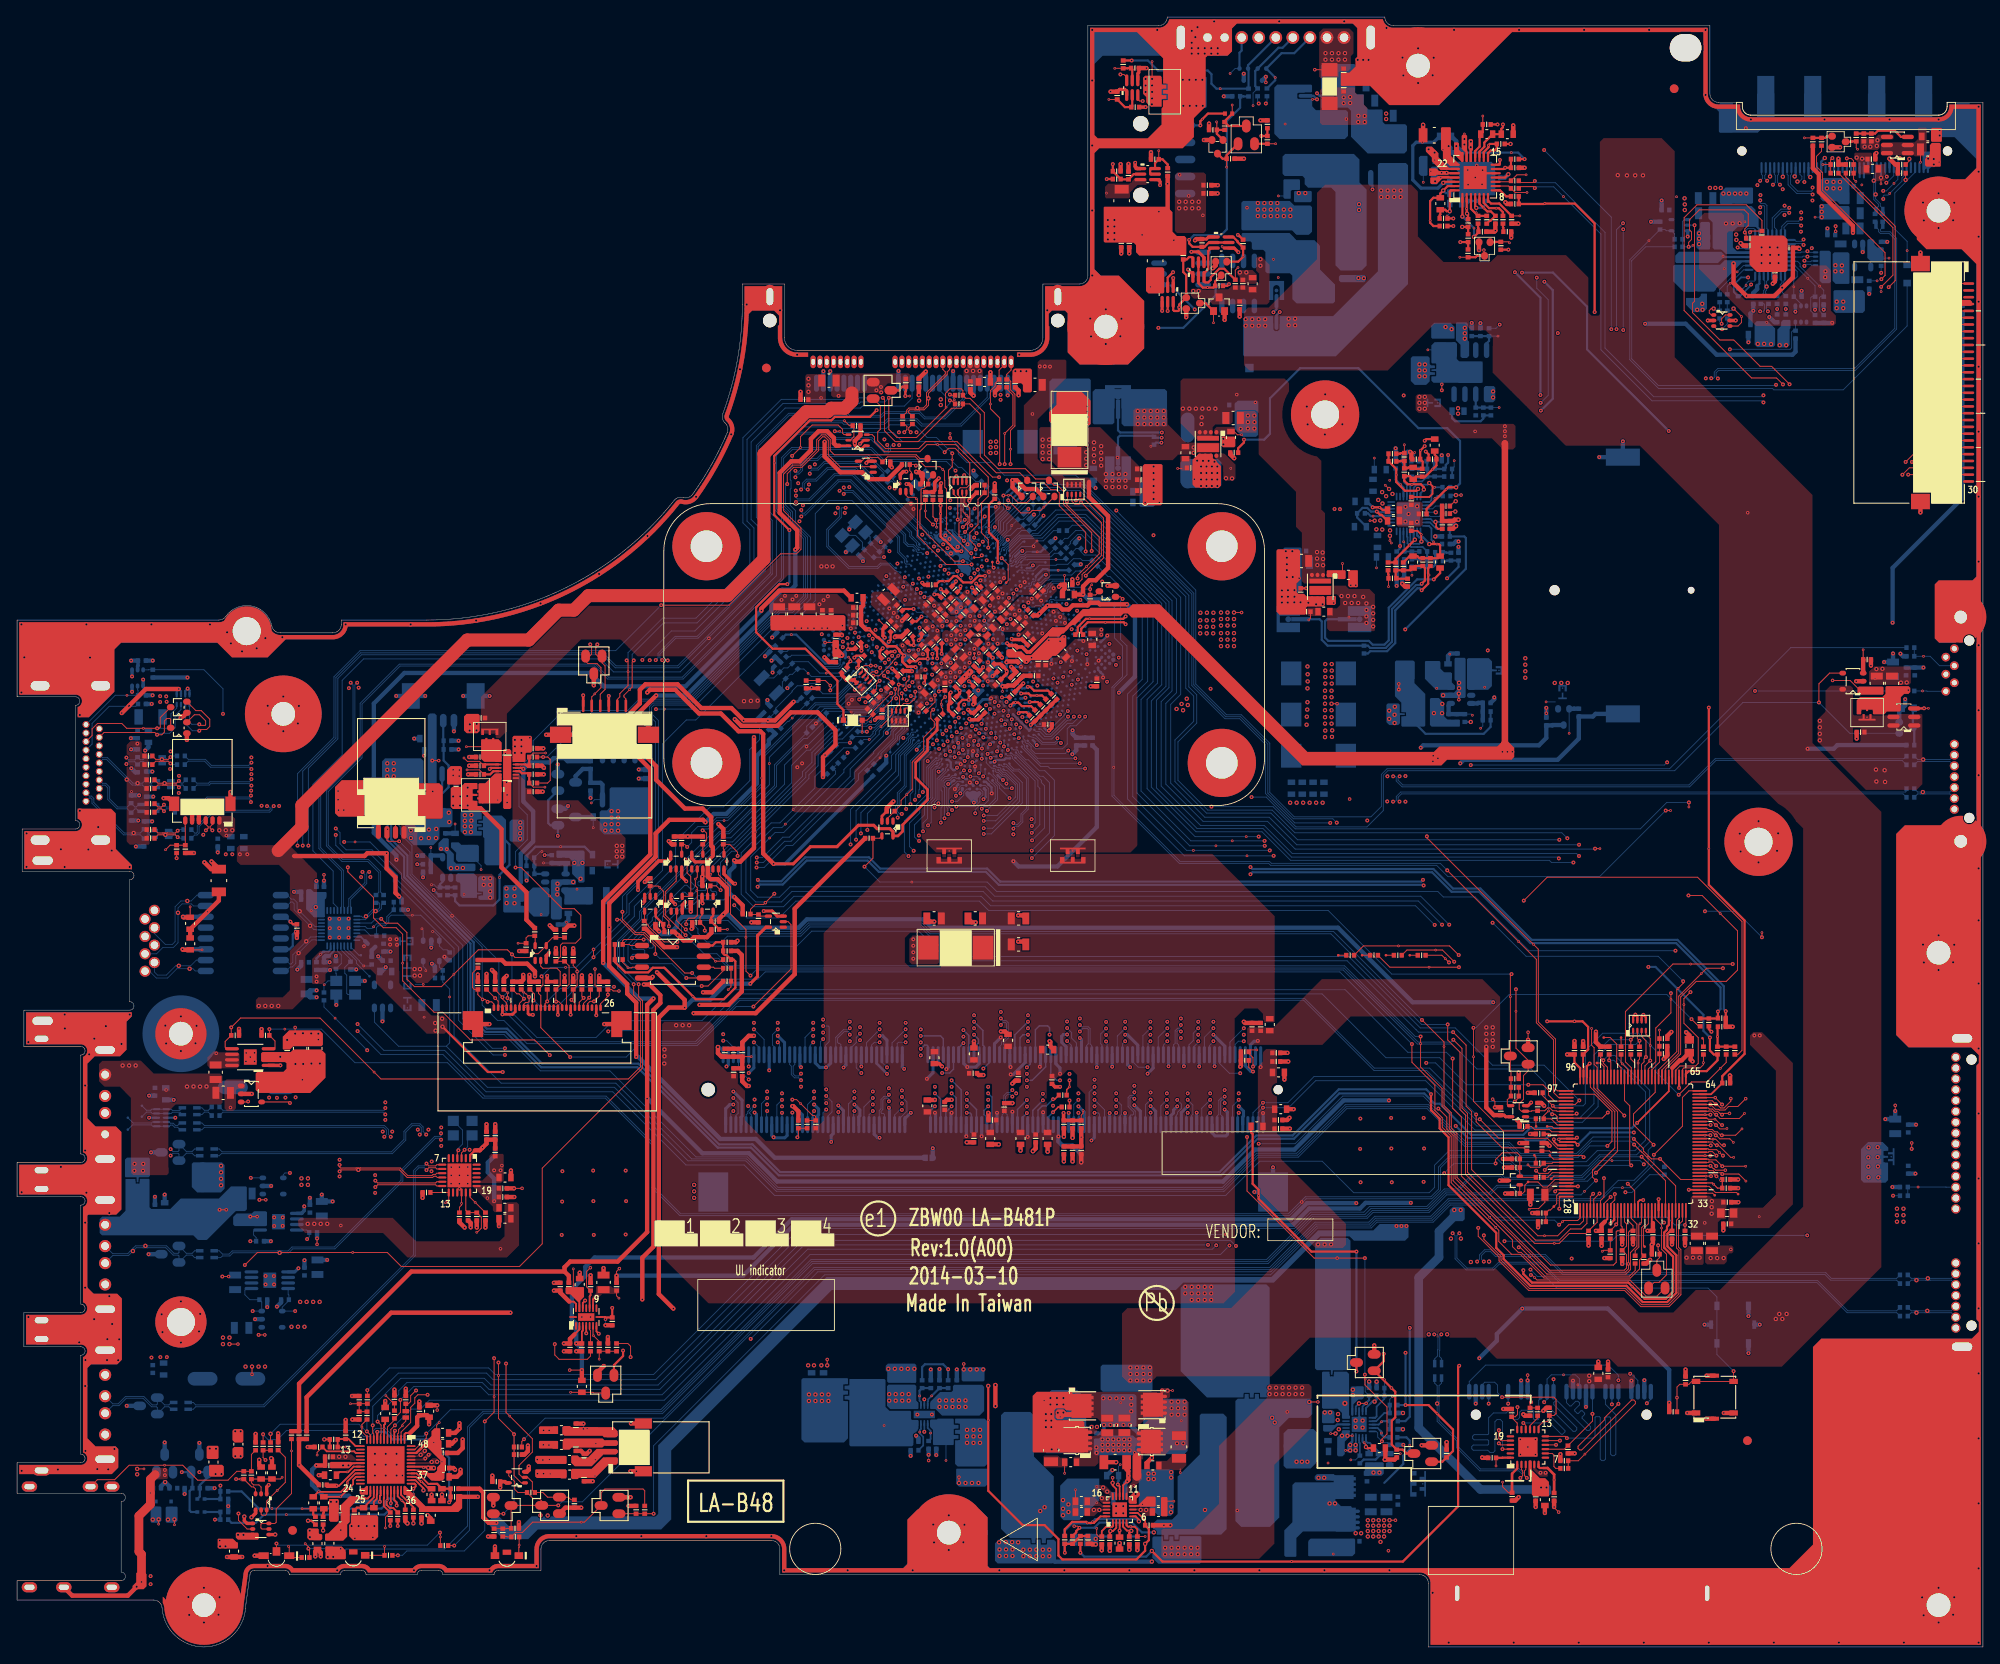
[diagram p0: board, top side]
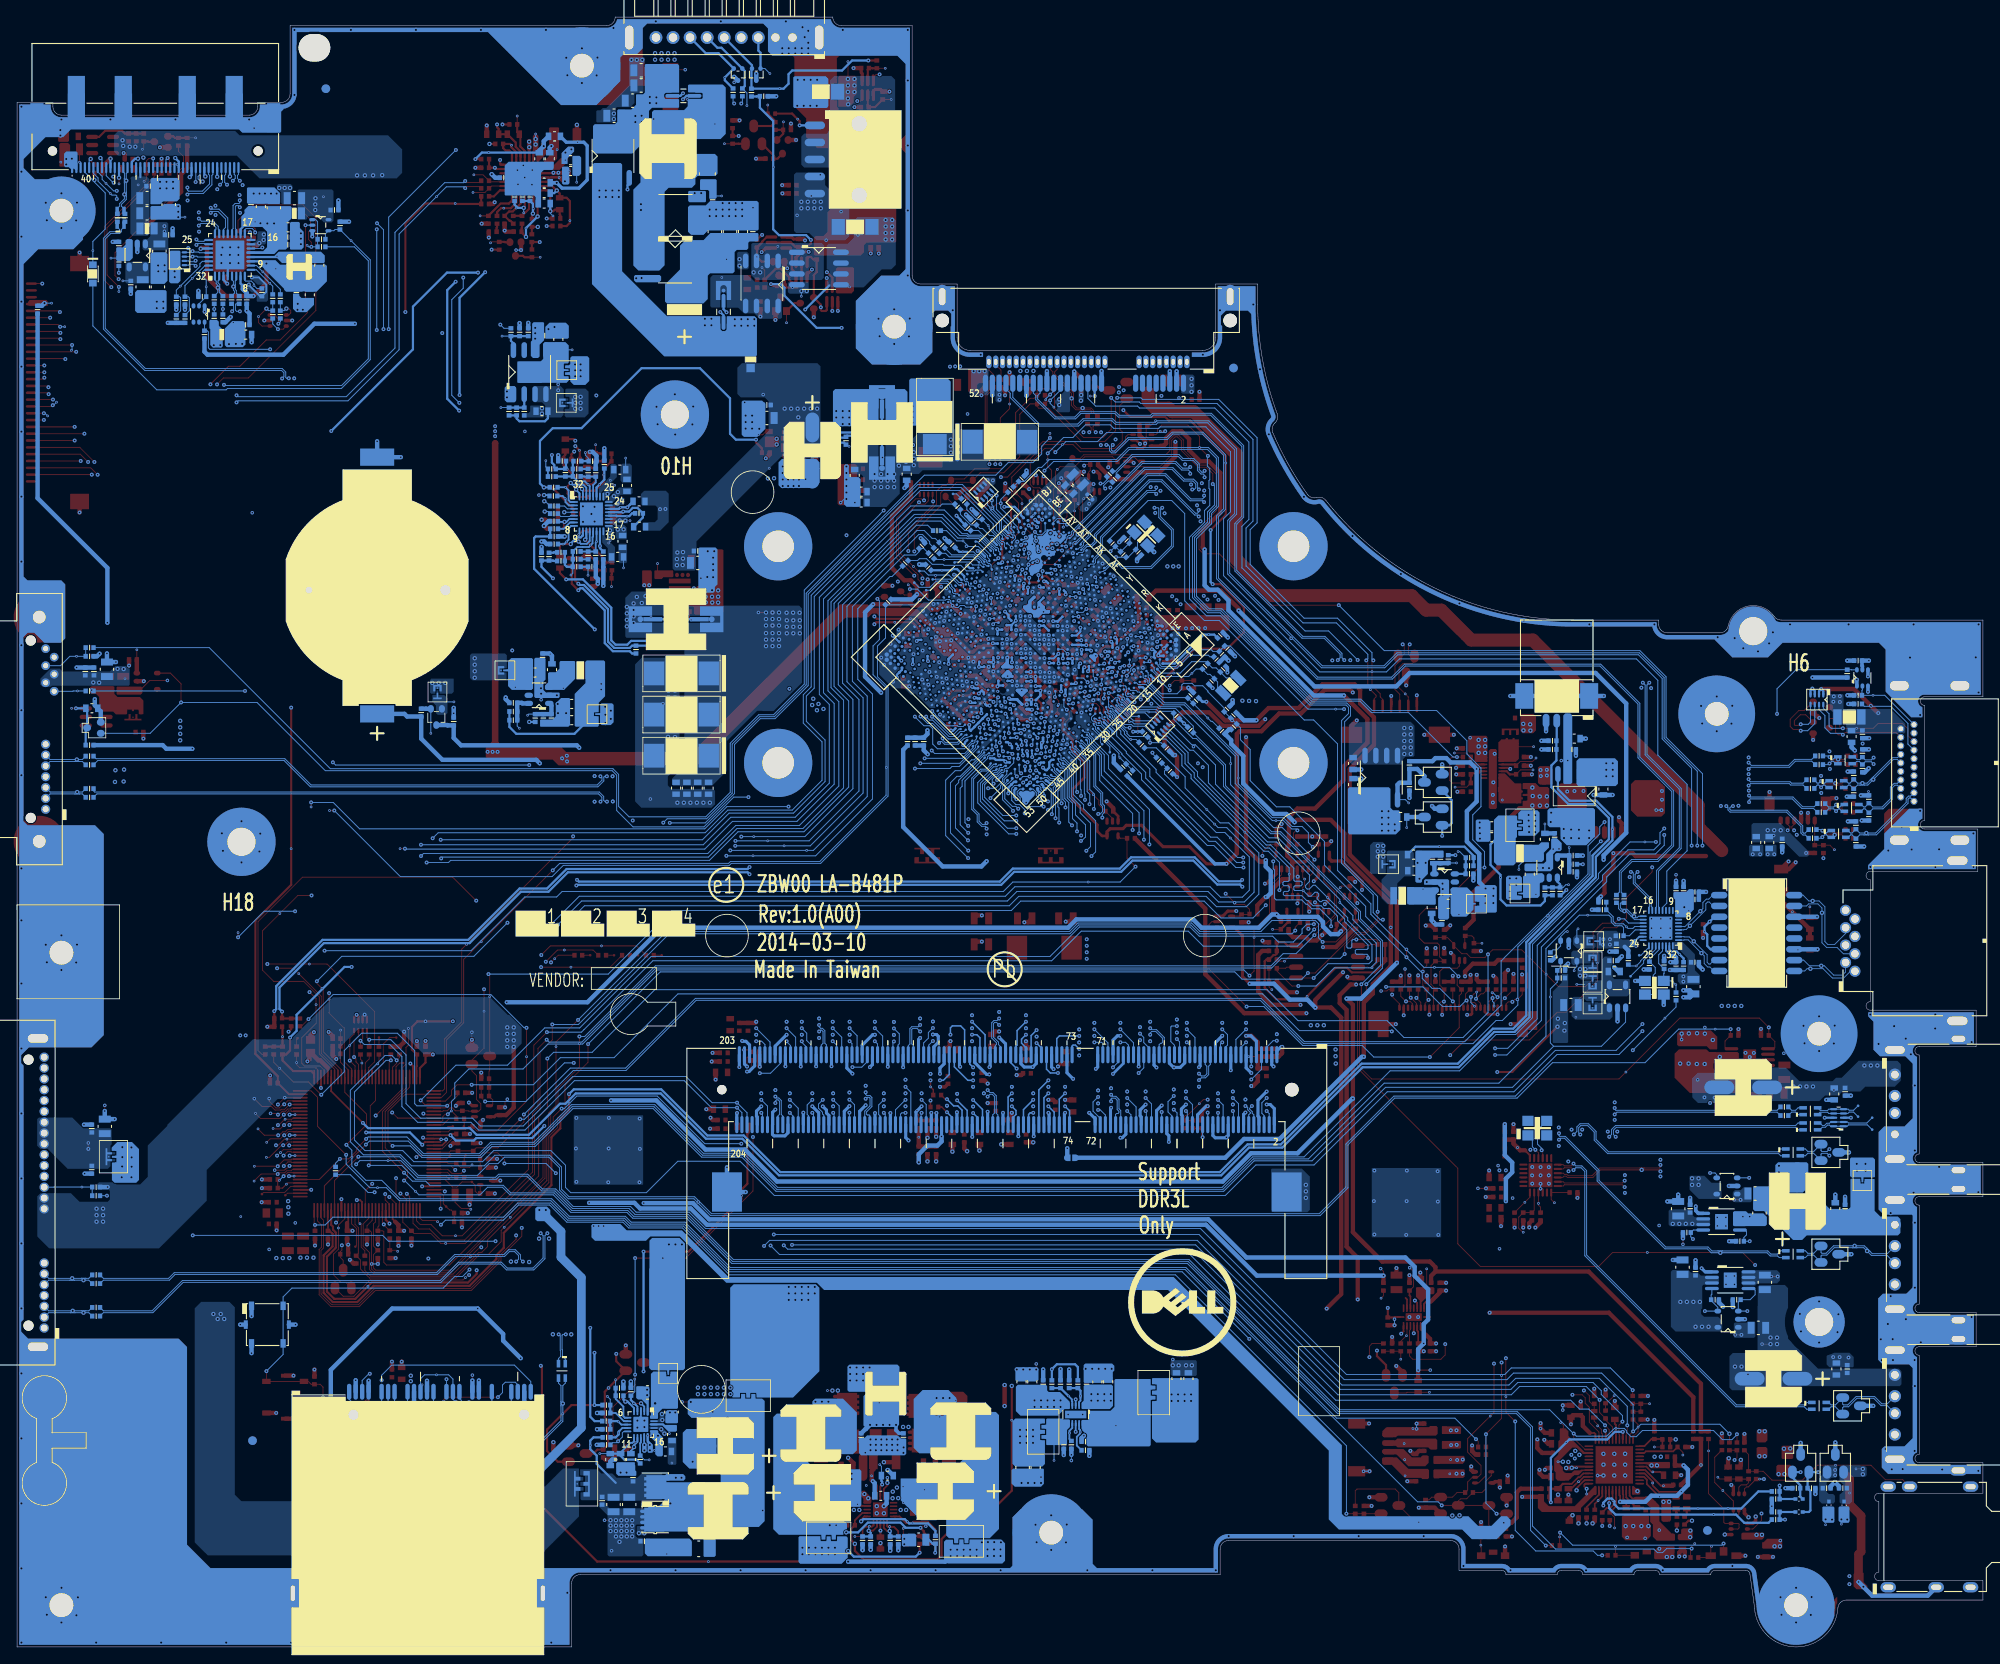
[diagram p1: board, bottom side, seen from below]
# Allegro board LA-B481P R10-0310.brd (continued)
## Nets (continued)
ODD_DA#: RP54.1 RS10.1 USOC1.AY26
ODD_DETECT#: RC68.2 RS09.1 USOC1.AU28
ODD_EN: CS16.1 QS2.3 QS3.1 RS6.1
ODD_EN#: QS3.2 UI7.4 USOC1.BD26
ON/OFFBTN#: CE20.1 JPWR.3 RE49.1 SW1.3 SW1.4 SW2.3 SW2.4 UE1.114
P2: PC700.1 PQ704.1 PQ704.2 PQ704.3 PQ705.1 PQ705.2 PQ705.3 PQ707.3 PR701.1
P3: PC701.2 PQ705.5 PQ705.6 PQ705.7 PQ705.8 PR700.1
PBTN_OUT#: U63.2 UE1.106
PC_BEEP: DA8.1 RA19.1 RA79.2
PCH_HOT#: RE7.1 T207.1(TP-1)
PCH_USB3_RX0_N: LI1.1 USOC1.E3
PCH_USB3_RX0_P: LI1.4 USOC1.D4
PCH_USB3_TX0_N: CI3.2 USOC1.K7
PCH_USB3_TX0_N_C: CI3.1 LI3.1
PCH_USB3_TX0_P: CI4.2 USOC1.K6
PCH_USB3_TX0_P_C: CI4.1 LI3.4
PCH_X1: RG6.2 RG10.1
PCH_X1_R: RG6.1 UG1.5
PCIE_CLKREQ_2#: RP63.3 USOC1.BG5
PCIE_CLKREQ_3#: RP63.4 USOC1.BE3
PCIE_PRX_C_DTX_N0: CL31.2 UL1.18
PCIE_PRX_C_DTX_P0: CL30.2 UL1.17
PCIE_PRX_DTX_N0: CL31.1 USOC1.AT13
PCIE_PRX_DTX_N1: JMINI.23 USOC1.AT9
PCIE_PRX_DTX_P0: CL30.1 USOC1.AT14
PCIE_PRX_DTX_P1: JMINI.25 USOC1.AT10
PCIE_PTX_C_DRX_N0: CC4.2 UL1.14
PCIE_PTX_C_DRX_N1: CC6.2 JMINI.31
PCIE_PTX_C_DRX_P0: CC3.2 UL1.13
PCIE_PTX_C_DRX_P1: CC5.2 JMINI.33
PCIE_PTX_DRX_N0: CC4.1 USOC1.AY6
PCIE_PTX_DRX_N1: CC6.1 USOC1.AV4
PCIE_PTX_DRX_P0: CC3.1 USOC1.AY7
PCIE_PTX_DRX_P1: CC5.1 USOC1.AV6
PCIE_RCOMPN: RC13.2 USOC1.AP13
PCIE_RCOMPP: RC13.1 USOC1.AP14
PCIE_WAKE#: RL34.2 UE1.29 UL1.21
PCU_SMB_ALERT#: RP68.2 USOC1.BG11
PCU_SMB_CLK: QC3.3 RP68.4 USOC1.BH10
PCU_SMB_DATA: QC4.3 RP68.3 USOC1.BG12
PECI_KB9012: RE43.1 UE1.118
PHASE1: PC524.2 PL501.1 PQ503.9 PR532.1 PU500.18
PHASEG: PC515.2 PL500.1 PQ501.9 PR512.1 PU500.24
PLT_RST#: CC11.1 CE36.1 JMINI.22 RC20.2 UC5.4 UE1.13 UL1.19
PMC_ACIN: DC1.2 RC21.2 USOC1.D20
PMC_BATLOW#: RP65.2 USOC1.K26
PMC_CORE_PWROK: CC16.1 CC57.1 CE31.1 JDB1.12 RE18.1 UC7.2 UE1.32 USOC1.B7
PMC_PCIE_WAKE#: RP65.1 USOC1.F26
PMC_PLTRST#: CC13.1 CC51.1 JDB1.17 UC5.2 USOC1.F20
PMC_PWRBTN#: R6.2 U63.4 USOC1.J26
PMC_RSTBTN#: RC24.1 USOC1.BG9
PMC_SLP_S3#: R1024.1 U54.2 USOC1.D22
PMC_SLP_S4#: R1033.1 U57.2 USOC1.F22
PMC_SUSCLK: T103.1(TP-1) USOC1.G24
PS_ID: PR1.2 PR4.1 UE1.16
PSID: PJPDC1.1 PL3.1
PSID-1: PQ2.2 PR2.1 PR5.2
PSID-2: PQ1.2 PQ2.1 PR3.2
PSID-3: PQ1.3 PR1.1
PWR_OTP#: PR114.1 UE1.104
PWR_PWM_LED#: RD14.1 UE1.92
PWR_SRC_ON: CX4.2 QX2.3 RX2.2 RX3.1
RING2: LA10.2 RA1109.1 UA1.17
RING2_R: CA40.1 DA12.2 JHP.6 LA10.1
RREF: RR1.1 UR1.1
RTC_RST#: CC22.1 R1089.2 RC35.2 USOC1.C12
RTC_TEST#: CC20.2 CC64.1 JDB1.13 R1088.2 RC34.2 USOC1.C11
RTC_VOUT: CG6.1 RG2.2 UG1.14
RUNPWROK: T216.1(TP-1) UE1.36
SATA_LED#_SOC: QC2.3 RC18.2 USOC1.AY12
SATA_PRX_DTX_N0: CS109.1 JHDD.5
SATA_PRX_DTX_N0_C: CS109.2 USOC1.AV16
SATA_PRX_DTX_N1: CS14.1 JODD.5
SATA_PRX_DTX_N1_C: CS14.2 USOC1.BA16
SATA_PRX_DTX_P0: CS108.1 JHDD.6
SATA_PRX_DTX_P0_C: CS108.2 USOC1.AU16
SATA_PRX_DTX_P1: CS15.1 JODD.6
SATA_PRX_DTX_P1_C: CS15.2 USOC1.AY16
SATA_PTX_DRX_N0: CS106.1 JHDD.3
SATA_PTX_DRX_N0_C: CS106.2 USOC1.BG7
SATA_PTX_DRX_N1: CS9.1 JODD.3
SATA_PTX_DRX_N1_C: CS9.2 USOC1.BF10
SATA_PTX_DRX_P0: CS105.1 JHDD.2
SATA_PTX_DRX_P0_C: CS105.2 USOC1.BF6
SATA_PTX_DRX_P1: CS8.1 JODD.2
SATA_PTX_DRX_P1_C: CS8.2 USOC1.BD10
SATA_RCOMPN: RC12.1 USOC1.AT18
SATA_RCOMPP: RC12.2 USOC1.AU18
SD3_RCOMP: RC59.1 USOC1.BF26
SD_CD#: CR9.1 JREAD.20 UR1.13
SD_CMD: CR11.1 JREAD.6 UR1.18
SD_D0: JREAD.18 UR1.11
SD_D1: JREAD.19 UR1.10
SD_D2: JREAD.1 UR1.21
SERIRQ: U64.4 UE1.3
SIO_SLP_S0#: T196.1(TP-1) UE1.89
SIO_SLP_S3#: CE27.1 R13.2 U54.4 UE1.6
SIO_SLP_S4#: T194.1(TP-1) UE1.84
SIO_SLP_S5#: CE28.1 R14.2 U57.4 UE1.14
SNB_3V: PC114.1 PR109.2
SNB_5V: PC115.1 PR110.2
SNB_CHG: PC716.1 PR721.2
SOC_I2C0_CLK: T109.1(TP-1) USOC1.BG28
SOC_I2C0_DATA: T108.1(TP-1) USOC1.BH28
SOC_KBRST#: R3.2 U61.4 USOC1.B18
SOC_LID_OUT#: R4.2 U62.4 USOC1.C17
SOC_SATALED#: QC2.1 RD15.1
SOC_SCI#: R8.2 U66.4 USOC1.BA12
SOC_SERIRQ: U64.3 USOC1.BG13
SOC_SMI#: R7.2 U65.4 USOC1.C15
SOC_SPI_CLK: RP67.5 USOC1.C22
SOC_SPI_CS0#: RP67.8 USOC1.C23
SOC_SPI_MISO: RP67.7 USOC1.B22
SOC_SPI_MOSI: RP67.6 USOC1.A21
SOC_SPKR: DA8.3 USOC1.BH12
SPI_CLK: RC39.1 RP67.4 UC8.6
SPI_CS0#: RC36.2 RP67.1 UC8.1
SPI_HOLD#: RC37.2 UC8.7
SPI_MISO: RP67.2 UC8.2
SPI_MOSI: RP67.3 UC8.5
SPI_WP#: RC38.2 UC8.3
SPK_L1-_CONN: CA30.1 JSPK.3 LA5.2
SPK_L2+_CONN: CA29.1 JSPK.4 LA6.2
SPK_R1-_CONN: CA32.1 JSPK.1 LA3.2
SPK_R2+_CONN: CA31.1 JSPK.2 LA4.2
SPOK: PR106.2 PR308.1 PR400.1 PU100.7 UE1.18
SUSP: Q8.1 Q70.2 Q71.2 Q2307.2 Q2308.2 R10.2
SUSP#: PR208.1 PR300.1 PR409.1 Q8.2 R16.1 R926.1 R927.2 R1055.2 R1056.2 UE1.116
SW_1.35VP: PC207.2 PL200.2 PQ201.1 PQ201.2 PQ201.3 PQ203.5 PR202.1 PU200.16
SYSON: CE26.1 PR207.1 UE1.95
TL_BKOFF#: DX1.2 RT15.2 RX33.1 UX2.4
TL_BKOFF#_R: RT14.1 RT15.1 RT19.1 UT2.17 UX2.1
TL_ENVDD: CX20.1 RV300.1 RX6.1 RX7.2 UT2.15
TL_INVT_PWM: JLVDS.36 RX26.1 UT2.14
TMDS_L_TX0N: CX25.1 JHDMI.9 LX3.2
TMDS_L_TX0P: CX26.1 JHDMI.7 LX3.3
TMDS_L_TX1N: CX27.1 JHDMI.6 LX4.2
TMDS_L_TX1P: CX28.1 JHDMI.4 LX4.3
TMDS_L_TX2N: CX29.1 JHDMI.3 LX5.2
TMDS_L_TX2P: CX30.1 JHDMI.1 LX5.3
TMDS_L_TXCN: CX23.1 JHDMI.12 LX2.2
TMDS_L_TXCP: CX24.1 JHDMI.10 LX2.3
TMDS_TX0N: CX14.1 LX3.1 R1073.1
TMDS_TX0P: CX15.1 LX3.4 R1074.1
TMDS_TX1N: CX16.1 LX4.1 R1075.1
TMDS_TX1P: CX17.1 LX4.4 R1076.1
TMDS_TX2N: CX18.1 LX5.1 R1077.1
TMDS_TX2P: CX19.1 LX5.4 R1078.1
TMDS_TXCN: CX12.1 LX2.1 R1071.1
TMDS_TXCP: CX13.1 LX2.4 R1072.1
TON_1.35VP: PR205.2 PU200.9
TOUCH_RST: RX1.1 RX4.2 UE1.38
TOUCH_RST_R: JTOUCH.6 RX1.2 RX24.2
TP2_CORE_VCC_S0IX: T112.1(TP-1) USOC1.AA22
TP_CLK: DE3.3 JTP.2 RE9.2 UE1.87
TP_CORE_V1P05_S4: T195.1(TP-1) USOC1.AF30
TP_DATA: DE3.2 JTP.3 RE10.2 UE1.88
TXE_DBG: QC1.2 UE1.99
UG_3V: PQ101.4 PU100.10
UG_5V: PQ102.4 PU100.16
UGATE1: PR528.1 PU500.17
UGATE1-1: PQ503.1 PR528.2
UGATEG1: PR506.1 PU500.25
UGATEG1-1: PQ501.1 PR506.2
USB3_REXT0: RC40.1 USOC1.M12
USB3RN2_JUSB1_R: DI1.1 DI1.10 LI1.2 T113.1(TP-1)
USB3RP2_JUSB1_R: DI1.2 DI1.9 LI1.3 T114.1(TP-1)
USB3TN2_JUSB1_R: DI1.4 DI1.7 LI3.2 T115.1(TP-1)
USB3TP2_JUSB1_R: DI1.5 DI1.6 LI3.3 T116.1(TP-1)
USB20_CAM_N7_R: JLVDS.28 LX6.2 RX21.2
USB20_CAM_P7_R: JLVDS.27 LX6.3 RX22.2
USB20_CPU_N3: LR2.1 USOC1.H10
USB20_CPU_P3: LR2.4 USOC1.K10
USB20_CR_N3_R: LR2.2 UR1.2
USB20_CR_P3_R: LR2.3 UR1.3
USB20_HUB_N1: JMINI.36 U58.11
USB20_HUB_N2: JTOUCH.2 U58.9
USB20_HUB_N3: LI6.1 U58.7
USB20_HUB_P1: JMINI.38 U58.12
USB20_HUB_P2: JTOUCH.3 U58.10
USB20_HUB_P3: LI6.4 U58.8
USB20_JUSB1_N0_R: DI2.2 JUSB1.2 LI2.2
USB20_JUSB1_P0_R: DI2.3 JUSB1.3 LI2.3
USB20_JUSB2_N1_R: DI9.2 JUSB8.2 LI5.2
USB20_JUSB2_P1_R: DI9.3 JUSB8.3 LI5.3
USB20_JUSB3_N3_R: DI8.2 JUSB7.2 LI6.2
USB20_JUSB3_P3_R: DI8.3 JUSB7.3 LI6.3
USB20_N0: LI2.1 USOC1.K16
USB20_N1: LI5.1 USOC1.G14
USB20_N2: LX6.1 RX21.1 USOC1.J12
USB20_P0: LI2.4 USOC1.M16
USB20_P1: LI5.4 USOC1.J14
USB20_P2: LX6.4 RX22.1 USOC1.K12
USB_EN#: CI13.1 CI26.1 CI29.1 UE1.26 UI1.4 UI2.4 UI3.4 UI4.4 UI5.4 UI6.4
USB_OC0#: CI15.1 CI17.1 RC44.2 UI1.3 UI2.5 UI3.5 UI4.3 USOC1.C20
USB_OC1#: CI28.1 RC46.2 UI5.3 UI6.5 USOC1.B20
USB_PLL_MON: RC47.2 USOC1.M13
USB_RCOMP: RC45.2 USOC1.C7 USOC1.D6
VCIN0_PH: PR13.2 R696.1 UE1.109
VCIN1_PROCHOT: PR15.2 R697.1 UE1.102
VCORE_GSNS: PC503.2 PC535.2 PU500.12 PU500.30 RC58.1 USOC1.N28
VCORE_VSNS: PC527.1 PC533.2 PR542.1 RC56.2 USOC1.P28
VCOUT1_PH: PR17.1 PR18.2 Q50.2 RE47.2 UE1.103 UE2.2
VFB: PR726.1 PU700.15 PU700.16
VGA_V1P35_S3_F1: CC35.1 CC36.1 L1.1 USOC1.BD1
VGATE: PR530.1 PU500.15 UE1.97
VGFX_VSNS: PC502.1 PR501.2 PR504.2 RC55.2 USOC1.BB8
VL: PC117.1 PU100.13
VR_HOT#: PC520.1 PR525.1 PU500.6 RE13.1 RE44.1
VR_ON: CE34.1 DE1.3 PR516.1 RE1.2 RE12.2
VR_ON_EC: RE12.1 UE1.121
VR_ON_R: PR516.2 PU500.2
VR_SVID_ALERT#: PU500.4 RC27.2 RC28.2
VR_SVID_ALERT#_SOC: RC28.1 USOC1.B24
VR_SVID_CLK: PR520.1 PR527.1 USOC1.C25
VR_SVID_CLK_R: PR520.2 PU500.3
VR_SVID_DATA: PR521.1 PR526.1 RC29.2
VR_SVID_DATA_R: PR521.2 PU500.5
VR_SVID_DATA_SOC: RC29.1 USOC1.A25
VSUM+: PC529.1 PC530.1 PR535.1 PR536.2 PR541.1 PU500.10
VSUM-: PC529.2 PC530.2 PC532.2 PC534.1 PH503.2 PL501.3 PR540.2 PR541.2
VSUMG+: PC513.2 PC514.2 PR500.2 PR509.2 PR513.2 PU500.32
VSUMG-: PC512.1 PC513.1 PC514.1 PH500.1 PL500.3 PR502.2 PR507.1 PR509.1
VTTREF_1.35VP: PC212.1 PU200.4
WL_BT_LED: QD20.2 RD50.1 RD53.1 UE1.1
WL_BT_LED#: QD20.1 RD18.1 RD51.2 RD53.2
WL_BT_LED#_EC: QD18.1 QD19.1 RD46.2 RD49.2 RD51.1 RD52.1 UD1.4 UE1.64
WL_BT_LED#_EC2: RD48.2 UE1.74
WL_LED#: JMINI.44 QD18.3 RD45.2 RD48.1 UD1.1
WL_OFF#: QM30.3 RE14.1 RP54.3 USOC1.BA26
WL_OFF#_EC: RE14.2 UE1.19
WLAN_CLKREQ#: JMINI.7 RP63.2 USOC1.BD7
WLAN_RADIO_DIS#_R: JMINI.20 QM30.1 RM110.2
WOL_EN: RL27.2 RL38.1 UE1.98 UL2.3 UL3.4
XDP_H_PRDY#: CC52.1 JDB1.2 RC65.2 USOC1.D18
XDP_H_PREQ_BUF#: CC50.1 JDB1.1 RC25.2 RC61.2 USOC1.F16
XDP_H_TCK: CC65.1 JDB1.26 RP66.7 USOC1.D14
XDP_H_TDI: CC61.1 JDB1.22 RP66.5 USOC1.F12
XDP_H_TDO: CC56.1 JDB1.20 RC63.2 RC64.2 USOC1.G16
XDP_H_TMS: CC63.1 JDB1.23 RP66.6 USOC1.F14
XDP_H_TRST#: CC59.1 JDB1.21 RP66.8 USOC1.G12
XDP_OBSDATA_A0: CC55.1 JDB1.4 USOC1.N24
XDP_OBSDATA_A1: CC58.1 JDB1.5 USOC1.M20
XDP_OBSDATA_A2: CC60.1 JDB1.7 USOC1.J18
XDP_OBSDATA_A3: CC62.1 JDB1.8 USOC1.M18
XDP_RSTBTN#: CC12.1 CC49.1 CC53.1 JDB1.18 RC24.2 RC62.2
XTAL_25M_IN: CC9.1 RC19.1 RG10.2 USOC1.AH12 YC1.1
XTAL_25M_OUT: CC10.1 RC19.2 USOC1.AH10 YC1.3
XTLI: CL36.2 RG11.2 UL1.29 YL2.1
XTLI_L: RG8.2 RG11.1
XTLI_R: CG7.1 RG5.2 RG8.1
XTLO: CL37.2 UL1.28 YL2.3
N17188574: PC400.2 PJP400.2 PU400.4
N17188613: PC405.1 PR401.2
N17227658: PC412.1 PJP404.2 PU402.5 PU402.9
N17227663: PC413.2 PR410.2 PR412.1 PU402.2
N17227696: PC415.1 PR409.2 PR411.1 PU402.8
N17253612: PC116.1 PR111.2 PU100.12
N17256470: PC210.2 PR209.2 PU200.12
N17256593: PC211.1 PR202.2
N17322320: PC7.1 PH1.1 PR10.2 PR13.1
N17322329: PR11.2 PR15.1 PR18.1 PR20.1
N17322935: PQ3.3 PR12.2
N17322941: PQ3.5 PQ3.6 PR14.1 PR19.2
N17330968: RC52.1 T211.1(TP-1)
N17344663: PJP1.1 PJPDC1.2 PJPDC1.3 PL2.1
N17354752: PL501.2 PR536.1
N17354919: PC517.2 PR518.1 PU500.22
N17371703: PR717.2 PU700.10
N17371738: PR719.2 PU700.9
N17407779: CE12.1 R2354.1
N17434553: RE36.1 T218.1(TP-1)
N17434554: RE36.2 UE1.107
N17434556: RE37.1 T212.1(TP-1)
N17434577: RE7.2 UE1.66
N17438484: CA21.1 R2355.2
N17494823: CA1.1 CA2.1 QA5.2 RA3.2
N18943829: PR720.2 PR724.1
N18944147: PC722.2 PC726.1 PR720.3 PU700.17
N18956218: PC722.1 PR724.2 PU700.18
N18967347: PC727.1 PR723.2
N18967375: PC721.1 PU700.4
N18967379: PR723.1 PU700.6
N18967435: PC723.1 PU700.7
N18967441: PR725.1 PR728.2 PU700.5
N18999155: PC706.1 PC709.1 PR704.2 PU700.28
N19000258: PC707.1 PC709.2 PR705.2 PU700.27
N19021042: PC710.1 PR709.2 PU700.26
N19095003: PR722.2 PU700.8
N19142937: PC700.2 PC701.1 PQ704.4 PQ705.4 PQ707.1 PR701.2 PR703.1
N19565438: PQ707.2 PQ708.1
N19565442: PQ709.3 PQ710.3 PR703.2
N19565444: PQ709.2 PQ709.5 PQ712.1 PR712.2
N19565472: PQ711.1 PR708.1
N19636367: QA6.2 RA6.2 RA7.2
N19792312: QA5.5 QA5.6 RA2.2
N19794620: QA6.5 QA6.6 RA5.2
N22321388: RE37.2 UE1.82
N22702729: LED2.1 RD15.2
N22702890: LED1.2 RD14.2
N22702897: LED1.3 RD17.2
N22795339: LED4.1 RD18.2
N23316235: JP3.1 RL28.1 UL2.1
N23954212: R15.2 R17.2 UC5.5
N23955686: T105.1(TP-1) USOC1.C21
N23993932: CC24.2 RC39.2
N24086884: C1123.2 U59.12
N24086900: C1127.2 U59.10
N24234938: CS17.1 JODD.11 RS10.2
N24235708: JODD.8 RS09.2
N24237390: R1048.1 U58.13
N24262528: C976.2 U11.12
N24262552: C967.2 U11.10
N24334655: PC300.2 PJP300.2 PU300.4
N24334673: PC305.1 PR301.2
N24509824: RL40.2 UL3.3
N24530695: RS9.1 UI7.3
N24559749: PC307.2 PJP302.2 PU301.4
N24559796: PC306.1 PR306.2
N24608852: CA62.2 RA154.2 UA1.27
N24608977: RA34.1 RA51.1 RA155.1 UA1.13
N24654163: PC112.2 PR107.1
N24654248: PC113.1 PR108.2
N24947886: RX5.2 UT2.8
N25096547: RE17.2 T199.1(TP-1)
N25096555: RE19.2 T200.1(TP-1)
N25096563: RE20.2 T201.1(TP-1)
N25096571: RE21.2 T202.1(TP-1)
N25415357: R5.1 U64.5
N25420647: R18.2 R19.2 U54.5
N25421095: R20.2 R21.2 U57.5
N29841026: PQ713.3 PR730.2
N39970373: PQ710.6 PQ712.2 PR718.2
N40812716: CR3.2 UR1.6
N47007898: PC11.2 PQ4.5 PR26.1
N47008110: PC9.1 PQ4.2 PR17.2
N47008134: PL3.2 PQ1.1 PR2.2
N48037563: JDIMM1.197 RD6.2
N48037565: JDIMM1.201 RD7.2
N48039107: CD21.1 CD22.1 JDIMM1.126 RD4.1
N52907207: PQ706.4 PR706.1 PR708.2
N52907447: PQ711.2 PR714.1
N55155843: QX1.1 RX3.2
N55201771: JHDMI.13 RX12.2
N56393123: RL31.2 UL1.31
N56393790: T94.1(TP-1) UL1.27
N56393809: T95.1(TP-1) UL1.25
N56394014: CL33.1 RL19.2 RL20.2
N56394031: CL41.2 TL1.3 TL1.6
N59110906: RE43.2 T203.1(TP-1)
N61580896: Q2307.1 R2314.2
N61580898: Q2308.1 R2315.2
N63469417: CA65.2 CA69.1 RA79.1 RA81.2
N63469524: CA68.2 RA82.1
N63469526: CA67.2 RA80.1
N63469613: CA65.1 UA1.12
N63469687: CA23.2 UA1.28
N63469697: RA153.2 UA1.15
N63469703: CA24.1 UA1.37
N63469709: CA24.2 UA1.35
N63469711: CA25.2 UA1.34
N63469723: CA63.2 UA1.39
N63469729: CA64.2 UA1.7
N63469750: RA130.2 UA1.8
N100764683: PC506.1 PR502.1
N100764685: PC506.2 PR507.2 PU500.31
N100764689: PC532.1 PR539.2
N100764691: PR539.1 PR540.1 PU500.11
N100764720: PC518.1 PR519.2 PR522.2 PU500.21
N100764741: PC504.1 PR503.1 PR508.1 PU500.28
N100764791: PC504.2 PC505.1 PC507.2 PR504.1 PR505.1 PU500.29
N100764795: PC528.2 PC531.2 PR534.2 PU500.14
N100764809: PC528.1 PR533.2 PR538.2 PR542.2 PR543.1 PU500.13
N100764813: PC507.1 PR503.2
N100764860: PR510.2 PU500.27
N100764905: PC531.1 PR543.2
N100764954: PC527.2 PR538.1
N100764996: PH500.2 PR500.1
N100765028: PC525.2 PR533.1
N100765040: PC505.2 PR501.1
N100765116: PH503.1 PR535.2
N100765769: PC511.1 PR505.2
N100765781: PR522.1 PU500.20
N100768097: PC526.1 PR532.2
N100768278: PC516.1 PR512.2
N100768460: PC524.1 PR531.2
N100768507: PC515.1 PR511.2
N100768540: PL500.2 PR513.1
N102723193: T102.1(TP-1) USOC1.BG18
N102723222: T101.1(TP-1) USOC1.BH18
N102723231: T100.1(TP-1) USOC1.BG21
N251601461: PR524.2 PU500.8

Pads without a net: FD1 1; FD2 1; FD3 1; FD4 1; FD5 1; FD6 1; FD7 1; FD8 1; JDB1 11 14 15 24; JDIMM1 77 122 125 198; JHDD 18 20 21 22; JHDMI 14; JKB 2 3 30; JLAN 4 5 7 8; JLVDS 13 14 16 17 19 20 22 23 38; JMINI 1 3 5 8 10 12 14 16 17 19 37 42 45 47; LED2 3; LED4 3; PU100 19; PU300 5; PU301 5; PU400 5; PU402 7; PU500 9; Q2309 3 4 5; RP54 4; RP68 1 8; TL1 4 5 12 13; U54 1; U57 1; U58 2 5 6 14 15 21 22 23 24; U61 1; U62 1; U63 1; U65 1; U66 1; UA1 14 16 23 24 48; UC4 1; UC5 1; UC7 1; UC10 1; UE1 85 86 90; UE2 1; UG1 9 12; UL1 3 6 7 9 10 11 22 24; UR1 7 14 17 19 23; USOC1 A13 A17 AB2 AB3 AB7 AB9 AB12 AB13 AB14 AC1 AC3 AD2 AD3 AD4 AD6 AD9 AD10 AD12 AD40 AD41 AF2 AF3 AF13 AF14 AF40 AF41 AF48 AF50 AF51 AF52 AG51 AG53 AH13 AH14 AH40 AH44 AH52 AJ51 AK4 AK6 AK7 AK9 AK40 AK42 AK45 AK47 AK48 AK50 AK51 AK52 AL1 AL3 AL51 AL53 AM4 AM6 AM9 AM10 AM13 AM14 AM41 AM42 AM45 AM47 AM48 AM50 AM52 AP4 AP6 AP7 AP9 AP10 AP12 AP41 AP42 AP44 AP45 AP47 AP48 AP50 AP51 AP52 AR51 AR53 AT6 AT7 AT20 AT22 AT26 AT32 AT34 AT36 AT40 AT41 AT42 AT44 AT45 AT48 AT50 AT51 AU20 AU22 AU26 AU32 AU34 AU36 AU53 AV9 AV10 AV20 AV22 AV26 AV28 AV32 AV34 AV36 AV40 AV44 AV45 AV48 AV50 AV52 AW1 AW41 AW51 AW53 AY2 AY3 AY20 AY24 AY28 AY30 AY34 AY38 AY40 AY42 AY44 AY45 AY47 AY48 AY51 AY52 B4 B5 B12 B14 B16 B26 B28 BA1 BA3 BA18 BA20 BA24 BA28 BA34 BA36 BA38 BA42 BA51 BB3 BB4 BB44 BB47 BB49 BB50 BB51 BC14 BC18 BC24 BC36 BC38 BC40 BC44 BC52 BC53 BD2 BD5 BD12 BD16 BD18 BD20 BD22 BD28 BD32 BD34 BD36 BD38 BD40 BD42 BD44 BD47 BE46 BE51 BE52 BF2 BF14 BF22 BF27 BF28 BF32 BF34 BF40 BF42 BF48 BF50 BF52 BG23 BG24 BG25 BG26 BG27 BG29 BG32 BG33 BG35 BG36 BG37 BG38 BG40 BG41 BG43 BG47 BH4 BH5 BH6 BH7 BH8 BH22 BH24 BH26 BH32 BH34 BH36 BH38 BH40 BH42 BH44 BH46 BH47 BH48 BH49 BH50 BJ9 BJ25 BJ29 BJ33 BJ37 BJ41 BJ45 C13 C16 C18 C19 C27 C30 D2 D26 D28 D32 D34 D48 E2 E46 F1 F18 F28 F32 F34 G2 G18 G30 H3 H4 H5 H7 H8 J3 J28 J30 J34 K2 K3 K18 K20 K24 K28 K34 L1 L3 M2 M3 M4 M6 M7 M9 M10 M22 M24 M32 N3 N30 N32 N34 P2 P3 P6 P7 P10 P12 P14 P34 R1 R3 T2 T3 T4 T6 T7 T9 T10 T12 T13 T14 V2 V3 V4 V6 V9 V10 V13 V14 W1 W3 Y2 Y3 Y4 Y6 Y12 Y13; Y9 2 4

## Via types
v1: diameter 0.305, hole 0.152, TOP to BOTTOM, 462 vias
v2: diameter 0.457, hole 0.203, TOP to BOTTOM, 2160 vias
v3: diameter 0.406, hole 0.203, TOP to BOTTOM, 127 vias
v4: diameter 0.508, hole 0.254, TOP to BOTTOM, 1386 vias
v5: diameter 0.61, hole 0.305, TOP to BOTTOM, 1 via

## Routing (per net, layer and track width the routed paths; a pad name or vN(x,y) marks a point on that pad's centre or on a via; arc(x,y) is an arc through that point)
1.0VS_GATE: length 9.2
  BOTTOM w0.102: v1(67.3,98.96) 67.69,99.35 U60.4
  BOTTOM w0.508: Q70.1 65.46,102.11 66.3,102.94 R1061.1 C1131.1 68.38,101.32 68.61,101.09 U60.4
1.8VS_ON: length 4.8
  TOP w0.102: R1055.1 60.51,100.81 v1(61.87,100.81)
  TOP w0.254: R1055.1 C1125.2 59.9,102.44 59.16,102.44 58.92,102.67 U59.3
1.35VS_ON: length 4.8
  TOP w0.102: v1(61.94,104.81) 60.49,104.81 R1056.1
  TOP w0.254: R1056.1 C1128.2 59.74,103.33 59.59,103.47 U59.5
3VS_ON: length 3.3
  BOTTOM w0.203: 105.77,29.21 105.77,28.88 105.93,28.72 U11.3
  BOTTOM w0.254: 105.77,29.21 v1(105.77,29.44) 105.77,30.05 R927.1 C980.1
5VS_ON: length 3.7
  BOTTOM w0.203: v1(107.19,29.44) 106.79,29.03 106.79,28.83 106.73,28.77 U11.5
  BOTTOM w0.254: R926.2 C979.2 v1(107.19,29.44)
+0.675VS: length 2.8
  BOTTOM w0.356: v2(146.02,62.6) 146.05,62.57 JDIMM1.204 ; v2(145.75,67.99) JDIMM1.203
  vias: v3(150.56,52.17) v4(152.48,47.19) v4(153.24,47.19) v4(154,47.19)
+0.675VSP: length 3.6
  TOP w0.102: v4(157.27,28.56) v3(158.11,28.56)
  IN2 w0.254: v5(155.62,28.56) v4(157.27,28.56)
  BOTTOM w0.203: PU200.2 156.89,28.18 v4(157.27,28.56)
+1.0VALW: length 11
  TOP w0.102: C1034.2 v3(94.7,117.76)
  TOP w0.254: C1039.2 104.97,118.09 105.09,117.98 v2(105.09,117.46) 104.71,117.46 C1074.1 ; C1036.2 106.65,116.66 106.73,116.58 v2(106.73,115.86) 105.68,115.86 105.4,115.57 C1037.2
  BOTTOM w0.254: USOC1.C5 96.64,116.43 v2(96.64,116.26) 96.59,116.21 USOC1.B6 ; USOC1.Y19 105.67,117.5 USOC1.V18 105.63,117.46 v2(105.09,117.46) ; USOC1.V22 106.74,115.87 v2(106.73,115.86) 106.71,115.84 USOC1.U22 ; USOC1.C3 95.84,117.23 95.84,117.2 v2(95.98,117.06)
  vias: v4(52.48,97.52) v4(52.48,96.86) v4(52.48,96.22) v4(52.48,95.54) v4(53.24,97.55) v4(53.24,96.88) v4(53.19,96.2) v4(53.19,95.54) v4(67.06,107.74) v4(67.06,106.98) v4(67.06,106.22) v4(67.06,105.46) v4(67.06,104.7) v4(67.82,107.74) v4(67.82,106.98) v4(67.82,106.22) v4(67.82,105.46) v4(67.82,104.7)
+1.0VALWP: length 15.4
  BOTTOM w0.254: PC308.1 57.71,94.09 57.71,91.69 56.54,90.52 v1(56.54,90.22) 56.54,87.65 55.83,86.94 51.84,86.94 51.34,87.45 PC310.1 PR307.1
+1.0VALWP_ON: length 4.3
  BOTTOM w0.102: v1(48.49,93.72) PC309.1
  BOTTOM w0.508: PR305.1 PR308.2 PC309.1 49.68,92.78 PU301.1
+1.0VS: length 131.6
  TOP w0.254: C1062.2 107.83,116.95 107.83,115.93 107.82,115.91 107.82,115.9 v2(107.83,115.9) ; v2(102.87,116.71) 102.37,116.71 102.26,116.6 C1060.2
  TOP w0.305: v2(105.67,118.03) 106,118.37 C1044.2
  TOP w0.356: C1061.2 114.36,113.83 v2(114.32,113.83)
  TOP w0.508: v2(94.45,101.99) 94.45,104.33 v2(94.69,104.57) 95.91,105.79 95.91,107.49 93.83,109.57 90.68,109.57 89.11,108 84.89,108 v2(84.12,108.77) ; v2(115.97,115.46) 116.06,115.55 117.21,115.55 117.29,115.46 ; PR527.2 PR526.2 167.01,132.03 PR525.2 PC523.1 168.32,132.01 168.47,132.17 v4(168.92,132.17)
  IN1 w0.508: v4(168.92,132.17) 168.37,132.17 167.41,131.21 167.41,129.51 164.04,126.13 162.11,126.13 160.43,124.46 160.43,112.19 159.97,111.73 156.92,111.73 155.96,110.77 155.96,106.58 154.28,104.9 147.32,104.9 v2(139.88,112.34)
  IN2 w0.508: v2(139.88,112.34) 132.64,119.58 132.64,121.61 126.97,127.29 125.34,127.29 124.84,127.79 118.75,127.79 117.3,126.34 117.3,125.45 117.17,125.32
  BOTTOM w0.254: v2(115.97,115.46) 115.97,115.81 115.99,115.83 USOC1.AK35 ; v2(115.97,115.46) 116.26,115.46 116.27,115.48 USOC1.AK36 ; v2(115.97,115.46) 115.97,114.93 USOC1.AJ36 ; v2(114.61,121.39) 114.2,120.98 114.2,120.66 USOC1.AN25 ; 115.49,119.32 v2(115.51,119.34) ; 115.49,119.32 USOC1.AN30 ; 115.49,119.32 115.44,119.27 USOC1.AN29 ; USOC1.G1 96.23,119.74 v2(96.73,119.74) ; v2(104.53,116.81) 104.64,116.92 USOC1.U18 ; USOC1.Y22 107.82,115.9 v2(107.83,115.9) ; v2(108.97,120.28) 108.95,120.25 USOC1.AF18 USOC1.AF16 ; USOC1.Y24 108.35,115.34 v2(108.33,115.32) ; USOC1.M14 102.37,116.71 v2(102.87,116.71) ; USOC1.AF21 USOC1.AG21 v2(110.59,119.73) ; USOC1.U19 v2(105.64,116.91) ; USOC1.BJ6 112.75,132.7 112.75,132.94 113.49,133.67 v2(114.7,133.67) ; v2(105.67,118.03) USOC1.Y18 ; v2(107.27,115.32) 107.28,115.33 USOC1.V24 ; USOC1.AM18 USOC1.AM16 ; USOC1.V32 v2(111.03,112.65)
  BOTTOM w0.305: RC27.1 94.83,102.37 v2(94.45,101.99)
  BOTTOM w0.508: RC15.2 94.87,104.57 v2(94.69,104.57)
  vias: v2(91.16,119.45) v2(91.93,119.45) v2(92.69,119.45) v2(93.4,119.43) v2(94.34,119.45) v2(94.97,119.45) v2(110.1,121.36) v2(110.63,121.9) v2(112.65,112.16) v2(114.02,122.1) v2(115.01,123.04) v2(115.5,123.52) v2(117.61,124.41) v2(118.09,124.85) v3(119.13,129.06) v4(68.94,96.44) v4(68.94,95.73) v4(69.68,97.99) v4(69.68,97.23) v4(69.68,96.47) v4(69.68,95.71) v4(70.44,97.99) v4(70.44,97.23) v4(70.44,96.47) v4(70.44,95.71)
+1.0VS_R: length 3.3
  BOTTOM w0.102: v1(67.53,96.06) R1052.1
  BOTTOM w0.508: R1052.1 Q71.1
+1.05V_PGOOD: length 1.9
  TOP w0.102: T210.1 180.11,55.2 UE1.122
+1.5VS: length 114.4
  TOP w0.406: 121.42,119.35 118.72,116.66 118.37,116.66 117.79,117.24 C1058.1 117.01,117.42 116.29,117.42 v2(116.04,117.68)
  TOP w0.508: v2(56.16,14.55) 55.27,14.55 54.64,15.19 54.64,18.11 54.19,18.55 RA8.1
  TOP w0.762: 174.36,141.12 174.37,141.11 174.37,105.95 174.27,105.85
  IN1 w0.508: v4(108.26,145.62) 107.19,145.62 105.79,144.22 92.64,144.22 90.73,146.13 90.73,148.94 91.24,149.45 93.67,149.45 94.21,148.9 94.82,148.9 95.3,149.38 v2(95.3,149.58)
  IN2 w0.762: 174.63,105.94 174.37,106.2 174.37,141.15
  BOTTOM w0.254: USOC1.AM32 116.01,117.64 v2(116.04,117.68)
  BOTTOM w0.508: JMINI.6 v2(95.3,149.58)
  vias: v2(115.27,146.81) v2(115.27,146.23) v2(161.66,49.35) v2(162.25,49.35) v2(162.83,49.35) v2(165.94,103.83) v2(165.97,104.49) v2(166.53,104.19) v2(174.08,104.95) v2(174.37,143.13) v2(174.37,142.54) v2(174.37,141.96) v2(174.67,104.95) v2(175.25,104.95) v3(170.88,142.52) v4(108.26,146.28) v4(164.35,146.57) v4(164.35,145.87) v4(164.35,145.17) v4(164.99,146.57) v4(164.99,145.87) v4(164.99,145.17)
+1.05VS: length 169
  TOP w0.102: v2(66.2,32.46) v3(64.77,32.46)
  TOP w0.203: UG1.3 66.3,37.09 66.2,36.98 CG2.1
  TOP w0.254: C1040.1 112.06,112.73 v2(111.56,113.22)
  TOP w0.356: RC100.2 110.03,112.56 v2(110.47,112.12) 110.47,111.79 C1038.1
  TOP w0.381: v2(114.35,115.98) 114.29,115.98 C1041.1
  TOP w0.508: R2315.1 v2(66.2,32.46) ; C1042.1 115.01,116.42 v2(115.43,116.01) ; CG2.1 v2(65.54,35.58)
  IN1 w0.406: v2(110.47,112.12) 110.47,112.85 110.82,113.21 111.55,113.21 v2(111.56,113.22)
  IN2 w0.508: v2(156.95,52.04) 155.72,53.27 155.72,70.41 158.25,72.93 v2(158.25,96.9)
  BOTTOM w0.254: USOC1.AA33 111.57,113.23 v2(111.56,113.22) ; USOC1.U35 USOC1.U33 110.46,112.11 v2(110.47,112.12) 110.48,112.12 USOC1.V33
  BOTTOM w0.305: v2(114.35,115.98) 114.34,115.97 114.34,115.44 114.88,114.91 114.86,114.89 USOC1.AF33
  BOTTOM w0.508: v2(156.95,52.04) 151.19,52.04 149.28,50.14 90.8,50.14 86.32,45.66 67.69,45.66 66.6,44.57 66.6,43.51 65.03,41.93 65.03,38.38 65.54,37.87 v2(65.54,35.58) 66.2,34.92 v2(66.2,32.46)
  vias: v4(135.89,109.98) v4(136.48,110.56) v4(136.66,109.83) v4(137.09,111.17) v4(137.21,110.44) v4(160.81,109.78) v4(160.81,108.81) v4(161.45,109.29) v4(161.45,108.33) v4(161.47,110.23)
+1.05VS_SOC: length 1.1
  BOTTOM w0.254: USOC1.Y32 111.04,113.76 v2(111.04,113.76) ; USOC1.AC32 v2(111.62,114.32)
  vias: v1(111.55,113.8)
+1.5VSP: length 6.7
  TOP w0.102: v2(166.98,147.34) v3(166.98,148.04)
  BOTTOM w0.254: PR410.1 PC413.1 171.85,144.03 171.53,143.71 168.53,143.71 168.18,144.06 PC414.1
+1.05VSP: length 11.8
  TOP w0.102: v2(161.94,112.25) v3(161.94,112.91)
  BOTTOM w0.254: 164.11,108.02 165.08,107.06 171.89,107.06 172.7,107.87 PR302.1 PC301.1
+1.05VSP_ON: length 4.2
  BOTTOM w0.102: PR300.2 170.44,109.37 v1(170.56,109.24)
  BOTTOM w0.508: PR300.2 PR303.1 PC304.1 167.77,110.37 PU300.1
+1.8VALW: length 41.8
  TOP w0.305: U64.1 99.34,140.84 99.04,140.54 98.52,140.54 98.19,140.87 v2(98.19,141.11) ; JDB1.16 v2(63.38,74.12)
  TOP w0.457: v2(104.88,114.4) 104.52,114.4 104.48,114.44 C1045.1
  TOP w0.508: v2(98.19,141.11) 98.19,141.41 98.85,142.07 R5.2 ; R6.1 82.77,95.91 v2(82.2,96.48) ; R3.1 v2(78.96,86.22) ; RC99.2 84.46,81.61 84.94,81.13 84.94,76.86 83.37,75.28 v2(79.99,75.28) ; RC61.1 56.82,80.54 57.26,80.11 59.78,80.11 60.7,79.2 v2(60.7,78.64) ; C182.1 R7.1 v2(78.6,95.02) R4.1 ; R17.1 v2(58.84,81.6) ; RC62.1 v2(63.15,81.95) ; RC63.1 v2(65.18,81.91)
  IN2 w0.508: v2(58.84,81.6) 60.85,81.6 61.31,82.05 63.04,82.05 v2(63.15,81.95)
  BOTTOM w0.229: USOC1.AA18 106.22,118.59 105.77,119.03 v2(105.77,119.51)
  BOTTOM w0.254: v2(104.88,114.4) 104.78,114.51 USOC1.N20
  BOTTOM w0.305: RC46.1 v2(93.63,108.28) RC44.1
  vias: v2(91.44,103.15) v2(92,103.6) v2(97.46,110.59) v2(97.84,111.05) v2(107.24,113.99) v3(92.52,105.56) v4(70.29,93.93) v4(70.29,93.29) v4(70.29,92.66) v4(70.92,93.93) v4(70.92,93.29) v4(70.92,92.66) v4(164.35,150.38) v4(164.35,149.68) v4(164.35,148.98) v4(165,150.37) v4(164.99,149.68) v4(164.99,148.98)
+1.8VALWP: length 9.7
  BOTTOM w0.254: PC403.1 66.51,93.83 v1(63.71,93.83) 60.76,93.83 59.69,92.76 PR402.1 59.69,91.6 PC401.1
+1.8VGS: length 5.2
  TOP w0.102: CG1.1 67.19,41.78 66.73,42.24 66.73,44 v3(67.19,44.46)
  TOP w0.203: CG1.1 67.21,41.22 67.1,41.11 UG1.11
+1.8VS: length 305.7
  TOP w0.254: RP63.7 110.27,137.08 v2(110.09,137.26) 109.77,136.94 RP63.8 ; RP63.5 111.27,137.12 v2(111,137.39) 110.77,137.15 RP63.6
  TOP w0.305: RC8.2 107.84,107.5 106.71,106.37 106.71,105.1 105.31,103.71 105.31,101.93 106.71,100.53 106.71,99.31 103.79,96.39 103.79,95.64 103.24,95.09 UC4.5
  TOP w0.356: UC4.5 102.66,95.58 102.3,95.94 100.8,95.94 100.4,96.34 98.61,96.34 96.09,93.83 92.98,93.83 90.97,91.82 v2(88.66,91.82)
  TOP w0.406: C1053.1 C1051.1 116.65,118.11 v2(116.57,118.19) ; UC10.5 103.52,137.47 103.85,137.81 v2(104.23,137.81) ; C1054.1 C1055.1 111.83,109.52 v2(111.46,109.89)
  TOP w0.508: RC43.1 112.25,136.22 v2(111.79,135.76) ; Q57.2 19.51,109.14 19.41,109.14 v2(19.18,108.91) ; v2(130.08,122.25) 126.9,122.25 126.72,122.43 RC17.1 125.45,122.12 123.73,122.12 123.24,121.64 122.52,121.64 122.08,122.08 v3(120.76,122.08) v2(119.82,121.14) 119.62,120.94 RC16.1 ; v4(52.81,98.65) 53.11,98.35 54.31,98.35 56.77,95.88 56.77,91.41 59.7,88.49 59.7,85.26 R15.1 ; v2(88.66,91.82) 87.44,93.04 87.44,107.03 87.11,107.36 84.56,107.36 82.48,109.45 79.93,109.45 77.15,112.23 74.17,112.23 v2(73.85,111.91) ; v2(105.36,137.79) 105.41,137.74 105.74,137.74 QC2.2 106.12,137.36 106.12,136.6 RC18.1 ; R8.1 102.34,138.49 v2(102.52,138.31) ; QC4.2 119.41,135.76 118.19,135.76 117.15,136.8 v2(116.67,136.8) 116.67,135.96 QC3.2 ; Q58.2 v2(19.9,106.35)
  IN1 w0.406: v2(111.46,109.89) 112.23,109.89 113.11,110.77 113.11,110.95 114.18,112.01 116.59,112.01 117,112.42 117.81,112.42 118.34,111.88 v2(129.14,111.88)
  IN1 w0.508: v2(162.51,146.73) 150.4,134.62 137.46,134.62 v2(133.19,130.34) 132.6,130.34 v2(127.17,124.92)
  IN2 w0.508: v2(133.19,130.34) 133.19,130.92 129.25,134.86 125.61,134.86 123.25,137.22 119.98,137.22 117.91,139.29 114.48,139.29 113.92,138.73 113.92,137.13 112.55,135.76 v2(111.79,135.76) ; v2(130.08,122.25) 129.06,122.25 127.17,124.13 v2(127.17,124.92) ; v2(190.81,155.14) 178.67,155.14 175.39,151.86 163.99,151.86 162.51,150.39 v2(162.51,146.73) ; v2(116.57,118.19) 116.57,118.77 117.46,119.66 118.34,119.66 v2(119.82,121.14)
  BOTTOM w0.254: RP15.4 20.21,112.15 v2(19.99,112.37) 19.71,112.08 RP15.3
  BOTTOM w0.33: v2(111.46,109.89) 111.72,109.89 111.79,109.95 USOC1.U38
  BOTTOM w0.406: RC10.1 90.01,91.82 v2(88.66,91.82)
  BOTTOM w0.508: v2(129.14,111.88) 131.02,113.76 131.02,121.31 v2(130.08,122.25) ; v2(190.81,155.14) 195.56,155.14 199.19,151.51 208.08,151.51 208.44,151.86 R377.1 ; R376.1 v2(19.97,113.66)
  vias: v2(116.03,136.78) v4(51.11,99.72) v4(51.11,98.65) v4(51.95,99.72) v4(51.92,98.65) v4(52.81,100.76) v4(52.76,99.77)
+1.8VS_OUT:
  vias: v1(56.33,99.3)
+1.8VSP_ON: length 4.2
  BOTTOM w0.102: PR400.2 v1(61.7,91.92)
  BOTTOM w0.508: PU400.1 64.29,91.67 PC404.1 63.6,91.9 PR403.1 62.69,91.9 PR400.2
+1.35V: length 60.3
  TOP w0.508: R1029.1 v4(124.72,56.83)
  BOTTOM w0.356: JDIMM1.93 112.75,68.38 112.36,67.99 v2(111.36,67.99) 110.95,68.4 JDIMM1.87 ; JDIMM1.117 119.95,68.1 v2(119.87,68.02) ; v2(107.57,62.62) 107.65,62.55 JDIMM1.76 ; v2(116.44,67.99) 116.44,68 116.35,68.08 JDIMM1.105 ; v2(122.05,59.85) JDIMM1.124 ; v2(116.65,62.75) JDIMM1.106 ; JDIMM1.112 v2(118.45,59.8) ; v2(115.29,71.46) 114.55,70.72 JDIMM1.99 ; v2(120.25,62.69) JDIMM1.118 ; v2(108.92,67.75) 109.15,67.98 JDIMM1.81 ; v2(113.05,59.88) JDIMM1.94 ; v2(114.85,62.63) JDIMM1.100 ; JDIMM1.75 107.35,67.32 v2(106.63,66.61) ; JDIMM1.88 v2(111.25,59.88) ; v2(122.24,67.2) 122.24,67.88 121.75,68.36 JDIMM1.123 ; v2(109.53,62.62) 109.45,62.54 JDIMM1.82 ; v2(116.46,67.12) 116.76,67.12 118.16,68.52 118.16,69.43 JDIMM1.111
  BOTTOM w0.508: v2(122.05,59.85) 122.05,59.27 122.53,58.78 123.7,58.78 R1029.1 v4(124.72,56.83) ; v2(116.77,92.12) 117.38,91.51 121.92,91.51 126.55,96.14 126.55,105.19 RC6.1
  vias: v3(60.1,106.6) v4(58.35,106.35) v4(58.35,105.59) v4(58.35,104.82) v4(59.11,106.35) v4(59.11,105.59) v4(59.11,104.82) v4(75.85,68.4) v4(75.87,70.05) v4(75.87,69.26) v4(77.24,72.9) v4(78.01,72.9) v4(78.77,72.9) v4(136.91,42.21) v4(136.91,41.45) v4(137.67,42.21) v4(137.67,41.45) v4(137.67,40.69) v4(138.43,42.21) v4(138.43,41.45) v4(138.43,40.69) v4(139.2,42.21) v4(139.2,41.45) v4(139.2,40.69) v4(139.96,42.21) v4(139.96,41.45) v4(139.96,40.69)
+1.35V_SOC: length 14.1
  BOTTOM w0.254: USOC1.BG51 127.13,116.01 v2(126.76,115.64) ; USOC1.AV41 USOC1.AV42 v2(121.23,115.26) ; v2(111.67,101.35) 111.83,101.19 111.88,101.19 USOC1.C51 ; USOC1.F52 113.54,101.44 USOC1.F53 114.21,100.77 114.21,100.11 v2(114.23,100.08) ; USOC1.D44 110.42,103.69 v2(110.6,103.51) ; v2(112.03,105.04) 112.03,104.76 111.95,104.68 USOC1.H46 ; USOC1.AK38 117.12,114.89 117.64,114.89 v2(117.66,114.92) 117.66,115.46 USOC1.AM38 ; v2(124.96,117.94) 124.83,118.07 USOC1.BF44 ; v2(127.77,118.57) 127.03,117.83 USOC1.BJ48 ; USOC1.BD52 126.69,114.58 127.28,113.99 v2(127.28,113.67) ; v2(123.64,115.59) 123.69,115.65 USOC1.BB46 ; v2(109.91,100.59) 110.14,100.81 110.14,100.97 USOC1.A48 ; USOC1.F49 112.26,103.23 v2(112.27,103.23) ; USOC1.BD49 125.42,115.24 v2(125.43,115.22)
  BOTTOM w0.33: USOC1.V38 112.62,110.51 USOC1.V38 ; USOC1.V38 USOC1.Y38 113.21,111.1 114.02,111.1 v2(114.15,111.22)
  vias: v1(128.53,103.12) v2(111.7,106.77)
+1.35VP: length 26.7
  TOP w0.102: v4(151.44,28.73) v3(152.45,28.73)
  IN2 w0.508: v2(162.46,23.7) 161.19,24.97 161.19,26.67 v4(159.1,28.76) 158.3,29.56 158.3,30.12 156.67,31.75 154.46,31.75 v4(151.44,28.73)
  IN2 w1.016: 153.85,26.57 148.29,26.57
  BOTTOM w0.203: PU200.5 158.09,28.01 158.59,28.51
  BOTTOM w0.254: 158.59,28.51 158.84,28.76 v4(159.1,28.76) 159.33,29 PR204.2
  BOTTOM w0.508: PR210.1 v2(162.46,23.7)
  vias: v4(147.09,26.87) v4(147.4,26.31) v4(154.82,27.3) v4(154.78,26.6)
+1.35VS: length 31
  TOP w0.254: v2(108.36,116.44) 108.36,116.91 108.39,116.94 CC40.1 ; CC41.1 111.54,111.93 v2(111.54,111.04) 110.8,111.04 110.35,110.59 CC39.1
  TOP w0.508: v2(84.05,87.93) 85.04,86.94 RC30.1 ; v2(86.36,106.67) 86.36,93.67 84.76,92.07 84.22,92.07 v2(84.05,92.24)
  BOTTOM w0.203: v2(108.36,116.44) 108.89,115.91 USOC1.AA25
  BOTTOM w0.254: USOC1.AD36 113.8,113.26 113.77,113.23 v2(113.78,113.23) ; v2(113.8,115.44) 113.81,115.46 USOC1.AG32
  BOTTOM w0.33: USOC1.U36 111.53,111.04 v2(111.54,111.04) 112.09,111.04
  BOTTOM w0.508: v2(84.05,92.24) 84.05,91.5 83.47,90.92 83.47,88.39 83.93,87.93 v2(84.05,87.93)
  vias: v2(104.75,134.03) v2(105.06,133.42) v2(108.44,119.71) v3(81.08,118.26) v4(85.2,110.89) v4(86.01,110.92) v4(86.8,110.95) v4(94.26,126.69) v4(94.9,126.69) v4(95.58,126.69)
+1.35VS_OUT: length 2.1
  TOP w0.102: 54.75,105.55 v1(52.66,105.55)
+3V_HUB: length 2.8
  TOP w0.508: R1049.1 v2(54.89,49.17) ; R1050.1 v2(53.88,49.17) ; R1047.1 51.84,49.78 v2(52.45,49.17)
  vias: v2(55.91,55.88) v2(56.67,55.88) v3(56.82,56.44)
+3V_WLAN: length 1
  TOP w0.508: v4(105.69,146.78) 105.69,146.78 CM47.1
  vias: v3(94.22,146.44) v4(92.75,148.68) v4(92.75,147.92) v4(92.75,147.16) v4(105.72,146.12) v4(111.28,149.6) v4(112.04,149.6) v4(112.8,149.6) v4(117,149.58) v4(117.63,149.58) v4(118.29,149.58)
+3VALW: length 411.4
  TOP w0.203: 65.33,36.65 65.9,37.22 UG1.2
  TOP w0.356: UC7.5 87.77,84.39 86.78,83.4 86.78,78.61 v2(85.93,77.76)
  TOP w0.508: R1022.2 96.92,123.85 89.34,123.85 87.23,121.74 v2(87.23,121.5) ; RA10.1 33.94,29.28 43.84,39.19 v2(57.81,39.19) ; v2(75,79.11) 78.25,75.86 v2(78.25,74.96) 76.39,74.96 75.21,73.78 75.21,41.37 v2(76.91,39.67) ; v2(79.06,84.2) 79.12,84.26 R13.1 ; v2(64.09,35.58) CG10.1 64.8,36.12 65.33,36.65 ; v2(77.35,82.05) 75.83,82.05 73.69,84.2 R14.1 ; PR4.2 v2(145.73,178.99)
  IN1 w0.508: v2(141.43,181.81) 144.25,178.99 v2(145.73,178.99) 146.43,178.99 151.41,183.97 160.5,183.97 163.39,181.07 177.55,181.07 180.57,178.05 v2(180.57,154.05) ; 169.19,41.32 169.19,45.03 170.21,46.05 170.21,48.23 170.01,48.44 170.01,84.99 172.37,87.35 v2(172.37,116.84) 167.06,116.84 161.69,122.21 v2(161.69,124.41)
  IN2 w0.508: v2(161.57,140.54) 161.57,139.98 163.3,138.25 171.38,138.25 ; 171.38,138.25 173,139.88 173,144.35 180.57,151.92 v2(180.57,154.05) ; 171.38,138.25 172.37,137.26 v2(172.37,116.84) ; v2(79.06,84.2) 79.06,83.17 77.94,82.05 v2(77.35,82.05) 77.35,81.45 v2(75,79.11)
  BOTTOM w0.508: PR510.1 v2(161.57,140.54) ; v2(50.09,80.92) 50.5,80.52 RL40.1 ; PR530.2 161.69,126.61 161.69,126.6 v2(161.69,124.41) ; PR7.2 v2(141.43,181.81) ; v2(87.23,121.5) 78.34,112.62 68.76,112.62 67.19,114.2 45.39,114.2 41.81,110.61 41.81,95.45 44.45,92.81 v2(44.45,92.3) ; v2(78.25,74.96) 79.18,75.89 81.23,75.89 83.1,77.76 v2(85.93,77.76)
  vias: v3(50.98,85.72) v3(143.01,16) v3(148.86,27.56) v4(46.59,79.47) v4(46.59,78.71) v4(47.22,79.47) v4(47.22,78.71) v4(54.69,90.12) v4(54.69,89.36) v4(55.45,90.12) v4(55.45,89.36) v4(55.45,88.59) v4(55.45,87.86) v4(102.21,29.64) v4(102.21,28.88) v4(102.98,29.64) v4(102.98,28.88) v4(103.74,29.64) v4(103.74,28.88) v4(104.5,29.64) v4(104.5,28.88) v4(134.55,11.63) v4(134.55,10.87) v4(135.31,11.63) v4(135.31,10.87) v4(136.07,11.63) v4(136.07,10.87) v4(136.83,11.63) v4(136.83,10.87) v4(137.6,11.63) v4(137.6,10.87) v4(138.36,11.63) v4(138.36,10.87) v4(146.8,30.4) v4(146.8,29.64) v4(147.56,30.4) v4(147.56,29.64) v4(148.32,30.4) v4(148.32,29.64) v4(149.08,30.4) v4(149.08,29.64) v4(149.84,30.4) v4(149.84,29.64) v4(150.61,30.4) v4(150.61,29.64) v4(195.66,45.64) v4(196.42,45.64) v4(197.18,45.64)
+3VALW_EC: length 234.9
  TOP w0.203: UE1.9 186.39,50.16 186.08,49.86 ; UE1.22 191.59,49.84 191.72,49.71 ; UE1.125 v2(182.93,54)
  TOP w0.254: CE5.2 182.53,68.53 183.19,67.87 UE1.96 ; RP36.6 190.4,73.91 v2(190.61,74.12) 190.9,73.82 RP36.5
  TOP w0.305: U64.6 96.36,140.84
  TOP w0.381: v2(77.13,87.08) 76.66,87.55 U61.5 ; U62.5 79.07,92.46 79.48,92.05 80.86,92.05 81.55,92.73 U63.5
  TOP w0.508: 191.72,49.71 CE2.1 v2(191.09,48.79) ; R696.2 176.1,61.49 v2(175.8,61.8) ; R697.2 v2(177.07,64.97) ; v2(181.66,69.47) CE5.2 ; R489.1 190.96,44.96 v2(191.39,45.39) ; 96.36,140.84 96.01,140.84 95.74,141.11 95.74,141.75 94.94,142.54 93.94,142.54 93.04,141.64 93.04,140.32 91.73,139.01 90.73,139.01 89.39,137.67 89.39,132.97 91.44,130.91 91.44,128.89 v2(91.21,128.66) ; RE3.2 193.4,71.63 v2(193.88,72.11) ; R18.1 82.26,85.09 82.26,85.37 v2(82.77,85.88) 83.19,86.29 83.19,88.95 82.11,90.02 81.27,90.02 80.95,90.33 80.95,91.96 80.86,92.05 ; v2(75.24,83.91) 74.82,84.33 R20.1 ; 186.08,49.86 185.7,49.48 CE6.2 v2(185.04,48.79) ; R488.1 v2(189.39,47.19) ; RE8.2 v2(201.7,54.81) ; RE11.2 v2(178.26,49.2) ; RE71.1 v2(176.08,59.08) ; v2(74.9,111.56) 72.14,108.8 72.14,106.02 74.9,103.26 74.9,101.67 78.27,98.3 80.34,98.3 81.35,97.29 81.35,93.95 81.55,93.75 U63.5
  IN2 w0.508: v2(75.24,83.91) 75.24,84.57 77.13,86.46 v2(77.13,87.08) ; v2(173,75.59) 174.07,74.52 174.07,62.99 175.26,61.8 v2(175.8,61.8) 176.56,62.56 176.56,64.46 v2(177.07,64.97)
  BOTTOM w0.508: v2(74.9,111.56) 78.43,111.56 88.42,121.54 88.42,122.7 89.68,123.96 90.71,123.96 91.21,124.47 v2(91.21,128.66) ; v2(173,75.59) 163.55,75.59 154.82,84.33 107.23,84.33 106.25,85.31 92.56,85.31 91.58,84.33 84.86,84.33 83.32,85.88 v2(82.77,85.88) 82.49,85.6 77.94,85.6 77.35,85 77.35,84.49 76.43,83.58 75.57,83.58 v2(75.24,83.91)
  vias: v3(197.79,49.72) v4(198.63,52.27) v4(198.61,51.56) v4(198.61,50.8)
+3VALW_SOC: length 13.1
  TOP w0.305: v2(105.31,114.87) 105.25,114.93 104.35,114.93 103.76,115.52 103.76,116.01 v2(103.97,116.21) 103.43,116.75 103.43,116.86 102.98,117.32 101.98,117.32 100.92,118.39 100.79,118.39 v1(99.85,119.33)
  TOP w0.508: R1022.1 99.15,122.11 C1065.1 C1067.1 C1063.1 98.91,119.89 99.47,119.33 v1(99.85,119.33)
  BOTTOM w0.254: v2(105.31,114.87) 105.47,114.72 USOC1.N22
+3VALW_UL2: length 0.9
  BOTTOM w0.102: 46.66,77.68 v1(47.6,77.68)
+3VALW_UL3: length 1.3
  BOTTOM w0.102: UL3.5 47.59,79.79 47.91,79.47 v1(47.91,79.28)
+3VALWP: length 14.5
  TOP w0.508: v4(130.36,11.4) PR100.1 ; PR106.1 v3(134.41,14.27) v4(135.16,14.27)
  IN2 w0.254: v4(139.22,16.06) 136.39,13.23 134.39,13.23 134.04,12.88 131.07,12.88 130.36,12.16 v4(130.36,11.4)
  BOTTOM w0.508: PR100.1 v4(130.36,11.4)
+3VLP: length 285.6
  TOP w0.203: v2(182.82,59.71) 182.71,59.6 UE1.111 ; UG1.15 65.5,40.24 65.26,40.49 64.72,40.49 ; PU100.3 129.23,13.65 v2(129.21,13.64)
  TOP w0.254: v2(129.21,13.64) PC105.1
  TOP w0.508: RE49.2 v2(193.63,28.62) ; v2(62.92,41.78) CG4.1 63.66,41.55 64.72,40.49 ; R19.1 81.37,83.74 80.85,83.22 79.35,83.22 78.97,82.84 78.1,82.84 77.47,83.46 v2(77.44,83.46) 77.05,83.84 R21.1 ; v2(73.28,40.75) 73.28,45.64 74.58,46.94 74.58,74.69 75.39,75.5 75.39,76.41 74.13,77.67 v2(73.46,77.67) ; v4(114.66,28.24) v4(114.66,30.71)
  IN1 w0.508: v4(198.49,45.6) 197.68,46.41 195.21,46.41 192.51,43.71 184.03,43.71 v2(182.2,45.54)
  IN2 w0.508: v2(77.44,83.46) 77.21,83.46 76.04,82.29 76.04,81.35 73.46,78.78 v2(73.46,77.67) ; v2(129.21,13.64) 129.21,13.41 128.55,12.75 128.55,11.89 128.91,11.53 128.91,10.81 128.29,10.18 122.46,10.18 121.66,10.98 121.66,12.79 120.25,14.2 117.86,14.2 115.4,16.66 115.4,16.71 114.66,17.45 v4(114.66,28.24) ; v2(62.92,41.78) 72.24,41.78 v2(73.28,40.75) 82.27,31.75 105.72,31.75 106.18,31.29 114.07,31.29 v4(114.66,30.71) 120.42,36.47 159.49,36.47 162.11,33.86 v2(171.38,33.86) ; v2(176.41,39.67) 179.49,42.76 179.49,42.83 v2(182.2,45.54) 182.2,53.41 181.56,54.05 181.56,58.46 v2(182.82,59.71)
  BOTTOM w0.508: v2(171.38,33.86) 173.43,35.91 173.43,36.7 v2(176.41,39.67) 186.44,39.67 193.63,32.48 v2(193.63,28.62)
  vias: v3(200.85,46.61) v4(180.22,113.03) v4(180.98,113.03) v4(181.74,113.03) v4(199.25,45.6) v4(200.01,45.6)
+3VS: length 348
  TOP w0.203: 46.07,25.09 45.56,25.09 45.41,24.94 UA1.1
  TOP w0.254: RP36.7 189.9,73.91 v2(189.67,74.14) 189.4,73.87 RP36.8
  TOP w0.305: JTP.1 v2(66.35,111.58)
  TOP w0.356: UE2.5 174.47,62.16 174.27,62.35 CE15.1
  TOP w0.406: v2(72.77,88.76) 72.77,89.75 75.17,92.15 76.34,92.15 76.59,92.4 U65.5 ; UD1.5 57.32,19.24 57.18,19.38 CD63.1
  TOP w0.508: v2(79.29,74.31) 86.57,74.31 91.14,78.88 91.14,86.56 R378.1 ; RC20.1 64.65,84.58 v2(65.31,84.58) ; v2(44.78,87.98) 44.35,88.42 44.35,90.24 43.31,91.29 v2(43.31,93.06) 41.05,93.06 40.72,92.73 32.46,92.73 ; RE9.1 RE10.1 185.04,70.91 v2(185.04,72.13) ; v4(172.19,70.36) 172.19,63.24 173.08,62.35 CE15.1 ; v2(94.64,141.3) 94.64,139.58 96.5,137.73 U66.5 99.04,137.73 99.85,136.92 102.07,136.92 103.71,138.55 RC53.1 ; v2(59.87,23.62) 59.87,22.96 59.46,22.55 RD45.1 ; RA1.1 v2(27.96,24.98) ; CD63.1 v2(56.62,18.69) ; 125.63,136.6 125.63,134.85 127.87,132.61 127.87,126.52 126.42,125.07 125.66,125.07 124.93,124.34 v2(124.93,123.42) 124.91,123.39 R1023.2 ; v2(48.29,26.11) CA59.1 48.05,27.18 CA60.1 46.89,26.92 46.89,25.92 46.07,25.09 ; QD19.2 64.27,16.33 RD47.1 v2(66.12,16.33) ; RA2.1 v2(30.6,25.04) ; QD18.2 v2(55.82,16.58) ; v2(54,17.6) RA9.1 ; RA155.2 v2(38.51,26.62)
  TOP w1.524: 97.84,147.04 97.84,146.09 96.99,145.24 95.42,145.24 95.01,144.83 92.48,144.83 87.53,139.88 87.53,127.54 83.26,123.26 66.96,123.26 65.26,121.56 63.48,121.56 59.97,118.06 52.76,118.06 33.38,98.68 33.38,96.14 30.61,93.37
  IN1 w0.508: v2(13.36,115.64) 14.13,114.88 14.13,112.22 v2(15.78,110.56) 15.78,109.6 17.1,108.28 17.1,101.22 18.29,100.02 18.29,97.48 23.45,92.33 25.51,92.33 v2(26.11,92.94)
  IN2 w0.508: v2(66.35,111.58) 63.41,108.63 59.11,108.63 55.71,105.23 v2(51.74,105.23) 46.51,105.23 44.96,103.68 44.96,95.91 43.72,94.66 43.72,93.47 v2(43.31,93.06) ; v2(96.28,146.68) 94.64,145.04 v2(94.64,141.3)
  BOTTOM w0.254: JLVDS.26 216.95,174.11 216.56,174.5 v4(216.23,174.5)
  BOTTOM w0.356: JDIMM1.199 144.55,70.58 144.98,71.01 145.37,71.01 v2(145.42,71.06)
  BOTTOM w0.406: Q14.5 14.13,115.01 14.18,115.06 R122.1
  BOTTOM w0.508: v2(13.36,115.64) R122.1 ; RX12.1 v2(15.78,110.56) ; RS7.1 v2(219.79,53.92) ; v2(124.93,123.42) 125.52,122.83 RC68.1 ; v2(44.78,87.98) 45.06,87.7 RL33.1 ; RE50.1 v2(51.74,105.23)
  BOTTOM w1.016: 168.23,50.29 166.65,48.72 166.65,45.69 164.27,43.31 164.27,25.7 171.5,18.46 177.75,18.46
  vias: v2(26.98,92.94) v2(100.71,147.34) v2(101.25,147.72) v2(101.27,147.09) v2(119.87,150.14) v2(120.45,150.14) v2(121.06,150.11) v3(119,144.56) v4(28.32,75.16) v4(29.09,75.16) v4(29.85,75.16) v4(30.61,75.16) v4(92.81,29.6) v4(92.81,28.84) v4(93.57,29.6) v4(93.57,28.84) v4(94.33,29.6) v4(94.33,28.84) v4(95.09,29.6) v4(95.09,28.84) v4(168.43,51.23) v4(169.19,51.23) v4(172.19,72.64) v4(172.19,71.88) v4(172.19,71.12) v4(172.95,72.64) v4(172.95,71.88) v4(172.95,71.12) v4(172.95,70.36) v4(178.62,18.69) v4(179.25,18.69) v4(198.4,171.07) v4(199.04,171.07) v4(199.67,171.07) v4(213.26,157.73) v4(213.26,156.97) v4(214.02,157.73) v4(214.02,156.97) v4(215.6,174.62) v4(220.32,51.38) v4(220.32,50.62) v4(220.32,49.86) v4(221.09,51.38) v4(221.09,50.62) v4(221.09,49.86)
+3VS_CAM: length 1.9
  TOP w0.102: v4(218.45,172.26) v1(218.45,171.54)
  BOTTOM w0.254: JLVDS.29 v4(218.45,172.26)
+3VS_LCDIN: length 0.9
  BOTTOM w0.102: CX9.1 v1(218,160.17)
+3VS_OUT:
  vias: v1(101.62,25.96)
+3VS_RT: length 1.4
  TOP w0.406: QX6.2 v2(198.15,155.52) ; QX6.5 201.4,155.52 201.4,155.53 v2(201.43,155.53)
  vias: v1(194.49,170.03) v4(195.43,169.85) v4(195.46,169.14) v4(195.46,168.48) v4(206.58,152.63) v4(207.34,152.63)
+3VS_SOC: length 16.2
  TOP w0.102: v1(122.76,125.63) C1073.1
  TOP w0.508: v2(122.1,124.31) 122.33,124.53 C1073.1 122.76,124.08 122.52,123.84 R1023.1
  IN2 w0.305: v2(113.35,120.32) 115.22,120.32 119.56,124.66 121.75,124.66 v2(122.1,124.31)
  BOTTOM w0.229: 113.85,119.79 113.85,119.82 v2(113.35,120.32) USOC1.AN24
  BOTTOM w0.254: USOC1.AN27 113.87,119.81 113.85,119.79 113.86,119.78 USOC1.AM27
+5V_HDD: length 0.7
  TOP w0.102: v2(222.05,58.39) v3(222.05,59.09)
+5V_HUB: length 10.6
  TOP w0.508: R1046.1 v2(56.04,61.29)
  BOTTOM w0.508: v2(56.04,61.29) 56.04,57.66 55.17,56.79 55.17,55.65 55.91,54.91 v2(55.91,52.27)
  vias: v3(55.12,52.63)
+5V_PVDD: length 1.3
  TOP w0.102: v1(49.48,26.31) 49.18,26.01 RV54.2
+5V_USB_PWR1:
  vias: v3(17.47,65.3) v4(12.37,68.17) v4(13.14,68.17) v4(13.74,55.83) v4(13.77,56.64) v4(13.9,68.17) v4(14.79,56.64) v4(14.76,55.83) v4(19.92,65.71) v4(20.68,65.71) v4(21.44,65.71) v4(22.2,65.71)
+5V_USB_PWR1_R1:
  vias: v3(23.33,69.61)
+5V_USB_PWR1_R2:
  vias: v3(25.01,63.24)
+5V_USB_PWR2: length 0.8
  TOP w0.102: v2(23.74,51.26) v3(24.51,51.26)
+5V_USB_PWR2_R1: length 0.8
  TOP w0.102: v2(27.33,50.45) v3(28.13,50.45)
+5V_USB_PWR2_R2: length 0.7
  TOP w0.102: v2(28.4,52.42) v3(29.15,52.42)
+5V_USB_PWR3: length 1
  TOP w0.102: v4(24.9,35.51) v3(25.89,35.51)
  vias: v4(24.13,36.27) v4(24.13,35.51) v4(24.9,36.27)
+5V_USB_PWR3_R1: length 0.7
  TOP w0.102: v2(24.06,43.43) v3(24.79,43.43)
+5V_USB_PWR3_R2: length 0.7
  TOP w0.102: v2(28.31,36.59) v3(29.04,36.59)
+5VA: length 2.6
  TOP w0.203: UA1.26 41.41,17.73 41.09,17.41 40.73,17.41
  TOP w0.381: 40.73,17.41 39.56,17.41
  vias: v3(37.94,13.7)
+5VALW: length 152.2
  TOP w0.254: PU700.11 174.39,172.29 v4(174.77,172.67) ; 58.46,103.07 59.21,103.07 v2(59.34,102.94)
  TOP w0.508: LED1.1 v2(27.84,10.7) ; PR209.1 160.37,22.03 v4(160.3,21.97) 161.45,21.97 R10.1 ; LED4.2 v2(56.01,11.78) ; PR3.1 v2(143.79,174.5) ; RD46.1 v2(58.82,14.64)
  IN1 w0.508: v2(143.79,174.5) 145.39,176.1 146.21,176.1 146.84,176.73 146.84,178.2 151.92,183.28 160.28,183.28 163.13,180.44 170.06,180.44 173.76,176.73 173.76,176.1 175.16,174.7 175.16,173.06 v4(174.77,172.67) 174.77,171.21 175.42,170.56 175.42,168.3 174.22,167.1 174.22,165 169.68,160.45 v4(169.68,154.66)
  IN2 w0.508: v4(133,10.01) 160.15,10.01 161.78,11.63 161.78,20.5 v4(160.3,21.97)
  BOTTOM w0.203: U11.4 v2(106.33,29.03)
  BOTTOM w0.508: v4(58.3,88.92) 59.03,89.66 59.03,92.99 60.48,94.44 60.48,97.99 59.34,99.13 v2(59.34,102.94) 60.1,103.71 62.39,103.71 62.9,104.22 64.16,104.22 64.52,103.86 R1061.2 ; PR524.1 168.33,129.31 168.63,129.61 v2(168.94,129.61) ; PR203.1 160.87,21.74 160.65,21.97 v4(160.3,21.97) ; PC715.1 174.36,172.26 v4(174.77,172.67) ; v4(133,10.01) 121.62,10.01 121.44,10.18
  vias: v2(154.41,133.42) v2(155.05,133.4) v3(33.43,66.5) v3(37.95,49.41) v3(56.66,46.68) v4(30.84,69.19) v4(32.16,37.54) v4(32.62,68.35) v4(32.92,37.54) v4(33.18,40.46) v4(33.33,54.94) v4(33.33,54.18) v4(33.53,68.35) v4(33.68,37.54) v4(33.94,40.46) v4(34.09,54.94) v4(34.09,54.18) v4(34.06,49.6) v4(34.5,68.4) v4(34.7,40.46) v4(34.83,49.6) v4(35.49,68.4) v4(35.46,40.46) v4(35.59,49.6) v4(36.35,49.6) v4(57.36,88.92) v4(57.38,88.06) v4(57.38,87.22) v4(58.3,88.03) v4(58.3,87.2) v4(108.11,28.9) v4(108.11,28.14) v4(108.87,28.9) v4(108.87,28.14) v4(109.63,28.9) v4(109.63,28.14) v4(110.39,28.9) v4(110.39,28.14) v4(111.15,28.9) v4(111.15,28.14) v4(115.09,12.27) v4(115.14,11.43) v4(115.14,10.67) v4(115.88,12.29) v4(115.9,11.43) v4(115.9,10.67) v4(116.61,12.29) v4(116.67,11.43) v4(116.67,10.67) v4(117.33,12.27) v4(117.94,11.4) v4(117.94,10.64) v4(118.7,11.4) v4(118.7,10.64) v4(119.46,11.4) v4(119.46,10.64) v4(120.22,11.4) v4(120.22,10.64) v4(120.98,11.4) v4(120.98,10.64) v4(169.68,154.02) v4(169.68,153.39) v4(176.76,115.92) v4(176.76,115.16) v4(176.76,114.4) v4(176.76,113.64)
+5VALWP: length 27.2
  TOP w0.102: v4(128.4,19.24) v3(128.4,19.84)
  TOP w0.203: PU100.14 128.83,18.52 128.4,18.95 v4(128.4,19.24)
  TOP w0.508: PR101.2 v4(128.07,11.29)
  IN2 w0.508: v4(128.07,11.29) 127.54,11.82 127.54,12.88 127.08,13.33 122.28,13.33 119.92,15.7 v4(119.92,15.94) ; v4(128.4,19.24) 128.38,19.21 128.38,18.78 128.49,18.67 128.49,17.09 128.17,16.77 128.17,15.96 126.81,14.6 122.2,14.6 v4(120.42,16.38)
  BOTTOM w0.508: v4(128.07,11.29) PR101.2
+5VS: length 41.7
  TOP w0.508: RV54.1 51.34,25.09 v3(51.84,25.6) v2(51.84,26.24)
  BOTTOM w0.508: v2(219.82,120.09) 219.82,126.52 227.99,134.69 RE60.1
  vias: v2(16.77,111.48) v2(16.77,110.79) v2(17.48,111.45) v2(17.53,110.82) v2(24.46,92.94) v2(25.23,92.94) v2(37.93,11.5) v4(36.41,10.55) v4(37.05,10.55) v4(43.39,103.6) v4(43.39,102.84) v4(43.39,102.08) v4(44.15,103.6) v4(44.15,102.84) v4(44.15,102.08) v4(61.34,15.44) v4(62.19,15.41) v4(111.33,25.45) v4(111.33,24.69) v4(111.33,23.92) v4(112.09,25.45) v4(112.09,24.69) v4(112.09,23.92) v4(112.86,25.45) v4(112.86,24.69) v4(112.86,23.92) v4(211.28,108.58) v4(211.28,107.82) v4(211.28,107.06) v4(211.28,106.3) v4(217,58.57) v4(216.97,57.4) v4(216.97,56.31) v4(217,55.07) v4(217.86,102.87) v4(217.91,101.47) v4(218.06,58.6) v4(218.06,57.43) v4(218.09,56.34) v4(218.14,55.07) v4(218.88,102.79) v4(218.93,101.42)
+5VS_ODD:
  vias: v1(217.76,113.51) v4(217.91,114.65) v4(218.62,114.68) v4(220.78,113.05) v4(221.47,113.08)
+5VS_ODD_R1:
  vias: v3(221.66,112.19)
+5VS_ODD_R2: length 4
  TOP w0.102: v3(212.78,113.32) 214.84,113.32 215.88,112.28 UI7.1
+5VS_OUT: length 2.1
  BOTTOM w0.102: 108.87,23.92 v1(108.87,21.87)
+5VS_TOUCH: length 1
  TOP w0.508: RX24.1 v2(20.73,93.09)
  vias: v3(24.53,95.13) v4(23.7,95.76) v4(24.46,95.76) v4(25.23,95.76)
+AVCC33: length 2
  TOP w0.508: CT2.1 206.02,160.09 v2(205.77,159.84)
  BOTTOM w0.254: UT2.3 206.21,160.28 v2(205.77,159.84)
  vias: v1(205.06,155.29) v4(204.02,152.78) v4(204.75,152.78) v4(205.57,152.75)
+DVCC33: length 3.2
  BOTTOM w0.254: 203.74,166.7 204.21,166.23 UT2.18
  BOTTOM w0.508: RT2.2 RT20.2 v2(212.73,155.24)
  vias: v1(202.51,167.09) v4(200.28,166.9) v4(201.07,166.9) v4(201.88,166.93) v4(211.94,161.29) v4(211.92,160.6)
+V18R: length 3.1
  TOP w0.102: v1(177.22,51.32) 177.3,51.39 178.32,51.39 179.06,52.13 CE16.1
+VCC_3IN1: length 2.6
  BOTTOM w0.508: JREAD.4 v2(189.2,31.21) ; JREAD.11 v2(182.35,31.21)
  vias: v1(182.93,30.73) v2(178.54,20.42) v2(179.15,20.42) v4(184.26,31.8) v4(184.26,31.16)
B+_3/5V: length 11.3
  TOP w0.508: v4(128.81,21.66) PR111.1
  IN2 w0.508: v4(130.43,26.03) 131.32,25.14 131.32,22.53 130.46,21.66 v4(128.81,21.66)
  BOTTOM w0.406: v4(127.38,26.03) 127.38,25.4 127.03,25.04 PC109.1
  BOTTOM w0.508: PC110.1 130.97,25.55 130.92,25.55 v4(130.43,26.03)
  vias: v1(129.35,28.62) v4(127.31,29.16) v4(128.07,29.16) v4(128.15,26.03) v4(128.83,29.16) v4(128.91,26.03) v4(129.59,29.16) v4(129.67,26.03) v4(130.58,29.16) v4(130.58,28.4) v4(130.58,27.63)
GND: length 1764.7
  TOP w0.102: v4(94.95,33.02) v3(94.95,33.7) ; v2(220.12,62.84) v3(220.12,63.5) ; v2(173.21,63.27) 173.21,63.96 v3(172.94,64.22) ; v2(179.23,110.11) v3(179.23,109.47) ; v4(110.39,19.23) v3(110.39,19.91) ; v3(154.7,110.59) v4(154.05,110.59) ; v3(180.67,15.81) 180.14,16.34 v2(180.14,16.41) ; v2(177.04,31.24) v3(177.04,31.87) ; v2(58.25,53.77) v3(59.19,53.77) ; v4(27.54,32.87) v3(27.54,31.96) ; v4(32.59,71.91) v3(32.59,72.63) ; v2(177.09,71.18) v3(177.09,72.07) ; v2(146.36,184.1) v3(146.36,183.44) ; v2(35.97,89.84) v3(35.97,90.54) ; v4(110.95,32.54) v3(110.95,33.18) ; v2(35.16,47.9) v3(35.16,47.2) ; v4(168.98,111.77) v3(168.98,111.06) ; v4(160.85,14.86) v3(161.55,14.86)
  TOP w0.203: UG1.4 v2(66.7,36.78) ; UE1.35 v2(195.93,53.6) ; v2(44.29,25.35) 44.21,25.27 UA1.4 ; UG1.13 66.3,40.34 v2(66.58,40.61) ; v2(68.18,36.73) 67.9,37 UG1.7 ; v2(180.11,59.51) 180.11,59.27 180.58,58.8 UE1.113
  TOP w0.254: PU700.14 173.64,173.79 173.79,173.94 v2(173.79,174.34) ; v2(171.76,173.15) 172.12,172.79 PU700.12 ; v2(186.75,49.64) 187.19,50.07 UE1.11 ; 56.41,103.07 55.53,103.07 v2(55.4,102.94) ; UE1.94 183.99,68.08 v2(184.31,68.4) ; UE1.24 v2(192.39,52.5)
  TOP w0.305: JDB1.25 v2(67.88,74.06) ; U64.2 99.23,141.49 v2(98.8,141.06) ; JTP.4 v2(69.35,111.5) ; RC67.2 101.36,97.42 UC4.3 ; JDB1.9 59.88,74.24 60.01,74.12 v2(60.46,74.12) ; JDB1.3 v2(56.88,74.17) 58.08,74.17 58.38,74.47 JDB1.6 ; C1060.1 101.12,116.14 101.12,116.76 v2(101.45,117.09) ; v2(98.45,114.81) 98.64,114.99 RC42.1 ; JDB1.19 v2(64.88,74.13)
  TOP w0.356: PR26.2 131.47,184.6 131.35,184.48 PQ4.4 ; PQ709.1 137.81,160.92 v2(137.24,161.49) ; UE2.3 177.08,63.46 v2(177.45,63.83) ; CC43.2 115.98,114.12 v2(115.98,114.37) 115.98,114.52 C1061.1 115.25,115.26 CC42.2 ; PC708.2 139.4,165.07 139.64,165.32 PQ710.1 ; PQ3.4 133.73,172.04 133.96,171.8 v2(133.96,171.4) ; v2(137.62,163.57) 138.46,163.57 139.11,162.92 PQ709.4 ; PQ713.1 v2(135.5,160.5) ; PC9.2 129.2,182.62 129.82,182.62 130.05,182.4 PQ4.1 ; v2(113.22,114.89) 113.22,114.89 113.22,114.83 CC44.2 112.44,114.75 112.4,114.75 PC934.1 ; v2(87.51,86.28) 88.5,86.28 89.09,85.69 UC7.3 ; PQ710.4 142.65,164.02 v2(143.13,163.53) ; PQ713.4 v2(134.2,156.65) ; v2(109.43,111.91) 109.3,111.78 109.3,110.88 C1038.2 109.15,110.46 109.15,109.87 CC39.2
  TOP w0.381: U57.3 73.55,87.44 v2(73.32,87.21) ; U61.3 77.96,86.98 v2(78.29,87.31) ; U54.3 80.28,87.25 v2(80.34,87.18) ; v2(80.31,90.31) 80.37,90.37 U62.3 ; v2(99.53,138.82) 99.74,139.03 U66.3 ; v2(84.15,89.49) 83.98,89.49 82.85,90.62 U63.3 ; v2(78.43,89.77) 77.89,90.31 U65.3
  TOP w0.406: UI3.1 v2(30.86,68.19) ; v2(62.36,81.38) 62.02,81.04 UC5.3 ; RC41.1 96.64,113.97 v2(97.21,113.4) 97.21,113.39 RP66.1 RP66.2 ; v2(111.62,108.82) 111.73,108.71 112.61,108.71 C1055.2 113.41,109.51 ; CC1.2 v2(117.94,112.98) ; UC10.3 104.82,136.07 104.54,136.35 v2(104.25,136.35) ; CC29.1 121.26,107.77 v2(120.94,107.45) ; v2(118.8,108.11) 119.26,108.57 RC5.1 RC3.1 RC4.1 RC1.1 RC2.1 ; v2(98.96,116.81) 98.96,117.25 98.9,117.3 RC45.1 ; v2(122.24,65.67) 121.64,65.67 CD10.2 ; v2(62.13,78.69) CC64.2 CC51.2 ; CD17.2 108.07,68.4 v2(108.41,68.06) ; v2(108.03,137.03) 107.55,136.55 107.55,135.61 R380.2 R379.2 ; v2(100.54,108.68) 100.82,108.96 CC13.2 ; RC57.2 106.32,124.53 v2(106.08,124.77) ; CC49.2 v2(64.16,78.74) ; RC48.2 112.42,135.33 111.61,134.52 v2(111.61,134.39) ; v2(131.04,174.01) 131.04,173.58 131.29,173.34 PQ3.1 ; RC26.2 93.04,112.39 v2(93.12,112.47) 93.2,112.39 CC14.2 ; C1045.2 103.21,114.08 v2(102.57,114.71)
  TOP w0.508: CA25.1 45.49,14.74 v4(45.75,14.49) ; v2(86.36,71.65) 85.76,71.65 84.99,70.89 C1076.2 CD1.2 CD2.2 ; CC50.2 v2(54,78.84) ; v2(112.1,146.71) 111.73,147.08 CM48.1 ; C1126.1 v2(52.99,104.34) ; v2(32.79,83.13) CL41.1 ; RD7.1 RD6.1 143.44,68.12 v2(143.35,68.03) ; CE33.2 v2(177.57,50.87) ; SW1.1 v2(195.74,27.43) ; CD8.2 119.38,58.45 v4(119.05,58.12) ; PH501.1 142.19,139.82 v2(142.65,139.37) ; v2(45.56,30.27) CA22.2 ; PC8.2 v2(130.26,173.88) ; C1123.1 v2(52.86,102.31) ; v2(106.5,149.53) 105.69,148.73 CM47.2 ; CE20.2 v2(195.55,32.52) ; v2(68.23,78.71) CC63.2 CC65.2 ; CD31.2 CD30.2 143.92,73.16 v2(143.77,73.31) ; CM46.1 117.38,147.32 v2(117.38,146.76) ; CR5.2 v2(180.88,22.6) ; PR5.1 v2(139.7,178.61) ; CC61.2 v2(67.21,78.74) ; v2(52.23,24.33) 52.23,23.32 51.65,22.74 CA54.2 ; CE11.2 v2(201.7,53.8) ; RD50.2 v2(71.66,16.53) ; UD1.3 59.73,20.54 59.97,20.78 v2(59.97,21.16) ; PR729.1 173.13,165.94 v2(173.26,166.06) PR728.1 ; v2(213.47,174.5) RX20.2 RX23.2 ; v4(126.42,12.04) 126.01,12.04 125.96,12.09 PR116.2 ; CD29.2 v2(149.62,63.05) ; PR21.2 v2(129.34,173.86) ; SW1.6 v2(198.01,31.81) ; DE3.1 v2(67.59,112.75) ; CC52.2 v2(55.02,78.92) ; v2(112.07,110.52) 112.19,110.64 CC41.2 ; CD21.2 v4(122.69,59.83) ; PC904.2 117.87,85.77 v2(117.33,85.77) ; v4(133,22.17) 132.43,21.6 PC114.2 ; CD6.2 108.97,64.15 v2(109.53,64.15) ; JTOUCH.7 v2(25.01,100.24) ; RR1.2 175.59,17.17 v2(175.99,17.56) ; v4(47.4,14.49) CA58.2 ; v2(22.79,92.1) 23.65,91.23 CL33.2 22.75,91.2 v2(21.95,92) ; CD4.2 v4(111.31,59.17) ; v2(55.65,79.37) 56.04,78.99 CC55.2 ; CG6.2 v2(65.94,43.89) ; PQ2.3 v2(139.1,176.69) ; v2(115.3,72.16) 115.8,72.16 CD19.2 ; PR19.1 v2(132.89,175.25) ; v2(35.59,10.62) 35.59,11.06 RA32.2 34.95,11.19 v2(34.95,10.62) ; CA21.2 v2(44.22,30.17) ; CG4.2 v2(62.92,42.7) ; RM11.1 115.09,147.67 114.61,147.19 v2(114.61,146.76) ; CC24.1 81.46,76.76 v2(80.39,76.76) ; PR104.1 v2(131.3,11.35) ; JTOUCH.4 v2(21.31,97.81) ; v2(149.13,62.05) 148.86,61.78 CD27.2 ; PR26.2 v2(132.36,185.11) ; CE6.1 v2(185.7,47.03) ; v2(107.5,85.04) 107,85.04 PC908.2 ; Q2308.3 68.02,32.21 v2(68.76,32.94) ; CE28.2 v2(188.12,44.91) ; JTP.7 74,108.02 v2(73.38,108.63) ; CA69.2 v2(39.26,29.42) ; C1145.1 v2(61.6,100.28) ; v2(59.33,78.8) 59.33,78.24 CC62.2 CC60.2 ; C1119.2 v2(57.88,55.87) ; CE12.2 v2(186.03,45.59) ; v4(168.64,131.44) 168.63,131.44 168.28,131.1 PC523.2 ; v2(140.14,161.64) 140.48,161.98 PQ712.3 ; v2(117.33,82.7) 117.9,82.7 PC902.2 ; CC19.2 v2(86.06,84.96) ; Q8.3 v2(164.62,23.65) ; v2(192.99,68.93) 193.4,69.34 CE8.2 RE5.1 ; CR10.2 v2(182.55,22.69) ; CG2.2 v2(65.54,34.67) ; 116.45,113.67 CC28.2 116.83,114.55 116.83,114.6 v2(116.52,114.92) ; v2(26.38,10.55) RA30.2 v2(24.6,10.55) ; C1118.2 v2(58.25,53.77) ; v2(96.68,118.63) 96.63,118.68 C1034.1 ; CD18.2 v4(117.61,58.2) ; R1030.1 v4(123.7,56.93) ; CE2.2 191.72,47.29 v2(191.6,47.17) RA19.2 ; CR11.2 v2(174.18,27.9) ; CE34.2 v2(174.27,56.21) ; v2(116.65,63.77) 116.65,63.76 CD5.2 ; PC1.2 v2(140.73,171.39) ; v2(61.75,103.07) 61.5,103.33 C1128.1 ; JKB.31 v2(223.07,133.02) ; v2(80.31,90.31) 80.31,89.28 R1024.2 ; QC1.3 v2(127.81,124.42) ; C182.2 76.75,94.1 v2(76.38,94.47) ; v2(103.72,120.31) RC23.1 ; C1120.2 v2(56.48,49.34) ; C1127.1 v2(52.99,103.33) ; v2(171.71,22.22) 171.76,22.17 CR4.1 ; C1122.1 53.17,49.71 v2(53.17,49.2) ; JSPK.6 v2(71.89,20.6) ; CR2.2 v2(179.06,15.71) ; SW1.5 v2(197.96,26.76) ; v4(48.1,15.44) 48.48,15.06 CA57.2 ; CD63.2 v2(55.71,20.09) ; RA81.1 v2(39.3,26.67) ; CE1.2 v2(201.73,52.14) ; RE47.1 178.64,63.78 v2(178.97,63.45) ; CC57.2 CC54.2 60.05,78.05 v2(60.05,78.8) ; RE1.1 v2(174.15,57.22) ; C1121.2 v2(55.02,61.29) ; CE18.1 v2(177.32,60.15) ; CD28.2 v2(148.53,66.52) ; v2(121.01,71.03) 121.1,70.94 121.1,70.42 CD20.2 ; UI7.2 v2(215.55,113.23) ; CE30.2 179.28,59.08 v2(179.61,58.75) ; v4(219.45,174.5) 220.14,173.81 RX26.2 RX9.2 ; CE35.2 v2(174.4,53.16) ; v2(67.11,22.98) 66.75,22.63 CA31.2 66.09,22.98 CA30.2 ; CD9.2 112.7,67.05 v2(113.25,67.05) ; PC906.2 111.9,84.96 v2(112.35,84.96) ; Q2307.3 v2(159.06,35.35) ; CA32.2 v2(67.47,19.43) ; CC56.2 v2(65.18,78.71) ; CI13.2 v2(28.65,72.44) ; v2(162.33,124.66) 162.67,124.33 PC534.2 ; PC727.2 v2(175.11,165.25) ; PC725.1 174.63,169.19 v2(174.43,169.39) ; CD25.2 v2(148.99,68.64) ; Q50.3 v2(177.09,71.18) ; CR1.2 v2(177.98,16.41) ; LE2.1 195.99,71.7 v2(195.61,72.08) ; C1035.1 95.18,115.48 v2(94.62,116.03) ; C1117.2 v2(58.27,52.75) ; RC67.2 101.93,98.36 v2(102.71,99.13) ; QX1.3 v2(213.66,175.83) ; CE27.2 v2(184.18,47.06) ; v2(138.05,164.92) 138.2,165.07 PC708.2 ; CR9.2 179.23,28.04 v2(178.87,27.68) ; UI1.2 v2(27.51,64.84) ; PC726.2 v2(175.35,178.39) ; v2(116.65,66.05) 117,66.4 CD11.2 ; R1033.2 74.01,90.13 v2(73.57,89.7) ; v2(51.97,20.78) 51.97,20.37 51.55,19.95 CA55.2 ; SW1.2 v2(200.03,27.43) ; CE19.2 v2(176,67.33) ; CR3.1 v2(180.14,16.41) ; CE29.2 v2(193.96,47.19) ; CA56.2 51.13,20.98 v2(51.34,20.78) ; JKB.32 v2(223.07,163.49) ; v2(217.91,175.16) 217.78,175.03 CX1.2 ; PC9.2 v2(128.16,182.36) ; v2(57.38,78.69) 57.05,78.36 CC58.2 ; CD13.2 112.14,71.01 v2(112.16,71.02) ; CG5.2 v2(68.74,44.42) ; CD12.2 v4(115.05,58.92) ; v2(102.88,118.4) 102.95,118.47 103.69,118.47 C1039.1 ; v2(107.57,64.15) 107.56,64.13 CD14.2 ; v2(51.41,24.28) 50.96,23.82 CA53.2 ; C1125.1 v2(61.73,102.31) ; PR716.2 v2(176.69,173.43) ; RS9.2 v2(217.28,115.06) ; v2(62.44,84.61) 62.94,84.1 CC11.2 ; C1078.2 v4(122.69,56.93) ; CI15.2 v2(26.01,72.46) ; CC21.2 84.26,82.62 v2(84.43,82.8) ; C1040.2 112.61,113.28 v2(112.14,113.76) ; CA29.2 v2(66.37,26.18) ; CG1.2 v2(67.21,43.58) ; v2(176.53,27.28) 176.7,27.11 CR6.2 ; v2(42.65,97.28) 42.65,96.87 42.35,96.57 JPWR.4 ; CR8.2 v2(185.32,33.45) ; v2(17.17,99.52) 17.74,99.52 JTOUCH.8 ; PC2.2 v2(140.7,170.42) ; PC512.2 163.41,139.38 163.41,139.96 v2(163.26,140.12) ; JDB1.28 v2(68.81,73.03) ; CS13.2 v2(215.6,106.5) ; QD20.3 v2(71.91,17.55) ; CG7.2 v2(69.24,36.35) ; DE1.1 v2(173.76,54.68) ; v2(74.49,78.57) 74.35,78.43 UC8.4 ; RE18.2 v2(195.48,47.06) ; v2(65.48,106.95) JTP.8 v2(62.01,106.95) ; R1048.2 v2(47.53,52.65) ; PC105.2 v4(129.21,12.18) ; PQ711.3 v2(171.34,163.78) ; CR7.2 v2(186.46,33.45) ; PC723.2 v2(175.95,166.88) ; v2(85.75,65.77) 85.54,65.77 84.99,66.32 R1028.1 ; CD26.2 v2(149.18,60.77) ; RC50.1 v2(114.58,136.42) ; R16.2 v4(167.54,24) ; CC31.1 v2(125.84,112.63) ; CM40.2 v2(91.82,147.17) ; CD3.2 91.57,62.8 90.96,63.41 v2(90.86,63.41) ; v2(113.81,62.62) 113.85,62.59 CD7.2 ; CG3.2 v2(68.96,37.72) ; CG10.2 v2(64.09,34.67) ; CE15.2 v2(173.21,63.27) ; CC53.2 v2(64.16,81.95) ; CE26.2 v2(183.54,71.04) ; CD24.2 v2(148.89,69.66) ; CA59.2 v2(49.24,28.33) ; RD52.2 v2(55.2,12.95) ; CE5.1 v2(182.53,71.05) ; JTOUCH.5 v2(20.51,97.79) ; CD16.2 v4(120.78,58.07) ; v2(127.12,11.34) 127.13,11.35 PR105.2 ; PC4.2 v2(129.41,163.38) ; CC59.2 v2(66.2,78.74) ; C1146.1 v2(61.67,105.36) ; CE16.2 v2(177.36,51.85) ; CD22.2 v4(123.7,59.7) ; C1073.2 v2(123.68,125.17) ; CM43.2 v2(114.08,149.45) ; JSPK.5 v2(71.95,26.2) ; PC3.2 v2(130.35,163.39) ; CA60.2 v2(47.15,28.78) ; JDB1.27 v2(55.35,73.03) ; PQ708.3 v2(137.02,155.9) ; v2(43.15,28.84) CA64.1 ; CE36.2 v2(188.12,47.19)
  VCC w0.203: H34.1 143.49,129.05 ; H34.1 142.87,127.38 ; H34.1 139.53,127.38 ; H34.1 141.2,126.76 ; H34.1 141.2,131.34 ; H34.1 142.87,130.72 ; H34.1 138.91,129.05 ; H34.1 139.53,130.72 ; H16.1 21.9,6.73 ; H16.1 20.56,6.24 ; H16.1 23.24,3.56 ; H16.1 20.56,3.56 ; H16.1 23.73,4.9 ; H16.1 20.07,4.9 ; H16.1 23.24,6.24 ; H16.1 21.9,3.07 ; JUSB7.8 2.87,37.03 2.87,37.03 ; JUSB7.8 4.1,36.49 ; JUSB7.8 3.49,36.89 ; JUSB7.8 2.88,36.1 3.79,37.01 ; JUSB7.8 2.24,36.73 2.24,37.03 ; JUSB7.8 4.1,36.89 ; JUSB8.6 11.91,51.52 ; JUSB8.6 11.91,53.28 ; JUSB8.6 10.32,53.28 ; JUSB8.6 10.32,51.52 ; JUSB8.6 11.91,52.4 ; 17.86,73.24 H17.1 ; H17.1 17.37,71.9 ; H17.1 19.2,73.73 ; H17.1 20.54,70.56 ; H17.1 17.86,70.56 ; H17.1 20.54,73.24 ; H17.1 19.2,70.07 ; H17.1 21.03,71.9 ; JUSB8.8 2.87,54.49 ; JUSB8.8 4.1,54.49 ; JUSB8.8 1.64,54.49 ; 87.27,158.32 JMINI.54 ; JMINI.54 87.27,156.76 ; JMINI.54 88.22,156.76 ; 2.87,38.14 2.24,37.51 ; 2.87,38.14 JUSB8.7 ; 2.87,38.14 2.87,37.36 2.85,37.34 ; 104.26,149.76 JMINI.21 ; JMINI.21 104.74,149.76 ; JMINI.21 104.5,149.76 ; JHDMI.23 2.7,113.73 ; JHDMI.23 4.28,113.73 ; JHDMI.23 4.28,112.7 ; PBATT1.10 159.57,186.87 ; PBATT1.10 159.57,188.7 ; PBATT1.10 157.72,186.87 ; PBATT1.10 157.72,188.7 ; PBATT1.10 158.64,186.87 ; JHDD.23 227.95,36.25 ; JHDD.23 227.95,34.14 ; JHDD.23 226.2,34.14 ; JHDD.23 226.2,36.25 ; JHDD.23 226.2,35.2 ; JUSB7.6 11.91,33.92 ; JUSB7.6 11.91,34.8 ; JUSB7.6 11.91,35.68 ; JUSB7.6 10.32,35.68 ; JUSB7.6 10.32,33.92 ; H7.1 19.2,40.18 ; H7.1 21.28,38.1 ; H7.1 20.72,39.62 ; H7.1 17.68,39.62 ; H7.1 19.2,36.02 ; H7.1 20.72,36.58 ; H7.1 17.68,36.58 ; H7.1 17.12,38.1 ; JMINI.29 107.94,149.76 ; JMINI.29 107.46,149.76 ; JMINI.29 107.7,149.76 ; JHDD.7 227.78,45.58 ; JHDD.7 227.94,45.01 ; JHDD.7 226.66,45.58 ; JHDD.7 227.78,44.45 ; JHDD.7 227.22,45.74 ; JHDD.7 226.5,45.01 ; JHDD.7 226.66,44.45 ; 226.66,41.77 JHDD.4 ; JHDD.4 227.78,40.64 ; JHDD.4 226.5,41.2 ; JHDD.4 226.66,40.64 ; JHDD.4 227.94,41.2 ; JHDD.4 227.78,41.77 ; JUSB8.7 2.95,38.3 3.71,37.54 ; JUSB8.7 2.25,37.51 ; JUSB8.7 4.1,37.51 ; JUSB8.7 4.1,37.91 ; JHDMI.21 11.38,94.6 ; JHDMI.21 9.8,95.63 ; JHDMI.21 11.38,95.63 ; JHDMI.21 11.38,93.57 ; JHDMI.21 8.23,94.6 ; JHDMI.21 9.8,93.57 ; JHDMI.21 8.23,93.57 ; 9.8,111.67 JHDMI.22 ; JHDMI.22 8.23,113.73 ; JHDMI.22 8.23,112.7 ; JHDMI.22 11.38,112.7 ; JHDMI.22 11.38,111.67 ; JHDMI.22 11.38,113.73 ; JHDMI.22 9.8,113.73 ; H8.1 166.03,185.4 ; H8.1 162.86,186.74 ; H8.1 165.54,184.06 ; H8.1 165.54,186.74 ; H8.1 162.37,185.4 ; H8.1 164.2,187.23 ; H8.1 164.2,183.57 ; H8.1 162.86,184.06 ; JHDMI.8 10.21,102.65 ; JHDMI.8 9.05,102.65 ; JHDMI.8 9.17,103.11 ; JHDMI.8 10.09,103.11 ; JHDMI.8 9.17,102.19 ; JHDMI.8 10.09,102.19 ; 139.53,101.99 H32.1 ; H32.1 141.2,105.95 ; H32.1 142.87,101.99 ; H32.1 141.2,101.37 ; H32.1 138.91,103.66 ; H32.1 142.87,105.33 ; H32.1 143.49,103.66 ; H32.1 139.53,105.33 ; H9.1 129.43,154.8 ; H9.1 128.94,153.46 ; H9.1 126.26,153.46 ; H9.1 125.77,154.8 ; H9.1 126.26,156.14 ; H9.1 128.94,156.14 ; H9.1 127.6,156.63 ; H9.1 127.6,152.97 ; JUSB1.7 4.1,55.11 ; JUSB1.7 1.64,55.11 ; JUSB1.7 2.87,55.11 ; 109.86,149.76 JMINI.35 ; JMINI.35 110.34,149.76 ; JMINI.35 110.1,149.76 ; JHDMI.11 8.54,104.61 ; JHDMI.11 8.54,103.69 ; JHDMI.11 8.66,104.15 ; 10.32,24.01 JUSB7.4 ; JUSB7.4 9.64,25.58 ; JUSB7.4 9.43,24.9 ; JUSB7.4 11.21,24.9 ; JUSB7.4 10.32,25.79 ; JUSB7.4 11,24.22 ; JUSB7.4 11,25.58 ; JUSB7.4 9.64,24.22 ; JMINI.15 99.38,149.76 ; JMINI.15 99.38,150.67 ; JMINI.15 98.9,149.76 ; JMINI.27 107.14,149.76 ; JMINI.27 106.66,149.76 ; JMINI.27 106.9,149.76 ; 223.86,3.56 H4.1 ; H4.1 223.86,6.24 ; H4.1 225.2,6.73 ; H4.1 223.37,4.9 ; H4.1 227.03,4.9 ; H4.1 225.2,3.07 ; H4.1 226.54,6.24 ; H4.1 226.54,3.56 ; 197.35,7.76 JREAD.23 ; JREAD.23 198.08,7.76 ; JREAD.23 198.08,4.83 ; JREAD.23 197.35,4.83 ; JREAD.23 198.8,6.3 ; JREAD.23 198.8,7.76 ; JREAD.23 198.8,4.83 ; JREAD.23 197.35,6.3 ; 9.64,60.78 JUSB1.4 ; JUSB1.4 11.21,60.1 ; JUSB1.4 11,59.42 ; JUSB1.4 9.64,59.42 ; JUSB1.4 10.32,60.99 ; JUSB1.4 11,60.78 ; JUSB1.4 10.32,59.21 ; JUSB1.4 9.43,60.1 ; 10.32,41.61 JUSB8.4 ; JUSB8.4 9.64,41.82 ; JUSB8.4 9.43,42.5 ; JUSB8.4 11,41.82 ; JUSB8.4 9.64,43.18 ; JUSB8.4 11.21,42.5 ; JUSB8.4 11,43.18 ; JUSB8.4 10.32,43.39 ; JHDMI.20 4.28,93.57 ; JHDMI.20 2.7,93.57 ; JHDMI.20 4.28,94.6 ; JREAD.24 169.5,4.83 ; JREAD.24 169.5,7.76 ; JREAD.24 168.05,6.3 ; JREAD.24 168.05,7.76 ; JREAD.24 168.78,7.76 ; JREAD.24 168.05,4.83 ; JREAD.24 169.5,6.3 ; JREAD.24 168.78,4.83 ; H5.1 226.54,169.74 ; H5.1 226.54,167.06 ; H5.1 223.37,168.4 ; H5.1 223.86,169.74 ; H5.1 227.03,168.4 ; H5.1 225.2,170.23 ; H5.1 223.86,167.06 ; H5.1 225.2,166.57 ; 226.66,37.96 JHDD.1 ; JHDD.1 227.22,36.67 ; JHDD.1 226.66,36.83 ; JHDD.1 226.5,37.39 ; JHDD.1 227.78,36.83 ; JHDD.1 227.94,37.39 ; JHDD.1 227.78,37.96 ; 96.5,149.76 JMINI.9 ; JMINI.9 96.74,149.76 ; JMINI.9 96.26,149.76 ; 136.39,186.87 PBATT1.11 ; PBATT1.11 135.47,186.87 ; PBATT1.11 137.32,188.7 ; PBATT1.11 135.47,188.7 ; PBATT1.11 137.32,186.87 ; JUSB1.6 11.91,70 ; JUSB1.6 11.91,70.88 ; JUSB1.6 11.91,69.12 ; JUSB1.6 10.32,69.12 ; JUSB1.6 10.32,70.88 ; JHDMI.2 10.21,99.65 ; JHDMI.2 10.09,99.19 ; JHDMI.2 9.63,99.07 ; JHDMI.2 10.09,100.11 ; JHDMI.2 9.17,99.19 ; JHDMI.2 9.05,99.65 ; JHDMI.2 9.17,100.11 ; 2.12,72.34 JLAN.9 ; JLAN.9 4.75,72.34 ; JLAN.9 3,72.34 ; JLAN.10 3.88,93.25 ; JLAN.10 3,93.25 ; JLAN.10 4.75,93.25 ; JHDMI.5 8.66,101.15 ; JHDMI.5 8.54,100.69 ; JHDMI.5 8.54,101.61 ; JUSB7.5 11.91,22.88 ; JUSB7.5 11.91,22 ; JUSB7.5 10.32,22.88 ; JUSB7.5 10.32,21.12 ; JUSB7.5 11.91,21.12 ; JMINI.53 122.93,156.76 ; JMINI.53 122.93,158.32 ; JMINI.53 121.97,156.76 ; JUSB8.5 11.91,38.72 ; JUSB8.5 10.32,40.48 ; JUSB8.5 10.32,38.72 ; JUSB8.5 11.91,39.6 ; JUSB8.5 11.91,40.48 ; JUSB1.8 3.49,72.09 ; JUSB1.8 2.87,72.09 ; JUSB1.8 4.1,72.09 ; JUSB1.5 11.91,56.32 ; JUSB1.5 11.91,57.2 ; JUSB1.5 10.32,56.32 ; JUSB1.5 11.91,58.08 ; JUSB1.5 10.32,58.08 ; JHDMI.17 8.66,107.15 ; JHDMI.17 8.54,106.69 ; JHDMI.17 8.54,107.61
  VCC w0.508: 4.58,72.06 3.82,71.3 JUSB1.8 ; JLAN.9 4.78,73.4 5.08,73.1
  GND w0.203: JUSB8.8 4.1,54.49 ; JUSB8.8 4.1,53.7 ; JUSB8.8 1.64,53.7 ; JUSB8.8 1.64,54.49 ; JUSB8.8 2.87,54.49 ; 139.53,105.33 H32.1 ; H32.1 143.49,103.66 ; H32.1 141.2,105.95 ; H32.1 142.87,105.33 ; H32.1 141.2,101.37 ; H32.1 142.87,101.99 ; H32.1 138.91,103.66 ; H32.1 139.53,101.99 ; 1.12,93.57 JHDMI.20 ; JHDMI.20 4.28,93.57 ; JHDMI.20 1.12,94.6 ; JHDMI.20 4.28,94.6 ; JHDMI.20 2.7,93.57 ; 1.25,72.34 JLAN.9 ; JLAN.9 4.75,73.4 ; JLAN.9 3,72.34 ; JLAN.9 4.75,72.34 ; JLAN.9 1.25,73.4 ; 202.58,95.92 H18.1 ; H18.1 205.62,92.88 ; H18.1 204.1,92.32 ; H18.1 205.62,95.92 ; H18.1 202.58,92.88 ; H18.1 204.1,96.48 ; H18.1 206.18,94.4 ; H18.1 202.02,94.4 ; JHDD.17 227.94,62.79 ; JHDD.17 226.66,62.23 ; JHDD.17 227.78,62.23 ; JHDD.17 227.78,63.36 ; JHDD.17 226.66,63.36 ; JHDD.17 226.5,62.79 ; JUSB8.4 10.32,43.39 ; JUSB8.4 10.32,41.61 ; JUSB8.4 9.43,42.5 ; JUSB8.4 11,41.82 ; JUSB8.4 11.21,42.5 ; JUSB8.4 11,43.18 ; JUSB8.4 9.64,43.18 ; JUSB8.4 9.64,41.82 ; H17.1 20.54,70.56 ; H17.1 19.2,73.73 ; H17.1 17.86,70.56 ; H17.1 21.03,71.9 ; H17.1 17.37,71.9 ; H17.1 19.2,70.07 ; H17.1 17.86,73.24 ; H17.1 20.54,73.24 ; 9.17,103.11 JHDMI.8 ; JHDMI.8 9.17,102.19 ; JHDMI.8 9.05,102.65 ; JHDMI.8 10.09,103.11 ; JHDMI.8 10.09,102.19 ; JHDMI.8 10.21,102.65 ; 9.05,99.65 JHDMI.2 ; JHDMI.2 9.63,99.07 ; JHDMI.2 9.17,100.11 ; JHDMI.2 10.09,99.19 ; JHDMI.2 10.21,99.65 ; JHDMI.2 10.09,100.11 ; JHDMI.2 9.17,99.19 ; 151.78,142.98 H10.1 ; H10.1 151.22,144.5 ; H10.1 153.3,146.58 ; H10.1 155.38,144.5 ; H10.1 154.82,142.98 ; H10.1 154.82,146.02 ; H10.1 151.78,146.02 ; H10.1 153.3,142.42 ; 98.9,149.76 JMINI.15 ; JMINI.15 99.38,150.67 ; JMINI.15 98.9,151.59 ; JMINI.15 99.38,151.59 ; JMINI.15 99.38,149.76 ; 26.92,117.02 H6.1 ; H6.1 25.39,117.58 ; H6.1 28.44,117.58 ; H6.1 29,119.1 ; H6.1 25.39,120.63 ; H6.1 24.84,119.1 ; H6.1 28.44,120.63 ; H6.1 26.92,121.19 ; JHDMI.21 11.38,94.6 ; JHDMI.21 9.8,93.57 ; JHDMI.21 8.23,93.57 ; JHDMI.21 11.38,95.63 ; JHDMI.21 8.23,95.63 ; JHDMI.21 9.8,95.63 ; JHDMI.21 8.23,94.6 ; JHDMI.21 11.38,93.57 ; H12.1 31.2,111.23 ; H12.1 32.54,110.74 ; H12.1 33.03,109.4 ; H12.1 31.2,107.57 ; H12.1 29.37,109.4 ; H12.1 29.86,110.74 ; H12.1 32.54,108.06 ; H12.1 29.86,108.06 ; JLAN.10 4.75,92.2 ; JLAN.10 1.25,93.25 ; JLAN.10 4.75,93.25 ; JLAN.10 1.25,92.2 ; JLAN.10 3,93.25 ; 157.72,190.53 PBATT1.10 ; PBATT1.10 157.72,188.7 ; PBATT1.10 158.64,186.87 ; PBATT1.10 159.57,188.7 ; PBATT1.10 159.57,186.87 ; PBATT1.10 158.64,190.53 ; PBATT1.10 157.72,186.87 ; PBATT1.10 159.57,190.53 ; JHDD.12 227.78,55.88 ; JHDD.12 226.66,55.88 ; JHDD.12 227.78,57.01 ; JHDD.12 226.5,56.44 ; JHDD.12 227.94,56.44 ; JHDD.12 226.66,57.01 ; JMINI.54 89.18,158.32 ; JMINI.54 87.27,156.76 ; JMINI.54 88.22,156.76 ; JMINI.54 87.27,158.32 ; JMINI.54 89.18,156.76 ; 164.2,183.57 H8.1 ; H8.1 162.37,185.4 ; H8.1 162.86,184.06 ; H8.1 166.03,185.4 ; H8.1 165.54,186.74 ; H8.1 162.86,186.74 ; H8.1 165.54,184.06 ; H8.1 164.2,187.23 ; JUSB7.6 11.91,35.68 ; JUSB7.6 8.73,33.92 ; JUSB7.6 10.32,35.68 ; JUSB7.6 8.73,35.68 ; JUSB7.6 10.32,33.92 ; JUSB7.6 11.91,34.8 ; JUSB7.6 8.73,34.8 ; JUSB7.6 11.91,33.92 ; H16.1 23.24,3.56 ; H16.1 21.9,3.07 ; H16.1 20.56,6.24 ; H16.1 23.24,6.24 ; H16.1 23.73,4.9 ; H16.1 21.9,6.73 ; H16.1 20.07,4.9 ; H16.1 20.56,3.56 ; JODD.13 227.59,117.59 ; JODD.13 227.05,117.74 ; JODD.13 227.05,116.36 ; JODD.13 226.51,117.59 ; JODD.13 226.36,117.05 ; JODD.13 227.59,116.51 ; JODD.13 227.74,117.05 ; 227.95,34.14 JHDD.23 ; JHDD.23 226.2,34.14 ; JHDD.23 229.7,35.2 ; JHDD.23 227.95,36.25 ; JHDD.23 229.7,34.14 ; JHDD.23 229.7,36.25 ; JHDD.23 226.2,36.25 ; JHDD.23 226.2,35.2 ; JUSB7.5 11.91,22.88 ; JUSB7.5 11.91,21.12 ; JUSB7.5 8.73,22.88 ; JUSB7.5 8.73,21.12 ; JUSB7.5 10.32,21.12 ; JUSB7.5 8.73,22 ; JUSB7.5 10.32,22.88 ; JUSB7.5 11.91,22 ; 226.66,57.15 JHDD.13 ; JHDD.13 227.94,57.71 ; JHDD.13 227.78,58.28 ; JHDD.13 226.5,57.71 ; JHDD.13 226.66,58.28 ; JHDD.13 227.78,57.15 ; 223.86,3.56 H4.1 ; H4.1 227.03,4.9 ; H4.1 223.86,6.24 ; H4.1 223.37,4.9 ; H4.1 226.54,6.24 ; H4.1 225.2,3.07 ; H4.1 226.54,3.56 ; H4.1 225.2,6.73 ; JODD.7 227.6,105.29 ; JODD.7 227.05,106.55 ; JODD.7 226.5,105.29 ; JODD.7 227.76,105.84 ; JODD.7 227.6,106.39 ; JODD.7 226.5,106.39 ; JODD.7 226.34,105.84 ; 226.34,98.22 JODD.1 ; JODD.1 227.6,98.77 ; JODD.1 227.05,97.51 ; JODD.1 226.5,98.77 ; JODD.1 227.6,97.67 ; JODD.1 227.76,98.22 ; JODD.1 226.5,97.67 ; JHDD.24 229.7,71.34 ; JHDD.24 229.7,72.4 ; JHDD.24 226.2,71.34 ; JHDD.24 226.2,70.29 ; JHDD.24 226.2,72.4 ; JHDD.24 227.95,72.4 ; JHDD.24 229.7,70.29 ; JHDD.24 227.95,70.29 ; 226.5,41.2 JHDD.4 ; JHDD.4 227.78,40.64 ; JHDD.4 227.94,41.2 ; JHDD.4 227.78,41.77 ; JHDD.4 226.66,40.64 ; JHDD.4 226.66,41.77 ; JHDMI.23 4.28,112.7 ; JHDMI.23 2.7,113.73 ; JHDMI.23 1.12,113.73 ; JHDMI.23 4.28,113.73 ; JHDMI.23 1.12,112.7 ; JHDMI.22 11.38,111.67 ; JHDMI.22 9.8,111.67 ; JHDMI.22 8.23,113.73 ; JHDMI.22 8.23,112.7 ; JHDMI.22 9.8,113.73 ; JHDMI.22 8.23,111.67 ; JHDMI.22 11.38,113.73 ; JHDMI.22 11.38,112.7 ; PBATT1.11 137.32,188.7 ; PBATT1.11 135.47,186.87 ; PBATT1.11 136.39,186.87 ; PBATT1.11 136.39,190.53 ; PBATT1.11 137.32,186.87 ; PBATT1.11 135.47,188.7 ; PBATT1.11 137.32,190.53 ; PBATT1.11 135.47,190.53 ; JHDD.11 227.78,54.61 ; JHDD.11 226.66,54.61 ; JHDD.11 227.94,55.17 ; JHDD.11 226.5,55.17 ; JHDD.11 227.78,55.74 ; JHDD.11 226.66,55.74 ; 1.64,55.11 JUSB1.7 ; JUSB1.7 1.64,55.9 ; JUSB1.7 4.1,55.9 ; JUSB1.7 2.87,55.11 ; JUSB1.7 4.1,55.11 ; 126.26,153.46 H9.1 ; H9.1 128.94,156.14 ; H9.1 129.43,154.8 ; H9.1 128.94,153.46 ; H9.1 126.26,156.14 ; H9.1 125.77,154.8 ; H9.1 127.6,156.63 ; H9.1 127.6,152.97 ; PBATT1.1 140.23,187.99 ; PBATT1.1 138.81,187.99 ; PBATT1.1 140.45,188.7 ; PBATT1.1 140.23,189.41 ; PBATT1.1 138.59,188.7 ; PBATT1.1 139.52,187.77 ; PBATT1.1 138.81,189.41 ; PBATT1.1 139.52,189.63 ; JHDD.1 227.94,37.39 ; JHDD.1 226.66,36.83 ; JHDD.1 226.5,37.39 ; JHDD.1 226.66,37.96 ; JHDD.1 227.78,36.83 ; JHDD.1 227.22,36.67 ; JHDD.1 227.78,37.96 ; JHDD.19 227.78,65.9 ; JHDD.19 226.66,65.9 ; JHDD.19 226.66,64.77 ; JHDD.19 227.78,64.77 ; JHDD.19 226.5,65.33 ; JHDD.19 227.94,65.33 ; 107.37,13.4 H2.1 ; H2.1 107.86,14.74 ; H2.1 107.86,12.06 ; H2.1 111.03,13.4 ; H2.1 110.54,12.06 ; H2.1 109.2,15.23 ; H2.1 109.2,11.57 ; H2.1 110.54,14.74 ; 8.73,53.28 JUSB8.6 ; JUSB8.6 11.91,53.28 ; JUSB8.6 8.73,51.52 ; JUSB8.6 10.32,51.52 ; JUSB8.6 8.73,52.4 ; JUSB8.6 10.32,53.28 ; JUSB8.6 11.91,52.4 ; JUSB8.6 11.91,51.52 ; 106.66,149.76 JMINI.27 ; JMINI.27 106.9,149.76 ; JMINI.27 106.9,151.59 ; 226.66,45.58 JHDD.7 ; JHDD.7 226.66,44.45 ; JHDD.7 227.22,45.74 ; JHDD.7 227.94,45.01 ; JHDD.7 226.5,45.01 ; JHDD.7 227.78,45.58 ; JHDD.7 227.78,44.45 ; JUSB1.5 10.32,58.08 ; JUSB1.5 8.73,58.08 ; JUSB1.5 10.32,56.32 ; JUSB1.5 11.91,58.08 ; JUSB1.5 11.91,57.2 ; JUSB1.5 8.73,57.2 ; JUSB1.5 11.91,56.32 ; JUSB1.5 8.73,56.32 ; 1.64,20.31 JUSB7.7 ; JUSB7.7 4.1,20.7 ; JUSB7.7 1.64,20.7 ; 168.78,4.83 JREAD.24 ; JREAD.24 168.05,4.83 ; JREAD.24 168.05,7.76 ; JREAD.24 169.5,7.76 ; JREAD.24 168.05,6.3 ; JREAD.24 168.78,7.76 ; JREAD.24 169.5,6.3 ; JREAD.24 169.5,4.83 ; JMINI.43 113.54,151.59 ; JMINI.43 113.3,151.59 ; JMINI.43 113.3,149.76 ; 107.7,149.76 JMINI.29 ; JMINI.29 107.46,149.76 ; JMINI.29 107.7,151.59 ; JHDMI.11 8.54,103.69 ; JHDMI.11 7.5,104.15 ; JHDMI.11 7.62,103.69 ; JHDMI.11 8.66,104.15 ; JHDMI.11 8.54,104.61 ; JHDMI.11 7.62,104.61 ; 80.8,101.37 H33.1 ; H33.1 78.51,103.66 ; H33.1 79.13,101.99 ; H33.1 82.47,105.33 ; H33.1 82.47,101.99 ; H33.1 79.13,105.33 ; H33.1 83.09,103.66 ; H33.1 80.8,105.95 ; 223.86,80.06 H11.1 ; H11.1 223.37,81.4 ; H11.1 227.03,81.4 ; H11.1 226.54,82.74 ; H11.1 226.54,80.06 ; H11.1 225.2,79.57 ; H11.1 223.86,82.74 ; H11.1 225.2,83.23 ; JREAD.23 198.8,4.83 ; JREAD.23 198.08,4.83 ; JREAD.23 197.35,4.83 ; JREAD.23 198.8,6.3 ; JREAD.23 198.08,7.76 ; JREAD.23 197.35,6.3 ; JREAD.23 198.8,7.76 ; JREAD.23 197.35,7.76 ; 121.02,156.76 JMINI.53 ; JMINI.53 122.93,158.32 ; JMINI.53 121.02,158.32 ; JMINI.53 122.93,156.76 ; JMINI.53 121.97,156.76 ; 8.73,38.72 JUSB8.5 ; JUSB8.5 11.91,40.48 ; JUSB8.5 8.73,40.48 ; JUSB8.5 11.91,38.72 ; JUSB8.5 10.32,38.72 ; JUSB8.5 11.91,39.6 ; JUSB8.5 8.73,39.6 ; JUSB8.5 10.32,40.48 ; JUSB7.4 11.21,24.9 ; JUSB7.4 10.32,24.01 ; JUSB7.4 9.64,24.22 ; JUSB7.4 10.32,25.79 ; JUSB7.4 11,24.22 ; JUSB7.4 11,25.58 ; JUSB7.4 9.43,24.9 ; JUSB7.4 9.64,25.58 ; 17.12,38.1 H7.1 ; H7.1 17.68,36.58 ; H7.1 20.72,36.58 ; H7.1 20.72,39.62 ; H7.1 17.68,39.62 ; H7.1 21.28,38.1 ; H7.1 19.2,40.18 ; H7.1 19.2,36.02 ; 226.5,102.58 JODD.4 ; JODD.4 227.6,101.48 ; JODD.4 226.5,101.48 ; JODD.4 226.34,102.03 ; JODD.4 227.6,102.58 ; JODD.4 227.76,102.03 ; JUSB1.4 10.32,60.99 ; JUSB1.4 11,60.78 ; JUSB1.4 11.21,60.1 ; JUSB1.4 10.32,59.21 ; JUSB1.4 9.64,59.42 ; JUSB1.4 9.43,60.1 ; JUSB1.4 9.64,60.78 ; JUSB1.4 11,59.42 ; 1.64,36.89 JUSB7.8 ; JUSB7.8 2.87,36.89 ; JUSB7.8 1.64,36.1 ; JUSB7.8 4.1,36.89 ; JUSB7.8 4.1,36.1 ; 1.64,38.3 JUSB8.7 ; JUSB8.7 2.87,37.51 ; JUSB8.7 1.64,37.51 ; JUSB8.7 4.1,38.3 ; JUSB8.7 4.1,37.51 ; 225.51,116.59 JODD.12 ; JODD.12 226.05,115.36 ; JODD.12 225.36,116.05 ; JODD.12 226.05,116.74 ; JODD.12 226.74,116.05 ; JODD.12 225.51,115.51 ; JUSB1.8 4.1,71.3 ; JUSB1.8 1.64,72.09 ; JUSB1.8 4.1,72.09 ; JUSB1.8 1.64,71.3 ; JUSB1.8 2.87,72.09 ; 140.59,188.7 PBATT1.2 ; PBATT1.2 142.23,187.99 ; PBATT1.2 141.52,189.63 ; PBATT1.2 141.52,187.77 ; PBATT1.2 140.81,189.41 ; PBATT1.2 142.23,189.41 ; PBATT1.2 140.81,187.99 ; H5.1 226.54,167.06 ; H5.1 223.37,168.4 ; H5.1 226.54,169.74 ; H5.1 223.86,169.74 ; H5.1 227.03,168.4 ; H5.1 225.2,170.23 ; H5.1 225.2,166.57 ; H5.1 223.86,167.06 ; 7.62,101.61 JHDMI.5 ; JHDMI.5 7.5,101.15 ; JHDMI.5 7.62,100.69 ; JHDMI.5 8.66,101.15 ; JHDMI.5 8.54,100.69 ; JHDMI.5 8.54,101.61 ; 8.73,70.88 JUSB1.6 ; JUSB1.6 10.32,69.12 ; JUSB1.6 8.73,69.12 ; JUSB1.6 10.32,70.88 ; JUSB1.6 11.91,70.88 ; JUSB1.6 11.91,70 ; JUSB1.6 11.91,69.12 ; JUSB1.6 8.73,70 ; 226.54,119.49 JODD.15 ; JODD.15 226.08,120.75 ; JODD.15 226.54,122.01 ; JODD.15 227.8,119.04 ; JODD.15 227.8,122.47 ; JODD.15 229.06,119.49 ; JODD.15 229.06,122.01 ; JODD.15 229.51,120.75 ; JHDMI.17 8.66,107.15 ; JHDMI.17 7.62,106.69 ; JHDMI.17 8.54,107.61 ; JHDMI.17 8.54,106.69 ; JHDMI.17 7.5,107.15 ; JHDMI.17 7.62,107.61 ; H34.1 142.87,127.38 ; H34.1 139.53,130.72 ; H34.1 143.49,129.05 ; H34.1 141.2,126.76 ; H34.1 139.53,127.38 ; H34.1 142.87,130.72 ; H34.1 138.91,129.05 ; H34.1 141.2,131.34 ; JMINI.21 104.5,151.59 ; JMINI.21 104.26,149.76 ; JMINI.21 104.5,149.76 ; 96.5,149.76 JMINI.9 ; JMINI.9 96.5,151.59 ; JMINI.9 96.26,149.76 ; JODD.14 229.51,94.45 ; JODD.14 226.54,93.19 ; JODD.14 226.54,95.71 ; JODD.14 227.8,96.17 ; JODD.14 229.06,95.71 ; JODD.14 229.06,93.19 ; JODD.14 226.08,94.45 ; JODD.14 227.8,92.73 ; H31.1 82.47,130.72 ; H31.1 82.47,127.38 ; H31.1 83.09,129.05 ; H31.1 79.13,130.72 ; H31.1 78.51,129.05 ; H31.1 80.8,131.34 ; H31.1 79.13,127.38 ; H31.1 80.8,126.76 ; PBATT1.4 146.23,189.41 ; PBATT1.4 145.52,189.63 ; PBATT1.4 145.52,187.77 ; PBATT1.4 144.81,187.99 ; PBATT1.4 146.23,187.99 ; 109.86,149.76 JMINI.35 ; JMINI.35 110.1,149.76 ; JMINI.35 110.1,151.59
  BOTTOM w0.102: v4(35.31,71.91) v3(35.31,71.21) ; v2(37.67,98.12) v3(38.29,98.12) ; v2(71.89,20.6) v3(72.59,20.6) ; v2(51.84,54.3) v3(51.84,53.72) ; v3(133.87,134.17) 133.46,134.59 v4(133.2,134.59) ; v2(180.11,59.51) v3(180.7,59.51) ; v2(49.24,28.33) v3(49.24,27.77) ; 166.27,130.2 v4(166.22,130.2) ; v2(66.37,26.18) v3(66.37,25.56) ; v2(171.34,163.78) v3(171.91,163.78) ; v2(68.96,37.72) v3(68.96,38.43) ; v2(106.84,22.53) v3(106.84,21.85) ; v2(188.12,44.91) v3(188.84,44.91) ; v4(44.48,20.1) v3(45.16,20.1)
  BOTTOM w0.203: USOC1.BJ27 120.33,125.71 v2(120.58,125.71) ; v2(108.01,102.62) 108.23,102.62 USOC1.A43 ; v2(203.23,159.74) 203.23,159.67 201.92,158.37 RX5.1 201.2,158.87 201.2,159.71 202.06,160.58 v2(202.87,160.58) ; U11.11 v2(106.33,25.22)
  BOTTOM w0.229: USOC1.A27 101.99,107.38 101.99,107.22 v2(101.93,107.16) ; USOC1.A23 101.18,109.32 101.17,109.32 100.54,108.69 v2(100.54,108.68)
  BOTTOM w0.254: 115.6,129.23 116,129.63 116,129.71 v2(116.11,129.82) ; PR309.2 49.43,88.14 v2(48.82,88.75) ; USOC1.A35 105.44,105.33 v2(105.44,105.19) ; v2(119.51,105.73) 119.3,105.95 119.3,106.08 USOC1.AA53 ; v2(118.8,108.11) 118.8,107.6 USOC1.AB51 118.22,107.84 USOC1.AB50 USOC1.AB48 USOC1.AB47 116.74,109.34 USOC1.AB45 ; v2(117.82,128.5) 117.62,128.5 USOC1.BJ19 ; USOC1.BJ7 112.92,132.06 v2(113.41,132.55) ; v2(98.18,112.24) 98.47,112.53 USOC1.A15 ; USOC1.A19 99.89,110.78 v2(99.43,110.78) ; RC60.1 119.84,132.1 119.84,132.18 v2(120.3,132.64) ; USOC1.E53 113.52,100.47 113.52,99.65 v2(113.27,99.4) ; USOC1.BJ23 118.74,126.48 v2(119.06,126.8) ; USOC1.P52 115.87,104.19 USOC1.N51 115.68,104 USOC1.M51 114.76,104 v2(114.57,103.8) 114.47,103.71 USOC1.K50 ; DI1.3 v2(15.47,62.05) ; USOC1.M47 113.79,105.59 v2(114.04,105.83) 114.29,106.09 USOC1.P47 ; v4(210.16,172.34) 209.95,172.55 JLVDS.12 ; v2(115.55,101.65) 115.48,101.65 USOC1.J53 ; JLVDS.3 v4(205.45,172.41) ; USOC1.C49 111.14,101.75 v2(110.88,102.01) ; v2(109.13,101.17) 109.29,101.17 109.64,101.52 109.74,101.52 USOC1.A47 ; v2(114.61,131.3) 114.61,131 USOC1.BJ11 ; USOC1.C42 109.14,104.02 109.43,103.73 109.43,103.1 USOC1.C45 109.87,102.81 v2(110.16,103.1) ; v4(205.44,162.25) 205.71,161.99 UT2.4 ; DI1.8 v2(18.55,62.05) ; USOC1.AJ21 v2(110.08,120.29) ; USOC1.Y25 109.39,115.35 v2(109.43,115.39) ; JLVDS.15 211.45,174.16 v4(211.86,174.57) ; v2(110.56,100.07) 110.56,100.22 110.79,100.44 USOC1.A49 ; v4(219.45,174.5) JLVDS.31 ; 120.43,107.7 120.68,107.45 v2(120.94,107.45) ; JLVDS.6 v4(206.95,172.37) ; USOC1.AT12 109.23,125.92 v2(109.17,125.85) ; JLVDS.9 208.45,172.53 v4(208.33,172.41) ; USOC1.BJ5 111.95,133.2 v2(112.22,133.47) ; v2(97.21,113.4) 97.21,113.58 97.52,113.89 USOC1.A11
  BOTTOM w0.305: USOC1.BF4 110.76,131.84 v2(111.08,132.16) ; CC8.1 98.96,107.33 98.98,107.31 v2(99.6,107.31) ; 110.29,106 v2(110.29,106) ; 110.29,106 110.16,106.13 USOC1.J40 ; 110.29,106 110.35,105.94 USOC1.G42 ; JDIMM1.61 100.75,68.4 v2(101.96,67.19) ; v2(102.57,114.71) 102.44,114.84 USOC1.J16
  BOTTOM w0.356: JDIMM1.48 96.85,62.88 v2(96.25,63.48) ; v2(89.15,71.65) 89.95,70.86 JDIMM1.25 ; JDIMM1.19 v2(88.15,67.61) ; JDIMM1.195 v2(143.35,68.03) ; v2(86.36,71.65) 85.78,71.65 85.15,71.02 JDIMM1.9 ; v2(104.75,62.63) 104.73,62.63 104.05,61.94 JDIMM1.72 ; JDIMM1.134 125.05,62.73 v2(124.39,63.39) ; JDIMM1.172 136.45,62.64 v2(137.2,63.39) ; v2(32.97,44.4) 32.55,43.98 UI6.1 ; v2(101.09,71.65) 101.44,71.65 101.95,71.14 JDIMM1.65 ; v2(123.06,71.81) 122.64,71.81 122.43,71.6 122.43,70.89 122.95,70.37 JDIMM1.127 ; JDIMM1.8 84.85,62.11 84.97,62.23 84.97,64.1 v2(83.95,65.12) ; v2(91.88,67.98) 91.75,68.1 JDIMM1.31 ; JDIMM1.128 v2(123.25,62.62) ; v2(125.91,59.38) 126.25,59.72 JDIMM1.138 ; JDIMM1.43 95.35,68.44 94.86,67.95 v2(94.81,67.95) 94.08,67.95 93.55,68.48 JDIMM1.37 ; JDIMM1.26 90.25,59.97 89.98,59.7 88.73,59.7 v2(88.67,59.76) 88.45,59.98 JDIMM1.20 ; JDIMM1.71 103.75,67.99 v2(103.97,67.78) ; JDIMM1.66 102.25,63.15 v2(102.18,63.22) ; JDIMM1.49 97.15,68.23 96.86,67.94 v2(96.86,67.94) ; v2(141.53,63.01) 141.85,62.69 JDIMM1.190 141.87,61.22 141.87,60.1 141.69,59.92 140.41,59.92 140.05,60.28 JDIMM1.184 ; v2(93.41,63.6) 93.94,63.07 93.94,62.4 93.85,62.31 JDIMM1.38 ; v2(132.85,63.41) 133.45,62.81 JDIMM1.162 ; JDIMM1.139 v2(126.55,67.97) ; v2(130.45,67.98) 130.15,68.28 JDIMM1.151 ; JDIMM1.173 v2(136.75,68.08) ; JDIMM1.168 135.25,62.32 135.54,62.6 135.54,62.95 v2(135.97,63.38) ; JDIMM1.54 98.65,62.15 98.78,62.27 98.78,62.96 v2(98.13,63.6) ; v2(129.87,71.78) 130.12,71.78 131.35,70.55 JDIMM1.155 ; v2(140.21,71.78) 141.55,70.44 JDIMM1.189 ; v2(90.86,63.41) 91.03,63.41 92.05,62.38 JDIMM1.32 ; v2(130.94,63.51) 131.65,62.81 JDIMM1.156 ; JDIMM1.167 v2(134.95,68.08) ; JDIMM1.2 83.05,63.12 83.53,63.6 v2(83.95,63.6) ; v2(85.75,67.29) 86.35,67.89 JDIMM1.13 ; v2(124.56,71.4) 124.75,71.21 JDIMM1.133 ; v2(132.49,67.22) 133.15,67.87 JDIMM1.161 ; JDIMM1.145 v2(128.35,68.03) ; JDIMM1.44 95.65,60.19 95.41,59.95 v2(95.41,59.21) ; JDIMM1.196 143.65,62.15 143.74,62.24 143.74,62.82 v2(143.18,63.39) ; JDIMM1.185 v2(140.35,68.08) ; JDIMM1.55 v2(98.95,68.06) ; JDIMM1.144 v2(128.05,62.6) ; v2(83.14,68.06) 83.35,68.27 JDIMM1.3 ; JDIMM1.150 v2(129.85,62.6) ; v2(86.44,62.66) 86.65,62.45 JDIMM1.14 ; JDIMM1.60 100.45,60.12 100.86,59.71 v2(101.09,59.71) ; JDIMM1.179 v2(138.55,68.06) ; v2(138.25,62.64) JDIMM1.178
  BOTTOM w0.406: UX2.3 v2(195.8,165.37) ; v2(88.55,114.25) 88.55,114.77 CC17.2 ; v2(33.66,51.66) 33.66,51.15 33.34,50.83 UI2.1 ; CC18.2 90.73,112.87 v2(90.28,112.42) ; Q14.1 v2(14.78,113.42) ; Q14.4 v2(13.48,113.79) ; Q2309.1 v2(208.42,156.55)
  BOTTOM w0.508: CS10.2 CS11.2 v2(223.42,114.83) ; RT16.2 v2(209.15,159) ; CI17.2 v2(29.75,47.57) ; PR103.2 v2(127.12,11.34) ; R121.2 v2(15.88,111.58) ; v2(32.45,88.53) CL26.2 CL22.2 ; v2(52.28,111.5) JFAN.5 v2(55.38,111.5) ; DI8.1 v2(12.86,28.27) ; RC59.2 124.61,126.89 v2(124.67,126.95) ; PC914.1 126.14,136.14 v2(126.39,135.89) ; PC212.2 v4(158.46,31.11) ; CX26.2 13.86,102.55 v2(13.39,103.02) ; RL27.1 48.97,79.75 v2(48.62,80.11) ; SW2.2 v2(202.92,34.44) ; CI2.2 v2(15.47,64.64) ; CX28.2 v2(14.2,96.9) ; C1129.1 v2(72.86,102.88) ; CI10.2 v2(33.68,45.34) ; CL38.2 42.73,79.2 43.21,79.68 v2(43.21,79.7) ; v2(163.26,140.12) 162.94,140.12 162.49,139.66 PC511.2 162.58,138.94 PR508.2 ; CL36.1 v2(37.37,81.02) ; UI4.2 v2(29.77,54.05) ; v2(188.2,141.36) JBATT1.2 v2(185.43,139.5) ; CI40.2 v2(18.36,64.15) ; v2(97.13,128.37) 97.14,128.37 YC1.2 ; CL39.2 42.83,80.46 v2(42.32,80.97) ; CLRP1.2 v2(107.32,58.47) ; PC502.2 v2(166.98,139.72) ; PR404.2 v2(59.72,89.86) ; v2(43.41,99.9) CE25.2 v2(45.62,99.9) ; CL37.1 v2(39.75,79.44) ; v4(128.38,20.74) 128.35,20.74 PC117.2 ; v2(124.48,129.99) 124.04,129.54 CC7.2 ; CX27.2 v2(14.3,99.85) ; PC533.1 v2(168.94,128.98) ; Q70.3 v2(63.38,103.48) ; YL2.4 v2(37.41,75.28) ; CX6.2 v2(23.52,93.17) ; JREAD.9 v2(183.88,28.14) ; PR102.1 131.31,11.36 v2(131.3,11.35) ; v2(105.36,24.76) 105.64,24.48 C1138.1 ; v2(123.68,104.67) 124.14,105.13 CC2.2 RC7.1 ; PC116.2 128.49,16.83 v4(128.81,16.51) ; v2(87.94,111.02) 87.94,110.64 CC20.1 ; CI7.2 v2(34.32,52.65) ; v2(36.99,52.23) CI6.2 v2(35.72,53.03) ; UL3.2 v2(48.54,81.99) ; JMINI.18 v2(103.3,149.6) ; JMINI.40 v2(112.1,146.71) ; RC11.2 101.86,103.67 v2(101.86,104.5) ; RL31.1 CL20.2 v2(36.68,79.37) ; PR534.1 162.58,126.66 PC525.1 162.57,125.45 162.33,125.22 v2(162.33,124.66) ; PC415.2 v2(171.5,155.22) ; CL15.2 33.29,79.87 v2(32.85,79.42) ; CI29.2 30.94,40.38 v2(30.46,39.9) ; CL35.2 v2(35.08,89.81) ; C967.1 v2(106.84,22.53) ; CE31.2 v2(87.66,116.15) ; R122.2 v2(15.9,115.64) ; CX25.2 v2(13.36,105.24) ; CS6.2 v2(222.56,61.24) ; CX21.2 v2(13.34,106.55) ; v2(220.12,62.84) CS7.2 v2(218.96,61.88) ; UX1.2 v2(216.31,163.55) ; JREAD.2 v2(190.72,31.27) ; C976.1 v2(104.73,22.4) ; CX29.2 v2(15.83,96.8) ; PC309.2 v2(46.89,92.78) ; v2(35.11,76.99) 34.36,76.99 CX51.2 34.33,76.17 v2(35.11,76.17) ; PC214.2 v4(162.42,25.52) ; v2(219.87,116.48) CS12.2 v2(218.81,115.48) ; v2(173.13,111.33) 173.13,111.12 PR304.2 ; Q71.3 64.24,98.27 v2(64.57,98.6) ; CL34.2 v2(35.97,89.84) ; JMINI.26 v2(106.5,149.53) ; CC9.2 100.7,130.06 v2(101.22,129.54) ; v4(168.64,131.44) 168.64,131.46 168.11,131.99 PC520.2 ; v2(220.73,116.46) 221.03,116.15 CS17.2 ; PR305.2 v2(47.58,90.24) ; PD1.1 v2(143.77,184.45) ; CX10.2 v2(192.74,169.59) ; PR206.2 v4(159.34,31.1) ; v2(121.69,130) 121.26,129.56 RC14.2 ; CT12.2 v2(203.48,156.67) 203.15,156.33 CT3.2 ; C980.2 v2(107.09,32.54) ; C1131.2 v2(67.21,99.54) ; CX23.2 v2(15.85,102.64) ; C1130.1 v2(72.86,101.81) ; JREAD.17 v2(176.27,31.24) ; RT3.1 v2(210.72,156.79) ; SW2.1 v2(202.92,38.79) ; QS3.3 220.59,109.7 CS16.2 221.29,110.4 v2(221.29,111.12) ; C979.1 v2(108.11,32.59) ; v2(146.36,184.1) 145.93,183.67 PD2.1 ; CE23.2 v2(47.7,104.49) ; PR529.2 166.27,130.2 ; PR411.2 v2(170.49,155.24) ; v2(88.5,118.36) 89.06,118.92 RC49.1 ; RX33.2 v2(191.49,167.1) ; v2(47.83,111.5) JFAN.4 v2(44.43,111.5) ; CX30.2 v2(13.92,93.85) ; CC15.2 CC16.2 v2(88.42,115.64) ; v2(112.09,137.92) 112.09,137.56 CC12.2 ; CI28.2 v2(29.32,39.85) ; DA12.1 v2(17.3,23.98) ; CX22.2 15.4,105.48 v2(15.01,105.1) ; JMINI.4 v2(94.5,149.57) ; C1139.1 v2(107.72,22.5) ; CC25.2 v2(119.18,132.76) ; CT1.2 v2(202.91,152.97) ; CE24.2 v2(51.74,106.25) ; SW2.5 v2(204.24,37.79) ; DA10.1 v2(21.36,23.92) ; v2(147.2,56.23) JDIMM1.206 v2(145.01,53.34) ; v2(97.54,131.04) 97.54,131.17 YC1.4 ; YL2.2 v2(40.76,78.09) ; CI43.2 v2(17.3,53.03) ; CI9.2 v2(16.16,52.78) ; SW2.6 v2(197.77,37.79) ; DI2.1 v2(15.7,57.99) ; RT18.2 205.97,155.32 v2(205.36,155.93) ; DI9.1 v2(15.42,46.05) ; v2(93.12,112.47) 92.55,111.9 CC22.2 ; JMINI.34 v2(109.7,149.58) ; JREAD.21 v2(170.96,28.53) ; RL35.1 v2(45.83,86.43) ; CX2.2 v2(212.17,166.32) ; UI5.2 v2(27.89,38.43) ; CX24.2 v2(15.95,99.69) ; PC215.2 v4(162.42,27.43) ; v2(99.14,127.3) 99.14,127.52 CC10.2 ; JREAD.16 v2(177.04,31.24) ; CS5.2 v2(222.48,55.5) ; CL19.2 v2(43.77,81.53) ; CE22.2 v2(46.54,106.5) ; CI26.2 v2(35.16,47.9) ; CX9.2 v2(217.07,158.65) ; UL2.2 v2(42.83,73.35) ; RT12.1 v2(211.74,156.79) ; CI11.2 v2(36.34,45.37) ; JFAN.3 v2(51.2,107.36) ; CC23.2 v2(179.23,110.11) ; JMINI.50 v2(116.1,146.75) ; C1144.1 v2(110.14,32.54) ; CC26.2 v2(118.52,133.42)
  vias: v2(15.75,33.93) v2(16.79,33.98) v2(17.55,33.98) v2(17.94,102.94) v2(17.99,105) v2(18.98,102.13) v2(18.95,100.12) v2(21.82,95.22) v2(26.83,68.65) v2(26.85,69.64) v2(27.33,69.16) v2(27.44,100.4) v2(27.46,104.29) v2(27.46,102.33) v2(27.83,69.66) v2(27.84,68.65) v2(28.65,98.63) v2(29.12,43.5) v2(29.12,42.5) v2(29.54,64.41) v2(30.13,50.37) v2(30.13,49.35) v2(30.1,43.48) v2(30.12,42.5) v2(30.46,64.39) v2(30.71,98.6) v2(31.14,50.37) v2(31.13,49.36) v2(31.45,64.41) v2(32.64,64.44) v2(36.64,85.38) v2(36.66,84.27) v2(36.66,83.18) v2(37.62,100.35) v2(37.62,99.34) v2(37.75,85.37) v2(37.75,84.27) v2(37.75,83.18) v2(37.8,57.12) v2(37.8,55.17) v2(38.84,84.27) v2(38.84,83.18) v2(38.89,112.42) v2(38.85,85.38) v2(40.03,112.47) v2(40.31,90.27) v2(41.41,90.27) v2(41.96,55.32) v2(41.96,53.24) v2(42.85,60.42) v2(43.16,63.85) v2(43.16,61.8) v2(43.97,60.42) v2(46.82,100.35) v2(46.97,60.65) v2(47.88,100.35) v2(48.21,60.65) v2(48.59,56.92) v2(48.57,55.78) v2(48.72,100.3) v2(49.69,93.57) v2(49.71,60.91) v2(49.71,58.75) v2(50.37,93.55) v2(50.88,56.26) v2(50.88,55.29) v2(50.87,54.32) v2(51.11,102.84) v2(51.11,102.18) v2(51.84,102.82) v2(51.82,102.11) v2(51.84,56.26) v2(51.84,55.29) v2(52.82,56.27) v2(52.84,55.29) v2(52.82,54.32) v2(53.04,58.29) v2(57.23,104.72) v2(57.38,101.37) v2(57.43,99.9) v2(57.43,99.01) v2(63.83,48.31) v2(63.91,55.78) v2(63.88,52.22) v2(66.2,38.68) v2(67.21,38.68) v2(67.52,55.85) v2(67.54,52.27) v2(67.59,48.31) v2(71.33,55.85) v2(71.33,48.36) v2(71.38,52.27) v2(74.15,115.69) v2(76.25,115.67) v2(82.76,71.84) v2(86.36,73.18) v2(86.44,64.18) v2(87.91,65.12) v2(87.91,63.6) v2(89.15,73.18) v2(89.59,122.76) v2(89.65,64.91) v2(89.65,63.38) v2(90,123.24) v2(90.88,122.81) v2(91.27,135.58) v2(91.32,123.24) v2(91.55,136.45) v2(91.7,131.98) v2(91.88,65.69) v2(92.1,133.86) v2(92.82,136.29) v2(93.31,73.18) v2(93.31,71.65) v2(93.41,65.12) v2(93.5,138.66) v2(94.03,122.25) v2(94.31,118.74) v2(94.52,122.73) v2(94.48,73.56) v2(94.48,72.04) v2(94.83,65.36) v2(94.83,63.76) v2(95.02,123.19) v2(95.91,132.92) v2(96.4,135.56) v2(97.01,132.97) v2(97.32,118.29) v2(97.54,135.99) v2(97.6,73.31) v2(97.6,71.02) v2(97.72,119.42) v2(97.9,117.74) v2(98.13,65.12) v2(98.79,72.67) v2(98.79,71.15) v2(99.57,120.28) v2(99.85,118.61) v2(100.29,65.12) v2(100.29,63.6) v2(100.61,119.25) v2(101.09,73.18) v2(101.26,112.18) v2(101.65,141.58) v2(101.88,125.55) v2(102.23,121.77) v2(102.18,65.5) v2(102.26,135.94) v2(102.75,121.24) v2(103.18,127.02) v2(103.18,120.75) v2(103.36,142.42) v2(103.38,140.92) v2(103.7,65.25) v2(103.7,63.73) v2(103.79,117.42) v2(103.87,106.58) v2(104.07,122.76) v2(104.14,73.18) v2(104.14,71.65) v2(104.27,111) v2(104.56,112.66) v2(105.04,82.97) v2(105.04,82.21) v2(105.04,81.45) v2(105.04,80.69) v2(105.41,142.42) v2(105.52,27.25) v2(105.65,109.56) v2(105.7,125.27) v2(105.69,95.15) v2(105.77,112.5) v2(105.92,72.4) v2(105.92,70.88) v2(105.92,69.36) v2(106.09,130.41) v2(106.18,116.41) v2(106.51,120.29) v2(106.46,114.59) v2(106.66,128.25) v2(106.73,103.87) v2(106.81,125.49) v2(107.12,111.08) v2(107.22,27.25) v2(107.32,119.66) v2(107.34,105.84) v2(107.48,122.08) v2(107.57,65.67) v2(107.86,119.16) v2(108.81,130.32) v2(109.33,133.55) v2(109.29,129.9) v2(109.38,134.44) v2(109.45,128.22) v2(109.53,65.67) v2(110.24,128.98) v2(110.57,117.56) v2(110.91,71.56) v2(111.31,64.91) v2(111.31,63.39) v2(111.41,129.28) v2(111.39,123.7) v2(112.14,99) v2(112.16,74.07) v2(112.16,72.54) v2(112.8,120.87) v2(112.75,118.68) v2(112.91,125.05) v2(113.19,129.59) v2(113.21,112.72) v2(113.64,127.4) v2(113.84,117.62) v2(113.81,65.67) v2(113.81,64.15) v2(113.9,126.04) v2(115.04,110.36) v2(115.22,124.85) v2(115.3,74.45) v2(115.66,125.32) v2(116.77,95.27) v2(116.95,121.03) v2(117.09,64.91) v2(117.38,118.69) v2(117.48,121.52) v2(118.24,120.77) v2(118.31,115.51) v2(118.35,67.2) v2(118.35,65.67) v2(118.35,63.36) v2(118.52,122.45) v2(118.48,74.07) v2(118.48,72.54) v2(118.48,71.02) v2(118.93,122.91) v2(118.91,115.98) v2(118.9,97.05) v2(119.08,113.19) v2(119.58,112.72) v2(120.02,122.68) v2(120.15,118.84) v2(120.22,64.85) v2(120.92,118.03) v2(121.42,63.46) v2(121.49,124.13) v2(121.48,121.37) v2(121.47,113.55) v2(121.75,120.3) v2(121.94,113.06) v2(122.24,117.92) v2(122.23,109.32) v2(122.26,120.77) v2(122.32,115.46) v2(122.61,113.74) v2(122.71,118.41) v2(122.81,120.06) v2(122.99,122.28) v2(123.06,73.33) v2(123.35,67.19) v2(123.47,114.32) v2(123.6,119.33) v2(123.6,112.82) v2(124.23,121.49) v2(124.26,116.82) v2(124.33,113.42) v2(124.39,64.91) v2(124.56,73.69) v2(125.34,116.4) v2(125.38,140.92) v2(126.28,66.51) v2(126.28,64.91) v2(126.28,63.39) v2(127.08,119.28) v2(127.06,118.67) v2(127.63,73.28) v2(127.63,71.76) v2(127.75,113.17) v2(128.03,117.61) v2(128.79,115.14) v2(128.82,64.91) v2(128.82,63.39) v2(129.12,116) v2(129.87,73.31) v2(130.94,65.8) v2(132.82,73.31) v2(132.82,71.78) v2(132.85,65.01) v2(134.81,73.31) v2(134.81,71.78) v2(134.75,64.91) v2(134.75,63.39) v2(136.4,73.69) v2(136.4,71.4) v2(137.2,64.91) v2(138.43,73.31) v2(138.43,71.78) v2(139.83,64.91) v2(139.83,63.39) v2(140.21,73.31) v2(141.53,65.29) v2(143.18,64.91) v2(143.77,71.78) v2(157.43,61.95) v2(157.41,58.39) v2(157.46,54.48) v2(160.61,102.08) v2(160.58,99.13) v2(161.04,62.02) v2(161.06,58.44) v2(161.12,54.48) v2(162.72,102.11) v2(162.72,99.11) v2(164.85,62.02) v2(164.85,54.53) v2(164.9,58.44) v2(170.02,173.16) v2(170.06,171.45) v2(170.89,172.29) v2(171.69,171.49) v2(176.18,24.33) v2(176.19,22.57) v2(177.07,23.44) v2(177.96,24.33) v2(177.96,22.55) v2(197.92,148.74) v2(202.62,178.08) v2(203.97,171.4) v2(204.32,170.23) v2(204.27,168.15) v2(206.94,170.91) v2(207.14,167.89) v2(207.15,168.98) v2(209.1,168.2) v2(209.07,165.94) v2(210.34,164.01) v2(210.42,169.59) v3(130.99,22.77) v3(132.21,134.17) v3(137.98,136.92) v3(144.15,168.74) v3(145.13,145.92) v3(150.26,125.31) v3(156.18,99.41) v3(160.72,11.28) v3(171.07,173.71) v4(0.51,119.89) v4(0.51,111.91) v4(0.54,53.31) v4(0.54,20.65) v4(0.84,116.03) v4(1.11,95.39) v4(1.11,91.46) v4(1.32,70.91) v4(1.32,38.68) v4(4.78,20.8) v4(5.14,93.52) v4(5.13,56.28) v4(5.58,91.45) v4(5.58,74.15) v4(5.6,72.51) v4(7.28,35.71) v4(7.36,109.27) v4(7.36,98.03) v4(7.98,65.83) v4(7.98,58.21) v4(7.98,49.75) v4(7.98,42.13) v4(8.01,33.64) v4(7.98,30.59) v4(8,22.98) v4(8.13,119.89) v4(8.13,53.26) v4(8.35,93.5) v4(8.45,69.48) v4(8.55,116.01) v4(9.05,71.32) v4(9.03,38.43) v4(9.4,20.85) v4(9.51,96.12) v4(10.41,72.79) v4(10.55,33.64) v4(10.58,36.08) v4(10.68,20.82) v4(10.81,50.87) v4(10.81,41.13) v4(11.09,93.37) v4(11.14,37.86) v4(11.41,23.22) v4(11.85,33.62) v4(11.97,36.07) v4(12.24,70.7) v4(13.2,91.45) v4(13.2,74.15) v4(15.75,119.89) v4(16.94,39) v4(17.04,36.91) v4(17.38,72.85) v4(17.47,70.75) v4(19.2,73.93) v4(19.2,69.87) v4(19.2,40.51) v4(19.2,35.69) v4(20.08,5.85) v4(20.17,3.75) v4(20.91,70.77) v4(21.03,72.83) v4(21.33,36.99) v4(21.46,39.05) v4(21.9,6.93) v4(21.9,2.87) v4(22.61,119.89) v4(22.58,23.26) v4(23.32,23.24) v4(23.61,3.77) v4(23.73,5.83) v4(23.9,56.41) v4(23.9,55.65) v4(23.9,54.89) v4(23.9,54.13) v4(24.61,118.97) v4(25.06,117.66) v4(25.57,25.28) v4(26.2,25.28) v4(26.37,116.73) v4(26.78,32.87) v4(28.09,117.09) v4(28.3,32.87) v4(29.1,118.28) v4(29.06,32.87) v4(29.38,110.35) v4(29.36,9.49) v4(29.47,108.25) v4(31.09,118.39) v4(31.2,111.43) v4(31.2,107.37) v4(31.65,71.17) v4(32.91,108.27) v4(33.03,110.33) v4(33.51,71.96) v4(34.47,71.93) v4(37.52,8.99) v4(38.51,119.89) v4(41.94,22.64) v4(41.94,21.37) v4(41.94,20.1) v4(43.21,22.64) v4(43.21,21.37) v4(43.21,20.1) v4(44.48,22.64) v4(44.48,21.37) v4(46.13,119.89) v4(46.16,95.73) v4(46.16,94.84) v4(46.51,8.99) v4(47.35,95.81) v4(47.35,94.82) v4(48.26,95.83) v4(48.26,94.84) v4(49.13,95.91) v4(49.1,94.84) v4(50.6,97.81) v4(50.65,96.72) v4(50.85,91.31) v4(51.57,91.34) v4(52.25,91.34) v4(53.04,107.44) v4(53.06,108.18) v4(53.8,120.34) v4(53.88,108.23) v4(53.85,107.47) v4(55.38,8.99) v4(58.98,96.67) v4(58.98,96.04) v4(58.96,95.4) v4(58.96,94.77) v4(60.88,9.49) v4(61.35,122.35) v4(63.34,89.49) v4(63.31,88.86) v4(63.31,88.22) v4(65.18,89.69) v4(65.31,91.93) v4(65.54,12.99) v4(66.04,90.07) v4(66.26,91.93) v4(68.22,125.81) v4(73.16,12.99) v4(73.89,130.26) v4(79.35,54.18) v4(79.35,53.41) v4(79.35,52.65) v4(79.58,134.85) v4(80.78,12.99) v4(83.7,142.17) v4(84.73,149.8) v4(85.51,157.4) v4(88.4,12.99) v4(89.42,156.72) v4(89.91,8.99) v4(91.43,151.51) v4(92.71,33.02) v4(93.4,33.02) v4(94.26,33.02) v4(97.34,8.99) v4(102.11,32.61) v4(102.87,32.61) v4(103.64,32.61) v4(104.4,32.61) v4(104.96,8.99) v4(105.16,32.61) v4(107.38,14.35) v4(107.47,12.25) v4(109.2,15.43) v4(109.2,11.37) v4(110.91,12.27) v4(111.03,14.33) v4(111.15,19.23) v4(111.71,32.54) v4(111.92,19.23) v4(112.47,32.54) v4(112.68,19.23) v4(113.24,32.54) v4(114.1,141.3) v4(114.1,140.66) v4(114.1,139.98) v4(114.74,141.32) v4(114.74,140.69) v4(114.74,140) v4(115.12,8.99) v4(117.46,151.51) v4(120.74,156.72) v4(122.58,17.22) v4(122.58,16.2) v4(122.58,15.44) v4(122.74,8.99) v4(122.91,143.56) v4(123.22,16.71) v4(123.22,15.82) v4(123.55,143.56) v4(123.8,144.24) v4(124.18,143.56) v4(124.51,144.22) v4(124.82,143.56) v4(125.45,145.46) v4(125.45,144.83) v4(125.45,144.19) v4(125.45,143.56) v4(125.78,155.75) v4(125.87,153.65) v4(126.01,189.59) v4(126.01,183.66) v4(126.01,176.04) v4(126.01,168.42) v4(126.01,160.8) v4(126.42,12.67) v4(126.5,23.39) v4(126.52,22.76) v4(126.56,25.79) v4(127.21,24.33) v4(127.21,23.7) v4(127.21,23.06) v4(127.6,156.83) v4(127.6,152.77) v4(127.84,24.33) v4(127.84,23.7) v4(127.84,23.06) v4(128.48,24.33) v4(128.48,23.7) v4(128.48,23.06) v4(128.81,15.67) v4(129.11,24.33) v4(129.11,23.7) v4(129.11,23.06) v4(129.31,153.67) v4(129.43,155.73) v4(129.64,16.51) v4(129.64,15.67) v4(129.75,24.33) v4(129.75,23.7) v4(129.75,23.06) v4(130.38,24.33) v4(130.38,23.7) v4(130.38,23.06) v4(130.36,8.99) v4(132.59,20.32) v4(132.59,19.68) v4(133.2,138.4) v4(133.2,137.64) v4(133.2,136.88) v4(133.2,136.12) v4(133.2,135.35) v4(133.23,20.32) v4(133.23,19.68) v4(133.63,189.59) v4(135.23,15.8) v4(135.26,20.5) v4(135.26,19.86) v4(135.28,16.46) v4(136.63,183.74) v4(136.68,180.69) v4(137.39,183.74) v4(137.44,180.69) v4(137.68,189.48) v4(137.67,188.08) v4(137.67,187.45) v4(137.67,186.81) v4(137.98,8.99) v4(138.09,188.75) v4(138.15,183.74) v4(138.2,180.69) v4(138.35,189.91) v4(138.31,139.09) v4(138.43,187.45) v4(138.43,186.81) v4(138.76,138.4) v4(138.76,137.64) v4(138.76,136.88) v4(138.76,136.12) v4(138.92,183.74) v4(138.97,180.69) v4(138.99,139.06) v4(139.2,187.45) v4(139.2,186.81) v4(139.4,138.4) v4(139.4,137.64) v4(139.4,136.88) v4(139.4,136.12) v4(139.65,139.06) v4(139.96,187.45) v4(139.96,186.81) v4(140.03,138.4) v4(140.03,137.64) v4(140.03,136.88) v4(140.03,136.12) v4(140.3,190.59) v4(140.34,138.96) v4(140.72,187.45) v4(140.72,186.81) v4(140.67,138.4) v4(140.67,137.64) v4(140.67,136.88) v4(140.67,136.12) v4(143.41,142.82) v4(144.25,144.37) v4(144.25,143.61) v4(144.25,142.85) v4(145.01,144.37) v4(145.01,143.61) v4(145.01,142.85) v4(145.42,169.29) v4(145.42,168.53) v4(145.42,167.76) v4(145.6,8.99) v4(146.18,169.29) v4(146.18,168.53) v4(146.18,167.76) v4(146.94,169.29) v4(146.94,168.53) v4(146.94,167.76) v4(147.7,169.29) v4(147.7,168.53) v4(147.7,167.76) v4(147.92,190.59) v4(148.24,123.87) v4(148.24,123.14) v4(148.24,122.45) v4(148.47,168.53) v4(148.47,167.76) v4(148.7,128.47) v4(148.82,127.71) v4(148.82,126.95) v4(148.82,126.26) v4(148.82,125.42) v4(148.95,123.9) v4(148.95,123.14) v4(148.92,122.45) v4(149.23,168.53) v4(149.23,167.76) v4(149.2,98.98) v4(149.46,128.47) v4(149.51,125.45) v4(149.71,123.9) v4(149.71,123.14) v4(149.69,122.48) v4(149.97,98.98) v4(149.95,21.71) v4(150.42,122.48) v4(150.59,21.71) v4(150.73,98.98) v4(151.16,145.43) v4(151.22,21.71) v4(151.25,143.34) v4(151.34,122.43) v4(151.49,98.98) v4(152.25,122.25) v4(152.25,98.98) v4(153.01,122.25) v4(153.01,98.98) v4(153.22,8.99) v4(153.31,146.86) v4(153.27,142.16) v4(153.32,115.24) v4(153.32,114.48) v4(153.32,113.71) v4(153.32,112.95) v4(153.29,112.11) v4(153.29,111.35) v4(153.29,110.59) v4(153.29,109.83) v4(153.29,109.01) v4(153.29,108.25) v4(153.32,107.44) v4(153.29,106.68) v4(153.25,27.49) v4(153.89,27.49) v4(154.08,115.24) v4(154.08,114.48) v4(154.08,113.71) v4(154.08,112.95) v4(154.05,112.11) v4(154.05,111.35) v4(154.05,109.83) v4(154.05,109.01) v4(154.05,108.25) v4(154.13,107.47) v4(154.11,106.7) v4(155.33,143.36) v4(155.54,190.59) v4(155.45,145.41) v4(156.56,30.16) v4(156.56,29.53) v4(156.87,26.54) v4(156.87,25.78) v4(156.87,23.68) v4(156.87,23.05) v4(157.13,186.08) v4(157.7,26.54) v4(157.7,25.72) v4(157.76,186.08) v4(158.31,14.86) v4(158.31,14.22) v4(158.31,13.59) v4(158.31,12.95) v4(158.4,186.08) v4(158.94,14.86) v4(158.94,14.22) v4(158.94,13.59) v4(158.94,12.95) v4(158.97,20.44) v4(159.58,14.86) v4(159.58,14.22) v4(159.58,13.59) v4(159.58,12.95) v4(159.67,20.44) v4(159.79,12.32) v4(160.21,14.86) v4(160.21,14.22) v4(160.21,13.59) v4(160.21,12.95) v4(160.5,189.82) v4(160.46,179.78) v4(160.46,179.14) v4(160.85,14.22) v4(160.85,13.59) v4(160.84,8.99) v4(162.38,186.35) v4(162.47,184.25) v4(162.72,133.67) v4(162.72,131.95) v4(163.08,132.84) v4(164.09,133.74) v4(164.07,131.91) v4(164.2,187.43) v4(164.2,183.37) v4(165.45,36.65) v4(165.91,184.27) v4(165.91,6.35) v4(166.03,186.33) v4(166.06,109.48) v4(167.03,110.56) v4(167.01,109.48) v4(167.14,111.58) v4(167.41,154.76) v4(167.61,36.66) v4(167.79,0.51) v4(168.13,154.51) v4(168.05,47.88) v4(168.42,189.59) v4(168.88,145.24) v4(168.88,144.6) v4(169,113.04) v4(169,112.41) v4(169.22,47.88) v4(170.39,176.49) v4(170.37,175.84) v4(170.39,45.13) v4(172.52,45.18) v4(172.99,147.2) v4(172.99,146.51) v4(175.41,0.51) v4(176.04,189.59) v4(183.03,0.51) v4(183.66,189.59) v4(190.65,0.51) v4(191.28,189.59) v4(196.9,156.78) v4(197.13,165.74) v4(197.13,165.11) v4(197.13,164.47) v4(197.5,157.48) v4(197.54,156.78) v4(197.89,189.59) v4(197.89,181.97) v4(198.27,0.51) v4(199.98,170.41) v4(200.64,170.41) v4(201.35,170.41) v4(201.9,95.36) v4(201.98,170.41) v4(202,93.26) v4(202.67,170.41) v4(203.2,179.09) v4(204.1,96.81) v4(204.1,91.99) v4(204.45,162.25) v4(204.46,164.09) v4(204.46,163.21) v4(205.43,164.11) v4(205.46,163.21) v4(205.89,0.51) v4(206.33,164.08) v4(206.27,93.34) v4(206.4,95.4) v4(206.47,163.21) v4(206.45,162.25) v4(211.84,179.09) v4(212.12,171.78) v4(212.12,171.02) v4(212.88,171.78) v4(212.88,171.02) v4(213.11,162) v4(213.11,161.29) v4(213.51,0.51) v4(213.64,171.78) v4(213.64,171.02) v4(213.85,161.29) v4(213.87,161.97) v4(219.46,179.09) v4(221.13,0.51) v4(223.27,5.81) v4(223.38,169.35) v4(223.38,82.35) v4(223.45,3.71) v4(223.47,167.25) v4(223.47,80.25) v4(225.2,179.09) v4(225.2,170.43) v4(225.2,166.37) v4(225.2,83.43) v4(225.2,79.37) v4(225.2,6.93) v4(225.2,2.87) v4(225.33,177.85) v4(225.33,177.21) v4(226.91,167.27) v4(226.91,80.27) v4(226.91,3.77) v4(227.03,169.33) v4(227.03,82.33) v4(227.03,5.83) v4(229.89,180.59) v4(229.89,172.97) v4(229.89,165.35) v4(229.89,157.73) v4(229.89,150.11) v4(229.89,142.49) v4(229.89,134.87) v4(229.89,127.25) v4(229.89,117.45) v4(229.89,109.83) v4(229.89,102.21) v4(229.89,91.28) v4(229.89,85.19) v4(229.89,77.79) v4(229.89,70.17) v4(229.89,62.55) v4(229.89,54.93) v4(229.89,47.31) v4(229.89,39.69) v4(229.89,32.07) v4(229.89,24.45) v4(229.89,16.83) v4(229.89,9.21) v4(229.89,0.51)
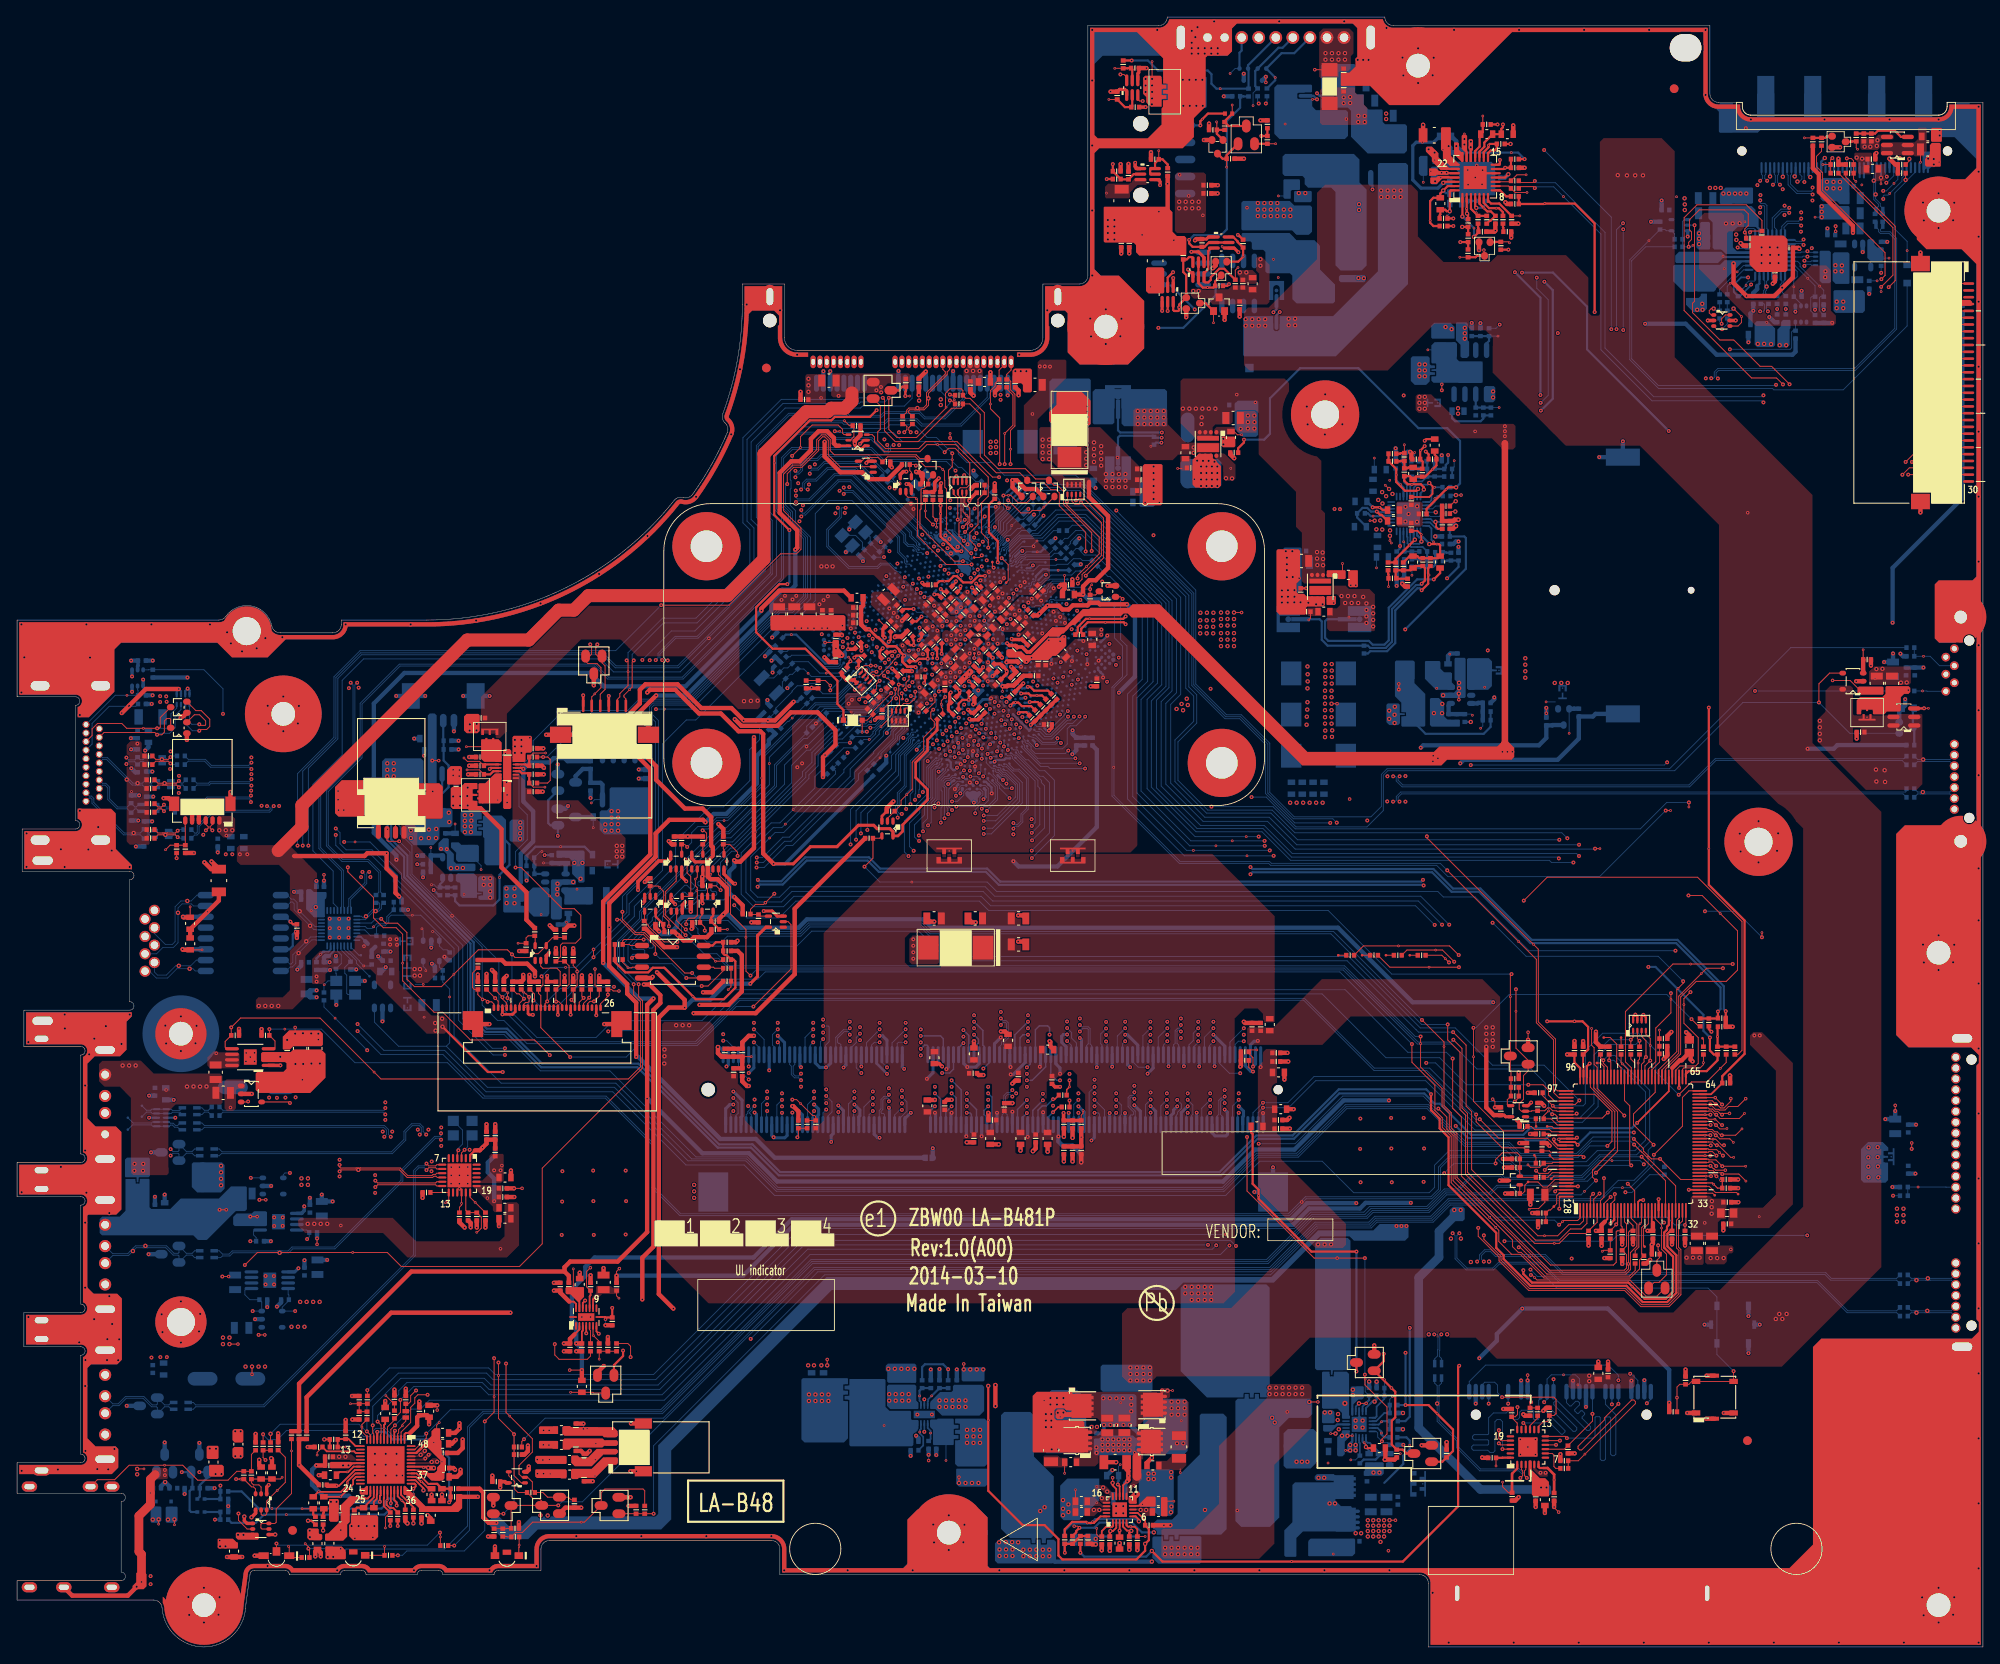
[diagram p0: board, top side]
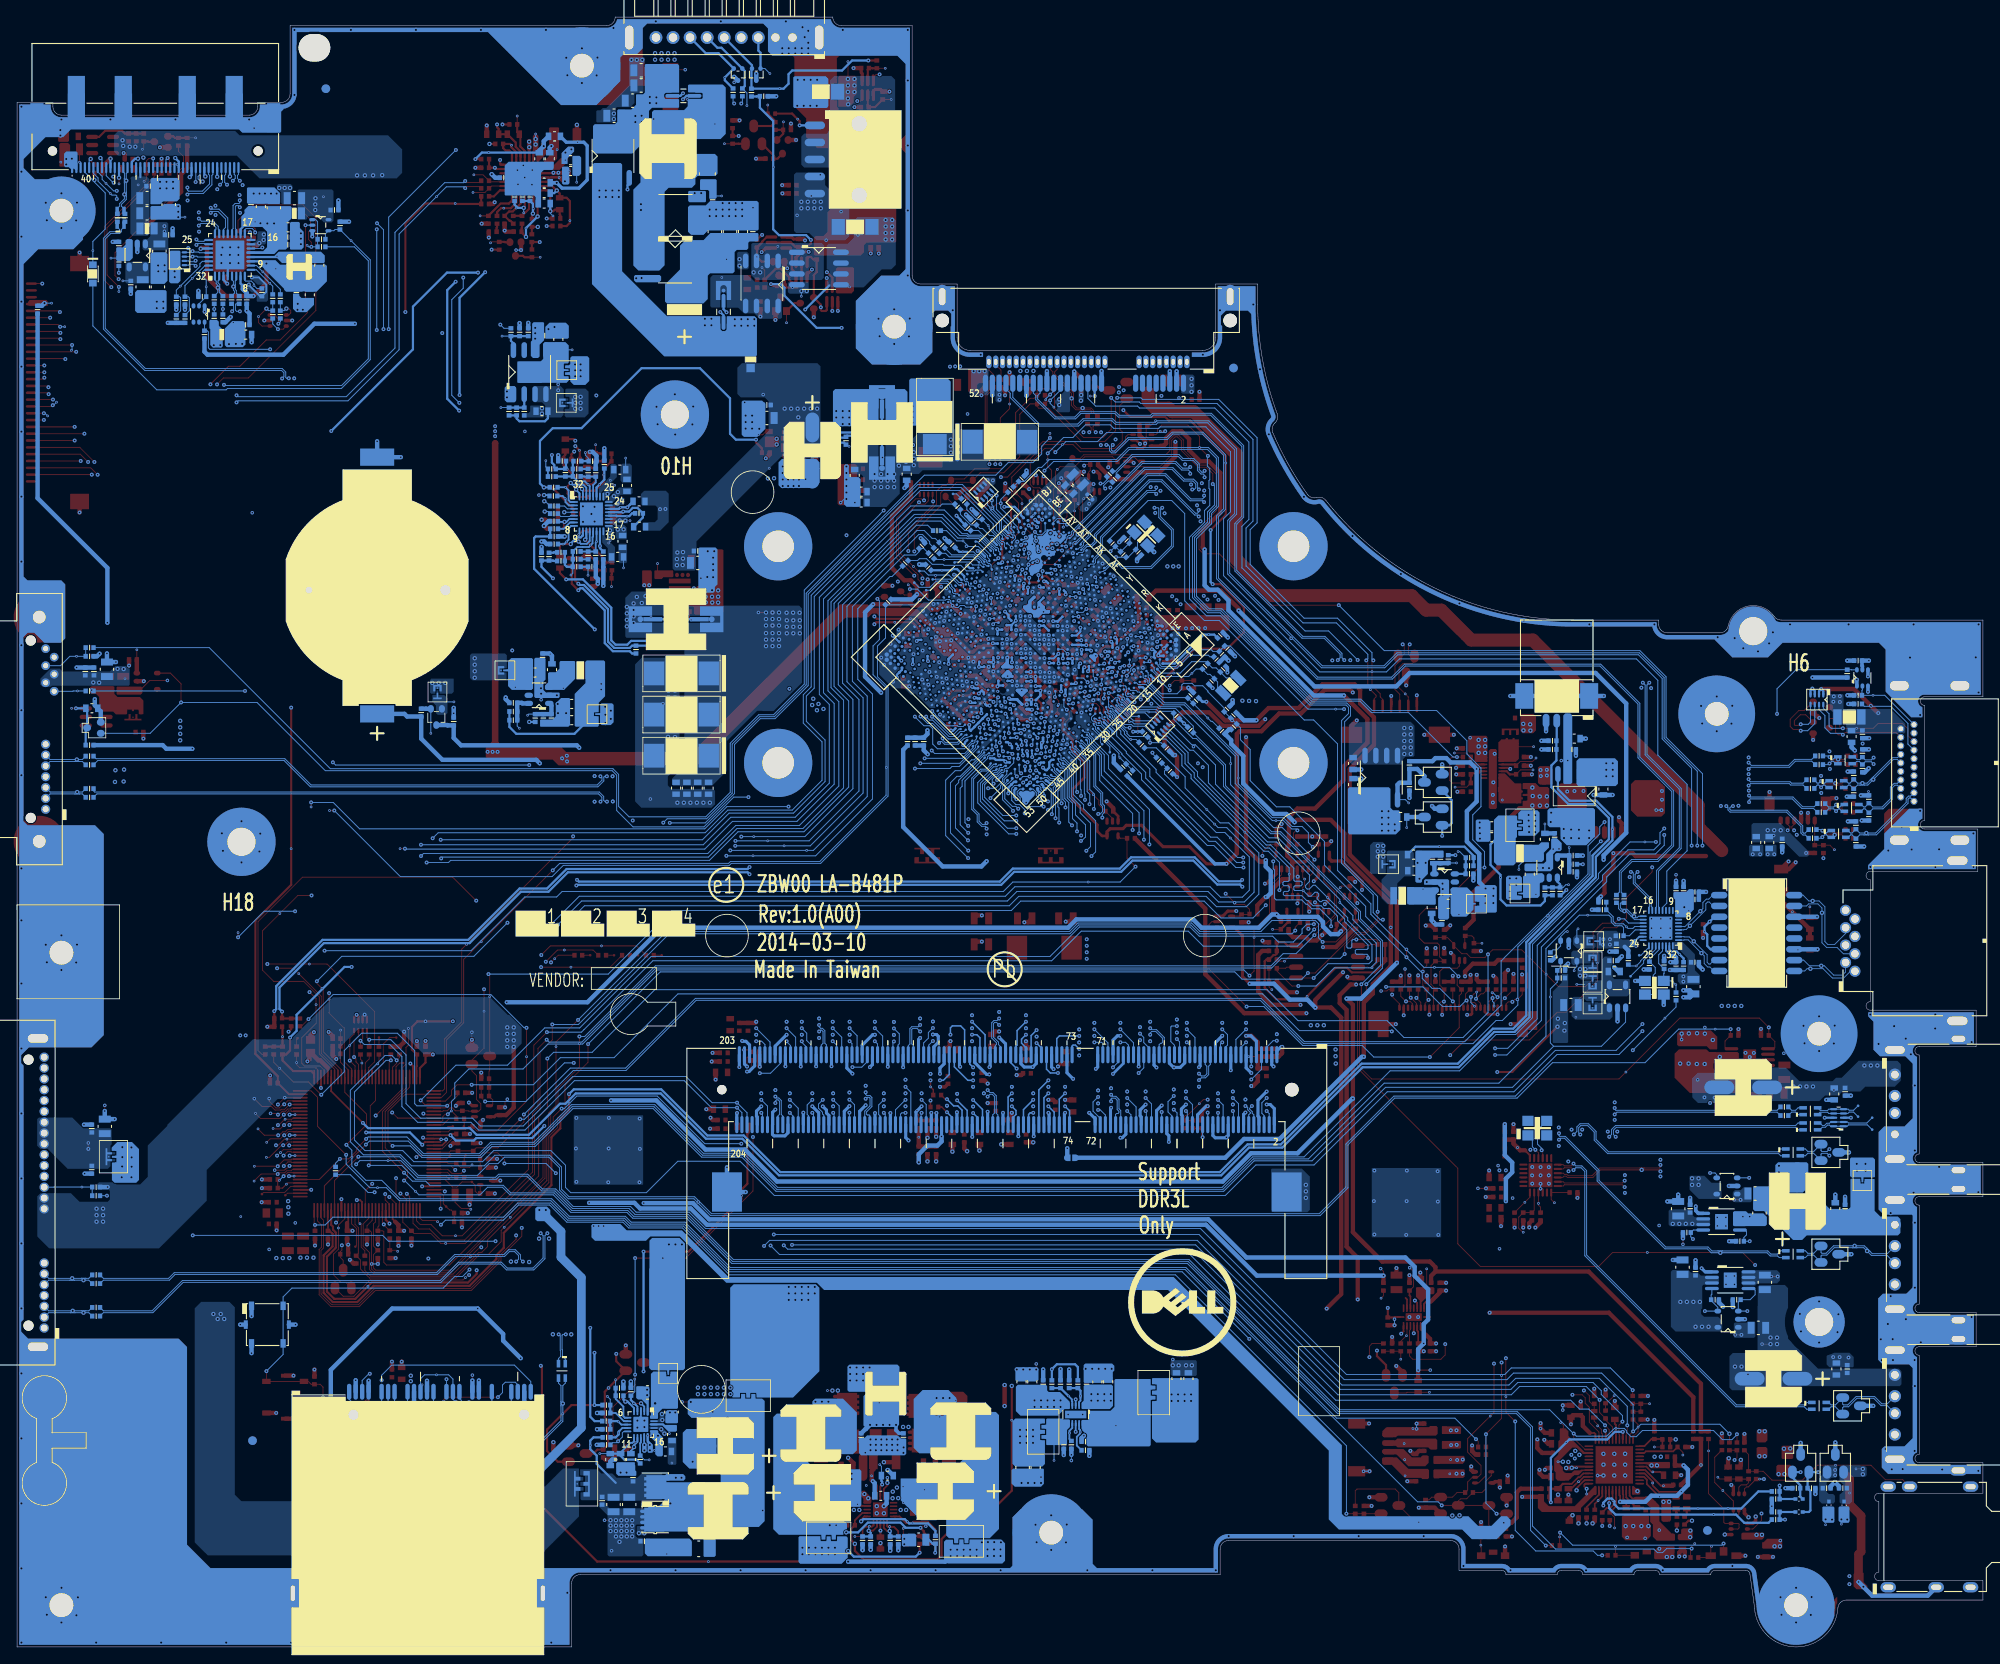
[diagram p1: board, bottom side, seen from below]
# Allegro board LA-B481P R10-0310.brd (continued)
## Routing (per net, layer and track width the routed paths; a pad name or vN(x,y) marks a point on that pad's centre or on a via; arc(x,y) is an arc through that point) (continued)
GNDA: length 21.9
  TOP w0.203: v4(47.63,18.36) 47.63,18.6 46.69,19.55 UA1.38
  TOP w0.381: v2(29.49,19) 29.25,18.76 QA5.1 ; v4(26.63,15.29) 26.63,14.8 26.95,14.48 QA6.1 ; QA6.4 v4(30.25,13.18)
  TOP w0.406: QA5.4 27.95,15.68 v4(27.47,15.2)
  TOP w0.508: v4(29.79,22.12) 29.87,22.03 CA2.2 ; CA74.2 v2(35.36,20.14) ; CA61.2 v4(49.8,17.85) ; v4(28.38,21.93) 28.38,21.32 CA1.2 ; RA153.1 v2(34.06,23.44) ; CA63.1 v2(48.58,17.85)
  GND w0.203: JHP.5 2.53,19.58 ; JHP.5 0.37,19.58 ; JHP.5 2.53,18.8 ; JHP.5 0.37,18.8 ; JHP.5 1.45,19.58
  BOTTOM w0.508: CA38.2 16.87,18.84 v4(17.35,19.33) 17.86,18.82 CA40.2 ; RA84.2 v2(24.74,16.51) RA83.2 ; v2(23.14,18.62) CA33.2 ; CA39.2 v2(19.64,17.93)
  vias: v3(23.75,12.47) v3(39.59,12.74) v3(41.7,12.84) v4(23.27,20.27) v4(23.79,11.8) v4(23.96,20.27) v4(24.43,11.8) v4(25.57,22.36) v4(26.2,22.36) v4(34.29,13.64) v4(34.32,12.88) v4(36.78,17.02) v4(37.44,17.02) v4(39.21,14.17) v4(40.03,14.17) v4(40.49,18.26) v4(40.99,14.17) v4(41.88,14.17)
V1: length 55.7
  TOP w0.254: PR714.2 v2(174.78,163.83) ; PQ709.6 137.81,162.8 137.65,162.96 137.37,162.96 137.09,162.68 PR702.2 136.68,161.2 137.02,160.86 PQ708.2 136.2,157.38 v2(136.2,157.07) 136.2,156.74 136.1,156.64 135.61,156.64 135.5,156.75 PQ713.6
  IN2 w0.254: v2(136.2,157.07) 136.76,157.07 140.96,152.87 155,152.87 165.33,163.19 174.15,163.19 v2(174.78,163.83)
V18: length 2.6
  TOP w0.102: v1(173.33,21.22) CR4.2
  TOP w0.254: CR4.2 174.08,22.17 174.1,22.19 UR1.24
VCCST_PG_EC: length 8
  TOP w0.102: UE1.123 180.23,54.8 179.35,53.92 178.84,53.92 178.25,54.52 T209.1 176.71,54.14 176.71,53.44 176.43,53.16 CE35.1 176.12,53.17 DE1.2
VDD_1.35VP: length 8
  BOTTOM w0.102: v1(162.11,22.67) PR203.2
  BOTTOM w0.203: PC213.1 159.67,22.79 158.52,23.94 158.27,23.94 158.09,24.12 PU200.11
  BOTTOM w0.254: PR201.1 157.82,21.97 159.22,21.97 159.67,22.41 PC213.1 PR203.2
VDDP_LDO: length 10.9
  TOP w0.254: PR710.1 v2(176.69,174.45)
  BOTTOM w0.254: v2(176.69,174.45) 175.92,175.21 v1(175.12,175.21) 169.21,175.21 PC714.1
  BOTTOM w0.508: PR709.1 168.67,176.55 v4(168.67,175.97) 169.19,175.45 PC714.1
VIN: length 88.4
  TOP w0.254: PR706.2 170.07,166.49 PR711.2 v4(169.37,166.49)
  TOP w0.508: PR707.1 v4(164.79,178.46) ; 134.85,167.23 v2(134.85,171.55) PR14.2
  IN1 w0.508: v2(134.85,171.55) 136.15,172.84 145.82,172.84 147.86,174.88 147.86,178 150.5,180.64 153.04,180.64 155.02,182.62 158.78,182.62 162.23,179.17 164.07,179.17 v4(164.79,178.46)
  IN2 w0.254: v4(169.37,166.49) 166.81,163.93 165.51,163.93 154.84,153.26 141.58,153.26 v2(138.03,156.82)
  BOTTOM w0.254: 135.21,159.64 v2(138.03,156.82)
  vias: v3(131.85,165.56) v3(133.82,168.29) v3(135.58,164.93) v4(127.84,167.31) v4(127.84,166.55) v4(127.84,165.78) v4(127.84,165.02) v4(128.6,167.31) v4(128.6,166.55) v4(128.6,165.78) v4(128.6,165.02)
65W/90W#: length 2.1
  TOP w0.102: T220.1 180.06,57.2 UE1.117
+A_VCC: length 7.2
  TOP w0.508: RA10.2 RA12.2 v3(33.05,21.33) RA28.2
+A_VCC_R: length 4.7
  TOP w0.203: UA1.20 39.59,20.75 37.74,18.9 v1(37.44,18.9)
  TOP w0.508: RA28.1 36.4,18.9 v1(37.44,18.9)
+BIOS_SPI: length 27.6
  TOP w0.254: UC8.8 81.51,82.24 81.89,82.62 CC21.1 RC99.1 82.76,81.3 82.93,81.13 83.14,81.13 RC37.1 83.98,80.59 84.18,80.39 84.18,77.29 82.83,75.94 79.54,75.94 v1(79.21,76.28) 75.85,79.63 74.51,79.63 73.97,79.09 71.28,79.09 70.06,80.31 RC38.1 RC36.1
+CHGRTC: length 1.1
  BOTTOM w0.102: 180.28,110.81 v1(179.2,110.81)
+CODEC_AVDD2: length 22.8
  TOP w0.203: 48.4,19.12 48.2,19.12 47.43,19.9 47.27,19.9 46.83,20.35 UA1.40
  TOP w0.254: v2(50.64,16.97) 50.82,17.14 RA9.2 RA8.2 CA61.1 49.23,19.12 48.4,19.12 ; UA1.9 v2(42.21,25.22)
  BOTTOM w0.254: v2(42.21,25.22) 43.15,25.22 44.03,24.33 48.48,24.33 v1(48.84,23.97) 50.64,22.17 v2(50.64,16.97)
+DDR_SOC_VREF: length 11.1
  IN1 w0.254: v2(118.18,111.29) 118.18,110.61 118.73,110.06 120.02,110.06 122.6,107.47 v2(123.71,107.47)
  BOTTOM w0.254: USOC1.AF44 117.86,111.2 117.95,111.29 v2(118.18,111.29)
  BOTTOM w0.508: RC6.2 RC7.2 CC2.1 123.71,107.04 v2(123.71,107.47)
+DIMM1_VREF_CA: length 4.2
  TOP w0.508: RD4.2 v1(124.72,59.76) R1029.2 R1030.2 C1078.1
+DIMM1_VREF_DQ: length 8.4
  TOP w0.102: v1(86.05,69.21) C1076.1
  TOP w0.508: R1027.2 R1028.2 C1076.1 CD1.1 CD2.1 82.55,69.21 82.14,69.63 v4(82.14,70.34)
  BOTTOM w0.356: JDIMM1.1 82.75,69.88 82.29,70.34 v4(82.14,70.34)
+EC_VCCA: length 2
  TOP w0.254: PR10.1 198.28,72.44 v2(198.58,72.13) ; UE1.67 v2(194.79,65.55)
  vias: v1(204.18,50.45) v2(203.61,71.7) v2(204.24,71.7)
+FAN_POWER: length 0.8
  TOP w0.102: v2(48.66,103.92) v3(49.42,103.92)
+INV_PWR_SRC:
  vias: v1(225.26,174.09) v4(223.98,174.5) v4(224.64,174.46) v4(224.64,173.82)
+INV_PWR_SRC_R: length 1.5
  TOP w0.102: RV301.1 v1(223.08,174.08)
+LAN_IO: length 50
  TOP w0.203: UG1.8 68.91,38.68
  TOP w0.254: v4(49.86,72.72) 55.17,67.41 v2(56.92,67.41) ; 68.91,38.68 68.96,38.63 CG3.1 v2(69.75,39.75)
  IN1 w0.254: v2(69.75,39.75) 69.75,44.52 68.07,46.19 64.35,46.19 62.41,48.13 62.41,61.92 v2(56.92,67.41)
  BOTTOM w0.203: UL1.23 40.27,83.27 40.8,82.75
  BOTTOM w0.508: RL36.1 41.56,81.66 41.99,82.09 ; 41.1,82.45 40.8,82.75
  vias: v2(35.11,78.61) v2(35.11,78) v2(43.72,82.98) v2(43.72,82.34) v2(44.48,82.98) v2(44.53,82.32) v3(40.66,82.17) v4(49,73.15) v4(49.05,72.26) v4(49.81,73.66)
+LAN_IO_UL3: length 1.4
  BOTTOM w0.102: v1(47.45,84.2) 47.59,84.06 UL3.1
+LAN_VDD: length 10.4
  IN2 w0.508: v2(36.63,80.29) 35,81.91 v4(35,86.74)
  BOTTOM w0.203: UL1.30 37.15,81.62 36.55,81.02
  BOTTOM w0.508: v2(36.63,80.29) CL20.1 35.97,80.82 36.17,81.02 36.55,81.02
  vias: v1(34.47,86.32)
+LCDVDD: length 0.6
  TOP w0.102: v2(213.13,166.58) v3(213.13,165.97)
+LCDVDD_CONN: length 14.4
  TOP w0.508: RV31.1 210.47,173.38 211.18,172.67 211.18,170.61 215.17,166.62 v2(215.17,165.81)
  BOTTOM w0.254: JLVDS.25 216.45,172.3 ; JLVDS.24 215.95,172.33
  vias: v1(216.21,171.42)
+LCDVDD_CONN_R: length 3.3
  TOP w0.102: v1(209.48,176.93) RV31.2
  TOP w0.254: QX1.2 212.11,177.13 211.92,176.93 RV32.2 RV31.2
+MIC2-VREFO: length 14.7
  TOP w0.203: v2(42.52,17.02) 42.52,17.7 42.6,17.78 42.61,17.78 UA1.29
  TOP w0.508: RA1109.2 RA53.2 v2(35.08,21.28)
  BOTTOM w0.508: v2(42.52,17.02) 39.58,17.02 38.87,17.73 35.84,17.73 v1(35.35,18.22) 34.57,19 34.57,20.78 v2(35.08,21.28)
+RTCBATT: length 179.4
  TOP w0.102: v3(70.59,44.36) 70.26,44.03 v2(70.26,43.53)
  TOP w0.508: RG1.1 v2(70.26,43.53)
  IN2 w0.508: v2(169.14,103.6) 169.14,89.2 162.84,82.9 162.84,65.86 166.63,62.08 166.63,53.74 164.95,52.07 v2(163.35,52.07)
  BOTTOM w0.508: JBATT1.1 185,109.4 184.69,109.09 RC33.2 183.04,106.5 180.55,104.01 169.55,104.01 v2(169.14,103.6) ; v2(70.26,43.53) 85.09,43.53 91.06,49.5 149.54,49.5 151.45,51.41 157.38,51.41 158.04,52.07 v2(163.35,52.07)
+RTCBATT_R: length 4
  BOTTOM w0.102: v1(181.91,107.12) DC3.3
  BOTTOM w0.508: RC33.1 182.48,110.01 182.46,109.99 DC3.3
+RTCVCC: length 326.6
  TOP w0.508: 64.16,44.02 64.16,44.52 64.82,45.18 70.39,45.18 73.84,48.64 v2(73.84,64.29) 73.84,75.28 v2(74.58,76.02) ; 64.16,44.02 46.21,44.02 33.05,30.86 RA12.1 RA5.1 ; 64.16,44.02 64.67,43.51 RG2.1 ; v2(68.69,80.21) 68.69,87.38 74.21,92.91 74.21,102.93 71.38,105.76 71.38,109.01 72.99,110.63 72.99,112.22 73.64,112.86 77.41,112.86 80.19,110.08 83.72,110.08 v2(85.16,108.65) 87.99,108.65 v3(88,108.63) 88.83,108.63 v2(91.01,110.82)
  IN1 w0.356: v2(105.8,115.32) 105.58,115.54 104.25,115.54 101.48,112.77 94.31,112.77 92.36,110.82 v2(91.01,110.82)
  IN2 w0.508: v2(164.52,105.43) 164.52,93.37 160.79,89.63 v2(160.79,64.08)
  BOTTOM w0.254: USOC1.P22 105.97,115.15 v2(105.8,115.32)
  BOTTOM w0.305: RC35.1 91.46,110.82 v2(91.01,110.82)
  BOTTOM w0.508: RC34.1 86.62,108.65 v2(85.16,108.65) ; v2(164.52,105.43) 164.8,105.71 178.36,105.71 179.23,106.58 CC23.1 179.94,108.05 179.98,108.09 DC3.1 ; v2(160.79,64.08) 155.48,64.08 149.71,58.32 145.09,58.32 141.34,54.57 89.09,54.57 85.78,57.88 80.32,57.88 73.92,64.29 v2(73.84,64.29) ; v2(74.58,76.02) 72.88,76.02 v2(68.69,80.21)
+SOC_VCC: length 0.9
  TOP w0.102: v4(142.62,121.28) v3(143.51,121.28)
  vias: v2(107.9,113.36) v2(108.84,113.71) v2(109.4,114.25) v2(109.38,113.18) v2(109.99,115.93) v2(109.96,113.71) v2(110.49,114.31) v2(111.06,114.84) v2(111.64,116.49) v2(111.63,115.41) v2(112.19,117.04) v2(112.73,116.51) v4(138.69,121.26) v4(138.66,120.37) v4(138.66,119.61) v4(138.66,118.84) v4(139.45,121.26) v4(139.42,120.37) v4(139.42,119.61) v4(139.42,118.84) v4(140.21,121.26) v4(140.19,120.37) v4(140.19,119.61) v4(140.19,118.84) v4(141.1,121.28) v4(141.1,120.52) v4(141.1,119.76) v4(141.1,118.87) v4(141.1,118.11) v4(141.1,117.35) v4(141.86,121.28) v4(141.86,120.52) v4(141.86,119.76) v4(141.86,118.87) v4(141.86,118.11) v4(141.86,117.35) v4(142.62,120.52) v4(142.62,119.76) v4(142.62,118.87) v4(142.62,118.11) v4(142.62,117.35) v4(151.13,108.13) v4(151.24,114.96) v4(151.24,112.39) v4(151.24,110.77) v4(151.21,109.9) v4(151.16,109.07) v4(151.26,114.04) v4(151.26,113.21)
+SOC_VNN: length 1.1
  TOP w0.406: RC55.1 108.23,136.38 v2(108.31,136.45)
  vias: v2(108.92,118.07) v2(109.48,118.62) v2(109.48,117.55) v2(110.02,118.12) v2(110.57,118.67) v2(111.13,119.21) v2(111.13,118.13) v2(111.7,120.86) v2(111.69,119.77) v2(112.23,120.31) v2(113.31,119.23) v2(114.38,118.16) v2(114.92,117.63) v3(128.97,139.46) v4(120.2,141.55) v4(120.2,140.79) v4(120.2,140.03) v4(120.2,139.27) v4(120.96,141.55) v4(120.96,140.79) v4(120.96,140.03) v4(120.96,139.27) v4(125.3,140.08) v4(125.3,139.32) v4(125.3,138.55) v4(126.22,141.22) v4(126.22,140.46) v4(126.22,139.7) v4(126.22,138.94) v4(127.05,140.79) v4(127.05,140.03) v4(127.05,139.27) v4(127.05,138.5) v4(127.61,137.51) v4(127.61,136.75) v4(127.61,135.99) v4(128.38,137.51) v4(128.38,136.75) v4(128.38,135.99) v4(129.14,137.51) v4(129.14,136.75) v4(129.14,135.99) v4(129.9,137.51) v4(129.9,136.75) v4(129.9,135.99)
+SW_LX:
  vias: v1(199.94,163.05)
+SWR_V12: length 19.4
  TOP w0.508: v4(208.88,163.94) 208.78,164.03 CT11.1 208.13,160.58 205.95,158.39 v2(202.7,158.39) 201.17,159.92 v4(201.17,162.2)
  BOTTOM w0.254: UT2.27 208.85,163.96 v4(208.88,163.94) ; UT2.7 204.21,159.85 203.94,159.59
  BOTTOM w0.508: v2(202.7,158.39) CT12.1 203.48,158.75 203.94,159.21 203.94,159.59
  vias: v1(200.08,161.59)
+VDISPLAY_VCC: length 9.4
  TOP w0.508: v2(18.95,112.32) 15.09,112.32 v3(13.14,110.37) v2(12.27,109.5)
  BOTTOM w0.254: RP15.2 19.21,112.06 v2(18.95,112.32) 18.71,112.07 RP15.1
ACIN: length 354.6
  TOP w0.203: UE1.110 v2(179.61,60)
  TOP w0.254: DC1.1 96.85,109.86 96.14,110.56 96.14,113.28 92.38,117.04 88.55,117.04 86.62,118.97 86.62,121.89 89.34,124.61 v2(90.28,124.61) ; v2(179.61,60) 179.46,60.15 CE18.2 ; PR712.1 141.84,159.59 v2(142.04,159.79) ; PR710.2 PR716.1 v2(174.4,173.43) 174.26,173.29 PU700.13 ; v2(90.52,130.95) 88.74,132.73 v1(88.74,138.82) 88.74,139.65 92.91,143.81 95.43,143.81 95.84,144.22 99.95,144.22 v2(100.74,145.01) ; PR16.1 v2(127.71,172.11)
  IN2 w0.254: v2(133.76,154.66) 130.86,151.76 123.9,151.76 119.49,147.34 107.78,147.34 106.05,145.62 102.31,145.62 101.7,145.01 v2(100.74,145.01) ; v2(133.76,154.66) 134.34,154.66 137.53,151.47 155.58,151.47 164.18,160.07 v2(179,160.07) ; v2(133.76,154.66) 131.68,156.74 131.68,165.3 127.71,169.26 v2(127.71,172.11) 127.49,172.34 127.49,174.09 128.15,174.75 137.29,174.75 138.64,176.1 146.05,176.1 150.24,180.29 160.68,180.29 161.98,178.99 170.1,178.99 174.4,174.69 v2(174.4,173.43) ; v2(178.59,144.96) 175.64,142.01 175.64,107.53 176.44,106.73 176.44,90.25 173.76,87.57 173.76,84.83 172.55,83.61 169.85,83.61 166.88,80.64 166.88,67.43 168.61,65.71 v2(168.61,61.08)
  BOTTOM w0.254: v2(133.76,154.66) 136.68,154.66 140.47,158.44 140.47,159.36 140.9,159.79 v2(142.04,159.79) ; v2(179,160.07) 179.99,159.08 179.99,146.35 v2(178.59,144.96) ; v2(179.61,60) 178.99,59.38 176.86,59.38 176.58,59.66 170.03,59.66 v2(168.61,61.08) ; v2(90.52,130.95) 90.52,124.85 v2(90.28,124.61)
ACIN_65W: length 2.3
  TOP w0.102: T221.1 179.88,61.03 180.11,60.8 UE1.108
ACOFF: length 220.9
  TOP w0.254: v2(143.08,165.56) 143.23,165.4 143.28,165.4 PR718.1 ; UE1.27 193.59,49.49 193.37,49.27 193.37,48.92 193.04,48.59 193.04,46.8 194.08,45.76 194.08,41.67 193.23,40.82 190.75,40.82 v1(189.28,42.28) 188.84,42.72 177.55,42.72 176.53,43.74 v2(176.53,44.17) ; PQ713.5 v2(134.85,156.64)
  IN2 w0.254: v2(178.54,146.78) 175.01,143.25 175.01,107.26 175.81,106.46 175.81,90.87 166.45,81.51 166.45,67.33 168.08,65.7 168.08,56.89 175.01,49.96 175.01,45.69 v2(176.53,44.17) ; v2(143.08,165.56) 142.65,165.12 142.65,159.56 141.08,157.99 136.2,157.99 v2(134.85,156.64) 139.01,152.49 155.16,152.49 163.76,161.08 175.44,161.08 v2(175.54,161.19)
  BOTTOM w0.254: v2(175.54,161.19) 178.54,158.19 v2(178.54,146.78)
ACSETIN: length 5.1
  TOP w0.254: PU700.2 v1(169.89,168.64) 169.89,168.1 v4(169.94,168.06) 170.06,167.94 PR711.1
  BOTTOM w0.254: PR715.2 PC712.2 169.94,169.2 v4(169.94,168.06)
AD_BID0: length 5.9
  TOP w0.102: v1(192.48,72.32) RE3.1 RE5.2 CE8.1 192.48,68.55 191.59,67.65 UE1.75
ADP_I: length 132.7
  TOP w0.254: v2(198.4,71.45) 198.4,69.92 198.86,69.47 PR11.1 199.29,68.78 198.02,67.51 195.91,67.51 195.59,67.18 UE1.65 ; v2(184.89,156.51) 184.89,166.9 182.55,169.24 v1(179.05,169.24) 179,169.19 PC725.2 PR722.1
  IN2 w0.254: v2(191.19,79.73) 191.19,98.32 201.96,109.09 201.96,143.16 191.93,153.19 191.93,155.34 190.75,156.51 v2(184.89,156.51)
  BOTTOM w0.254: v2(191.19,79.73) 192.03,79.73 197.64,74.12 197.64,72.24 198.4,71.47 v2(198.4,71.45)
ADPIN:
  vias: v3(136.26,172.6) v3(137.32,170.13) v3(138.98,167.85) v4(136.2,169.44) v4(136.2,168.68) v4(136.96,169.44) v4(136.96,168.68) v4(137.72,169.44) v4(137.72,168.68) v4(138.48,169.44) v4(138.48,168.68)
AUD_HP_OUT_L_CN: length 24.9
  IN1 w0.254: v2(19.31,20.5) 18.62,19.81 18.62,18.87 14.38,14.63 14.38,8.15 13.23,7 JHP.1
  BOTTOM w0.254: LA8.1 20.4,15.82 20.22,16 20.22,18.29 CA39.1 20.55,20.34 DA10.3 v2(19.31,20.5)
AUD_HP_OUT_R_CN: length 16.2
  IN1 w0.254: JHP.2 13.98,18.8 16.41,21.23 20.02,21.23 20.76,20.5 v2(21.36,20.5)
  BOTTOM w0.254: v2(21.36,20.5) DA10.2 22.33,19.89 21.42,18.97 CA33.1 21.42,17.64 LA9.1
B+: length 11.8
  BOTTOM w0.508: v2(209.86,105.31) 212.91,105.31 213.34,105.74 RS6.2
  vias: v3(202.84,132.98) v4(130.48,32.76) v4(130.48,32) v4(130.48,31.24) v4(131.25,32.76) v4(131.25,32) v4(131.25,31.24) v4(132.01,32.76) v4(132.01,32) v4(132.01,31.24) v4(132.77,32.76) v4(132.77,32) v4(132.77,31.24) v4(144,155.67) v4(144,154.91) v4(144.76,155.67) v4(144.76,154.91) v4(145.52,155.67) v4(145.52,154.91) v4(146.28,155.67) v4(146.28,154.91) v4(149.03,155.73) v4(149.03,154.96) v4(149.79,155.73) v4(149.79,154.96) v4(159.87,170.76) v4(159.87,170) v4(160.63,170.76) v4(160.63,170) v4(161.4,170.76) v4(161.4,170) v4(162.16,170.76) v4(162.16,170) v4(187.61,172.57) v4(188.67,172.54) v4(189.64,172.54) v4(190.55,172.54) v4(206.12,38.45) v4(206.53,39.04) v4(206.89,38.45) v4(207.39,39.04) v4(216.54,175.89) v4(217.2,175.89) v4(218.04,176.65) v4(217.96,175.99)
B+_1.35VP: length 7.8
  BOTTOM w0.254: PR205.1 162.84,24.57 163.22,24.19 v1(163.22,23.65) 163.22,23.19 162.46,22.43 162.46,21.46 160.24,19.24
BAT_ALERT: length 5.1
  BOTTOM w0.102: PD1.2 142.75,185.07 v1(142.17,184.48)
  BOTTOM w0.254: PBATT1.3 143.52,187.17 143.27,186.92 PD1.2
BATT+: length 21.5
  TOP w0.254: PR726.2 v4(175.03,176.22)
  IN2 w0.254: v4(156.24,181.02) 160.49,181.02 162.14,179.37 170.26,179.37 173.41,176.22 v4(175.03,176.22)
  vias: v3(155.79,179.14) v4(155.48,181.68) v4(155.48,181) v4(156.24,181.73) v4(157.2,179.53) v4(157.18,178.79) v4(157.94,179.5) v4(157.94,178.79)
BATT++: length 1.7
  TOP w0.102: PL4.2 v3(152.09,184.93)
  vias: v4(153.34,186.87) v4(153.34,186.1) v4(154.11,186.87) v4(154.11,186.1) v4(154.87,186.87) v4(154.87,186.1) v4(155.63,186.87) v4(155.63,186.1)
BATT_LOW_LED#: length 174.6
  TOP w0.102: UE1.93 184.39,65.64 187.25,62.77 187.25,58.52 184.64,55.91 184.64,55.09 v2(185.05,54.68) ; RD17.1 v2(51.24,11.89)
  BOTTOM w0.102: v2(51.24,11.89) 53.01,13.66 53.01,25.7 54.67,27.35 75.63,27.35 93.22,44.95 146.62,44.95 151.93,50.26 158.24,50.26 158.92,50.95 165.49,50.95 167.55,53.01 172.63,53.01 173.52,53.9 175.26,53.9 176.15,53.01 183.3,53.01 v1(183.71,53.42) 184.97,54.68 v2(185.05,54.68)
BATT_PRS: length 24.1
  TOP w0.254: PC11.1 v2(130.63,186.01)
  BOTTOM w0.254: PBATT1.5 144.27,185.45 PD1.3 144.33,185.01 PR6.1 v1(141.01,182.7) 140.56,182.7 139.98,183.28 139.98,184.4 139.55,184.83 133.71,184.83 132.54,186.01 v2(130.63,186.01)
BATT_TEMP: length 202.6
  TOP w0.203: UE1.63 198.54,64.8 CE9.2
  TOP w0.254: v2(137.37,164.97) 137.37,164.56 137.77,164.16 PC708.1 139.17,164.16 139.68,164.67 PQ710.2 PQ710.5 ; v2(198.28,110.13) v1(198.28,93.6) 198.28,89.36 202.47,85.16 202.47,69.54 199.85,66.93 CE9.2 ; v2(135.49,161.19) 134.85,160.55 PQ713.2
  IN2 w0.254: v2(176.38,161.14) 175.95,160.7 163.92,160.7 155.32,152.11 137.98,152.11 133.71,156.38 133.71,159.41 v2(135.49,161.19) 135.49,163.09 v2(137.37,164.97) ; v2(198.28,110.13) 201.32,113.18 201.32,134.82 v2(193.58,142.57)
  BOTTOM w0.254: v2(193.58,142.57) 184,152.14 184,157.15 180.01,161.14 v2(176.38,161.14) ; PR6.2 143.74,181.79 143.72,181.81 PR7.1 143.34,180.47 141.79,178.92 141.79,166.22 141.1,165.53 137.93,165.53 v2(137.37,164.97)
BEEP#: length 10.8
  TOP w0.102: DA8.2 191.88,42.75 192.43,42.75 193.32,43.64 193.32,46.05 192.74,46.63 v1(192.74,49.12) 192.74,49.45 191.99,50.2 UE1.23
BKOFF#: length 126.9
  TOP w0.102: UE1.105 182.96,62 182.97,62 183.3,62 183.31,62 185.78,62 186.44,62.66 v2(186.44,62.66) ; v2(207.74,148.04) 205.63,150.15 204.28,150.15 201.2,153.24 199.57,153.24 196.37,156.44 196.37,157.55 196.6,157.78 v2(196.6,166.7)
  IN2 w0.127: v2(186.44,62.66) 186.44,62.66 188.12,64.34 189.13,64.34 192.23,67.44 192.23,72.15 194.08,74.01 194.08,76.02 194.59,76.53 194.59,78.43 195.46,79.3 195.46,93.42 208.87,106.83 208.87,146.91 v2(207.74,148.04)
  BOTTOM w0.102: UX2.2 v2(196.6,166.7)
BOOT1:
  vias: v1(161.06,129.44)
BOOTG:
  vias: v1(160.87,136.79)
BST:
  vias: v1(166.87,172.27) v4(166.2,171.84)
BST_1.35VP:
  vias: v1(153.65,21.56)
BST_3V:
  vias: v1(131.89,16.72)
BST_5V:
  vias: v1(126.52,16.9)
BST_CHGA: length 1.3
  BOTTOM w0.102: PR713.1 v1(164.81,171.73)
BT_LED#: length 221.2
  TOP w0.102: RD47.2 64.93,17.24 64.61,17.56 QD19.3 62.17,17.56 61.62,18.11 RD49.1 60.39,18.4 60.39,19.34 59.85,19.89 UD1.2 59.21,19.89 58.83,20.27 58.83,21.28 60.39,22.85 60.39,24.42 v1(57.74,27.07) 57.31,27.51 v2(57.31,33.22)
  IN2 w0.127: v2(57.31,33.22) 57.31,33.48 39.36,51.42 39.36,57.27 38.33,58.3 38.33,72.29 42.09,76.05 42.09,78.36 40.72,79.73 40.72,87.37 v2(34.14,93.95)
  BOTTOM w0.102: v2(34.14,93.95) 34.14,103.02 37.6,106.47 37.6,113.56 40.36,116.33 68.58,116.33 70.11,114.81 77.52,114.81 88.51,125.8 88.51,132.08 87.7,132.9 87.7,140.37 90.86,143.53 96.7,143.53 96.88,143.36 101.67,143.36 102.09,143.77 105.37,143.77 105.99,143.15 110.66,143.15 114,146.49 114,146.99 114.5,147.49 JMINI.46
BT_ON#: length 45.9
  TOP w0.102: v2(124.32,124.69) 124.82,125.19 124.82,125.74 125.06,125.98 125.11,125.98 127.08,127.95 127.08,131.82 v2(124.69,134.21) 124.46,133.98 123.98,133.98 123.6,134.36 RP54.2 ; RM13.2 115.98,147.53 116.72,146.79 116.72,143.25 v1(115.75,142.28) v2(115.75,138.68)
  IN2 w0.102: v2(116.01,119.91) 116.01,120.65 118.85,123.49 122.61,123.49
  IN2 w0.127: 122.61,123.49 122.81,123.49 123.46,124.14 123.77,124.14 v2(124.32,124.69) ; v2(124.69,134.21) 124.69,134.52 123.35,135.86 119.98,135.86 117.66,138.17 116.26,138.17 v2(115.75,138.68)
  BOTTOM w0.102: USOC1.AT28 115.8,120.09 115.98,119.91 v2(116.01,119.91)
CAPS_LED: length 127.6
  TOP w0.102: JKB.1 v2(227.45,159.85) ; v2(188.37,62.3) 185.19,65.49 UE1.91 185.19,67.97 184.83,68.33 184.83,70.27 184.53,70.56 v1(184.53,72.51)
  IN2 w0.127: v2(188.37,62.3) 188.65,62.58 189.98,62.58 195.61,68.21 195.61,69.8 196.75,70.94 196.75,75.09 200.56,78.9 200.56,81.1 211.99,92.53 211.99,144.4 v2(227.45,159.85)
CE_EN: length 140.1
  TOP w0.102: v2(218.47,159.46) 219.85,160.84 219.85,166.41 RX18.1 ; UE1.17 189.59,53.49 v2(188.78,54.3)
  IN2 w0.127: v2(218.47,159.46) 218.47,153.75 209.38,144.66 209.38,106.55 196.93,94.1 196.93,80.41 194.85,78.33 194.85,76.42 194.34,75.91 194.34,69.16 189.26,64.09 188.31,64.09 186.97,62.75 186.97,61.84 187.91,60.9 187.91,57.94 188.4,57.45 188.4,56.08 188.75,55.72 188.75,54.33 v2(188.78,54.3)
  BOTTOM w0.102: v2(218.47,159.46) v1(218.47,158.91)
CE_EN_R: length 4
  TOP w0.102: RX20.1 v1(211.64,173.81) ; RX20.1 212.55,174.37 v2(212.75,174.57) ; RX20.1 RX18.2
  BOTTOM w0.102: JLVDS.18 212.95,174.38 v2(212.75,174.57)
CHG:
  vias: v1(148.62,178.56)
CHG_B+:
  vias: v1(147.25,162.7)
CIICSCL: length 4.3
  BOTTOM w0.102: RT9.2 200.44,159.55 v1(200.78,159.89) 202.35,161.46 UT2.9
CIICSDA: length 5.2
  BOTTOM w0.102: RT11.2 199.55,159.18 v1(201.59,161.22) 202.33,161.96 UT2.10
CLK_PCIE_LAN: length 106.9
  IN2 w0.102: 102.52,124.75 102.53,124.76 102.55,124.76 102.88,125.09 103.65,125.09 103.65,125.09 103.71,125.09 v2(104.04,125.42)
  IN2 w0.127: v2(40.48,90.87) 40.66,91.05 40.66,91.94 40.51,92.09 40.51,105.34 48.23,113.05 62.84,113.05 65.21,115.42 69.22,115.42 72.09,118.29 83.37,118.29 83.62,118.54 83.62,119.07 83.37,119.33 78.41,119.33 78,119.73 78,120.32 78.41,120.73 84.48,120.73 89.28,125.53 90.75,125.53 92.31,123.97 95.6,123.97 96.98,122.59 100.36,122.59 102.52,124.75
  BOTTOM w0.102: v2(40.48,90.87) 40.76,90.59 40.76,89.6 38.88,87.72 38.88,86.84 38.75,86.71 UL1.15 ; v2(104.04,125.42) 103.92,125.3 USOC1.AF4
CLK_PCIE_LAN#: length 106.9
  IN2 w0.102: v2(103.86,124.31) 103.86,124.7 103.7,124.86 102.97,124.86 102.76,124.65 102.71,124.6 102.71,124.58 102.7,124.57
  IN2 w0.127: 102.7,124.57 100.47,122.33 96.87,122.33 95.5,123.71 92.2,123.71 90.64,125.27 89.39,125.27 84.59,120.47 78.51,120.47 78.26,120.22 78.26,119.84 78.51,119.58 83.47,119.58 83.88,119.18 83.88,118.44 83.47,118.03 72.2,118.03 69.33,115.16 65.31,115.16 62.95,112.8 48.34,112.8 40.77,105.23 40.77,92.19 40.92,92.04 40.92,90.95 41,90.87 v2(41.26,90.87)
  BOTTOM w0.102: v2(41.26,90.87) 41.1,90.87 40.98,90.74 40.98,89.51 39.09,87.63 39.09,86.79 39.15,86.74 UL1.16 ; USOC1.AF6 104.04,124.48 v2(103.86,124.31)
CLK_PCIE_WLAN: length 104.2
  IN2 w0.102: v2(104.98,124.66) 105.21,124.43 105.21,124.33 105,124.12 104.76,124.12 104.5,124.37 104.5,124.79 104.73,125.02 104.73,125.61 104.12,126.23 101.81,126.23 101.8,126.24 101.78,126.24
  IN2 w0.127: 101.78,126.24 101.21,126.24 100.98,126.46 100.98,127.44 100.61,127.82 100.08,127.82 99.71,127.44 99.71,126.46 99.49,126.24 98.23,126.24 97.86,125.86 97.86,125.34 98.23,124.96 100.7,124.96 100.93,124.74 100.93,124.42 100.7,124.2 97.45,124.2 97.08,124.56 97.08,126.72 94.99,128.82 94.46,128.82 93.42,127.78 92.87,127.22 92.87,126.27 93.47,125.66 95.66,125.66 95.89,125.44 95.89,125.12 95.66,124.89 93.05,124.89 91.6,126.34 91.6,127.04 92.32,127.76 92.32,128.29 92.05,128.56 92.05,128.88 92.28,129.1 92.59,129.1 92.86,128.83 93.66,128.83 94.11,129.28 94.11,130.96 94.54,131.39 94.54,136.96 95.01,137.43 95.92,137.43 96.29,137.8 96.29,138.33 95.92,138.71 94.47,138.71 93.43,139.75 92.16,139.75 90.5,141.41 90.5,146.13 90.72,146.35 91.04,146.35 91.26,146.13 91.26,141.87 91.64,141.5 92.16,141.5 92.54,141.87 92.54,145.69 92.79,145.95 93.15,145.95 93.4,145.69 93.4,140.96 94.72,139.64 96.34,139.64 96.72,140.02 96.72,140.55 96.51,140.76 96.51,141.08 97.01,141.58 97.43,141.58 97.8,141.96 97.8,142.49 97.43,142.86 97.01,142.86 96.79,143.08 96.79,144.04 97.11,144.36 98.68,144.36 99.06,144.73 99.06,145.26 98.68,145.63 97.9,145.63 97.68,145.85 97.68,146.17 97.9,146.39 98.68,146.39 99.06,146.77 99.06,147.3 98.68,147.67 98.04,147.67 97.82,147.89 97.82,149.5 98.1,149.78 JMINI.13
  BOTTOM w0.102: v2(104.98,124.66) 104.7,124.38 104.7,124.09 USOC1.AF7
CLK_PCIE_WLAN#: length 104.2
  IN2 w0.102: v2(105.46,124.04) 105.25,124.04 105.09,123.89 104.66,123.89 104.27,124.28 104.27,124.89 104.5,125.12 104.5,125.52 104.02,125.99 101.81,125.99 101.8,125.98 101.78,125.98
  IN2 w0.127: 101.78,125.98 101.1,125.98 100.73,126.36 100.73,127.34 100.5,127.56 100.19,127.56 99.97,127.34 99.97,126.36 99.59,125.98 98.34,125.98 98.11,125.76 98.11,125.44 98.34,125.22 100.81,125.22 101.18,124.85 101.18,124.32 100.81,123.94 97.34,123.94 96.83,124.46 96.83,126.61 94.88,128.56 94.56,128.56 93.6,127.6 93.12,127.12 93.12,126.37 93.58,125.92 95.77,125.92 96.15,125.54 96.15,125.01 95.77,124.64 92.94,124.64 91.34,126.23 91.34,127.14 92.07,127.87 92.07,128.18 91.8,128.46 91.8,128.98 92.17,129.36 92.7,129.36 92.97,129.09 93.56,129.09 93.85,129.38 93.85,131.07 94.29,131.5 94.29,137.07 94.91,137.69 95.81,137.69 96.04,137.91 96.04,138.23 95.81,138.45 94.37,138.45 93.32,139.49 92.05,139.49 90.24,141.3 90.24,146.24 90.62,146.61 91.15,146.61 91.52,146.24 91.52,141.98 91.74,141.76 92.06,141.76 92.28,141.98 92.28,145.8 92.68,146.2 93.25,146.2 93.65,145.8 93.65,141.07 94.82,139.9 96.24,139.9 96.46,140.13 96.46,140.44 96.25,140.65 96.25,141.18 96.91,141.84 97.32,141.84 97.54,142.06 97.54,142.38 97.32,142.6 96.91,142.6 96.53,142.98 96.53,144.14 97,144.61 98.58,144.61 98.8,144.84 98.8,145.15 98.58,145.37 97.8,145.37 97.43,145.75 97.43,146.28 97.8,146.65 98.58,146.65 98.8,146.87 98.8,147.19 98.58,147.41 97.94,147.41 97.56,147.79 97.56,149.52 97.3,149.78 JMINI.11
  BOTTOM w0.102: v2(105.46,124.04) 105.31,123.89 105.31,123.48
CLK_SMB: length 9.8
  BOTTOM w0.254: PR8.1 146.49,182.73 147.45,183.69 v1(147.45,184.02) PD2.3 148.2,186.87 149.69,186.87 PBATT1.7
CLR_CMOS: length 90.6
  TOP w0.508: v2(80.67,96.7) 80.39,96.98 76.44,96.98 74.84,95.37 74.84,92.65 69.4,87.2 v3(69.4,84.36) 69.4,79.83 71.5,77.72 71.5,76.6 72.56,75.55 v2(72.56,69.19)
  BOTTOM w0.508: v2(72.56,69.19) 72.79,69.19 82.41,59.56 86.59,59.56 88.8,57.35 CLRP1.1 ; R1088.1 88.35,107.57 R1089.1 88.11,106.32 88.11,105.89 86.69,104.47 86.69,101.24 83.12,97.66 81.64,97.66 v2(80.67,96.7)
CPU_B+:
  vias: v3(142.95,146.84) v4(136.63,145.18) v4(137.39,145.18) v4(138.15,145.18) v4(138.84,144.17) v4(138.81,143.38) v4(138.92,145.18) v4(139.68,145.18) v4(140.44,145.18) v4(152.35,128.37) v4(152.36,127.61) v4(152.39,126.85) v4(153.01,128.32) v4(153.06,127.56) v4(153.06,126.83)
CPU_DETECT#: length 4.9
  TOP w0.102: UE1.127 180.72,53.2 180.45,52.93 180.45,51.97 T215.1 179.71,51.23 179.53,51.23 CE33.1 RE11.1
CPU_DPB_CTRLCLK_R: length 17.7
  TOP w0.102: Q57.1 16.78,108.96 16.78,107.85 16.64,107.71 v2(16.41,107.71) 16.41,107.71 v1(14.8,107.71) 12.84,107.71 12.27,108.28 9.43,108.28 8.79,107.64 8.79,106.86 JHDMI.15
  BOTTOM w0.102: RP15.8 18.71,110.08 18.04,109.41 18.04,107.97 17.78,107.71 v2(16.41,107.71)
CPU_DPB_CTRLDAT_R: length 16.8
  TOP w0.102: Q58.1 18,108.77 17.9,108.87 17.56,108.87 17.26,108.57 17.26,107.25 16.97,106.95 v2(16.41,106.95) 16.14,107.22 10.2,107.22 JHDMI.16
  BOTTOM w0.102: RP15.7 19.21,109.9 18.52,109.21 18.52,107.77 17.87,107.12 16.58,107.12 v2(16.41,106.95)
CPU_EDP_AUX#_C: length 2.7
  BOTTOM w0.102: UT2.1 207.21,160.29 207.06,160.14 207.06,159.85 206.87,159.66 v4(206.87,159.37) 206.87,158.81 CX44.2
CPU_EDP_AUX_C: length 2.7
  BOTTOM w0.102: UT2.2 206.71,160.3 206.85,160.16 206.85,159.94 206.65,159.74 206.65,159.1 206.66,159.09 206.66,158.77 CX43.2
CPU_EDP_N0_C: length 2.6
  BOTTOM w0.102: CX46.2 204.7,158.72 204.7,159.04 204.82,159.15 204.82,159.76 204.83,159.78 204.83,160.17 204.71,160.29 UT2.6
CPU_EDP_P0_C: length 2.6
  BOTTOM w0.102: UT2.5 205.21,160.28 205.05,160.12 v4(205.05,159.5) 205.05,159.08 204.92,158.95 204.92,158.74 CX42.2
CRT_DDC_CLK: length 4.5
  TOP w0.102: R379.1 v1(106.45,133.2) 106.45,132.48 v2(107.34,131.6)
  BOTTOM w0.102: USOC1.BC1 108.21,131.72 107.47,131.72 v2(107.34,131.6)
CRT_DDC_DATA: length 5
  TOP w0.102: v1(107.76,131.29) 107.76,132.09 v2(107.72,132.13) 107.34,132.51 R380.1
  BOTTOM w0.102: USOC1.BC2 108.97,131.83 108.5,132.29 107.89,132.29 v2(107.72,132.13)
CS1: length 4
  TOP w0.102: v1(126.53,13.9) 126.53,13.19 126.77,12.95 PR105.1
  TOP w0.203: PU100.1 128.43,14.17 128.32,14.07 127.61,14.07 127.13,13.59 PR105.1
CS2: length 3.5
  TOP w0.102: PR104.2 v1(132.21,12.95)
  TOP w0.203: PU100.5 130.03,14.3 130.23,14.09 130.99,14.09 131.3,13.79 PR104.2
CS_1.35VP: length 3.4
  BOTTOM w0.102: v1(156.32,21.93) 156.87,21.93 PR201.2
  BOTTOM w0.203: PR201.2 157.37,23.89 157.29,23.97 PU200.13
CSCL: length 26
  TOP w0.102: QX6.4 201.69,154.87 202.11,155.29 v1(202.11,155.98) v4(201.17,156.92)
  IN2 w0.127: v2(209.48,162.53) 209.1,162.53 208.96,162.39 208.56,162.39 208.05,161.89 208.05,158.2 208.89,157.37 208.89,155.99 207.99,155.09 200.95,155.09 200.21,155.84 200.21,156.72 200.41,156.92 v4(201.17,156.92)
  BOTTOM w0.102: v2(209.48,162.53) 209.6,162.41 210.2,162.41 210.3,162.51 RP56.2 ; v4(201.17,156.92) 200.93,156.68 RT21.1 RT9.1
CSDA: length 24.6
  TOP w0.102: v4(198.83,156.92) 198.55,156.92 198.33,156.7 198.33,156.4 198.56,156.17 QX6.1
  IN2 w0.127: v2(209.48,161.92) 209.1,161.92 208.96,162.06 208.7,162.06 208.39,161.75 208.39,158.34 209.22,157.5 209.22,155.85 208.13,154.76 200.82,154.76 199.88,155.7 199.88,156.72 199.67,156.92 v4(198.83,156.92)
  BOTTOM w0.102: v4(198.83,156.92) 199.08,156.68 RT22.1 RT11.1 ; v2(209.48,161.92) 209.66,162.11 210.2,162.11 210.3,162.01 RP56.1
CSIN: length 27.9
  TOP w0.254: v2(168.33,166.6) PR705.1
  IN2 w0.254: v2(147.98,156.51) 147.83,156.67 147.83,157.98 148.29,158.44 158.76,158.44 167.17,166.85 168.08,166.85 v2(168.33,166.6)
  BOTTOM w0.254: PR700.3 147.6,156.13 v2(147.98,156.51)
CSIP: length 28.7
  TOP w0.254: v2(168.33,167.49) PR704.1
  IN2 w0.254: v2(147.25,156.49) 147.45,156.69 147.45,158.14 148.14,158.82 158.6,158.82 167.01,167.23 168.08,167.23 v2(168.33,167.49)
  BOTTOM w0.254: PR700.2 147.6,156.84 v2(147.25,156.49)
DAT_SMB: length 10.4
  BOTTOM w0.102: PR9.1 144.86,182.2 v1(144.86,180.72)
  BOTTOM w0.254: PBATT1.6 148.32,187.5 147.84,187.5 PD2.2 145.11,184.78 145.11,183.01 PR9.1
DBC_EN: length 146.4
  TOP w0.102: v2(193.02,49.76) 192.79,49.99 UE1.25 ; v2(219.36,159.43) 220.12,160.2 220.12,166.57 214.33,172.36 RX19.1 ; v2(204.5,83.21) v1(204.5,83.75)
  IN2 w0.127: v2(197.82,86.26) 197.82,94.25 209.91,106.34 209.91,144.47 219.36,153.92 v2(219.36,159.43) ; v2(193.02,49.76) 193.02,65.26 195.86,68.11 195.86,69.69 197.01,70.83 197.01,74.99 204.5,82.48 v2(204.5,83.21)
  BOTTOM w0.102: v2(204.5,83.21) 201.45,86.26 v2(197.82,86.26)
DBC_EN_R: length 4.5
  TOP w0.102: v1(215.51,171.83) 215.24,172.1 RX19.2 RX23.1 215.24,174.24 214.96,174.53 v2(214.45,174.53)
  BOTTOM w0.102: JLVDS.21 v2(214.45,174.53)
DBG_UART_RXD: length 1.5
  TOP w0.102: v2(114.46,126.54) 114.3,126.69 T107.1
  BOTTOM w0.102: v2(114.46,126.54) 114.28,126.72 USOC1.BC16
DBG_UART_TXD: length 1.5
  TOP w0.102: T106.1 112.8,127.73 v2(113.06,127.99)
  BOTTOM w0.102: USOC1.BD14 113.13,127.92 v2(113.06,127.99)
DCIN: length 0.9
  BOTTOM w0.508: PC711.1 167.97,175.78 v4(167.78,175.97)
  vias: v1(167.11,175.55)
DDI0_RCOMPN: length 1.5
  TOP w0.254: v2(108.26,124.03) 108.58,123.71 RC9.1
  BOTTOM w0.254: v2(108.26,124.03) 108.26,124.03 108.26,123.42 USOC1.AK13
DDI0_RCOMPP: length 1.5
  TOP w0.254: v2(107.5,123.4) 107.96,123.4 RC9.2
  BOTTOM w0.254: v2(107.5,123.4) 107.5,123.66 USOC1.AK12
DDI1_ENABLE: length 2.9
  TOP w0.102: v2(108.77,111.39) 108.32,110.94 v1(108.32,110.53) 108.32,110.16 108.48,110 RC8.1
  BOTTOM w0.102: v2(108.77,111.39) 108.72,111.44 USOC1.P30
DDI1_PWM: length 16.9
  TOP w0.102: UC4.2 102.01,97.15 RC67.1 103.61,98.75 103.61,99.26 v1(104.27,99.92) 104.91,100.56 104.91,103.74 106.26,105.09 106.26,106.64 107.5,107.88 107.5,108.46 107.09,108.87 107.09,109.6 v2(107.37,109.89)
  BOTTOM w0.102: USOC1.M30 107.71,110.22 v2(107.37,109.89)
DDR_A_BS0: length 58.8
  IN2 w0.102: 118.73,100.05 118.55,100.23 116.48,100.23 116.21,100.49 116.21,100.86 116.34,100.99 116.34,101.69 116.09,101.93 116.09,104.31 115,105.41 114.51,105.41 114.2,105.09 113.59,105.09 113.06,104.57 v2(113.06,104.15)
  IN2 w0.216: 118.73,100.05 124.08,94.7 124.08,79.87 123.87,79.65 123.57,79.65 123.36,79.87 123.36,84.98 123.15,85.19 122.85,85.19 122.63,84.98 122.63,78.33 119.6,75.3 119.6,73.36 119.05,72.81 119.05,72.36 v2(118.48,71.78)
  BOTTOM w0.165: v2(118.48,71.78) 117.91,71.78 117.55,71.42 JDIMM1.109 ; v2(113.06,104.15) 113.09,104.17 USOC1.K47
DDR_A_BS1: length 59.3
  IN2 w0.102: v2(112.17,106.24) 113.05,106.24 113.07,106.22 113.36,106.22 113.88,106.74 114.29,106.74 114.64,107.08 115.12,107.08 118.59,103.62 118.68,103.62 119,103.3
  IN2 w0.216: 119,103.3 126.75,95.55 126.75,76.45 125.88,75.59 125.54,75.59 123.55,73.6 123.55,70.72 121.41,68.58 121.41,66.31 120.7,65.6 119.84,65.6 118.36,64.12 v2(118.35,64.12)
  BOTTOM w0.165: USOC1.K44 112.08,106.15 v2(112.17,106.24) ; v2(118.35,64.12) 117.25,63.02 JDIMM1.108
DDR_A_BS2: length 54.5
  IN2 w0.102: 107.86,96.34 107.86,97.02 109.37,98.52 v2(110.09,98.52)
  IN2 w0.216: v2(105.92,71.64) 105.43,71.16 105.43,70.7 105.21,70.48 104.84,70.48 104.63,70.7 104.63,71.83 105.39,72.59 105.39,73.14 98.68,79.85 98.68,87.46 102.84,91.63 103.15,91.63 103.37,91.41 103.37,91.1 101.92,89.65 101.92,89.35 102.13,89.13 102.43,89.13 104.7,91.4 107.86,94.57 107.86,96.34
  BOTTOM w0.102: USOC1.D52 112.87,100.59 113.19,100.26 113.19,99.9 112.83,99.55 112.83,99.09 112.27,98.52 v2(110.09,98.52)
  BOTTOM w0.165: JDIMM1.79 108.55,71.32 108.23,71.64 v2(105.92,71.64)
DDR_A_CAS#: length 54.5
  IN2 w0.102: v2(112.66,105.75) 113.17,105.75 113.7,106.27 114.15,106.27 114.35,106.07 114.71,106.07 115.06,106.42 115.5,106.42 117.17,104.74 117.17,104.24 118.49,102.93
  IN2 w0.216: 118.49,102.93 126.13,95.29 126.13,76.8 125.82,76.5 125.52,76.5 125.31,76.71 125.31,77.51 125.1,77.72 124.8,77.72 124.59,77.51 124.59,75.51 121.92,72.85 121.92,71.65 121.67,71.4 121.4,71.4 v2(121.01,71.79)
  BOTTOM w0.165: v2(121.01,71.79) 121.01,72.59 120.78,72.82 119.82,72.82 119.35,72.35 JDIMM1.115 ; USOC1.M44 112.66,106.27 v2(112.66,105.75)
DDR_A_CKE0: length 57
  IN2 w0.102: 107.24,96.44 107.24,96.78 109.22,98.75 109.76,98.75 109.96,98.96 109.96,99.31 109.53,99.74 109.53,100.79 110.34,101.6 110.34,102.14 v2(110.97,102.77)
  IN2 w0.216: 107.24,96.44 107.24,94.83 104.68,92.27 102.56,92.27 98.05,87.76 98.05,79.58 103.41,74.22 103.41,70.63 104.51,69.54 104.51,66.86 106.22,65.15 106.53,65.15 106.75,65.37 106.75,65.67 105.43,66.99 105.43,69.63 v2(105.92,70.12)
  BOTTOM w0.165: v2(110.97,102.77) 110.89,102.77 USOC1.C47 ; JDIMM1.73 106.75,70.45 106.63,70.56 106.36,70.56 v2(105.92,70.12)
DDR_A_CKE2: length 57.5
  IN2 w0.102: 106.26,97.42 106.87,98.02 107.7,98.02 108.57,98.89 108.57,101.23 109.36,102.01 109.64,102.01 111.06,103.43 v2(111.06,103.88)
  IN2 w0.216: v2(107.57,63.39) 105.46,63.39 104.28,64.57 104.28,65.33 103.05,66.56 101.92,66.56 101.49,66.99 101.49,68.79 101.9,69.2 101.9,73.95 96.81,79.05 96.81,88.28 102.42,93.89 103.72,93.89 104.54,94.71 104.54,95.69 106.26,97.42
  BOTTOM w0.165: 110.56,104.19 110.63,104.19 110.95,103.88 v2(111.06,103.88) ; JDIMM1.74 107.05,62.86 v2(107.57,63.39)
DDR_A_CLK0: length 58.8
  IN2 w0.102: v2(114.1,104.25) 113.93,104.25 113.77,104.09 113.77,103.68 114.71,102.74 114.71,101.05 115.12,100.64 115.12,99.36 117.43,97.05 117.43,96.27 117.45,96.25 117.45,96.23
  IN2 w0.127: v2(115.3,72.92) 115.6,73.22 115.76,73.22 116.02,73.49 116.02,77.84 116.2,78.02 117.13,78.02 117.51,78.39 117.51,78.92 117.13,79.3 116.41,79.3 116.18,79.52 116.18,79.83 116.41,80.06 117.13,80.06 117.51,80.43 117.51,80.96 117.13,81.33 116.94,81.33 116.87,81.4 116.87,89.48 117.13,89.74 117.51,89.74 117.76,89.48 117.76,82.99 118.13,82.62 118.66,82.62 119.04,82.99 119.04,90.11 117.45,91.7 117.45,96.23
  BOTTOM w0.102: JDIMM1.101 115.15,70.4 115.39,70.63 115.39,70.92 115.95,71.49 115.95,73.1 115.82,73.23 115.61,73.23 v2(115.3,72.92) ; v2(114.1,104.25) 114.27,104.41 USOC1.M50
DDR_A_CLK0#: length 58.9
  IN2 w0.102: 117.19,96.23 117.19,96.25 117.2,96.27 117.2,96.95 114.89,99.26 114.89,100.54 114.48,100.95 114.48,102.64 113.54,103.58 113.54,104.18 113.75,104.39 v2(113.75,104.71)
  IN2 w0.127: v2(115.3,73.69) 115.51,73.48 115.65,73.48 115.77,73.6 115.77,77.95 116.1,78.28 117.03,78.28 117.25,78.5 117.25,78.82 117.03,79.04 116.3,79.04 115.93,79.41 115.93,79.94 116.3,80.31 117.03,80.31 117.25,80.54 117.25,80.85 117.03,81.08 116.84,81.08 116.61,81.3 116.61,89.59 117.02,89.99 117.61,89.99 118.02,89.59 118.02,83.1 118.24,82.88 118.56,82.88 118.78,83.1 118.78,90 117.19,91.59 117.19,96.23
  BOTTOM w0.102: JDIMM1.103 115.75,70.5 115.6,70.65 115.6,70.83 116.17,71.4 116.17,73.19 115.91,73.45 115.54,73.45 v2(115.3,73.69) ; USOC1.M48 113.92,104.88 v2(113.75,104.71)
DDR_A_CLK2: length 58.1
  IN2 w0.102: v2(115.3,104.52) 115.2,104.62 115.01,104.62 114.9,104.52 114.9,104.34 115.37,103.87 115.37,102.56 115.17,102.36 115.17,101.26 115.58,100.85 115.58,99.69 116.13,99.13 116.81,99.13 116.99,98.96 117.05,98.9 117.06,98.9 117.07,98.89
  IN2 w0.127: 117.07,98.89 118.47,97.5 118.47,92.19 120.57,90.08 120.57,79.24 120.2,78.86 119.58,78.86 119.3,79.15 119.3,81.44 119.15,81.58 118.67,81.58 118.54,81.45 118.54,78.6 118.9,78.23 118.9,77.52 118.29,76.91 117.22,76.91 117.04,76.72 117.04,72.56 116.01,71.52 116.01,64.98 116.07,64.91 116.27,64.91 v2(116.65,65.29)
  BOTTOM w0.102: JDIMM1.102 115.45,62.38 115.64,62.57 115.64,64.63 116.02,65.02 116.37,65.02 v2(116.65,65.29) ; v2(115.3,104.52) 115.31,104.52 115.47,104.68 USOC1.P50
DDR_A_CLK2#: length 58.1
  IN2 w0.102: v2(114.85,105.01) 114.85,104.8 114.67,104.61 114.67,104.24 115.14,103.77 115.14,102.66 114.94,102.46 114.94,101.17 115.35,100.76 115.35,99.59 116.04,98.9 116.72,98.9 116.88,98.74 116.88,98.72 116.89,98.71
  IN2 w0.127: 116.89,98.71 116.89,98.71 118.21,97.39 118.21,92.08 120.32,89.97 120.32,79.34 120.09,79.12 119.69,79.12 119.55,79.25 119.55,81.55 119.26,81.84 118.57,81.84 118.28,81.55 118.28,78.49 118.64,78.12 118.64,77.63 118.18,77.16 117.12,77.16 116.78,76.83 116.78,72.67 115.75,71.63 115.75,64.87 115.97,64.66 116.52,64.66 v2(116.65,64.53)
  BOTTOM w0.102: USOC1.P48 114.99,105.15 v2(114.85,105.01) ; v2(116.65,64.53) 116.38,64.8 116.11,64.8 115.86,64.54 115.86,62.58 116.05,62.39 JDIMM1.104
DDR_A_CS0#: length 63.3
  IN2 w0.102: v2(112.75,107.14) 112.75,107.94 112.63,108.06 112.63,108.41 112.86,108.64 114.42,108.64 118.02,105.04 119.9,105.04 120.32,104.62
  IN2 w0.216: v2(120.22,64.09) 121.12,64.98 122.81,64.98 128.62,70.79 128.62,96.32 120.32,104.62
  BOTTOM w0.165: JDIMM1.114 119.05,62.91 v2(120.22,64.09) ; USOC1.P44 113.44,107.14 v2(112.75,107.14)
DDR_A_CS2#: length 61.3
  IN2 w0.102: 119.44,103.74 119.14,104.04 118.45,104.04 114.46,108.03 113.38,108.03 113.16,107.82 113.16,107.27 113.25,107.19 v2(113.25,106.65)
  IN2 w0.216: v2(122.24,66.43) 122.8,66.99 122.8,69.09 123.84,70.13 124.36,70.13 124.97,69.53 125.27,69.53 125.48,69.74 125.48,70.04 125,70.52 125,70.82 125.21,71.04 125.51,71.04 125.92,70.63 126.22,70.63 126.43,70.84 126.43,71.14 125.71,71.86 125.71,72.5 125.92,72.71 126.2,72.71 126.41,72.93 126.41,73.23 126.2,73.44 125.92,73.44 125.71,73.65 125.71,74.32 127.37,75.99 127.37,95.81 119.44,103.74
  BOTTOM w0.165: USOC1.P45 113.3,106.59 v2(113.25,106.65) ; v2(122.24,66.43) 121.84,66.43 121.15,67.12 JDIMM1.121
DDR_A_D0: length 67
  IN1 w0.102: 104.93,106.71 106.26,106.71 108.51,108.96 v2(110.36,108.96)
  IN1 w0.127: 104.93,106.71 104.61,106.71 102.97,105.07 100.08,105.07 88.04,93.03 88.04,87.73 88.39,87.38 88.39,87.11 88.2,86.93 87.94,86.93 87.63,87.24 87.37,87.24 86.64,86.51 86.64,86.24 87.06,85.82 87.06,85.56 86.88,85.37 86.61,85.37 86.19,85.79 85.93,85.79 85.09,84.95 85.09,84.66 85.4,84.35 85.4,83.92 84.97,83.49 84.71,83.49 84.33,83.87 83.96,83.87 83.15,83.05 83.15,82.87 83.63,82.39 83.63,82.21 83.36,81.94 83.18,81.94 82.7,82.42 82.52,82.42 82.3,82.2 82.3,80.85 82.43,80.72 82.66,80.72 82.78,80.59 82.78,80.21 82.66,80.08 82.43,80.08 82.3,79.96 82.3,79.58 82.43,79.45 82.66,79.45 82.78,79.32 82.78,78.94 82.66,78.81 82.43,78.81 82.3,78.69 82.3,78.31 82.43,78.18 82.66,78.18 82.78,78.05 82.78,77.67 82.66,77.54 82.43,77.54 82.3,77.42 82.3,77.04 82.43,76.91 82.66,76.91 82.78,76.78 82.78,76.4 82.66,76.27 82.43,76.27 82.3,76.15 82.3,75.77 82.43,75.64 82.66,75.64 82.78,75.51 82.78,75.13 82.66,75 82.43,75 82.3,74.88 82.3,74.5 82.43,74.37 82.66,74.37 82.78,74.24 82.78,73.86 82.66,73.73 82.43,73.73 82.3,73.61 82.3,73.23 82.43,73.1 82.66,73.1 82.78,72.97 82.78,72.59 82.66,72.46 82.43,72.46 82.3,72.34 82.3,71.22 82.44,71.08 v2(82.76,71.08)
  BOTTOM w0.102: JDIMM1.5 83.95,70.32 83.19,71.08 v2(82.76,71.08) ; USOC1.M36 110.33,108.99 v2(110.36,108.96)
DDR_A_D1: length 67.1
  IN1 w0.102: v2(108.9,107.45) 108.26,107.45 106.91,106.11 106.91,105.66 106.71,105.46
  IN1 w0.127: v2(85.75,66.53) 85.43,66.22 84.92,66.22 84.59,66.55 84.59,67.23 84.59,77.93 84.77,78.11 85.25,78.11 85.44,78.3 85.44,78.56 85.25,78.75 84.77,78.75 84.59,78.93 84.59,80.55 91.23,87.2 91.23,87.44 91.1,87.57 90.38,87.57 90.25,87.7 90.25,88.08 90.38,88.2 91.1,88.2 91.23,88.33 91.23,92.41 91.1,92.54 90.81,92.54 90.68,92.66 90.68,93.05 90.81,93.17 91.1,93.17 91.82,93.88 92,93.88 92.36,93.52 92.54,93.52 92.81,93.79 92.81,93.97 92.45,94.33 92.45,94.51 97.78,99.85 98.56,99.85 98.77,100.06 98.77,100.24 98.5,100.52 98.5,100.7 98.77,100.97 98.95,100.97 99.22,100.69 99.4,100.69 99.7,100.99 99.7,101.2 99.35,101.55 99.35,101.73 99.61,102 99.79,102 100.11,101.68 100.39,101.68 100.62,101.91 100.62,102.17 100.31,102.48 100.31,102.66 100.56,102.92 100.76,102.92 101.14,102.54 101.5,102.54 101.98,103.02 103.58,103.02 104.82,104.26 105.52,104.26 106.71,105.46
  BOTTOM w0.102: v2(108.9,107.45) 108.77,107.59 USOC1.J36 ; v2(85.75,66.53) 84.55,67.73 JDIMM1.7
DDR_A_D2: length 67.3
  IN1 w0.127: v2(111.23,108.29) 111.23,106.31 108.96,104.03 108.96,102.57 107.76,101.38 105.6,101.38 104.42,100.2 102.3,100.2 99.2,97.1 98.5,97.1 96.49,95.09 96.49,88.76 90.99,83.27 90.99,83 91.17,82.82 91.44,82.82 96.02,87.4 96.29,87.4 96.47,87.22 96.47,86.95 88.69,79.17 88.69,76.59 87.36,75.26 87.36,71.9 v2(86.36,70.89)
  BOTTOM w0.102: v2(86.36,70.89) 86.95,70.3 JDIMM1.15 ; v2(111.23,108.29) 111.3,108.35 111.74,108.35 111.91,108.53 USOC1.P40
DDR_A_D3: length 66.9
  IN1 w0.102: 108.34,103.83 108.34,104.64 110.37,106.67 110.37,106.82 110.63,107.08 v2(110.63,107.72)
  IN1 w0.127: 108.34,103.83 108.34,103.68 106.65,101.99 105.36,101.99 104.15,100.79 102.05,100.79 99.23,97.97 98.38,97.97 95.9,95.49 95.9,89.04 95.71,88.85 95.45,88.85 95.27,89.04 95.27,92.7 95.08,92.88 94.82,92.88 94.63,92.7 94.63,87.76 87.92,81.05 87.92,80.78 88.1,80.6 88.37,80.6 90.33,82.56 90.59,82.56 90.78,82.37 90.78,82.11 88.1,79.43 88.1,76.9 86.78,75.58 86.78,72.84 v2(86.36,72.42)
  BOTTOM w0.102: v2(110.63,107.72) 110.63,107.73 USOC1.M40 ; v2(86.36,72.42) 87.55,71.23 JDIMM1.17
DDR_A_D4: length 67.7
  IN1 w0.102: v2(111,110.49) 110.39,109.87 108.49,109.87 106.45,107.83 105.47,107.83
  IN1 w0.127: v2(83.95,62.84) 82.12,64.66 82.12,66.23 81.06,67.29 81.06,82.61 85.83,87.39 85.83,92.48 101.18,107.83 105.47,107.83
  BOTTOM w0.102: v2(111,110.49) 110.78,110.26 USOC1.P36 ; v2(83.95,62.84) 83.65,62.54 JDIMM1.4
DDR_A_D5: length 67.3
  IN1 w0.102: 105.66,107.27 106.39,107.27 108.62,109.5 v2(110.95,109.5)
  IN1 w0.127: 105.66,107.27 104.22,107.27 104,107.04 102.73,107.04 101.49,105.8 99.98,105.8 87.43,93.25 87.43,88.16 81.64,82.37 81.64,69.56 81.83,69.37 82,69.37 82.18,69.19 82.18,68.92 82,68.74 81.83,68.74 81.64,68.55 81.64,67.54 82.73,66.44 82.73,65.58 v2(83.95,64.36)
  BOTTOM w0.102: USOC1.N36 110.95,109.49 v2(110.95,109.5) ; v2(83.95,64.36) 84.51,63.8 84.51,62.57 84.25,62.31 JDIMM1.6
DDR_A_D6: length 67.1
  IN1 w0.102: 107.76,103.95 108.09,104.29 108.09,104.68 110.13,106.72 v2(110.13,107.26)
  IN1 w0.127: 107.76,103.95 106.56,102.76 105.16,102.76 103.77,101.37 101.79,101.37 99.02,98.6 98.19,98.6 95.31,95.72 95.31,93.73 95.12,93.54 94.86,93.54 94.67,93.73 94.67,94.38 94.49,94.57 94.22,94.57 94.04,94.38 94.04,88.13 87.29,81.38 87.29,77 85.78,75.48 85.78,68.9 85.96,68.71 86.22,68.71 86.41,68.9 86.41,70.08 86.6,70.27 86.86,70.27 87.05,70.08 87.05,67.9 86.86,67.72 86.5,67.72 86.31,67.53 86.31,67.27 86.5,67.08 86.86,67.08 87.05,66.9 87.05,65.23 v2(87.91,64.36)
  BOTTOM w0.102: USOC1.K40 110.28,107.1 v2(110.13,107.26) ; v2(87.91,64.36) 87.25,63.7 JDIMM1.16
DDR_A_D7: length 67.2
  IN1 w0.127: v2(111.5,105.73) 111.5,105.17 109.53,103.19 109.53,102.54 108.44,101.45 108.44,101.27 109.62,100.09 109.62,99.91 109.35,99.64 109.17,99.64 108.85,99.96 108.67,99.96 108.33,99.62 108.15,99.62 107.88,99.89 107.88,100.07 108.22,100.41 108.22,100.59 107.99,100.82 105.89,100.82 104.69,99.62 102.55,99.62 99.31,96.38 98.62,96.38 97.08,94.84 97.08,86.68 89.28,78.88 89.28,76.31 87.95,74.98 87.95,68.42 87.69,68.16 87.69,66.08 88.52,65.25 88.52,63.96 88.77,63.71 88.77,62.07 88.65,61.95 87.18,61.95 87.02,62.1 87.02,62.66 87.2,62.84 v2(87.91,62.84)
  BOTTOM w0.102: v2(87.91,62.84) 87.85,62.78 JDIMM1.18 ; USOC1.K42 111.35,105.89 v2(111.5,105.73)
DDR_A_D8: length 52.5
  IN1 w0.127: v2(98.33,94.65) 98.33,94.39 98.28,94.33 98.28,86.09 96.24,84.05 96.24,82.9 96.15,82.81 95.97,82.81 95.54,83.24 95.36,83.24 95.09,82.97 95.09,82.79 95.52,82.36 95.52,82.18 95.25,81.91 95.07,81.91 94.64,82.34 94.46,82.34 94.19,82.07 94.19,81.89 94.62,81.46 94.62,81.28 94.07,80.73 93.89,80.73 93.46,81.16 93.28,81.16 93.01,80.89 93.01,80.71 93.44,80.28 93.44,80.1 93.17,79.83 92.99,79.83 92.56,80.26 92.38,80.26 92.11,79.99 92.11,79.81 92.54,79.38 92.54,79.2 92.27,78.93 92.09,78.93 91.66,79.36 91.48,79.36 91.21,79.09 91.21,78.91 91.64,78.48 91.64,78.3 91.26,77.92 91.08,77.92 90.94,78.06 90.76,78.06 90.49,77.79 90.49,77.61 91.09,77.01 91.09,76.39 89.57,74.88 89.57,72.84 v2(89.15,72.42)
  BOTTOM w0.102: v2(89.15,72.42) 88.53,71.79 88.53,70.57 88.75,70.35 JDIMM1.21 ; USOC1.B32 104.48,106.43 104.48,106.13 102.98,104.63 102.98,102.69 98.33,98.05 v2(98.33,94.65)
DDR_A_D9: length 52.4
  IN1 w0.127: v2(89.15,70.89) 89.18,70.86 89.18,67.77 89.01,67.59 88.75,67.59 88.53,67.81 88.53,74.72 89.86,76.05 89.86,78.59 97.69,86.42 v2(97.69,94.09)
  BOTTOM w0.102: USOC1.C32 105.3,107.25 104.87,107.25 104.7,107.08 104.7,106.94 104.28,106.52 104.28,106.31 102.47,104.5 102.47,102.98 97.69,98.2 v2(97.69,94.09) ; JDIMM1.23 89.35,70.7 v2(89.15,70.89)
DDR_A_D10: length 52.7
  IN1 w0.127: v2(104.71,98.81) 104.93,98.59 104.93,97.83 103.06,95.96 103.06,95.79 102.14,94.87 102.14,84.93 99.8,82.59 99.8,81.44 94.9,76.54 94.9,76.28 95.08,76.09 95.34,76.09 96.66,77.41 96.93,77.41 97.11,77.22 97.11,76.96 95.55,75.4 95.55,72.3 95.36,72.11 95.09,72.11 94.9,72.3 94.9,74.15 94.66,74.39 94.16,74.39 93.86,74.09 93.86,72.97 v2(93.31,72.42)
  BOTTOM w0.102: v2(104.71,98.81) 104.68,98.84 104.68,99.98 104.99,100.28 104.99,103.9 106.36,105.28 106.5,105.28 106.68,105.46 106.68,105.88 USOC1.C36 ; JDIMM1.33 92.35,71.46 v2(93.31,72.42)
DDR_A_D11: length 52.6
  IN1 w0.127: v2(93.31,70.89) 93.61,70.58 94.75,70.58 96.24,72.08 96.24,75.26 100.75,79.77 100.75,80.04 100.57,80.22 100.3,80.22 97.78,77.7 97.52,77.7 97.33,77.88 97.33,78.15 100.44,81.26 100.44,82.4 100.69,82.65 100.94,82.65 101.43,82.16 101.69,82.16 101.88,82.34 101.88,82.6 101.34,83.15 101.34,83.3 102.73,84.69 102.73,94.09 103.65,95.01 103.65,95.72 105.54,97.61 105.54,99.02 v2(105.24,99.32)
  BOTTOM w0.102: v2(105.24,99.32) 105.24,100 105.32,100.07 105.32,103.83 USOC1.A37 ; v2(93.31,70.89) 92.95,70.53 JDIMM1.35
DDR_A_D12: length 53.2
  IN1 w0.127: v2(89.65,64.14) 89.18,64.61 89.18,66.88 89.77,67.46 89.77,69.44 90.16,69.84 90.16,74.64 91.75,76.23 91.75,77.58 96.82,82.65 96.82,83.81 98.86,85.84 98.86,91.92 99.05,92.11 99.05,95.24 v2(98.9,95.39)
  BOTTOM w0.102: USOC1.C33 105.39,106.65 104.99,106.65 104.71,106.37 104.71,106 103.31,104.6 103.31,102.21 98.9,97.8 v2(98.9,95.39) ; v2(89.65,64.14) 89.05,63.54 JDIMM1.22
DDR_A_D13: length 52.6
  IN1 w0.127: v2(89.65,62.62) 90.3,63.27 90.3,64.41 90.61,64.72 90.61,64.97 90.25,65.33 90.02,65.33 89.77,65.58 89.77,66.57 89.97,66.77 90.25,66.77 90.37,66.9 90.37,69.22 90.74,69.59 90.74,74.37 92.41,76.04 92.41,77.41 97.41,82.41 97.41,83.56 99.77,85.93 99.77,95.67 v2(99.65,95.79)
  BOTTOM w0.102: USOC1.A33 104.93,106.2 104.93,105.89 103.51,104.48 103.51,101.58 99.65,97.72 v2(99.65,95.79) ; v2(89.65,62.62) JDIMM1.24
DDR_A_D14: length 52.8
  IN1 w0.127: v2(105.7,99.78) 106.15,99.32 106.15,97.39 104.23,95.48 104.23,94.74 103.31,93.82 103.31,84.45 102.58,83.71 102.58,80.77 102.33,80.53 102.07,80.53 101.52,81.08 101.26,81.08 101.07,80.89 101.07,80.63 101.62,80.08 101.62,79.82 96.84,75.03 96.84,70.79 94.28,68.23 94.28,66.92 92.89,65.53 92.89,64.88 v2(93.41,64.36)
  BOTTOM w0.102: v2(93.41,64.36) 92.65,63.6 JDIMM1.34 ; v2(105.7,99.78) 105.7,100.49 105.78,100.57 105.78,103.9 106.76,104.88 106.76,105.04 106.98,105.25 USOC1.C37
DDR_A_D15: length 51.7
  IN1 w0.127: v2(106.15,100.23) 106.76,99.63 106.76,97.18 104.82,95.24 104.82,94.31 103.89,93.38 103.89,84.2 103.2,83.51 103.2,80.57 98.2,75.57 98.2,74.88 98.4,74.68 98.63,74.68 98.76,74.55 98.76,74.17 98.63,74.04 98.33,74.04 98.2,73.92 98.2,70.01 95.57,67.39 95.57,67.21 95.85,66.93 95.85,66.66 95.67,66.48 95.4,66.48 95.13,66.76 94.95,66.76 94.19,66 94.19,63.61 v2(93.41,62.84)
  BOTTOM w0.102: v2(106.15,100.23) 106.27,100.35 106.27,104 107.07,104.8 USOC1.B38 ; JDIMM1.36 93.25,62.68 v2(93.41,62.84)
DDR_A_D16: length 57.9
  IN2 w0.102: v2(107.8,106.3) 107.78,106.27 105.97,106.27 105.06,105.36 105.06,104.8 104.96,104.7
  IN2 w0.127: 104.96,104.7 103.97,103.71 102.63,103.71 99.06,100.13 98.55,100.13 91.35,92.94 91.35,70.75 93.55,68.55 93.55,67.36 94.28,66.63 94.63,66.63 94.87,66.87 94.87,67.22 94.24,67.85 94.24,68.29 94.48,68.53 v2(94.48,71.27)
  BOTTOM w0.102: v2(107.8,106.3) 107.8,106.94 USOC1.F36 ; JDIMM1.39 94.15,70.95 v2(94.48,71.27)
DDR_A_D17: length 59.5
  IN2 w0.102: v2(109.05,106.2) 109.05,105.67 108.21,104.83 107.91,104.83 107.6,105.14 106.22,105.14 104.14,103.05
  IN2 w0.127: v2(94.48,72.8) 93.99,72.8 93.88,72.69 93.88,69.49 93.75,69.37 93.57,69.37 91.94,70.99 91.94,73.45 92.17,73.68 93.42,73.68 93.6,73.87 93.6,74.13 93.42,74.32 92.08,74.32 91.94,74.46 91.94,74.79 92.28,75.13 92.28,75.5 91.94,75.84 91.94,92.69 98.79,99.55 99.3,99.55 102.8,103.05 104.14,103.05
  BOTTOM w0.102: v2(94.48,72.8) 95.07,72.8 95.18,72.69 95.18,70.98 94.75,70.55 JDIMM1.41 ; USOC1.G38 108.95,106.58 109.05,106.48 v2(109.05,106.2)
DDR_A_D18: length 59.9
  IN2 w0.102: v2(109.82,105.51) 109.82,104.89 109.43,104.5 109.43,104.3 109,103.87 107.4,103.87 107.21,103.68
  IN2 w0.127: v2(98.79,71.91) 98.37,72.33 98.37,74.08 98,74.46 97.82,74.46 97.34,73.98 97.16,73.98 96.89,74.25 96.89,74.43 97.37,74.91 97.37,75.09 97.1,75.36 96.92,75.36 96.44,74.88 96.26,74.88 95.99,75.15 95.99,75.33 96.47,75.81 96.47,75.99 96.2,76.26 96.02,76.26 95.55,75.78 95.37,75.78 95.1,76.05 95.1,76.23 95.57,76.71 95.57,76.89 95.15,77.31 94.97,77.31 94.77,77.11 94.59,77.11 94.32,77.38 94.32,77.56 94.52,77.76 94.52,77.94 94.43,78.03 94.43,91.76 96.19,93.52 96.45,93.52 96.64,93.33 96.64,93.07 95.07,91.51 95.07,91.33 95.34,91.06 95.52,91.06 100.39,95.92 100.39,96.1 99.86,96.63 99.86,96.81 100.13,97.08 100.31,97.08 100.83,96.55 101.01,96.55 106.08,101.62 106.08,102.55 107.21,103.68
  BOTTOM w0.102: v2(109.82,105.51) 109.85,105.49 USOC1.F42 ; JDIMM1.51 97.75,70.26 98.35,70.86 98.35,71.47 v2(98.79,71.91)
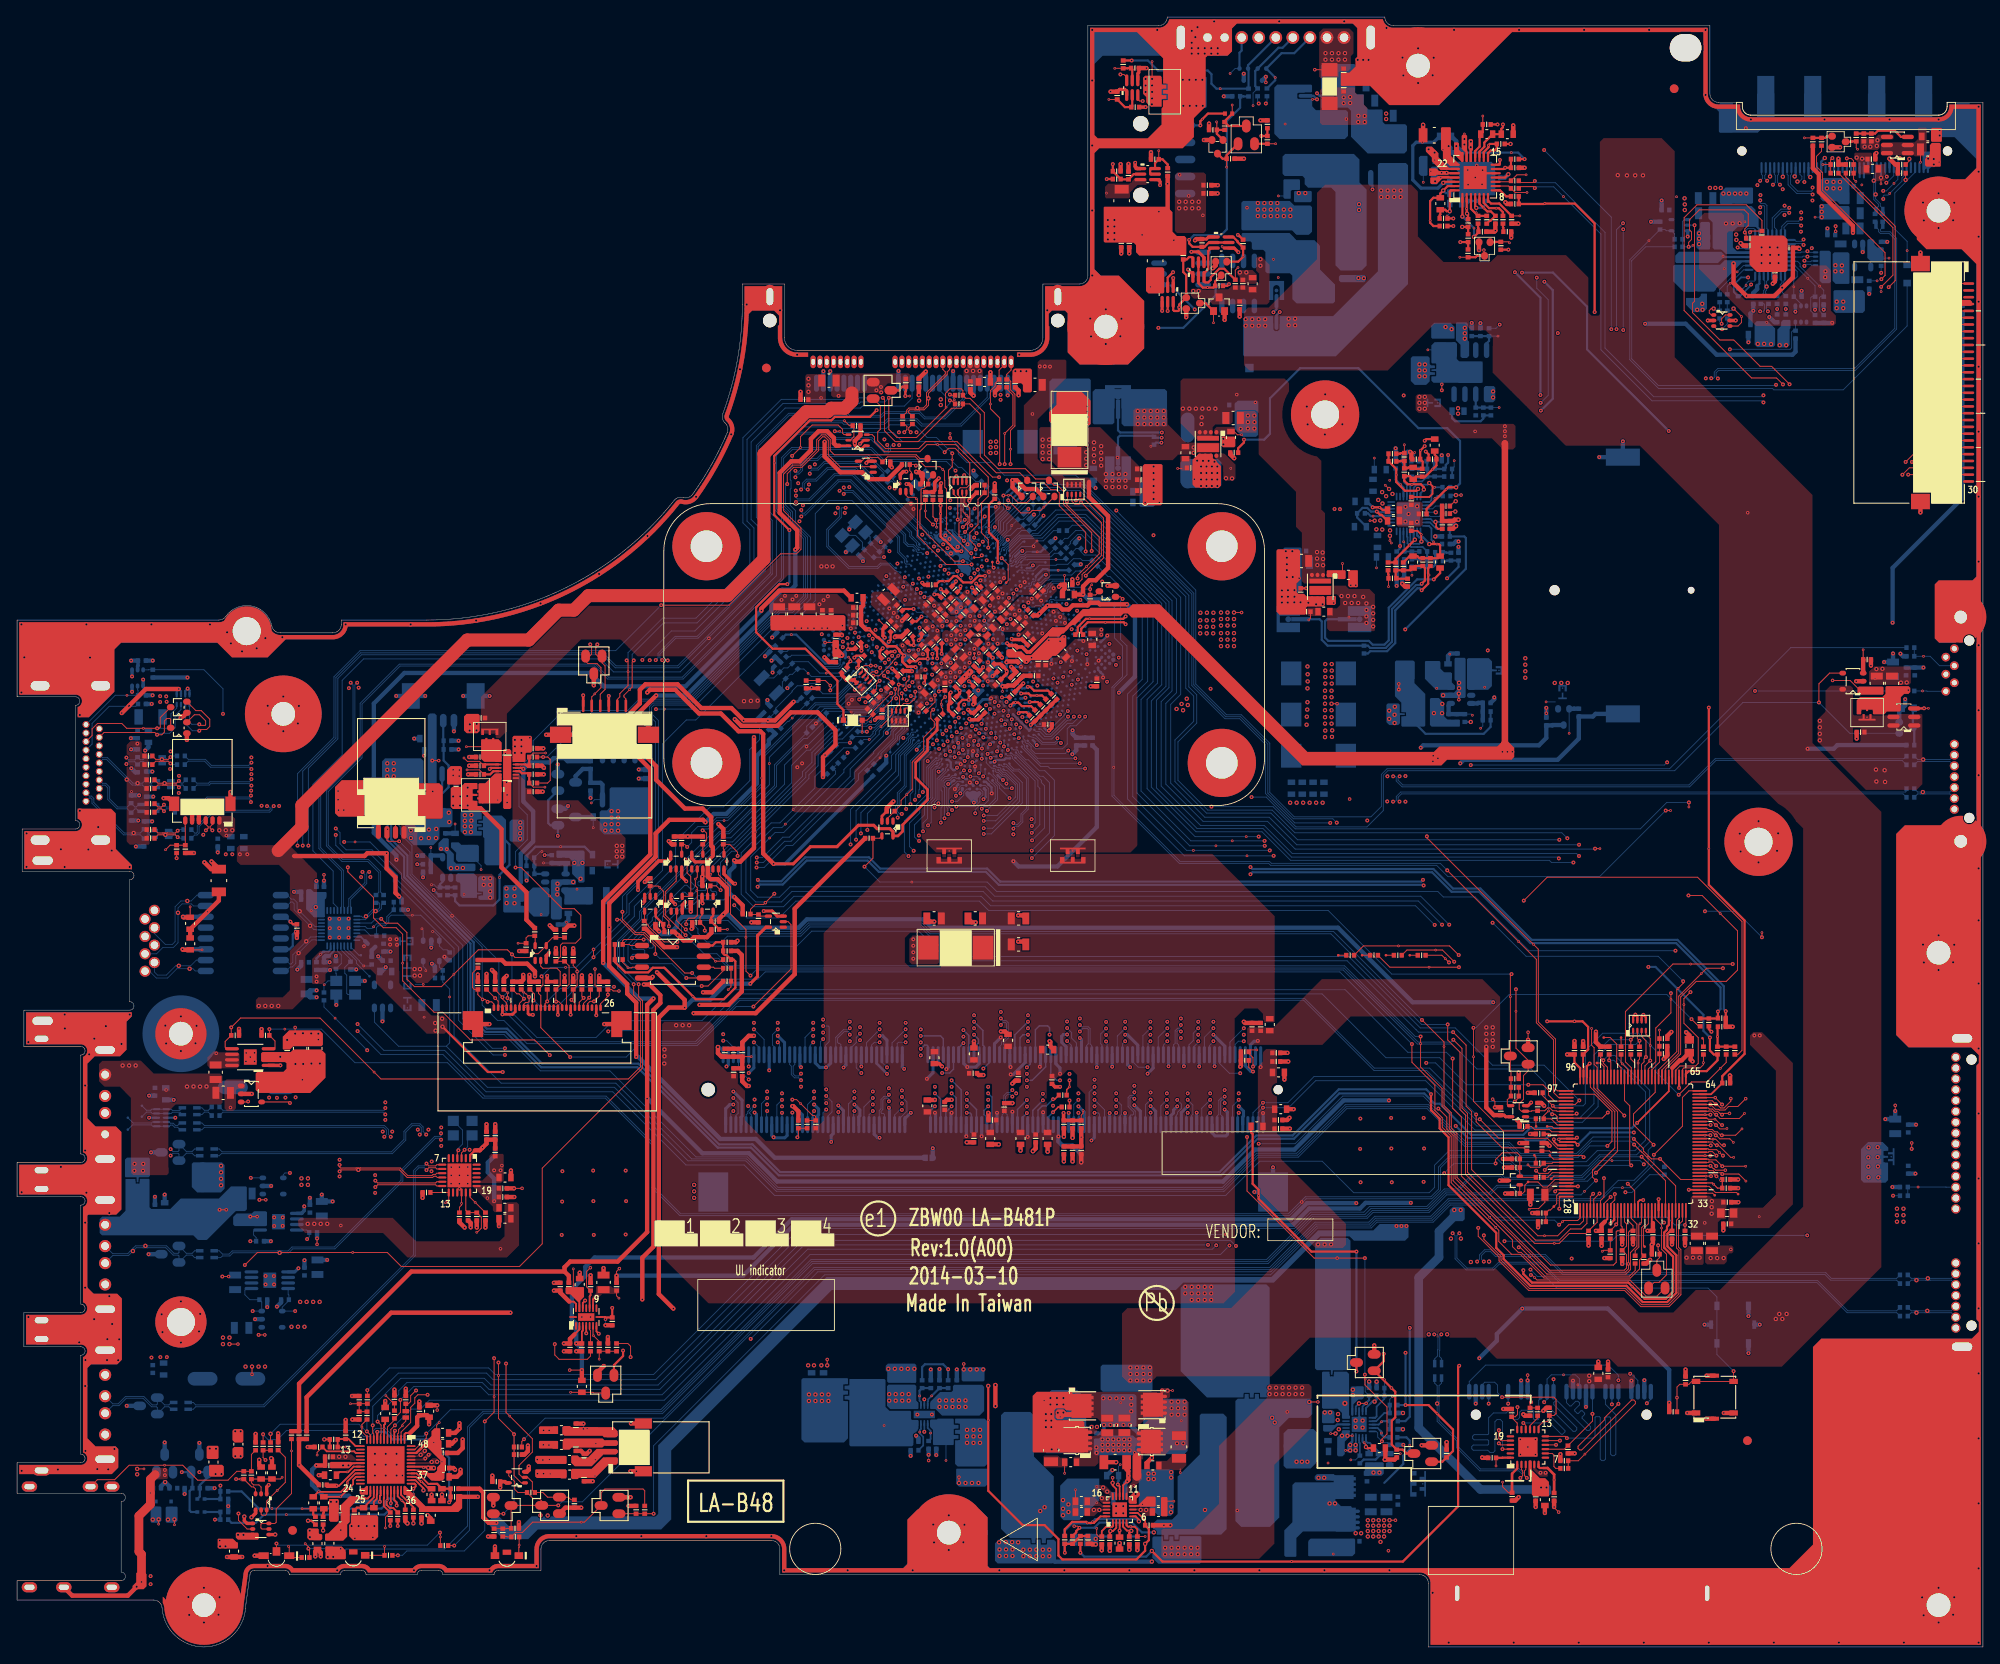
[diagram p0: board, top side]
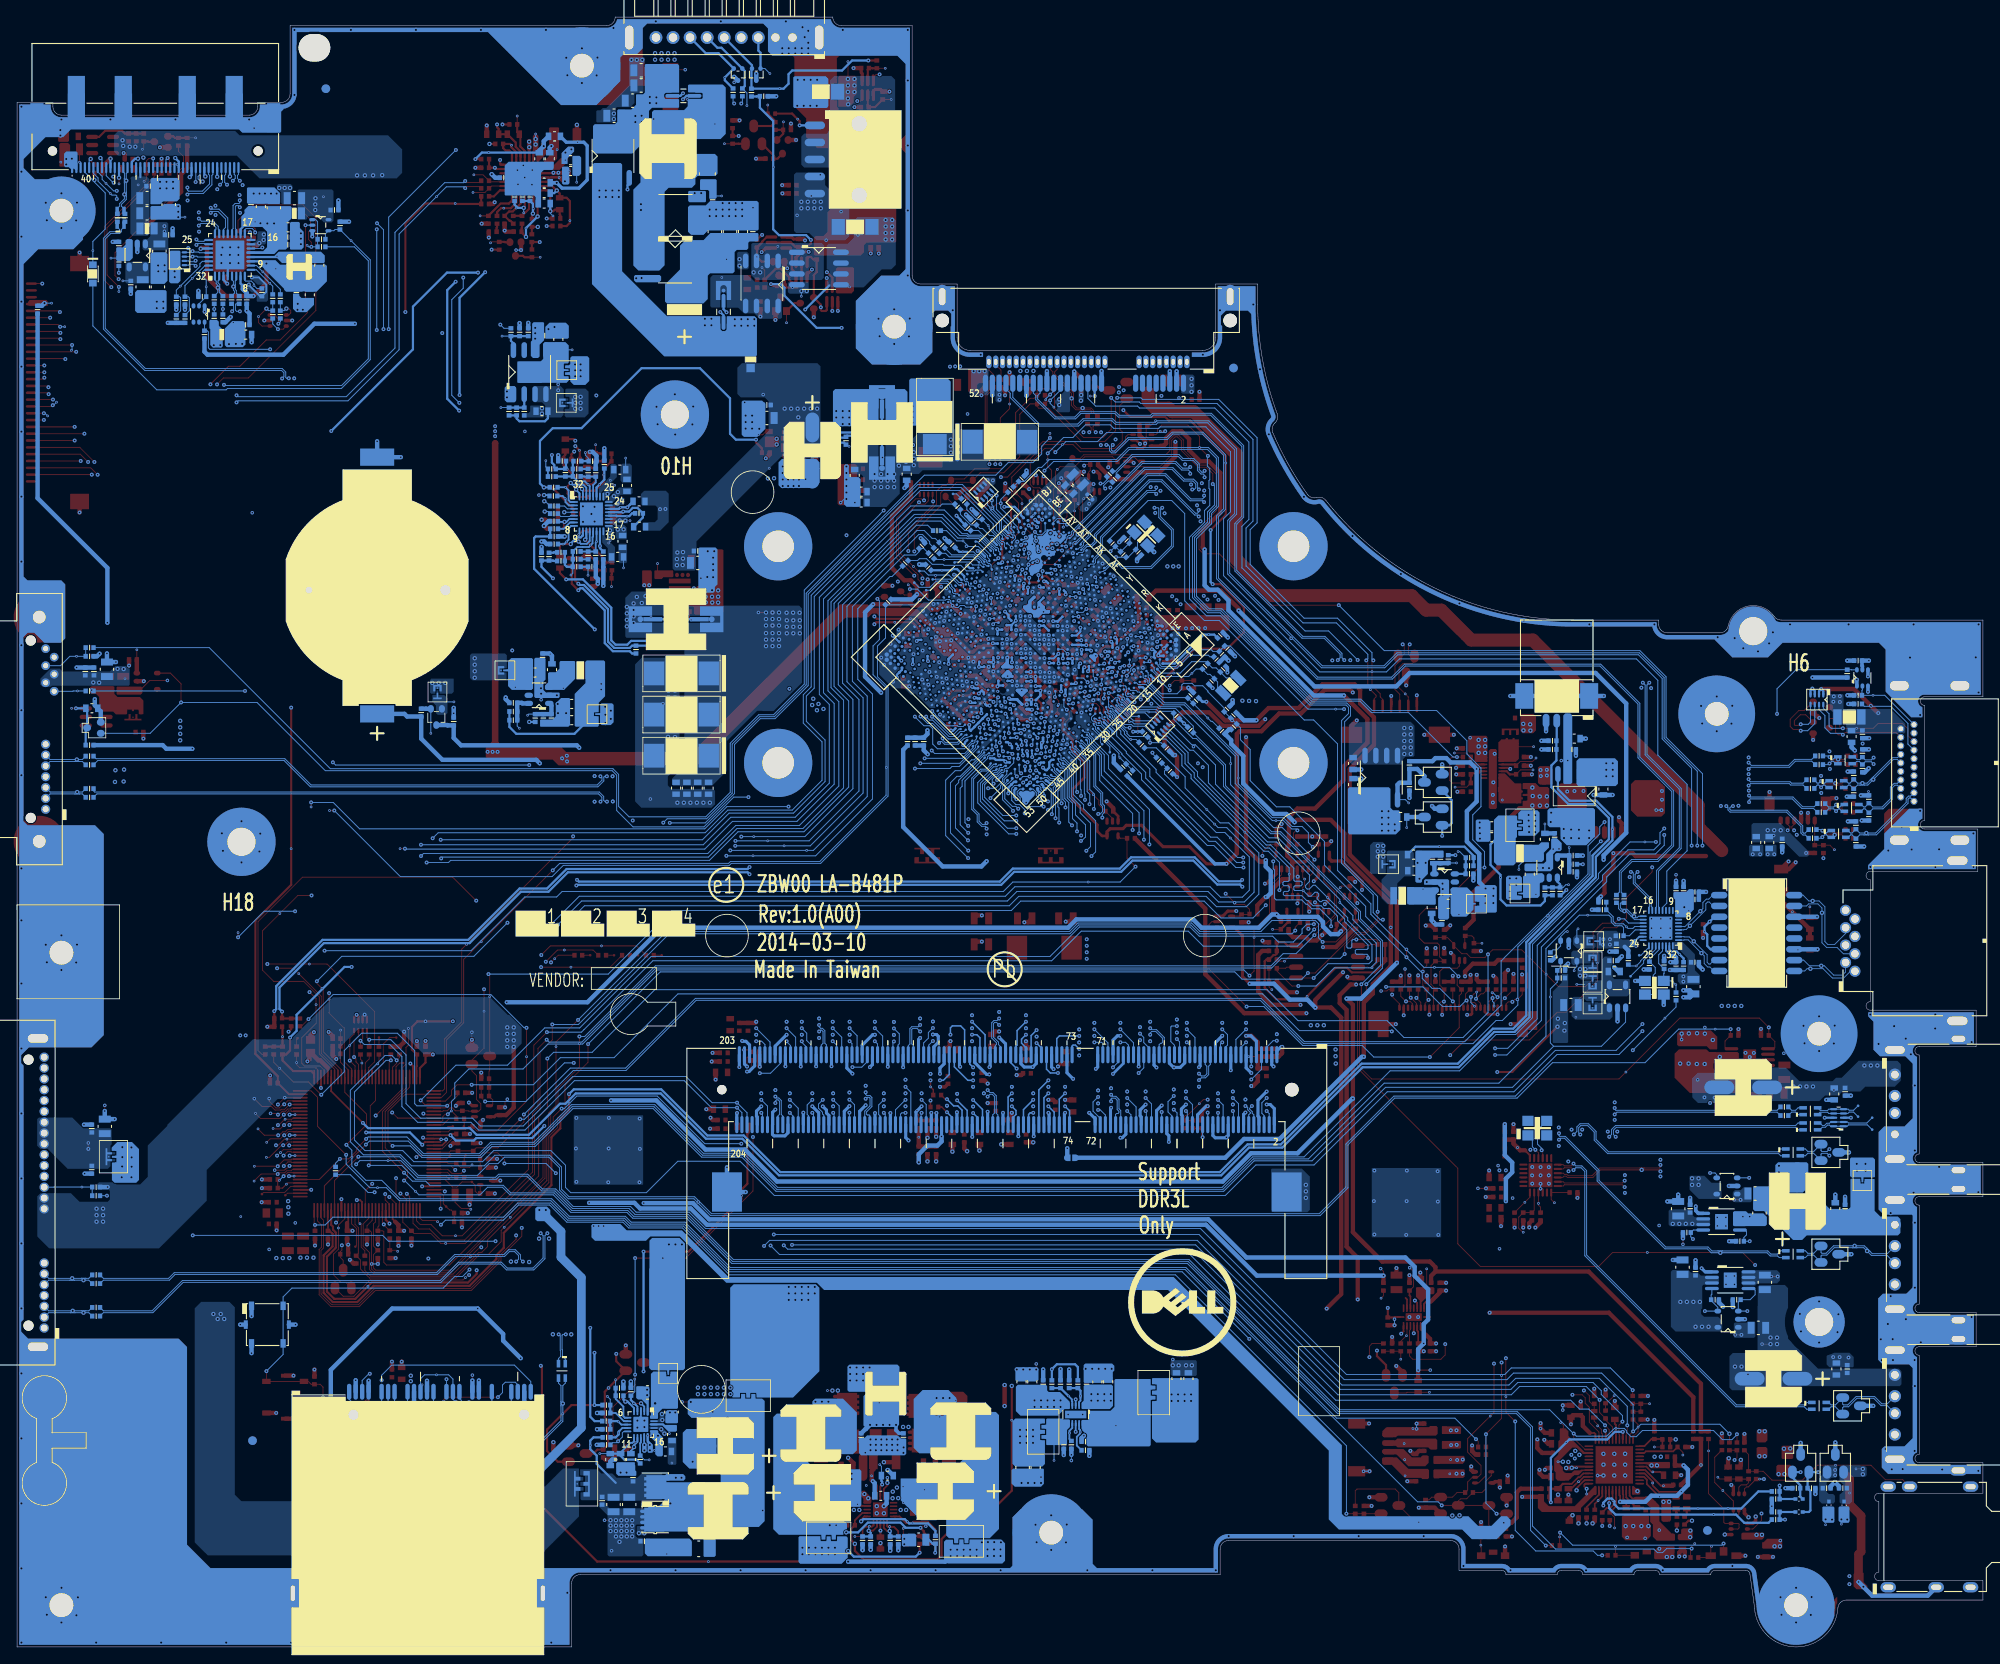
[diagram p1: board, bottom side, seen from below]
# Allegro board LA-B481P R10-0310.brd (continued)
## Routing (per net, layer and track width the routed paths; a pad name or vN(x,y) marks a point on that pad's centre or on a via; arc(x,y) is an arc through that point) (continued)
DDR_A_D19: length 59.4
  IN2 w0.102: 108.66,102.64 108.75,102.73 109.23,102.73 110.85,104.34 v2(110.85,105.18)
  IN2 w0.127: 108.66,102.64 107.78,101.76 107.78,99.82 103.91,95.95 103.91,95.57 103.09,94.76 101.99,94.76 96.18,88.95 96.18,78.79 100.61,74.35 100.61,70.18 100.86,69.93 100.86,67.11 99.69,65.94 99.69,63.25 99.49,63.05 99.19,63.05 98.95,63.3 v2(98.95,67.29)
  BOTTOM w0.102: v2(98.95,67.29) 98.35,67.89 JDIMM1.53 ; USOC1.J42 110.86,105.19 v2(110.85,105.18)
DDR_A_D20: length 60.1
  IN2 w0.102: 104.93,106.4 105.36,106.83 107.47,106.83 107.52,106.88 108.09,106.88 108.33,106.65 108.65,106.65 108.78,106.78 v2(109.55,106.78)
  IN2 w0.127: v2(94.83,63) 93.83,64 93.83,65.36 92.38,66.81 92.38,68.07 90.19,70.27 90.19,93.42 101.72,104.96 103.49,104.96 104.93,106.4
  BOTTOM w0.102: v2(109.55,106.78) 109.65,106.68 USOC1.G40 ; JDIMM1.40 94.45,62.62 v2(94.83,63)
DDR_A_D21: length 59
  IN2 w0.102: v2(108.06,105.29) 108.06,105.77 108.21,105.92 108.21,106.48 108.01,106.68 107.61,106.68 107.56,106.63 106,106.63 104.37,105
  IN2 w0.127: 104.37,105 103.69,104.32 102.42,104.32 99.6,101.5 99.09,101.5 90.77,93.18 90.77,70.51 92.97,68.31 92.97,67.05 94.42,65.6 94.42,65.02 v2(94.83,64.6)
  BOTTOM w0.102: v2(94.83,64.6) 95.51,63.93 95.51,62.72 95.05,62.26 JDIMM1.42 ; USOC1.C38 107.66,105.29 v2(108.06,105.29)
DDR_A_D22: length 59.5
  IN2 w0.102: 107.25,102.26 107.25,102.4 108.05,103.21 109.36,103.21 110.37,104.22 v2(110.37,104.78)
  IN2 w0.127: v2(98.13,64.36) 97.64,64.85 97.64,65.25 98.32,65.93 98.32,69.11 98.64,69.43 99.2,69.43 99.61,69.01 99.61,67.77 99.81,67.57 100.08,67.57 100.27,67.77 100.27,69.67 99.98,69.96 99.98,74.16 95.6,78.54 95.6,89.19 101.85,95.45 102.94,95.45 103.32,95.83 103.32,96.19 107.25,100.12 107.25,102.26
  BOTTOM w0.102: JDIMM1.50 97.45,63.68 v2(98.13,64.36) ; v2(110.37,104.78) 110.47,104.69 USOC1.G44
DDR_A_D23: length 60.1
  IN2 w0.102: 106.61,102.08 106.61,102.25 107.92,103.56 109.25,103.56 109.89,104.2 v2(109.89,104.32)
  IN2 w0.127: v2(98.13,62.84) 98.13,60.33 97.82,60.02 97.37,60.02 97.05,60.33 97.05,65.68 97.73,66.36 97.73,69.48 98.38,70.13 98.91,70.13 99.39,70.61 99.39,73.89 95.01,78.27 95.01,89.72 106.61,101.32 106.61,102.08
  BOTTOM w0.102: USOC1.D42 109.8,104.41 v2(109.89,104.32) ; JDIMM1.52 98.05,62.75 v2(98.13,62.84)
DDR_A_D24: length 49.3
  IN1 w0.127: v2(105.72,94.5) 105.72,94.1 106.1,93.72 106.1,93.45 105.72,93.07 105.72,88.08 105.9,87.89 106.31,87.89 106.5,87.71 106.5,87.44 106.31,87.26 105.9,87.26 105.72,87.07 105.72,84.42 105.98,84.16 105.98,83.7 105.72,83.44 105.72,81.03 105.9,80.84 106.43,80.84 106.62,80.65 106.62,80.39 106.43,80.21 105.9,80.21 105.72,80.02 105.72,79.21 105.62,79.11 105.35,79.11 104.93,79.53 104.66,79.53 104.48,79.35 104.48,79.08 104.9,78.66 104.9,78.39 104.72,78.21 104.45,78.21 104.03,78.64 103.76,78.64 103.58,78.45 103.58,78.19 104.01,77.76 104.01,77.49 103.82,77.31 103.56,77.31 103.13,77.74 102.86,77.74 102.68,77.55 102.68,77.29 103.11,76.86 103.11,76.6 102.92,76.41 102.66,76.41 102.23,76.84 101.96,76.84 101.78,76.66 101.78,76.39 102.21,75.96 102.21,75.7 102.02,75.51 101.76,75.51 101.33,75.95 101.06,75.95 100.88,75.76 100.88,75.5 101.31,75.06 101.31,74.8 100.66,74.15 100.66,72.61 100.86,72.42 v2(101.09,72.42)
  BOTTOM w0.102: USOC1.A41 107.71,103.48 107.54,103.48 107.09,103.03 107.09,99.65 106.35,98.91 106.35,97.56 105.19,96.4 105.19,94.96 105.64,94.5 v2(105.72,94.5) ; JDIMM1.57 99.55,70.84 v2(101.09,72.42)
DDR_A_D25: length 48.7
  IN1 w0.127: v2(106.18,95.63) 106.18,95.12 106.3,94.99 106.3,94.35 107.21,93.44 107.21,93.22 107.03,93.04 106.52,93.04 106.34,92.85 106.34,92.59 106.52,92.4 107.03,92.4 107.21,92.22 107.21,91.95 107.03,91.77 106.52,91.77 106.34,91.58 106.34,91.32 106.52,91.13 107.03,91.13 107.21,90.95 107.21,90.68 107.03,90.5 106.52,90.5 106.34,90.31 106.34,90.05 106.52,89.86 107.03,89.86 107.21,89.68 107.21,89.41 107.03,89.23 106.52,89.23 106.34,89.04 106.34,88.78 106.52,88.59 107.03,88.59 107.21,88.41 107.21,87.32 106.34,86.44 106.34,84.7 107.21,83.83 107.21,83.47 107.02,83.29 106.5,83.29 106.31,83.1 106.31,82.84 106.5,82.65 107.02,82.65 107.21,82.47 107.21,82.2 107.02,82.02 106.67,82.02 106.48,81.83 106.48,81.57 106.67,81.38 107.02,81.38 107.21,81.2 107.21,79.87 101.68,74.34 101.68,70.66 101.51,70.5 101.25,70.5 101.09,70.66 v2(101.09,70.89)
  BOTTOM w0.102: v2(101.09,70.89) 100.48,70.89 100.15,70.56 JDIMM1.59 ; v2(106.18,95.63) 106.18,96.59 106.71,97.13 106.71,98.93 107.32,99.55 107.32,102.88 107.7,103.26 107.91,103.26 108.14,103.49 108.14,103.69 108.35,103.9 USOC1.C41
DDR_A_D26: length 48.7
  IN1 w0.127: v2(104.14,72.42) 104.75,73.02 106.43,73.02 108.43,75.02 108.69,75.02 108.88,74.84 108.88,74.58 106.34,72.03 106.34,71.77 106.52,71.58 106.79,71.58 109.58,74.38 109.58,75.78 109.45,75.9 108.79,75.9 108.66,76.03 108.66,76.41 108.79,76.54 109.45,76.54 109.58,76.67 109.58,95.34 v2(108.26,96.65)
  BOTTOM w0.102: v2(108.26,96.65) 108.29,96.68 108.29,98.38 108.42,98.51 108.42,100.33 108.29,100.45 108.29,101.63 108.71,102.06 109.04,102.06 USOC1.A45 ; JDIMM1.67 102.55,70.83 v2(104.14,72.42)
DDR_A_D27: length 48.7
  IN1 w0.127: v2(104.14,70.89) 104.14,70.13 105.46,68.81 106.25,68.81 106.79,69.34 106.79,70.76 107.01,70.99 107.19,70.99 108.03,70.15 108.21,70.15 108.48,70.42 108.48,70.6 107.64,71.43 107.64,71.61 107.91,71.88 108.09,71.88 108.93,71.05 109.1,71.05 109.37,71.32 109.37,71.5 108.54,72.33 108.54,72.51 109.14,73.11 109.32,73.11 109.58,72.85 109.76,72.85 110.03,73.12 110.03,73.3 109.77,73.56 109.77,73.74 110.16,74.13 110.16,95.69 v2(108.69,97.16)
  BOTTOM w0.102: v2(104.14,70.89) 103.29,70.89 103.15,70.75 JDIMM1.69 ; USOC1.B46 109.86,102.16 109.59,102.16 109.26,101.83 108.81,101.83 108.52,101.53 108.52,100.89 108.69,100.72 v2(108.69,97.16)
DDR_A_D28: length 49.3
  IN1 w0.127: v2(105.08,93.35) 105.08,83.74 104.52,83.18 104.52,80.24 100.06,75.78 100.06,68.06 100.25,67.87 100.52,67.87 100.71,67.68 100.71,67.42 100.53,67.24 100.25,67.24 100.06,67.05 100.06,66.53 100.88,65.71 100.88,64.95 v2(100.29,64.36)
  BOTTOM w0.102: USOC1.C40 108.05,104.51 108.05,104.03 107.93,103.9 107.66,103.9 106.84,103.08 106.84,99.73 105.81,98.69 105.81,97.8 104.59,96.59 104.59,93.84 v2(105.08,93.35) ; v2(100.29,64.36) 99.25,63.32 JDIMM1.56
DDR_A_D29: length 48.9
  IN1 w0.127: v2(104.48,92.73) 104.48,83.96 103.79,83.27 103.79,80.33 99.39,75.94 99.39,62.43 99.55,62.27 100.13,62.27 100.29,62.44 v2(100.29,62.84)
  BOTTOM w0.102: v2(100.29,62.84) 99.85,62.39 JDIMM1.58 ; v2(104.48,92.73) 103.99,93.22 103.99,96.86 105.4,98.27 105.4,98.74 106.61,99.96 106.61,103.16 107.66,104.21 USOC1.B40
DDR_A_D30: length 48.2
  IN1 w0.102: 111.33,95.12 111.33,96.38 111.23,96.48
  IN1 w0.127: 111.33,95.12 111.33,72.63 111.59,72.37 111.59,69.6 110.32,68.33 110.32,68.07 110.69,67.69 110.69,67.43 110.51,67.24 110.24,67.24 109.87,67.62 109.61,67.62 108.4,66.41 107.15,66.41 v2(103.7,62.96) ; 111.23,96.48 v2(109.58,98.13)
  BOTTOM w0.102: v2(103.7,62.96) 103.45,62.96 102.85,62.37 JDIMM1.68 ; v2(109.58,98.13) 109.2,98.51 109.2,100.59 109.74,101.12 109.82,101.12 110.19,101.5 110.47,101.5 110.53,101.44 USOC1.B48
DDR_A_D31: length 48.6
  IN1 w0.127: v2(103.7,64.49) 109.28,70.06 109.54,70.06 110.2,69.4 110.46,69.4 110.64,69.59 110.64,69.85 109.99,70.51 109.99,72.23 110.75,72.99 110.75,96.02 v2(109.13,97.64)
  BOTTOM w0.102: v2(109.13,97.64) 109.07,97.7 109.07,98.32 108.96,98.43 108.96,100.75 108.72,101 108.72,101.35 108.97,101.61 109.33,101.61 109.66,101.94 109.97,101.94 110.06,101.85 USOC1.B47 ; v2(103.7,64.49) 104.3,63.9 104.3,62.82 103.45,61.98 JDIMM1.70
DDR_A_D32: length 51.4
  IN1 w0.102: 113.68,96.2 113.46,96.43 113.15,96.43 112.86,96.72 112.86,97.13 113.22,97.49 v2(113.29,97.49)
  IN1 w0.127: 113.68,96.2 113.92,95.97 113.92,95.11 113.35,94.55 113.35,79.84 117.76,75.44 119.1,75.44 120.09,74.45 120.09,74.18 118.9,72.99 118.9,72.67 119.03,72.54 119.35,72.54 120.54,73.73 120.8,73.73 120.99,73.55 120.99,73.29 119.49,71.78 119.49,71.52 119.67,71.33 119.94,71.33 121.52,72.92 121.88,72.92 122.43,72.37 122.43,71.68 v2(123.06,71.04)
  BOTTOM w0.102: JDIMM1.129 123.55,70.56 v2(123.06,71.04) ; USOC1.K52 115.5,102.32 115.79,102.32 117,101.11 117,99.62 114.87,97.49 v2(113.29,97.49)
DDR_A_D33: length 52
  IN1 w0.102: 114.14,96.86 v2(113.29,96.86)
  IN1 w0.127: v2(123.06,72.57) 122.43,73.2 119.11,76.57 118.93,76.57 118.4,76.04 118.22,76.04 117.95,76.31 117.95,76.49 118.48,77.02 118.48,77.2 118.21,77.46 118.03,77.46 117.5,76.94 117.32,76.94 117.05,77.21 117.05,77.39 117.58,77.91 117.58,78.09 117.31,78.36 117.13,78.36 116.6,77.84 116.42,77.84 116.15,78.11 116.15,78.29 116.68,78.81 116.68,78.99 116.41,79.26 116.23,79.26 115.71,78.74 115.53,78.74 115.26,79 115.26,79.18 115.78,79.71 115.78,79.89 115.51,80.16 115.33,80.16 114.81,79.63 114.63,79.63 114.36,79.9 114.36,80.08 114.88,80.61 114.88,80.79 113.98,81.69 113.98,94.35 114.6,94.97 114.6,96.54 114.28,96.86 114.14,96.86
  BOTTOM w0.102: USOC1.K51 114.68,103.31 114.87,103.11 115.18,103.11 115.3,102.99 115.3,102.81 115.56,102.55 115.85,102.55 117.25,101.14 117.25,99.41 114.69,96.86 v2(113.29,96.86) ; v2(123.06,72.57) 123.6,72.03 123.6,71.37 124.15,70.82 JDIMM1.131
DDR_A_D34: length 52.4
  IN1 w0.127: v2(127.63,72.52) 127.21,72.94 127.21,75.54 119.68,83.07 119.68,83.86 119.86,84.05 120.42,84.05 120.6,84.23 120.6,84.5 120.42,84.68 119.61,84.68 119.42,84.87 119.42,85.13 119.61,85.32 120.42,85.32 120.6,85.5 120.6,85.77 120.42,85.95 119.86,85.95 119.68,86.14 119.68,86.4 119.86,86.59 120.42,86.59 120.6,86.77 120.6,87.04 120.42,87.22 119.86,87.22 119.68,87.41 119.68,87.67 119.86,87.86 120.42,87.86 120.6,88.04 120.6,88.31 120.42,88.49 119.86,88.49 119.68,88.68 119.68,88.94 119.86,89.13 120.42,89.13 120.6,89.31 120.6,89.58 120.42,89.76 119.86,89.76 119.68,89.95 119.68,90.21 119.86,90.4 120.42,90.4 120.6,90.58 120.6,90.85 120.42,91.03 119.86,91.03 119.68,91.22 119.68,91.48 119.86,91.67 120.42,91.67 120.6,91.85 120.6,92.12 120.42,92.3 119.99,92.3 v2(118.92,93.37)
  BOTTOM w0.102: USOC1.T52 119.86,102.08 120.25,102.08 121.01,101.32 121.01,95.45 v2(118.92,93.37) ; v2(127.63,72.52) 127,71.89 127,70.72 127.15,70.57 JDIMM1.141
DDR_A_D35: length 52
  IN1 w0.127: v2(118.94,92.49) 118.51,92.07 118.51,83.41 119.11,82.81 119.11,82.63 118.52,82.04 118.52,81.86 118.79,81.59 118.97,81.59 119.56,82.18 119.74,82.18 120.01,81.91 120.01,81.73 119.42,81.14 119.42,80.96 119.69,80.69 119.87,80.69 120.46,81.28 120.64,81.28 126.62,75.29 126.62,69.24 126.88,68.98 127.38,68.98 127.61,69.21 127.61,70.97 v2(127.63,70.99)
  BOTTOM w0.102: v2(127.63,70.99) 127.75,70.88 JDIMM1.143 ; USOC1.T51 116.76,105.18 117.21,105.18 117.37,105.02 117.37,104.86 118.22,104.01 118.53,104.01 119.8,102.74 120.45,102.74 121.57,101.62 121.57,95.12 v2(118.94,92.49)
DDR_A_D36: length 52.2
  IN1 w0.127: v2(113.29,95.32) 112.77,94.8 112.77,79.51 116.88,75.4 116.88,71.73 120.59,68.01 122.07,68.01 122.91,67.18 122.91,65.63 v2(124.39,64.15)
  BOTTOM w0.102: v2(113.29,95.32) 114.17,95.32 117.81,98.96 117.81,101.35 115.96,103.2 115.56,103.2 115.35,103.41 USOC1.L51 ; v2(124.39,64.15) 123.85,63.61 JDIMM1.130
DDR_A_D37: length 51
  IN1 w0.127: v2(124.39,62.62) 124.05,62.62 119.15,67.52 119.15,68.63 116.3,71.48 116.3,74.94 111.92,79.32 111.92,94.84 113.07,95.99 v2(113.29,95.99)
  BOTTOM w0.102: v2(124.39,62.62) 124.45,62.56 JDIMM1.132 ; USOC1.L53 115.74,102.77 116,102.77 117.5,101.26 117.5,99.16 114.34,95.99 v2(113.29,95.99)
DDR_A_D38: length 52.5
  IN1 w0.127: v2(126.28,62.62) 125.08,63.82 125.08,67.2 125.45,67.57 125.45,73.94 121.81,77.59 121.13,77.59 116.9,81.82 116.9,91.4 117.31,91.82 117.31,93.86 118.02,94.57 v2(118.96,94.57)
  BOTTOM w0.102: JDIMM1.140 126.85,62.47 126.7,62.62 v2(126.28,62.62) ; USOC1.R51 116.58,104.79 116.79,104.57 117.08,104.57 120.04,101.61 120.04,101.34 120.42,100.96 120.42,96.04 v2(118.96,94.57)
DDR_A_D39: length 51.8
  IN1 w0.127: v2(126.28,64.15) 125.69,64.74 125.69,66.98 126.04,67.33 126.04,74.33 122.13,78.24 121.3,78.24 120.85,78.68 120.85,78.95 121.15,79.25 121.15,79.51 120.97,79.7 120.7,79.7 120.4,79.4 120.14,79.4 117.92,81.62 117.92,93.34 118.56,93.98 119.23,93.98 119.56,94.31 119.56,94.82 v2(118.93,95.45)
  BOTTOM w0.102: v2(118.93,95.45) 119.87,96.39 119.87,100.68 119.64,100.91 119.64,101.62 USOC1.R53 ; v2(126.28,64.15) 127.45,62.98 JDIMM1.142
DDR_A_D40: length 62.2
  IN1 w0.102: v2(115.23,106.04) 115.23,105.13 115.83,104.53 115.83,103.37
  IN1 w0.127: 115.83,103.37 115.83,102.85 123.68,95.01 123.68,83.81 123.49,83.62 123.23,83.62 123.04,83.81 123.04,87.03 122.86,87.21 122.59,87.21 122.41,87.03 122.41,82.82 128.31,76.91 128.49,76.91 128.76,77.18 128.76,77.36 126.07,80.05 126.07,80.32 126.25,80.5 126.52,80.5 129.65,77.37 129.65,73.73 129.45,73.53 129.45,72.96 v2(129.87,72.54)
  BOTTOM w0.102: v2(129.87,72.54) 128.95,71.62 JDIMM1.147 ; v2(115.23,106.04) 115.18,106.08 USOC1.T47
DDR_A_D41: length 61
  IN1 w0.127: v2(129.87,71.02) 129.87,70.62 129.72,70.47 129.11,70.47 128.87,70.72 128.87,75.53 121.8,82.59 121.8,94.48 121.97,94.64 122.23,94.64 122.44,94.43 122.44,88 122.63,87.81 122.89,87.81 123.07,88 123.07,94.78 114.98,102.88 114.98,104.13 114.39,104.72 114.39,105.27 114.61,105.49 114.61,106.51 v2(114.69,106.59)
  BOTTOM w0.102: v2(114.69,106.59) 114.68,106.6 114.68,107.28 ; JDIMM1.149 129.55,70.7 v2(129.87,71.02)
DDR_A_D42: length 61
  IN1 w0.102: 117.96,105.15 117.46,105.64 116.98,105.64 113.52,109.11 113.52,110.37 113.57,110.41 v2(113.57,110.41)
  IN1 w0.127: 117.96,105.15 118.69,104.41 118.69,104.26 127.82,95.13 127.82,90.75 127.69,90.63 127.11,90.63 126.98,90.5 126.98,90.12 127.11,89.99 127.69,89.99 127.82,89.86 127.82,89.48 127.69,89.36 127.11,89.36 126.98,89.23 126.98,88.85 127.11,88.72 127.69,88.72 127.82,88.59 127.82,88.21 127.69,88.09 127.11,88.09 126.98,87.96 126.98,87.58 127.11,87.45 127.99,87.45 128.17,87.26 128.17,87 127.99,86.82 127.11,86.82 126.98,86.69 126.98,86.31 127.11,86.18 128.82,86.18 129.01,85.99 129.01,85.73 128.82,85.55 127.11,85.55 126.98,85.42 126.98,85.04 127.11,84.91 128.65,84.91 128.91,84.66 128.91,82.29 133.25,77.94 133.25,72.97 v2(132.82,72.54)
  BOTTOM w0.102: JDIMM1.157 131.95,71.67 v2(132.82,72.54) ; v2(113.57,110.41) 113.8,110.65 USOC1.Y40
DDR_A_D43: length 61.8
  IN1 w0.102: 118.47,105.44 117.79,106.13 116.79,106.13 114.02,108.89 v2(114.02,109.98)
  IN1 w0.127: 118.47,105.44 119.27,104.64 119.27,104.5 128.5,95.27 128.5,88.35 128.69,88.16 128.95,88.16 129.14,88.35 129.14,93.33 129.32,93.52 129.59,93.52 129.77,93.33 129.77,82.81 134.17,78.41 134.17,72.36 v2(132.82,71.02)
  BOTTOM w0.102: USOC1.V41 113.84,109.79 v2(114.02,109.98) ; v2(132.82,71.02) 132.55,70.74 JDIMM1.159
DDR_A_D44: length 62
  IN1 w0.102: v2(115.66,105.58) 115.66,105.06 116.25,104.46 116.25,103.26 119.61,99.9
  IN1 w0.127: 119.61,99.9 124.31,95.2 124.31,83.62 123.63,82.93 123.63,82.42 125.37,80.68 125.55,80.68 125.81,80.95 125.81,81.13 124.5,82.45 124.5,82.71 124.69,82.9 124.95,82.9 130.46,77.39 130.46,69.98 128.89,68.42 128.89,67.16 128.71,66.97 128.42,66.97 128.17,66.72 128.17,66.5 128.33,66.34 128.83,66.34 128.98,66.18 128.98,65.82 128.04,64.88 127.14,64.88 126.95,64.69 126.95,64.43 127.14,64.24 128.04,64.24 128.23,64.06 128.23,63.21 v2(128.82,62.62)
  BOTTOM w0.102: v2(115.66,105.58) 115.68,105.6 USOC1.T48 ; JDIMM1.146 128.65,62.46 v2(128.82,62.62)
DDR_A_D45: length 62
  IN1 w0.102: 120.03,100.31 116.58,103.75 116.58,104.7 v2(116.12,105.17)
  IN1 w0.127: 120.03,100.31 124.9,95.44 124.9,83.78 131.04,77.63 131.04,69.74 129.63,68.33 129.63,65.32 130.16,64.79 130.16,63.33 130.55,62.94 131.28,62.94 131.5,63.15 131.5,63.52 131.71,63.73 132.01,63.73 132.23,63.52 132.23,62.39 131.94,62.1 129.68,62.1 129.42,62.37 129.42,63.97 129.25,64.15 v2(128.82,64.15)
  BOTTOM w0.102: v2(128.82,64.15) 129.42,63.55 129.42,62.42 129.25,62.25 JDIMM1.148 ; USOC1.T50 116.14,105.19 v2(116.12,105.17)
DDR_A_D46: length 62.1
  IN1 w0.102: 116.55,109.5 116.41,109.64 115.75,109.64 v2(115.62,109.77)
  IN1 w0.127: 116.55,109.5 119.16,106.89 119.87,106.89 120.61,106.15 120.61,104.97 131.28,94.3 131.28,86.41 131.46,86.22 131.72,86.22 131.91,86.41 131.91,86.96 132.1,87.15 132.36,87.15 132.55,86.96 132.55,81.71 135.94,78.31 135.94,70.41 133.4,67.87 133.4,64.72 v2(132.85,64.17)
  BOTTOM w0.102: USOC1.Y42 115.5,109.64 v2(115.62,109.77) ; JDIMM1.158 132.25,63.57 v2(132.85,64.17)
DDR_A_D47: length 62.3
  IN1 w0.102: v2(114.58,110.79) 115.23,110.79 116.04,109.98 116.9,109.98
  IN1 w0.127: 116.9,109.98 117.49,109.98 121.22,106.25 121.22,105.18 131.89,94.52 131.89,88.47 133.13,87.23 133.13,81.95 136.56,78.52 136.56,74.7 136.84,74.41 136.84,69.39 135.85,68.4 135.85,66.79 134.22,65.16 134.22,64.01 v2(132.85,62.65)
  BOTTOM w0.102: USOC1.AB40 114.73,110.93 v2(114.58,110.79) ; JDIMM1.160 v2(132.85,62.65)
DDR_A_D48: length 68.8
  IN2 w0.102: v2(115.81,108.18) 116.55,108.18 117.37,107.36 117.72,107.36 118.2,106.88 121.01,106.88 121.55,107.42 122.05,107.42
  IN2 w0.127: 122.05,107.42 122.51,107.42 132.23,97.7 132.23,96.13 132.41,95.94 133.9,95.94 134.08,95.76 134.08,95.49 133.9,95.31 132.41,95.31 132.23,95.12 132.23,94.86 132.41,94.67 133.9,94.67 134.08,94.49 134.08,94.22 133.9,94.04 132.41,94.04 132.23,93.85 132.23,93.59 132.41,93.4 133.9,93.4 134.08,93.22 134.08,92.95 133.9,92.77 132.41,92.77 132.23,92.58 132.23,92.32 132.41,92.13 133.9,92.13 134.08,91.95 134.08,91.68 133.9,91.5 132.41,91.5 132.23,91.31 132.23,91.05 132.41,90.86 133.9,90.86 134.08,90.68 134.08,90.41 133.9,90.23 132.41,90.23 132.23,90.04 132.23,89.72 132.54,89.4 134.01,89.4 134.37,89.05 134.37,72.98 v2(134.81,72.54)
  BOTTOM w0.102: v2(115.81,108.18) 115.57,107.95 USOC1.V45 ; v2(134.81,72.54) 133.75,71.49 JDIMM1.163
DDR_A_D49: length 70.7
  IN2 w0.102: v2(116.34,107.65) 116.79,107.65 117.28,107.16 117.64,107.16 118.15,106.65 121.24,106.65 121.53,106.94 121.95,106.94
  IN2 w0.127: 121.95,106.94 122.12,106.94 131.63,97.42 131.63,88.95 131.82,88.76 133.33,88.76 133.52,88.58 133.52,88.32 133.33,88.13 131.82,88.13 131.63,87.94 131.63,87.68 131.82,87.49 133.33,87.49 133.52,87.31 133.52,87.05 133.33,86.86 131.82,86.86 131.63,86.67 131.63,86.41 131.82,86.22 133.33,86.22 133.52,86.04 133.52,85.78 133.33,85.59 131.82,85.59 131.63,85.4 131.63,85.14 131.82,84.95 133.33,84.95 133.52,84.77 133.52,84.51 133.33,84.32 131.82,84.32 131.63,84.13 131.63,83.87 131.82,83.68 133.33,83.68 133.52,83.5 133.52,83.24 133.33,83.05 131.82,83.05 131.63,82.86 131.63,82.6 131.82,82.41 133.33,82.41 133.52,82.23 133.52,81.97 133.33,81.78 131.82,81.78 131.63,81.59 131.63,81.29 131.9,81.02 133.48,81.02 133.78,80.72 133.78,72.04 v2(134.81,71.02)
  BOTTOM w0.102: 115.85,107.45 116.14,107.45 v2(116.34,107.65) ; JDIMM1.165 134.35,70.56 v2(134.81,71.02)
DDR_A_D50: length 70.8
  IN2 w0.102: v2(117.82,109.03) 118.12,109.33 119.69,109.33 120,109.63
  IN2 w0.127: 120,109.63 121.09,110.72 125.41,110.72 128.14,107.99 128.14,105.98 128.39,105.73 128.66,105.73 129.38,106.45 129.64,106.45 129.83,106.26 129.83,106 129.1,105.28 129.1,105.01 129.29,104.83 129.55,104.83 130.28,105.55 130.54,105.55 130.73,105.37 130.73,105.1 130,104.38 130,104.12 130.19,103.93 130.45,103.93 131.17,104.65 131.44,104.65 131.62,104.47 131.62,104.2 130.9,103.48 130.9,103.22 139.53,94.59 139.53,79.3 139.34,79.11 138.63,79.11 138.45,78.93 138.45,78.66 138.63,78.48 139.34,78.48 139.53,78.29 139.53,78.03 139.34,77.84 138.63,77.84 138.45,77.66 138.45,77.39 138.63,77.21 139.34,77.21 139.53,77.02 139.53,76.76 139.34,76.57 138.63,76.57 138.45,76.39 138.45,76.12 138.63,75.94 139.34,75.94 139.53,75.75 139.53,75.49 139.34,75.3 138.63,75.3 138.45,75.12 138.45,74.85 138.63,74.67 139.34,74.67 139.53,74.48 139.53,74.05 138.95,73.47 138.95,73.06 v2(138.43,72.54)
  BOTTOM w0.102: v2(117.82,109.03) USOC1.AD48 ; v2(138.43,72.54) 137.85,71.96 137.85,71.1 137.35,70.6 JDIMM1.175
DDR_A_D51: length 71.1
  IN2 w0.102: 120.74,109.45 120.24,108.94 119.46,108.94 119.02,108.51 v2(118.33,108.51)
  IN2 w0.127: v2(138.43,71.02) 137.85,71.6 137.85,80.51 138.43,81.1 138.81,81.1 138.94,81.23 138.94,81.61 138.81,81.73 137.97,81.73 137.85,81.86 137.85,82.24 137.97,82.37 138.81,82.37 138.94,82.5 138.94,82.88 138.81,83 137.97,83 137.85,83.13 137.85,83.51 137.97,83.64 138.81,83.64 138.94,83.77 138.94,84.15 138.81,84.27 137.97,84.27 137.85,84.4 137.85,84.78 137.97,84.91 138.81,84.91 138.94,85.04 138.94,85.42 138.81,85.54 137.97,85.54 137.85,85.67 137.85,86.05 137.97,86.18 138.81,86.18 138.94,86.31 138.94,86.69 138.81,86.81 137.97,86.81 137.85,86.94 137.85,87.32 137.97,87.45 138.81,87.45 138.94,87.58 138.94,87.96 138.81,88.08 137.97,88.08 137.85,88.21 137.85,88.59 137.97,88.72 138.81,88.72 138.94,88.85 138.94,89.23 138.81,89.35 137.97,89.35 137.85,89.48 137.85,89.86 137.97,89.99 138.81,89.99 138.94,90.12 138.94,90.5 138.81,90.62 137.97,90.62 137.85,90.75 137.85,91.13 137.97,91.26 138.81,91.26 138.94,91.39 138.94,91.77 138.81,91.89 137.97,91.89 137.85,92.02 137.85,95.45 127.41,105.88 127.41,107.57 124.78,110.19 121.49,110.19 120.74,109.45
  BOTTOM w0.102: USOC1.AD50 118.67,108.51 v2(118.33,108.51) ; JDIMM1.177 137.95,70.41 138.43,70.9 v2(138.43,71.02)
DDR_A_D52: length 69.2
  IN2 w0.102: v2(116.87,107.02) 117.14,107.02 117.2,106.96 117.55,106.96 118.12,106.39 121.15,106.39 121.59,105.95
  IN2 w0.127: v2(134.75,64.15) 133.93,64.97 133.93,67.53 132.39,69.07 132.39,69.72 132.52,69.85 133.07,69.85 133.2,69.97 133.2,70.35 133.07,70.48 132.52,70.48 132.39,70.61 132.39,75.25 130.98,76.66 130.98,77.05 131.17,77.23 132.97,77.23 133.16,77.42 133.16,77.68 132.97,77.87 131.17,77.87 130.98,78.05 130.98,78.32 131.17,78.5 132.97,78.5 133.16,78.69 133.16,78.95 132.97,79.14 131.17,79.14 130.98,79.32 130.98,79.59 131.17,79.77 132.97,79.77 133.16,79.96 133.16,80.22 132.97,80.41 131.17,80.41 130.98,80.59 130.98,96.55 121.59,105.95
  BOTTOM w0.102: JDIMM1.164 134.05,63.44 v2(134.75,64.15) ; v2(116.87,107.02) 116.65,107.02 116.58,106.94 USOC1.V48
DDR_A_D53: length 70.5
  IN2 w0.102: 120.85,105.86 120.58,106.13 117.84,106.13 v2(117.41,106.56)
  IN2 w0.127: v2(134.75,62.62) 133.34,64.03 133.34,66.07 133.18,66.24 132.94,66.24 132.05,65.34 131.87,65.34 131.6,65.61 131.6,65.79 132.34,66.54 132.34,66.72 132.07,66.99 131.89,66.99 131.15,66.24 130.97,66.24 130.7,66.51 130.7,66.69 131.45,67.44 131.45,67.62 130.4,68.66 130.4,69.16 130.53,69.29 131.47,69.29 131.65,69.47 131.65,69.74 131.47,69.92 130.53,69.92 130.4,70.05 130.4,70.43 130.53,70.56 131.47,70.56 131.65,70.74 131.65,71.01 131.47,71.19 130.53,71.19 130.4,71.32 130.4,71.7 130.53,71.83 131.47,71.83 131.65,72.01 131.65,72.28 131.47,72.46 130.53,72.46 130.4,72.59 130.4,72.97 130.53,73.1 131.49,73.1 131.68,73.28 131.68,73.55 131.49,73.73 130.53,73.73 130.4,73.86 130.4,74.24 130.53,74.37 131.49,74.37 131.68,74.55 131.68,74.82 131.49,75 130.53,75 130.4,75.13 130.4,96.31 120.85,105.86
  BOTTOM w0.102: v2(134.75,62.62) 134.65,62.52 JDIMM1.166 ; USOC1.V50 117.34,106.49 v2(117.41,106.56)
DDR_A_D54: length 70.8
  IN2 w0.102: 119.56,110.11 119.38,109.93 117.18,109.93 116.44,109.19 v2(116.16,109.19)
  IN2 w0.127: 119.56,110.11 120.78,111.33 125.64,111.33 132.48,104.49 132.48,104.23 131.92,103.67 131.92,103.41 132.11,103.22 132.37,103.22 132.93,103.78 133.19,103.78 133.38,103.6 133.38,101.57 140.11,94.83 140.11,73.81 139.7,73.4 139.7,69.39 139.12,68.81 139.12,67.64 136.58,65.1 136.58,63.24 v2(137.2,62.62)
  BOTTOM w0.102: USOC1.AB44 116.23,109.27 v2(116.16,109.19) ; v2(137.2,62.62) 137.05,62.48 JDIMM1.174
DDR_A_D55: length 71.4
  IN2 w0.102: v2(115.35,108.67) 115.75,109.07 115.75,109.36 115.99,109.6 116.23,109.6 116.96,110.33 118.83,110.33 119.47,110.97
  IN2 w0.127: v2(137.2,64.15) 139.88,66.83 139.88,68.36 140.69,69.17 140.69,95.13 134,101.82 134,103.8 125.86,111.95 120.45,111.95 119.47,110.97
  BOTTOM w0.102: v2(115.35,108.67) 115.69,108.67 115.72,108.64 USOC1.Y45 ; JDIMM1.176 137.65,62.29 137.8,62.44 137.8,63.55 v2(137.2,64.15)
DDR_A_D56: length 66.3
  IN1 w0.127: v2(140.21,72.54) 138.89,73.86 138.89,77.86 134.76,81.99 134.76,82.49 134.94,82.68 135.74,82.68 135.93,82.87 135.93,83.13 135.74,83.32 134.73,83.32 134.55,83.5 134.55,83.76 134.73,83.95 135.74,83.95 135.93,84.14 135.93,84.4 135.74,84.59 134.7,84.59 134.52,84.77 134.52,85.03 134.7,85.22 135.74,85.22 135.93,85.41 135.93,85.67 135.74,85.86 134.71,85.86 134.53,86.04 134.53,86.3 134.71,86.49 135.74,86.49 135.93,86.68 135.93,86.94 135.74,87.13 134.71,87.13 134.53,87.31 134.53,87.57 134.71,87.76 135.74,87.76 135.93,87.95 135.93,88.21 135.74,88.4 134.71,88.4 134.53,88.58 134.53,88.84 134.71,89.03 135.74,89.03 135.93,89.22 135.93,89.48 135.74,89.67 134.94,89.67 134.76,89.85 134.76,90.11 134.94,90.3 135.74,90.3 135.93,90.49 135.93,90.75 135.74,90.94 134.94,90.94 134.76,91.12 134.76,91.38 134.94,91.57 135.74,91.57 135.93,91.76 135.93,92.02 135.74,92.21 134.94,92.21 134.76,92.39 134.76,93.4 v2(125.17,102.99)
  BOTTOM w0.102: JDIMM1.181 139.15,71.48 v2(140.21,72.54) ; USOC1.V52 117.75,105.45 119.98,103.22 120.83,103.22 121.07,102.99 v2(125.17,102.99)
DDR_A_D57: length 66.1
  IN1 w0.127: v2(140.21,71.02) 138.84,69.64 138.26,69.64 137.85,70.05 137.85,74.19 138.31,74.64 138.31,74.91 138.12,75.09 137.51,75.09 137.33,75.28 137.33,75.54 137.51,75.73 138.12,75.73 138.31,75.91 138.31,76.18 138.12,76.36 137.51,76.36 137.33,76.55 137.33,76.81 137.51,77 138.12,77 138.31,77.18 138.31,77.45 138.12,77.63 137.51,77.63 137.33,77.82 137.33,78.58 133.71,82.19 133.71,87.99 133.35,88.36 132.86,88.36 132.56,88.65 132.56,89.07 132.86,89.36 133.97,89.36 134.15,89.55 134.15,89.81 133.97,90 132.73,90 132.55,90.18 132.55,90.44 132.73,90.63 133.96,90.63 134.15,90.82 134.15,91.08 133.96,91.27 132.73,91.27 132.55,91.45 132.55,91.71 132.73,91.9 133.95,91.9 134.13,92.09 134.13,92.35 133.95,92.54 132.73,92.54 132.55,92.72 132.55,92.98 132.73,93.17 133.47,93.17 133.66,93.36 133.66,93.62 133.47,93.81 132.73,93.81 132.55,93.99 132.55,94.68 124.54,102.69 v2(124.54,103.6)
  BOTTOM w0.102: v2(140.21,71.02) 140.26,71.02 139.75,70.51 JDIMM1.183 ; USOC1.W51 117.84,105.93 118.06,105.72 118.06,105.45 119.9,103.6 v2(124.54,103.6)
DDR_A_D58: length 67.1
  IN1 w0.102: 125.22,109.47 124.89,109.47 v2(124.52,109.1)
  IN1 w0.127: 125.22,109.47 125.46,109.47 125.98,108.95 125.98,107.65 141.51,92.12 141.51,89.35 141.69,89.17 142.76,89.17 142.95,88.98 142.95,88.72 142.76,88.53 141.69,88.53 141.51,88.34 141.51,88.08 141.69,87.9 142.93,87.9 143.11,87.71 143.11,87.45 142.93,87.26 141.69,87.26 141.51,87.07 141.51,86.81 141.69,86.63 142.93,86.63 143.11,86.44 143.11,86.18 142.93,85.99 141.69,85.99 141.51,85.8 141.51,85.54 141.69,85.36 142.93,85.36 143.11,85.17 143.11,84.91 142.93,84.72 141.69,84.72 141.51,84.53 141.51,84.18 141.7,83.98 142.52,83.98 142.9,83.61 142.9,82.79 144.19,81.49 144.19,72.96 v2(143.77,72.54)
  BOTTOM w0.102: JDIMM1.191 142.15,70.92 v2(143.77,72.54) ; USOC1.AC53 120.29,106.46 121.27,106.46 123.1,108.29 123.71,108.29 v2(124.52,109.1)
DDR_A_D59: length 67.3
  IN1 w0.102: v2(123.86,109.07) 124.76,109.98 125.84,109.98 126.2,109.61
  IN1 w0.127: v2(143.77,71.02) 143.77,69.71 143.91,69.58 144.13,69.58 144.32,69.78 144.32,71.57 144.78,72.03 144.78,82.53 144.46,82.85 143.71,82.85 143.49,83.06 143.49,83.36 143.71,83.58 144.46,83.58 144.64,83.76 144.64,84.03 144.46,84.21 143.9,84.21 143.72,84.4 143.72,84.66 143.9,84.85 144.46,84.85 144.64,85.03 144.64,85.3 144.46,85.48 143.9,85.48 143.72,85.67 143.72,85.93 143.9,86.12 144.46,86.12 144.64,86.3 144.64,86.57 144.46,86.75 143.9,86.75 143.72,86.94 143.72,87.2 143.9,87.39 144.46,87.39 144.64,87.57 144.64,87.84 144.46,88.02 143.9,88.02 143.72,88.21 143.72,89.08 142.31,90.48 142.31,92.19 126.65,107.84 126.65,109.16 126.2,109.61
  BOTTOM w0.102: USOC1.AC51 119.42,107.33 119.88,107.33 120.46,106.75 121.18,106.75 123.1,108.67 123.45,108.67 v2(123.86,109.07) ; JDIMM1.193 142.75,70.64 143.13,71.02 v2(143.77,71.02)
DDR_A_D60: length 66.4
  IN1 w0.127: v2(124.03,104.19) 125.07,104.19 136.52,92.74 136.52,91.77 136.71,91.58 137.07,91.58 137.26,91.39 137.26,91.13 137.07,90.95 136.71,90.95 136.52,90.76 136.52,90.5 136.71,90.31 137.07,90.31 137.26,90.12 137.26,89.86 137.07,89.68 136.71,89.68 136.52,89.49 136.52,89.23 136.71,89.04 137.07,89.04 137.26,88.85 137.26,88.59 137.07,88.41 136.71,88.41 136.52,88.22 136.52,87.96 136.71,87.77 137.07,87.77 137.26,87.58 137.26,87.32 137.07,87.14 136.71,87.14 136.52,86.95 136.52,86.69 136.71,86.5 137.07,86.5 137.26,86.31 137.26,86.05 137.07,85.87 136.71,85.87 136.52,85.68 136.52,85.42 136.71,85.23 137.07,85.23 137.26,85.04 137.26,84.78 137.07,84.6 136.71,84.6 136.52,84.41 136.52,84.15 136.71,83.96 137.07,83.96 137.26,83.77 137.26,83.51 137.07,83.33 136.71,83.33 136.52,83.14 136.52,82.88 136.71,82.69 137.07,82.69 137.26,82.5 137.26,82.24 137.07,82.06 136.71,82.06 136.52,81.87 136.52,81.05 140.8,76.78 140.8,66.7 139.33,65.23 139.33,64.65 v2(139.83,64.15)
  BOTTOM w0.102: v2(124.03,104.19) 119.61,104.19 118.37,105.43 USOC1.W53 ; v2(139.83,64.15) 138.85,63.16 JDIMM1.180
DDR_A_D61: length 66.7
  IN1 w0.127: v2(139.83,62.62) 140.44,63.23 140.44,65.52 141.38,66.46 141.38,77.02 138.14,80.27 138.14,81.22 138.32,81.4 138.64,81.4 138.83,81.59 138.83,81.85 138.64,82.04 138.32,82.04 138.14,82.22 138.14,82.49 138.32,82.67 138.64,82.67 138.83,82.86 138.83,83.12 138.64,83.31 138.32,83.31 138.14,83.49 138.14,83.76 138.32,83.94 138.64,83.94 138.83,84.13 138.83,84.39 138.64,84.58 138.32,84.58 138.14,84.76 138.14,85.03 138.32,85.21 138.64,85.21 138.83,85.4 138.83,85.66 138.64,85.85 138.32,85.85 138.14,86.03 138.14,86.3 138.32,86.48 138.64,86.48 138.83,86.67 138.83,86.93 138.64,87.12 138.32,87.12 138.14,87.3 138.14,87.57 138.32,87.75 138.64,87.75 138.83,87.94 138.83,88.2 138.64,88.39 138.32,88.39 138.14,88.57 138.14,88.84 138.32,89.02 138.64,89.02 138.83,89.21 138.83,89.47 138.64,89.66 138.32,89.66 138.14,89.84 138.14,91.95 124.81,105.28 123.38,105.28 v2(123.2,105.1)
  BOTTOM w0.102: USOC1.Y51 117.94,106.49 118.14,106.3 118.14,106.09 118.29,105.94 118.46,105.94 118.84,105.56 118.84,105.24 119.34,104.75 122.85,104.75 v2(123.2,105.1) ; JDIMM1.182 139.45,62.24 v2(139.83,62.62)
DDR_A_D62: length 66.4
  IN1 w0.102: v2(123.17,109.07) 124.43,110.34 126.4,110.34 126.66,110.07
  IN1 w0.127: v2(143.18,64.15) 144.4,65.37 144.4,68.5 144.91,69.01 144.91,71.33 145.36,71.78 145.36,88.26 142.93,90.69 142.93,92.41 127.35,107.99 127.35,109.39 126.66,110.07
  BOTTOM w0.102: v2(123.17,109.07) 123.15,109.07 121.09,107.02 120.61,107.02 120,107.62 USOC1.AD52 ; v2(143.18,64.15) 142.45,63.42 JDIMM1.192
DDR_A_D63: length 67.6
  IN1 w0.102: v2(123.15,109.73) 124.33,110.92 124.48,110.92
  IN1 w0.127: v2(143.18,62.62) 145.32,64.76 145.32,68.35 145.95,68.98 145.95,88.49 143.51,90.93 143.51,92.71 127.99,108.23 127.99,109.6 126.67,110.92 124.48,110.92
  BOTTOM w0.102: v2(123.15,109.73) 122.76,109.35 122.76,109.27 121.49,108 120.7,108 120.69,108.01 120.17,108.01 120.08,107.92 119.52,107.92 USOC1.AD51 ; JDIMM1.194 143.05,62.49 v2(143.18,62.62)
DDR_A_DM0: length 67.1
  IN1 w0.102: v2(108.49,107.03) 108.49,106.39 108.21,106.12
  IN1 w0.127: v2(85.75,68.06) 85.19,68.61 85.19,75.73 85.54,76.08 85.54,76.34 85.19,76.7 85.19,76.96 85.37,77.15 85.63,77.15 85.99,76.79 86.25,76.79 86.71,77.24 86.71,79.24 86.52,79.43 85.41,79.43 85.23,79.61 85.23,79.88 85.41,80.06 86.52,80.06 86.71,80.25 86.71,80.57 86.31,80.97 86.31,81.46 91.82,86.96 91.82,92.66 92,92.85 92.26,92.85 92.45,92.66 92.45,88.08 92.64,87.89 92.9,87.89 93.45,88.45 93.45,94.7 97.99,99.24 98.8,99.24 101.51,101.95 103.43,101.95 105.11,103.64 105.73,103.64 108.21,106.12
  BOTTOM w0.102: JDIMM1.11 v2(85.75,68.06) ; 108.26,107.48 108.26,107.25 v2(108.49,107.03)
DDR_A_DM1: length 52.6
  IN1 w0.127: v2(104.2,98.25) 103.8,98.65 102.43,98.65 100.36,96.58 100.36,85.69 97.99,83.32 97.99,82.17 92.99,77.17 92.99,75.79 91.33,74.13 91.33,69.35 91.11,69.14 91.11,65.4 91.28,65.24 91.28,63.06 v2(90.86,62.65)
  BOTTOM w0.102: v2(104.2,98.25) 104.12,98.33 104.12,99.99 104.68,100.54 104.68,103.89 USOC1.B36 ; v2(90.86,62.65) 90.85,62.64 JDIMM1.28
DDR_A_DM2: length 58.5
  IN2 w0.102: v2(108.58,105.75) 108.58,106.3 108.86,106.58 109.21,106.58 109.44,106.35 109.44,105.77 108.3,104.63 107.73,104.63 107.45,104.91 106.38,104.91 104.77,103.29 104.77,102.85 104.31,102.39
  IN2 w0.127: 104.31,102.39 102.97,102.39 99.48,98.9 98.97,98.9 92.52,92.45 92.52,76.1 95.06,73.57 95.06,68.8 95.7,68.16 95.7,63.27 v2(96.25,62.72)
  BOTTOM w0.102: JDIMM1.46 v2(96.25,62.72) ; v2(108.58,105.75) 108.58,106.16 USOC1.F38
DDR_A_DM3: length 48
  IN1 w0.127: v2(101.96,67.95) 102.26,68.25 102.26,68.97 102.07,69.15 101.6,69.15 101.42,69.34 101.42,69.6 101.6,69.79 102.07,69.79 102.26,69.97 102.26,74.08 104.25,76.08 104.56,76.08 105.57,75.07 105.83,75.07 106.02,75.25 106.02,75.52 105.01,76.52 105.01,76.79 105.19,76.97 105.46,76.97 106.03,76.4 106.3,76.4 106.48,76.58 106.48,76.85 105.9,77.42 105.9,77.69 107.79,79.57 107.79,84.07 107.05,84.81 107.05,86.33 107.8,87.08 107.8,93.68 107.02,94.46 107.02,95.5 106.76,95.76 v2(106.76,96.33)
  BOTTOM w0.102: USOC1.B42 108.44,103.41 108.09,103.05 107.81,103.05 107.6,102.85 107.6,99.47 107.14,99.01 107.14,96.71 v2(106.76,96.33) ; v2(101.96,67.95) 101.35,68.56 JDIMM1.63
DDR_A_DM4: length 51.1
  IN1 w0.127: v2(118.93,96.26) 119.13,96.26 120.32,95.08 120.32,94.81 120.16,94.66 120.16,94.4 120.35,94.21 120.61,94.21 120.76,94.37 121.03,94.37 121.19,94.2 121.19,82.38 128.28,75.29 128.28,69.04 127.74,68.5 127.74,67.13 v2(126.28,65.67)
  BOTTOM w0.102: v2(118.93,96.26) 119.31,96.64 119.31,101.53 116.67,104.17 116.67,104.36 116.55,104.49 116.08,104.49 USOC1.P51 ; JDIMM1.136 125.65,65.04 v2(126.28,65.67)
DDR_A_DM5: length 62.1
  IN1 w0.127: v2(132.49,67.98) 135.31,70.79 135.31,78.11 131.96,81.46 131.96,85.41 131.78,85.6 131.51,85.6 131.33,85.41 131.33,82.74 131.14,82.56 130.88,82.56 130.69,82.74 130.69,94.06 120.01,104.74 120.01,105.82 119.61,106.22 118.82,106.22 117.95,107.09 117.54,107.09 115.21,109.42 v2(114.56,109.42)
  BOTTOM w0.102: JDIMM1.153 130.75,68.63 131.4,67.98 v2(132.49,67.98) ; v2(114.56,109.42) 114.34,109.21 USOC1.V42
DDR_A_DM6: length 71.1
  IN2 w0.102: 124.32,107.48 123.8,108 120.12,108 119.26,107.14 118.23,107.14 v2(117.58,107.8)
  IN2 w0.127: v2(135.97,64.14) 135.56,64.55 135.56,66.81 135.69,66.94 136.3,66.94 136.43,67.07 136.43,67.45 136.3,67.58 135.69,67.58 135.56,67.7 135.56,68.76 135.69,68.89 137.32,68.89 137.44,69.02 137.44,69.4 137.32,69.53 135.69,69.53 135.56,69.65 135.56,70.03 135.69,70.16 137.32,70.16 137.44,70.29 137.44,70.67 137.32,70.8 135.69,70.8 135.56,70.92 135.56,73.56 134.95,74.17 134.95,74.36 135.08,74.49 135.83,74.49 136.02,74.68 136.02,74.94 135.83,75.13 135.08,75.13 134.95,75.25 134.95,75.63 135.08,75.76 135.56,75.76 135.69,75.89 135.69,76.27 135.56,76.4 135.08,76.4 134.95,76.52 134.95,95.8 125,105.76 125,106.8 124.32,107.48
  BOTTOM w0.102: v2(135.97,64.14) 136.47,63.64 136.47,63.16 136,62.69 136,62.49 135.85,62.35 JDIMM1.170 ; v2(117.58,107.8) 117.52,107.73 USOC1.Y50
DDR_A_DM7: length 66
  IN1 w0.102: 125.18,108.59 v2(125.18,109.07)
  IN1 w0.127: v2(143.35,67.27) 143.82,67.74 143.82,68.49 143.16,69.15 143.16,73.67 143.61,74.12 143.61,78.31 143.42,78.49 142.93,78.49 142.74,78.68 142.74,78.94 142.93,79.13 143.42,79.13 143.61,79.32 143.61,79.58 143.42,79.76 143.12,79.76 142.93,79.95 142.93,80.21 143.12,80.4 143.42,80.4 143.61,80.59 143.61,80.97 140.9,83.67 140.9,91.74 125.18,107.47 125.18,108.59
  BOTTOM w0.102: JDIMM1.187 140.95,68.41 142.09,67.27 v2(143.35,67.27) ; v2(125.18,109.07) 124.11,108.01 123.43,108.01 123.09,107.67 123.09,105.86 122.53,105.31 119.38,105.31 USOC1.Y52
DDR_A_DQS0: length 66.4
  IN1 w0.102: v2(109.34,107.87) 109.63,108.16 109.63,108.24 109.5,108.38 108.7,108.38 106.06,105.74 105.62,105.74 105.61,105.72 105.6,105.72
  IN1 w0.127: 105.6,105.72 104.9,105.72 102.95,103.78 100.31,103.78 89.48,92.96 89.48,92.43 89.71,92.21 89.96,92.21 90.33,91.84 90.33,91.31 89.96,90.94 89.36,90.94 89.13,90.71 89.13,90.4 89.36,90.17 89.96,90.17 90.33,89.8 90.33,89.27 89.96,88.9 89.71,88.9 89.48,88.68 89.48,86.53 83.82,80.87 83.82,66.22 84.62,65.42 85.23,65.42 86.01,64.64 86.01,63.68 86.27,63.42 v2(86.44,63.42)
  BOTTOM w0.102: JDIMM1.12 86.05,62.39 85.86,62.58 85.86,62.67 86.17,62.98 86.17,63.25 86.34,63.42 v2(86.44,63.42) ; v2(109.34,107.87) 109.45,107.75 109.45,107.3
DDR_A_DQS1: length 51.8
  IN1 w0.127: v2(103.69,97.67) 103.49,97.67 103.27,97.89 102.74,97.89 101.12,96.27 101.12,85.37 98.75,83.01 98.75,81.84 93.83,76.92 93.83,75.52 92.25,73.94 92.25,69.94 93.12,69.07 93.12,67.22 92.82,66.92 92.06,66.92 91.88,67.11 v2(91.88,67.21)
  BOTTOM w0.102: v2(91.88,67.21) 91.61,66.94 91.21,66.94 90.96,67.2 90.96,68.1 91.15,68.29 JDIMM1.29 ; v2(103.69,97.67) 103.45,97.67 103.18,97.94 103.18,98.55 103.38,98.75 103.38,100.05 104.2,100.87 104.2,104.55 105.61,105.97 105.85,105.97 106.06,106.18 USOC1.C35
DDR_A_DQS2: length 58.9
  IN2 w0.102: v2(108.82,104.58) 108.65,104.41 107.63,104.41 107.43,104.61 106.48,104.61 105.13,103.26 105.13,102.36 105.11,102.35 105.11,102.32
  IN2 w0.127: v2(97.6,71.78) 97.6,72 97.46,72.14 97.27,72.14 97.13,72.01 97.13,69.97 96.76,69.59 96.23,69.59 95.85,69.97 95.85,73.85 93.29,76.41 93.29,92.07 96.06,94.84 96.51,94.84 96.8,94.55 97.11,94.55 97.34,94.78 97.34,95.09 97.08,95.35 97.08,95.88 97.45,96.26 97.98,96.26 98.24,96 98.55,96 98.78,96.22 98.78,96.53 98.45,96.86 98.45,97.29 99.26,98.1 101.07,98.1 101.7,98.73 101.7,99.02 101.48,99.25 101.48,99.78 101.85,100.15 102.38,100.15 102.66,99.87 102.89,99.87 103.24,100.22 103.24,100.37 102.97,100.64 102.97,101.17 103.34,101.54 103.87,101.54 104.14,101.27 104.46,101.27 105.11,101.93 105.11,102.32
  BOTTOM w0.102: v2(97.6,71.78) 97.6,71.98 97.42,72.16 96.94,72.16 96.17,71.38 96.17,70.88 96.27,70.78 96.38,70.78 96.55,70.61 JDIMM1.47 ; USOC1.D40 108.67,104.73 v2(108.82,104.58)
DDR_A_DQS3: length 48.5
  IN1 w0.127: v2(102.18,63.98) 102.18,64.24 102.27,64.33 102.65,64.33 102.76,64.44 102.9,64.58 102.9,65.75 103.36,66.21 103.36,73 104.14,73.78 106.03,73.78 106.94,74.7 107.65,75.41 107.65,77.72 108.82,78.89 108.82,94.54 108.31,95.05 108.31,95.92 107.72,96.5 107.72,97.19 108.14,97.6 108.14,98.32 107.91,98.55 107.91,98.84 v2(107.98,98.91)
  BOTTOM w0.102: v2(102.18,63.98) 102.18,64.26 102.1,64.34 101.7,64.34 101.47,64.11 101.47,63.01 101.27,62.8 101.27,62.64 101.37,62.54 101.55,62.54 101.65,62.44 JDIMM1.64 ; USOC1.B44 109.13,102.8 108.05,101.72 108.05,98.98 v2(107.98,98.91)
DDR_A_DQS4: length 51.4
  IN1 w0.127: v2(116.77,95.94) 116.77,96.07 116.64,96.2 116.31,96.2 115.93,95.83 115.93,93.92 115.65,93.65 115.14,93.65 115.02,93.52 115.02,93.01 115.14,92.88 115.65,92.88 115.93,92.61 115.93,91.89 115.65,91.61 115.14,91.61 115.02,91.48 115.02,90.97 115.14,90.85 115.65,90.85 115.93,90.57 115.93,89.85 115.65,89.57 115.14,89.57 115.02,89.44 115.02,88.94 115.14,88.81 115.65,88.81 115.93,88.53 115.93,87.81 115.65,87.53 115.14,87.53 115.02,87.41 115.02,86.9 115.14,86.77 115.65,86.77 115.93,86.49 115.93,85.77 115.65,85.5 115.14,85.5 115.02,85.37 115.02,84.86 115.14,84.73 115.65,84.73 115.93,84.46 115.93,83.74 115.65,83.46 115.14,83.46 115.02,83.33 115.02,82.82 115.14,82.7 115.65,82.7 115.93,82.42 115.93,81.18 120.36,76.76 121.19,76.76 124.08,73.86 124.08,72.78 124.23,72.63 124.44,72.63 124.56,72.75 v2(124.56,72.92)
  BOTTOM w0.102: USOC1.N53 116.31,103.44 116.83,102.92 117.45,102.92 118.51,101.86 118.51,98.21 117.87,97.57 117.87,96.73 117.36,96.22 116.91,96.22 116.77,96.08 v2(116.77,95.94) ; JDIMM1.137 125.95,70.51 125.76,70.7 125.76,72.5 125.54,72.72 124.77,72.72 v2(124.56,72.92)
DDR_A_DQS5: length 61.3
  IN1 w0.102: v2(113.54,107.65) 113.86,107.65 114.03,107.83 114.5,107.83 117.29,105.04 117.29,104.61 117.6,104.31 117.61,104.31 117.62,104.3
  IN1 w0.127: 117.62,104.3 117.86,104.06 117.86,103.93 125.94,95.85 125.94,94.97 126.07,94.85 126.75,94.85 127.03,94.57 127.03,93.85 126.75,93.57 126.07,93.57 125.94,93.44 125.94,92.94 126.07,92.81 126.75,92.81 127.03,92.53 127.03,91.81 126.75,91.53 126.07,91.53 125.94,91.41 125.94,84.18 132.06,78.06 132.06,68.92 131.19,68.06 131.19,66.76 132.04,65.92 132.04,64.98 131.53,64.47 131.14,64.47 v2(130.94,64.27)
  BOTTOM w0.102: v2(113.54,107.65) 113.67,107.78 USOC1.T42 ; v2(130.94,64.27) 130.77,64.44 130.54,64.44 130.43,64.34 130.43,63.44 131.05,62.82 JDIMM1.154
DDR_A_DQS6: length 70
  IN2 w0.102: v2(116.58,108.76) 116.83,108.76 116.97,108.89 117.4,108.89 118.57,107.72 119.08,107.72 119.33,107.97 119.89,108.53 120.83,108.53 120.96,108.66 124.57,108.66 124.73,108.5 124.73,108.5 124.91,108.33 124.92,108.33
  IN2 w0.127: v2(136.4,72.16) 136.55,72.31 136.81,72.31 137.09,72.59 137.09,76.81 136.81,77.09 136.35,77.09 136.12,77.31 136.12,77.63 136.35,77.85 136.81,77.85 137.09,78.13 137.09,78.85 136.81,79.13 136.12,79.13 136,79.25 136,79.76 136.12,79.89 136.81,79.89 137.09,80.17 137.09,80.89 136.81,81.17 136.12,81.17 136,81.29 136,81.8 136.12,81.93 136.81,81.93 137.09,82.2 137.09,82.92 136.81,83.2 136.12,83.2 136,83.33 136,83.84 136.12,83.96 136.81,83.96 137.09,84.24 137.09,84.96 136.81,85.24 136.12,85.24 136,85.37 136,85.87 136.12,86 136.81,86 137.09,86.28 137.09,87 136.81,87.28 136.12,87.28 136,87.4 136,87.91 136.12,88.04 136.81,88.04 137.09,88.32 137.09,89.04 136.81,89.31 136.12,89.31 136,89.44 136,89.95 136.12,90.08 136.81,90.08 137.09,90.35 137.09,91.07 136.81,91.35 136.12,91.35 136,91.48 136,91.99 136.12,92.11 136.81,92.11 137.09,92.39 137.09,93.11 136.81,93.39 136.12,93.39 136,93.51 136,94.02 136.12,94.15 136.81,94.15 137.09,94.43 137.09,95.12 126.5,105.71 126.5,106.74 124.92,108.33
  BOTTOM w0.102: USOC1.Y47 116.54,108.71 v2(116.58,108.76) ; JDIMM1.171 136.15,70.57 135.94,70.77 135.94,72.16 136.1,72.32 136.24,72.32 v2(136.4,72.16)
DDR_A_DQS7: length 66.2
  IN1 w0.127: v2(141.53,63.77) 141.53,63.89 141.7,64.07 142.09,64.07 142.4,64.37 142.4,77.49 141.98,77.91 141.98,81.52 141.61,81.89 141.08,81.89 140.71,81.52 140.71,79.93 140.48,79.7 140.17,79.7 139.94,79.93 139.94,91.59 124.64,106.89 124,106.89 123.69,106.58 123.34,106.58 123.03,106.89 122.43,106.89 122.08,106.54 v2(121.93,106.54)
  BOTTOM w0.102: USOC1.AB52 119.3,106.94 120.18,106.06 121.63,106.06 121.93,106.36 v2(121.93,106.54) ; JDIMM1.188 141.25,62.23 141.05,62.43 141.05,63.98 141.22,64.15 141.39,64.15 141.53,64 v2(141.53,63.77)
DDR_A_DQS#0: length 66.4
  IN1 w0.102: 105.6,105.98 105.61,105.98 105.62,105.97 105.96,105.97 108.6,108.61 109.59,108.61 109.73,108.47 v2(109.95,108.47)
  IN1 w0.127: 105.6,105.98 104.79,105.98 102.85,104.04 100.2,104.04 89.23,93.06 89.23,92.33 89.6,91.95 89.85,91.95 90.07,91.73 90.07,91.42 89.85,91.19 89.25,91.19 88.88,90.82 88.88,90.29 89.25,89.92 89.85,89.92 90.07,89.69 90.07,89.38 89.85,89.16 89.6,89.16 89.23,88.78 89.23,86.64 83.57,80.98 83.57,66.11 84.51,65.17 85.12,65.17 85.76,64.53 85.76,63.5 v2(85.68,63.42)
  BOTTOM w0.102: USOC1.K38 109.96,108.46 v2(109.95,108.47) ; JDIMM1.10 85.45,62.39 85.64,62.58 85.64,62.76 85.95,63.07 85.95,63.15 v2(85.68,63.42)
DDR_A_DQS#1: length 51.9
  IN1 w0.127: v2(103.21,97.24) 103.3,97.33 103.3,97.5 103.16,97.64 102.85,97.64 101.37,96.16 101.37,85.27 99.01,82.9 99.01,81.73 94.09,76.81 94.09,75.41 92.51,73.84 92.51,70.04 93.37,69.18 93.37,67.11 92.92,66.66 92.09,66.66 v2(91.88,66.45)
  BOTTOM w0.102: USOC1.B34 105.61,106.27 103.98,104.64 103.98,100.96 103.17,100.14 103.17,98.84 102.97,98.64 102.97,97.85 103.21,97.61 v2(103.21,97.24) ; v2(91.88,66.45) 91.6,66.73 91.12,66.73 90.74,67.11 90.74,68.1 90.55,68.29 JDIMM1.27
DDR_A_DQS#2: length 59
  IN2 w0.102: 105.37,102.32 105.37,102.35 105.36,102.36 105.36,103.16 106.58,104.38 107.33,104.38 107.53,104.18 108.97,104.18 109.23,104.44 109.23,104.88 v2(109.36,105.01)
  IN2 w0.127: v2(97.6,72.54) 97.46,72.4 97.16,72.4 96.88,72.11 96.88,70.07 96.65,69.85 96.33,69.85 96.11,70.07 96.11,73.96 93.55,76.52 93.55,91.97 96.17,94.59 96.4,94.59 96.69,94.3 97.22,94.3 97.59,94.67 97.59,95.2 97.33,95.46 97.33,95.78 97.56,96 97.87,96 98.13,95.74 98.66,95.74 99.03,96.11 99.03,96.64 98.71,96.96 98.71,97.18 99.37,97.84 101.17,97.84 101.96,98.63 101.96,99.13 101.73,99.36 101.73,99.67 101.96,99.89 102.27,99.89 102.55,99.62 103,99.62 103.5,100.11 103.5,100.48 103.23,100.75 103.23,101.06 103.45,101.29 103.77,101.29 104.04,101.01 104.56,101.01 105.37,101.82 105.37,102.32
  BOTTOM w0.102: v2(97.6,72.54) 97.43,72.37 96.85,72.37 95.95,71.47 JDIMM1.45 ; USOC1.F40 109.15,105.22 v2(109.36,105.01)
DDR_A_DQS#3: length 48.5
  IN1 w0.127: v2(102.18,64.74) 102.33,64.59 102.55,64.59 102.58,64.62 102.64,64.69 102.64,65.86 103.1,66.31 103.1,73.1 104.04,74.04 105.92,74.04 107.39,75.51 107.39,77.83 108.56,79 108.56,94.43 108.05,94.94 108.05,95.81 107.47,96.39 107.47,97.29 107.88,97.71 107.88,98.21 107.66,98.43 v2(107.53,98.43)
  BOTTOM w0.102: USOC1.C43 109.04,103.25 108.82,103.03 108.82,102.8 107.83,101.81 107.83,99.35 107.53,99.04 v2(107.53,98.43) ; v2(102.18,64.74) 102,64.56 101.61,64.56 101.25,64.2 101.25,63.1 101.05,62.89 JDIMM1.62
DDR_A_DQS#4: length 51.4
  IN1 w0.127: v2(124.56,72.16) 124.35,72.37 124.12,72.37 123.83,72.67 123.83,73.76 121.08,76.5 120.25,76.5 115.68,81.07 115.68,82.31 115.55,82.44 115.04,82.44 114.76,82.72 114.76,83.44 115.04,83.72 115.55,83.72 115.68,83.84 115.68,84.35 115.55,84.48 115.04,84.48 114.76,84.76 114.76,85.48 115.04,85.75 115.55,85.75 115.68,85.88 115.68,86.39 115.55,86.52 115.04,86.52 114.76,86.79 114.76,87.51 115.04,87.79 115.55,87.79 115.68,87.92 115.68,88.43 115.55,88.55 115.04,88.55 114.76,88.83 114.76,89.55 115.04,89.83 115.55,89.83 115.68,89.95 115.68,90.46 115.55,90.59 115.04,90.59 114.76,90.87 114.76,91.59 115.04,91.86 115.55,91.86 115.68,91.99 115.68,92.5 115.55,92.63 115.04,92.63 114.76,92.9 114.76,93.62 115.04,93.9 115.55,93.9 115.68,94.03 115.68,95.93 116.2,96.46 116.63,96.46 v2(116.77,96.6)
  BOTTOM w0.102: v2(116.77,96.6) 116.94,96.43 117.27,96.43 117.66,96.82 117.66,97.66 118.29,98.3 118.29,101.77 117.36,102.7 116.74,102.7 115.94,103.5 USOC1.M52 ; JDIMM1.135 125.35,70.52 125.54,70.71 125.54,72.41 125.45,72.5 124.9,72.5 v2(124.56,72.16)
DDR_A_DQS#5: length 61.3
  IN1 w0.102: 117.44,104.12 117.43,104.13 117.43,104.14 117.38,104.2 117.06,104.52 117.06,104.94 114.4,107.6 114.13,107.6 113.98,107.45 113.98,107.34 v2(114.17,107.15)
  IN1 w0.127: v2(130.94,65.04) 131.25,64.73 131.42,64.73 131.78,65.09 131.78,65.81 130.94,66.65 130.94,68.16 131.8,69.03 131.8,77.95 125.68,84.07 125.68,91.51 125.96,91.79 126.65,91.79 126.77,91.92 126.77,92.43 126.65,92.55 125.96,92.55 125.68,92.83 125.68,93.55 125.96,93.83 126.65,93.83 126.77,93.95 126.77,94.46 126.65,94.59 125.96,94.59 125.68,94.87 125.68,95.75 117.61,103.83 117.61,103.95 117.44,104.12
  BOTTOM w0.102: JDIMM1.152 130.45,62.28 130.54,62.37 130.75,62.37 130.83,62.46 130.83,62.74 130.22,63.35 130.22,64.43 130.45,64.66 130.81,64.66 130.94,64.79 v2(130.94,65.04) ; USOC1.T44 114.17,107.15 v2(114.17,107.15)
DDR_A_DQS#6: length 70
  IN2 w0.102: 124.74,108.15 124.72,108.16 124.72,108.18 124.47,108.43 121.05,108.43 120.93,108.3 119.99,108.3 119.49,107.81 119.18,107.49 118.47,107.49 117.3,108.66 117.06,108.66 116.92,108.51 116.92,108.36 v2(117.1,108.17)
  IN2 w0.127: 124.74,108.15 126.24,106.64 126.24,105.6 136.83,95.02 136.83,94.53 136.7,94.41 136.02,94.41 135.74,94.13 135.74,93.41 136.02,93.13 136.7,93.13 136.83,93 136.83,92.5 136.7,92.37 136.02,92.37 135.74,92.09 135.74,91.37 136.02,91.09 136.7,91.09 136.83,90.97 136.83,90.46 136.7,90.33 136.02,90.33 135.74,90.05 135.74,89.33 136.02,89.06 136.7,89.06 136.83,88.93 136.83,88.42 136.7,88.29 136.02,88.29 135.74,88.02 135.74,87.3 136.02,87.02 136.7,87.02 136.83,86.89 136.83,86.38 136.7,86.26 136.02,86.26 135.74,85.98 135.74,85.26 136.02,84.98 136.7,84.98 136.83,84.86 136.83,84.35 136.7,84.22 136.02,84.22 135.74,83.94 135.74,83.22 136.02,82.95 136.7,82.95 136.83,82.82 136.83,82.31 136.7,82.18 136.02,82.18 135.74,81.91 135.74,81.19 136.02,80.91 136.7,80.91 136.83,80.78 136.83,80.27 136.7,80.15 136.02,80.15 135.74,79.87 135.74,79.15 136.02,78.87 136.7,78.87 136.83,78.74 136.83,78.24 136.7,78.11 136.24,78.11 135.87,77.74 135.87,77.21 136.24,76.83 136.7,76.83 136.83,76.71 136.83,72.7 136.7,72.57 136.52,72.57 136.4,72.69 v2(136.4,72.92)
  BOTTOM w0.102: v2(136.4,72.92) 136.4,72.71 136.23,72.54 136.01,72.54 135.73,72.25 135.73,70.78 135.55,70.61 JDIMM1.169 ; v2(117.1,108.17) 117.04,108.11 USOC1.Y48
DDR_A_DQS#7: length 66.2
  IN1 w0.127: v2(141.53,64.53) 141.73,64.32 141.98,64.32 142.14,64.48 142.14,77.38 141.72,77.8 141.72,81.41 141.5,81.63 141.19,81.63 140.96,81.41 140.96,79.82 140.59,79.45 140.06,79.45 139.69,79.82 139.69,91.48 124.53,106.64 124.11,106.64 123.8,106.33 123.24,106.33 122.93,106.64 122.53,106.64 122.34,106.45 v2(122.34,105.99)
  BOTTOM w0.102: JDIMM1.186 140.65,62.24 140.84,62.43 140.84,64.07 141.13,64.36 141.36,64.36 v2(141.53,64.53) ; v2(122.34,105.99) 122.16,106.17 122.04,106.17 121.72,105.85 120.09,105.85 119.41,106.53 118.63,106.78 USOC1.AA51
DDR_A_MA0: length 53.5
  IN2 w0.102: 116.29,96.68 116.29,97.39 114.69,98.99 114.69,100.46 114.25,100.89 114.25,102.51 113.34,103.43 113.23,103.43 112.5,104.15 v2(112.5,104.53)
  IN2 w0.216: v2(113.81,64.91) 114.28,64.44 114.28,63.98 115.09,63.17 115.52,63.17 115.68,63.32 115.68,63.75 114.89,64.54 114.89,70.46 114.49,70.85 114.49,75.04 114.22,75.31 114.22,75.89 114.44,76.1 114.7,76.1 114.91,76.32 114.91,76.75 114.7,76.97 114.44,76.97 114.22,77.18 114.22,77.62 114.44,77.83 114.7,77.83 114.91,78.05 114.91,78.48 114.7,78.69 114.44,78.69 114.22,78.91 114.22,79.4 115.78,80.96 115.78,90.28 116.28,90.78 116.28,96.67 116.29,96.68
  BOTTOM w0.165: v2(113.81,64.91) 114.25,64.47 JDIMM1.98 ; USOC1.K45 112.59,104.85 112.5,104.77 v2(112.5,104.53)
DDR_A_MA1: length 55.8
  IN2 w0.102: 115.04,97.05 115.04,98.05 114.07,99.02 114.07,99.38 113.62,99.84 113.62,100.32 113.85,100.54 113.85,102.34 113.17,103.02 113.06,103.02 112.34,103.74 v2(111.97,103.74)
  IN2 w0.216: v2(113.25,67.81) 113.25,67.73 112.51,66.99 112.51,65.31 112.27,65.07 111.94,65.07 111.59,65.43 111.59,67.22 112.58,68.21 112.58,68.51 111.22,69.88 111.22,70.18 111.43,70.39 111.73,70.39 113.09,69.03 113.39,69.03 113.64,69.28 113.64,69.94 112.83,70.75 112.83,73.1 113.25,73.52 113.25,74.52 112.98,74.8 112.98,82.28 113.19,82.5 113.49,82.5 113.7,82.28 113.7,81.5 113.91,81.28 114.21,81.28 114.42,81.5 114.42,90.73 115.04,91.34 115.04,97.05
  BOTTOM w0.102: 111.97,103.74 v2(111.97,103.74)
  BOTTOM w0.165: JDIMM1.97 113.95,68.51 v2(113.25,67.81) ; USOC1.H47 112.26,103.74 111.97,103.74
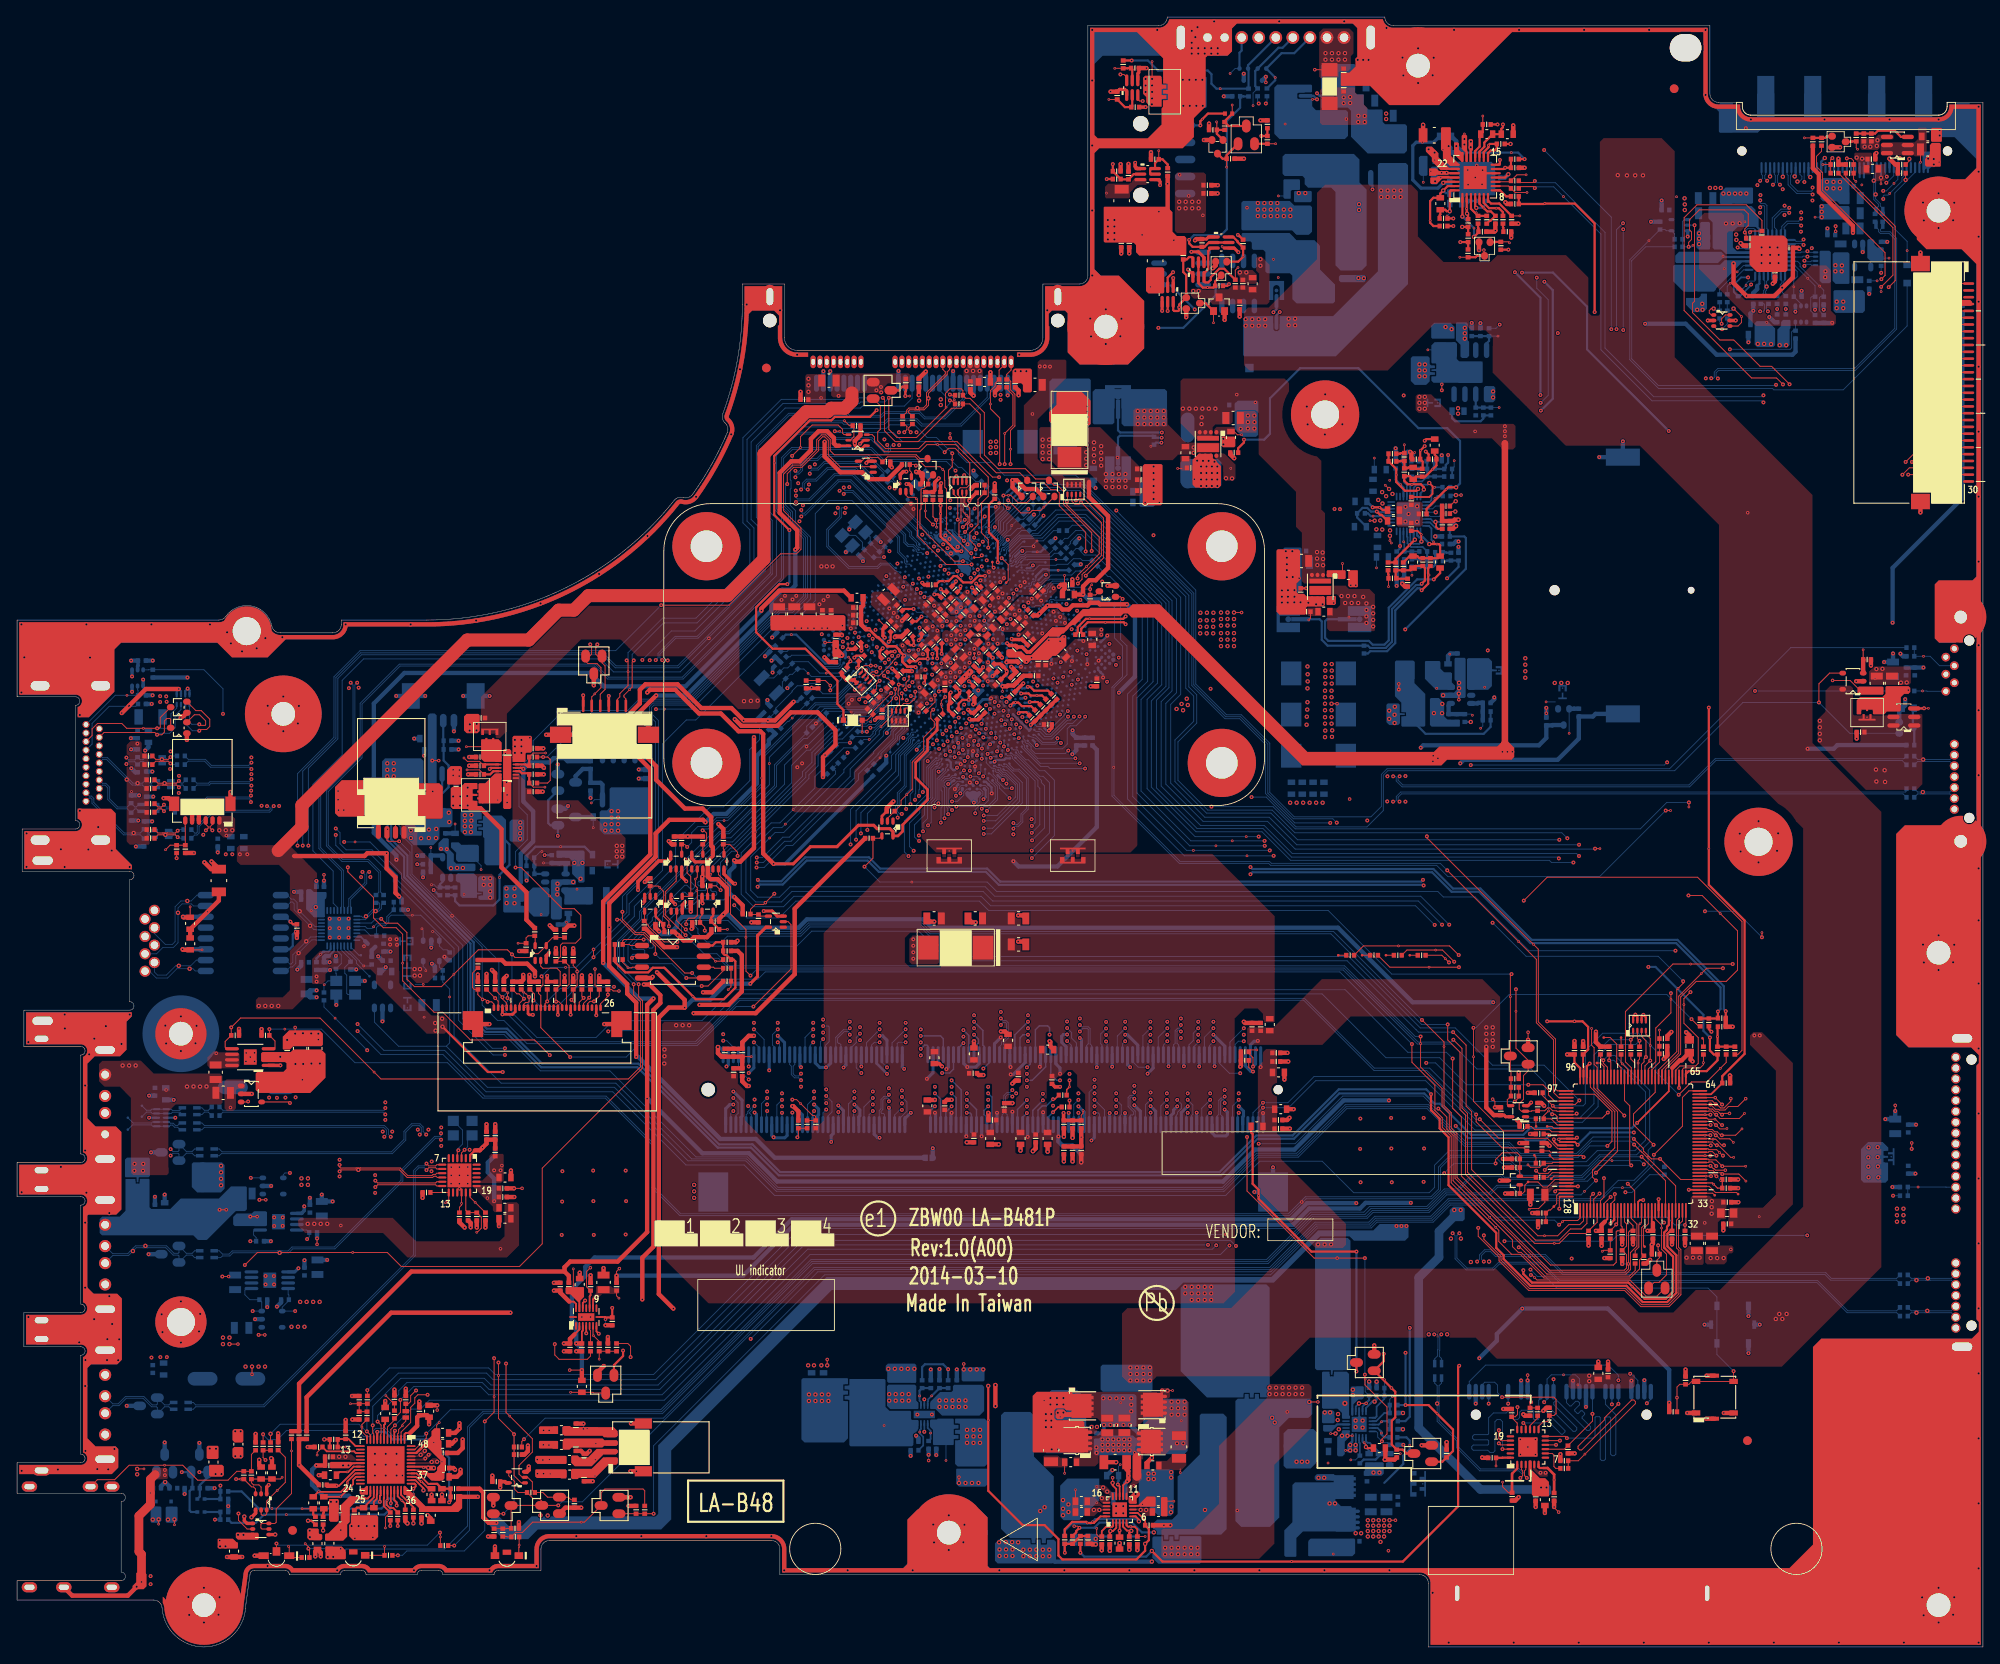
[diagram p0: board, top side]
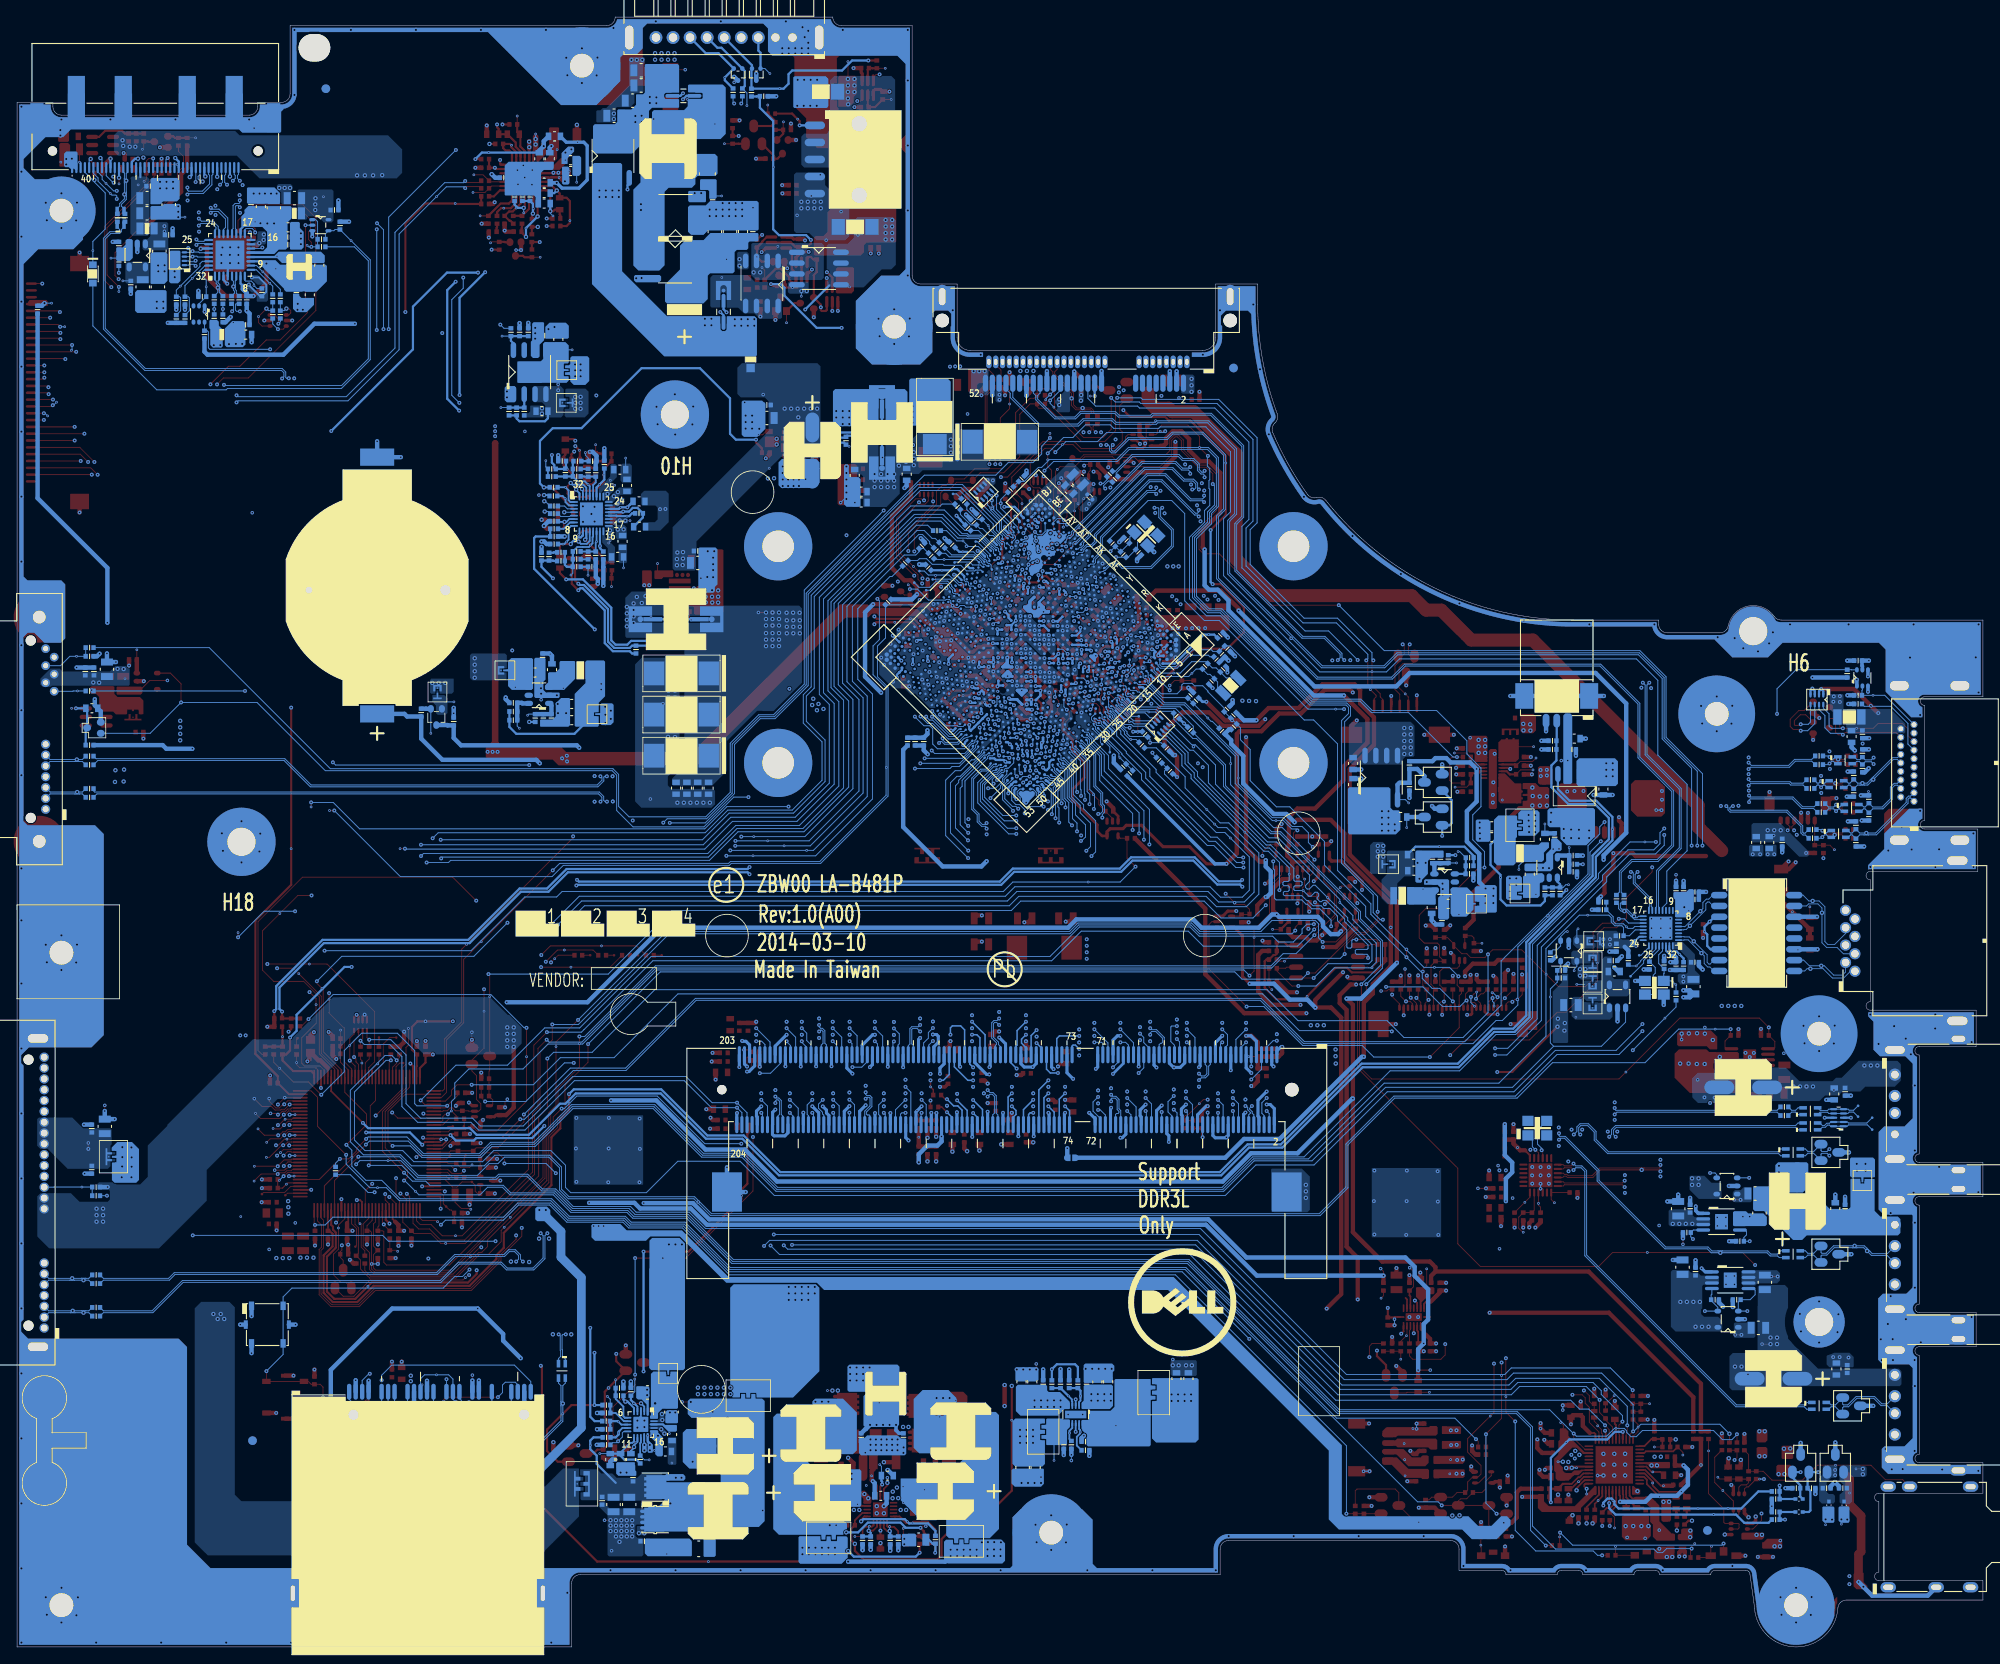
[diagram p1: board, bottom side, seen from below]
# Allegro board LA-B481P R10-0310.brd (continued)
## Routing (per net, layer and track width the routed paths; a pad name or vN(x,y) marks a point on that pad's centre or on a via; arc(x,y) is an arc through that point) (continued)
DDR_A_MA2: length 53.8
  IN2 w0.102: 115.66,97.05 115.66,97.72 114.27,99.1 114.27,99.47 113.82,99.92 113.82,100.23 114.05,100.46 114.05,102.43 113.25,103.22 113.14,103.22 111.62,104.75 111.62,105.01 110.8,105.82 v2(110.8,106.59)
  IN2 w0.216: 115.66,97.05 115.66,91.09 115.05,90.47 115.05,81.1 113.6,79.66 113.6,75.06 113.87,74.78 113.87,70.59 114.27,70.2 114.27,67 113.13,65.87 113.13,62.63 113.71,62.05 114.01,62.05 114.34,62.37 114.34,62.86 v2(113.81,63.39)
  BOTTOM w0.165: v2(110.8,106.59) 110.8,106.64 USOC1.L41 ; v2(113.81,63.39) 113.33,62.9 113.33,62.44 113.65,62.11 JDIMM1.96
DDR_A_MA3: length 55.3
  IN2 w0.102: v2(111.43,104.34) 111.51,104.25 111.51,103.45 112.17,102.79 112.42,102.79 112.45,102.82 113.08,102.82 113.64,102.26 113.64,100.94 112.88,100.18 112.88,99.18 113.39,98.68 113.92,98.68 114.42,98.18 114.42,97.05
  IN2 w0.216: v2(112.16,73.31) 112.63,73.77 112.63,74.27 112.35,74.54 112.35,84.01 111.81,84.56 111.81,86.07 112.35,86.61 112.35,90.25 112.57,90.46 112.87,90.46 113.08,90.25 113.08,83.49 113.29,83.28 113.59,83.28 113.8,83.49 113.8,90.99 114.42,91.6 114.42,97.05
  BOTTOM w0.165: v2(112.16,73.31) 113.2,72.27 113.2,70.56 113.35,70.41 JDIMM1.95 ; v2(111.43,104.34) 111.43,104.74 111.46,104.78 USOC1.H44
DDR_A_MA4: length 54.6
  IN2 w0.102: v2(113.22,102.07) 113.22,102.06 113.22,100.92 112.56,100.25 112.56,98.58 111.6,97.63 111.6,96.34
  IN2 w0.216: 111.6,96.34 111.6,93.02 104.06,85.48 104.06,83.45 104.27,83.24 104.57,83.24 104.78,83.45 104.78,85.07 105,85.28 105.3,85.28 105.51,85.07 105.51,80.21 105.3,80 104.9,80 104.69,79.79 104.69,79.49 104.9,79.27 105.3,79.27 105.51,79.06 105.51,78.38 109.65,74.23 109.65,70.57 110.81,69.4 110.81,64.64 v2(111.31,64.15)
  BOTTOM w0.102: USOC1.H50 113.45,102.3 v2(113.22,102.07)
  BOTTOM w0.165: JDIMM1.92 112.45,63 v2(111.31,64.15)
DDR_A_MA5: length 56.1
  IN2 w0.102: 113.8,95.3 113.8,97.9 v2(113.67,98.02)
  IN2 w0.216: 113.8,95.3 113.8,92.58 111.73,90.51 111.73,89.84 111.52,89.62 110.86,89.62 110.65,89.41 110.65,89.11 110.86,88.9 111.52,88.9 111.73,88.69 111.73,88.39 111.52,88.18 110.5,88.18 110.29,87.96 110.29,87.66 110.5,87.45 111.52,87.45 111.73,87.24 111.73,86.87 110.98,86.11 110.5,86.11 110.29,85.9 110.29,85.6 110.5,85.39 110.98,85.39 111.19,85.18 111.19,84.3 111.73,83.76 111.73,76.67 111.52,76.46 111.22,76.46 111.01,76.67 111.01,83.4 110.8,83.62 110.5,83.62 110.28,83.4 110.28,76.26 111.54,75.01 111.54,72.4 v2(112.16,71.78)
  BOTTOM w0.102: USOC1.G53 114.33,101.48 114.89,100.92 114.89,99.32 113.67,98.1 v2(113.67,98.02)
  BOTTOM w0.165: JDIMM1.91 112.15,70.27 112.68,70.8 112.68,71.26 v2(112.16,71.78)
DDR_A_MA6: length 56.3
  IN2 w0.102: v2(112.73,102.44) 112.73,101.8 112.91,101.62 112.91,101.05 111.69,99.84 111.69,98.05 110.98,97.33 110.98,96.34
  IN2 w0.216: v2(111.31,62.62) 112.05,62.62 112.48,62.19 112.48,61.01 112.02,60.55 110.68,60.55 110.19,61.04 110.19,69.15 109.03,70.31 109.03,73.98 104.02,78.98 104.02,82.52 103.44,83.11 103.44,85.74 110.98,93.28 110.98,96.34
  BOTTOM w0.102: USOC1.H49 112.95,102.66 v2(112.73,102.44)
  BOTTOM w0.165: JDIMM1.90 111.85,62.44 111.66,62.62 v2(111.31,62.62)
DDR_A_MA7: length 54.1
  IN2 w0.102: 110.35,96.34 110.35,96.68 110.75,97.08 110.75,97.44 111.46,98.14 111.46,100.02 112.48,101.05 v2(112.48,101.35)
  IN2 w0.216: v2(109.53,66.43) 109.53,68.93 108.41,70.05 108.41,73.72 101.3,80.82 101.3,82.24 101.52,82.45 101.82,82.45 102.03,82.24 102.03,81.15 102.74,80.44 103.16,80.44 103.4,80.68 103.4,82.26 102.82,82.85 102.82,86 110.35,93.54 110.35,96.34
  BOTTOM w0.102: v2(112.48,101.35) 112.15,101.68 USOC1.D50
  BOTTOM w0.165: v2(109.53,66.43) 110.65,65.31 JDIMM1.86
DDR_A_MA8: length 56.9
  IN2 w0.102: 112.84,95.31 112.84,97.6 113.06,97.82 v2(113.06,98.28)
  IN2 w0.216: v2(110.91,72.32) 110.91,74.73 108.2,77.44 108.2,87 108.41,87.22 108.71,87.22 108.92,87 108.92,77.81 109.14,77.6 109.44,77.6 109.65,77.81 109.65,89.31 113.17,92.83 113.17,94.6 112.84,94.93 112.84,95.31
  BOTTOM w0.102: USOC1.G52 113.77,101.69 114.21,101.25 114.26,101.25 114.64,100.87 114.64,99.45 113.75,98.56 113.34,98.56 v2(113.06,98.28)
  BOTTOM w0.165: v2(110.91,72.32) 111.55,71.69 JDIMM1.89
DDR_A_MA9: length 55.2
  IN2 w0.102: 112.22,95.98 112.22,96.52 112.3,96.6 v2(112.3,97.75)
  IN2 w0.216: v2(110.91,70.8) 110.44,70.8 110.27,70.97 110.27,74.49 107.58,77.19 107.58,84.36 107.37,84.57 107.07,84.57 106.85,84.36 106.85,78.67 106.64,78.46 106.34,78.46 106.13,78.67 106.13,85.05 106.34,85.26 106.82,85.26 107.03,85.47 107.03,85.77 106.82,85.98 106.22,85.98 106,86.19 106,86.55 106.48,87.02 106.78,87.02 107.06,86.74 107.36,86.74 107.57,86.95 107.57,87.25 107.29,87.53 107.29,87.83 107.8,88.34 108.1,88.34 108.5,87.95 108.8,87.95 109.01,88.16 109.01,88.46 108.61,88.85 108.61,89.15 112.55,93.09 112.55,94.32 112.22,94.65 112.22,95.98
  BOTTOM w0.102: v2(112.3,97.75) 112.3,98.18 112.89,98.76 113.34,98.76 113.83,99.24 113.83,100.68 113.49,101.02 USOC1.E52
  BOTTOM w0.165: v2(110.91,70.8) 110.35,70.24 JDIMM1.85
DDR_A_MA10: length 58.7
  IN2 w0.102: 118.29,99.61 117.88,100.02 116.39,100.02 115.95,100.46 v2(115.95,101.22)
  IN2 w0.216: v2(118.48,73.31) 118.98,73.8 118.98,75.55 122.01,78.59 122.01,93.25 122.22,93.47 122.52,93.47 122.74,93.25 122.74,86.02 122.95,85.81 123.25,85.81 123.46,86.02 123.46,94.44 118.29,99.61
  BOTTOM w0.102: 113.59,104.18 113.59,103.65 114.2,103.05 114.36,103.05 114.39,103.02 114.56,103.02 114.7,102.87 114.7,102.62 114.81,102.51 115.02,102.51 115.44,102.09 115.73,102.09 116.11,101.71 116.11,101.37 v2(115.95,101.22)
  BOTTOM w0.165: v2(118.48,73.31) 116.95,71.78 JDIMM1.107
DDR_A_MA11: length 56.1
  IN2 w0.102: 109.11,96.05 109.11,96.41 111.03,98.33 111.03,101.35 v2(111.74,102.06)
  IN2 w0.216: 109.11,96.05 109.11,94.05 101.31,86.25 101.01,86.25 100.8,86.46 100.8,86.76 101.61,87.58 101.61,87.88 101.4,88.09 101.1,88.09 99.92,86.91 99.92,80.44 107.16,73.2 107.16,67.65 108.85,65.96 108.85,65.18 109.13,64.91 v2(109.53,64.91)
  BOTTOM w0.102: USOC1.E51 112.52,102.06 v2(111.74,102.06)
  BOTTOM w0.165: v2(109.53,64.91) 110.05,64.39 JDIMM1.84
DDR_A_MA12: length 53.2
  IN2 w0.102: v2(111.66,102.74) 112.2,102.21 112.2,101.7 112.07,101.58 112.07,101.16 111.23,100.32 111.23,98.23 110.49,97.48 110.49,97.2 109.73,96.44 109.73,96.09
  IN2 w0.216: 109.73,96.09 109.73,93.79 102.11,86.17 102.11,83.3 101.9,83.09 101.6,83.09 101.38,83.3 101.38,85.4 101.17,85.61 100.87,85.61 100.66,85.4 100.66,80.58 107.78,73.46 107.78,69.79 108.24,69.34 108.24,68.78 107.78,68.32 107.78,67.92 v2(108.41,67.29)
  BOTTOM w0.165: USOC1.F47 111.66,103.31 v2(111.66,102.74) ; v2(108.41,67.29) 109.3,67.29 109.75,67.74 JDIMM1.83
DDR_A_MA13: length 57.3
  IN2 w0.102: 119.17,100.49 118.97,100.68 v2(116.59,100.68)
  IN2 w0.216: 119.17,100.49 124.7,94.95 124.7,79.52 122.11,76.93 122.11,76.63 122.83,75.91 122.83,75.61 122.62,75.4 122.32,75.4 121.6,76.12 121.3,76.12 121.09,75.9 121.09,75.6 121.81,74.88 121.81,74.58 121.59,74.37 121.29,74.37 120.64,75.03 120.4,75.03 120.22,74.85 120.22,73.1 119.73,72.6 119.73,70.85 119.31,70.44 117.84,70.44 117.61,70.2 117.61,69.9 117.79,69.72 119.07,69.72 119.3,69.49 119.3,66.84 118.89,66.43 v2(118.35,66.43)
  BOTTOM w0.102: v2(116.59,100.68) 115.72,100.68 114.92,101.49 114.92,101.81 114.41,102.32 USOC1.J51
  BOTTOM w0.165: JDIMM1.119 120.55,68.02 118.97,66.43 v2(118.35,66.43)
DDR_A_MA14: length 55.2
  IN2 w0.102: 108.49,96.05 108.49,96.21 110.47,98.19 110.47,99.36 v2(110.04,99.79)
  IN2 w0.216: v2(109.53,63.39) 109.05,62.91 109.05,61.89 108.8,61.64 108.45,61.64 108.21,61.89 108.21,65.72 106.54,67.39 106.54,72.9 99.3,80.14 99.3,87.18 100.86,88.75 101.62,88.75 102.11,88.26 102.44,88.26 108.49,94.31 108.49,96.05
  BOTTOM w0.102: USOC1.B49 110.66,101.02 110.42,100.77 110.42,100.51 110.04,100.13 v2(110.04,99.79)
  BOTTOM w0.165: JDIMM1.80 108.85,62.71 v2(109.53,63.39)
DDR_A_MA15: length 55.1
  IN2 w0.102: 106.7,96.98 107.29,97.56 107.65,97.56 109.22,99.13 v2(109.58,99.13)
  IN2 w0.216: 106.7,96.98 105.16,95.43 105.16,94.2 104.2,93.24 102.65,93.24 97.43,88.02 97.43,79.3 102.61,74.13 102.61,69.77 102.82,69.56 103.24,69.56 103.46,69.35 103.46,69.05 103.24,68.84 102.82,68.84 102.61,68.63 102.61,67.88 105.01,65.48 105.01,64.72 105.7,64.03 106.69,64.03 v2(107.57,64.91)
  BOTTOM w0.102: USOC1.B50 111.33,100.59 110.95,100.2 110.95,99.87 110.21,99.13 v2(109.58,99.13)
  BOTTOM w0.165: JDIMM1.78 108.25,64.23 v2(107.57,64.91)
DDR_A_ODT0: length 56.8
  TOP w0.165: RD8.2 123.02,65.34 v1(123.35,65.67) v2(123.35,66.43)
  IN2 w0.102: 119.88,104.18 119.57,104.49 118.29,104.49 114.49,108.29 113.09,108.29 v2(113.04,108.24)
  IN2 w0.216: v2(123.35,66.43) 124.36,67.44 124.36,67.74 123.53,68.57 123.53,68.87 123.74,69.08 124.04,69.08 124.87,68.25 125.17,68.25 127.05,70.14 127.05,74.7 127.99,75.64 127.99,96.06 119.88,104.18
  BOTTOM w0.165: v2(113.04,108.24) 113.17,108.37 USOC1.T41
DDR_A_ODT2: length 59.8
  TOP w0.165: RD9.2 v2(123.35,64.07)
  IN2 w0.102: 120.84,104.98 120.5,105.32 118.03,105.32 114.51,108.85 112.78,108.85 112.35,108.42 v2(112.35,107.57)
  IN2 w0.216: v2(123.35,64.07) 123.35,64.6 125.87,67.13 126.48,67.13 129.32,69.98 129.32,96.49 120.84,104.98
  BOTTOM w0.165: USOC1.P42 112.38,107.6 v2(112.35,107.57)
DDR_A_RAS#: length 55
  IN2 w0.102: v2(113.08,105.34) 114.15,105.34 114.43,105.61 115.08,105.61 116.68,104.01 116.68,103.86 116.89,103.65
  IN2 w0.216: v2(118.35,62.6) 117.68,63.26 117.68,64.34 120.35,67 120.35,72.18 123.89,75.72 123.89,77.75 125.33,79.19 125.33,95.21 116.89,103.65
  BOTTOM w0.165: JDIMM1.110 117.85,62.1 v2(118.35,62.6) ; v2(113.08,105.34) 113.08,105.69 USOC1.M45
DDR_A_RST#: length 3.6
  TOP w0.102: v2(91.45,59.76) 91.57,59.88 CD3.1 RD5.1
  BOTTOM w0.102: JDIMM1.30 v2(91.45,59.76)
DDR_A_RST#_CPU: length 65.6
  TOP w0.102: v2(90.86,64.17) 91.37,64.17 v1(91.84,63.69) 93.22,62.32 93.48,62.32 93.6,62.19 RD3.2 RD5.2
  IN2 w0.102: v2(111.92,107.98) 111.82,107.88 111.06,107.88 110.81,108.13 110.34,108.13 110.24,108.02 109.76,108.02 109.43,108.35 108.54,108.35 107.29,107.11 104.98,107.11 103.97,106.09 101.51,106.09 100.82,105.4
  IN2 w0.127: 100.82,105.4 89.42,94.01 89.42,74.88 88.5,73.95 88.5,70.18 88.83,69.85 88.83,66.62 90.86,64.59 v2(90.86,64.17)
  BOTTOM w0.102: v2(111.92,107.98) 112.04,108.1 USOC1.P41
DDR_A_WE#: length 55.7
  IN2 w0.102: 119.53,97.41 117.42,99.52 v2(116.31,99.52)
  IN2 w0.216: v2(118.35,67.96) 118.06,67.96 117.81,67.7 117.81,66.77 117.6,66.56 117.22,66.56 116.99,66.78 116.99,67.99 117.35,68.34 117.35,69.13 116.87,69.61 116.87,71.25 117.85,72.23 117.85,75.3 121.39,78.85 121.39,93.88 121.6,94.09 122.11,94.09 122.32,94.3 122.32,94.6 122.11,94.81 121.6,94.81 121.39,95.02 121.39,95.58 121.18,95.79 120.88,95.79 120.67,95.58 120.67,91.95 120.45,91.74 120.15,91.74 119.94,91.95 119.94,97 119.53,97.41
  BOTTOM w0.102: USOC1.H51 114.01,102.42 114.71,101.71 114.71,101.4 115.15,100.97 115.15,100.69 v2(116.31,99.52)
  BOTTOM w0.165: v2(118.35,67.96) 118.75,68.36 JDIMM1.113
DDR_CORE_PWROK: length 48.8
  TOP w0.102: v2(88.75,88.31) v3(87.7,87.27) 87.51,87.07 86.54,87.07 85.96,86.48 RC30.2 86.01,85.88 CC19.1 87.09,85.69 UC7.4 ; v2(115.43,111.33) 115.43,111.33 CC1.1
  IN2 w0.102: v2(115.43,111.33) 115.5,111.26 115.5,110.18 115.46,110.15 115.46,110.15 115.14,109.83 114.42,109.83 113.89,109.29 111.53,109.29 111.2,108.96 110.9,108.96 110.49,109.37 109.07,109.37 107.09,107.39 104.04,107.39 103.13,106.47 101.53,106.47 100.64,105.58
  IN2 w0.127: v2(88.75,88.31) 89.17,88.73 89.17,94.11 100.64,105.58
  BOTTOM w0.102: v2(115.43,111.33) 115.55,111.21 115.55,110.52 USOC1.AB42
DDR_PWROK: length 125.3
  TOP w0.102: v2(157.97,31.93) 157.97,30.73 160.56,28.14 160.56,24.97 159.96,24.37 v2(159.96,24.12) ; v2(144.15,59.79) 144.15,53.46 152.02,45.59 v3(154.71,45.59) v2(157.97,45.59)
  IN2 w0.127: v2(115.96,110.8) 117.37,112.22 118.01,112.22 118.49,111.73 119.28,111.73 120.4,112.85 120.4,113.18 121.98,114.76 124.34,114.76 124.7,114.41 127.68,114.41 135.03,107.06 135.03,101.87 141.85,95.05 141.85,86.52 142.78,85.59 142.78,70 144.15,68.62 v2(144.15,59.79)
  BOTTOM w0.102: PU200.10 159.29,25.27 159.46,25.09 159.46,24.61 v2(159.96,24.12) 160.13,23.95 160.61,23.95 PR210.2 ; v2(157.97,31.93) v2(157.97,45.59) ; USOC1.AD42 116.19,111.03 v2(115.96,110.8)
DDR_RCOMP0: length 4
  TOP w0.254: RC3.2 118.84,110.31 117.76,110.31 117.34,110.72 v1(117.01,110.72) 116.77,110.72 v2(116.42,110.37)
  BOTTOM w0.254: v2(116.42,110.37) 116.76,110.37 USOC1.AD44
DDR_RCOMP1: length 2
  TOP w0.254: v2(118.69,110.79) 119.63,110.79 RC4.2
  BOTTOM w0.254: v2(118.69,110.79) 118.6,110.7 USOC1.AF45
DDR_RCOMP2: length 2.1
  TOP w0.254: v2(117.38,109.48) 117.5,109.6 118.28,109.6 RC5.2
  BOTTOM w0.254: USOC1.AD45 117.38,109.98 v2(117.38,109.48)
DDR_TERMN0: length 4.2
  TOP w0.254: v2(117.68,111.79) 118.55,111.79 118.79,111.55 v1(119.52,111.55) 120.14,111.55 RC1.2
  BOTTOM w0.254: v2(117.68,111.79) 117.33,112.14 117.32,112.14 117.09,111.91 117.09,111.7
DDR_TERMN1: length 3.8
  TOP w0.254: RC2.2 120.84,112.12 119.18,112.12 118.74,112.57 v2(118.47,112.57)
  BOTTOM w0.254: v2(118.47,112.57) 118.36,112.46 118.18,112.46 118.11,112.39 USOC1.AH42
DEVSLP0: length 199
  TOP w0.102: v2(105.34,138.5) 105.21,138.63 RC53.2 104.63,137.92 104.82,137.73 UC10.4 ; v2(109.35,141.76) v1(109.35,142.29)
  IN2 w0.127: v2(219.87,52.91) 215.22,48.26 v2(209.81,48.26) ; v2(105.34,138.5) 105.87,138.5 105.95,138.58 106.18,138.58 v2(109.35,141.76) ; v2(174.32,47.57) 171.5,47.57 170.46,48.61 170.46,49.2 169.98,49.68 167.18,49.68 165.79,48.28 159.9,48.28 155.27,52.91 155.27,71.02 156.87,72.62 156.87,94.44 v2(154.66,96.64)
  BOTTOM w0.102: v2(109.35,141.76) 110.32,140.79 110.32,139.88 111.33,138.86 114.23,138.86 115.7,137.39 124.07,137.39 137.91,123.54 137.91,112.81 141.65,109.07 143.39,109.07 146.59,105.87 146.59,100.1 149.59,97.1 154.21,97.1 v2(154.66,96.64) ; v2(174.32,47.57) 186.87,47.57 187.56,48.26 v2(209.81,48.26) ; RS8.1 v2(219.87,52.91)
DEVSLP_SOC: length 14.5
  TOP w0.102: v2(111.87,126.92) 108.89,126.92 105.52,130.3 105.52,134.5 v1(105.39,134.62) 105.22,134.8 104.42,134.8 104.17,135.05 UC10.2
  BOTTOM w0.102: v2(111.87,126.92) 111.87,126.77 112.08,126.56 USOC1.AY14
DH_1.35VP: length 4.5
  TOP w0.102: v4(154.52,25.02) v1(153.95,25.02)
  IN2 w1.016: 152.81,21.02 152.81,23.87 153.57,24.64
  vias: v4(152.53,19.84) v4(153.19,19.84) v4(154.91,25.52)
DH_CHG: length 15.2
  IN2 w1.016: 166.04,172.92 165.66,172.92 165,172.26 165,168.65 157.74,161.39
  vias: v1(165.69,173.02) v2(166.96,172.84) v2(167.54,172.84) v4(157.2,160.5) v4(157.84,160.48)
DISPOFF#: length 13.9
  TOP w0.102: RX9.1 v4(221.34,172.01)
  BOTTOM w0.102: DX1.1 v1(221.52,163.71) 221.52,164.79 220.07,166.24 220.07,170.48 221.34,171.75 v4(221.34,172.01) 221.56,172.01 222.45,172.9 JLVDS.37
DL_1.35VP: length 8.2
  TOP w0.102: v4(156.24,23.05) v1(155.71,23.05)
  IN2 w1.016: 157,14.35 157,21.99
  vias: v4(156.24,23.68) v4(156.89,13.33) v4(157.52,13.33)
DL_CHG: length 20.2
  IN2 w1.016: 168.58,177.39 162.89,177.39 155.81,170.3 151.9,170.3
  BOTTOM w0.102: v4(169.62,176.79) v1(169.62,177.39)
  vias: v4(150.22,170.46) v4(150.98,170.46) v4(169.62,176.16)
DRAM_VDD_S4_CLK: length 5.6
  TOP w0.102: v2(115.5,112.63) v1(115.5,112.04)
  TOP w0.508: v2(115.5,112.63) 116.01,112.63 116.11,112.72 116.8,112.72 CC27.1 CC28.1 117.94,113.87 RC54.1
  BOTTOM w0.254: USOC1.AD38 115.41,112.73 ; 115.41,112.73 v2(115.5,112.63) ; 115.41,112.73 115.4,112.73 USOC1.AF38
EC_ENVDD: length 113.3
  TOP w0.102: v2(195.89,88.11) 197.49,88.11 v1(199.6,86) 201.63,83.97 201.63,79.35 200.32,78.04 196.81,78.04 194.97,76.2 194.97,69.52 193.19,67.73 UE1.71
  IN2 w0.127: v2(218.47,161.11) 217.83,160.48 217.83,153.47 209.12,144.76 209.12,106.66 195.89,93.42 v2(195.89,88.11)
  BOTTOM w0.102: RX8.2 v2(218.47,161.11)
EC_LID_OUT#: length 124.3
  TOP w0.102: v2(183.1,64.08) 182.62,63.6 UE1.101 ; v2(78.41,84.74) 78.41,85.13 78.73,85.44 79.39,85.44 79.72,85.77 79.72,89.02 79.49,89.25 v1(79.49,90.03) 79.72,90.26 U62.2
  BOTTOM w0.102: v2(78.41,84.74) 79.23,84.74 79.8,84.17 79.8,83.68 80.83,82.65 82.57,82.65 83.25,83.34 91.85,83.34 92.93,84.42 105.88,84.42 109.35,80.95 156.09,80.95 164.46,72.58 168.56,72.58 172.93,68.21 178.97,68.21 v2(183.1,64.08)
EC_MUTE#: length 190.2
  TOP w0.102: RA7.1 v2(28.83,24.94) ; v2(47.96,25.02) 47.96,24.48 46.62,23.15 UA1.47 ; v2(189.18,56.46) 189,56.64 189,63.45 188.39,64.07 UE1.83
  BOTTOM w0.102: v2(189.18,56.46) 185.32,56.46 183.7,54.84 174.22,54.84 173.87,55.19 170.64,55.19 168.91,53.46 167.36,53.46 165.3,51.41 158.68,51.41 157.99,50.72 151.74,50.72 146.43,45.41 93.03,45.41 75.44,27.81 50.78,27.81 47.98,25.02 v2(47.96,25.02) 47.65,24.71 44.1,24.71 43.18,25.63 42.04,25.63 41.75,25.33 41.75,25.16 41.24,24.65 40.63,24.65 39.91,25.37 31.58,25.37 30.51,24.31 29.42,24.31 28.83,24.89 v2(28.83,24.94)
EC_ON: length 114.8
  TOP w0.102: v3(123.89,14.16) 124.32,14.16 v2(124.51,13.97)
  TOP w0.203: UE1.112 182.58,59.2 v2(182.91,58.88)
  TOP w0.254: v2(124.51,13.97) 124.13,13.59 124.13,13.43 PR115.1
  IN2 w0.254: v4(133.23,13.43) 133.81,13.43 134.12,13.74 135.97,13.74 139.04,16.81 139.04,31.27 141.63,33.86 158.3,33.86 160.71,31.44 173.4,31.44 188.65,46.69 188.65,48.36 189.89,49.6 189.89,52.45 190.38,52.93 190.38,56.13 190.17,56.34 190.17,56.89 189.89,57.17 189.89,58.11 190.25,58.47 190.25,59.56 v2(189.49,60.32)
  BOTTOM w0.254: v2(124.51,13.97) 126.24,13.97 126.85,14.58 130.69,14.58 131.83,13.43 v4(133.23,13.43) ; v2(182.91,58.88) 184.36,60.32 v2(189.49,60.32)
EC_RSMRST#: length 195.8
  TOP w0.102: CC54.1 60.63,76.55 60.63,75.91 v2(60.52,75.79) 60.38,75.65 JDB1.10 ; RC26.1 CC14.1 94.73,113.31 v3(95.31,112.73) v2(95.31,112.16) ; UE1.100 180.2,64 179.48,64.72 179.48,65.28 178.84,65.91 v2(177.12,65.91)
  IN2 w0.102: v2(95.31,112.16) 93.51,110.37
  IN2 w0.127: v2(69.28,72.17) 69.12,72.34 64.14,72.34 60.76,75.72 60.6,75.72 v2(60.52,75.79) ; v2(69.96,77.39) 70.15,77.39 77.18,84.43 77.18,85.52 77.85,86.19 77.85,87.91 78.41,88.47 78.41,88.99 78.85,89.42 78.85,93.32 79.02,93.5 79.02,96.78 92.58,110.34 93.48,110.34 93.51,110.37
  BOTTOM w0.102: v2(177.12,65.91) 169.9,65.91 166.73,69.09 160.43,69.09 152.95,76.57 84.42,76.57 80.11,72.26 69.37,72.26 v2(69.28,72.17) ; v2(69.96,77.39) 65.64,77.39 63.33,75.08 61.31,75.08 60.6,75.79 v2(60.52,75.79) ; v2(95.31,112.16) 96.63,113.48 96.63,113.7 USOC1.B10
EC_RST#: length 3.9
  TOP w0.127: UE1.37 198.69,54.4 v1(198.83,54.26) 199.29,53.8 CE11.1 RE8.1
EC_RX: length 191.3
  TOP w0.102: JMINI.51 116.5,149.72 115.98,149.2 RM13.1 116.23,148.61 116.46,148.38 116.46,147.37 116.95,146.89 116.95,143.15 116.44,142.64 v1(116.44,140.43) v2(116.44,138.68) ; UE1.31 195.19,49.94 194.72,49.48 194.72,46.87 195,46.59 195,41.29 193.61,39.9 190.31,39.9 188.4,41.81 177.15,41.81 173.69,45.27 173.69,45.71 171.25,48.15 v2(171.25,49.13)
  IN2 w0.127: v2(116.44,138.68) 116.49,138.63 117.58,138.63 120.09,136.12 123.73,136.12 125.43,134.42 129.07,134.42 132.68,130.8 132.68,130.21 137.52,125.37 143.21,125.37 145.95,122.63 145.95,113.73 149.89,109.8 149.89,107.9 151.92,105.87 161.42,105.87 164.07,103.21 164.07,93.55 159.67,89.15 159.67,73.37 156.8,70.5 156.8,53.54 161.55,48.79 165.57,48.79 166.97,50.19 170.19,50.19 v2(171.25,49.13)
EC_SCI#: length 234
  TOP w0.102: U66.2 96.46,138.38 95.08,139.76 95.08,141.48 94.67,141.88 94.4,141.88 93.95,141.43 93.95,140.28 91.98,138.31 91.02,138.31 90.26,137.55 v2(90.26,136.35) ; v2(79.11,79.02) 78.26,79.02 73.53,83.74 72.53,83.74 70.94,85.33 v2(70.94,86.19) ; UE1.20 190.79,49.54 190.4,49.16 190.4,46.12 R489.2 190.15,45.36 190.15,44.32 189.08,43.25 178.96,43.25 176.18,46.04 175.16,46.04 173.66,47.53 173.66,48.84 v1(173.31,49.2) 168.08,54.43 168.08,59.89 167.03,60.93 167.03,62.05 166.17,62.91 166.17,65.86 163.48,68.55 v2(163.48,70.69)
  BOTTOM w0.102: v2(163.48,70.69) 155.02,79.15 87.69,79.15 86.83,78.29 79.84,78.29 v2(79.11,79.02) ; v2(70.94,86.19) 70.94,87.99 74.81,91.86 74.81,108.48 74.12,109.17 74.12,110.24 74.55,110.67 78.8,110.67 89.39,121.26 90.86,121.26 92.64,123.03 92.64,130.14 90.88,131.89 90.88,133.07 90.07,133.89 90.07,136.15 v2(90.26,136.35)
EC_SMB_CK1: length 184.8
  TOP w0.102: PR717.1 176.2,171.7 177.71,171.7 v2(177.88,171.88) ; RP36.4 190.9,71.87 191.41,71.36 v1(191.41,70.53) v2(191.41,68.74) 190.79,68.12 UE1.77
  IN2 w0.127: v2(146.35,180.96) 148.12,180.96 151.1,183.94 159.81,183.94 162.57,181.19 174.64,181.19 180.14,175.69 180.14,172.7 179.14,171.7 178.05,171.7 v2(177.88,171.88) ; v2(204.68,146.75) 204.85,146.58 206.18,146.58 207.29,145.46 207.29,107.41 193.32,93.44 193.32,73.97 191.54,72.19 191.54,68.88 v2(191.41,68.74)
  BOTTOM w0.102: v2(146.35,180.96) 146.49,181.1 PR8.2 ; v2(177.88,171.88) 178.08,171.68 180.29,171.68 186.11,165.86 186.11,152.29 191.81,146.59 204.52,146.59 v2(204.68,146.75)
EC_SMB_CK2: length 335.5
  TOP w0.102: v2(101.47,146.45) 101.65,146.27 101.65,142.6 102.93,141.32 105.61,141.32 109.53,145.24 110.65,145.24 110.85,145.44 R432.2 111.66,145.74 112.88,144.52 112.88,139.55 114.76,137.67 117.51,137.67 QC3.1 118.63,136.55 120.3,136.55 121.16,135.68 121.77,135.68 122.15,135.31 122.15,133.78 125.24,130.69 v2(125.24,128.45) ; QX6.3 199.22,154.51 v2(199.83,154.51) ; RE15.1 v2(190.15,71.07) 189.9,71.32 RP36.2 ; v2(71.45,115.67) 71.61,115.51 v1(71.61,114.35) 71.61,112.74 70.64,111.78 70.64,111.39 70.35,111.1 JTP.5
  IN2 w0.127: v2(199.83,154.51) 199.7,154.63 199.17,154.63 198.94,154.39 198.94,153.86 199.4,153.39 201.07,153.39 203.51,150.95 203.51,145.74 205.62,143.63 205.62,107.17 192.26,93.81 192.26,74.34 190.15,72.23 v2(190.15,71.07) ; v2(125.24,128.45) 125.7,127.99 127.26,127.99 133.51,121.74 133.51,119.78 145.22,108.07 145.22,99.26 144.58,98.63 144.58,93.22 147.2,90.61 147.2,67.85 145.16,65.82 145.16,63.68 145.61,63.23 v2(146.02,63.23)
  BOTTOM w0.102: v2(190.15,71.07) 189.71,70.64 186.72,70.64 185.3,69.22 185.3,63.36 183.46,61.52 177.22,61.52 176.3,60.6 170.87,60.6 165.08,66.39 152.2,66.39 149.03,63.23 v2(146.02,63.23) 145.45,62.65 JDIMM1.202 ; v2(101.47,146.45) 98.68,146.45 98.5,146.28 89.57,146.28 85.07,141.78 85.07,131.8 85.88,130.99 85.88,126.94 79.56,120.62 75.65,120.62 71.61,116.58 71.61,115.83 v2(71.45,115.67) ; RT21.2 200.44,155.12 v2(199.83,154.51)
EC_SMB_CK2_EC: length 2.7
  TOP w0.102: RE15.2 190.15,68.91 189.99,68.75 v1(189.99,68.46) UE1.79
EC_SMB_CK2_R: length 4.3
  TOP w0.102: R432.1 109.53,146.15 v2(109.33,146.15)
  BOTTOM w0.102: JMINI.30 108.1,147.37 v2(109.33,146.15) 109.33,145.81 v1(108.88,145.36)
EC_SMB_DA1: length 186.2
  TOP w0.102: PR719.1 176.2,171.22 177.71,171.22 v2(177.88,171.05) ; RP36.3 190.4,71.58 190.91,71.07 v2(190.91,69.16) 190.68,68.94 190.68,68.6 190.39,68.31 UE1.78
  IN2 w0.127: v2(190.91,69.16) 190.91,72.27 192.79,74.15 192.79,93.62 206.78,107.62 206.78,145.25 205.96,146.07 204.83,146.07 v2(204.68,145.92) ; v2(177.88,171.05) 178.03,171.19 179.35,171.19 180.65,172.49 180.65,175.9 174.85,181.7 162.78,181.7 159.97,184.5 150.94,184.5 148.03,181.59 146.15,181.59 v2(145.52,180.96)
  BOTTOM w0.102: v2(145.52,180.96) 145.39,181.1 PR9.2 ; v2(204.68,145.92) 204.49,146.11 191.61,146.11 185.63,152.09 185.63,165.66 v1(181.24,170.04) 180.09,171.19 178.03,171.19 v2(177.88,171.05)
EC_SMB_DA2: length 336.9
  TOP w0.102: JTP.6 71.35,111.17 71.12,111.39 71.12,111.58 v1(71.8,112.25) 72.09,112.54 72.09,115.48 v2(72.27,115.67) ; RP36.1 189.4,71.46 v2(189.13,71.19) RE16.1 ; v2(125.95,128.5) 125.95,130.67 122.63,133.98 122.63,135.51 121.95,136.19 121.53,136.19 QC4.1 120.78,136.94 119.37,136.94 118.16,138.15 114.96,138.15 113.36,139.75 113.36,144.72 111.68,146.4 111.2,146.4 R434.2 110.85,147.32 110.65,147.52 109.35,147.52 108.82,146.99 108.82,145.21 105.41,141.81 103.13,141.81 102.17,142.76 v2(102.17,146.45) ; QX6.6 200.22,156.17 199.77,155.73 v2(199.77,155.14)
  IN2 w0.127: v2(199.77,155.14) 198.96,155.14 198.43,154.61 198.43,153.64 199.19,152.88 200.86,152.88 203,150.74 203,145.53 205.08,143.45 205.08,107.55 191.75,94.22 191.75,74.55 189.13,71.93 v2(189.13,71.19) ; v2(146.02,63.81) 145.67,64.16 145.67,65.61 147.7,67.64 147.7,90.82 145.09,93.43 145.09,98.42 145.72,99.05 145.72,108.29 134.01,119.99 134.01,121.95 127.47,128.5 v2(125.95,128.5)
  BOTTOM w0.102: JDIMM1.200 144.85,62.64 v2(146.02,63.81) 148.93,63.81 152,66.88 165.28,66.88 171.07,61.08 176.1,61.08 177.02,62 183.11,62 184.81,63.7 184.81,69.42 186.59,71.19 v2(189.13,71.19) ; v2(199.77,155.14) 199.55,155.37 RT22.2 ; v2(72.27,115.67) 72.09,115.86 72.09,116.38 75.77,120.06 79.68,120.06 86.36,126.74 86.36,131.19 85.55,132 85.55,141.58 89.77,145.79 98.7,145.79 98.88,145.97 101.69,145.97 v2(102.17,146.45)
EC_SMB_DA2_EC: length 2.8
  TOP w0.102: RE16.2 189.13,68.93 189.59,68.48 189.59,68.47 UE1.80
EC_SMB_DA2_R: length 3
  TOP w0.102: R434.1 109.4,146.76 v2(109.33,146.84)
  BOTTOM w0.102: JMINI.32 108.9,147.26 v2(109.33,146.84) 109.85,146.31 v1(109.85,146.23)
EC_SMI#: length 151.2
  TOP w0.102: UE1.15 188.79,50 189.39,49.4 R488.2 189.03,48.79 188.85,48.61 188.85,44.33 188.47,43.94 179.54,43.94 168.53,54.95 168.53,60.08 167.86,60.75 167.86,62.54 167.01,63.39 167.01,65.48 164.49,67.99 v1(164.49,70.74) v2(164.49,71.58) ; v2(78.35,83.45) 78.34,83.45 76.01,85.77 76.01,88.57 77.24,89.8 77.24,91.22
  BOTTOM w0.102: v2(164.49,71.58) 163.87,71.58 155.59,79.86 83.44,79.86 82.01,81.28 80.52,81.28 v2(78.35,83.45)
EC_SPI_CLK_R: length 41.4
  TOP w0.102: v2(168.43,80.34) 167.06,81.71 v1(166.26,81.71) 162.89,81.71 RE20.1 ; v2(180.27,53.41) 180.46,53.6 UE1.126
  IN2 w0.127: v2(180.27,53.41) 178.12,53.41 174.68,56.85 174.68,60 171.94,62.74 171.94,65.36 169.47,67.82 169.47,73.39 168.43,74.43 v2(168.43,80.34)
EC_SPI_CS0#: length 41.2
  TOP w0.102: v2(167.82,80.26) v1(167.39,80.69) 166.98,81.1 RE21.1 ; UE1.128 180.9,52.8 180.75,52.65 v2(180.75,51.38)
  IN2 w0.127: v2(167.82,80.26) 167.82,74.32 168.96,73.18 168.96,67.61 171.43,65.15 171.43,62.53 172.85,61.11 172.85,56.31 175.42,53.74 177.07,53.74 179.43,51.38 v2(180.75,51.38)
EC_SPI_MISO_1: length 41.5
  TOP w0.102: v2(168.99,79.7) v1(165.48,79.7) 160.89,79.7 RE19.1 ; UE1.120 179.91,56 179.43,55.52 178.35,55.52 v2(178.03,55.84)
  IN2 w0.127: v2(178.03,55.84) 175.19,58.68 175.19,60.21 172.44,62.95 172.44,65.57 169.98,68.03 169.98,73.6 168.99,74.59 v2(168.99,79.7)
EC_SPI_MOSI_1: length 45.6
  TOP w0.102: v2(168.96,81.13) 167.9,82.19 v1(161.9,82.19) 157.79,82.19 RE17.1 ; UE1.119 179.52,56.4 v2(179.05,55.93)
  IN2 w0.127: v2(179.05,55.93) 178.24,56.74 177.55,56.74 175.44,58.85 175.44,60.32 172.7,63.06 172.7,65.68 170.23,68.14 170.23,79.86 v2(168.96,81.13)
EC_TX: length 194.9
  TOP w0.102: v2(171.91,48.26) 171.91,47.81 173.92,45.8 173.92,45.36 177.25,42.03 188.5,42.03 190.4,40.13 193.51,40.13 194.77,41.39 194.77,46.49 194.49,46.77 194.49,50.04 194.79,50.33 UE1.30 ; v2(115.17,138.68) 115.17,144.09 114.07,145.18 v1(114.07,145.73) 114.07,147.29 114.63,147.85 114.63,148.16 RM11.2 115.09,149.71 115.7,150.31 JMINI.49
  IN2 w0.127: v2(115.17,138.68) 114.43,137.95 114.43,137.17 114.95,136.65 115.18,136.65 115.79,137.26 117.86,137.26 119.76,135.35 122.71,135.35 123.47,134.59 123.47,134.14 123.83,133.78 129.34,133.78 132.43,130.7 132.43,130.11 137.42,125.12 143.11,125.12 145.7,122.52 145.7,113.62 149.63,109.69 149.63,107.8 151.82,105.61 161.32,105.61 163.82,103.11 163.82,93.66 159.31,89.15 159.31,73.37 156.54,70.6 156.54,53.44 161.45,48.54 165.68,48.54 167.08,49.93 170.09,49.93 170.72,49.31 170.72,48.71 171.17,48.26 v2(171.91,48.26)
ECAGND: length 140.2
  TOP w0.203: 193.99,67.9 UE1.69
  TOP w0.254: PC7.2 v2(200.26,74.55) ; PH1.2 124.31,118.97 124.31,119.58 125.28,120.55 v1(125.71,120.55) 129.65,120.55 v2(129.92,120.83)
  TOP w0.508: v2(196.37,68.65) 196.14,68.88 196.14,69.53 LE2.2 195.09,68.78 194.87,68.78 193.99,67.9 ; CE7.2 v2(199.98,48.84) ; PC7.2 PR20.2 v2(201.07,72.72) ; v2(200.74,67) 200.77,66.98 CE9.1
  IN2 w0.254: v2(144.55,91.44) 144.35,91.23 143.44,91.23 142.98,91.69 142.98,97.13 136.43,103.68 136.43,106.98 138.49,109.04 138.49,111.6 131.02,119.08 131.02,119.99 130.48,120.52 130.23,120.52 v2(129.92,120.83)
  IN2 w0.508: v2(199.98,48.84) 199.22,49.6 198.15,49.6 197.39,50.37 197.39,63.65 v2(200.74,67)
  BOTTOM w0.254: v2(144.55,91.44) 144.78,91.21 166,91.21 168.28,88.92 171.5,88.92 177.52,82.9 194.6,82.9 200.03,77.47 200.03,74.78 v2(200.26,74.55)
EDID_CLK: length 22.1
  IN2 w0.127: v2(209.83,163.01) 214.33,163.01 219.84,168.52 219.84,170.13 219.25,170.72 v2(218.71,170.72)
  BOTTOM w0.102: RP56.3 v2(209.83,163.01) 209.78,163.07 209.32,163.07 209.22,162.96 UT2.29 ; v2(218.71,170.72) 219.09,170.72 v1(219.98,171.61) 220.42,172.05 220.42,172.44 220.95,172.96 JLVDS.34
EDID_DATA: length 22.1
  IN2 w0.127: v2(209.83,163.65) 209.93,163.55 214.15,163.55 219.33,168.73 219.33,169.92 219.04,170.21 218.82,170.21 218.71,170.1 v2(218.71,169.77)
  BOTTOM w0.102: RP56.4 209.97,163.51 v2(209.83,163.65) 209.73,163.55 209.11,163.55 209.02,163.46 UT2.28 ; v2(218.71,169.77) 218.71,170.12 218.82,170.23 219.28,170.23 v1(219.48,170.43) 220.91,171.85 220.91,172.24 221.45,172.78 JLVDS.35
EDP_BIA_PWM: length 217
  TOP w0.102: v2(203.1,165.87) 203.24,166.01 RX36.1 204.5,167.26 202.67,169.09 196.89,169.09 195.38,167.58 195.38,156.69 203.29,148.78 206.21,148.78 v2(206.96,148.03) ; UC4.4 101.09,94.82 R378.2 100.31,92.48 v2(99.32,91.49)
  IN2 w0.127: v2(206.96,148.03) 208.36,146.63 208.36,107.04 194.95,93.63 194.95,82.22 v2(194.36,81.63)
  BOTTOM w0.102: UT2.16 202.98,165.75 v2(203.1,165.87) ; v2(194.36,81.63) 177.19,81.63 170.89,87.93 167.16,87.93 166.52,88.58 114.8,88.58 113.69,89.69 v1(104.87,89.69) 101.12,89.69 v2(99.32,91.49)
EDP_CPU_AUX: length 138.3
  IN2 w0.127: v2(96.89,135.19) 97.01,135.31 98.05,135.31 98.58,135.84 98.58,138.46 100.42,140.3 100.42,142.55 102.16,144.3 109.91,144.3 110.65,145.03 118.4,145.03 124.01,150.64 156.14,150.64 164.57,159.08 202.98,159.08 203.86,158.19 206.12,158.19 206.68,157.63 206.68,156.98 206.57,156.87 v2(206.28,156.87)
  BOTTOM w0.102: USOC1.AK3 104.6,126.96 104.18,126.96 104,127.14 104,127.53 103.22,128.31 103.22,130.03 97.89,135.36 97.06,135.36 v2(96.89,135.19) ; CX43.1 v2(206.28,156.87) RT18.1
EDP_CPU_AUX#: length 138.2
  IN2 w0.127: v2(207.29,156.87) 206.94,157.22 206.94,157.74 206.23,158.45 203.97,158.45 203.08,159.33 164.47,159.33 156.04,150.9 123.9,150.9 118.29,145.29 110.54,145.29 109.8,144.55 102.06,144.55 100.16,142.66 100.16,140.41 98.32,138.57 98.32,135.94 97.95,135.57 97.07,135.57 96.89,135.75 v2(96.89,135.94)
  BOTTOM w0.102: CX44.1 v2(207.29,156.87) RT17.2 ; v2(96.89,135.94) 96.89,135.72 97.03,135.57 97.98,135.57 103.43,130.12 103.43,128.4 104.21,127.62 104.21,127.35 USOC1.AK2
EDP_CPU_HPD: length 174.9
  TOP w0.102: v2(195.94,99.02) v1(195.94,98.49)
  IN2 w0.102: 115.65,111.76 114.1,111.76 112.48,110.14 111.89,110.14 111.16,110.87 110.84,110.87 110.6,110.62 v2(106.64,110.62)
  IN2 w0.127: v2(139.98,98.52) 139.98,98.7 135.28,103.4 135.28,107.16 127.54,114.91 126.75,114.91 125.89,115.77 125.05,115.77 124.75,116.07 120.87,116.07 118.43,113.63 117.52,113.63 115.65,111.76 ; v2(195.94,99.02) 204.8,107.88 204.8,141.73 200.1,146.43 200.1,151.51 v2(200.74,152.14)
  BOTTOM w0.102: v2(139.98,98.52) 147.2,98.52 149.8,95.92 190.25,95.92 193.35,99.02 v2(195.94,99.02) ; Q2309.6 208.44,155.32 R377.2 208.13,154.33 207.98,154.18 207.98,152.32 207.8,152.14 v2(200.74,152.14) ; USOC1.K30 106.71,110.55 v2(106.64,110.62)
EDP_CPU_LANE_N0: length 139.8
  IN2 w0.127: v2(97.1,133.56) 96.7,133.56 96.6,133.67 96.6,133.93 96.9,134.24 98.56,134.24 99.6,135.27 99.6,137.68 101.18,139.27 101.18,142.17 102.5,143.48 110.2,143.48 110.93,144.22 118.72,144.22 124.36,149.86 156.44,149.86 164.52,157.94 201.35,157.94 201.96,157.33 204.45,157.33 204.78,157 204.78,156.69 204.69,156.6 v2(204.29,156.6)
  BOTTOM w0.102: v2(204.29,156.6) 204.68,156.6 204.8,156.73 204.8,157.4 204.73,157.48 CX46.1 ; v2(97.1,133.56) 96.67,133.56 96.59,133.48 96.59,132.42 95.11,130.95 95.11,129.09 97.53,126.68 100.8,126.68 101.06,126.95 101.07,126.95 101.2,127.07 102.32,127.07 102.88,126.51 102.99,126.51 USOC1.AG1
EDP_CPU_LANE_P0: length 139.8
  IN2 w0.127: v2(205.19,156.6) 205.03,156.76 205.03,157.1 204.55,157.58 202.07,157.58 201.46,158.19 164.41,158.19 156.33,150.11 124.25,150.11 118.62,144.48 110.83,144.48 110.09,143.74 102.39,143.74 100.93,142.27 100.93,139.37 99.34,137.78 99.34,135.38 98.45,134.49 96.8,134.49 96.34,134.03 96.34,133.71 v2(96.19,133.56)
  BOTTOM w0.102: v2(96.19,133.56) 96.37,133.38 96.37,132.51 94.9,131.04 94.9,129 97.44,126.46 100.89,126.46 101.22,126.79 101.22,126.8 101.28,126.87 102.23,126.87 102.86,126.24 103.06,126.15 103.14,126.11 USOC1.AG3 ; CX42.1 205.02,157.24 205.02,156.77 v2(205.19,156.6)
EDP_HPD: length 5.3
  BOTTOM w0.102: UT2.32 208.44,161.46 208.63,161.27 208.63,160.66 208.23,160.27 v1(208.23,159.47) RT16.1 209.07,157.48 Q2309.2
EN_0.675VSP: length 4.5
  BOTTOM w0.102: PR208.2 160.88,29.03 v1(161.22,29.37)
  BOTTOM w0.203: PC215.1 160.24,27.43 159.28,26.47 PU200.7
  BOTTOM w0.254: PC215.1 160.88,27.43 PR208.2
EN_1.35VP: length 3.2
  BOTTOM w0.203: 160.05,26.48 159.99,26.48 v1(159.9,26.39) 159.58,26.07 PU200.8
  BOTTOM w0.254: PC214.1 160.87,25.98 160.9,26.01 PR207.2 160.9,26.48 160.05,26.48
EN_3V: length 11
  TOP w0.203: PU100.6 131.11,15.3 131.47,14.93 v4(131.47,14.73)
  BOTTOM w0.254: PR113.1 122.76,13.6 123.64,14.48 125.85,14.48 v1(126.05,14.68) 126.36,14.98 131.22,14.98 v4(131.47,14.73)
EN_5V: length 6.4
  TOP w0.203: 126.72,15.06 126.97,15.3 PU100.20
  TOP w0.254: PR112.1 122.79,13.79 123.66,14.67 125.3,14.67 v1(125.43,14.54) 126.2,14.54 126.72,15.06
EN_5V3V: length 6.5
  TOP w0.254: v2(122.8,11.05) 122.79,11.06 PR112.2 PR115.2 PR114.2 PR116.1
  BOTTOM w0.254: v2(122.8,11.05) 122.76,11.08 PR113.2 123.09,12.11 123.55,12.57 PC118.1
EN_DFAN1: length 194.9
  TOP w0.203: UE1.70 193.59,65.16 v2(189.87,61.44)
  BOTTOM w0.254: v2(189.87,61.44) 189.26,60.83 177.32,60.83 176.53,60.04 170.41,60.04 166.77,63.69 166.13,63.69 164.93,64.89 154.96,64.89 149.65,59.59 145.39,59.59 141.1,55.29 89.28,55.29 86.03,58.54 82.12,58.54 72.7,67.97 61.42,67.97 57.28,72.11 54.89,72.11 53.14,73.86 53.14,82.47 45.37,90.24 45.37,92.63 43.42,94.57 v1(43.42,95.87) 43.42,97.32 45.32,99.21 48.44,99.21 49.81,100.58 UE3.4
EN_INVPWR: length 125.8
  TOP w0.102: v2(218.49,160.37) 218.93,160.81 218.93,163.47 211.61,170.79 211.61,172.85 210.9,173.56 210.9,174.78 211.48,175.36 RV32.1 ; v2(196.12,76.78) 196.12,76.78 196.12,76.78 195.35,76.02 v1(195.35,75.31) 195.35,73.12 197.03,71.45 197.03,68.43 196.73,68.12 194.9,68.12 194.39,67.61 UE1.68
  IN2 w0.127: v2(196.12,76.78) 196.12,76.78 196.12,76.78 197.31,77.98 197.31,94.1 209.66,106.44 209.66,144.58 218.93,153.85 218.93,159.94 v2(218.49,160.37)
ENBAKL: length 124.2
  TOP w0.102: v2(193.83,76.66) v1(193.83,75.94) 193.83,74.34 192.05,72.57 192.05,68.63 191.19,67.76 UE1.76
  IN2 w0.127: v2(193.83,76.66) 193.83,93.23 207.8,107.2 207.8,146.33 v2(206.15,147.98)
  BOTTOM w0.102: v2(206.15,147.98) 206.07,147.9 192.36,147.9 189.23,151.03 189.23,162.53 190.86,164.16 RT14.2
ENVDD_R: length 0.9
  BOTTOM w0.102: RX8.1 v1(219.4,162.84)
ERP_LOT6: length 191.7
  TOP w0.102: v2(195.27,78.05) 195.27,77.81 v1(194.66,77.21) 194.52,77.06 194.52,69.8 192.39,67.67 UE1.73
  TOP w0.254: PQ3.2 130.88,172.69 PC8.1 129.37,172.07 PR16.2 PR21.1 v2(128.42,173.86)
  IN2 w0.127: v2(172.93,84.91) 172.93,87.18 176.13,90.38 176.13,106.59 175.33,107.39 175.33,142.63 v2(178.57,145.87) ; v2(178.11,160.55) 177.94,160.39 164.05,160.39 155.45,151.79 137.85,151.79 132.57,157.07 132.57,165.3 128.42,169.44 v2(128.42,173.86)
  BOTTOM w0.102: v2(178.11,160.55) 178.11,159.31 179.45,157.96 179.45,146.76 v2(178.57,145.87) ; v2(195.27,78.05) 192.35,80.97 176.86,80.97 v2(172.93,84.91)
FAN_SPEED1: length 223.6
  TOP w0.203: CE29.1 193.96,49.75 193.99,49.78 UE1.28
  TOP w0.254: CE29.1 193.78,48.79 193.42,48.44 193.42,46.96 194.47,45.92 194.47,41.51 193.39,40.43 190.53,40.43 188.62,42.34 177.37,42.34 174.22,45.49 174.22,45.93 173.36,46.79 173.36,48.55 167.77,54.14 167.77,59.76 166.73,60.8 166.73,61.92 165.71,62.94 v1(165.71,63.76) v2(165.71,64.82)
  BOTTOM w0.254: v2(165.71,64.82) 165.15,65.38 154.91,65.38 149.5,59.97 145.24,59.97 140.94,55.67 89.44,55.67 86.19,58.93 82.28,58.93 72.82,68.39 61.54,68.39 57.44,72.49 55.05,72.49 53.52,74.02 53.52,82.63 45.75,90.4 45.75,92.79 43.84,94.69 43.84,97.2 45.48,98.83 48.6,98.83 50.57,100.8 50.57,103.35 49.99,103.93 RE50.2 CE24.1 49.95,106.29 JFAN.2
FB_1.0VALWP: length 4.2
  BOTTOM w0.102: PR309.1 49.2,89.05 48.89,89.37 v1(48.57,89.37)
  BOTTOM w0.254: PC310.2 PR307.2 PR309.1 49.56,89.42 49.88,89.74 PU301.6
FB_1.05VSP: length 4.5
  BOTTOM w0.102: v1(171.53,107.72) 171.78,107.97 PR302.2
  BOTTOM w0.508: PU300.6 171.17,110.63 171.24,110.69 PR304.1 PC301.2 PR302.2
FB_1.35VP: length 5.2
  BOTTOM w0.102: PR206.1 v1(160.25,31.33)
  BOTTOM w0.203: PU200.6 159.17,26.87 159.34,27.03 159.34,28.18 160.24,29.09 PR204.1 ; 160.25,29.46 160.25,29.46
  BOTTOM w0.254: PR204.1 160.25,29.46 ; 160.25,29.46 PR206.1
FB_3V: length 4.7
  TOP w0.203: PU100.4 129.63,14.09 130.08,13.64 130.56,13.64 v4(130.58,13.61)
  TOP w0.254: PR100.2 130.36,13.38 v4(130.58,13.61)
  BOTTOM w0.102: v1(130.51,14.16) 130.58,14.08 v4(130.58,13.61)
  BOTTOM w0.254: v4(130.58,13.61) 130.36,13.38 PR100.2 PR102.2
FB_5V: length 4.2
  TOP w0.203: PU100.2 128.83,13.97 128.44,13.59 v4(128.13,13.59)
  TOP w0.254: PR101.1 128.07,13.51 128.13,13.57 v4(128.13,13.59)
  BOTTOM w0.102: v4(128.13,13.59) v1(128.13,14.12)
  BOTTOM w0.254: PR103.1 PR101.1 128.07,13.51 128.13,13.57 v4(128.13,13.59)
FB_+1.8VSP: length 4.7
  BOTTOM w0.102: PR402.2 61.32,93.25 v1(61.51,93.25)
  BOTTOM w0.254: 60.62,91.29 60.62,90.66 PR404.1 60.64,90.64 PU400.6 ; 60.62,91.29 PC401.2 ; 60.62,91.29 60.61,91.3 PR402.2
GCLK_VRTC: length 2.3
  TOP w0.102: RG1.2 70.26,41.17 v1(70.54,40.89)
  TOP w0.203: 67.67,40.92 67.5,40.75 UG1.10
GPIO_NC12: length 2.3
  BOTTOM w0.102: USOC1.B30 104.32,107.61 103.44,106.73 103.44,106.05 T98.1
GPIO_NC13: length 6.6
  BOTTOM w0.102: RC10.2 RC11.1 v1(101.14,104.25) 101.26,104.37 101.26,104.76 102.98,106.48 102.98,106.99 USOC1.A29
GPIO_NC14: length 4.1
  BOTTOM w0.102: T97.1 102.33,105.53 103.18,106.38 103.18,106.79 104.02,107.62 104.02,107.88 104.23,108.09 104.23,108.24
GPIO_RCOMP: length 1.4
  TOP w0.254: v2(106.31,113.01) 106.4,113.11 RC32.2
  BOTTOM w0.254: USOC1.N26 106.4,112.92 v2(106.31,113.01)
GPIO_S0_SC_56: length 9.1
  TOP w0.102: RC43.2 RC48.1 112.62,134.56 v1(112.62,134.05) 112.62,131.59 111.66,130.63 111.66,129.77 112.35,129.08 v2(112.35,128.69)
  BOTTOM w0.102: v2(112.35,128.69) 112.38,128.66 USOC1.BC12
GPIO_S0_SC_63: length 1.3
  TOP w0.102: RC16.2 118.03,122.01 v2(117.99,122.01)
  BOTTOM w0.102: v2(117.99,122.01) 118.08,121.93 USOC1.BA30
GPIO_S0_SC_65: length 11
  TOP w0.102: v1(125.95,124.53) 125.76,124.34 v2(125.76,124.03) RC17.2 126.41,123.34 QC1.1
  BOTTOM w0.102: USOC1.BC30 119.2,121.92 119.38,122.1 119.87,122.1 120.11,121.87 120.45,121.87 120.97,122.38 120.97,122.4 120.97,122.64 121.15,122.83 121.48,122.83 121.58,122.74 123.58,122.74 124.87,124.03 v2(125.76,124.03)
GPIO_S0_SC_92: length 6
  BOTTOM w0.102: T110.1 124.7,124.24 123.4,124.24 122.68,124.97 121.34,124.97 120.86,124.49 120.86,124.36 120.54,124.04 120.54,124.02 120.48,123.96 USOC1.BH30
GPIO_S0_SC_93: length 5
  BOTTOM w0.102: USOC1.BG30 120.14,123.47 120.41,123.47 120.45,123.5 120.62,123.5 120.77,123.65 120.77,123.95 121.12,124.29 121.12,124.39 121.44,124.71 122.61,124.71 123.42,123.9 T111.1
GPIO_S5_14: length 4.6
  TOP w0.102: RP65.3 103.03,110.14 103.43,110.54 103.43,111.45 103.25,111.63 103.25,112.09 103.34,112.17 v2(103.34,112.84) 103.67,112.84 v1(103.83,112.68)
  BOTTOM w0.102: USOC1.J20 103.27,112.91 v2(103.34,112.84)
GPIO_S5_17: length 2.3
  TOP w0.102: T104.1 104.54,113.43 104.18,113.08 104.18,112.32 v2(104.12,112.26)
  BOTTOM w0.102: v2(104.12,112.26) 104.28,112.26 104.44,112.09 USOC1.J24
GPO: length 4.1
  BOTTOM w0.102: RL36.2 41.39,79.84 v1(40.63,79.84) 40.11,80.36 40.11,80.46 38.75,81.82 UL1.26
H_PROCHOT#: length 315.6
  TOP w0.102: UE2.4 174.77,63.46 174.65,63.57 174.65,64.16 RE13.2 RE44.2 CE19.1 175.09,67.51 175.01,67.59 Q50.1 v1(175.01,76.25) 175.01,78.75 v2(175.15,78.89) ; PQ4.3 131.35,181.48 131.58,181.25 v2(131.93,181.25) ; PQ4.6 130.05,184.05 129.72,184.38 v2(129.31,184.38)
  IN2 w0.127: v2(131.93,181.25) 131.93,181.76 v2(129.31,184.38) 132.75,184.38 133.31,184.94 141.41,184.94 141.76,185.29 160.05,185.29 163.05,182.29 175.26,182.29 187.68,169.87 187.68,166.77 v2(188.24,166.22) ; v2(84.05,86.97) 84.57,87.49 84.57,91.57 86.29,93.28 86.29,94.46 92.04,100.22 92.04,102.2 93.55,103.71 95.3,103.71 v2(97.62,106.02) ; v2(188.24,154.4) 188.24,152.78 177.27,141.81 177.27,87.36 175.15,85.24 v2(175.15,78.89)
  BOTTOM w0.102: v2(175.15,78.89) 161.12,78.89 153.66,86.34 113.88,86.34 112.77,87.45 91.27,87.45 89.29,85.47 85.55,85.47 v2(84.05,86.97) ; RC15.1 96.32,106.02 v2(97.62,106.02) 97.62,106.42 CC8.2 97.95,106.75 99.98,106.75 100.31,107.09 100.31,107.31 102,109 102,109.16 102.01,109.17 102.01,109.17 102.24,109.4 102.36,109.4 102.42,109.4 102.56,109.53 102.56,109.76 102.75,109.96 USOC1.C24 ; v2(188.24,154.4) v2(188.24,166.22)
HDA_BIT_CLK: length 5.5
  BOTTOM w0.102: RC66.2 122.84,127.51 v1(121.76,127.51) 118.49,127.51 118.45,127.46 117.95,127.46 USOC1.BJ21
HDA_BITCLK_AUDIO: length 216.1
  TOP w0.102: UA1.6 43.41,25.79 44.22,26.6 R2355.1 44.92,27.49 v2(44.92,28.97)
  IN2 w0.127: v2(146.82,93.39) 147.55,93.39 150.73,90.22 150.73,64.85 147.55,61.68 147.55,57.74 142.68,52.86 142.68,48.38 141.38,47.09 v2(140.54,47.09)
  BOTTOM w0.102: v2(44.92,28.97) 46.49,30.53 54.31,30.53 55.28,29.56 75.59,29.56 92.67,46.64 140.09,46.64 v2(140.54,47.09) ; v2(146.82,93.39) v1(137.86,93.39) 137.07,93.39 130.76,99.7 130.76,111.48 132.5,113.22 132.5,121.95 126.43,128.03 125.07,128.03 124.69,128.41 CC7.1 124.11,128.78 RC66.1
HDA_RCOMP: length 5.8
  BOTTOM w0.102: 119.03,128.4 118.29,128.4 117.97,128.07 117.58,128.07 117.04,127.54 116.92,127.54 116.75,127.36 116.75,127.21 116.58,127.04 116.43,127.04 116.24,126.85 116.24,126.42 USOC1.BF20
  BOTTOM w0.254: RC14.1 119.97,128.4 v1(119.56,128.4) 119.03,128.4
HDA_RST#: length 9.5
  BOTTOM w0.102: RC71.2 124.85,127.38 124.64,127.59 123.8,127.59 123.14,126.93 121.87,126.93 121.76,126.82 119.79,126.82 119.13,126.16 118.16,126.16 118.06,126.26 117.44,126.26 USOC1.BG22
HDA_RST_AUDIO#: length 226.3
  TOP w0.102: v2(41,25.27) 41.41,24.86 UA1.11 ; RA6.1 v4(29.71,24.99)
  IN2 w0.127: v2(147.27,92.76) 150.09,89.94 150.09,65.11 146.92,61.94 146.92,58 141.71,52.8 v2(141.71,48.36)
  BOTTOM w0.102: v2(141.71,48.36) 91.87,48.36 74.85,31.34 55.78,31.34 55.02,32.1 44.68,32.1 41,28.42 v2(41,25.27) 40.92,25.27 40.08,26.11 30.83,26.11 v4(29.71,24.99) ; RC71.1 127.85,125.5 128.1,125.5 131.87,121.73 131.87,113.45 130.15,111.73 130.15,99.42 136.81,92.76 v1(144.15,92.76) v2(147.27,92.76)
HDA_SDIN0: length 7.4
  BOTTOM w0.102: RA130.1 121.47,130.88 120.26,129.68 v1(119.54,129.68) 118.89,129.03 117.74,129.03 116.66,127.95 116.66,127.74 116.45,127.53 USOC1.BG19
HDA_SDOUT: length 6.4
  BOTTOM w0.102: USOC1.BG20 116.77,126.75 116.97,126.95 117.17,126.95 117.35,127.13 117.35,127.26 117.76,127.67 118.13,127.67 118.19,127.72 118.28,127.81 121.16,127.81 121.57,128.22 RC70.2
HDA_SDOUT_AUDIO: length 216.8
  TOP w0.102: UA1.5 43.81,25.5 v2(44.29,25.98)
  IN2 w0.127: v2(142.09,47.06) 151.36,56.34 151.36,90.3 147.74,93.93 v2(146.23,93.93)
  BOTTOM w0.102: v2(146.23,93.93) v1(140.5,93.93) 137.44,93.93 131.25,100.12 131.25,111.28 133.14,113.17 133.14,122.01 124.72,130.43 124.29,130.43 123.44,129.58 123.44,129.35 RC70.1 ; v2(44.29,25.98) 46.19,27.89 47.27,27.89 48.31,28.93 75.85,28.93 92.93,46 141.03,46 v2(142.09,47.06)
HDA_SYNC: length 5.3
  BOTTOM w0.102: RC69.2 120.86,128.04 118.22,128.04 118.05,127.87 117.67,127.87 117.05,127.24 USOC1.BH20
HDA_SYNC_AUDIO: length 223.7
  TOP w0.102: v2(41.68,25.98) 41.68,25.09 41.81,24.97 UA1.10
  IN2 w0.127: v2(142.85,47.01) 151.88,56.04 151.88,90.5 147.87,94.51 v2(146.21,94.51)
  BOTTOM w0.102: v2(41.68,25.98) 41.68,28.22 44.96,31.49 54.77,31.49 55.56,30.71 75.12,30.71 92.09,47.67 142.19,47.67 v2(142.85,47.01) ; RC69.1 122.8,129.98 123.16,129.98 124.09,130.91 124.92,130.91 133.65,122.18 133.65,113 131.73,111.08 131.73,100.36 137.57,94.51 v1(142.42,94.51) v2(146.21,94.51)
HDMI_CLK+: length 105.7
  IN2 w0.127: v2(91.91,132.54) 91.77,132.69 91.16,132.69 87.91,129.44 87.91,127.86 83.06,123.01 73.74,123.01 71.32,120.59 65.31,120.59 61.4,116.68 46.58,116.68 31.07,101.16 27.63,101.16 v2(27.46,100.99)
  BOTTOM w0.102: v2(27.46,100.99) 27.23,101.22 22.69,101.22 22.53,101.06 21.08,101.06 CX13.2 ; v2(91.91,132.54) 92.08,132.71 92.38,132.71 93.95,134.28 96.29,136.62 97.64,136.62 103.93,130.34 103.93,129.5 104.1,129.33 104.17,129.26 104.18,129.26 104.25,129.19 104.33,129.11 104.41,129.03 104.99,129.03 105.38,128.64 105.38,128.48 105.53,128.33 105.98,128.33 USOC1.AP3
HDMI_CLK-: length 105.7
  IN2 w0.127: v2(91.91,133.3) 91.91,133.09 91.77,132.94 91.06,132.94 87.66,129.54 87.66,127.97 82.95,123.26 73.63,123.26 71.22,120.85 65.21,120.85 61.29,116.94 46.48,116.94 30.96,101.42 27.6,101.42 27.46,101.55 v2(27.46,101.75)
  BOTTOM w0.102: v2(27.46,101.75) 27.46,101.63 27.27,101.44 22.6,101.44 22.44,101.27 21.08,101.27 CX12.2 ; USOC1.AP2 105.08,129.23 104.5,129.23 104.39,129.33 104.33,129.4 104.33,129.41 104.25,129.48 104.14,129.59 104.14,130.43 97.73,136.84 96.21,136.84 93.79,134.43 92.29,132.93 92.06,132.93 91.91,133.08 v2(91.91,133.3)
HDMI_DDCCLK: length 142.8
  TOP w0.102: v2(21.36,107.42) 21.5,107.57 22.22,107.57 22.58,107.93 22.58,108.78 21.59,109.78 20.96,109.78 Q57.3
  IN2 w0.127: v2(86.69,91.97) 86.45,91.97 85.59,91.11 85.59,81.5 83.93,79.84 83.93,76.46 78.71,71.24 75.48,71.24 74.46,70.22 62.35,70.22 61.54,69.41 v2(57.18,69.41) ; v2(21.36,107.42) 22.47,107.42 25.43,104.46 25.43,98.62 28.42,95.63 36.93,95.63 v2(37.35,95.21)
  BOTTOM w0.102: v2(37.35,95.21) 37.35,94 38.37,92.97 41.4,92.97 44.1,90.28 44.1,89.71 51.76,82.06 51.76,73.45 55.8,69.41 v2(57.18,69.41) ; USOC1.C28 103.94,108.84 103.73,108.63 103.48,108.63 103.33,108.48 103.33,108.25 102.4,107.32 102.4,106.99 100.4,104.99 100.4,104.81 98.12,102.53 98.12,101.87 90.71,94.46 89.95,94.46 87.46,91.97 v2(86.69,91.97) ; v2(21.36,107.42) 20.54,107.42 19.71,108.26 RP15.6
HDMI_DDCDATA: length 139.8
  TOP w0.102: Q58.3 20.78,109.29 21.39,109.29 22.1,108.58 22.1,108.13 22.02,108.05 21.49,108.05 v2(21.36,108.18)
  IN2 w0.127: v2(37.35,95.96) 37.05,96.26 28.5,96.26 25.94,98.83 25.94,104.67 22.43,108.18 v2(21.36,108.18) ; v2(57.18,70.19) 61.6,70.19 62.15,70.74 74.14,70.74 75.21,71.8 78.55,71.8 83.42,76.67 83.42,80.05 85.08,81.71 85.08,91.32 86.32,92.56 v2(86.69,92.56)
  BOTTOM w0.102: v2(37.35,95.96) 37.85,95.47 37.85,94.18 38.57,93.46 41.6,93.46 44.58,90.48 44.58,89.91 52.24,82.26 52.24,73.65 55.69,70.19 v2(57.18,70.19) ; v2(86.69,92.56) 87.36,92.56 89.75,94.94 90.51,94.94 97.64,102.07 97.64,102.94 101.53,106.82 101.53,107.34 102.9,108.71 103.11,108.71 103.24,108.85 103.24,109.31 USOC1.C26 ; v2(21.36,108.18) 20.47,108.18 20.21,108.44 RP15.5
HDMI_GND: length 7
  IN1 w0.508: v2(13.48,111.99) 13.48,110.76 14.1,110.14 v2(14.1,105.92)
  BOTTOM w0.406: Q14.3 v2(13.48,111.99)
  vias: v1(13.41,100.29)
HDMI_HPD#: length 149.1
  TOP w0.102: v2(62.44,69.39) 60.66,71.17 53.14,71.17 49.89,74.42 48.87,74.42 45.19,78.1 v1(45.19,80.17) 45.19,83.56 44.43,84.33 42.93,84.33 41.79,85.47 41.79,87.86 38.76,90.88 v2(38.76,91.41)
  IN2 w0.127: v2(38.76,91.41) 38.76,95.6 37.14,97.23 32.67,97.23 32.29,96.85 28.66,96.85 26.44,99.07 26.44,104.88 24.13,107.19 v2(24.13,109.4) ; v2(86.67,91.39) 86.59,91.39 86.1,90.89 86.1,87.54 86.92,86.71 86.92,82.12 84.43,79.63 84.43,76.25 78.92,70.74 75.7,70.74 74.57,69.61 62.65,69.61 v2(62.44,69.39)
  BOTTOM w0.102: v2(86.67,91.39) 87.56,91.39 90.15,93.98 90.91,93.98 98.61,101.67 98.61,102.33 100.92,104.65 100.92,104.75 102.67,106.51 102.67,107.29 103.41,108.03 103.82,108.03 103.93,108.14 103.93,108.38 104.08,108.54 104.3,108.54 104.48,108.72 104.48,109 104.26,109.22 104.25,109.22 USOC1.D27 ; v2(24.13,109.4) 24.13,112.34 21.9,114.58 R376.2 15.4,114.58 15.38,114.56 Q14.6
HDMI_HPLUG: length 8.6
  BOTTOM w0.102: Q14.2 14.13,112.22 14.18,112.16 R121.1 v1(12.88,111.58) 11.51,111.58 JHDMI.19
HDMI_TX0+: length 107.1
  IN2 w0.127: v2(91.28,134.23) 91.14,134.38 90.57,134.38 87.1,130.91 87.1,128.13 82.79,123.82 73.31,123.82 70.87,121.38 64.96,121.38 61.04,117.47 46.25,117.47 31.84,103.06 27.59,103.06 v2(27.46,102.93)
  BOTTOM w0.102: USOC1.AR3 106.05,128.73 105.84,128.94 105.66,128.94 105.42,129.18 105.42,129.42 104.91,129.93 104.9,129.93 104.63,130.21 104.63,130.63 97.92,137.34 95.86,137.34 94.34,135.82 92.91,134.38 91.43,134.38 v2(91.28,134.23) ; CX15.2 20.06,103.85 21.97,103.85 22.68,103.15 27.24,103.15 v2(27.46,102.93)
HDMI_TX0-: length 107.1
  IN2 w0.127: v2(91.28,134.99) 91.28,134.76 91.16,134.63 90.46,134.63 86.84,131.02 86.84,128.24 82.68,124.08 73.2,124.08 70.76,121.64 64.85,121.64 60.94,117.73 46.15,117.73 31.73,103.31 27.64,103.31 27.46,103.49 v2(27.46,103.68)
  BOTTOM w0.102: USOC1.AR1 105.74,129.39 105.05,130.08 105.05,130.09 104.84,130.3 104.84,130.72 98.01,137.55 95.77,137.55 94.19,135.97 92.82,134.6 91.46,134.6 91.28,134.78 v2(91.28,134.99) ; v2(27.46,103.68) 27.14,103.36 22.77,103.36 22.06,104.07 20.06,104.07 CX14.2
HDMI_TX1+: length 112.7
  IN2 w0.127: v2(27.41,99.06) 27.41,99.29 27.53,99.41 30.48,99.41 46.94,115.87 61.78,115.87 65.72,119.81 75.34,119.81 77.76,122.22 83.9,122.22 86.02,124.34 89.25,127.57 89.25,128.48 92.84,132.08 92.84,134.79 92.29,135.34 92.29,135.59 92.41,135.71 v2(92.67,135.71)
  BOTTOM w0.102: CX17.2 19.84,98.3 21.21,98.3 22.35,99.43 27.27,99.43 27.41,99.29 v2(27.41,99.06) ; USOC1.AT2 106.36,129.33 106.26,129.42 106.17,129.42 105.45,130.14 105.45,130.83 105.33,130.95 105.26,131.02 105.25,131.02 98.23,138.05 95.02,138.05 93.68,136.7 92.6,136.7 92.25,136.36 92.25,135.9 92.44,135.71 v2(92.67,135.71)
HDMI_TX1-: length 112.7
  IN2 w0.127: v2(27.41,99.82) 27.56,99.67 30.38,99.67 46.83,116.13 61.67,116.13 65.61,120.06 75.24,120.06 77.65,122.48 83.79,122.48 85.84,124.52 88.99,127.67 88.99,128.59 92.59,132.19 92.59,134.69 92.04,135.24 92.04,135.56 v2(91.89,135.71)
  BOTTOM w0.102: v2(27.41,99.82) 27.24,99.65 22.26,99.65 21.12,98.51 19.78,98.51 CX16.2 ; USOC1.AT3 106.66,129.02 106.66,129.44 106.48,129.63 106.26,129.63 105.66,130.23 105.66,130.91 105.4,131.16 105.4,131.17 98.32,138.26 94.94,138.26 93.59,136.92 92.51,136.92 92.04,136.44 92.04,135.86 v2(91.89,135.71)
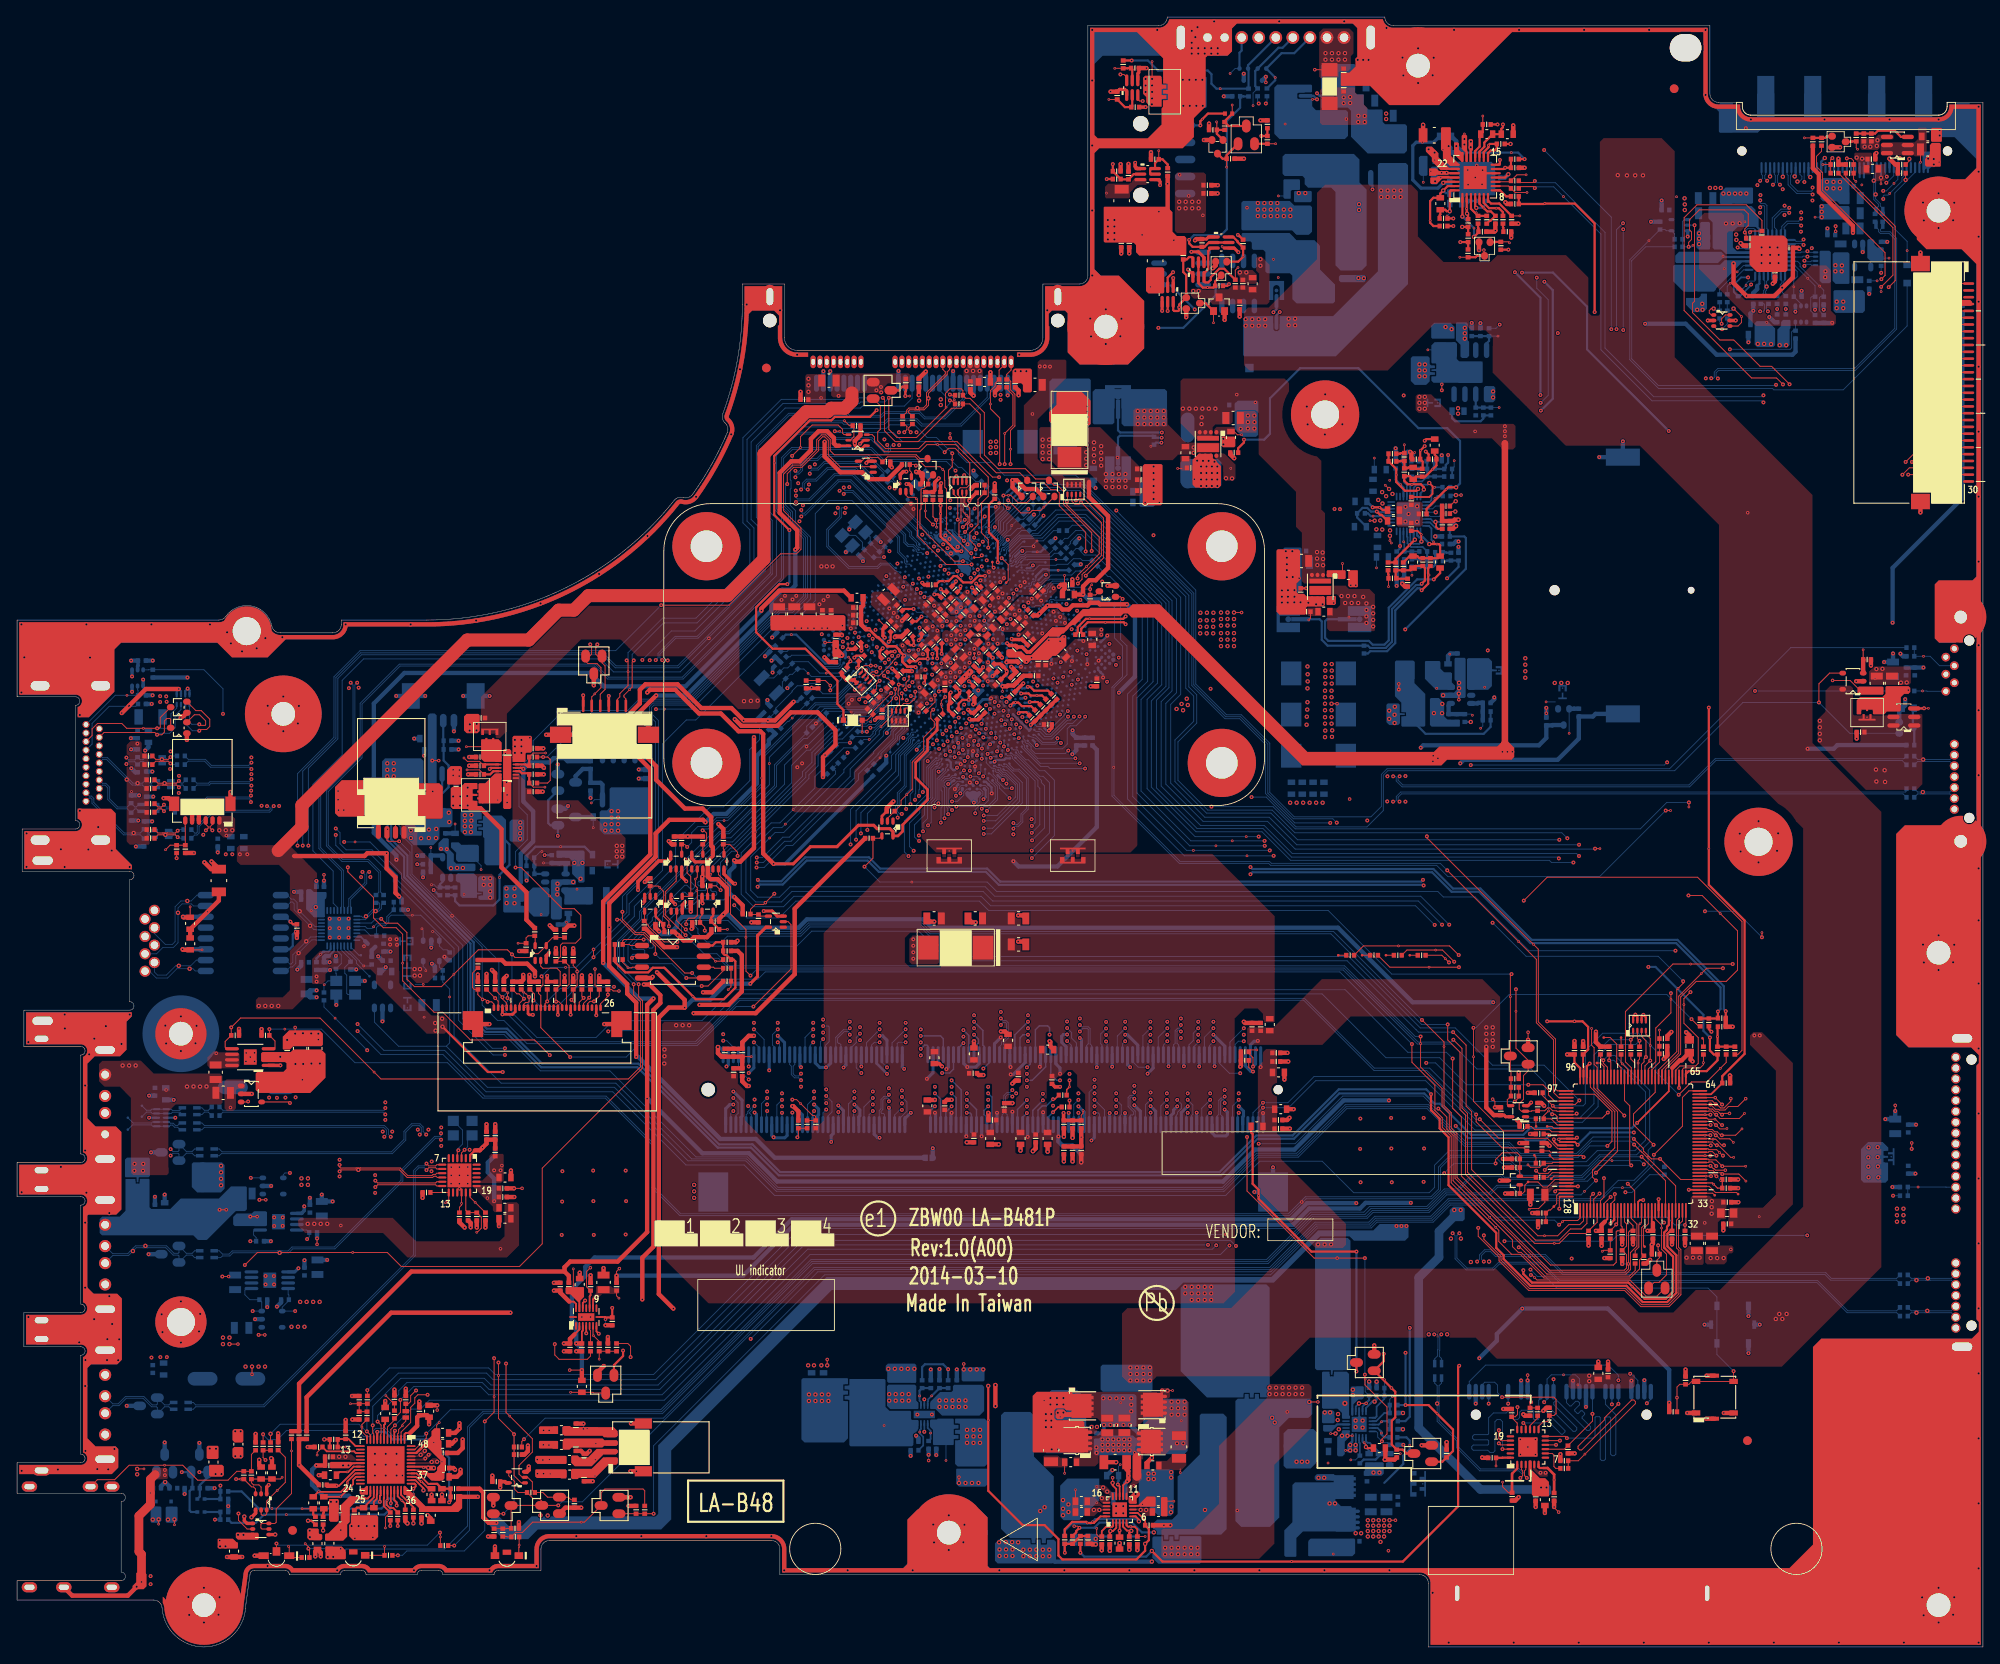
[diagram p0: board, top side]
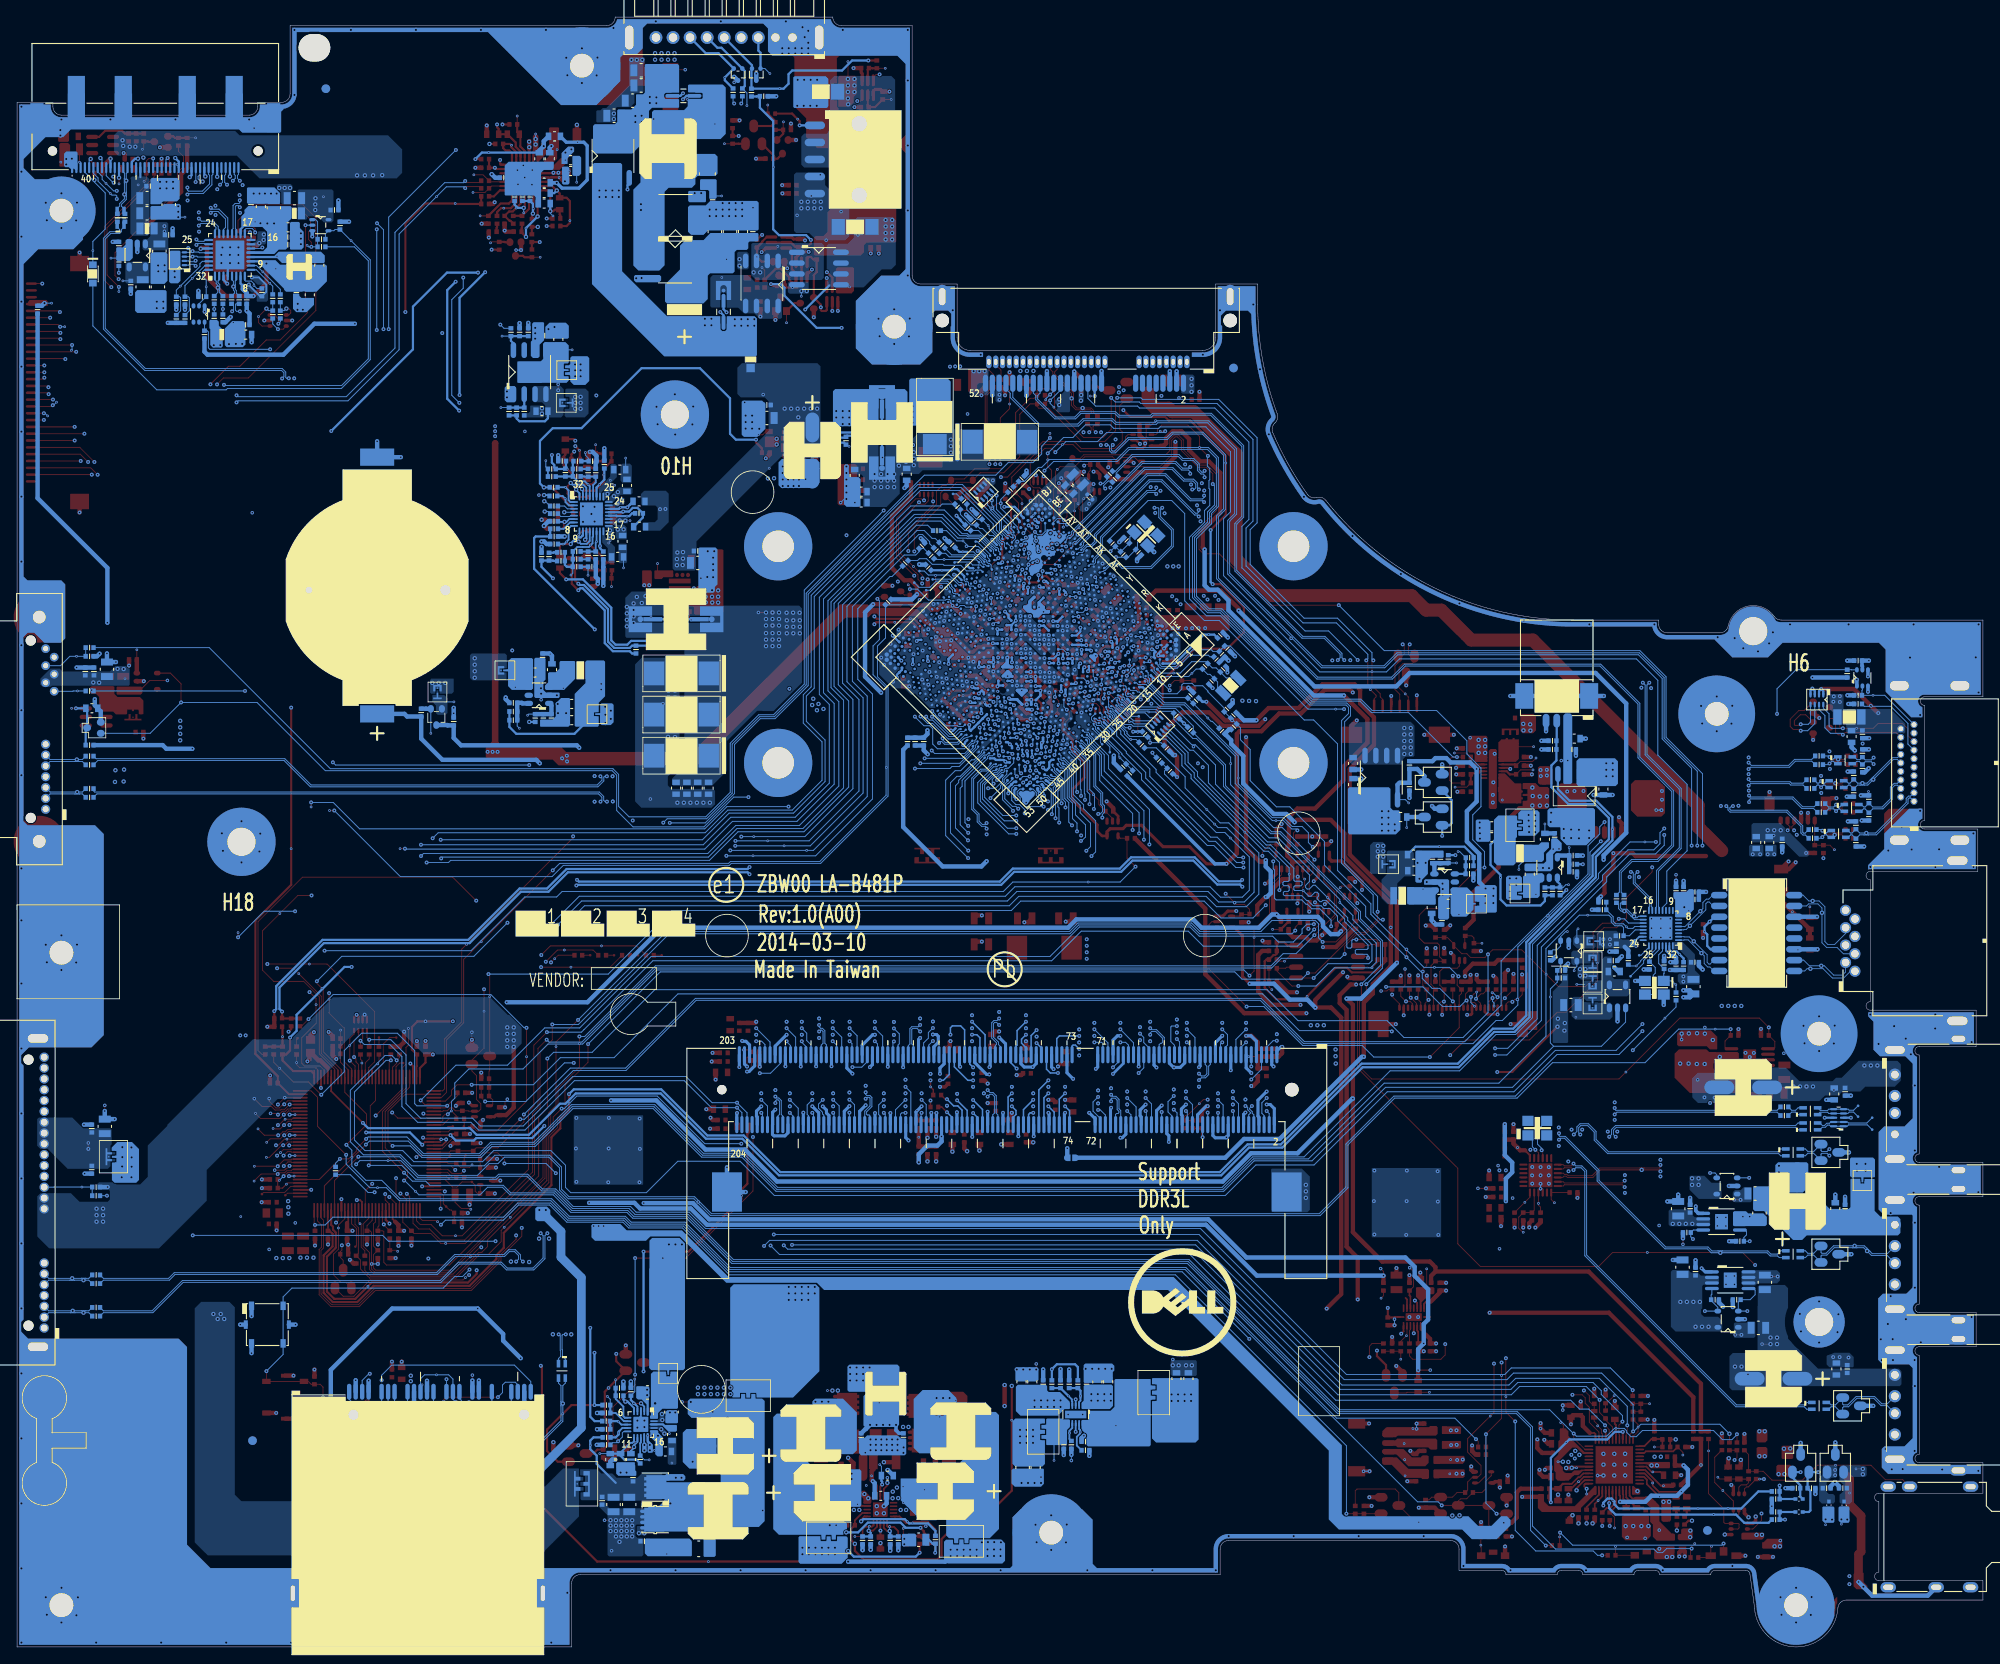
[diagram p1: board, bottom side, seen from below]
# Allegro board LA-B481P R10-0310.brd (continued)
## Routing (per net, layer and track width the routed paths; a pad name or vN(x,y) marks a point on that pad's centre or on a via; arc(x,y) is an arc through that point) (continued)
HDMI_TX2+: length 118.5
  IN2 w0.127: v2(92.91,138.34) 92.76,138.19 92.44,138.19 92.06,137.81 92.06,137.23 92.55,136.73 93.01,136.73 93.37,136.36 93.37,131.86 90.1,128.58 90.1,127.66 84.13,121.69 78.03,121.69 75.57,119.23 65.86,119.23 61.97,115.34 47.16,115.34 31.61,99.79 31.61,98.41 31.07,97.88 30.08,97.88 29.94,98.02 29.94,98.45 v2(30.08,98.59)
  BOTTOM w0.102: v2(92.91,138.34) 93.04,138.21 93.81,138.21 94.58,138.97 98.59,138.97 106.8,130.77 106.8,130.49 106.97,130.32 107.15,130.32 107.34,130.13 107.34,129.96 107.47,129.65 USOC1.AV3 ; v2(30.08,98.59) 29.88,98.39 29.88,98.14 29.63,97.88 23.04,97.88 21.34,96.18 21.34,95.44 21.09,95.2 20.81,95.2 CX19.2
HDMI_TX2-: length 118.5
  IN2 w0.127: v2(92.91,137.55) 92.91,137.81 92.78,137.94 92.55,137.94 92.31,137.7 92.31,137.33 92.66,136.99 93.11,136.99 93.63,136.47 93.63,131.75 90.35,128.47 90.35,127.55 84.23,121.43 78.14,121.43 75.68,118.97 65.97,118.97 62.08,115.08 47.27,115.08 31.87,99.68 31.87,98.31 31.18,97.62 29.98,97.62 29.68,97.92 29.68,98.43 29.53,98.59 v2(29.29,98.59)
  BOTTOM w0.102: v2(92.91,137.55) 92.91,137.78 93.12,137.99 93.9,137.99 94.67,138.76 98.5,138.76 106.58,130.68 106.58,130.4 106.88,130.1 106.96,130.1 USOC1.AV2 ; CX18.2 20.85,95.41 21,95.41 21.12,95.53 21.12,96.27 22.95,98.1 29.54,98.1 29.67,98.23 29.67,98.38 29.45,98.59 v2(29.29,98.59)
HPOUT-L: length 22
  TOP w0.203: v2(43.81,16.86) 43.81,16.87 UA1.32
  BOTTOM w0.254: RA55.1 25.12,14.55 27.97,14.55 28.93,15.52 v1(31.56,15.52) 43.06,15.52 43.81,16.27 v2(43.81,16.86)
HPOUT-R: length 23.7
  TOP w0.203: UA1.33 44.21,17.24 44.49,16.95 v2(44.49,16.58)
  BOTTOM w0.254: RA56.1 26.32,18.24 28.32,16.23 v1(29.87,16.23) 42.7,16.23 43.18,16.71 43.18,17.07 43.51,17.4 44,17.4 44.49,16.9 v2(44.49,16.58)
HSIC_RCOMP: length 8
  BOTTOM w0.254: RC49.2 90.1,118.69 v1(90.75,118.69) 91.32,118.69 94.71,115.3 USOC1.A7
HUB_BUSJ: length 3.1
  TOP w0.102: U58.18 53.09,52.72 v1(53.69,52.13) R1049.2
HUB_OVCJ: length 5.4
  TOP w0.254: U58.1 53.09,57.66 53.66,58.23
  TOP w0.508: R1051.2 R1046.2 C1121.1 55.02,59.01 v1(54.55,58.54) 54.23,58.23 53.66,58.23
HUB_VBUSM: length 6.3
  TOP w0.102: U58.17 52.59,51.19 C1122.2 R1050.2 54.41,50.39 54.41,49.09 53.94,48.63 v1(53.88,48.63)
HUB_XIN: length 5.1
  TOP w0.102: v2(51.72,58.24) 51.59,58.12 U58.4
  BOTTOM w0.102: v2(51.72,58.24) 51.72,58.47 52.2,58.95 52.2,60.61 Y9.3
HUB_XOUT: length 3.2
  TOP w0.102: v2(52.45,58.29) 52.09,57.93 U58.3
  BOTTOM w0.102: v2(52.45,58.29) 52.81,58.65 52.81,59.46 Y9.1
HUB_XRSTJ: length 2.5
  TOP w0.102: U58.16 v1(52.09,52) 52.09,51.81 51.84,51.56 R1047.2
ICLK_ICOMP: length 2
  TOP w0.254: RC23.2 105.43,120.24 v2(106,120.81)
  BOTTOM w0.102: v2(106,120.81) 106.01,120.8 USOC1.AD14
ICLK_RCOMP: length 2.7
  TOP w0.254: RC22.2 103.94,121.7 v2(105.07,121.7)
  BOTTOM w0.102: v2(105.07,121.7) 105.47,121.3 USOC1.AD13
ICLK_USB_TERMN: length 2
  TOP w0.254: RC42.2 98.35,116.22 v2(98.12,116)
  BOTTOM w0.102: v2(98.12,116) 98.18,115.94 USOC1.F10
ICLK_USB_TERMP: length 2.1
  TOP w0.102: v2(97.67,115.58) 97.67,115.83 v1(97.45,116.05)
  TOP w0.254: v2(97.67,115.58) 97.28,115.19 RC41.2
  BOTTOM w0.102: v2(97.67,115.58) 97.81,115.44 USOC1.D10
ILB_RTC_EXTPAD: length 7.8
  BOTTOM w0.102: CC15.1 90.6,116.09 90.78,116.28 92.92,116.28 94.44,114.76 96.4,114.76 96.68,115.03 96.68,115.16 USOC1.B8
ILB_RTC_X1: length 11
  BOTTOM w0.102: YC2.2 89.69,112.49 89.69,113.14 CC18.1 90.59,114.04 90.86,114.04 RC31.2 92.21,114.66 v1(92.71,114.16) 93.08,113.79 96.43,113.79 97.13,114.49 97.13,114.82 USOC1.C9
ILB_RTC_X2: length 11
  BOTTOM w0.102: YC2.1 88.69,113.61 CC17.1 89.87,114.79 90.33,114.79 RC31.1 91.05,115.52 92.74,115.52 94.07,114.18 v1(94.83,114.18) 96.3,114.18 USOC1.A9
INT-SPK-L+: length 24.2
  IN2 w1.016: 64.06,25.27 64.57,24.76 64.57,19.28 62.13,16.84 57.03,16.84 54.66,19.2 51.67,19.2 50.57,20.29 49.56,20.29
  BOTTOM w0.102: v4(48.19,21) v1(47.64,21)
  vias: v2(61.7,25.4) v2(62.36,25.4) v4(48.85,20.98)
INT-SPK-L-: length 18
  IN2 w1.016: 50.4,21.64 55.76,21.64 58.83,18.57 61.7,18.57 62.87,19.73 62.87,22.93
  BOTTOM w0.102: v4(49.23,21.71) v1(49.8,21.71)
  vias: v2(61.67,23.7) v2(62.34,23.67) v4(48.59,21.69)
INT-SPK-R+: length 13.9
  IN2 w1.016: 48.11,23.92 49.46,25.27 56.59,25.27 59.8,22.07 60.1,22.07
  vias: v1(62.39,21.97) v2(60.96,21.97) v2(61.62,21.92) v4(47.3,22.52) v4(47.78,22.98)
INT-SPK-R-: length 12.4
  IN2 w1.016: 59.95,20.24 59.31,20.24 56.14,23.42 49.3,23.42 48.97,23.09
  vias: v1(62.49,20.29) v2(47.83,22.1) v2(48.24,22.53) v2(60.99,20.32) v2(61.7,20.32)
ISL88731_ICREF: length 6.9
  TOP w0.254: PR727.1 171.22,166.39 171.28,166.34 PR729.2 171.28,165.85 v4(170.76,165.33) ; v4(169.39,167.71) PU700.1
  BOTTOM w0.254: v4(169.39,167.71) v1(170.76,166.35) v4(170.76,165.33)
ISL88731_VREF: length 3.5
  TOP w0.254: PU700.3 170.39,168.62 PR727.2 PR725.2
ISOLATEB: length 6.5
  BOTTOM w0.102: RL33.2 RL35.2 43.34,85.62 43.34,85.09 43.03,84.78 42.13,84.78 v1(41.78,84.43) 41.6,84.25 41.02,84.25 40.8,84.47 UL1.20
JACK_PLUG#: length 23.7
  TOP w0.102: JHP.4 9.41,19.61 11.43,19.61 13.14,21.31 v1(17.29,21.31) 19.41,21.31 21.16,19.56 24.72,19.56 25.76,20.6 RA4.1 RA3.1 27.46,22.57 RA1.2
JACK_SENSE#: length 17.7
  TOP w0.102: v2(25.67,19.68) RA4.2 27.49,18.77 27.71,18.77 27.95,18.53 QA5.3
  TOP w0.203: RA51.2 RA34.2 v4(36.01,24.33)
  IN1 w0.127: v2(25.67,19.68) 27.71,21.73 27.71,21.9 28.84,23.02 31.16,23.02 32.46,24.33 v4(36.01,24.33)
  BOTTOM w0.102: v2(25.67,19.68) v1(26.18,19.68)
JHDD_P10: length 6.6
  BOTTOM w0.102: RS8.2 RS7.2 v1(222.8,53.92) 226.06,53.92 226.08,53.9 JHDD.10
KB_CAPS_PWR: length 1.8
  BOTTOM w0.102: v4(227.18,157.55) v1(226.36,157.55)
  BOTTOM w0.508: RE60.2 227.49,157.25 v4(227.18,157.55)
KB_LED_PWM: length 4.5
  TOP w0.102: UE1.21 191.19,49.61 190.63,49.06 190.63,47.05 T192.1
KB_RST#: length 134.2
  TOP w0.102: v2(168.3,72.08) 169.83,70.56 169.83,63.41 170.48,62.76 170.48,55.97 178.24,48.21 v1(179.01,48.21) 180.56,48.21 181.87,49.52 183.14,49.52 183.59,49.97 UE1.2 ; U61.2 77.31,85.16 78.35,84.12 v2(78.38,84.12)
  BOTTOM w0.102: v2(78.38,84.12) 80.33,82.17 91.38,82.17 93.14,83.92 105.67,83.92 109.14,80.45 155.88,80.45 163.96,72.37 163.96,72.37 164.25,72.08 v2(168.3,72.08)
KSI0: length 101.5
  TOP w0.102: JKB.22 v2(223.65,143.05) ; UE1.55 198.16,61.6 198.2,61.64 198.62,61.64 199.08,61.19 v2(199.11,61.19) 199.56,60.74 200.35,60.74 v1(200.4,60.79)
  IN2 w0.127: v2(223.65,143.05) 223.22,142.62 223.22,140.36 223.65,139.93 223.65,132.98 214.33,123.66 214.33,90.08 211.13,86.88 211.13,72.37 200.48,61.72 199.65,61.72 v2(199.11,61.19)
KSI1: length 98.6
  TOP w0.102: UE1.56 198.07,62 198.2,61.87 v1(198.99,61.87) 199.04,61.87 199.73,61.19 v2(199.83,61.19) ; JKB.24 v2(223.65,141.45)
  IN2 w0.127: v2(199.83,61.19) 200.31,61.19 211.38,72.26 211.38,86.77 214.58,89.97 214.58,123.55 223.9,132.87 223.9,140.04 223.65,140.29 v2(223.65,141.45)
KSI2: length 95.8
  TOP w0.102: v2(222.08,138.94) 222.99,139.85 JKB.26 ; UE1.57 v2(198.45,62.4)
  IN2 w0.127: v2(198.45,62.4) 199.22,63.17 200.26,63.17 210.11,73.02 210.11,87.3 213.31,90.5 213.31,127.46 222.08,136.22 v2(222.08,138.94)
  BOTTOM w0.102: v2(198.45,62.4) v1(197.82,62.4)
KSI3: length 102
  TOP w0.102: UE1.58 198.19,62.8 198.23,62.84 198.59,62.84 199.02,62.41 v2(199.14,62.41) 199.58,61.96 201.86,61.96 v1(202.45,62.56) ; JKB.23 v2(222.51,142.25)
  IN2 w0.127: v2(199.14,62.41) 199.65,62.91 200.36,62.91 210.37,72.92 210.37,87.2 213.57,90.4 213.57,127.35 222.51,136.29 v2(222.51,142.25)
KSI4: length 96.1
  TOP w0.102: JKB.27 v2(222.94,139.05) ; v3(200.69,62.56) 199.98,62.56 v2(199.83,62.41) 199.66,62.57 199.55,62.57 199.31,62.81 198.94,62.81 198.69,63.07 198.33,63.07 198.19,63.2 UE1.59
  IN2 w0.127: v2(199.83,62.41) 200.08,62.66 200.47,62.66 210.62,72.81 210.62,87.09 213.82,90.29 213.82,127.25 222.94,136.37 v2(222.94,139.05)
KSI5: length 99.1
  TOP w0.102: v2(221.34,138.94) 223.05,140.65 JKB.25 ; UE1.60 v2(198.45,63.6) 198.48,63.6 199.04,63.04 199.4,63.04 199.49,62.95 200.17,62.95 200.59,63.37 201.68,63.37 v3(202.59,64.29)
  IN2 w0.127: v2(198.45,63.6) 209.27,74.42 209.27,87.66 212.53,90.91 212.53,130.12 v2(221.34,138.94)
KSI6: length 95.6
  TOP w0.102: UE1.61 198.09,64 198.12,64.03 198.68,64.03 v2(199.09,63.62) 199.25,63.46 199.39,63.46 199.66,63.19 200.05,63.19 200.85,63.99 v3(200.85,64.3) ; JKB.28 221.77,138.25 v2(220.96,137.44)
  IN2 w0.127: v2(220.96,137.44) 212.78,129.26 212.78,90.81 209.6,87.63 209.6,74.14 v2(199.09,63.62)
KSI7: length 92.9
  TOP w0.102: UE1.62 v3(199.02,64.4) v2(199.83,63.6) ; JKB.29 v2(221.64,137.45)
  IN2 w0.127: v2(199.83,63.6) 209.86,73.63 209.86,87.53 213.03,90.7 213.03,127.63 221.64,136.24 v2(221.64,137.45)
KSO0: length 112.9
  TOP w0.102: UE1.39 v2(198.53,55.2) ; JKB.13 v2(227.21,150.25)
  IN2 w0.127: v2(198.53,55.2) 199.26,55.93 200.94,55.93 214.94,69.93 214.94,85.3 222.48,92.84 222.48,126.42 228.27,132.21 228.27,146.76 226.42,148.61 226.42,149.46 v2(227.21,150.25)
  BOTTOM w0.102: v2(198.53,55.2) v1(197.93,55.2)
KSO1: length 112.2
  TOP w0.102: UE1.40 198.18,55.6 198.18,55.61 198.7,55.61 199.11,55.19 v2(199.16,55.19) ; JKB.15 227.37,148.65 v2(227.21,148.82)
  IN2 w0.127: v2(227.21,148.82) 228.78,147.24 228.78,132 222.99,126.21 222.99,92.63 215.45,85.09 215.45,69.72 201.15,55.42 200.51,55.42 200.05,54.96 199.62,54.96 199.39,55.19 v2(199.16,55.19)
  BOTTOM w0.102: v2(199.16,55.19) 199.18,55.19 v1(199.66,54.71)
KSO2: length 114.8
  TOP w0.102: UE1.41 198.1,56 198.27,55.84 198.79,55.84 199.03,55.6 199.7,55.6 v2(199.85,55.45) 201.79,55.45 v1(202.62,54.62) ; JKB.14 v2(227.21,149.45)
  IN2 w0.127: v2(199.85,55.45) 200.03,55.45 200.26,55.67 201.04,55.67 215.19,69.83 215.19,85.19 222.74,92.74 222.74,126.32 228.53,132.11 228.53,146.89 226.77,148.64 226.77,149.02 v2(227.21,149.45)
KSO3: length 109.5
  TOP w0.102: v2(226.72,147.7) 226.88,147.85 JKB.16 ; v3(200.21,55.9) 199.05,55.9 198.89,56.07 198.81,56.07 v2(198.47,56.4) UE1.42
  IN2 w0.127: v2(198.47,56.4) 199.24,57.17 200.78,57.17 214.05,70.44 214.05,85.67 220.2,91.81 220.2,114.5 221.72,116.02 221.72,126.92 226.55,131.74 226.55,144.83 227.18,145.46 227.18,147.24 v2(226.72,147.7)
KSO4: length 104.8
  TOP w0.102: JKB.20 v2(227.26,144.65) ; UE1.43 198.21,56.8 198.28,56.87 198.65,56.87 v2(199.14,56.39)
  IN2 w0.127: v2(199.14,56.39) 199.67,56.92 200.89,56.92 214.3,70.33 214.3,85.56 221.97,93.23 221.97,126.81 226.83,131.66 226.83,144.22 v2(227.26,144.65)
  BOTTOM w0.102: v1(226.81,144.33) 227.13,144.65 v2(227.26,144.65)
KSO5: length 106.5
  TOP w0.102: JKB.21 227.27,143.85 v2(227.26,143.86) ; UE1.44 198.18,57.2 198.28,57.1 199.11,57.1 v2(199.85,56.36) v1(202.59,56.36)
  IN2 w0.127: v2(199.85,56.36) 200.16,56.67 200.99,56.67 214.56,70.23 214.56,85.46 222.23,93.13 222.23,126.71 227.26,131.74 v2(227.26,143.86)
KSO6: length 105.5
  TOP w0.102: UE1.45 v2(198.45,57.6) ; JKB.18 v2(226.19,146.25)
  IN2 w0.127: v2(226.19,146.25) 225.76,145.82 225.76,132.18 220.3,126.72 220.3,116 219.43,115.14 219.43,92.27 213.19,86.03 213.19,70.72 200.86,58.39 199.24,58.39 v2(198.45,57.6)
  BOTTOM w0.102: v2(198.45,57.6) v1(197.83,57.6)
KSO7: length 105.3
  TOP w0.102: v2(226.22,145.59) 226.36,145.45 JKB.19 ; UE1.46 198.22,58 198.29,58.07 198.7,58.07 v2(199.16,57.61)
  IN2 w0.127: v2(199.16,57.61) 199.7,58.14 200.96,58.14 213.44,70.61 213.44,85.92 219.69,92.17 219.69,114.71 221.21,116.23 221.21,127.27 226.01,132.07 226.01,145.39 v2(226.22,145.59)
  BOTTOM w0.102: v1(225.77,145.95) 226.13,145.59 v2(226.22,145.59)
KSO8: length 106.2
  TOP w0.102: v2(199.93,57.61) 199.89,57.61 v1(199.53,57.96) 199.19,58.3 198.29,58.3 198.19,58.4 UE1.47 ; v2(226.7,146.89) 226.86,147.05 JKB.17
  IN2 w0.127: v2(199.93,57.61) 200.79,57.61 213.69,70.51 213.69,85.81 219.94,92.06 219.94,114.6 221.47,116.13 221.47,127.17 226.29,131.99 226.29,145.03 226.88,145.62 226.88,146.71 v2(226.7,146.89)
KSO9: length 113.7
  TOP w0.102: v2(225.35,154.79) 225.62,155.05 JKB.7 ; UE1.48 v2(198.5,58.8)
  IN2 w0.127: v2(225.35,154.79) 226.01,154.13 226.01,150.69 225,149.68 225,132.49 216.34,123.83 216.34,90.25 212.42,86.34 212.42,71.4 200.58,59.56 199.26,59.56 v2(198.5,58.8)
  BOTTOM w0.102: v2(225.35,154.79) v1(224.82,154.79)
KSO10: length 118
  TOP w0.102: UE1.49 198.22,59.2 198.23,59.21 198.67,59.21 199.05,58.82 v2(199.22,58.82) 199.41,58.82 200.83,57.4 v1(201.18,57.4) ; v2(225.38,156.51) 225.52,156.65 JKB.5
  IN2 w0.127: v2(199.22,58.82) 199.7,59.31 200.69,59.31 212.68,71.3 212.68,86.24 216.59,90.15 216.59,123.73 225.25,132.39 225.25,149.57 226.27,150.59 226.27,154.73 225.38,155.62 v2(225.38,156.51)
KSO11: length 113.7
  TOP w0.102: v2(200.05,58.82) 199.79,58.82 199.08,59.54 v1(198.77,59.54) 198.27,59.54 198.21,59.6 UE1.50 ; v2(226.52,155.85) 226.52,155.85 JKB.6
  IN2 w0.127: v2(200.05,58.82) 200.56,58.82 212.93,71.19 212.93,86.13 216.84,90.04 216.84,123.62 225.5,132.28 225.5,149.47 226.52,150.48 v2(226.52,155.85)
KSO12: length 108.5
  TOP w0.102: JKB.12 224.79,151.05 v2(224.74,151) ; UE1.51 v2(198.45,60)
  IN2 w0.127: v2(224.74,151) 224.18,150.44 224.18,132.76 214.86,123.44 214.86,89.86 211.66,86.66 211.66,71.99 200.4,60.73 199.18,60.73 v2(198.45,60)
  BOTTOM w0.102: v2(198.45,60) v1(197.82,60)
KSO13: length 112.7
  TOP w0.102: UE1.52 198.18,60.4 198.23,60.45 198.58,60.45 199.04,59.99 v2(199.09,59.99) 199.14,59.99 199.56,59.57 200.74,59.57 v1(201.15,59.17) ; JKB.9 225.44,153.45 v2(225.33,153.34)
  IN2 w0.127: v2(199.09,59.99) 199.57,60.48 200.51,60.48 211.92,71.88 211.92,86.55 215.12,89.75 215.12,123.33 224.49,132.7 224.49,150.09 225.33,150.92 v2(225.33,153.34)
KSO14: length 114.4
  TOP w0.102: v1(202.16,60.74) 201.41,59.99 v2(199.8,59.99) 199.66,59.99 199.26,60.4 198.95,60.4 198.68,60.68 198.2,60.68 198.08,60.8 UE1.53 ; v2(225.33,154.07) 225.5,154.25 JKB.8
  IN2 w0.127: v2(199.8,59.99) 200.38,59.99 212.17,71.78 212.17,86.45 216.06,90.33 216.06,123.91 224.74,132.6 224.74,149.78 225.76,150.8 225.76,153.64 v2(225.33,154.07)
KSO15: length 109.7
  TOP w0.102: JKB.10 v2(223.96,152.65) ; UE1.54 v2(198.48,61.2)
  IN2 w0.127: v2(223.96,152.65) 223.96,151.33 222.96,150.34 222.96,140.26 223.37,139.85 223.37,136.44 214.07,127.14 214.07,90.19 210.87,86.98 210.87,72.47 200.38,61.97 199.25,61.97 v2(198.48,61.2)
  BOTTOM w0.102: v2(223.96,152.65) 223.96,152.11 v1(224.03,152.03)
KSO16: length 109.1
  TOP w0.102: JKB.11 v2(223.47,151.85) ; v2(201.07,80.07) v1(196.14,80.07) 194.07,80.07 188.5,74.5 188.5,68.6 189.19,67.91 UE1.81
  IN2 w0.127: v2(223.47,151.85) 212.25,140.62 212.25,91.89 201.07,80.72 v2(201.07,80.07)
LAN_CLKREQ#: length 134.9
  TOP w0.102: v2(109.6,139.95) v1(109.6,139.19) 109.6,138.4 109.17,137.96 109.17,137.03 109.21,136.98 109.21,136.18 109.77,135.62 RP63.1 109.77,135.16 110.25,134.69 v2(110.25,132.17)
  BOTTOM w0.102: v2(109.6,139.95) 107.75,141.81 106.66,141.81 105.17,143.29 102.29,143.29 101.87,142.87 96.6,142.87 96.43,143.05 91.08,143.05 88.18,140.15 88.18,133.1 88.99,132.28 88.99,125.6 77.72,114.32 69.9,114.32 68.38,115.85 40.62,115.85 38.1,113.33 38.1,104.57 34.67,101.14 34.67,93.34 37.05,90.97 37.05,87.21 37.55,86.71 UL1.12 ; v2(110.25,132.17) 110.59,132.52 USOC1.BG3
LAN_X1_R: length 2.4
  TOP w0.102: RG5.1 68.23,35.82 v1(67.57,36.48) 67.5,36.55 UG1.6
LCD_TEST: length 122.7
  TOP w0.102: v2(199.93,79.58) 198.02,79.58 v1(197.38,78.93) 194.75,76.3 194.75,69.61 192.79,67.65 UE1.72
  IN2 w0.127: v4(220.63,174.57) 222.02,173.18 222.02,154.79 211.74,144.5 211.74,92.66 199.93,80.85 v2(199.93,79.58)
  BOTTOM w0.102: JLVDS.33 220.45,174.39 v4(220.63,174.57)
LG_3V: length 2.3
  TOP w1.016: 131.25,19.99 131.25,22.25
  vias: v1(130.88,18.93)
LG_5V: length 6
  IN2 w1.016: 126.93,19.73 125.38,21.28 125.38,24.13 126.06,24.81
  vias: v1(126.56,18.79) v4(125.92,25.79) v4(127.28,18.69) v4(127.77,18.21)
LGATE1: length 11.6
  TOP w0.102: v4(159.11,132.05) v1(158.56,132.05)
  IN2 w1.016: 153.27,124 153.27,125.75 154.68,127.16 154.68,130.01 157.15,132.48 158.09,132.48
  vias: v2(154.31,122.98) v2(154.31,122.4) v4(159.77,132.08)
LGATEG: length 17
  IN2 w1.016: 142.17,136.09 143.77,134.49 158.55,134.49
  vias: v1(142.24,138.19) v4(141.68,137.03) v4(142.4,137.01) v4(159.53,134.48) v4(160.02,134.06)
LID_SW#: length 164.7
  TOP w0.102: JPWR.2 v2(44.35,96.72) ; v2(171,62.42) 171,61.57 174.05,58.52 176.58,58.52 RE71.2 CE30.1 179.57,58.16 179.73,58 UE1.115
  BOTTOM w0.102: v2(44.35,96.72) 44.91,96.16 44.91,95.32 46.28,93.95 46.28,90.62 56.47,80.43 56.47,75.23 60.73,70.97 79.52,70.97 84.6,76.05 150.9,76.05 159.08,67.87 165.56,67.87 v2(171,62.42)
LINE1-L: length 5.6
  TOP w0.203: CA67.1 v1(37.9,17.6) 39.39,19.09 39.39,19.61 39.73,19.95 UA1.22
LINE1-R: length 6.9
  TOP w0.203: CA68.1 35.3,18.18 37.96,18.18 38.71,18.93 v1(38.71,19.23) 38.71,19.4 39.66,20.35 UA1.21
LINE1-VREFO-L: length 3.4
  TOP w0.203: RA165.1 44.1,16.29 43.68,16.29 43.31,16.66 43.31,17.12 v1(43.36,17.17) 43.41,17.22 UA1.31
LINE1-VREFO-R: length 5
  TOP w0.102: v1(43.17,13.96) 43.17,15.2 RA166.1
  TOP w0.203: RA166.1 43.73,15.77 42.98,16.52 42.98,17.47 43.01,17.5 UA1.30
LINE-IN-L: length 28.1
  TOP w0.254: RA80.2 v4(35.87,13.65) ; RA165.2 v2(44.62,14.18)
  IN1 w0.254: v2(44.62,14.18) 44.62,13.84 43.65,12.87 38.35,12.87 37.56,13.65 v4(35.87,13.65) 35.35,14.17 31.91,14.17 31.49,13.75 25.81,13.75 24.63,14.93 v2(23.19,14.93)
  BOTTOM w0.254: LA8.2 RA83.1 RA55.2 v2(23.19,14.93)
LINE-IN-R: length 29.1
  TOP w0.254: RA166.2 v2(43.74,14.18) ; RA82.2 34.52,14.8 v4(34.1,14.8)
  IN1 w0.254: v2(43.74,14.18) 43.74,14.16 43.21,13.63 38.67,13.63 37.5,14.8 v4(34.1,14.8) 34.1,14.79 31.51,14.79 31.02,14.3 26.41,14.3 25.35,15.36 25.35,17.4 v2(23.83,18.92)
  BOTTOM w0.254: LA9.2 RA84.1 RA56.2 v2(23.83,18.92)
LPC_AD0: length 143.7
  TOP w0.102: UE1.10 186.79,51.94 187.25,52.41 v2(187.25,53.1)
  IN2 w0.127: v2(183.06,92.73) 183.06,67.55 184.78,65.83 184.78,61.6 185.95,60.43 185.95,57.44 186.8,56.6 186.8,53.56 v2(187.25,53.1)
  BOTTOM w0.102: USOC1.BH16 116.11,129.06 116.18,129.06 117.47,130.35 118.85,130.35 119.03,130.53 119.64,130.53 121.9,132.79 125.24,132.79 135.36,122.67 135.36,112.1 134.09,110.83 134.09,100.94 138.71,96.31 146.17,96.31 149.45,93.04 182.76,93.04 v2(183.06,92.73)
LPC_AD1: length 142.4
  TOP w0.102: v2(186.77,52.75) 185.99,51.97 UE1.8
  IN2 w0.127: v2(182.4,91.97) 182.4,71.58 182.07,71.24 182.07,70.56 182.61,70.01 182.61,67.46 184.4,65.67 184.4,61.39 185.57,60.22 185.57,57.29 186.41,56.44 186.41,53.11 v2(186.77,52.75)
  BOTTOM w0.102: v2(182.4,91.97) 179.84,91.97 179.58,92.23 149.25,92.23 145.9,95.58 138.18,95.58 132.93,100.82 132.93,110.91 134.65,112.63 134.65,122.36 125.01,132 122.13,132 120.13,130.01 119.1,130.01 119.04,129.94 117.68,129.94 USOC1.BJ17
LPC_AD2: length 147.8
  TOP w0.102: v2(185.98,54.96) 185.98,52.75 185.59,52.36 UE1.7
  IN2 w0.127: v2(185.98,54.96) 185.98,56.34 185.19,57.13 185.19,60.02 184,61.21 184,65.54 182.23,67.3 182.23,69.84 181.69,70.38 v2(181.69,94.82)
  BOTTOM w0.102: USOC1.BJ13 114.91,130.25 115.62,130.96 115.62,131.8 119.76,135.94 124.69,135.94 137.33,123.3 137.33,112.56 138.26,111.64 138.26,108.32 136.06,106.12 136.06,101.61 139.55,98.12 147.1,98.12 149.75,95.46 181.04,95.46 v2(181.69,94.82)
LPC_AD3: length 147.9
  TOP w0.102: v2(185.47,53.16) 185.45,53.16 184.79,52.5 UE1.5
  IN2 w0.127: v2(180.75,94.64) 181.23,94.16 181.23,67.77 183.62,65.38 183.62,61.01 184.81,59.82 184.81,56.97 185.47,56.31 v2(185.47,53.16)
  BOTTOM w0.102: USOC1.BG14 114.68,129.01 114.68,129.46 114.82,129.6 114.99,129.6 115.24,129.85 115.24,130.17 115.99,130.92 115.99,131.67 119.91,135.58 124.54,135.58 136.97,123.15 136.97,112.42 137.9,111.49 137.9,108.53 135.7,106.33 135.7,101.46 139.4,97.76 146.95,97.76 150.08,94.64 v2(180.75,94.64)
LPC_CLK_0: length 7.4
  BOTTOM w0.102: RC51.2 119.85,132.78 118.61,131.55 CC25.1 117.55,131.14 117.25,131.14 116.44,130.33 116.01,130.33 115.65,129.97 115.65,129.68 115.29,129.32 115.29,129.18 115.07,128.96 USOC1.BG15
LPC_CLK_1: length 6.8
  BOTTOM w0.102: 114.98,129.3 115.45,129.77 115.45,130.07 116.48,131.1 116.48,131.38 v1(116.59,131.49) CC26.1 117.94,132.21 118.03,132.3 118.05,132.3 119.09,133.34 RC52.2
LPC_CLK_EC: length 143.5
  TOP w0.102: R2354.2 187.42,49.49 v2(187.42,49.54) 187.59,49.71 UE1.12
  IN2 w0.127: v2(183.06,94.05) 184.33,92.78 184.33,69.82 183.82,69.31 183.82,67.86 185.3,66.39 185.3,61.8 186.88,60.23 186.88,57.24 187.3,56.81 187.3,53.97 187.99,53.29 187.99,50.11 v2(187.42,49.54)
  BOTTOM w0.102: RC51.1 121.98,134 122.2,133.78 125.66,133.78 136.38,123.07 136.38,111.68 135.21,110.51 135.21,101.28 139.2,97.28 146.75,97.28 149.98,94.05 v2(183.06,94.05)
LPC_CLKRUN#: length 151.4
  TOP w0.102: v2(184.94,93.6) v1(185.51,93.6)
  IN2 w0.127: v2(188.5,53.31) 188.5,53.5 187.81,54.18 187.81,57.02 187.38,57.45 187.38,60.44 185.86,61.97 185.86,66.55 184.94,67.46 184.94,70.58 185.55,71.19 185.55,72.85 184.94,73.45 v2(184.94,93.6)
  BOTTOM w0.102: RX4.1 191.34,55.37 189.26,53.29 188.52,53.29 v2(188.5,53.31) ; v2(184.94,93.6) 184.89,93.55 149.8,93.55 146.55,96.8 139,96.8 134.64,101.16 134.64,110.62 135.89,111.88 135.89,122.87 125.46,133.3 121.72,133.3 119.31,130.89 RC60.2 117.72,130.89 116.15,129.31 116.08,129.31 115.67,128.91 115.53,128.91 115.37,128.75 115.37,128.5 115.18,128.3 115.18,128.12
LPC_FRAME#: length 141.5
  TOP w0.102: v2(184.72,53.13) 184.39,52.8 UE1.4
  IN2 w0.127: v2(184.72,53.13) 184.72,53.61 184.41,53.92 184.41,59.68 183.21,60.88 183.21,62.86 180.85,65.22 180.85,92.3 v2(180.7,92.45)
  BOTTOM w0.102: v2(180.7,92.45) 180.55,92.61 149.38,92.61 146.02,95.96 138.3,95.96 133.53,100.73 133.53,111 135,112.48 135,122.52 125.12,132.41 122.03,132.41 119.92,130.3 119.09,130.3 118.93,130.15 117.55,130.15 116.26,128.86 116.2,128.86 115.98,128.63 115.98,128.24 USOC1.BG17
LPC_RCOMP: length 8.7
  TOP w0.254: v2(114.94,127.18) 114.94,129.64 113.9,130.68 v1(113.9,131.24) 113.9,133.94 RC50.2
  BOTTOM w0.254: v2(114.94,127.18) 115.09,127.03 USOC1.BF18
LS_OE: length 2.4
  TOP w0.102: v1(101.25,107.9) 102.14,108.79 102.14,108.91 102.53,109.31 RP65.4
LVDS_A0+: length 13.4
  IN2 w0.127: v2(205.11,171.91) 204.82,171.91 204.7,171.79 204.7,171.02 205.46,170.25 205.46,167.79 208.55,164.7 209.06,164.7 v2(209.38,165.02)
  BOTTOM w0.102: JLVDS.2 204.95,172.65 204.83,172.54 204.83,172.18 v2(205.11,171.91) ; UT2.25 208.34,164.96 208.5,164.81 209.17,164.81 v2(209.38,165.02)
LVDS_A0-: length 13.4
  IN2 w0.127: v2(204.29,171.91) 204.38,171.81 204.38,170.88 205.15,170.12 205.15,167.66 208.42,164.38 v2(209.38,164.38)
  BOTTOM w0.102: v2(209.38,164.38) 209.22,164.54 208.44,164.54 208.36,164.46 UT2.26 ; v2(204.29,171.91) 204.57,172.18 204.57,172.54 204.45,172.65 JLVDS.1
LVDS_A1+: length 12.5
  IN2 w0.127: v2(206.61,171.44) 206.36,171.19 206.36,168.08 207.28,167.16 208.78,167.16 v2(209.1,167.47)
  BOTTOM w0.102: v2(209.1,167.47) 208.8,167.17 207.43,167.17 206.82,166.56 206.82,166.24 206.71,166.12 UT2.23 ; JLVDS.5 206.45,172.65 206.33,172.54 206.33,171.72 v2(206.61,171.44)
LVDS_A1-: length 12.5
  IN2 w0.127: v2(205.79,171.44) 206.04,171.19 206.04,167.94 207.15,166.84 208.91,166.84 v2(209.1,166.65)
  BOTTOM w0.102: JLVDS.4 205.95,172.65 206.07,172.54 206.07,171.72 v2(205.79,171.44) ; UT2.24 207.21,166.12 207.09,166.24 207.09,166.45 207.54,166.9 208.85,166.9 v2(209.1,166.65)
LVDS_A2+: length 13.9
  IN2 w0.127: v2(207.7,168.73) 208.41,168.73 209.27,169.6 209.27,170.48 209.69,170.9 210.23,170.9 v2(210.44,171.11)
  BOTTOM w0.102: v2(210.44,171.11) 210.44,170.81 210.32,170.69 208.69,170.69 207.83,171.54 207.83,172.54 207.95,172.65 JLVDS.8 ; v2(207.7,168.73) 207.54,168.58 206.74,168.58 205.71,167.55 UT2.21
LVDS_A2-: length 13.8
  IN2 w0.127: v2(210.44,170.3) 210.15,170.58 209.82,170.58 209.59,170.35 209.59,169.47 208.54,168.42 207.98,168.42 207.72,168.15 v2(207.7,168.15)
  BOTTOM w0.102: UT2.22 206.21,166.2 205.97,166.43 205.97,167.44 206.85,168.31 207.54,168.31 v2(207.7,168.15) ; JLVDS.7 207.45,172.65 207.57,172.54 207.57,171.43 208.58,170.42 210.32,170.42 v2(210.44,170.3)
LVDS_ACLK+: length 18.6
  IN2 w0.127: v2(209.47,171.76) 209.38,171.86 209.38,173.22 208.57,174.03 204.89,174.03 203.19,172.32 203.19,169.4 203.7,168.9 204.2,168.9 v2(204.3,168.8)
  BOTTOM w0.102: UT2.19 204.71,166.18 204.82,166.29 204.82,168.9 204.73,168.98 204.48,168.98 v2(204.3,168.8) ; JLVDS.11 209.45,171.78 v2(209.47,171.76)
LVDS_ACLK-: length 18.6
  IN2 w0.127: v2(204.3,169.61) 204.3,169.29 204.22,169.21 203.83,169.21 203.51,169.53 203.51,172.19 205.02,173.71 208.44,173.71 209.06,173.09 209.06,171.99 208.88,171.81 v4(208.66,171.81)
  BOTTOM w0.102: JLVDS.10 208.95,172.65 209.18,172.42 209.18,172.12 208.88,171.81 v4(208.66,171.81) ; UT2.20 205.21,166.17 205.08,166.29 205.08,169.01 204.84,169.25 204.38,169.25 204.3,169.34 v2(204.3,169.61)
LX_1.0VALWP: length 1.3
  BOTTOM w0.102: 53.84,92.17 53.84,92.16 54.38,91.62 v1(54.38,91.15)
LX_1.05VSP:
  vias: v1(166.37,112.41)
LX_3V: length 7.1
  IN2 w1.016: 136.15,22.43 136.15,19.25 133.38,16.48
  vias: v1(136.44,26.52) v4(131.69,16.06) v4(132.32,16.06) v4(135.31,28.75) v4(135.31,27.99) v4(135.31,27.23) v4(135.94,23.87) v4(136.07,28.75) v4(136.07,27.99) v4(136.07,27.23) v4(136.68,23.87) v4(136.83,28.75) v4(136.83,27.99) v4(136.83,27.23)
LX_5V: length 7.4
  IN2 w1.016: 125.07,16.36 121.34,20.09 121.34,22.17
  vias: v1(120.37,28.89) v4(120.58,27.3) v4(120.58,26.54) v4(120.58,25.78) v4(121.11,29.18) v4(121.11,28.42) v4(121.21,27.3) v4(121.21,26.54) v4(121.21,25.78) v4(121.26,23.16) v4(121.87,29.18) v4(121.87,28.42) v4(122.03,23.16) v4(122.63,29.18) v4(122.63,28.42) v4(126.2,16.06) v4(126.84,16.06)
LX_+1.8VSP:
  vias: v1(65.62,88.85)
LX_CHG: length 11.6
  IN2 w1.016: 158.19,168.7 162.49,168.7 163.25,169.47 163.25,173.91 164.54,175.21
  vias: v1(166.14,174.33) v4(157.28,169.16) v4(157.28,168.48) v4(165.43,175.59) v4(166.13,175.21)
M_ODT0: length 4.9
  TOP w0.165: v2(121.42,64.22) 121.62,64.22 RD8.1
  BOTTOM w0.165: v2(121.42,64.22) 120.63,63.43 120.15,63.43 119.65,62.94 JDIMM1.116
M_ODT1: length 3
  TOP w0.165: RD9.1 122.03,63.31 v2(121.42,62.7)
  BOTTOM w0.165: v2(121.42,62.7) 120.85,62.13 JDIMM1.120
MCT0: length 4.8
  TOP w0.102: v1(20.29,86.78) RL19.1
  TOP w0.508: RL19.1 19.51,85.54 v2(19.45,85.61)
  BOTTOM w0.508: v2(19.45,85.61) TL1.14
MCT1: length 5
  TOP w0.102: v1(21.68,81.73) RL20.1
  TOP w0.508: v2(19.4,81.8) 19.46,81.73 RL20.1
  BOTTOM w0.508: TL1.11 v2(19.4,81.8)
MDI0+: length 6.8
  BOTTOM w0.089: UL1.1 35.05,82.87 35.02,82.9 34.55,82.9 v4(32.99,81.35) 32.67,81.02 32.67,80.13 32.25,79.72 32,79.72 31.54,79.26 TL1.8
MDI0-: length 6.8
  BOTTOM w0.089: TL1.7 31.51,80.53 31.98,80.06 32.11,80.06 32.33,80.28 32.33,81.17 v4(33.89,82.73) 34.41,83.25 35.02,83.25 35.05,83.27 UL1.2
MDI1+: length 6.7
  BOTTOM w0.089: UL1.4 35.05,84.07 35.02,84.1 34.79,84.1 v4(34.34,84.55) 32.48,86.42 32.48,87.14 32.27,87.34 32.08,87.34 31.61,86.88 TL1.2
MDI1-: length 6.7
  BOTTOM w0.089: TL1.1 31.66,88.15 32.13,87.68 32.42,87.68 32.82,87.28 32.82,86.56 v4(33.12,86.26) 34.94,84.45 35.02,84.45 35.05,84.47 UL1.5
MDO0+: length 8
  BOTTOM w0.089: JLAN.1 15.52,79.23 16.32,78.43 17.64,78.43 18.73,79.52 v4(20.22,79.52) 20.62,79.52 20.88,79.26 TL1.9
MDO0-: length 8
  BOTTOM w0.089: JLAN.2 16.1,79.14 16.46,78.77 17.5,78.77 18.59,79.86 v4(18.95,79.86) 20.35,79.86 21.01,80.53 TL1.10
MDO1+: length 12
  BOTTOM w0.089: JLAN.3 16.35,81.27 17.1,82.02 18.32,82.02 18.86,82.56 v4(18.86,86.08) 18.86,86.64 19.34,87.12 20.43,87.12 20.67,86.88 TL1.15
MDO1-: length 12
  BOTTOM w0.089: JLAN.6 16.1,83.65 17.39,82.36 18.18,82.36 18.52,82.7 18.52,86.79 19.2,87.47 v4(19.96,87.47) 20.4,87.47 21.08,88.15 TL1.16
ME_SUS_PWR_ACK: length 1.8
  TOP w0.102: UE1.34 198.72,53.2 T204.1
MIC1-L: length 3.2
  TOP w0.203: CA74.1 37.81,20.52 v1(38.69,20.52) 38.81,20.52 39.44,21.15 UA1.19
MIC_CLK: length 300.4
  TOP w0.102: LA1.2 CA22.1 45.86,28.51 46.13,28.78 46.13,29.46 46.74,30.07 v2(46.76,30.07)
  IN2 w0.127: v2(46.76,30.07) 47.96,28.88 78.2,28.88 80.97,26.11 111,26.11 113.85,28.95 116.34,28.95 121.88,34.49 158.48,34.49 160.95,32.01 173.17,32.01 187,45.84 187,47.57 189.26,49.83 189.26,52.62 189.81,53.17 189.81,55.79 189.6,56 189.6,56.66 189.32,56.94 189.32,58.05 188.75,58.62 188.75,61.14 187.73,62.15 187.73,62.43 188.4,63.09 189.77,63.09 195.1,68.43 195.1,74.16 199.37,78.43 199.37,81.01 210.75,92.38 210.75,144.23 221.14,154.62 221.14,170.38 v2(219.13,172.39)
  BOTTOM w0.102: v2(219.13,172.39) 218.95,172.57 JLVDS.30
MIC_CLK_C: length 3
  TOP w0.102: UA1.3 44.61,24.97 44.72,25.09 44.72,25.5 v1(45.15,25.92) 45.15,26.07 45.56,26.48 LA1.1
MIC_DATA: length 301.4
  TOP w0.102: UA1.2 45.01,25.19 46.13,26.31 46.13,28.09 46.61,28.58 46.61,29.21 46.97,29.56 48.11,29.56 v2(48.11,29.56)
  IN2 w0.127: v2(48.11,29.56) 78.24,29.56 81.18,26.62 110.72,26.62 113.57,29.46 116.13,29.46 121.71,35.04 158.65,35.04 161.16,32.52 171.95,32.52 186.49,47.06 186.49,47.78 188.75,50.04 188.75,52.83 189.3,53.38 189.3,55.53 188.65,56.18 188.65,58 188.24,58.41 188.24,60.93 187.23,61.94 187.23,62.64 188.42,63.83 189.64,63.83 194.59,68.78 194.59,74.37 198.33,78.1 198.33,94.39 210.19,106.25 210.19,144.39 220.63,154.83 220.63,170.13 v2(219.08,171.68)
  BOTTOM w0.102: JLVDS.32 219.95,172.5 219.1,171.65 v2(219.08,171.68)
MIC_IN: length 24.7
  TOP w0.102: v4(16.59,14.96) v1(16.59,14.4)
  IN2 w1.016: 24.9,12.93 21.42,12.93 20.22,11.73 17.15,11.73 16.28,12.6 16.28,14.02 ; 37.65,20.34 36.35,19.05 33.48,19.05 27.46,13.03
  vias: v4(15.9,14.93) v4(25.9,13.14) v4(26.53,13.14) v4(38.21,21.28) v4(38.84,21.28)
MIC_IN_R: length 42.6
  TOP w0.102: v4(14.08,20.88) v1(14.88,20.88)
  IN1 w0.508: v2(15.65,8.3) v2(15.65,7.36) 14.3,6.02 2.43,6.02 JHP.3
  IN2 w0.508: v2(15.65,7.36) 14.3,6.02 2.43,6.02 JHP.3
  IN2 w1.016: 15.65,9.27 15.65,10.62 14.38,11.89 14.38,15.95 14.56,16.13 14.56,19.17
  vias: v4(14.08,20.24)
MIIC_SCL: length 7.9
  BOTTOM w0.102: RT2.1 210.21,156.67 210.21,158.19 210.34,158.32 RT3.2 210.72,159.61 v1(209.86,160.47) 208.37,161.96 UT2.31
MIIC_SDA: length 9
  BOTTOM w0.102: UT2.30 208.68,162.46 208.97,162.18 208.97,161.85 v1(211.26,159.55) 211.74,159.08 RT12.2 211.36,158.32 211.23,158.19 211.23,156.67 RT20.1
MMC1_RCOMP: length 7.4
  TOP w0.254: v2(113.44,125.58) 112.66,125.58 111.9,124.81 110.87,124.81 110.14,125.55 109.76,125.55 109.17,124.97 v1(108.68,124.97) 108.11,124.97 RC57.1
  BOTTOM w0.254: v2(113.44,125.58) 113.47,125.55 USOC1.AY18
MS_BS: length 32.9
  TOP w0.102: UR1.22 v2(174.09,23.19)
  BOTTOM w0.102: v2(174.09,23.19) 174.09,26.41 173.84,26.67 173.46,26.67 173.21,26.41 173.21,22.98 173.03,22.81 172.62,22.81 172.37,23.06 170.67,23.06 170.49,23.24 170.49,23.49 170.67,23.67 172.37,23.67 172.47,23.77 172.47,24.18 172.37,24.28 170.77,24.28 170.59,24.46 170.59,24.71 170.77,24.89 172.37,24.89 172.47,24.99 172.47,26.87 173.03,27.43 174.52,27.43 174.84,27.76 175.2,27.76 175.3,27.65 175.3,26.77 175.4,26.67 175.87,26.67 176.1,26.9 176.1,27.53 176.33,27.76 177.63,27.76 177.73,27.65 177.73,26.74 177.83,26.64 178.24,26.64 178.34,26.74 178.34,28.93 178.56,29.15 JREAD.15
MS_CLK_SD_WP: length 53
  TOP w0.102: RR3.2 CR5.1 182.97,21.83 v1(183.75,22.61) 189.67,28.52 189.67,28.78 189.49,28.95 189.23,28.95 183.38,23.1 183.13,23.1 182.95,23.28 182.95,23.53 186.03,26.61 186.03,26.85 v2(187.68,28.5)
  IN2 w0.127: v2(187.68,28.5) v2(187.68,31.27)
  BOTTOM w0.102: v2(187.68,31.27) 187.68,31.85 186.48,33.04 172.11,33.04 170.19,31.12 JREAD.22 ; JREAD.5 v2(187.68,28.5)
MS_CLK_SD_WP_R: length 3.3
  TOP w0.102: UR1.8 179.93,22.69 180.11,22.5 180.11,21.16 180.33,20.94 RR3.1
MS_D0: length 33.3
  TOP w0.102: v2(176.53,26.26) 176.82,25.98 UR1.16
  BOTTOM w0.102: JREAD.12 181.6,28.64 181.98,28.25 182.13,28.25 182.68,28.8 182.93,28.8 183.11,28.63 183.11,28.37 182.56,27.82 182.56,27.68 182.84,27.39 182.99,27.39 183.29,27.69 183.43,27.69 183.72,27.4 183.72,27.26 183.42,26.96 183.42,26.81 184.42,25.81 184.42,25.56 184.24,25.38 183.99,25.38 180.53,28.84 180.28,28.84 180.1,28.66 180.1,28.41 182.79,25.71 182.79,25.46 182.62,25.28 182.36,25.28 179.75,27.9 179.49,27.9 179.31,27.72 179.31,27.47 181.42,25.37 181.42,25.22 181.13,24.94 180.98,24.94 179.44,26.48 179.29,26.48 179.07,26.26 v2(176.53,26.26)
MS_D1_SD_D3: length 37.4
  TOP w0.102: UR1.20 173.92,24.19 173.66,24.45 v2(173.66,25.42)
  IN2 w0.127: v2(173.66,25.42) 173.66,28.27 174.93,29.54 174.93,30.66 177.3,33.02 188.52,33.02 189.06,32.48 v2(189.06,32.03) 187.84,32.03 187.58,32.28 181.99,32.28 181.11,31.39 v2(180.08,31.39)
  BOTTOM w0.102: JREAD.3 189.96,31.24 189.17,32.03 v2(189.06,32.03) ; JREAD.13 v2(180.08,31.39)
MS_D2_SD_CLK: length 31.8
  TOP w0.102: v2(177.45,28.7) 177.32,28.57 CR6.1 RR2.2
  IN2 w0.127: v2(178.97,28.7) 178.17,28.7 177.98,28.89 177.98,29.15 178.17,29.33 182.34,29.33 182.53,29.52 182.53,29.78 182.34,29.97 179.59,29.97 179.46,30.1 179.46,31.69 179.27,31.87 179.01,31.87 178.82,31.69 178.82,30.1 178.7,29.97 178.32,29.97 178.19,30.1 178.19,31.79 178,31.98 177.74,31.98 177.55,31.79 177.55,30.1 177.43,29.97 176.58,29.97 176.41,29.79 176.41,28.93 176.64,28.7 v2(177.45,28.7)
  BOTTOM w0.102: v2(178.97,28.7) 179.32,29.04 JREAD.14 179.32,31.41 179.81,31.9 v1(181.25,31.9) 182.65,31.9 183.12,31.44 JREAD.10
MS_D2_SD_CLK_R: length 2
  TOP w0.102: RR2.1 178.21,26.85 177.32,25.95 UR1.15
MS_D3: length 32.9
  TOP w0.102: UR1.12 181.43,24.69 v2(181.64,24.48)
  BOTTOM w0.102: v2(181.64,24.48) 184.71,24.48 184.94,24.71 184.94,26.9 185.04,27 185.44,27 185.55,26.9 185.55,22.02 185.72,21.84 185.98,21.84 186.16,22.02 186.16,26.87 186.26,26.97 186.66,26.97 186.76,26.87 186.76,22.6 186.94,22.43 187.2,22.43 187.37,22.6 187.37,27.23 186.16,28.45 JREAD.7
MS_INS#: length 10.3
  TOP w0.102: v2(184.64,27.33) 184.64,26.48 CR10.1 181.35,23.19 UR1.9
  BOTTOM w0.102: JREAD.8 v2(184.64,27.33)
NTC: length 2.2
  BOTTOM w0.203: PU500.7 165.6,131.84 166.34,131.1 PR523.1
NTC_1: length 46.3
  TOP w0.254: v2(151.08,124.13) PH502.1
  IN2 w0.254: v2(151.08,124.13) 150.52,124.69 147.4,124.69 146.49,123.77 146.49,117.47 147.32,116.63 160.02,116.63 v2(162.69,119.3)
  BOTTOM w0.254: PR523.2 167.92,130.21 PR529.1 169.62,130.2 169.8,130.02 169.8,126.41 v2(162.69,119.3)
NTCG: length 3.3
  BOTTOM w0.203: PU500.1 165.56,134.24 165.76,134.45 165.76,135.61 v1(166.12,135.97) PR515.2
NTCG_1: length 48
  TOP w0.254: PH501.2 143.11,140.54 143.79,141.22 v2(143.79,141.55) ; v4(168.65,135.96) 168.64,135.96 167.72,135.96 v1(167.48,135.73) 165.19,133.44 PR514.2
  BOTTOM w0.203: v4(168.65,135.96) 167.98,135.96 PR515.1
  BOTTOM w0.254: v4(168.65,135.96) 169.12,136.42 169.12,141.4 167.62,142.9 164.24,142.9 157.2,149.93 150.37,149.93 146.84,146.4 146.84,142.24 146.16,141.55 v2(143.79,141.55)
ODD_DA#: length 156.8
  TOP w0.102: RP54.1 123.1,134.38 v2(123.04,134.31) 123.04,133.9 126.83,130.12 126.83,128.17 v1(125.35,126.69) 124.29,125.63 v2(124.29,125.29)
  IN2 w0.102: 122.05,125.07 119.54,125.07 117.47,123 v2(116.26,123)
  IN2 w0.127: v2(128.83,133.25) 128.63,133.25 128.4,133.47 123.4,133.47 123.04,133.83 v2(123.04,134.31) ; 122.05,125.07 122.28,125.07 122.89,125.68 123.78,125.68 124.17,125.29 v2(124.29,125.29)
  BOTTOM w0.102: 116.21,122.27 116.21,122.95 v2(116.26,123) ; v2(128.83,133.25) 129.29,132.79 129.29,132.76 138.14,123.91 138.14,112.9 141.75,109.29 143.48,109.29 146.82,105.96 146.82,100.2 149.68,97.33 158.68,97.33 159.9,98.55 159.9,102.3 160.56,102.97 193.68,102.97 207.88,117.17 RS10.1
ODD_DETECT#: length 145.9
  TOP w0.102: v2(193.22,98.07) v1(193.78,98.07)
  IN2 w0.102: 123.35,122.76 122.48,122.76 121.69,121.97 118.75,121.97 117.3,120.52 v2(116.44,120.52)
  IN2 w0.127: v2(124.62,122.76) 123.35,122.76 ; v2(193.22,98.07) 203.69,108.53 v2(203.69,112.09)
  BOTTOM w0.102: v2(193.22,98.07) 185.47,90.32 167.69,90.32 166.37,91.64 146.92,91.64 146.69,91.87 136.22,91.87 128.32,99.76 128.32,112.52 129.57,113.76 129.57,117.35 128.62,118.29 RC68.2 125.19,122.18 v2(124.62,122.76) ; v2(203.69,112.09) RS09.1 ; v2(116.44,120.52) 116.36,120.6 115.88,120.6 115.88,120.6
ODD_EN: length 7.3
  TOP w0.102: v2(223.5,110.06) v1(224.01,110.06)
  TOP w0.254: QS2.3 223.48,110.04 v2(223.5,110.06)
  BOTTOM w0.254: RS6.1 222.36,107.6 QS3.1 222.19,109.9 CS16.1 v2(223.5,110.06)
ODD_EN#: length 138.6
  TOP w0.102: v2(211.18,110.74) 211.18,112.93 212.43,114.18 UI7.4
  IN2 w0.102: 122.05,126.39 121.31,126.39 121.19,126.52 120.41,126.52 117.87,123.98 v2(117.15,123.98)
  IN2 w0.127: v2(144.68,99.64) 144.68,106.64 131.98,119.34 131.98,121.64 127.91,125.72 125.77,125.72 125.47,126.02 124.23,126.02 123.86,126.39 122.05,126.39
  BOTTOM w0.102: v2(144.68,99.64) 146.4,99.64 149.89,96.15 158.21,96.15 160.13,98.07 160.13,102.21 160.66,102.74 194.27,102.74 202.28,110.74 v2(211.18,110.74) 214.8,107.12 QS3.2 ; USOC1.BD26 117.35,123.78 v2(117.15,123.98)
ON/OFFBTN#: length 227.6
  TOP w0.102: UE1.114 180.59,58.4 179.35,59.64 173.66,59.64 v2(171.43,61.87) ; v2(201.17,32.34) SW1.4 SW1.3 196.28,31.13 195.94,30.8 CE20.1 194.87,30.8 194.54,30.47 v3(194.54,29.23) RE49.1 ; v2(44.78,94.46) 43.51,94.46 43.35,94.62 JPWR.3
  IN2 w0.127: v2(177.37,44.24) 176.61,45.01 176.61,49.68 171.43,54.86 v2(171.43,61.87)
  BOTTOM w0.102: v2(201.17,32.34) 199.22,34.29 SW2.4 SW2.3 199.22,41.04 198.19,42.07 180.46,42.07 179.1,43.43 178.18,43.43 v2(177.37,44.24) ; v2(171.43,61.87) 170.92,61.87 165.21,67.59 159.03,67.59 150.8,75.82 84.69,75.82 79.61,70.74 59.77,70.74 57.05,73.45 56.32,73.45 54.51,75.26 54.51,82.07 46.05,90.52 46.05,93.19 v2(44.78,94.46)
P2: length 7.7
  TOP w0.508: PQ707.3 v2(141.52,155.59)
  IN2 w0.508: v4(144.07,161.16) 144.07,158.14 v2(141.52,155.59)
  vias: v1(141.24,164.21) v4(143.31,161.16)
P3: length 0.9
  TOP w0.508: PC701.2 v2(143.28,155.98)
  vias: v1(147.81,160.56)
PBTN_OUT#: length 119.2
  TOP w0.102: U63.2 82.2,90.55 83.62,89.13 83.62,85.92 85.42,84.12 v1(85.42,83.2) 85.42,79.25 v2(85.96,78.71) ; v2(179.91,62.46) 180.23,62.46 180.5,62.19 180.5,61.75 180.64,61.6 UE1.106
  BOTTOM w0.102: v2(85.96,78.71) 86.62,79.38 155.42,79.38 164.11,70.69 168.18,70.69 171.1,67.77 177.45,67.77 179.1,66.11 179.1,64.34 179.48,63.96 179.48,62.89 v2(179.91,62.46)
PC_BEEP: length 175.9
  TOP w0.102: v2(192.33,47.09) 192.33,46.53 192.51,46.35 RA19.1 192.51,45.67 192.18,45.34 DA8.1 ; RA79.2 v2(41.05,30.11)
  IN2 w0.127: v2(190.66,56.59) 191.8,55.45 191.8,51.79 192.33,51.26 v2(192.33,47.09)
  BOTTOM w0.102: v2(41.05,30.11) 43.65,32.71 55.27,32.71 56.04,31.95 74.6,31.95 91.72,49.07 149.72,49.07 151.63,50.98 157.84,50.98 158.5,51.64 165.21,51.64 167.27,53.69 168.82,53.69 170.55,55.42 173.96,55.42 174.32,55.07 183.47,55.07 185.42,57.02 v1(186.92,57.02) 190.22,57.02 v2(190.66,56.59)
PCH_HOT#: length 1
  TOP w0.102: T207.1 197.64,71.26 RE7.1
PCH_USB3_RX0_N: length 119.1
  IN2 w0.127: v2(96.78,117.87) 96.63,117.72 91.1,117.72 89.39,119.43 87.3,119.43 83.42,115.54 82.27,115.54 73.84,107.12 73.84,95.86 74.12,95.58 74.12,91.36 66.55,83.79 56.22,83.79 50.06,77.64 47.65,75.23 47.65,69.57 44.62,66.54 44.62,62.42 43.29,61.09 43.29,60.06 v2(43.04,59.81)
  BOTTOM w0.102: v2(43.04,59.81) 43.31,60.08 43.31,60.58 42.96,60.93 21.96,60.93 21.66,60.63 LI1.1 ; 96.36,118.21 96.44,118.21 v2(96.78,117.87)
PCH_USB3_RX0_P: length 119.1
  IN2 w0.127: v2(43.8,59.81) 43.55,60.06 43.55,60.98 44.87,62.31 44.87,66.43 47.91,69.47 47.91,75.12 50.24,77.46 56.32,83.54 66.66,83.54 74.38,91.26 74.38,95.68 74.1,95.96 74.1,107.01 82.38,115.29 83.53,115.29 87.41,119.17 89.28,119.17 90.99,117.46 96.55,117.46 v2(96.78,117.23)
  BOTTOM w0.102: v2(96.78,117.23) 96.54,117.46 USOC1.D4 ; v2(43.8,59.81) 43.53,60.08 43.53,60.67 43.05,61.14 21.96,61.14 21.66,61.43 LI1.4
PCH_USB3_TX0_N: length 117.8
  IN2 w0.102: v2(98.64,118.4) 98.53,118.51 98.4,118.51 98.22,118.32 97.83,118.32 97.06,119.1 96.43,119.1 96.01,119.51 96.01,119.96 95.44,120.53 95.24,120.53 95.23,120.52 95.21,120.52
  IN2 w0.127: v2(43.16,62.43) 43.31,62.58 43.72,62.58 44.1,62.96 44.1,66.95 47.12,69.97 47.12,75.56 55.93,84.38 59.86,84.38 60.87,85.39 67.42,85.39 73.56,91.53 73.56,95.33 73.29,95.61 73.29,99.95 71.71,101.53 71.71,105.71 82.18,116.18 83.3,116.18 87.64,120.52 95.21,120.52
  BOTTOM w0.102: v2(43.16,62.43) 42.89,62.7 24.13,62.7 CI3.2 ; USOC1.K7 98.72,118.48 v2(98.64,118.4)
PCH_USB3_TX0_N_C: length 2
  BOTTOM w0.102: CI3.1 22.41,62.71 21.96,62.71 21.66,62.41 LI3.1
PCH_USB3_TX0_P: length 117.8
  IN2 w0.102: v2(98.2,118.93) 98.2,118.64 98.12,118.55 97.93,118.55 97.15,119.33 96.52,119.33 96.24,119.61 96.24,120.06 95.54,120.76 95.24,120.76 95.23,120.78 95.21,120.78
  IN2 w0.127: v2(43.16,63.19) 43.16,62.96 43.28,62.84 43.61,62.84 43.84,63.06 43.84,67.06 46.86,70.08 46.86,75.67 55.83,84.63 59.75,84.63 60.77,85.65 67.32,85.65 73.31,91.64 73.31,95.22 73.03,95.5 73.03,99.85 71.45,101.42 71.45,105.81 82.07,116.43 83.19,116.43 87.53,120.78 95.21,120.78
  BOTTOM w0.102: CI4.2 24.13,62.92 43.03,62.92 43.16,63.05 v2(43.16,63.19) ; USOC1.K6 98.26,118.98 v2(98.2,118.93)
PCH_USB3_TX0_P_C: length 2
  BOTTOM w0.102: CI4.1 22.41,62.92 21.95,62.92 21.66,63.21 LI3.4
PCH_X1: length 160.4
  TOP w0.102: RG6.2 67.21,34.11 66.83,33.73 63.53,33.73 63.02,34.24 v2(63.02,35.51)
  IN2 w0.127: v2(63.02,35.51) 59.22,35.51 44.53,50.2 44.53,56.87 41.84,59.56 41.84,66.7 46.13,70.99 46.13,75.92 55.58,85.38 59.5,85.38 60.54,86.42 67.07,86.42 72.59,91.93 72.59,94.91 72.31,95.19 72.31,99.4 70.55,101.16 70.55,107.94 72.57,109.96 v2(74.88,109.96)
  BOTTOM w0.102: RG10.1 102.33,129.93 97.84,134.41 95.08,134.41 93.55,132.89 93.55,122.65 91.24,120.34 89.48,120.34 79.1,109.96 v1(75.86,109.96) v2(74.88,109.96)
PCH_X1_R: length 2.1
  TOP w0.102: UG1.5 67.1,37.19 67.21,37.08 RG6.1
PCIE_CLKREQ_2#: length 5.5
  TOP w0.102: RP63.3 110.77,134.95 110.87,134.85 110.87,133.09 v1(111.31,132.66) 111.46,132.51 111.46,131.93 111.2,131.68 111.2,131.6 110.91,131.3 v2(110.84,131.3)
  BOTTOM w0.102: v2(110.84,131.3) 110.85,131.31 110.85,131.37 111.03,131.54 111.19,131.54 USOC1.BG5
PCIE_CLKREQ_3#: length 7.7
  TOP w0.102: v2(111.1,130.73) 111.41,131.04 111.41,131.6 111.66,131.85 111.66,133.51 v1(111.21,133.96) 111.08,134.1 111.08,134.85 111.27,135.04 RP63.4
  BOTTOM w0.102: USOC1.BE3 109.91,130.78 110.29,130.4 110.77,130.4 v2(111.1,130.73)
PCIE_PRX_C_DTX_N0: length 4.2
  BOTTOM w0.102: UL1.18 40.82,85.27 41.24,85.69 41.24,85.71 41.8,86.27 v4(42.03,86.27) 42.4,86.27 42.71,86.58 42.71,87 CL31.2
PCIE_PRX_C_DTX_P0: length 4.2
  BOTTOM w0.102: UL1.17 40.36,85.67 40.55,85.49 40.72,85.49 v4(40.89,85.67) 41.72,86.5 42.33,86.5 42.5,86.67 42.5,87.16 42.41,87.25 CL30.2
PCIE_PRX_DTX_N0: length 139.5
  IN2 w0.102: v2(110.21,126.14) 110.32,126.03 110.32,125.79 110.18,125.65 110.04,125.65 109.78,125.9 109.78,126.44 109.53,126.69 109.53,127.4 108.84,128.09 107.77,128.09 106.8,129.06 105.51,129.06 104.52,130.04 104.52,130.06 104.51,130.08
  IN2 w0.127: v2(102.74,140.93) 102.56,140.93 102.39,140.77 102.39,139.33 100.54,137.48 100.54,134.05 104.51,130.08
  BOTTOM w0.102: USOC1.AT13 110.26,126.1 v2(110.21,126.14) ; CL31.1 42.61,88.5 42.61,90.89 41.19,92.31 38.17,92.31 36.47,94.02 36.47,100.29 40.43,104.25 40.43,110.55 44.89,115.01 67.69,115.01 69.22,113.49 78.06,113.49 89.82,125.25 89.82,132.63 89.01,133.44 89.01,139.72 91.49,142.21 94.95,142.21 95.6,141.56 100.1,141.56 101.67,140 102.11,140 102.37,140.26 102.37,140.76 102.53,140.93 v2(102.74,140.93)
PCIE_PRX_DTX_N1: length 43.3
  IN2 w0.102: 103.77,129.34 103.79,129.34 105.86,127.28 108.59,127.28 108.75,127.12 108.75,126.87 108.5,126.63 108.34,126.63 v2(108.22,126.75)
  IN2 w0.127: JMINI.23 105.3,149.81 105.57,149.54 105.57,149.36 105.39,149.17 100.81,149.17 100.07,148.43 99.72,148.08 99.72,144.2 99.24,143.72 99.24,140.73 96.96,138.45 96.96,137.51 95.23,135.78 95.23,132.61 95.6,132.23 97.24,132.23 98.31,133.3 99.82,133.3 103.77,129.34
  BOTTOM w0.102: v2(108.22,126.75) 108.4,126.92 USOC1.AT9
PCIE_PRX_DTX_P0: length 139.5
  IN2 w0.102: 104.32,129.9 104.34,129.88 104.36,129.88 105.41,128.83 106.71,128.83 107.67,127.86 108.74,127.86 109.3,127.31 109.3,126.6 109.55,126.34 109.55,125.81 109.94,125.42 110.28,125.42 110.54,125.68 v2(110.69,125.68)
  IN2 w0.127: v2(101.98,140.93) 102.14,140.78 102.14,139.44 100.28,137.58 100.28,133.94 104.32,129.9
  BOTTOM w0.102: v2(110.69,125.68) 110.68,125.68 USOC1.AT14 ; CL30.1 42.4,88.49 42.4,90.8 41.1,92.1 38.08,92.1 36.25,93.93 36.25,100.38 40.21,104.34 40.21,110.64 44.8,115.22 67.78,115.22 69.31,113.7 77.97,113.7 89.6,125.33 89.6,132.54 88.79,133.35 88.79,139.81 91.4,142.43 95.04,142.43 95.69,141.78 100.19,141.78 101.76,140.22 102.02,140.22 102.15,140.35 102.15,140.76 v2(101.98,140.93)
PCIE_PRX_DTX_P1: length 43.3
  IN2 w0.102: v2(108.72,126.29) 108.72,126.51 108.98,126.78 108.98,127.22 108.69,127.51 105.95,127.51 104,129.46 103.96,129.5 103.96,129.52 103.95,129.53
  IN2 w0.127: 103.95,129.53 99.92,133.55 98.2,133.55 97.13,132.48 95.71,132.48 95.48,132.71 95.48,135.68 97.21,137.41 97.21,138.34 99.5,140.62 99.5,143.61 99.98,144.09 99.98,147.98 100.25,148.25 100.91,148.92 105.49,148.92 105.83,149.25 105.83,149.58 106.1,149.85 JMINI.25
  BOTTOM w0.102: 109.25,126.42 108.85,126.42 v2(108.72,126.29)
PCIE_PTX_C_DRX_N0: length 108.7
  IN2 w0.127: v2(91.22,137.14) 91.22,137.31 91.08,137.45 89.46,137.45 86.32,134.31 86.32,128.44 82.51,124.63 72.87,124.63 70.46,122.22 64.62,122.22 60.71,118.31 44.25,118.31 39.61,113.67 39.61,113.3 v2(39.86,113.05)
  BOTTOM w0.102: v2(91.22,137.14) 91.22,137.37 91.37,137.52 91.63,137.52 92.06,137.95 92.06,138.62 92.57,139.13 93.84,139.13 94.3,139.58 99.64,139.58 101.58,137.64 101.58,137.43 CC4.2 ; v2(39.86,113.05) 39.59,112.78 39.59,104.58 35.59,100.58 35.59,93.7 38.24,91.04 38.24,86.79 38.35,86.69 UL1.14
PCIE_PTX_C_DRX_N1: length 9.6
  TOP w0.102: CC6.2 103.94,144.45 103.95,144.45 104.26,144.76 104.26,145 104.52,145.26 v4(105.52,145.26) 106.2,145.26 106.59,145.65 106.59,146.11 106.58,146.13 106.58,146.66 106.59,146.67 106.59,147.06 108.79,149.26 108.79,149.49 108.5,149.79 JMINI.31
PCIE_PTX_C_DRX_P0: length 108.6
  IN2 w0.127: v2(91.22,137.9) 91.03,137.7 89.35,137.7 86.06,134.41 86.06,128.55 82.4,124.89 72.77,124.89 70.35,122.48 64.51,122.48 60.6,118.57 44.14,118.57 39.35,113.78 39.35,113.3 v2(39.1,113.05)
  BOTTOM w0.102: v2(91.22,137.9) 91.39,137.73 91.54,137.73 91.85,138.04 91.85,138.71 92.48,139.34 93.75,139.34 94.21,139.8 99.73,139.8 101.67,137.86 CC3.2 ; v2(39.1,113.05) 39.37,112.78 39.37,104.67 35.37,100.67 35.37,93.61 38.03,90.96 38.03,86.79 37.95,86.71 UL1.13
PCIE_PTX_C_DRX_P1: length 9.6
  TOP w0.102: JMINI.33 109.3,149.79 109.01,149.49 109.01,149.17 106.81,146.97 v4(106.81,146.39) 106.81,145.56 106.29,145.04 105.79,145.04 105.78,145.03 105.25,145.03 105.24,145.04 104.61,145.04 104.48,144.91 104.48,144.75 CC5.2
PCIE_PTX_DRX_N0: length 12.3
  IN2 w0.102: 105.75,131.32 105.77,131.3 105.78,131.3 106.72,130.37 107.67,130.37 108.54,129.5 v2(108.54,129.28)
  IN2 w0.127: v2(102.86,135.82) 103.05,136.01 103.25,136.01 103.79,135.48 103.79,133.28 105.75,131.32
  BOTTOM w0.102: v2(102.86,135.82) 103.05,136.01 103.05,136.17 102.52,136.7 102.15,136.7 CC4.1 ; v2(108.54,129.28) 108.58,129.33 USOC1.AY6
PCIE_PTX_DRX_N1: length 20.7
  TOP w0.102: v2(103.98,142.43) 104.29,142.73 104.29,143.09 104,143.38 CC6.1
  IN2 w0.102: v2(107.46,129.03) 107.73,129.03 107.88,129.18 107.88,129.39 107.56,129.72 105.66,129.72 104.93,130.45 104.91,130.45 104.89,130.46
  IN2 w0.127: 104.89,130.46 101.5,133.86 101.5,136.6 104.23,139.33 104.23,142.18 v2(103.98,142.43)
  BOTTOM w0.102: v2(107.46,129.03) 107.54,129.1 USOC1.AV4
PCIE_PTX_DRX_P0: length 12.3
  IN2 w0.102: v2(109.04,128.83) 108.88,129.48 107.76,130.6 106.82,130.6 105.99,131.42 105.94,131.48 105.94,131.49 105.93,131.5
  IN2 w0.127: v2(103.42,136.41) 103.42,136.21 104.04,135.58 104.04,133.39 105.93,131.5
  BOTTOM w0.102: v2(103.42,136.41) 103.12,136.41 102.66,136.86 CC3.1 ; USOC1.AY7 v2(109.04,128.83)
PCIE_PTX_DRX_P1: length 20.7
  TOP w0.102: v2(104.74,142.43) 104.51,142.66 104.51,142.96 CC5.1
  IN2 w0.102: v2(107.93,128.56) 107.93,128.9 108.11,129.08 108.11,129.49 107.65,129.95 105.76,129.95 105.09,130.61 105.09,130.63 105.07,130.65
  IN2 w0.127: 105.07,130.65 101.76,133.96 101.76,136.49 104.49,139.22 104.49,142.18 v2(104.74,142.43)
  BOTTOM w0.102: USOC1.AV6 108.01,128.63 v2(107.93,128.56)
PCIE_RCOMPN: length 1.4
  TOP w0.254: RC13.2 110.04,124.83 v2(110.04,124.95)
  BOTTOM w0.254: v2(110.04,124.95) 109.79,124.95 USOC1.AP13
PCIE_RCOMPP: length 1.4
  TOP w0.254: RC13.1 110.57,124.07 v2(110.57,124.36)
  BOTTOM w0.254: v2(110.57,124.36) 110.43,124.22 USOC1.AP14
PCIE_WAKE#: length 188.2
  TOP w0.102: v2(189.51,58.9) 190.37,58.04 190.4,58.04 194.39,54.06 UE1.29
  BOTTOM w0.102: v2(189.51,58.9) 189.11,59.31 184.55,59.31 182.85,57.61 176.14,57.61 174.8,58.94 169.74,58.94 165.34,63.35 155.75,63.35 150.06,57.66 145.36,57.66 141.36,53.65 89.08,53.65 85.51,57.22 79.05,57.22 70.17,66.1 56.73,66.1 51.21,71.63 51.21,81.89 47.3,85.8 v1(46.32,85.8) 43.84,85.8 43.56,85.53 43.56,84.99 43.13,84.55 42.32,84.55 42.12,84.35 RL34.2 41.43,83.39 40.74,84.07 UL1.21
PCU_SMB_ALERT#: length 6.4
  BOTTOM w0.102: USOC1.BG11 113.91,130.08 114.12,130.3 114.31,130.3 114.31,130.3 114.33,130.3 115.01,130.99 115.01,132.02 116.29,133.29 v1(116.29,133.53) 116.67,133.91 116.67,134.65 RP68.2
PCU_SMB_CLK: length 10.1
  TOP w0.102: QC3.3 118.32,134.16 117.33,134.16 116.46,135.03 v1(116.2,135.03) 115.64,135.03 v2(115.6,134.99)
  BOTTOM w0.102: USOC1.BH10 113.61,130.68 113.61,130.82 113.87,131.08 113.87,131.65 115.6,133.37 v2(115.6,134.99) RP68.4
PCU_SMB_DATA: length 14.2
  TOP w0.102: v2(116.16,134.44) 117.63,132.97 118.7,132.97 118.97,133.24 119.94,133.24 v1(120.34,133.64) QC4.3
  BOTTOM w0.102: RP68.3 116.16,134.84 v2(116.16,134.44) 116.16,133.92 115.93,133.69 115.93,133.27 114.18,131.52 114.18,130.95 113.91,130.69 113.91,130.52 113.77,130.38 113.74,130.38 113.74,130.38 113.54,130.38 113.39,130.22 113.39,129.94 113.8,129.53 USOC1.BG12
PECI_KB9012: length 4.8
  TOP w0.102: UE1.118 179.99,56.8 179.9,56.72 RE43.1 178.45,56.25 177.36,56.25 v1(177.08,56.53)
PHASE1: length 7.5
  IN2 w1.016: 155.1,124.28 155.1,124.69 157.23,126.82 157.23,128.75 158.78,130.3
  vias: v1(156.1,120.74) v4(155.22,123.21) v4(155.65,122.4) v4(155.98,123.21) v4(156.42,122.4) v4(156.75,123.21) v4(157.18,122.4) v4(157.76,123.11) v4(158.14,122.35) v4(158.14,121.59) v4(158.14,120.83) v4(158.14,120.06) v4(158.93,121.94) v4(158.93,121.18) v4(158.93,120.42) v4(158.93,119.66) v4(159.31,131.04) v4(160,131.01)
PHASEG: length 21.3
  IN2 w1.016: 158.98,136.09 158.4,136.68 146.03,136.68 144.22,138.48 142.19,138.48 140.26,140.41 139.5,140.41
  vias: v1(132.88,140.76) v4(131.35,144.9) v4(131.35,144.14) v4(131.35,143.38) v4(132.11,144.9) v4(132.11,144.14) v4(132.11,143.38) v4(132.87,144.9) v4(132.87,144.14) v4(132.87,143.38) v4(133.63,144.9) v4(133.63,144.14) v4(133.63,143.38) v4(134.39,144.9) v4(134.39,144.14) v4(134.39,143.38) v4(137.9,140.64) v4(137.9,140) v4(159.98,135.4) v4(160.45,134.92)
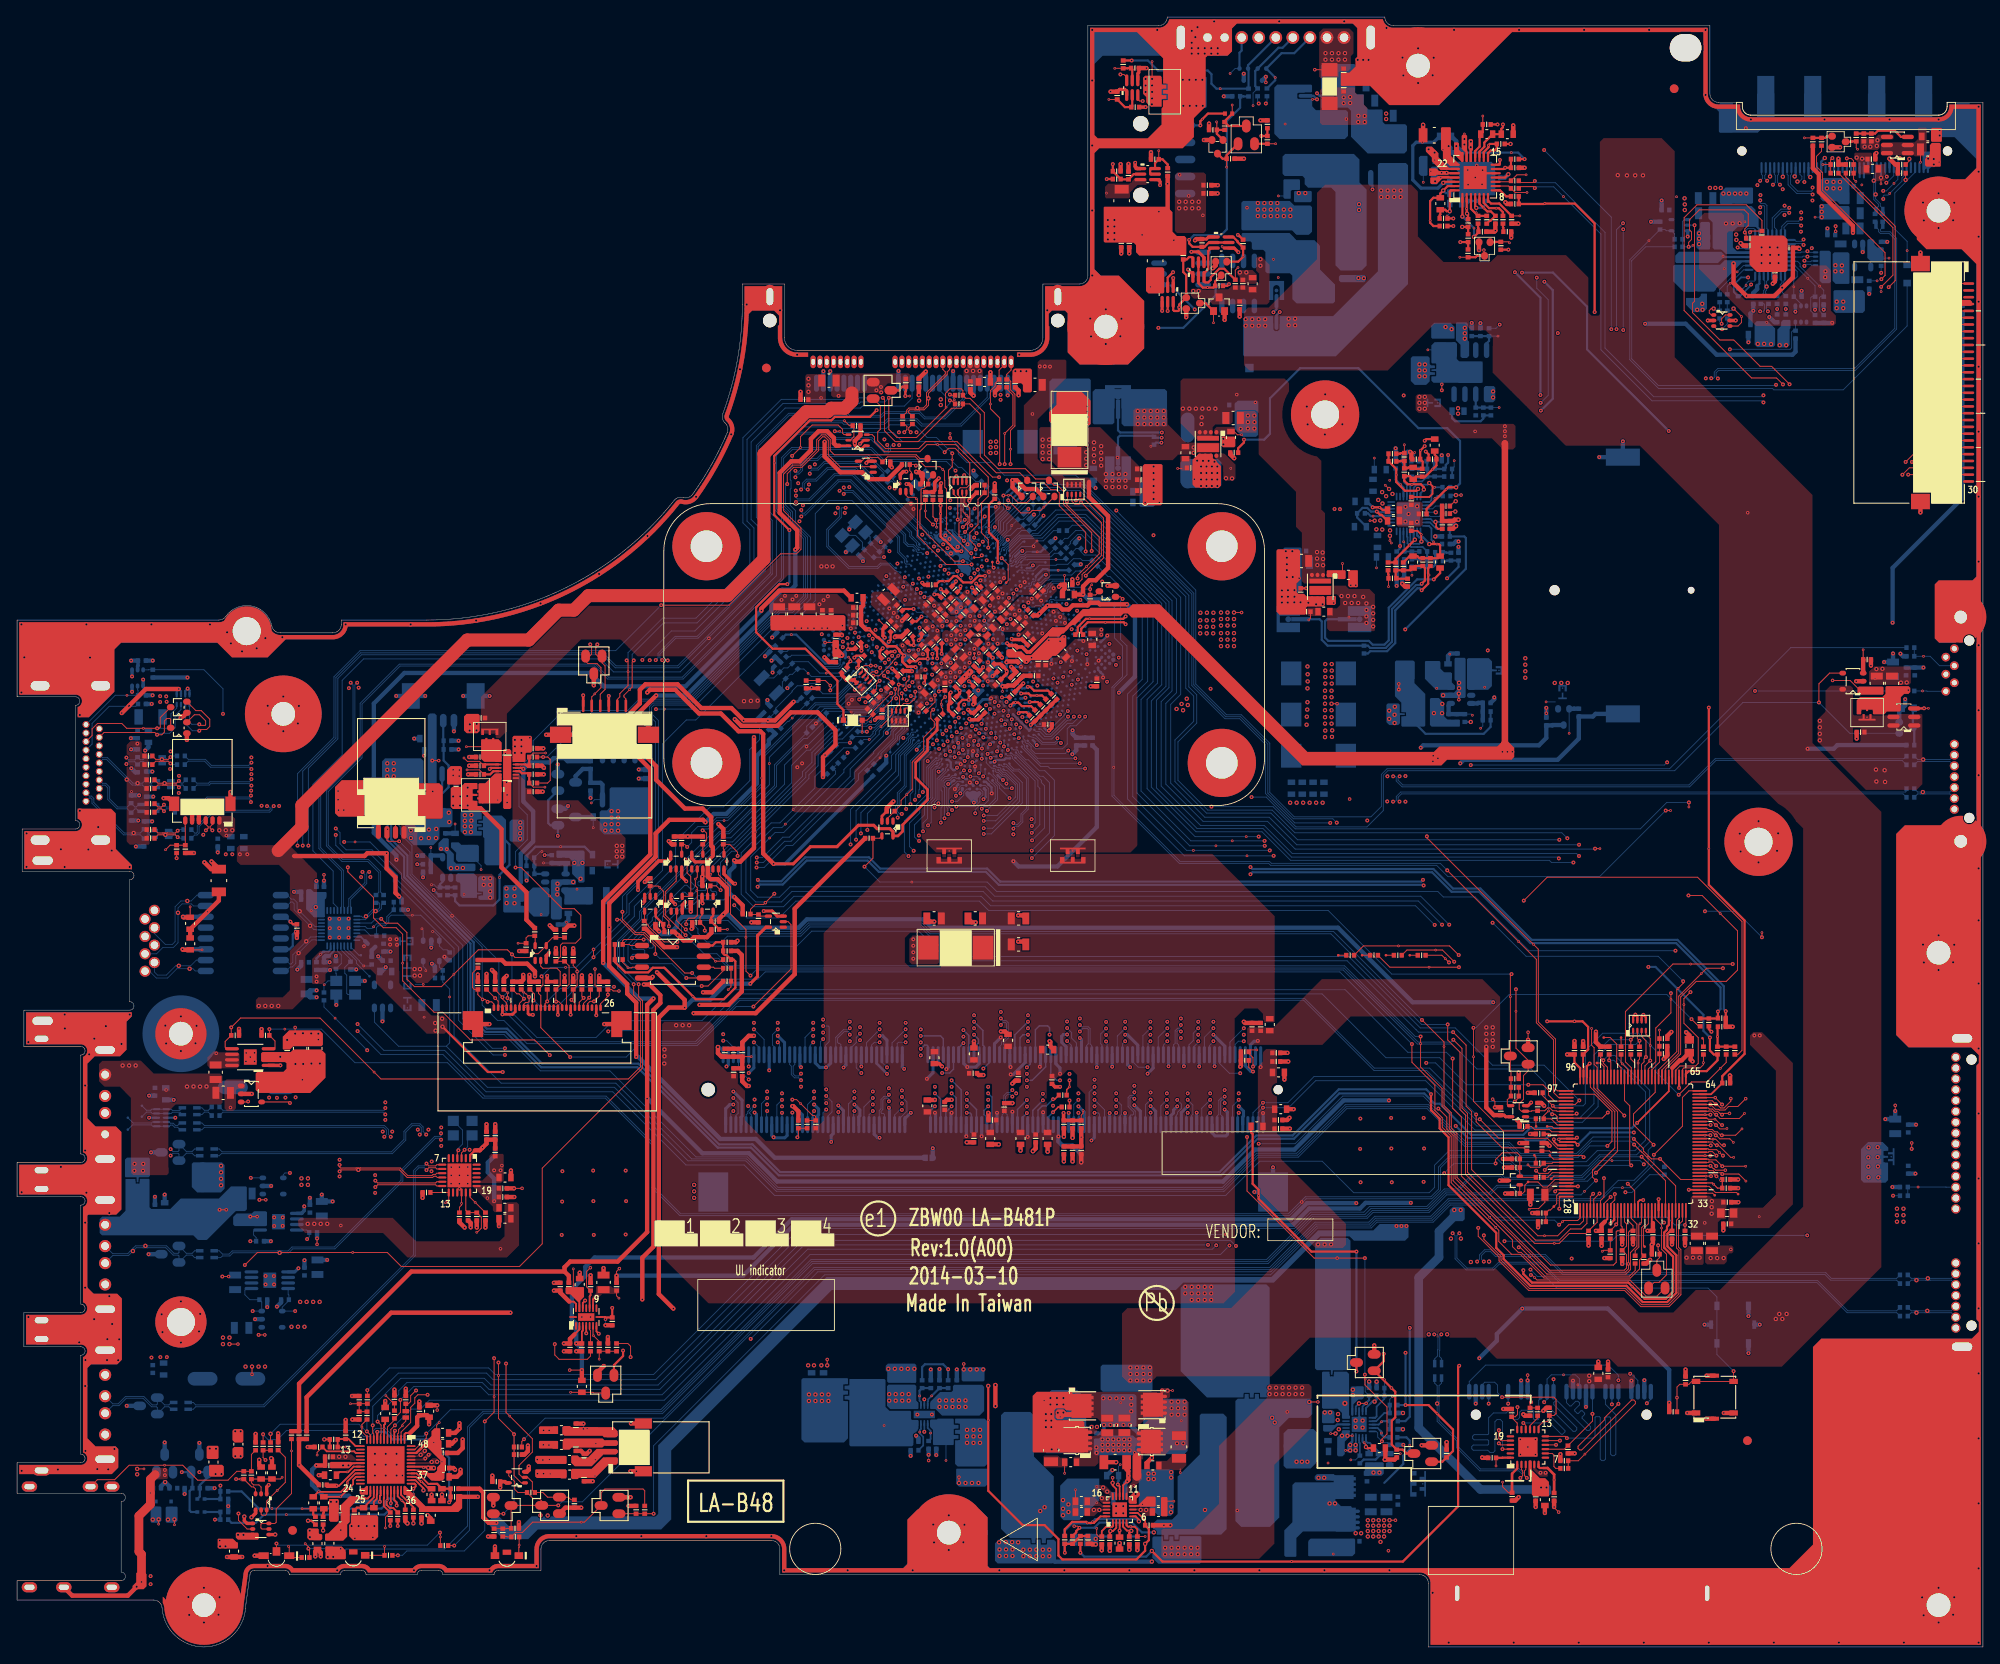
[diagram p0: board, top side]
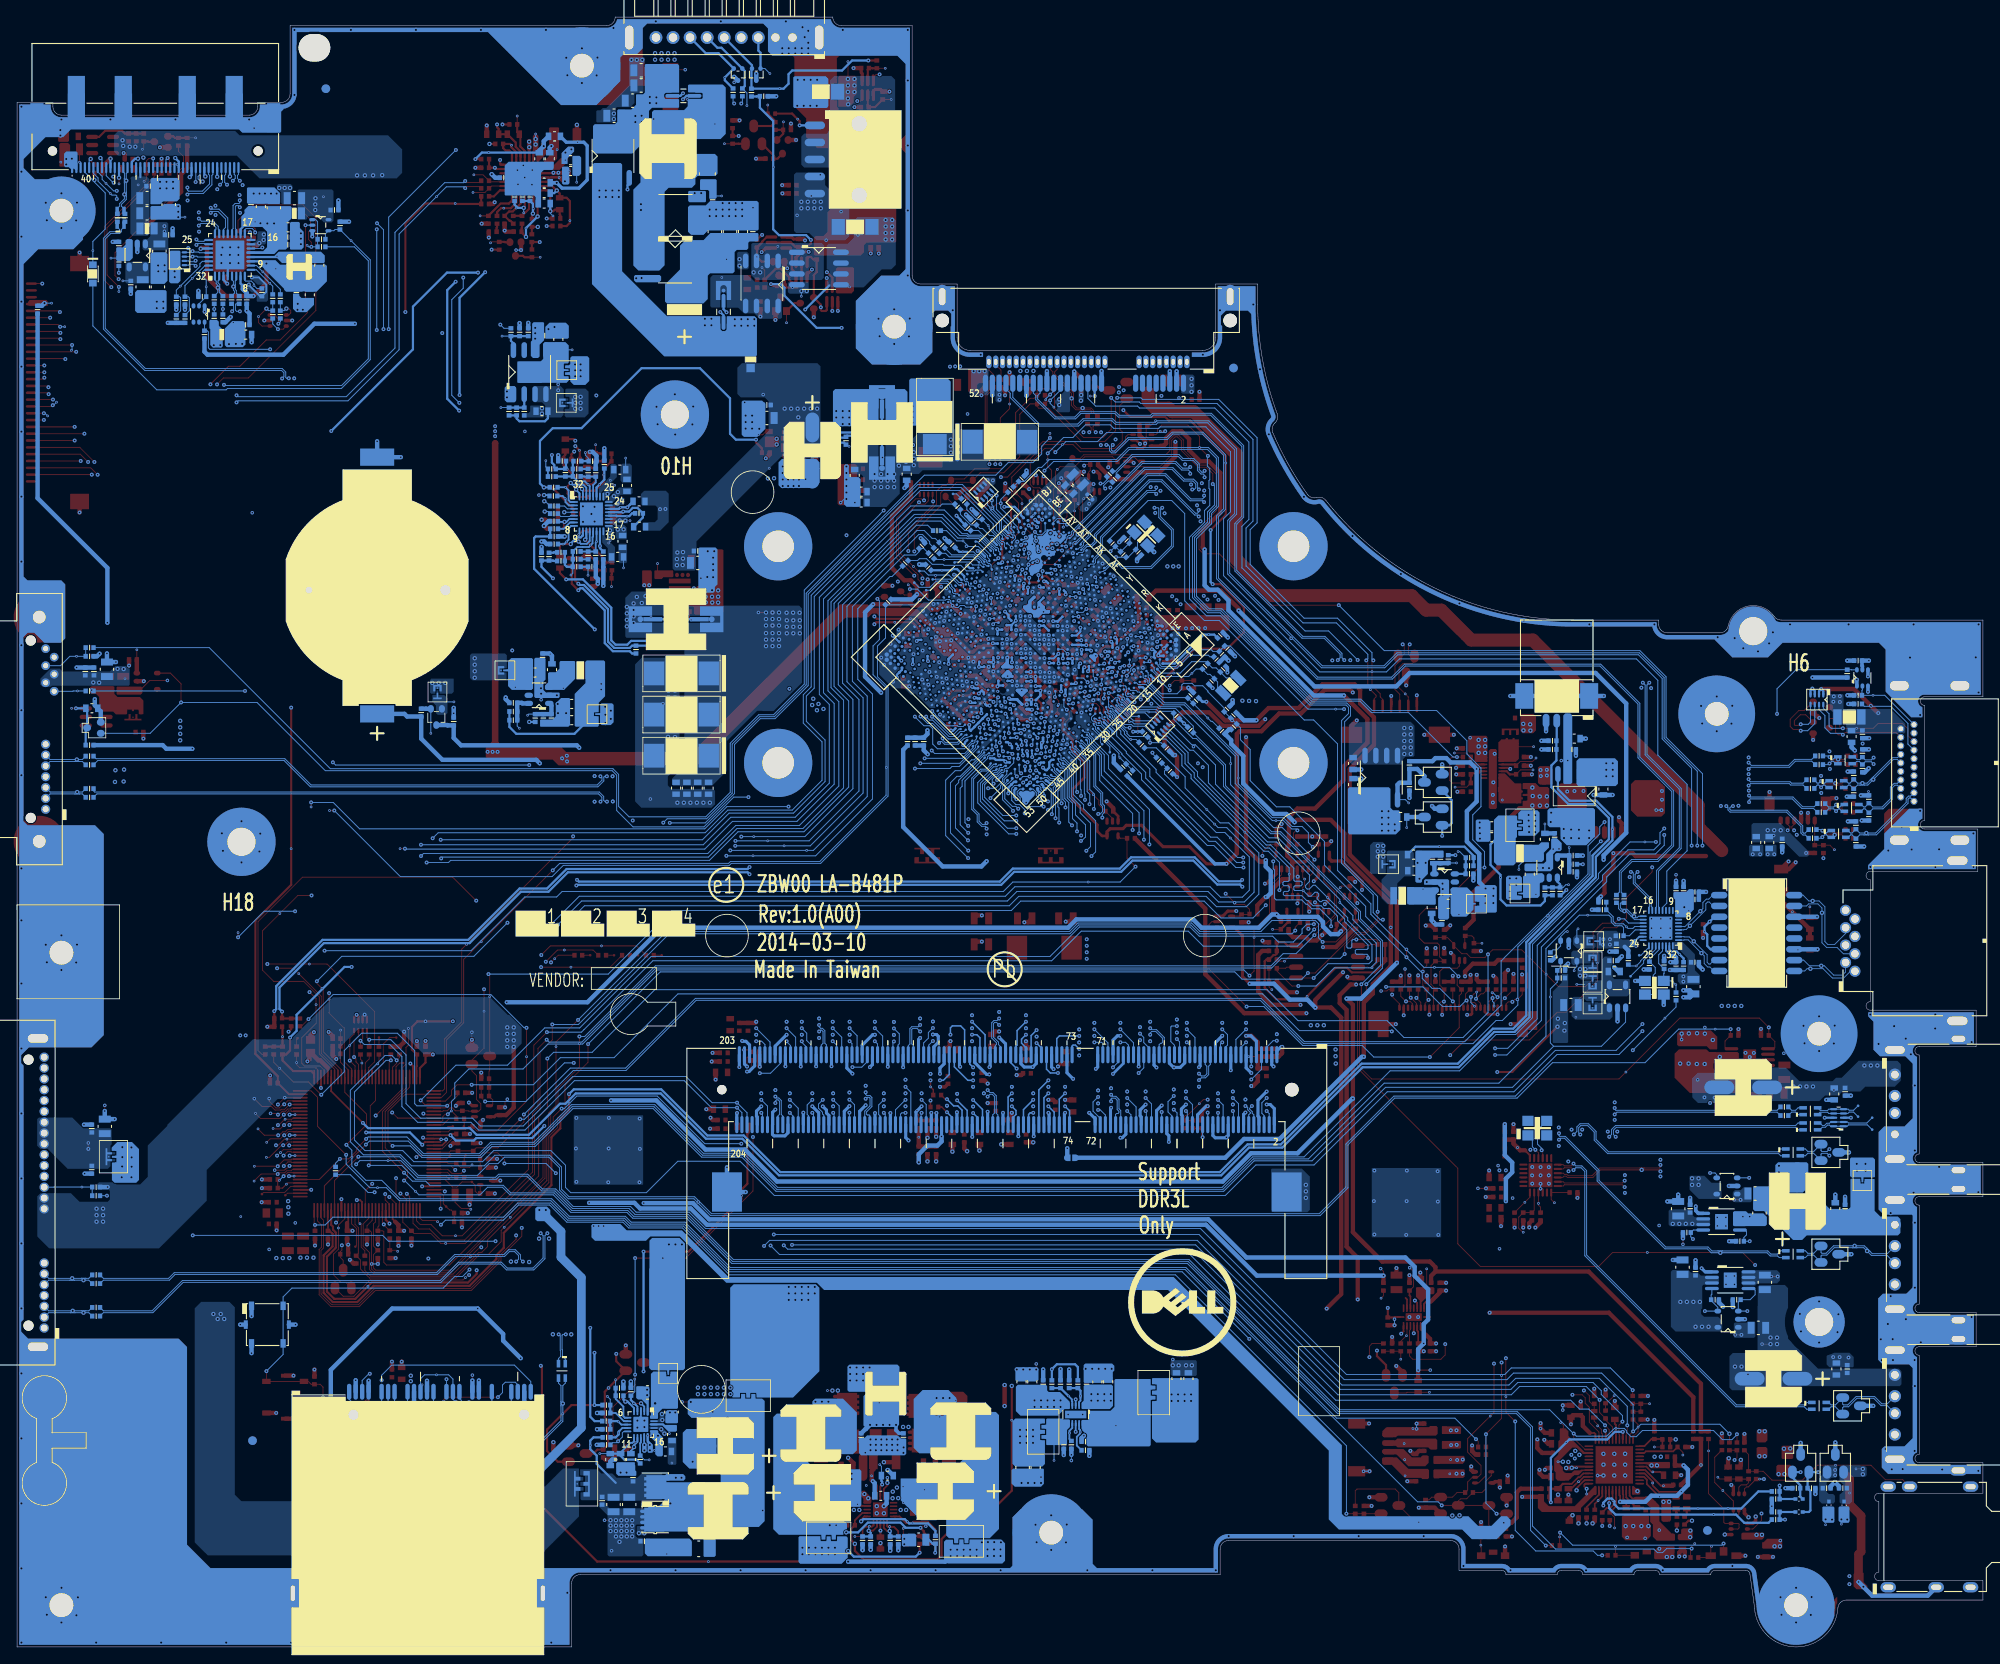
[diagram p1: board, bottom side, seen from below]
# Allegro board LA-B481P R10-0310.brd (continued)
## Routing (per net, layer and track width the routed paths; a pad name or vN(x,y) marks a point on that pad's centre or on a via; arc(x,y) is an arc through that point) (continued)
PLT_RST#: length 313.6
  TOP w0.102: RC20.2 CC11.1 62.77,83.18 62.02,82.44 UC5.4 61.07,81.28 60.48,81.28 60.05,80.85 58.36,80.85 v2(58,81.2) 57.47,81.74 54.05,81.74 v1(51.2,78.88) 49.74,77.42 46.58,77.42 45.69,78.31 45.69,83.77 44.6,84.86 43.18,84.86 v2(42.68,85.37) ; v2(168.25,68.98) 168.25,63.15 169.27,62.14 169.27,55.22 179.71,44.78 187.1,44.78 187.42,45.1 187.42,48.68 187.53,48.79 CE36.1 188.12,49.25 187.99,49.38 UE1.13
  IN2 w0.127: v2(73.28,115.72) 73.28,114.42 72.6,113.74 65.98,113.74 62.5,110.26 48.49,110.26 42.4,104.16 42.4,98.5 43.08,97.81 43.08,95.22 42.32,94.46 42.32,92.71 42.68,92.35 v2(42.68,85.37)
  BOTTOM w0.102: v2(58,81.2) 58,74.38 60.92,71.46 67.86,71.46 69.83,73.43 80.27,73.43 83.9,77.06 155.65,77.06 163,69.72 167.52,69.72 v2(168.25,68.98) ; UL1.19 41.52,84.87 42.02,85.37 v2(42.68,85.37) ; v2(73.28,115.72) 76.69,119.12 79.44,119.12 86.85,126.53 86.85,131.39 86.03,132.2 86.03,141.27 90.02,145.26 98.85,145.26 99.08,145.49 103.99,145.49 104.9,146.4 JMINI.22
PMC_ACIN: length 7
  TOP w0.102: v2(102.45,111.84) 100.3,109.7 RC21.2 99.61,108.66 DC1.2 v1(99.05,107.24)
  BOTTOM w0.102: v2(102.45,111.84) 101.95,111.84 USOC1.D20
PMC_BATLOW#: length 4
  TOP w0.102: RP65.2 103.53,110.23 103.91,110.61 104.61,110.61 v1(105.11,111.11) 105.26,111.27 v2(105.26,112)
  BOTTOM w0.102: USOC1.K26 105.64,111.91 105.56,112 v2(105.26,112)
PMC_CORE_PWROK: length 271.4
  TOP w0.102: RE18.1 v2(195.48,49.48) 195.48,49.63 195.59,49.73 UE1.32 ; UC7.2 90.36,85.04 90.71,84.69 90.71,79.49 v2(86.3,75.08) ; v2(61.47,78.63) 61.62,78.47 61.62,77.59 CC57.1 61.12,76.63 61.38,76.36 JDB1.12 61.38,72.6 v2(64.82,69.16)
  IN2 w0.127: v2(64.82,69.16) 73.04,60.95 73.04,49.06 v2(85.98,36.12)
  BOTTOM w0.102: v2(61.47,78.63) 62.52,79.68 v1(64.29,79.68) 65.51,79.68 71.73,85.9 71.73,87.13 75.64,91.04 75.64,105.89 78.44,108.68 79.54,108.68 88.22,117.36 CE31.1 CC16.1 90.24,116.73 90.43,116.91 92.64,116.91 94.59,114.96 96.27,114.96 96.46,115.15 USOC1.B7 ; v2(195.48,49.48) 194.29,49.48 193.37,50.39 173.37,50.39 171.72,52.04 167.88,52.04 165.87,50.04 159.3,50.04 158.62,49.35 152.31,49.35 146.95,43.99 93.86,43.99 v2(85.98,36.12) ; v2(86.3,75.08) 84.28,75.08 79.71,70.51 72.74,70.51 71.39,69.16 v2(64.82,69.16)
PMC_PCIE_WAKE#: length 1.6
  TOP w0.102: v2(104.6,109.9) 104.42,110.08 104.14,110.08 104.03,109.97 RP65.1
  BOTTOM w0.102: 104.35,110.48 104.35,110.16 v2(104.6,109.9)
PMC_PLTRST#: length 78.6
  TOP w0.102: v2(102.93,112.32) 102.93,111.66 102.59,111.33 102.59,111.1 CC13.1 ; JDB1.17 63.88,75.26 63.48,75.66 v2(63.17,75.66) 63.15,75.69 CC51.1 63.66,77.59 63.66,79.2 63.27,79.58 61.62,79.58 61.37,79.83 UC5.2
  IN2 w0.127: v2(102.93,112.32) 102.32,112.32 101.27,111.28 101.07,111.28 99.37,109.57 99.1,109.57 98.13,108.61 96.69,108.61 93.74,105.66 92.25,105.66 90.08,103.49 90.08,100.7 82.25,92.87 82.25,91.73 82.87,91.1 82.87,86.46 83.19,86.14 83.19,84.17 82.81,83.79 82.81,81.77 74.77,73.73 68.87,73.73 68.24,73.1 65.13,73.1 64.09,74.14 64.09,74.75 v2(63.17,75.66)
  BOTTOM w0.102: USOC1.F20 102.78,112.48 v2(102.93,112.32)
PMC_PWRBTN#: length 34.3
  TOP w0.102: U63.4 82.85,93.51 82.77,93.59 R6.2 83.52,94.1 84.45,93.18 v2(84.45,92.75)
  IN2 w0.127: v2(84.45,92.75) 84.41,92.78 84.41,92.94 91.79,100.32 91.79,102.3 93.52,104.04 95.18,104.04 96.13,104.99 96.13,105.28 97.99,107.14 98.38,107.14 100.89,109.65 103.56,109.65 104.76,110.85 v2(104.76,111.49)
  BOTTOM w0.102: v2(104.76,111.49) 105.05,111.49 105.13,111.41 USOC1.J26
PMC_RSTBTN#: length 7.1
  TOP w0.102: v3(116.11,133.51) 115.54,134.08 v2(115.11,134.08)
  BOTTOM w0.102: RC24.1 115.11,134.54 v2(115.11,134.08) 115.11,133.54 113.67,132.09 113.67,131.82 113.19,131.34 113.19,131.06 113.02,130.89 USOC1.BG9
PMC_SLP_S3#: length 35.9
  TOP w0.102: U54.2 80.93,88.91 R1024.1 81.94,89.24 v2(82.45,88.73)
  BOTTOM w0.102: USOC1.D22 102.48,110.51 102.44,110.47 102.47,110.32 102.45,110.2 102.4,110.12 102.28,110.01 102.06,110.01 101.96,109.9 101.96,109.7 101.6,109.33 101.6,109.16 100.58,108.15 99.8,108.15 99.6,107.95 98.23,107.95 96.73,106.45 95.76,106.45 93.88,104.57 93.88,103.33 92.8,102.25 92.8,101.82 v1(86.51,95.53) 84.27,93.29 83.75,93.29 82.45,92 v2(82.45,88.73)
PMC_SLP_S4#: length 50.6
  TOP w0.102: U57.2 R1033.1 75.14,89.22 v1(75.33,89.02) 75.78,88.57 75.78,85.66 76.39,85.05 v2(76.39,84.5)
  IN2 w0.127: v2(103.03,111.21) 102.39,110.56 101.04,110.56 98.32,107.85 97,107.85 94.06,104.9 92.57,104.9 90.93,103.26 90.93,100.47 83.18,92.72 v2(83.18,92.11)
  BOTTOM w0.102: USOC1.F22 102.95,111.55 103.03,111.48 v2(103.03,111.21) ; v2(76.39,84.5) 76.39,85.22 77.72,86.55 78.65,86.55 79.18,87.08 79.33,87.08 79.84,87.59 82.83,87.59 83.04,87.79 83.04,91.1 83.18,91.24 v2(83.18,92.11)
PMC_SUSCLK: length 1.3
  TOP w0.102: T103.1 103.78,111.72 v2(103.69,111.81)
  BOTTOM w0.102: v2(103.69,111.81) 103.71,111.78 103.96,111.78 USOC1.G24
PS_ID: length 209.2
  TOP w0.102: v2(176,46.86) 176.15,46.86 v1(177.28,45.73) 179.3,43.71 188.56,43.71 189.08,44.23 189.08,46.23 189.84,46.99 189.84,49.59 189.19,50.24 UE1.16
  TOP w0.254: v2(145.82,177.16) PR1.2 PR4.1
  IN2 w0.127: v2(178.97,175.51) 173.8,180.68 162.36,180.68 159.6,183.44 151.31,183.44 145.82,177.95 v2(145.82,177.16) ; v2(176,46.86) 176,49.68 169.32,56.36 169.32,65.56 167.2,67.68 167.2,80.51 169.98,83.3 172.68,83.3 174.25,84.86 174.25,87.61 176.76,90.12 176.76,106.86 175.96,107.66 175.96,141.23 186.85,152.12 v2(186.85,154.51)
  BOTTOM w0.102: v2(186.85,154.51) 186.85,167.64 v2(178.97,175.51)
PSID: length 5.5
  TOP w0.254: v2(138.68,178.4) 138.68,178.9 v1(138.92,179.13) 139.56,179.78 PL3.1
  BOTTOM w0.254: PJPDC1.1 v2(138.68,178.4)
PSID-1: length 3.4
  TOP w0.102: PR5.2 140.61,178.64 140.58,178.67 v1(140.58,178.81)
  TOP w0.254: PQ2.2 140.61,177.41 PR5.2 141.53,177.87 PR2.1
PSID-2: length 4.6
  TOP w0.102: PR3.2 v1(141.76,173.5)
  TOP w0.254: PQ2.1 141.28,174.5 PR3.2 141.76,174.91 PQ1.2
PSID-3: length 2.5
  TOP w0.102: PR1.1 v1(147.5,176.24)
  TOP w0.254: PQ1.3 145.82,176.24 PR1.1
PWR_OTP#: length 105.5
  TOP w0.102: UE1.104 182.65,62.4 v2(182.78,62.53)
  TOP w0.254: PR114.1 v2(124.62,11.05) ; v2(169.02,32.97) 168.89,32.84 168.89,16.48 162.42,10.01 v1(149.38,10.01) 134.24,10.01 v4(133,11.25)
  IN2 w0.127: v2(182.78,62.53) 182.78,60.77 184.03,59.52 184.03,48.66 184.76,47.93 184.76,45.69 172.04,32.97 v2(169.02,32.97)
  BOTTOM w0.254: v2(124.62,11.05) 125.07,10.59 132.34,10.59 v4(133,11.25)
PWR_PWM_LED#: length 191.6
  TOP w0.102: RD14.1 34.27,11.4 v2(34.14,11.53) 34.14,11.75 v1(33.77,12.11) ; v2(185.05,55.6) 187.58,58.13 187.58,62.77 184.79,65.56 UE1.92
  BOTTOM w0.102: v2(185.05,55.6) 184.06,54.61 182.5,54.61 182.02,54.13 173.42,54.13 172.53,53.24 167.46,53.24 165.4,51.18 158.83,51.18 158.14,50.49 151.84,50.49 146.52,45.18 93.13,45.18 75.53,27.58 54.58,27.58 52.78,25.79 52.78,14.17 50.09,11.48 38.56,11.48 38.13,11.05 37.57,11.05 37.09,11.53 v2(34.14,11.53)
PWR_SRC_ON: length 6.5
  TOP w0.254: RX3.1 RX2.2 CX4.2 217.76,177.44 218.09,177.77 220.07,177.77 220.8,177.05 QX2.3
RING2: length 22.9
  TOP w0.102: v4(18.44,14.96) v1(18.44,14.32)
  IN2 w1.016: 18.06,13.79 19.99,13.79 23.75,17.55 29.57,17.55 34.55,22.53 36.71,22.53
  vias: v4(17.68,14.93) v4(37.75,22.3) v4(38.48,22.3)
RING2_R: length 32.1
  TOP w0.508: v4(14.01,7.06) 14.01,7.05 12.98,6.02 6.46,6.02 JHP.6
  TOP w1.016: 16.18,20.22 15.62,19.66 v1(15.62,18.04) 15.62,16.71 14.28,15.36 14.28,11.17 14.58,10.87 14.58,8.56
  BOTTOM w0.508: 14.01,7.05 12.98,6.02 6.46,6.02 JHP.6 ; 14.01,7.05 v2(14.58,7.62) ; 14.01,7.05 v4(14.01,7.06)
  vias: v2(17.33,20.75) v2(17.33,20.14)
RREF: length 5.5
  TOP w0.102: RR1.1 174.81,18.08 174.11,18.78 v1(174.11,19.33)
  TOP w0.254: 175.21,20.32 175.82,20.92 UR1.1
  TOP w0.305: RR1.1 175.21,20.32
RTC_RST#: length 12.3
  BOTTOM w0.102: R1089.2 90.32,108.53 90.46,108.53 v1(90.85,108.91) RC35.2 CC22.1 93.23,111.3 96.14,111.3 97.87,113.03 97.87,113.28 98.12,113.53 98.27,113.53 98.43,113.69 98.43,114.13 98.63,114.32
RTC_TEST#: length 62.9
  TOP w0.102: v2(67.56,80.87) v3(67.56,81.79) ; JDB1.13 61.88,75.44 v2(62.13,75.69) CC64.1
  BOTTOM w0.102: v2(62.13,75.69) 63.66,77.21 64.54,77.21 65.71,78.38 65.71,79.02 v2(67.56,80.87) 72.34,85.65 72.34,86.83 77.16,91.65 77.16,94.43 81.23,98.5 82.81,98.5 85.88,101.57 85.88,105.23 87.02,106.37 87.02,107.78 R1088.2 88.14,108.89 RC34.2 CC20.2 88.92,110.07 90.83,111.99 90.83,112.09 91.44,112.7 92.41,112.7 92.69,112.98 93.7,112.98 93.89,112.79 93.89,112.3 94.44,111.76 96.31,111.76 97.67,113.11 97.67,113.52 97.84,113.69 97.84,114.22 USOC1.C11
RTC_VOUT: length 2.2
  TOP w0.102: 65.19,42.11 v1(65.19,44.33)
RUNPWROK: length 4.9
  TOP w0.102: T216.1 201.51,53.29 199.04,53.29 198.32,54 UE1.36
SATA_LED#_SOC: length 14.2
  TOP w0.102: v2(110.85,127.3) 109.83,127.3 v1(105.93,131.21) 105.82,131.32 105.82,133.3 105.95,133.42 105.95,135.71 106.07,135.84 106.28,135.84 RC18.2 106.79,136.85 QC2.3
  BOTTOM w0.102: v2(110.85,127.3) 111.2,127.3 USOC1.AY12
SATA_PRX_DTX_N0: length 6
  BOTTOM w0.102: CS109.1 221.99,43 v4(222.61,43) 223.66,43 223.68,42.99 224.21,42.99 224.22,43 226.69,43 JHDD.5
SATA_PRX_DTX_N0_C: length 179.7
  IN2 w0.102: v2(112.2,125.88) 112.12,125.8 112.12,125.64 112.26,125.5 112.42,125.5 113.44,126.52 113.44,126.58 116.39,129.53 120.07,129.53 120.08,129.54 120.09,129.54
  IN2 w0.127: 120.09,129.54 127.67,129.54 134.88,122.33 134.88,120.24 146.51,108.61 146.51,99.52 153.4,92.63 153.4,52.04 158.93,46.51 171,46.51 171.69,45.82 171.69,45.4 v2(171.9,45.18)
  BOTTOM w0.102: CS109.2 220.28,43 212.55,43 211.89,43.66 181.16,43.66 179.02,45.79 173.26,45.79 172.7,46.35 172.09,46.35 171.62,45.88 171.62,45.47 v2(171.9,45.18) ; USOC1.AV16 112.28,125.81 v2(112.2,125.88)
SATA_PRX_DTX_N1: length 5.1
  BOTTOM w0.102: JODD.5 226.52,103.83 223.68,103.83 223.66,103.81 223.13,103.81 223.12,103.83 222.76,103.83 CS14.1
SATA_PRX_DTX_N1_C: length 145.9
  IN2 w0.102: v2(113.06,126.69) 112.97,126.6 112.85,126.6 112.58,126.87 112.58,127.17 112.09,127.66 111.76,127.66 111.33,128.09 111.33,128.8 110.59,129.54 110.59,130.79 109.84,131.54 109.84,132.77 110.46,133.4 111.58,133.4 112.12,133.93 112.14,133.93 112.15,133.95
  IN2 w0.127: v2(161.28,102.08) 161.51,102.08 161.63,102.21 161.63,102.43 161.4,102.66 151.43,102.66 148.69,105.4 148.69,109.55 144.83,113.41 144.83,122.2 142.7,124.33 136,124.33 127.66,132.66 121.97,132.66 120.83,133.8 119.51,133.8 117.61,135.71 115.17,135.71 114.31,134.84 113.05,134.84 112.15,133.95
  BOTTOM w0.102: CS14.2 220.94,103.93 199.11,103.93 196.03,100.85 162.32,100.85 161.63,101.54 161.63,101.98 161.54,102.08 v2(161.28,102.08) ; 113.28,126.21 113.13,126.21 113.06,126.29 v2(113.06,126.69)
SATA_PRX_DTX_P0: length 6
  BOTTOM w0.102: JHDD.6 226.69,43.22 v4(223.94,43.22) 222.89,43.22 222.87,43.23 222.34,43.23 222.33,43.22 221.99,43.22 CS108.1
SATA_PRX_DTX_P0_C: length 179.7
  IN2 w0.102: 120.09,129.28 120.08,129.28 120.07,129.3 116.48,129.3 113.67,126.48 113.67,126.42 112.52,125.27 112.16,125.27 112.01,125.42 111.85,125.42 v2(111.77,125.35)
  IN2 w0.127: 120.09,129.28 127.56,129.28 134.62,122.22 134.62,120.13 146.25,108.5 146.25,99.41 153.14,92.52 153.14,51.93 158.82,46.25 170.9,46.25 171.44,45.71 171.44,45.5 v2(171.12,45.18)
  BOTTOM w0.102: USOC1.AU16 v2(111.77,125.35) ; v2(171.12,45.18) 171.4,45.47 171.4,45.97 172,46.57 172.79,46.57 173.35,46.01 179.11,46.01 181.25,43.88 211.98,43.88 212.64,43.22 220.28,43.22 CS108.2
SATA_PRX_DTX_P1: length 5.1
  BOTTOM w0.102: JODD.6 226.52,104.04 v4(223.4,104.04) 222.76,104.04 CS15.1
SATA_PRX_DTX_P1_C: length 145.9
  IN2 w0.102: v2(112.59,126.32) 112.59,126.54 112.35,126.78 112.35,127.08 112,127.43 111.67,127.43 111.1,127.99 111.1,128.7 110.36,129.44 110.36,130.69 109.61,131.45 109.61,132.87 110.37,133.63 111.49,133.63 111.96,134.1 111.96,134.12 111.97,134.13
  IN2 w0.127: 111.97,134.13 112.94,135.1 114.2,135.1 115.07,135.96 117.71,135.96 119.62,134.06 120.93,134.06 122.07,132.92 127.77,132.92 136.1,124.58 142.81,124.58 145.09,122.31 145.09,113.52 148.95,109.66 148.95,105.51 151.54,102.92 161.51,102.92 161.89,102.54 161.89,102.22 v2(162.03,102.08)
  BOTTOM w0.102: v2(112.59,126.32) 112.59,126.32 112.59,126.17 112.78,125.98 USOC1.AY16 ; CS15.2 221.14,104.14 199.02,104.14 195.94,101.06 162.41,101.06 161.85,101.63 161.85,101.9 v2(162.03,102.08)
SATA_PTX_DRX_N0: length 6
  BOTTOM w0.102: JHDD.3 226.69,39.41 v4(223.88,39.41) 222.89,39.41 222.87,39.42 222.34,39.42 222.33,39.41 221.99,39.41 CS106.1
SATA_PTX_DRX_N0_C: length 182.5
  IN2 w0.127: v2(169.03,48.51) 168.77,48.24 168.77,47.45 168.46,47.14 159.28,47.14 153.98,52.44 153.98,92.91 147.02,99.87 147.02,108.88 135.41,120.49 135.41,122.65 127,131.06 115.82,131.06 115.03,131.85 113.36,131.85 112.45,130.94 v2(112.45,130.59)
  BOTTOM w0.102: USOC1.BG7 112.19,130.86 v2(112.45,130.59) ; CS106.2 220.28,39.41 214.57,39.41 211.01,42.96 180.81,42.96 178.67,45.11 173.64,45.11 172.95,44.42 169.93,44.42 168.75,45.6 168.75,48.22 v2(169.03,48.51)
SATA_PTX_DRX_N1: length 5.1
  BOTTOM w0.102: JODD.3 226.52,100.23 v4(223.36,100.23) 222.76,100.23 CS9.1
SATA_PTX_DRX_N1_C: length 138.6
  IN2 w0.102: 112.95,133.15 112.94,133.13 112.92,133.13 111.46,131.67 111.46,131.29 111.74,131.01 111.74,129.85 112,129.58 112.38,129.58 112.46,129.66 112.46,129.78 v2(112.17,130.07)
  IN2 w0.127: 112.95,133.15 113.16,133.35 113.56,133.35 114.28,132.64 117.83,132.64 118.62,131.85 127.31,131.85 135.74,123.41 142.44,123.41 143.94,121.91 143.94,113.08 147.88,109.14 147.88,104.82 152.51,100.2 161.22,100.2 161.63,99.79 161.63,99.27 161.47,99.11 v2(161.27,99.11)
  BOTTOM w0.102: v2(112.17,130.07) 112.42,129.82 USOC1.BF10 ; v2(161.27,99.11) 161.49,99.11 161.65,99.27 161.65,99.72 162.16,100.23 221.3,100.23 221.44,100.37 CS9.2
SATA_PTX_DRX_P0: length 6
  BOTTOM w0.102: JHDD.2 226.69,39.19 224.16,39.19 224.15,39.18 223.61,39.18 223.6,39.19 v4(222.61,39.19) 221.99,39.19 CS105.1
SATA_PTX_DRX_P0_C: length 182.5
  IN2 w0.127: v2(111.84,131.49) 111.84,131.49 112.64,131.49 113.26,132.11 115.14,132.11 115.93,131.32 127.11,131.32 135.67,122.76 135.67,120.59 147.28,108.99 147.28,99.98 154.23,93.02 154.23,52.55 159.39,47.39 168.35,47.39 168.51,47.55 168.51,48.24 v2(168.25,48.51)
  BOTTOM w0.102: v2(111.84,131.49) 111.5,131.15 111.46,131.15 ; CS105.2 220.28,39.19 214.48,39.19 210.93,42.75 180.72,42.75 178.58,44.89 173.73,44.89 173.04,44.21 169.84,44.21 168.53,45.51 168.53,48.22 v2(168.25,48.51)
SATA_PTX_DRX_P1: length 5.1
  BOTTOM w0.102: CS8.1 222.76,100.02 223.08,100.02 223.09,100 223.62,100 223.64,100.02 226.52,100.02 JODD.2
SATA_PTX_DRX_P1_C: length 138.6
  IN2 w0.102: v2(112.73,129.21) 112.59,129.35 111.91,129.35 111.51,129.75 111.51,130.91 111.23,131.19 111.23,131.77 112.75,133.29 112.75,133.31 112.77,133.33
  IN2 w0.127: v2(162.02,99.11) 161.89,99.24 161.89,99.89 161.32,100.46 152.61,100.46 148.14,104.93 148.14,109.25 144.2,113.19 144.2,122.02 142.55,123.67 135.85,123.67 127.41,132.11 118.72,132.11 117.94,132.89 114.38,132.89 113.67,133.61 113.05,133.61 112.77,133.33
  BOTTOM w0.102: v2(112.73,129.21) 112.62,129.32 USOC1.BD10 ; CS8.2 221.04,100.02 162.25,100.02 161.86,99.63 161.86,99.27 v2(162.02,99.11)
SATA_RCOMPN: length 1.4
  TOP w0.254: RC12.1 112.28,123.85 v2(111.92,124.21)
  BOTTOM w0.254: 111.96,123.51 111.92,123.55 v2(111.92,124.21)
SATA_RCOMPP: length 1.4
  TOP w0.254: RC12.2 112.79,124.28 v2(112.4,124.67)
  BOTTOM w0.254: USOC1.AU18 112.46,124.33 112.4,124.39 v2(112.4,124.67)
SD3_RCOMP: length 6.6
  BOTTOM w0.102: USOC1.BF26 118.34,124.38 118.75,124.38 118.9,124.53 118.9,124.81 118.98,124.89 119.23,124.89 119.4,125.06 119.4,125.41
  BOTTOM w0.254: RC59.1 v1(122.01,126.24) 120.89,126.24 120.76,126.37 120.23,126.37 119.4,125.54 119.4,125.41
SD_CD#: length 15.9
  TOP w0.102: UR1.13 178.32,25.86 178.87,26.41 179.38,26.41 179.58,26.62 CR9.1 180.11,27.13 180.37,27.38 180.37,29.03 180.11,29.28 v2(174.04,29.28)
  BOTTOM w0.102: JREAD.20 171.72,30.74 172.01,31.04 173.18,31.04 173.51,30.71 173.51,29.82 v2(174.04,29.28)
SD_CMD: length 25.7
  TOP w0.102: v2(175.85,28.12) 175.85,27.25 175.58,26.99 CR11.1 175.16,26.9 175.82,26.24 UR1.18
  IN2 w0.127: v2(175.85,28.12) 183.19,28.12 183.37,28.29 183.37,30.77 183.55,30.96 183.82,30.96 184,30.77 184,28.68 184.19,28.5 184.45,28.5 184.64,28.68 184.64,30.93 184.82,31.11 185.09,31.11 185.27,30.93 185.27,28.7 185.53,28.45 v2(186.92,28.45)
  BOTTOM w0.102: v2(186.92,28.45) JREAD.6
SD_D0: length 26.1
  TOP w0.102: UR1.11 v2(180.83,24.19)
  IN2 w0.127: v2(174.76,28.52) 174.76,27.96 175.4,27.32 175.86,27.32 176.28,27.73 177.98,27.73 178.49,27.23 184.13,27.23 184.33,27.03 184.33,26.74 184.13,26.54 183.76,26.54 183.63,26.41 183.63,24.77 183.44,24.59 183.18,24.59 183,24.77 183,26.41 182.87,26.54 182.49,26.54 182.36,26.41 182.36,25.25 182.17,25.07 181.91,25.07 181.73,25.25 181.73,26.26 181.47,26.52 181.08,26.52 180.83,26.26 v2(180.83,24.19)
  BOTTOM w0.102: JREAD.18 v2(174.76,28.52)
SD_D1: length 25.6
  TOP w0.102: UR1.10 v2(180.37,23.69)
  IN2 w0.127: v2(172.48,28.52) 171.96,28.01 171.96,23.91 172.15,23.72 172.41,23.72 172.6,23.91 172.6,27.62 172.78,27.81 173.05,27.81 173.23,27.62 173.23,25.13 173.49,24.88 174.01,24.88 175.87,26.74 179.05,26.74 180.37,25.42 v2(180.37,23.69)
  BOTTOM w0.102: JREAD.19 v2(172.48,28.52)
SD_D2: length 26.2
  TOP w0.102: v2(173.66,23.87) 173.85,23.69 UR1.21
  IN2 w0.127: v2(173.66,23.87) 173.66,22.76 175.91,20.51 177.64,20.51 178.21,19.94 182.38,19.94 v2(191.01,28.57)
  BOTTOM w0.102: v2(191.01,28.57) 191.48,29.04 JREAD.1
SERIRQ: length 219.3
  TOP w0.102: UE1.3 183.99,49.67 183.33,49.01 182.06,49.01 180.75,47.7 177.96,47.7 169.98,55.67 169.98,62.56 169.35,63.19 169.35,70.18 v2(168.33,71.19) ; U64.4 96.93,142.14 96.75,142.32 96.75,142.75 96.23,143.27 93.18,143.27 91.82,141.9 v1(91.82,140.63) v2(90.83,139.65) ; v2(70.32,85.27) 70.68,85.27 72.43,83.51 73.44,83.51 74.81,82.14 v2(74.81,81.24)
  BOTTOM w0.102: v2(90.83,139.65) 90.9,139.58 90.9,138.44 90.61,138.16 90.61,136.85 90.71,136.76 90.71,135.84 90.61,135.74 90.61,133.85 91.24,133.22 91.24,131.86 92.99,130.11 92.99,122.89 91.01,120.9 89.36,120.9 78.9,110.44 74.64,110.44 74.35,110.14 74.35,109.44 75.16,108.63 75.16,91.88 71.47,88.19 71.47,86.1 70.63,85.27 v2(70.32,85.27) ; v2(168.33,71.19) 168.05,70.91 164.21,70.91 155.52,79.6 83.37,79.6 82.23,80.74 75.3,80.74 v2(74.81,81.24)
SIO_SLP_S0#: length 2.2
  TOP w0.102: UE1.89 185.99,68.04 185.56,68.46 T196.1
SIO_SLP_S3#: length 134.7
  TOP w0.102: v2(167.67,72.98) 167.67,71.17 169.12,69.72 169.12,62.99 169.75,62.35 169.75,55.42 177.85,47.32 v1(180.17,47.32) 180.75,47.32 181.92,48.49 183.87,48.49 CE27.1 185.19,49.8 UE1.6 ; v2(80.6,84) 80.6,84.39 R13.2 80.04,85.56 80.28,85.8 U54.4
  BOTTOM w0.102: v2(167.67,72.98) 164.61,72.98 153.98,83.61 107,83.61 105.97,84.65 92.84,84.65 91.81,83.61 80.98,83.61 v2(80.6,84)
SIO_SLP_S4#: length 5.9
  TOP w0.102: UE1.84 187.99,67.89 187.48,68.4 187.48,70.69 186.72,71.45 T194.1
SIO_SLP_S5#: length 153
  TOP w0.102: v2(77.38,82.66) 75.83,82.66 74.01,84.49 74.01,84.61 R14.2 73.55,85.16 U57.4 ; UE1.14 188.39,49.84 188.62,49.6 188.62,47.01 CE28.1 188.62,46 188.62,44.42 188.37,44.17 179.64,44.17 168.76,55.05 168.76,60.17 168.09,60.84 168.09,62.64 167.24,63.49 v1(167.24,70.39) 167.24,70.93 v2(164.65,73.51)
  BOTTOM w0.102: v2(77.38,82.66) 77.87,83.14 77.87,84.8 78.24,85.16 83.34,85.16 84.61,83.89 91.76,83.89 92.74,84.88 106.07,84.88 107.05,83.89 154.27,83.89 v2(164.65,73.51)
SNB_3V: length 0.4
  TOP w0.102: 136.33,20.89 v1(136.33,20.44)
SNB_5V: length 1.3
  TOP w0.102: PC115.1 v1(122.77,20.36)
SNB_CHG: length 1.1
  BOTTOM w0.102: PC716.1 v1(147.82,170.13)
SOC_I2C0_CLK: length 6.5
  BOTTOM w0.102: T109.1 124.07,126.15 123.6,125.68 121.19,125.68 120.82,125.31 120.5,125.31 119.99,124.8 119.8,124.8 119.68,124.8 119.5,124.62 119.5,124.21 USOC1.BG28
SOC_I2C0_DATA: length 3.6
  BOTTOM w0.102: T108.1 122.8,125.17 122.77,125.19 121.05,125.19 120.93,125.08 120.59,125.08 120,124.49 USOC1.BH28
SOC_KBRST#: length 37.2
  TOP w0.102: v2(78.34,92.31) 78.53,92.12 78.53,90.75 78.96,90.32 R3.2 78.74,88 U61.4
  BOTTOM w0.102: v2(78.34,92.31) 78.35,92.31 82.1,96.06 83.13,96.06 88.17,101.09 v1(88.17,103.58) 88.17,104.31 94.09,110.23 96.43,110.23 97.68,111.48 99.62,111.48 99.91,111.77 100.19,111.77
SOC_LID_OUT#: length 31.8
  TOP w0.102: U62.4 80.37,94.09 R4.2 80.81,94.56 80.81,95.41 80.48,95.74 v2(80.34,95.74)
  BOTTOM w0.102: v2(80.34,95.74) 80.51,95.91 81,95.91 81.98,96.89 v1(82.86,96.89) 83.28,96.89 87.63,101.24 87.63,104.48 93.62,110.46 96.04,110.46 97.32,111.74 98.63,111.74 98.85,111.96 99.06,111.96 99.26,112.16 99.9,112.16 USOC1.C17
SOC_SATALED#: length 219
  TOP w0.102: QC2.1 105.82,139.33 105.38,139.77 95.78,139.77 95.3,140.25 95.3,141.57 94.77,142.11 94.3,142.11 93.72,141.53 93.72,140.38 91.91,138.57 90.9,138.57 89.82,137.49 89.82,133.23 91.88,131.18 91.88,128.7 91.34,128.17 89.49,128.17 83.47,122.15 v2(75.49,122.15) ; v2(54.82,26.44) 55.91,27.53 v1(55.91,29.35) v2(55.91,33.86) ; RD15.1 v2(44.63,10.74)
  IN2 w0.127: v2(55.91,33.86) 55.91,34.15 38.85,51.21 38.85,57.06 37.82,58.09 37.82,72.5 41.58,76.26 41.58,78.15 40.21,79.52 40.21,86.61 v2(32.87,93.95)
  BOTTOM w0.102: v2(32.87,93.95) 32.87,102.39 37.14,106.66 37.14,113.75 40.2,116.81 70.16,116.81 v2(75.49,122.15) ; v2(44.63,10.74) 45.16,10.74 45.67,11.25 52.4,11.25 54.82,13.66 v2(54.82,26.44)
SOC_SCI#: length 23.1
  TOP w0.102: v2(111.83,128.24) 111.69,128.24 108.94,130.99 108.94,135.76 108.73,135.98 108.73,136.78 108.68,136.83 108.68,137.86 v1(108.48,138.07) 108.17,138.38 106.45,138.38 105.28,139.55 102.02,139.55 R8.2 100.92,139.46 99.41,139.46 98.98,139.03 U66.4
  BOTTOM w0.102: USOC1.BA12 111.88,128.18 v2(111.83,128.24)
SOC_SERIRQ: length 27
  TOP w0.102: v2(113.83,128.89) 113.83,129.84 113.02,130.64 113.02,134.12 113.82,134.92 113.82,137.16 110.02,140.97 v1(107.89,140.97) 106.63,140.97 105.81,140.14 101.64,140.14 100.49,141.3 100.49,141.87 100.22,142.14 U64.3
  BOTTOM w0.102: USOC1.BG13 114.33,129.39 v2(113.83,128.89)
SOC_SMI#: length 33.4
  TOP w0.102: U65.4 77.89,94.09 R7.2 78.24,94.1 v2(78.54,93.8)
  BOTTOM w0.102: USOC1.C15 99.21,113.05 99,112.84 98.81,112.84 98.06,112.84 97.79,112.57 97.62,112.4 97.59,112.4 95.89,110.69 93.52,110.69 87.28,104.45 v1(87.28,101.88) 87.28,101.21 83.3,97.23 81.98,97.23 80.95,96.2 79.8,96.2 79.06,95.46 79.06,94.32 v2(78.54,93.8)
SOC_SPI_CLK: length 7
  BOTTOM w0.102: 102.06,110.89 102.06,110.89 101.67,111.28 101.41,111.28 101.3,111.27 101.2,111.2 101.18,111.02 101.18,110.93 101.03,110.78 100.95,110.78 100.87,110.78 99.82,109.73 97.86,109.73 v1(97.76,109.62) 96.96,109.62 RP67.5
SOC_SPI_CS0#: length 6
  BOTTOM w0.102: RP67.8 97.69,108.23 99.47,108.23 99.72,108.48 v1(100.04,108.48) 100.16,108.6 100.16,108.91 100.89,109.65 101.11,109.65 101.55,110.09 101.76,110.09 101.98,110.3 USOC1.C23
SOC_SPI_MISO: length 5.4
  BOTTOM w0.102: RP67.7 97.33,108.58 99.54,108.58 100.81,109.85 101.03,109.85 USOC1.B22
SOC_SPI_MOSI: length 5.1
  BOTTOM w0.102: USOC1.A21 100.84,110.46 99.9,109.52 98.2,109.52 97.62,108.94 96.98,108.94 RP67.6
SOC_SPKR: length 159.6
  TOP w0.102: v2(177.42,43.61) 177.55,43.61 v1(177.85,43.3) 178.13,43.03 189.02,43.03 190.92,41.12 192.18,41.12 DA8.3
  IN2 w0.127: v2(153.9,96.62) 156.62,93.9 156.62,72.73 155.02,71.13 155.02,52.8 159.79,48.03 165.89,48.03 167.29,49.43 169.88,49.43 170.13,49.17 170.13,48.24 174.76,43.61 v2(177.42,43.61)
  BOTTOM w0.102: USOC1.BH12 114.35,129.99 115.24,130.88 115.24,131.93 119.61,136.29 124.84,136.29 137.68,123.45 137.68,112.71 141.56,108.84 143.29,108.84 146.31,105.82 146.31,100.06 149.75,96.62 v2(153.9,96.62)
SPI_CLK: length 55.2
  TOP w0.102: v2(80.24,77.49) 80.98,77.49 82.76,79.27 RC39.1 81.74,79.58 81.61,79.7 UC8.6
  BOTTOM w0.102: v2(80.24,77.49) 78.16,77.49 76.03,79.63 71.76,79.63 71.1,80.29 71.1,82.52 73.84,85.26 73.84,85.76 v1(75.37,87.29) 75.37,87.65 82.59,94.87 83.65,94.87 89.94,101.16 89.94,103.41 92.32,105.78 92.72,105.78 95.09,108.15 RP67.4
SPI_CS0#: length 46.4
  TOP w0.102: UC8.1 71.89,82.24 71.76,82.37 RC36.2 70.97,82.78 71.14,82.94 v2(73.43,82.94)
  BOTTOM w0.102: RP67.1 96.55,107.08 96.27,106.8 95.61,106.8 93.51,104.71 93.51,103.56 92.44,102.48 92.44,101.96 84.15,93.67 83.63,93.67 81.31,91.36 v1(81.31,90.6) 81.31,89.88 81.44,89.75 81.92,89.75 82.05,89.62 82.05,89.38 81.92,89.25 81.44,89.25 81.31,89.13 81.31,88.72 81.44,88.59 81.87,88.59 81.99,88.47 81.99,88.21 81.87,88.09 79.83,88.09 79.24,87.5 79.1,87.5 78.5,86.9 77.58,86.9 77.26,86.59 76.54,86.59 75.64,85.69 75.64,85.15 74.55,84.06 74.55,82.07 74.43,81.94 74.1,81.94 73.97,82.07 73.97,82.81 73.84,82.94 v2(73.43,82.94)
SPI_HOLD#: length 2.6
  TOP w0.102: RC37.2 82.57,80.4 v1(81.86,80.4) 81.28,80.97 80.49,80.97
SPI_MISO: length 45.4
  TOP w0.102: 73.24,80.97 72.25,80.97 v2(72.06,80.78)
  BOTTOM w0.102: v2(72.06,80.78) 72.06,81.09 72.19,81.21 73.43,81.21 73.56,81.34 73.56,81.66 73.43,81.79 72.19,81.79 72.06,81.91 72.06,82.3 74.81,85.04 74.81,85.36 76.98,87.53 77.37,87.53 77.52,87.38 77.7,87.38 78.02,87.71 78.02,87.88 77.85,88.06 77.85,88.31 78.03,88.49 78.28,88.49 78.75,88.02 79,88.02 v1(79.67,88.68) 80.66,88.68 80.76,88.78 80.76,89.11 80.63,89.24 79.92,89.24 79.8,89.37 79.8,89.65 79.92,89.77 80.63,89.77 80.76,89.9 80.76,91.31 83.48,94.03 84,94.03 92.06,102.08 92.06,102.61 93.16,103.71 93.16,104.86 95.46,107.16 95.91,107.16 RP67.2
SPI_MOSI: length 49.6
  TOP w0.102: UC8.5 v2(78.44,78.43)
  BOTTOM w0.102: v2(78.44,78.43) 76.76,80.11 71.96,80.11 71.61,80.46 71.61,82.34 74.45,85.19 74.45,85.5 v1(76.8,87.85) 78.25,89.3 78.5,89.3 78.95,88.86 79.2,88.86 79.38,89.04 79.38,89.29 78.94,89.74 78.94,90.53 82.79,94.38 83.86,94.38 90.78,101.31 90.78,103.38 92.53,105.14 92.94,105.14 95.32,107.52 95.56,107.52 RP67.3
SPI_WP#: length 2.9
  TOP w0.102: RC38.2 70.97,80.26 v1(71.6,79.63) 71.62,79.61 72.01,79.61 72.1,79.7 UC8.3
SPK_L1-_CONN:
  vias: v1(67.83,23.85)
SPK_L2+_CONN:
  vias: v1(66.81,25.6)
SPK_R1-_CONN:
  vias: v1(67.73,20.05)
SPK_R2+_CONN:
  vias: v1(67.77,21.96)
SPOK: length 276.4
  TOP w0.203: UE1.18 189.99,52.19 190.2,52.4 v2(190.58,52.4) ; PU100.7 131.35,15.7 132.21,14.84 PR106.2
  TOP w0.254: v4(113.82,30.6) v1(113.82,26.58) 113.82,18.31 117.85,14.29 120.41,14.29 122.05,12.65 122.05,10.72 122.51,10.26 131.19,10.26 132.21,11.28 v4(132.21,12.09) 132.64,12.52 132.64,13.84 PR106.2
  IN2 w0.254: v4(113.82,30.6) 105.5,30.6 105.08,31.02 78.87,31.02 74.13,35.76 67.72,35.76 66.07,34.11 59.35,34.11 41.2,52.26 41.2,58.03 40.24,59 40.24,67.54 44.36,71.66 44.36,80.68 46.89,83.21 v2(46.89,91.77) 48.47,91.77 49.99,90.24 54,90.24 56.6,92.84 v2(61.83,92.84) ; v4(132.21,12.09) 133.96,12.09 134.6,12.72 138.05,12.72 139.81,14.48 139.81,31.16 142.12,33.48 158.14,33.48 160.56,31.06 173.56,31.06 188.93,46.43 189.39,46.43 190.58,47.62 v2(190.58,52.4)
  BOTTOM w0.254: PR400.1 v2(61.83,92.84) ; PR308.1 v2(46.89,91.77)
SUSP: length 221.1
  TOP w0.254: v2(160.18,34.36) 160.18,33.5 Q2307.2 v3(161.08,30.36) 161.52,29.92 161.52,26.92 161.12,26.52 161.12,23.72 R10.2 162.39,23.14 162.84,22.68 Q8.1 ; Q2308.2 69.96,33.04 71.02,34.11 v2(71.02,34.75)
  IN2 w0.254: v2(160.18,34.36) 160.18,34.92 159.24,35.86 121.63,35.86 115.69,29.92 105.64,29.92 104.92,30.64 78.71,30.64 74.2,35.15 71.43,35.15 v2(71.02,34.75) 67.24,34.75 66.23,33.73 59.19,33.73 40.82,52.1 40.82,57.88 39.86,58.84 39.86,67.7 43.73,71.57 43.73,80.58 46.38,83.24 46.38,91.95 46.71,92.28 49.08,92.28 50.73,90.63 53.78,90.63 56.57,93.42 60.35,93.42 62.03,95.1 v2(63.38,95.1)
  BOTTOM w0.254: Q70.2 62.26,99.29 62.26,96.59 62.51,96.34 Q71.2 v2(63.38,95.1)
SUSP#: length 440.9
  TOP w0.102: v2(183.59,57.43) 183.42,57.6 UE1.116 ; R1056.2 v2(61.65,104.34) 62.21,104.34 62.49,104.06 62.49,101.6 62.18,101.29 R1055.2
  TOP w0.254: Q8.2 167.03,21.71 R16.1 168.29,22.97 168.29,25.49 v1(166.44,27.34) 165.42,28.36 v2(162.73,28.36)
  IN2 w0.127: v4(170.37,108.46) v2(170.37,103.4) ; v2(183.59,57.43) 183.59,59.6 182.12,61.07 182.12,63.22 180.09,65.25 180.09,94.64 182.38,96.92 186.59,96.92 v2(193.39,103.72) 201.64,111.97 201.64,143.03 191.42,153.25 191.42,155.4 191.11,155.7 178.05,155.7 177.39,155.04 v2(173.76,155.04) 172.65,156.16 165.83,156.16 164.84,155.17 162.57,152.89 158.58,148.91 158.16,148.49 124.88,148.49 119.22,142.82 113.88,142.82 112.12,141.06 112.12,140.05 v2(109.99,137.92)
  IN2 w0.254: v2(109.12,32.56) 113.57,37.01 160.21,37.01 v2(162.73,34.49) 173.03,34.49 183.57,45.03 183.57,56.77 183.59,56.79 v2(183.59,57.43)
  BOTTOM w0.102: v2(109.99,137.92) 108.92,138.99 101.47,138.99 100.05,140.41 90.88,140.41 89.84,139.37 89.84,133.79 90.66,132.98 90.66,131.8 92.41,130.04 92.41,123.13 90.77,121.49 89.3,121.49 78.71,110.9 73,110.9 71.65,109.55 67.31,109.55 62.11,104.34 v2(61.65,104.34) ; v2(173.76,155.04) 173.33,154.61 PR409.1 ; v2(193.39,103.72) 193.07,103.4 v2(170.37,103.4)
  BOTTOM w0.254: v2(162.73,34.49) v2(162.73,28.36) PR208.1 ; R927.2 106.07,32.81 106.4,33.14 108.54,33.14 v2(109.12,32.56) R926.1 ; PR300.1 v4(170.37,108.46)
SW_1.35VP: length 7
  TOP w0.102: v4(155.92,24.76) v1(156.49,24.76)
  IN2 w1.016: 154.78,23.94 154.59,23.75 154.59,18.41 154.02,17.84
  vias: v4(153.83,16.83) v4(154.46,16.83) v4(155.29,24.76)
SYSON: length 74.2
  TOP w0.203: CE26.1 183.54,68.11 183.59,68.07 UE1.95
  TOP w0.254: CE26.1 184.13,70.05 184.13,72.69 183.47,73.35 v3(182.53,73.35) v2(179.33,73.35)
  IN2 w0.254: v2(163.22,37.41) 173.1,37.41 181.64,45.95 181.64,53.26 180.98,53.91 180.98,54.76 178.49,57.25 178.49,72.51 v2(179.33,73.35)
  BOTTOM w0.254: PR207.1 161.82,26.48 162.71,26.48 163.22,26.99 v2(163.22,37.41)
TL_BKOFF#: length 61.4
  BOTTOM w0.102: DX1.2 221.52,154.89 214.02,147.39 205.9,147.39 205.74,147.55 192.39,147.55 189,150.93 189,162.63 v1(191.25,164.88) RX33.1 193.13,166.19 193.27,166.05 UX2.4 194.26,165.68 RT15.2
TL_BKOFF#_R: length 21.1
  TOP w0.102: RT19.1 202.64,165.69 v2(202.49,165.85) 202.49,166.27 202.9,166.67 202.9,168.02 202.42,168.5 197.16,168.5 196.02,167.36 196.02,166.14 196.24,165.91 196.24,165.02 195.91,164.69 v2(195.91,164.16)
  BOTTOM w0.102: UT2.17 203.71,166.16 203.55,166.32 202.85,166.32 202.49,165.96 v2(202.49,165.85) ; UX2.1 195.41,167.35 195.18,167.12 RT15.1 RT14.1 v2(195.91,164.16) 196.23,164.16 v1(196.41,164.34)
TL_ENVDD: length 2.3
  TOP w0.508: RX6.1 202.31,164.29 v4(202.01,164.59)
  BOTTOM w0.102: v4(211.51,167.64) v1(210.72,167.64)
  BOTTOM w0.508: RX7.2 v2(219.18,164.74)
  vias: v4(201.48,165.61) v4(201.5,164.97) v4(211.51,168.91) v4(211.51,168.27)
TL_INVT_PWM: length 40.5
  TOP w0.102: v4(221.77,174.47) 221.77,174.24 RX26.1
  IN2 w0.127: v2(201.65,164.08) 200.56,164.08 197.34,167.31 197.34,171.45 198,172.11 201.3,172.11 204.42,175.23 216.84,175.23 217.76,174.32 218.55,174.32 219.79,175.56 220.68,175.56 v4(221.77,174.47)
  BOTTOM w0.102: v4(221.77,174.47) 221.95,174.29 JLVDS.36 ; v2(201.65,164.08) 201.77,163.96 UT2.14
TMDS_L_TX0N: length 16.4
  IN2 w0.127: JHDMI.9 8.44,102.79 8.74,102.79 8.97,102.56 8.97,99.11 9.38,98.7 10.87,98.7 11.56,99.39 11.56,103.55 12.03,104.02 12.56,104.02 v2(12.81,104.27)
  BOTTOM w0.102: LX3.2 15.08,104.36 14.75,104.02 14.43,104.02 CX25.1 13.8,104 13.08,104 v2(12.81,104.27)
TMDS_L_TX0P: length 16.3
  IN2 w0.127: v2(12.81,103.52) 12.56,103.77 12.13,103.77 11.81,103.45 11.81,99.28 10.98,98.45 9.28,98.45 8.72,99.01 8.72,102.46 8.63,102.54 8.47,102.54 JHDMI.7
  BOTTOM w0.102: v2(12.81,103.52) 13.08,103.79 13.8,103.79 CX26.1 14.47,103.81 14.81,103.81 15.06,103.56 LX3.3
TMDS_L_TX1N: length 7.5
  BOTTOM w0.102: LX4.2 14.25,98.77 13.95,98.48 13.81,98.48 CX27.1 12.91,98.48 11.81,98.48 10.85,99.44 10.85,100.81 10.4,101.26 10.02,101.26 JHDMI.6
TMDS_L_TX1P: length 7.5
  BOTTOM w0.102: LX4.3 14.3,97.97 14.01,98.26 13.81,98.26 CX28.1 12.91,98.26 11.72,98.26 10.63,99.35 10.63,100.72 10.31,101.04 10.02,101.04 JHDMI.4
TMDS_L_TX2N: length 10.7
  BOTTOM w0.102: LX5.2 15.82,95.72 15.53,95.43 15.34,95.43 CX29.1 14.44,95.43 v4(13.67,95.43) 12.57,95.43 9,99.01 9,99.49 8.73,99.76 8.47,99.76 JHDMI.3
TMDS_L_TX2P: length 10.7
  BOTTOM w0.102: LX5.3 15.8,94.92 15.5,95.22 15.34,95.22 CX30.1 14.44,95.22 13.95,95.22 13.93,95.2 13.4,95.2 13.39,95.22 12.48,95.22 8.78,98.92 8.78,99.4 8.64,99.54 8.47,99.54 JHDMI.1
TMDS_L_TXCN: length 8.6
  BOTTOM w0.102: LX2.2 16.07,101.57 15.78,101.27 15.59,101.27 CX23.1 14.69,101.27 v4(14.13,101.27) 13.58,101.27 13.2,101.65 13.2,101.67 12.83,102.05 12.81,102.05 10.6,104.26 10.02,104.26 JHDMI.12
TMDS_L_TXCP: length 8.6
  BOTTOM w0.102: LX2.3 16.05,100.77 15.76,101.06 15.59,101.06 CX24.1 14.69,101.06 14.4,101.06 14.39,101.05 13.86,101.05 13.85,101.06 13.49,101.06 v4(12.85,101.7) 10.51,104.04 10.02,104.04 JHDMI.10
TMDS_TX0N: length 4.4
  TOP w0.102: R1073.1 16.25,104.07 v4(16.97,104.07) 17.71,104.07 v2(17.98,104.34)
  BOTTOM w0.102: LX3.1 17.28,104.36 17.57,104.07 17.71,104.07 v2(17.98,104.34) 18.11,104.47 CX14.1
TMDS_TX0P: length 4.4
  TOP w0.102: v2(17.98,103.58) 17.71,103.85 17.25,103.85 17.24,103.84 16.71,103.84 16.69,103.85 16.25,103.85 R1074.1
  BOTTOM w0.102: LX3.4 17.26,103.56 17.55,103.85 17.71,103.85 v2(17.98,103.58) 18.11,103.45 CX15.1
TMDS_TX1N: length 4.1
  TOP w0.102: v2(17.22,98.75) 16.95,98.48 16.51,98.48 R1075.1
  BOTTOM w0.102: LX4.1 16.49,98.77 16.79,98.48 16.95,98.48 v2(17.22,98.75) 17.49,98.48 18.09,98.48 CX16.1
TMDS_TX1P: length 4.1
  TOP w0.102: R1076.1 16.51,98.26 16.95,98.26 v2(17.22,97.99)
  BOTTOM w0.102: LX4.4 16.52,97.97 16.81,98.26 16.95,98.26 v2(17.22,97.99) 17.49,98.26 18.09,98.26 CX17.1
TMDS_TX2N: length 5
  TOP w0.102: v2(18.82,95.7) 18.55,95.43 17.66,95.43 17.64,95.44 17.11,95.44 17.1,95.43 16.51,95.43 R1077.1
  BOTTOM w0.102: LX5.1 18.04,95.72 18.34,95.43 18.55,95.43 v2(18.82,95.7) 18.95,95.83 CX18.1
TMDS_TX2P: length 5
  TOP w0.102: R1078.1 16.51,95.22 v4(17.38,95.22) 18.55,95.22 v2(18.82,94.95)
  BOTTOM w0.102: LX5.4 18.05,94.92 18.34,95.22 18.55,95.22 v2(18.82,94.95) 18.95,94.82 CX19.1
TMDS_TXCN: length 5.4
  TOP w0.102: v2(18.97,101.54) 18.7,101.27 v4(17.29,101.27) 16.51,101.27 R1071.1
  BOTTOM w0.102: LX2.1 18.25,101.57 18.54,101.27 18.7,101.27 v2(18.97,101.54) 19.23,101.28 19.43,101.28 CX12.1
TMDS_TXCP: length 5.4
  TOP w0.102: v2(18.97,100.79) 18.7,101.06 17.57,101.06 17.55,101.05 17.02,101.05 17.01,101.06 16.51,101.06 R1072.1
  BOTTOM w0.102: CX13.1 19.42,101.06 19.24,101.06 v2(18.97,100.79) 18.7,101.06 18.54,101.06 18.25,100.77 LX2.4
TON_1.35VP: length 2.6
  BOTTOM w0.203: PU200.9 159.46,25.67 159.79,25.33
  BOTTOM w0.254: PR205.2 160.24,24.57 159.9,24.92 v1(159.9,25.08) 159.9,25.23 159.79,25.33
TOUCH_RST: length 215.4
  TOP w0.102: UE1.38 194.98,54.8 v2(192.56,57.22) 191.54,57.22 190.63,58.14 190.63,58.42 v2(189.49,59.56) ; RX1.1 v2(18.7,92.48)
  IN2 w0.127: v2(38.33,94.38) 35.79,94.38 35.28,94.89 28.32,94.89 26.34,96.87 21.97,96.87 20.35,95.25 20.35,94.89 18.7,93.24 v2(18.7,92.48)
  BOTTOM w0.102: v2(192.56,57.22) 193.07,56.72 RX4.2 ; v2(189.49,59.56) 189.26,59.79 184.71,59.79 182.75,57.83 176.23,57.83 174.9,59.17 169.84,59.17 165.43,63.57 155.66,63.57 149.97,57.88 145.27,57.88 141.26,53.88 89.17,53.88 85.6,57.45 79.57,57.45 69.47,67.55 61.33,67.55 57.08,71.8 54.76,71.8 52.78,73.78 52.78,82.39 45.06,90.11 45.06,90.68 41.35,94.38 v1(39.61,94.38) v2(38.33,94.38)
TOUCH_RST_R: length 5.4
  TOP w0.102: v1(17.4,93.47) 17.94,94 RX1.2 RX24.2 19.71,96.21 19.71,96.21 JTOUCH.6
TP2_CORE_VCC_S0IX: length 1.8
  TOP w0.102: T112.1 107.32,116.39 v2(107.28,116.43)
  BOTTOM w0.102: v2(107.28,116.43) 107.82,116.98 USOC1.AA22
TP_CLK: length 260.8
  TOP w0.102: v2(67.18,117.55) 67.34,117.39 67.34,116.41 67.11,116.18 DE3.3 66.63,115.57 66.91,115.29 67.97,115.29 68.43,114.83 68.43,112.47 v1(67.71,111.74) 67.35,111.38 JTP.2 ; UE1.87 186.79,68.59 v2(186.59,68.78) RE9.2
  IN2 w0.127: v2(39.91,73.03) 40.07,72.87 40.94,72.87 42.65,74.58 42.65,78.52 41.25,79.92 41.25,87.58 39.32,89.51 39.32,105.77 47.95,114.4 62.28,114.4 64.47,116.58 66.95,116.58 67.34,116.97 67.34,117.39 v2(67.18,117.55)
  BOTTOM w0.102: v2(39.91,73.03) 42.99,69.95 50.11,69.95 54.97,65.09 69.81,65.09 78.39,56.51 85.21,56.51 88.78,52.94 141.65,52.94 145.66,56.94 152.96,56.94 156.65,53.26 165.51,53.26 166.12,53.88 166.12,56.48 167.83,58.19 174.55,58.19 175.84,56.89 183.9,56.89 185.19,58.19 189.62,58.19 190.86,59.43 190.86,65.07 187.15,68.78 v2(186.59,68.78)
TP_CORE_V1P05_S4: length 1.1
  TOP w0.102: T195.1 112.2,115.97 v2(112.18,115.95)
  BOTTOM w0.254: USOC1.AF30 112.71,115.95 v2(112.18,115.95)
TP_DATA: length 264.1
  TOP w0.102: UE1.88 186.39,67.97 185.91,68.45 v2(185.91,68.78) 185.58,69.11 RE10.2 ; v2(68.01,117.55) 67.82,117.36 67.82,116.41 68.05,116.18 DE3.2 68.56,115.39 68.91,115.03 68.91,112.27 68.35,111.7 JTP.3
  IN2 w0.127: v2(39.91,72.2) 40.07,72.36 41.15,72.36 43.16,74.37 43.16,78.74 41.76,80.13 41.76,87.79 39.83,89.72 39.83,105.56 48.16,113.89 62.49,113.89 64.68,116.08 67.16,116.08 67.85,116.76 67.85,117.39 v2(68.01,117.55)
  BOTTOM w0.102: v2(39.91,72.2) 42.64,69.47 49.91,69.47 54.8,64.58 69.03,64.58 74.65,58.96 74.65,53.92 77.78,50.8 149.01,50.8 150.99,52.78 165.71,52.78 166.6,53.68 166.6,56.28 167.98,57.65 174.4,57.65 175.64,56.41 184.17,56.41 185.46,57.7 189.81,57.7 191.34,59.23 191.34,65.27 187.27,69.34 186.47,69.34 v2(185.91,68.78)
TXE_DBG: length 100.6
  TOP w0.102: QC1.2 129.33,123.12 v2(129.57,122.88) ; v2(167.62,91.06) v1(175.99,82.68) 178.06,80.62 178.06,73.19 180.06,71.19 180.06,65.02 180.68,64.4 UE1.99
  BOTTOM w0.102: v2(129.57,122.88) 129.34,122.65 129.34,118.11 130.08,117.37 130.08,113.98 128.55,112.46 128.55,99.86 136.31,92.1 146.78,92.1 147.01,91.87 166.81,91.87 v2(167.62,91.06)
UG_3V: length 13.1
  TOP w0.102: v4(134.84,30.06) v1(135.42,30.06)
  IN2 w1.016: 134.52,29.21 134.27,28.95 134.27,19.35 133.51,18.59 132.01,18.59
  vias: v4(130.64,17.44) v4(131.09,17.93) v4(134.2,30.06)
UG_5V: length 10.5
  IN2 w1.016: 126.17,17.6 123.27,20.5 123.27,25.88 122.56,26.59
  vias: v1(122.27,26.97) v4(121.97,27.46) v4(122.63,27.48) v4(127.13,17.45) v4(127.79,17.44)
UGATE1: length 6.9
  TOP w0.102: v4(160.9,130.27) v1(160.9,129.72)
  IN2 w1.016: 157.89,124.28 159.54,125.93 159.54,127.94 160.94,129.33
  vias: v2(156.32,124.48) v2(156.9,124.48) v4(160.91,130.92)
UGATE1-1: length 1.3
  TOP w0.102: v1(155.34,127.02) PR528.2
UGATEG1: length 19.5
  TOP w0.102: v4(160.8,135.77) 160.79,135.77 v1(160.35,136.21)
  IN2 w1.016: 160.3,136.9 158.32,138.89 147.43,138.89 145.72,140.59 142.93,140.59
  vias: v4(141.38,141.65) v4(141.38,140.99) v4(161.2,135.19)
UGATEG1-1: length 1.4
  TOP w0.102: v1(143.51,142.12) 143.02,142.12 142.64,142.5 PR506.2
USB3_REXT0: length 3.3
  TOP w0.102: v1(101.01,120.39) RC40.1
  TOP w0.381: RC40.1 101.48,119.36 101.48,118.56 v2(101.7,118.34)
  BOTTOM w0.254: v2(101.7,118.34) 101.51,118.15 USOC1.M12
USB3RN2_JUSB1_R: length 7
  BOTTOM w0.102: LI1.2 19.12,60.63 18.82,60.93 18.47,60.93 18.21,61.19 17.99,61.19 17.85,61.05 DI1.10 DI1.1 15.91,61.05 15.75,61.21 13.54,61.21 T113.1
USB3RP2_JUSB1_R: length 7
  BOTTOM w0.102: T114.1 13.61,61.43 15.75,61.43 15.87,61.55 DI1.2 DI1.9 17.82,61.55 17.97,61.4 18.3,61.4 18.56,61.15 18.82,61.15 19.11,61.43 LI1.3
USB3TN2_JUSB1_R: length 5.2
  BOTTOM w0.102: LI3.2 19.09,62.69 18.2,62.69 18.06,62.55 DI1.7 DI1.4 15.84,62.55 15.68,62.71 15.17,62.71 T115.1
USB3TP2_JUSB1_R: length 5.2
  BOTTOM w0.102: LI3.3 19.07,62.91 18.2,62.91 18.06,63.05 DI1.6 DI1.5 15.8,63.05 15.68,62.93 15.15,62.93 T116.1
USB20_CAM_N7_R: length 5.5
  BOTTOM w0.102: LX6.2 218.67,168.63 218.37,168.93 218.37,169.24 217.82,169.78 v4(217.82,170.3) 217.82,171.64 217.83,171.65 217.83,172.18 217.82,172.2 217.82,172.82 217.95,172.95 JLVDS.28
USB20_CAM_P7_R: length 5.5
  BOTTOM w0.102: LX6.3 217.87,168.62 218.15,168.91 218.15,169.15 217.61,169.69 217.61,170.03 217.59,170.04 217.59,170.57 217.61,170.58 v4(217.61,171.92) 217.61,172.77 217.45,172.92 JLVDS.27
USB20_CPU_N3: length 241.5
  IN2 w0.102: v2(99.55,117.34) 99.9,117.69 99.9,117.88 99.8,117.98 99.29,117.98 98.53,117.22 96.92,115.62 95.92,115.62 94.98,116.56 91.63,116.56 91.62,116.54 91.6,116.54
  IN2 w0.127: v2(166.09,36.65) 166.42,36.65 166.5,36.57 166.5,35.86 166.29,35.65 162.98,35.65 160.73,37.9 92,37.9 89.56,35.46 85.2,35.46 73.34,47.32 52.4,47.32 48.28,51.44 47.32,51.44 45.6,53.17 45.6,61.31 45.89,61.6 45.89,65.64 51.62,71.37 51.62,77.67 56.7,82.75 68.84,82.75 72.32,86.23 72.32,87.07 75.19,89.93 75.19,96.01 74.89,96.32 74.89,106.71 82.63,114.45 83.83,114.45 87.06,117.68 89.53,117.68 90.66,116.54 91.6,116.54
  BOTTOM w0.102: v2(99.55,117.34) 99.88,117.34 99.95,117.26 99.95,117.09 USOC1.H10 ; v2(166.09,36.65) 166.42,36.65 166.53,36.55 166.53,34.87 166.48,34.82 166.48,34.11 166.14,33.78 LR2.1
USB20_CPU_P3: length 241.6
  IN2 w0.102: 91.6,116.8 91.62,116.8 91.63,116.79 95.08,116.79 96.02,115.85 96.83,115.85 98.44,117.46 99.19,118.21 v2(100.28,118.21)
  IN2 w0.127: 91.6,116.8 90.77,116.8 89.64,117.93 86.95,117.93 83.72,114.71 82.52,114.71 74.63,106.81 74.63,96.21 74.93,95.91 74.93,90.04 72.07,87.18 72.07,86.34 68.74,83.01 56.59,83.01 51.36,77.78 51.36,71.48 45.63,65.75 45.63,61.71 45.34,61.42 45.34,53.06 47.21,51.19 48.17,51.19 52.29,47.06 73.23,47.06 85.1,35.2 89.66,35.2 92.1,37.64 160.63,37.64 162.87,35.39 166.4,35.39 166.76,35.75 166.76,36.48 v2(166.92,36.65)
  BOTTOM w0.102: USOC1.K10 100.3,118.18 v2(100.28,118.21) ; v2(166.92,36.65) 166.74,36.47 166.74,34.78 166.69,34.73 166.69,34.07 166.7,34.07 166.7,34.06 166.7,34.05 166.95,33.81 LR2.4
USB20_CR_N3_R: length 20.5
  TOP w0.102: UR1.2 176.32,20.8 176.46,20.66 176.46,20.09 v2(176.19,19.82)
  BOTTOM w0.102: v2(176.19,19.82) 176.46,20.09 176.46,20.19 176,20.65 171.43,20.65 168.72,23.35 168.72,24.17 166.44,26.45 v4(166.44,28.53) 166.44,30.64 166.14,30.93 LR2.2
USB20_CR_P3_R: length 20.5
  TOP w0.102: UR1.3 176.82,20.8 176.68,20.66 176.68,20.09 v2(176.95,19.82)
  BOTTOM w0.102: LR2.3 166.95,30.93 166.65,30.64 166.65,28.81 166.67,28.8 166.67,28.27 166.65,28.26 166.65,26.54 168.94,24.26 168.94,23.44 171.52,20.86 176.09,20.86 176.68,20.28 176.68,20.09 v2(176.95,19.82)
USB20_HUB_N1: length 156.8
  TOP w0.102: v2(41.99,54.67) 42.26,54.4 49.06,54.4 49.2,54.54 U58.11
  IN2 w0.127: v2(41.99,54.67) 41.99,54.42 42.08,54.32 42.6,54.32 42.78,54.5 42.78,57.27 40.82,59.22 40.82,67.32 44.93,71.43 44.93,79.53 50.21,84.81 53.32,84.81 54.84,86.33 59.1,86.33 60.14,87.37 66.68,87.37 71.63,92.33 71.63,94.51 71.35,94.79 71.35,99.01 69.6,100.76 69.6,108.38 72.98,111.76 72.98,112.9 75.19,115.11 75.19,115.57 75.05,115.71 v2(74.85,115.71)
  BOTTOM w0.102: JMINI.36 110.5,147.02 110.79,146.73 110.79,146.32 108.68,144.21 106.43,144.21 105.81,144.83 101.65,144.83 101.24,144.41 97.55,144.41 97.32,144.64 90.43,144.64 86.64,140.85 86.64,132.46 87.46,131.65 87.46,126.24 79.71,118.49 77.12,118.49 75.12,116.5 75.12,115.98 v2(74.85,115.71)
USB20_HUB_N2: length 64.3
  TOP w0.102: JTOUCH.2 22.91,96.46 22.62,96.17 22.62,96.02 v2(22.89,95.75) ; U58.9 49.19,55.54 49.05,55.41 48.76,55.41 48.61,55.26 45.81,55.26 44.91,56.15 40.27,56.15 40.26,56.16 39.73,56.16 39.72,56.15 37.92,56.15 37.8,56.27 v2(37.8,56.52)
  IN2 w0.127: v2(22.89,95.75) 22.64,95.5 22.64,94.97 23.33,94.28 29.27,94.28 34.01,89.54 34.01,74.55 36.6,71.96 36.6,56.73 37.17,56.16 37.65,56.16 37.8,56.31 v2(37.8,56.52)
USB20_HUB_N3: length 47.6
  TOP w0.102: U58.7 49.2,56.54 49.06,56.4 48.25,56.4 v2(47.98,56.67)
  BOTTOM w0.102: v2(47.98,56.67) 47.71,56.4 47.01,56.4 46.45,55.84 46.45,45.96 28.86,28.38 20.94,28.38 20.65,28.67 LI6.1
USB20_HUB_P1: length 156.8
  TOP w0.102: U58.12 49.2,54.04 49.06,54.19 42.26,54.19 v2(41.99,53.92)
  IN2 w0.127: v2(75.61,115.71) 75.45,115.55 75.45,115 73.24,112.79 73.24,111.65 69.86,108.27 69.86,100.87 71.61,99.11 71.61,94.9 71.89,94.62 71.89,92.22 66.78,87.12 60.25,87.12 59.21,86.08 54.95,86.08 53.42,84.55 50.32,84.55 45.19,79.42 45.19,71.32 41.08,67.21 41.08,59.33 43.03,57.37 43.03,54.4 42.71,54.07 42.14,54.07 v2(41.99,53.92)
  BOTTOM w0.102: JMINI.38 111.3,147.02 111,146.72 111,146.23 108.77,143.99 106.34,143.99 105.72,144.61 101.74,144.61 101.32,144.19 97.46,144.19 97.23,144.42 90.52,144.42 86.86,140.76 86.86,132.55 87.67,131.74 87.67,126.15 79.8,118.27 77.21,118.27 75.34,116.41 75.34,115.98 v2(75.61,115.71)
USB20_HUB_P2: length 64.3
  TOP w0.102: v2(22.13,95.75) 22.4,96.02 22.4,96.17 22.11,96.46 JTOUCH.3 ; U58.10 49.25,55.04 49.1,55.19 48.85,55.19 48.7,55.04 45.72,55.04 44.82,55.93 v4(40,55.93) 37.97,55.93 v2(37.8,55.76)
  IN2 w0.127: v2(37.8,55.76) 37.66,55.9 37.07,55.9 36.35,56.62 36.35,71.85 33.76,74.44 33.76,89.43 29.17,94.03 23.22,94.03 22.38,94.87 22.38,95.5 v2(22.13,95.75)
USB20_HUB_P3: length 47.6
  TOP w0.102: v2(47.98,55.92) 48.25,56.19 49.06,56.19 49.2,56.04 U58.8
  BOTTOM w0.102: LI6.4 20.65,27.87 20.94,28.16 28.95,28.16 46.66,45.87 46.66,55.75 47.1,56.19 47.71,56.19 v2(47.98,55.92)
USB20_JUSB1_N0_R: length 15.3
  IN2 w0.127: JUSB1.2 11.18,63.74 11.79,63.74 17.41,58.11 17.75,58.11 v2(18,58.36)
  BOTTOM w0.102: v2(18,58.36) 18.27,58.09 18.88,58.09 18.98,58.2 DI2.2 19.83,58.1 20.53,58.1 20.81,58.39 LI2.2
USB20_JUSB1_P0_R: length 15.3
  IN2 w0.127: v2(18,57.61) 17.75,57.86 17.3,57.86 11.68,63.48 11.2,63.48 JUSB1.3
  BOTTOM w0.102: v2(18,57.61) 18.27,57.88 18.88,57.88 18.98,57.78 DI2.3 19.84,57.89 20.51,57.89 20.81,57.59 LI2.3
USB20_JUSB2_N1_R: length 13.5
  BOTTOM w0.102: JUSB8.2 11.21,46.11 12.97,46.11 13.23,46.37 13.23,46.39 13.6,46.77 13.62,46.77 13.88,47.03 v4(15.04,47.03) 17.52,47.03 18.39,46.16 18.88,46.16 18.98,46.26 DI9.2 19.83,46.16 20.52,46.16 20.81,46.45 LI5.2
USB20_JUSB2_P1_R: length 13.5
  BOTTOM w0.102: LI5.3 20.81,45.65 20.52,45.94 19.83,45.94 DI9.3 18.98,45.84 18.88,45.94 18.3,45.94 17.43,46.81 15.32,46.81 15.31,46.8 14.77,46.8 14.76,46.81 13.97,46.81 v4(13.58,46.42) 13.06,45.89 11.21,45.89 JUSB8.3
USB20_JUSB3_N3_R: length 10.5
  BOTTOM w0.102: LI6.2 18.08,28.67 17.79,28.38 17.29,28.38 DI8.2 16.44,28.48 16.34,28.38 15.85,28.38 14.85,29.37 12.72,29.37 11.85,28.51 11.21,28.51 JUSB7.2
USB20_JUSB3_P3_R: length 10.5
  BOTTOM w0.102: LI6.3 18.08,27.87 17.79,28.16 17.29,28.16 DI8.3 16.44,28.06 16.34,28.16 15.76,28.16 14.76,29.16 12.81,29.16 11.94,28.29 11.21,28.29 JUSB7.3
USB20_N0: length 124.4
  IN2 w0.102: v2(102.16,115.79) 102.16,116.19 102.01,116.34 101.08,116.34 100.64,115.9 98.96,115.9 98,114.94 98,114.76 96.67,113.43 94.13,113.43 93.79,113.09 93.17,113.09 93.16,113.08 93.15,113.08
  IN2 w0.127: v2(47.95,60.08) 47.7,60.33 47.7,64.53 53.47,70.3 53.47,76.17 56.65,79.35 67.07,79.35 68.59,80.87 69.1,80.87 75.28,87.05 75.28,87.94 77.06,89.71 77.06,96.71 76.58,97.18 76.58,106.04 80.78,110.23 83.87,110.23 84.94,109.17 88.37,109.17 92.28,113.08 93.15,113.08
  BOTTOM w0.102: USOC1.K16 102.41,115.53 v2(102.16,115.79) ; LI2.1 23.7,58.39 24.03,58.05 43.89,58.05 45.34,59.51 45.34,60.45 46.23,61.34 47.23,61.34 47.59,60.98 47.59,60.44 v2(47.95,60.08)
USB20_N1: length 129.4
  IN2 w0.102: 93.7,111.47 93.7,111.48 93.7,111.5 93.76,111.55 94.98,112.77 97.51,112.77 99.07,114.33 99.07,114.81 99.7,115.44 101.12,115.44 101.48,115.09 101.48,114.93 101.35,114.8 v2(101.16,114.8)
  IN2 w0.127: v2(49.69,60.22) 49.69,60.02 49.52,59.86 49.21,59.86 49.08,59.99 49.08,64.49 54.33,69.75 54.33,75.87 56.14,77.67 68.15,77.67 71.24,80.76 71.24,81.86 76.33,86.95 76.33,87.73 77.92,89.32 77.92,96.73 78.62,97.42 78.62,98.93 77.5,100.05 77.5,105.78 79.08,107.36 85.33,107.36 86.16,108.2 89.71,108.2 92.41,110.89 93.12,110.89 93.7,111.47
  BOTTOM w0.102: LI5.1 23.7,46.45 24.09,46.06 24.84,46.06 25.21,46.43 30.5,46.43 30.51,46.44 31.04,46.44 31.05,46.43 31.76,46.43 32.22,46.89 37.17,46.89 45,54.72 45,55.92 48.95,59.86 49.58,59.86 49.69,59.96 v2(49.69,60.22) ; v2(101.16,114.8) 100.92,115.04 100.71,115.04
USB20_N2: length 173.4
  IN2 w0.102: v2(100.17,116.63) 100.17,116.85 100.05,116.97 100.05,117.42 100.69,118.06 100.69,118.41 101.59,119.3 103.54,119.3 103.86,119.62 105.71,121.48 108.27,121.48 111.1,124.31 111.1,126.03 109.96,127.17 109.96,128.29 109.55,128.7 109.55,129.5 109.72,129.67 109.72,130.27 108.68,131.32 108.68,132 107.57,133.11 107.55,133.11 107.55,133.12
  IN2 w0.127: v2(199.33,148.72) 199.17,148.89 199.17,150.35 192.11,157.4 165.99,157.4 157.89,149.3 124.62,149.3 119.01,143.69 113.67,143.69 111.35,141.38 111.35,140.65 109.86,139.16 109.06,139.16 107.06,137.17 107.06,133.6 107.55,133.12
  BOTTOM w0.102: v2(100.17,116.63) 100.51,116.29 USOC1.J12 ; LX6.1 218.67,166.48 218.37,166.19 218.37,166.03 218.47,165.94 219.51,165.94 220.29,165.16 220.29,154.52 215.43,149.67 199.41,149.67 199.13,149.39 199.13,148.93 v2(199.33,148.72)
USB20_P0: length 124.4
  IN2 w0.102: v2(102.56,116.21) 102.46,116.21 102.1,116.57 100.98,116.57 100.54,116.13 98.86,116.13 97.77,115.03 97.77,114.85 96.58,113.66 94.04,113.66 93.7,113.32 93.17,113.32 93.16,113.34 93.15,113.34
  IN2 w0.127: v2(47.19,60.08) 47.44,60.33 47.44,64.63 53.21,70.4 53.21,76.28 56.54,79.6 66.96,79.6 68.48,81.13 68.99,81.13 75.02,87.16 75.02,88.04 76.8,89.82 76.8,96.6 76.33,97.07 76.33,106.15 80.67,110.49 83.98,110.49 85.05,109.42 88.26,109.42 89.96,111.12 90.22,111.38 92.18,113.34 93.15,113.34
  BOTTOM w0.102: v2(102.56,116.21) 102.92,115.86 USOC1.M16 ; v2(47.19,60.08) 47.37,60.26 47.37,60.89 47.14,61.12 46.32,61.12 45.56,60.36 45.56,59.42 43.98,57.84 23.95,57.84 23.7,57.59 LI2.4
USB20_P1: length 129.4
  IN2 w0.102: v2(101.72,115.4) 101.49,115.4 101.22,115.67 99.61,115.67 98.83,114.9 98.83,114.42 97.42,113 94.88,113 93.77,111.89 93.55,111.67 93.53,111.67 93.51,111.65
  IN2 w0.127: 93.51,111.65 93.01,111.15 92.3,111.15 89.61,108.46 86.06,108.46 85.22,107.62 78.97,107.62 77.24,105.89 77.24,99.94 78.36,98.82 78.36,97.53 77.66,96.83 77.66,89.42 76.07,87.84 76.07,87.06 70.98,81.97 70.98,80.86 68.05,77.93 56.03,77.93 54.08,75.97 54.08,69.86 48.82,64.6 48.82,59.88 49.1,59.6 49.56,59.6 v2(49.69,59.47)
  BOTTOM w0.102: USOC1.J14 101.58,115.54 v2(101.72,115.4) ; LI5.4 23.87,45.65 24.06,45.84 24.93,45.84 25.3,46.21 v4(30.78,46.21) 31.85,46.21 32.31,46.67 37.26,46.67 45.22,54.63 45.22,55.83 49.04,59.65 49.51,59.65 v2(49.69,59.47)
USB20_P2: length 173.4
  IN2 w0.102: 107.73,133.3 107.75,133.28 107.75,133.26 108.91,132.1 108.91,131.41 109.95,130.37 109.95,129.57 109.79,129.41 109.79,128.8 110.19,128.39 110.19,127.27 111.33,126.13 111.33,124.22 108.36,121.24 105.81,121.24 103.64,119.07 101.68,119.07 100.92,118.32 100.92,117.97 100.29,117.33 100.29,117.06 100.49,116.86 100.64,116.86 100.77,116.99 v2(100.77,117.23)
  IN2 w0.127: v2(198.55,148.75) 198.82,148.75 198.91,148.84 198.91,150.24 192,157.15 166.1,157.15 158,149.04 124.72,149.04 119.12,143.44 113.78,143.44 111.61,141.27 111.61,140.55 109.97,138.91 109.16,138.91 107.32,137.06 107.32,133.71 107.73,133.3
  BOTTOM w0.102: LX6.4 217.87,166.49 218.16,166.2 218.16,165.94 218.38,165.72 219.42,165.72 220.07,165.07 220.07,154.61 215.34,149.88 199.32,149.88 198.91,149.48 198.91,148.84 198.82,148.75 v2(198.55,148.75) ; v2(100.77,117.23) 100.77,116.98 USOC1.K12
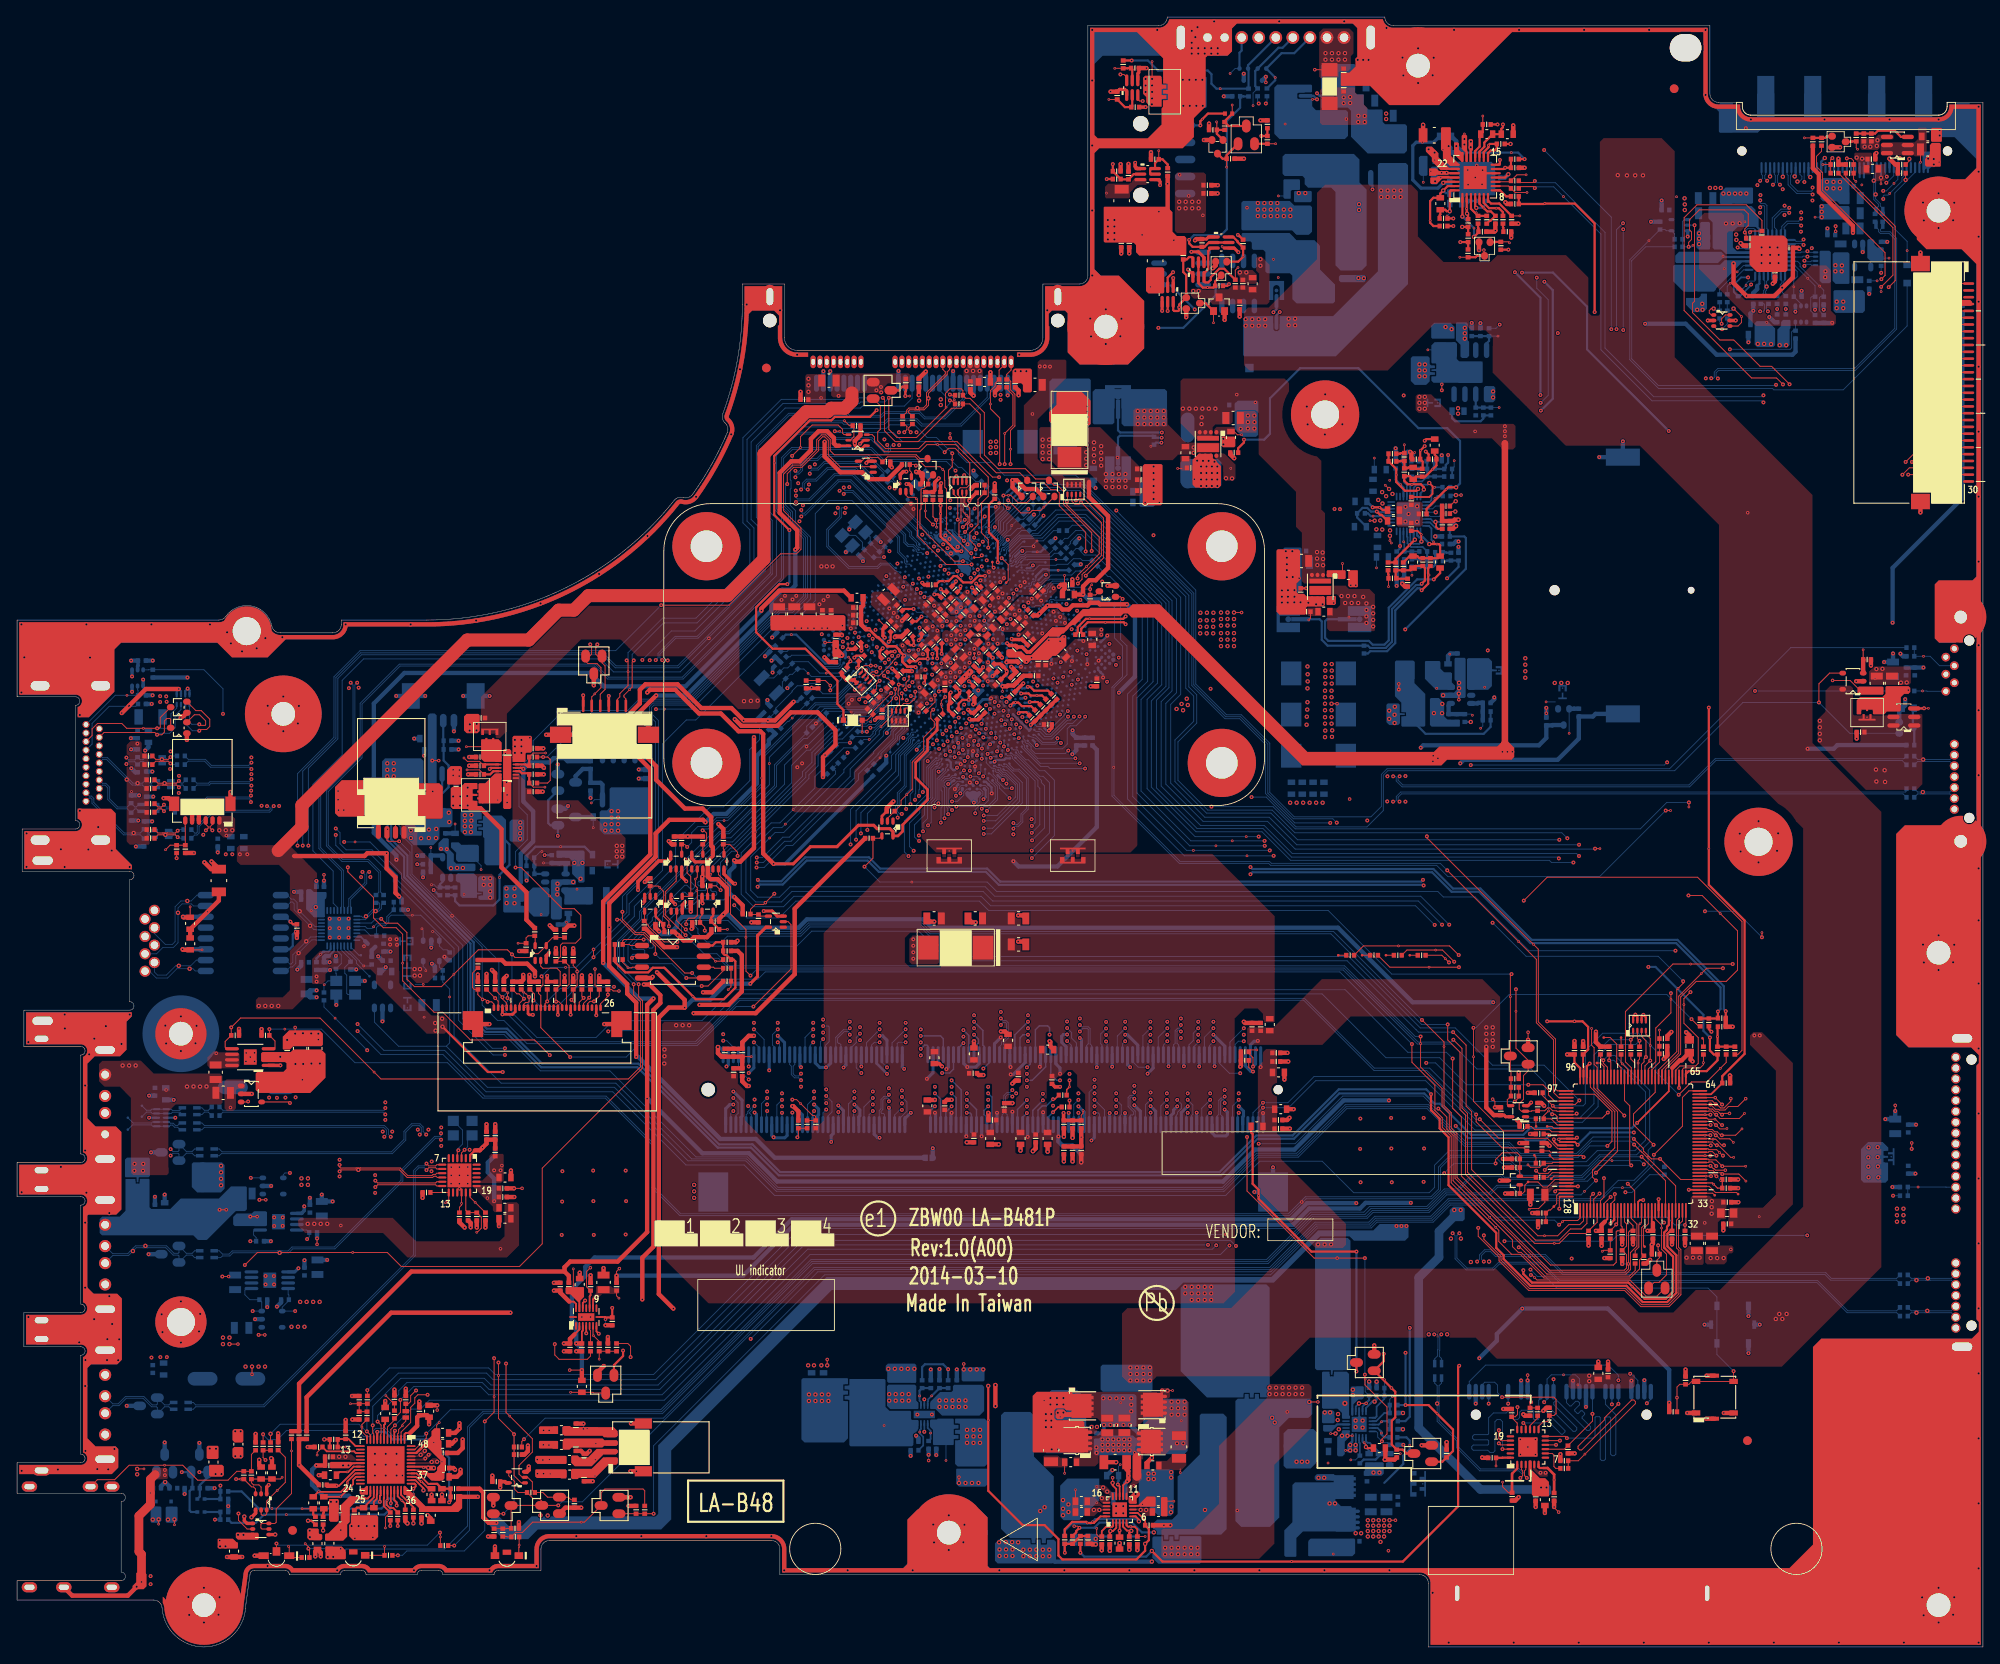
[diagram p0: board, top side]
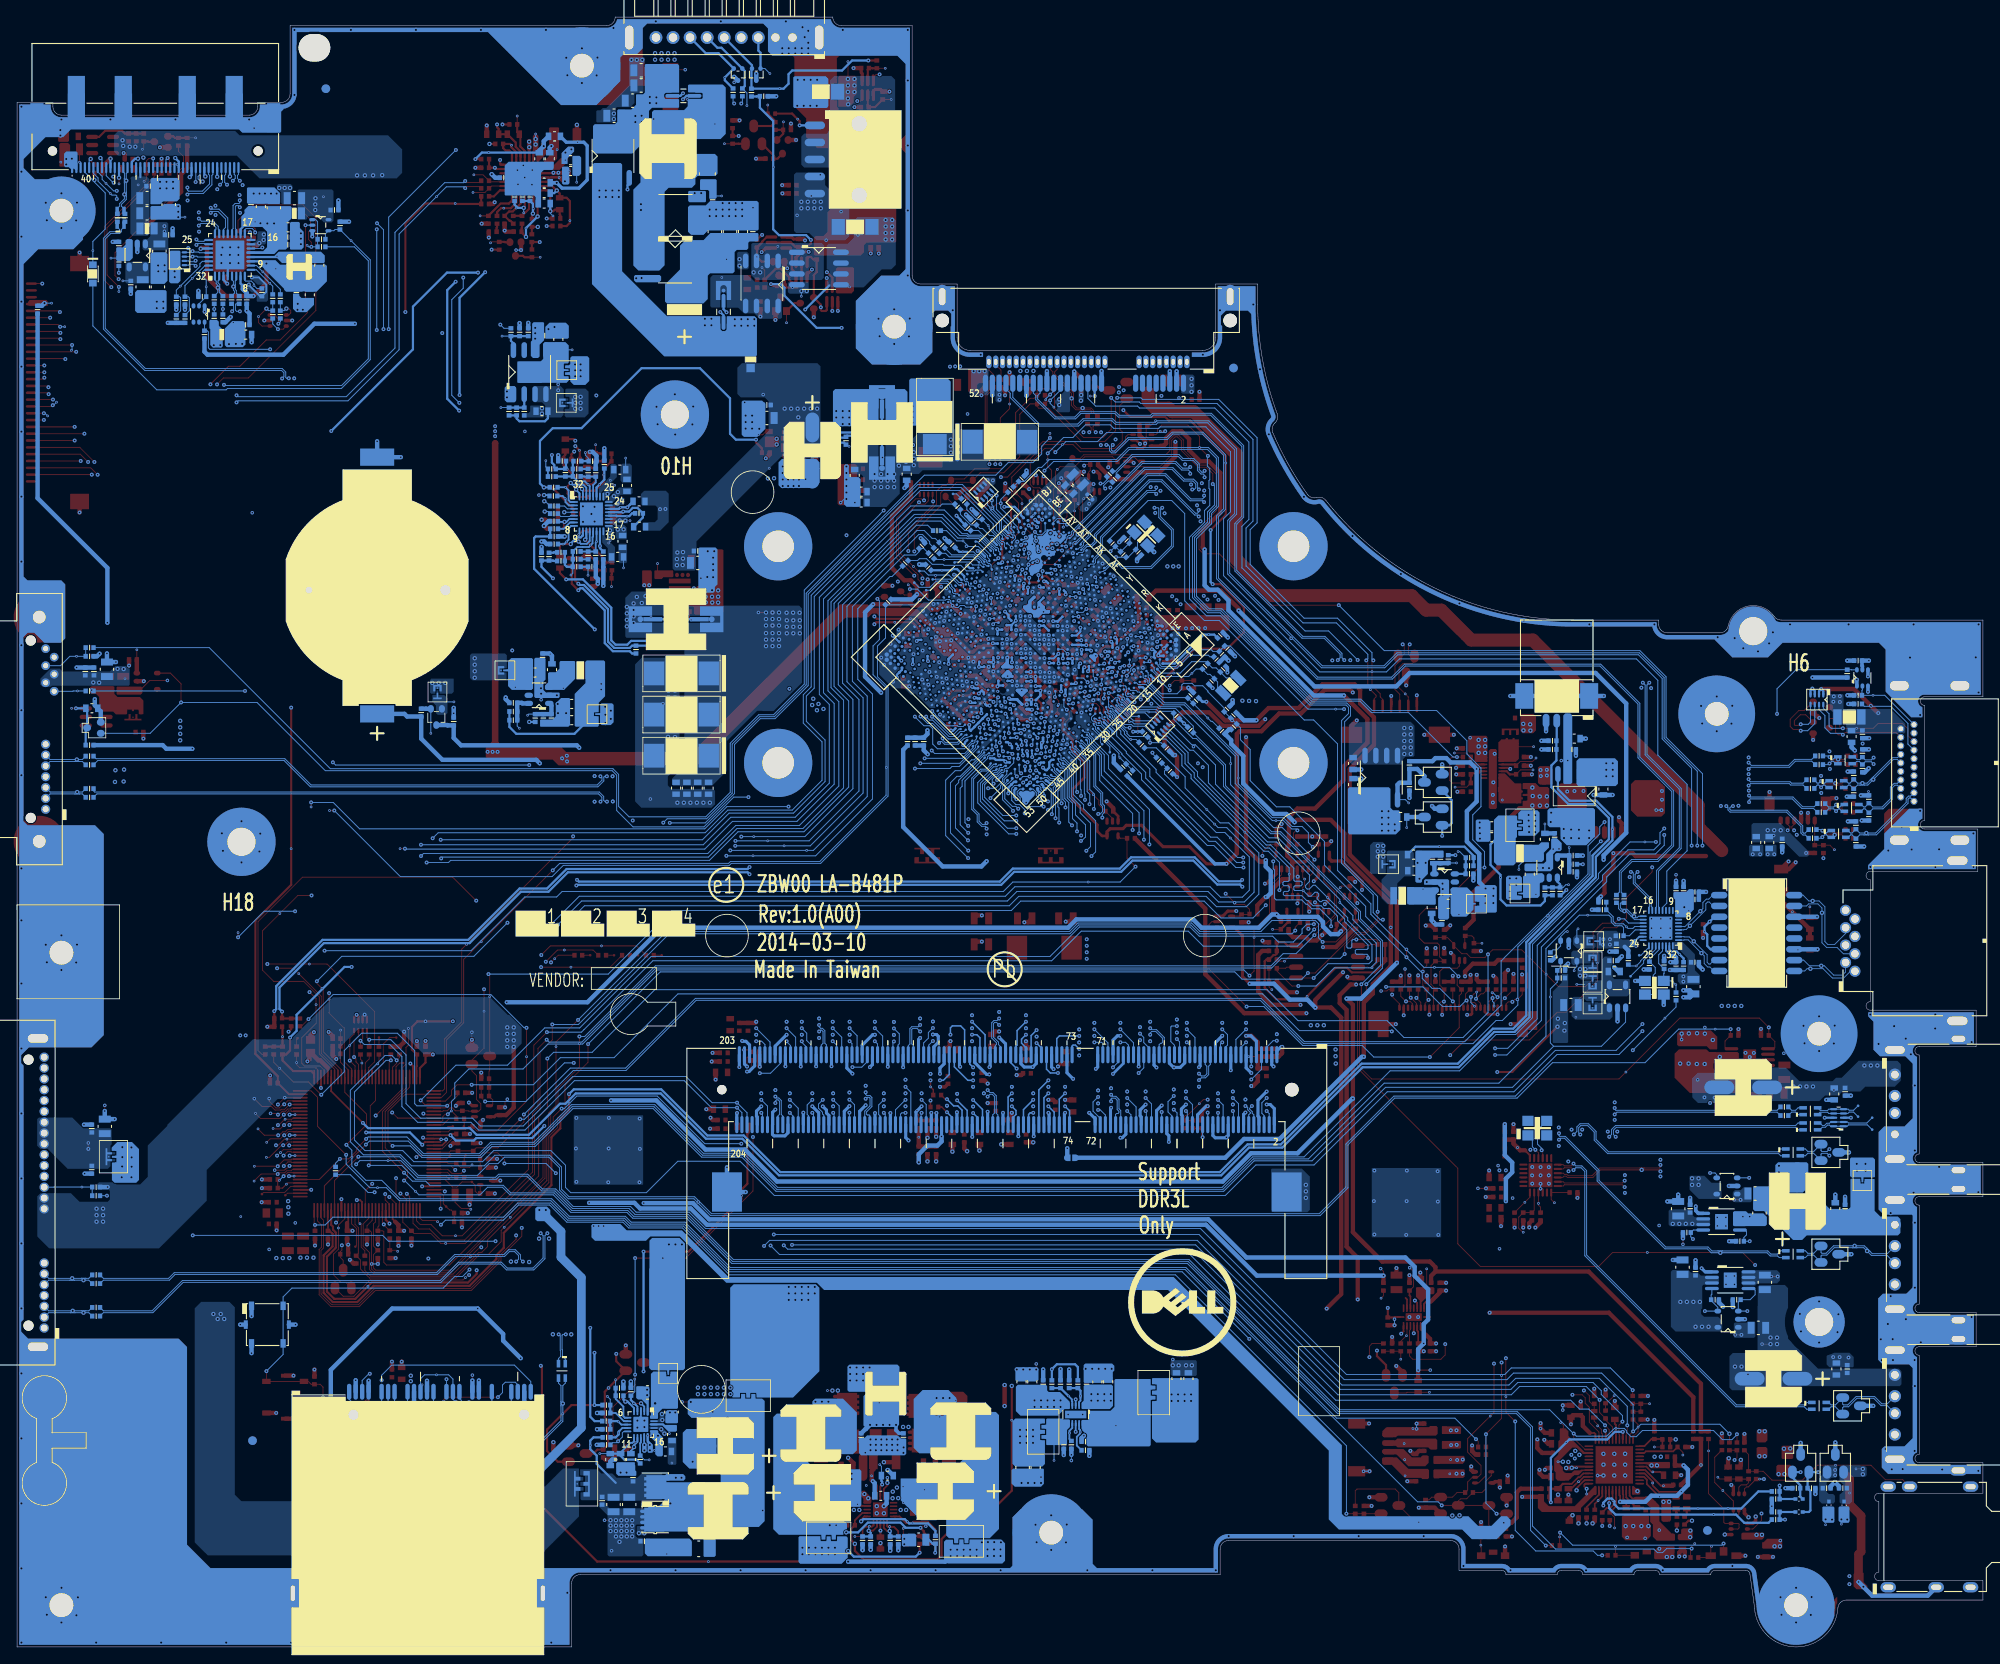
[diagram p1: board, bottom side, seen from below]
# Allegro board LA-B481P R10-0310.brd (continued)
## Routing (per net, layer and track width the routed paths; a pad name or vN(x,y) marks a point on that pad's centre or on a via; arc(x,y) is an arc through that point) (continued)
USB_EN#: length 237.4
  TOP w0.102: UI1.4 31.87,63.89 v2(31.98,63.78) ; v2(190.4,57.47) 193.19,54.68 UE1.26 ; v2(29.57,72.44) CI13.1 30.23,71.04 30.23,70.31 30.06,70.14 UI3.4
  IN2 w0.127: v2(29.57,72.44) 31.98,70.03 v2(31.98,63.78) v2(31.98,55.57) 31.98,48.94 33.1,47.83 v2(33.99,47.83) 33.99,47.67 32.41,46.09 32.41,39.56 v2(32.59,39.38)
  BOTTOM w0.102: UI6.4 31.77,41.35 31.86,41.26 CI29.1 31.86,40.61 31.07,39.83 UI5.4 v2(32.59,39.38) ; v2(31.98,55.57) 31.4,55.57 31.2,55.38 UI4.4 ; UI2.4 33.95,48.88 CI26.1 34.24,48.08 v2(33.99,47.83) ; v2(29.57,72.44) v1(31.39,72.44) 35.67,72.44 39.6,68.5 50.45,68.5 54.6,64.35 68.94,64.35 74.43,58.87 74.43,53.83 77.68,50.57 149.1,50.57 151.08,52.55 165.8,52.55 166.83,53.58 166.83,56.18 168.07,57.42 173.28,57.42 174.04,56.67 175.06,56.67 176.44,55.29 183.37,55.29 185.55,57.47 v2(190.4,57.47)
USB_OC0#: length 148.3
  TOP w0.102: UI3.5 24.58,70.14 24.39,70.33 24.39,70.99 CI15.1 v2(25.1,72.64) 26.19,73.73 35.51,73.73 v1(41.84,67.4) 42.65,66.59 71.64,66.59 73.08,68.03 73.08,75.64 72.27,76.45 v2(72.27,77.7) ; v2(27.08,63.96) 27.02,63.89 UI1.3
  IN2 w0.127: v2(25.1,72.64) 25.1,69.11 27.08,67.13 v2(27.08,63.96) 27.08,55.31 v2(27.39,55) 27.33,54.94 27.33,51.26 26.81,50.73 26.81,50.05 27.33,49.53 v2(27.33,47.57)
  BOTTOM w0.102: USOC1.C20 101.21,111.57 101.02,111.38 100.71,111.38 100.58,111.24 100.58,111.06 99.72,110.21 96.74,110.21 96.56,110.03 94.62,110.03 92.54,107.95 RC44.2 88.78,103.43 88.78,100.99 83.36,95.58 82.3,95.58 72.95,86.23 72.95,85.38 70.39,82.81 70.39,79.58 v2(72.27,77.7) ; UI2.5 27.88,48.88 27.71,48.72 27.71,48.31 28.02,48 CI17.1 v2(27.33,47.57) ; v2(27.39,55) UI4.3
USB_OC1#: length 134.7
  TOP w0.102: v2(72.85,77.7) 72.85,76.22 73.31,75.77 73.31,67.89 61.55,56.13 61.55,47.27 58.88,44.6 45.04,44.6 43.39,46.25 v1(39.34,46.25) 28.17,46.25 v2(26.7,44.78)
  IN2 w0.127: v2(27.61,39.38) 26.7,40.29 v2(26.7,44.78)
  BOTTOM w0.102: v2(27.61,39.38) UI5.3 28.67,40.44 CI28.1 27.28,40.71 26.7,41.3 26.7,41.83 26.89,42.03 UI6.5 ; v2(72.85,77.7) 70.62,79.93 70.62,82.72 73.18,85.29 73.18,86.14 82.39,95.35 83.45,95.35 89.01,100.9 89.01,103.33 92.19,106.52 92.59,106.52 94.84,108.76 RC46.2 95.05,109.7 96.65,109.7 96.88,109.93 99.73,109.93 USOC1.B20
USB_PLL_MON: length 2
  TOP w0.254: v2(102.17,117.86) 102.38,118.08 RC47.2
  BOTTOM w0.254: USOC1.M13 102.01,117.71 v2(102.17,117.86)
USB_RCOMP: length 2.9
  TOP w0.102: v2(97.39,116.97) v1(97.39,117.59)
  TOP w0.406: v2(97.39,116.97) 98.13,116.97 RC45.2
  BOTTOM w0.254: USOC1.C7 97.14,116.04 97.14,116.51 USOC1.D6 97.28,116.97 v2(97.39,116.97)
VCIN0_PH: length 51.1
  TOP w0.102: UE1.109 179.86,60.4 179.61,60.65 177.85,60.65 177.47,61.03 R696.1 176.48,60.5 174.17,60.5 170.69,63.98 v1(170.69,69.2) v2(170.69,72.59) ; v2(196.24,73.61) 197.08,72.77 PR13.2
  BOTTOM w0.102: v2(196.24,73.61) 193.35,76.5 174.88,76.5 171.02,72.64 170.74,72.64 v2(170.69,72.59)
VCIN1_PROCHOT: length 38.1
  TOP w0.102: v2(194.75,64.74) 196.24,66.24 198.02,66.24 v1(199.62,67.84) 200.31,68.53 PR15.2 ; R697.1 178.79,64.64 v2(179.99,63.45) 180.23,63.2 UE1.102
  BOTTOM w0.102: v2(194.75,64.74) 192.05,67.43 192.05,69.92 190.02,71.96 185.83,71.96 183.8,69.92 183.8,63.7 183.54,63.45 v2(179.99,63.45)
VCORE_GSNS: length 186
  TOP w0.102: v2(107.58,111.58) 107.58,110.78 RC58.1
  TOP w0.203: v4(165.51,136.47) 165.89,136.09 165.89,135.2 165.51,134.83 PC503.2 ; v4(164.6,129.61) 164.57,129.63 v1(164.57,130.43) 164.13,130.87 PC535.2
  IN2 w0.254: v4(165.51,136.47) 166.02,135.96 166.02,135.2 165.54,134.72 165.54,130.55 v4(164.6,129.61) 164.6,129 168.18,125.42 168.18,121.82 163.6,117.24 163.6,109.66 168.18,105.08 168.18,93.67 166.65,92.15 166.65,90.35 165.76,89.46 165.03,89.46 v2(164.85,89.28) ; v2(86.8,89.13) 87.06,89.39 87.34,89.39 87.79,89.84 87.79,94.44 93.12,99.77 93.12,101.75 93.88,102.51 96.58,102.51 101.2,107.13 101.2,107.69 101.74,108.23 105.41,108.23 106.18,108.99 106.18,110.86 106.89,111.58 v2(107.58,111.58)
  BOTTOM w0.203: v4(164.6,129.61) 164.33,129.34 163.62,129.34 163.34,129.62 163.28,129.68 PU500.12 ; PU500.30 163.68,135.92 164.04,136.27 165.31,136.27 v4(165.51,136.47)
  BOTTOM w0.254: v2(164.85,89.28) 164.77,89.36 115.06,89.36 113.54,90.88 101,90.88 99.68,92.2 92.54,92.2 89.73,89.39 87.06,89.39 v2(86.8,89.13) ; v2(107.58,111.58) 107.53,111.63 USOC1.N28
VCORE_VSNS: length 163
  TOP w0.102: v2(108.03,112.04) 108.13,112.14 RC56.2
  IN2 w0.254: v2(164.77,89.94) 164.87,89.84 165.61,89.84 166.27,90.5 166.27,92.31 167.8,93.83 167.8,104.93 163.22,109.5 163.22,117.4 167.8,121.97 167.8,125.09 v2(167.59,125.3) ; v2(86.82,89.93) 86.98,89.77 87.18,89.77 87.4,90 87.4,94.59 92.74,99.93 92.74,101.91 93.72,102.89 96.42,102.89 100.82,107.29 100.82,107.85 101.94,108.97 104.81,108.97 105.16,109.32 105.16,110.51 106.79,112.14 107.93,112.14 v2(108.03,112.04)
  BOTTOM w0.254: PR542.1 167.54,127.33 167.59,127.38 PC527.1 PC533.2 168.94,126.64 v2(167.59,125.3) ; v2(86.82,89.93) 86.98,89.77 89.57,89.77 92.38,92.58 99.84,92.58 101.16,91.26 113.7,91.26 115.22,89.74 164.57,89.74 v2(164.77,89.94) ; v2(108.03,112.04) USOC1.P28
VCOUT1_PH: length 239.2
  TOP w0.102: v2(176.58,87.5) 179.33,90.24 196.96,90.24 202.16,85.04 202.16,69.95 201.68,69.47 PR18.2 ; v2(175.67,77.11) v1(175.67,74.53) 175.67,70.2 177.09,68.78 Q50.2 177.09,67.54 176.56,67 176.56,64.21 176.05,63.7 176.05,63.07 176.3,62.81 UE2.2 177.48,62.81 177.53,62.86 RE47.2 179.04,62.86 179.37,63.19 179.65,63.19 179.98,62.86 180.43,62.86 180.5,62.8 UE1.103
  TOP w0.406: PR17.1 v2(132.26,180.54)
  IN2 w0.127: v2(175.67,77.11) 175.67,77.5 174.73,78.44 174.73,85.65 v2(176.58,87.5) 177.02,87.93 177.02,106.96 176.22,107.76 176.22,141.13 187.46,152.37 v2(187.46,154.51) ; v2(188.22,166.93) 188.22,170.2 175.87,182.55 163.15,182.55 160.15,185.54 141.66,185.54 141.3,185.19 133.2,185.19 132.64,184.63 131.65,184.63 131.17,185.11 129.16,185.11 128.63,184.58 128.63,183.44 131.52,180.54 v2(132.26,180.54)
  BOTTOM w0.102: v2(188.22,166.93) 187.46,166.16 v2(187.46,154.51)
VFB: length 4.9
  TOP w0.254: PU700.16 171.9,175.27 172.46,175.83 v1(172.46,176.07) 172.61,176.22 PR726.1 173.43,175.74 173.14,175.45 172.71,175.45 172.4,175.13 PU700.15
VGA_V1P35_S3_F1:
  vias: v1(106.06,134.03)
VGATE: length 77.7
  TOP w0.102: UE1.97 180.52,65.2 180.29,65.42 180.29,71.28 178.29,73.29 178.29,81.81 v1(177.71,82.38) 165.23,94.87 v2(165.23,95.04)
  IN2 w0.127: v2(165.23,95.04) 165.23,105.61 162.44,108.41 162.44,117.73 165.61,120.9 165.61,125.55 v2(162.08,129.08)
  BOTTOM w0.254: PR530.1 162.08,128.83 v2(162.08,129.08) PU500.15
VGFX_VSNS: length 83.8
  TOP w0.254: v2(110.67,128.47) 110.06,128.47 108.74,129.79 108.64,129.79 108.23,130.2 v1(108.23,132.87) v2(108.23,133.81) RC55.2
  IN2 w0.254: v2(108.23,133.81) 108.23,134.31 109.05,135.13 109.76,135.13 111.66,137.03 112.25,137.03 112.86,137.64 112.86,140.81 114.16,142.11 119.5,142.11 125.17,147.79 158.46,147.79 163.99,142.26 166.93,142.26 167.72,141.48 v2(167.72,139.75)
  BOTTOM w0.254: v2(110.67,128.47) 110.79,128.59 USOC1.BB8 ; v2(167.72,139.75) 167.72,138.86 167.44,138.58 167.44,138.29 PR501.2 166.17,138.11 PR504.2 166.06,138.22 PC502.1
VL: length 3.9
  TOP w0.203: v2(129.01,19.05) 129.23,18.83 PU100.13
  BOTTOM w0.102: PC117.1 129.1,21.18 v1(129.29,21.37)
  BOTTOM w0.254: PC117.1 129.1,19.47 129.01,19.38 v2(129.01,19.05)
VR_HOT#: length 85.3
  TOP w0.102: v2(175.54,63.96) 176,64.41 RE13.1 RE44.1
  TOP w0.203: PR525.1 166.55,131.1 166.32,131.33 166.32,131.91 v4(166.24,131.91)
  IN2 w0.127: v4(166.24,131.91) 166.98,131.17 166.98,128.6 169.07,126.52 169.07,114.31 170.84,112.53 170.84,90.27 165.15,84.58 v2(165.15,68.48)
  BOTTOM w0.102: v2(165.15,68.48) 166.25,68.48 170.77,63.96 v2(175.54,63.96)
  BOTTOM w0.203: PU500.6 165.68,132.24 166.01,131.91 v4(166.24,131.91) 166.94,131.91 PC520.1
VR_ON: length 102
  TOP w0.102: v4(168.63,135.05) v3(169.24,135.05) ; RE12.2 176.24,55.07 DE1.3 176.12,56.2 CE34.1 RE1.2 176.13,57.63 175.82,57.94 174.07,57.94 173.28,57.15 v2(173.28,56.69)
  IN2 w0.127: v4(168.63,135.05) 169.49,135.05 171.83,132.71 171.83,115.38 173.64,113.57 173.64,89.71 166.13,82.2 166.13,67.2 167.76,65.57 167.76,56.04 v2(167.26,55.55)
  BOTTOM w0.102: v2(173.28,56.69) 168.41,56.69 v2(167.26,55.55)
  BOTTOM w0.203: v4(168.63,135.05) 168.1,135.05 PR516.1
VR_ON_EC: length 2.9
  TOP w0.102: RE12.1 179.39,55.07 179.93,55.6 UE1.121
VR_ON_R: length 2.6
  BOTTOM w0.203: PU500.2 165.74,133.84 166.12,134.22 166.12,134.61 v1(166.17,134.66) 166.46,134.95 PR516.2
VR_SVID_ALERT#: length 161.2
  IN2 w0.127: v2(167.01,84.68) 172.01,89.69 172.01,113.55 170.67,114.89 170.67,132.13 169.06,133.73 166.96,133.73 v4(166.27,133.04)
  BOTTOM w0.102: RC28.2 RC27.2 95.91,102.7 95.91,102.34 v1(90.05,96.48) 89.63,96.06 88.62,96.06 85.42,92.86 85.42,88.49 86.56,87.35 89.59,87.35 90.81,88.57 113.23,88.57 114.34,87.46 164.23,87.46 v2(167.01,84.68) ; v4(166.27,133.04) PU500.4
VR_SVID_ALERT#_SOC: length 8.3
  IN2 w0.102: 98.89,107.33 99.34,107.77 v2(100,107.77)
  IN2 w0.127: v2(97.34,104.85) 98.63,106.14 98.63,107.07 98.89,107.33
  BOTTOM w0.102: v2(97.34,104.85) 97.34,104.75 RC28.1 ; USOC1.B24 101.8,109.25 101.8,109.08 100.49,107.77 v2(100,107.77)
VR_SVID_CLK: length 168.5
  TOP w0.102: v4(168.61,134.33) 168.5,134.33 PR527.1
  IN2 w0.127: v2(167.85,84.68) 172.6,89.43 172.6,113.79 171.25,115.14 171.25,132.38 169.3,134.33 v4(168.61,134.33)
  BOTTOM w0.102: USOC1.C25 102.85,109.43 102.64,109.22 102.64,108.98 101.04,107.38 101.04,107.02 96.9,102.88 96.9,102.54 89.86,95.5 88.85,95.5 v1(88.2,94.85) 85.98,92.63 85.98,88.72 86.8,87.91 89.36,87.91 90.58,89.13 113.46,89.13 114.57,88.02 164.51,88.02 v2(167.85,84.68) ; v4(168.61,134.33) 168.5,134.33 PR527.1
VR_SVID_CLK_R: length 2
  BOTTOM w0.102: PU500.3 165.91,133.44 166.23,133.77 PR520.2
VR_SVID_DATA: length 161.3
  TOP w0.102: v4(168.56,133.13) 168.18,133.13 PR526.1
  IN2 w0.127: v2(166.14,84.66) 171.43,89.94 171.43,113.3 170.08,114.65 170.08,131.82 168.78,133.13 v4(168.56,133.13)
  BOTTOM w0.102: PR526.1 168.18,133.13 v4(168.56,133.13) ; RC29.2 96.89,105.41 93.5,102.03 93.5,100.72 v1(90.96,98.17) 89.4,96.62 88.39,96.62 84.86,93.09 84.86,88.26 86.33,86.79 89.82,86.79 91.04,88.01 113,88.01 114.11,86.9 163.9,86.9 v2(166.14,84.66)
VR_SVID_DATA_R: length 2.1
  BOTTOM w0.102: PU500.5 165.53,132.64 165.64,132.54 166.67,132.54 PR521.2
VR_SVID_DATA_SOC: length 4.9
  BOTTOM w0.102: 102.33,109.09 102.33,109.03 100.62,107.33 100.62,107.05 99.97,106.4 v1(99.88,106.4) 99.24,106.4 RC29.1
VSUM+: length 9.8
  TOP w0.254: PC529.1 163.21,127.9 PC530.1 164.11,127.9 164.35,127.66 PR541.1 PR535.1 166.54,127.66 PR536.2 166.78,129.16 166.63,129.31 v1(166.41,129.31) v4(165.51,129.31)
  BOTTOM w0.254: v4(165.51,129.31) 165.51,129.38 164.8,130.09 164.34,130.09 164.15,130.27 164.08,130.34 PU500.10
VSUM-: length 30.3
  TOP w0.254: v2(164.62,124.66) 165,125.04 165,126.49 PR541.2 163.85,126.74 PC530.2 163.34,126.24 PC529.2 PR540.2 161.57,125.37 PC532.2 161.7,125.25 PC534.1
  BOTTOM w0.254: v2(164.62,124.66) 164.47,124.51 163.96,124.51 161.14,121.69 161.14,117.86 160.41,117.13 158.59,117.13 158.32,117.4 PH503.2 153.6,117.4 152.91,118.08 152.91,120.24 152.66,120.5 PL501.3
VSUMG+: length 10.8
  TOP w0.254: v4(164.87,135.71) 164.87,135.96 164.52,136.32 163,136.32 162.58,136.74 162.58,137.27 PC514.2 163.24,137.29 PC513.2 163.95,137.22 PR509.2 165.03,137.22 v1(165.91,138.09) 166.35,138.53 PR500.2 166.35,139.57 166.14,139.77 PR513.2
  BOTTOM w0.203: PU500.32 164.48,135.27 164.87,135.66 v4(164.87,135.71)
VSUMG-: length 52.8
  TOP w0.254: v2(164.98,140.79) v1(164.49,140.31) 164.44,140.26 PC512.1 164.74,138.97 164.74,138.18 PR509.1 163.79,138.13 PC513.1 163.07,138.3 162.97,138.2 PC514.1 PR502.2 162.13,139.06 162.08,139.01 PR507.1
  IN2 w0.254: v2(164.98,140.79) 164.57,140.79 164.32,141.04 163.41,141.04 162.09,142.36 159.59,142.36 158.19,140.97 151.09,140.97 145.42,146.63 136.27,146.63 135.56,145.92 135.56,142.62 134.73,141.78 v2(134.15,141.78)
  BOTTOM w0.254: PL500.3 129.03,141.8 129.24,142.01 133.12,142.01 PH500.1 133.35,141.78 v2(134.15,141.78)
VTTREF_1.35VP: length 4.3
  BOTTOM w0.102: v1(158,31.4) 158,29.92 PC212.1
  BOTTOM w0.203: 157.89,28.38 157.69,28.19 PU200.4
  BOTTOM w0.254: PC212.1 158.46,28.95 157.89,28.38
WL_BT_LED: length 134.5
  TOP w0.102: v2(74.6,15.62) RD53.1 RD50.1 QD20.2 ; UE1.1 183.19,50.29 182.91,50.01 181.27,50.01 v1(181.12,49.86) 180.76,49.5 v2(180.72,49.5)
  BOTTOM w0.102: v2(180.72,49.5) 180.19,50.04 173.4,50.04 171.63,51.81 167.97,51.81 165.97,49.81 159.4,49.81 158.71,49.12 152.41,49.12 146.91,43.63 94.64,43.63 74.6,23.59 v2(74.6,15.62)
WL_BT_LED#: length 21.7
  TOP w0.102: RD53.2 73.56,18.31 73.36,18.51 68.89,18.51 68.46,18.08 QD20.1 66.5,14.63 v1(66.12,14.63) 60.43,14.63 59.21,13.41 58.44,13.41 RD18.1 57.43,12.9 57.38,12.95 RD51.2
WL_BT_LED#_EC: length 173.3
  TOP w0.102: RD52.1 RD51.1 57.39,13.87 57.43,13.9 RD46.2 57.9,16.58 QD18.1 57.92,16.6 QD19.1 ; UE1.64 195.94,65.2 195.18,64.44 195.18,61.04 v2(191.83,57.7) ; v2(63.43,16.6) QD19.1 ; QD19.1 61.48,17.1 61.22,17.37 60.51,17.37 RD49.2 58.7,18.11 58.32,18.49 58.32,19.38 57.63,20.07 UD1.4
  BOTTOM w0.102: v2(63.43,16.6) 63.85,17.02 66.26,17.02 93.51,44.26 146.9,44.26 152.22,49.58 158.52,49.58 159.21,50.26 165.78,50.26 167.84,52.32 185.59,52.32 187.12,53.85 v1(188.15,53.85) 189.06,53.85 191.83,56.62 v2(191.83,57.7)
WL_BT_LED#_EC2: length 158.8
  TOP w0.102: v2(59.41,24.36) 59.16,24.1 RD48.2 ; v2(191.8,58.88) 189.45,61.22 189.45,62.49 191.99,65.03 UE1.74
  BOTTOM w0.102: v2(191.8,58.88) 191.16,58.24 v1(191.16,57.4) 191.16,56.36 189.51,54.71 187.66,54.71 185.5,52.55 167.74,52.55 165.68,50.49 159.11,50.49 158.43,49.81 152.12,49.81 146.81,44.49 93.41,44.49 75.74,26.82 61.88,26.82 v2(59.41,24.36)
WL_LED#: length 224.4
  TOP w0.102: QD18.3 v2(57,15.62) ; v2(56.42,33.35) v1(56.42,31.82) 56.42,26.79 58.25,24.97 v2(58.25,24.94) RD48.1 RD45.2 58.25,20.09 59.1,19.24 UD1.1
  IN2 w0.127: v2(33.48,93.95) 40.47,86.97 40.47,79.62 41.84,78.25 41.84,76.15 38.08,72.39 38.08,58.19 39.11,57.17 39.11,51.31 56.42,34 v2(56.42,33.35)
  BOTTOM w0.102: v2(57,15.62) 58.25,16.86 v2(58.25,24.94) ; JMINI.44 113.7,146.51 110.57,143.38 106.09,143.38 105.46,144 102,144 101.58,143.58 96.97,143.58 96.8,143.76 90.73,143.76 87.47,140.5 87.47,132.8 88.28,131.99 88.28,125.89 77.42,115.03 70.2,115.03 68.68,116.56 40.27,116.56 37.37,113.66 37.37,106.57 33.48,102.68 v2(33.48,93.95)
WL_OFF#: length 195
  TOP w0.102: v2(115.09,137.16) 114.33,137.16 110.16,141.32 106.49,141.32 105.66,140.5 101.79,140.5 100.87,141.42 100.87,142.47 101.17,142.77 101.17,145.53 QM30.3 ; RP54.3 v2(124.1,134.44) 124.26,134.44 124.44,134.62 125.07,134.62 127.33,132.36 127.33,127.68 v2(125.25,125.6) ; RE14.1 189.64,44.14 188.99,43.48 179.06,43.48 176.27,46.26 175.94,46.26 175.28,46.92 175.28,47.7 v1(172.6,50.38) 168.3,54.67 168.3,59.98 167.57,60.72 167.57,62.13 v2(166.58,63.12)
  IN2 w0.102: 122.05,126.1 120.95,126.1 120.81,126.24 120.42,126.24 117.69,123.51 v2(116.77,123.51)
  IN2 w0.127: v2(145.52,59) 145.52,62.28 144.53,63.27 144.53,66.11 146.43,68.02 146.43,90.65 143.87,93.22 143.87,99.97 144.43,100.53 144.43,106.54 131.73,119.24 131.73,121.54 127.83,125.44 125.42,125.44 v2(125.25,125.6) 125.14,125.72 124.17,125.72 123.79,126.1 122.05,126.1 ; v2(124.1,134.44) 122.94,135.61 119.87,135.61 117.74,137.74 115.68,137.74 v2(115.09,137.16)
  BOTTOM w0.102: v2(145.52,59) 149.79,59 155.38,64.59 164.8,64.59 166.27,63.12 v2(166.58,63.12) ; USOC1.BA26 116.72,123.46 v2(116.77,123.51)
WL_OFF#_EC: length 5.6
  TOP w0.102: RE14.2 189.64,46.46 190.07,46.89 190.07,49.48 v1(190.21,49.62) 190.39,49.8 UE1.19
WLAN_CLKREQ#: length 38.5
  TOP w0.102: v2(95.84,142.54) v1(96.42,142.54) ; v2(110.98,129.69) 110.39,130.27 110.39,131.77 110.63,132.01 110.63,134.71 110.27,135.07 RP63.2 110.27,135.64 110.54,135.91 111.28,135.91 111.66,136.29 111.66,138.82 109.94,140.54 109.17,140.54 v2(108.72,140.08)
  IN2 w0.127: v2(95.84,142.54) 95.84,145.54 96.8,146.51 96.8,147.72 95.84,148.69 95.84,149.76 95.7,149.89 JMINI.7
  BOTTOM w0.102: v2(108.72,140.08) 107.47,141.32 103.76,141.32 102.7,142.39 95.99,142.39 v2(95.84,142.54) ; v2(110.98,129.69) 110.98,129.82 111.08,129.92 USOC1.BD7
WLAN_RADIO_DIS#_R: length 5.1
  TOP w0.102: v2(104.1,146.66) v1(104.62,146.66)
  TOP w0.254: QM30.1 103.32,147.33 103.75,147.76 RM110.2 104.17,147.24 104.1,147.17 v2(104.1,146.66)
  BOTTOM w0.254: JMINI.20 v2(104.1,146.66)
WOL_EN: length 182.4
  TOP w0.102: v2(186.39,58.75) 186.92,59.28 186.92,62.78 184.9,64.8 UE1.98
  BOTTOM w0.102: 50.31,70.43 50.7,70.82 v1(50.7,76.21) 50.7,77.14 49.89,77.95 RL38.1 RL27.2 49.49,79.72 UL3.4 ; 50.31,70.43 55.13,65.61 70.01,65.61 78.63,57 85.41,57 88.98,53.42 141.45,53.42 145.46,57.43 150.16,57.43 155.85,63.12 165.24,63.12 169.69,58.67 174.75,58.67 176.04,57.38 182.94,57.38 184.31,58.75 v2(186.39,58.75) ; 50.31,70.43 44.71,70.43 41.88,73.26 UL2.3
XDP_H_PRDY#: length 75.3
  TOP w0.102: v2(98.69,111.1) 98.97,111.37 RC65.2 ; CC52.1 v2(56.04,76.07) 56.38,75.72 JDB1.2
  IN2 w0.102: 96.06,109.78 97.38,109.78 v2(98.69,111.1)
  IN2 w0.127: v2(56.04,76.07) 56.87,76.91 64.57,76.91 66.48,75 74.24,75 75.06,75.82 75.06,76.74 81.54,83.22 81.54,86.4 81.27,86.66 81.27,90.78 80.9,91.15 80.9,93.32 88.81,101.23 88.81,104.02 91.73,106.93 93.21,106.93 96.06,109.78
  BOTTOM w0.102: v2(98.69,111.1) 98.86,111.26 99.7,111.26 99.91,111.46 100.34,111.46 100.49,111.61 100.49,111.94 100.39,112.05 100.39,112.27 100.42,112.58 100.54,112.69 USOC1.D18
XDP_H_PREQ_BUF#: length 80.6
  TOP w0.102: v2(101.1,113.28) 100.72,112.91 100.72,112.35 RC25.2 ; JDB1.1 55.88,75.39 55.63,75.64 v2(55.15,75.64) 54.87,75.92 v3(54.56,75.92) 54,76.48 CC50.1 53.6,77.09 53.37,77.32 53.37,78.99 RC61.2
  IN2 w0.102: 96.83,111.12 97.13,111.43 98.5,111.43 98.61,111.53 98.99,111.53 100.74,113.28 v2(101.1,113.28)
  IN2 w0.127: v2(55.15,75.64) 55.15,75.94 56.37,77.16 64.68,77.16 66.58,75.26 73.22,75.26 81.28,83.33 81.28,86.29 81.02,86.56 81.02,90.68 80.65,91.05 80.65,93.43 84.51,97.29 84.51,97.81 88.56,101.86 88.56,104.12 93.15,108.71 94.42,108.71 96.83,111.12
  BOTTOM w0.102: v2(101.1,113.28) 100.9,113.47 USOC1.F16
XDP_H_TCK: length 59.4
  TOP w0.102: JDB1.26 68.38,75.41 69.24,76.27 v2(69.24,76.48) CC65.1 69.69,77.09 69.86,76.91 v3(70.54,76.91) ; v2(99.5,114.53) 99.5,114.12 RP66.7
  IN2 w0.102: v2(99.5,114.53) 99.5,114.4 97.34,112.24 96.45,112.24 95.63,111.43
  IN2 w0.127: v2(69.24,76.48) 73,76.48 79.53,83.01 79.53,85.77 79.38,85.93 79.38,93.13 79.53,93.28 79.53,96.57 92.74,109.78 93.98,109.78 95.63,111.43
  BOTTOM w0.102: v2(99.5,114.53) 99.5,114.29 USOC1.D14
XDP_H_TDI: length 66.3
  TOP w0.102: RP66.5 100.33,113.54 v2(100.33,113.87) 101.04,113.87 102.62,115.44 102.62,115.56 v3(103.27,116.2) ; CC61.1 67.21,76.27 v2(67.06,76.12) 66.38,75.44 JDB1.22
  IN2 w0.102: v2(100.33,113.87) 98.78,112.32 98.78,112.28 98.34,111.83 96.78,111.83 94.16,109.22 93.68,109.22
  IN2 w0.127: 93.68,109.22 92.93,109.22 88.05,104.33 88.05,102.07 83.99,98.01 83.99,97.49 80.09,93.59 80.09,92.85 79.89,92.64 79.89,86.14 80.09,85.93 80.09,82.85 73.03,75.79 68.33,75.79 68,76.12 v2(67.06,76.12)
  BOTTOM w0.102: USOC1.F12 99.5,115.08 99.88,114.7 99.88,114.42 100.33,113.97 v2(100.33,113.87)
XDP_H_TDO: length 70.9
  TOP w0.102: JDB1.20 65.38,75.46 v2(64.98,75.87) 65.18,76.07 CC56.1 65.64,77.54 v3(65.64,79.2) 65.64,79.42 65.18,79.88 RC63.2 ; RC64.2 102.1,113.54 101.94,113.54 v2(101.61,113.87)
  IN2 w0.102: 96.11,109.47 97.82,109.47 98.85,110.51 98.85,110.71 99.08,110.94 99.08,111.11 100.05,112.09 100.1,112.09 100.92,112.9 101.46,112.9 101.61,113.05 v2(101.61,113.87)
  IN2 w0.127: v2(64.98,75.87) 66.09,74.75 74.35,74.75 75.31,75.72 75.31,76.64 81.79,83.11 81.79,86.53 81.52,86.79 81.52,90.89 81.16,91.26 81.16,93.22 89.07,101.13 89.07,103.91 91.83,106.68 93.32,106.68 96.11,109.47
  BOTTOM w0.102: v2(101.61,113.87) 101.41,114.07 USOC1.G16
XDP_H_TMS: length 65.8
  TOP w0.102: v2(100.72,114.33) 100.21,114.33 99.72,113.84 99.72,113.64 RP66.6 ; JDB1.23 66.88,75.44 67.14,75.69 v2(67.62,75.69) 68.23,76.3 CC63.1 67.73,77.58 v3(67.73,79.49)
  IN2 w0.102: v2(100.72,114.33) 100.72,113.69 98.79,111.76 98.55,111.76 98.42,111.63 97.01,111.63 96.78,111.4
  IN2 w0.127: 96.78,111.4 94.35,108.96 93.04,108.96 88.3,104.23 88.3,101.96 84.25,97.9 84.25,97.38 80.39,93.53 80.39,90.94 80.76,90.57 80.76,86.45 81.03,86.19 81.03,83.43 73.14,75.54 67.77,75.54 v2(67.62,75.69)
  BOTTOM w0.102: v2(100.72,114.33) 100.51,114.54 USOC1.F14
XDP_H_TRST#: length 64.2
  TOP w0.102: JDB1.21 65.88,75.58 v2(66.4,76.1) 66.2,76.3 CC59.1 ; RP66.8 99.06,114.4 99.06,114.83 99.29,115.06 v2(100.07,115.06) 100.09,115.03 v3(100.63,115.03)
  IN2 w0.102: v2(100.07,115.06) 100.07,114.49 98.73,113.15 98.56,113.15 97.44,112.04 96.6,112.04 95.81,111.25
  IN2 w0.127: 95.81,111.25 94.09,109.52 92.84,109.52 79.84,96.51 79.84,93.23 79.63,93.03 79.63,86.03 79.78,85.88 79.78,82.9 72.93,76.05 68.43,76.05 67.83,76.66 66.96,76.66 v2(66.4,76.1)
  BOTTOM w0.102: v2(100.07,115.06) 100.01,115.12 USOC1.G12
XDP_OBSDATA_A0: length 81.6
  TOP w0.102: CC55.1 56.04,77.04 v2(56.89,76.19) 56.89,75.98 57.38,75.49 JDB1.4
  IN2 w0.102: v2(104.94,113.11) 104.96,113.09 104.96,112.44 102.75,110.23 101.07,110.23 98.45,107.62 97.74,107.62
  IN2 w0.127: 97.74,107.62 97.13,107.62 94.16,104.65 93.77,104.65 91.53,102.41 91.53,100.43 83.63,92.53 83.63,86.78 83.95,86.46 83.95,83.72 83.57,83.34 83.57,81.46 73.51,71.4 60,71.4 57.51,73.89 57.51,74.88 56.89,75.5 v2(56.89,76.19)
  BOTTOM w0.102: v1(57.52,76.71) 57.41,76.71 v2(56.89,76.19) ; USOC1.N24 105.43,113.6 v2(104.94,113.11)
XDP_OBSDATA_A1: length 81
  TOP w0.102: JDB1.5 57.88,75.67 v2(57.47,76.08) 57.47,76.67 CC58.1
  IN2 w0.102: v2(103.97,113.49) 103.97,112.8 102.09,110.92 101.02,110.92 98.2,108.1 97.21,108.1
  IN2 w0.127: 97.21,108.1 96.9,108.1 93.95,105.15 92.46,105.15 90.66,103.35 90.66,100.56 82.76,92.66 82.76,91.94 83.38,91.31 83.38,86.67 83.7,86.35 83.7,83.82 83.32,83.44 83.32,81.56 73.41,71.65 60.1,71.65 57.88,73.87 57.88,75.67 v2(57.47,76.08)
  BOTTOM w0.102: v2(57.47,76.08) 57.47,75.69 57.29,75.51 v1(57.29,75.13) ; USOC1.M20 104.28,113.8 v2(103.97,113.49)
XDP_OBSDATA_A2: length 75.3
  TOP w0.102: CC60.1 58.58,76.58 58.83,76.58 v2(59.41,75.99) 58.88,75.46 JDB1.7
  IN2 w0.102: 96.24,109.24 98,109.24 98.99,110.23 99.43,110.23 100.49,111.28 100.49,112.09 100.99,112.6 101.76,112.6 102.06,112.9 v2(102.06,114.32)
  IN2 w0.127: 96.24,109.24 93.42,106.42 91.94,106.42 89.32,103.81 89.32,101.02 81.41,93.11 81.41,91.36 81.78,90.99 81.78,86.9 82.05,86.63 82.05,83.01 75.57,76.53 75.57,75.61 74.45,74.5 65.69,74.5 63.53,76.66 59.69,76.66 59.41,76.38 v2(59.41,75.99)
  BOTTOM w0.102: USOC1.J18 102.22,114.16 v2(102.06,114.32) ; v2(59.41,75.99) 59.34,76.07 v1(59.34,76.78)
XDP_OBSDATA_A3: length 76.5
  TOP w0.102: JDB1.8 59.38,75.35 59.59,75.56 59.87,75.56 60.01,75.7 v2(60.01,76.21) 59.64,76.59 59.59,76.59 CC62.1
  IN2 w0.102: v2(102.99,115.3) 102.99,113.29 101.18,111.49 100.98,111.49 99.44,109.95 99.14,109.95 98.17,108.99 96.35,108.99
  IN2 w0.127: v2(60.01,76.21) 60.2,76.4 63.43,76.4 66.22,73.61 68.02,73.61 68.66,74.24 74.56,74.24 75.82,75.51 75.82,76.43 82.3,82.9 82.3,86.74 82.03,87.01 82.03,91.22 81.74,91.52 81.74,93.08 89.57,100.92 89.57,103.7 92.04,106.17 93.53,106.17 96.35,108.99
  BOTTOM w0.102: v1(59.59,75.12) 60.01,75.55 v2(60.01,76.21) ; USOC1.M18 103.12,115.16 v2(102.99,115.3)
XDP_RSTBTN#: length 123.4
  TOP w0.102: v2(58.42,91.39) 59.08,91.39 v1(62.42,88.05) 63.91,86.56 65.31,86.56 66.07,85.8 66.07,83.13 65.46,82.52 63.94,82.52 63.68,82.27 63.68,80.92 RC62.2 CC53.1 64.7,79.86 64.7,77.7 64.16,77.16 CC49.1 64.38,76.87 JDB1.18
  BOTTOM w0.102: v2(58.42,91.39) 58.42,93.27 59.8,94.64 59.8,97.56 58.83,98.52 58.83,103.05 60.48,104.7 60.48,106.25 64.04,109.8 71.58,109.8 72.9,111.13 78.61,111.13 89.2,121.71 90.67,121.71 92.18,123.22 92.18,129.92 90.43,131.67 90.43,132.88 89.61,133.7 89.61,139.46 90.79,140.64 100.14,140.64 101.56,139.22 109.4,139.22 110.32,138.3 110.7,138.3 112.34,136.66 CC12.1 RC24.2
XTAL_25M_IN: length 13.8
  IN2 w0.127: v2(106.33,123.09) 107.04,123.8 107.04,124.46 106.2,125.3 106.2,125.91 103.64,128.47 v2(102.24,128.47)
  BOTTOM w0.102: v2(106.33,123.09) 106.41,123.17 USOC1.AH12 ; v2(102.24,128.47) 101.69,129.02 RG10.2 RC19.1 101.04,128.41 CC9.1 99.98,129.48 99.98,130.15 YC1.1
XTAL_25M_OUT: length 14.2
  IN2 w0.127: v2(101.6,127.79) 101.96,127.43 103.76,127.43 105.29,125.91 105.29,124.92 106.05,124.15 106.05,123.73 v2(105.9,123.58)
  BOTTOM w0.102: v2(105.9,123.58) 105.99,123.67 USOC1.AH10 ; YC1.3 98.27,130.33 99.09,129.51 99.09,128.86 CC10.1 100.19,127.77 RC19.2 101.59,127.77 v2(101.6,127.79)
XTLI: length 7.1
  BOTTOM w0.102: UL1.29 37.55,81.6 38,81.15 38,80.13 CL36.2 37.37,78.97 37.41,78.92 YL2.1 36.44,78.09 v1(36,77.65) 35.97,77.62 RG11.2
XTLI_L: length 71.7
  TOP w0.102: v2(71.91,33.98) 71.91,35.26 71.58,35.58 RG8.2
  IN2 w0.127: v2(41.03,69.96) 39.07,68 39.07,58.55 40.06,57.56 40.06,51.79 60.3,31.54 69.47,31.54 v2(71.91,33.98)
  BOTTOM w0.102: v2(41.03,69.96) v1(37.27,73.73) 35.97,75.03 RG11.1
XTLI_R: length 3
  TOP w0.102: v1(68.23,33.74) RG5.2 CG7.1 RG8.1
XTLO: length 7.4
  BOTTOM w0.102: YL2.3 38.78,76.49 38.64,76.63 38.64,78.76 38.41,78.99 38.41,79.68 CL37.2 39.08,80.63 37.95,81.76 UL1.28
N17188574:
  vias: v1(61.42,85.88)
N17188613: length 2.2
  BOTTOM w0.508: PC405.1 64.13,84.71 v1(64.39,84.97) 64.61,85.19 PR401.2
N17227658: length 0.6
  BOTTOM w0.102: 165.99,152.08 v1(165.34,152.08)
N17227663: length 4.3
  BOTTOM w0.102: v1(173.7,145.31) PR410.2
  BOTTOM w0.254: PU402.2 PR412.1 PC413.2 PR410.2
N17227696: length 4.8
  BOTTOM w0.102: v1(173.56,153.69) PR409.2
  BOTTOM w0.254: PU402.8 172.23,152.84 172.52,153.13 PR409.2 PC415.1 PR411.1
N17253612: length 6.1
  TOP w0.203: PU100.12 129.63,18.95 v2(130.1,19.43)
  TOP w0.508: PR111.2 130.04,20.83 130.24,20.62 v1(130.24,20.06) 130.24,19.57 v2(130.1,19.43)
  BOTTOM w0.508: v2(130.1,19.43) 129.89,19.21 PC116.1
N17256470: length 3.7
  TOP w0.102: v4(158.09,23.44) 158.09,23.73 v1(157.88,23.95)
  TOP w0.254: PR209.2 158.22,23.32 v4(158.09,23.44)
  BOTTOM w0.203: PC210.2 158.46,22.98 158.09,23.35 v4(158.09,23.44) 158.09,23.65 157.69,24.05 PU200.12
N17256593:
  vias: v1(154.26,10.89)
N17322320: length 111.2
  TOP w0.254: PR13.1 PR10.2 199.29,73.68 PC7.1 v2(199.34,74.5) ; v2(129.92,119.91) 129.7,120.14 v1(127.54,120.14) 125.48,120.14 124.72,119.38 124.72,118.92 PH1.1
  IN2 w0.254: v2(144.55,90.6) 144.3,90.85 143.28,90.85 142.6,91.53 142.6,96.97 136.05,103.52 136.05,107.14 138.11,109.2 138.11,111.44 130.64,118.92 130.64,119.83 130.33,120.14 130.15,120.14 v2(129.92,119.91)
  BOTTOM w0.254: v2(199.34,74.5) 199.65,74.8 199.65,77.32 194.44,82.52 177.37,82.52 171.35,88.54 168.13,88.54 165.84,90.83 144.78,90.83 v2(144.55,90.6)
N17322329: length 4.4
  TOP w0.254: PR20.1 199.29,72.67 v1(199.29,71.55) PR11.2 PR15.1 PR18.1
N17322935:
  vias: v1(127.68,170.46)
N17322941: length 5.6
  TOP w0.102: v1(133.81,175.43) PR19.2
  TOP w0.254: PQ3.5 132.95,172.69 132.79,172.84 132.79,173.15 132.98,173.34 PQ3.6 133.37,173.98 PR19.2 134.24,174.42 134.85,173.81 PR14.1
N17330968: length 1.2
  BOTTOM w0.102: T211.1 120.29,135.19 RC52.1
N17344663: length 2
  TOP w0.102: v4(133.02,183.84) v1(133.02,185.88)
  vias: v4(132.26,183.84) v4(132.26,183.08) v4(132.26,182.32) v4(133.02,183.08) v4(133.02,182.32) v4(133.02,181.56) v4(133,180.87)
N17354752: length 24.8
  TOP w0.254: PR536.1 166.78,125.91 v2(166.04,125.17)
  BOTTOM w0.254: v2(166.04,125.17) 164.08,125.17 160.76,121.85 160.76,118.02 160.25,117.51 158.88,117.51 158.44,117.96 153.67,117.96 153.29,118.34 153.29,120.26 153.53,120.5 PL501.2
N17354919: length 5.1
  TOP w0.254: PC517.2 160.05,133.3 159.73,133.62 v2(158.88,133.62)
  BOTTOM w0.254: PR518.1 158.58,133.94 158.58,133.91 v2(158.88,133.62) v1(159.67,133.62) 159.85,133.44 PU500.22
N17371703: length 3.9
  TOP w0.102: v1(176.86,172.6) 175.78,172.6 PR717.2 174.97,171.79 PU700.10
N17371738: length 4
  TOP w0.102: v1(176.97,170.53) 175.57,170.53 PR719.2 174.82,171.29 PU700.9
N17407779: length 2.3
  TOP w0.102: v1(185.79,46.39) 185.91,46.51 CE12.1 R2354.1
N17434553: length 0.9
  TOP w0.102: RE36.1 178.01,61.06 T218.1
N17434554: length 4.1
  TOP w0.102: UE1.107 180.51,61.2 179.78,61.92 RE36.2 178.92,62.28 v1(179.49,62.85)
N17434556: length 1.1
  TOP w0.102: RE37.1 T212.1
N17434577: length 4.8
  TOP w0.102: UE1.66 195.19,67.72 195.35,67.89 197.26,67.89 197.64,68.27 v1(197.64,68.51) RE7.2
N17438484: length 2.2
  TOP w0.102: R2355.2 CA21.1 44.11,28.57 v1(43.22,29.46)
N17494823: length 6.3
  TOP w0.102: v1(31.07,19.9) 30.86,19.7 CA2.1 CA1.1 28.59,19.68 RA3.2 27.46,19.25 27.71,19 28.35,19 28.6,18.74 QA5.2
N18943829: length 26.6
  TOP w0.102: v2(152.35,181.46) v1(151.83,181.46)
  TOP w0.254: PR724.1 v2(173.51,178.51)
  IN2 w0.254: v2(152.35,181.46) 152.48,181.58 154.16,181.58 155.05,182.47 159.58,182.47 162.14,179.91 172.9,179.91 173.61,179.19 173.61,178.61 v2(173.51,178.51)
  BOTTOM w0.254: v2(152.35,181.46) 151.95,181.86 PR720.2
N18944147: length 31.4
  TOP w0.254: PU700.17 171.39,175.33 171.96,175.89 171.96,176.39 PC722.2 PC726.1 173.96,177.99 174.15,178.18 v2(174.15,178.51)
  IN2 w0.254: v2(174.15,178.51) 173.99,178.66 173.99,179.35 172.98,180.36 162.22,180.36 159.66,182.93 154.86,182.93 153.97,182.04 152.48,182.04 v2(152.35,182.17)
  BOTTOM w0.254: v2(152.35,182.17) 152.66,181.86 PR720.3
N18956218: length 5.2
  TOP w0.102: v1(171.78,179.5) PR724.2
  TOP w0.254: PU700.18 170.89,175.4 171.42,175.92 171.42,177.24 PC722.1 171.78,177.61 PR724.2
N18967347: length 1
  TOP w0.254: PC727.1 174.2,166.39 174.15,166.44 PR723.2
N18967375: length 3.5
  TOP w0.254: PU700.4 170.89,168.86 v4(171.02,168.73)
  BOTTOM w0.102: v4(171.02,168.73) v1(171.02,168.15)
  BOTTOM w0.254: v4(171.02,168.73) 171.72,168.73 172.09,169.1 PC721.1
N18967379: length 3.7
  TOP w0.254: PU700.6 171.9,169.32 172.52,168.69 v1(173.36,168.69) 173.68,168.69 174.15,168.22 PR723.1
N18967435: length 4.8
  TOP w0.102: PC723.1 v1(176.13,167.79)
  TOP w0.254: PC723.1 173.71,169.24 172.75,169.24 172.4,169.59 PU700.7
N18967441: length 4.5
  TOP w0.254: PR725.1 172.57,167.21 172.67,167.21 PR728.2 172.74,168.31 172.3,168.31 v1(171.91,168.7) 171.39,169.22 PU700.5
N18999155: length 6.8
  TOP w0.254: PR704.2 166.73,167.87 166.81,167.94 PC709.1 167.38,168.51 167.55,168.34 v4(167.91,168.34) 167.91,170.64 168.06,170.79 PU700.28
  BOTTOM w0.102: v1(167.59,167.78) 167.91,168.1 v4(167.91,168.34)
  BOTTOM w0.254: PC706.1 v4(167.91,168.34)
N19000258: length 8.6
  TOP w0.254: PR705.2 165.99,166.6 165.61,166.98 v1(165.61,167.23) 165.61,169.53 165.99,169.91 PC709.2 166.81,170.42 v4(167.15,170.76) 167.67,171.29 PU700.27
  BOTTOM w0.254: v4(167.15,170.76) 167.45,170.46 PC707.1
N19021042: length 14
  TOP w0.254: PU700.26 167.28,171.79 v4(167.15,171.66)
  BOTTOM w0.381: PC710.1 167.52,171.68 167.5,171.66 v4(167.15,171.66) 166.53,171.04 164.54,171.04 163.58,172.01 163.58,176.02 163.99,176.43 v1(164.71,176.43) 166.03,176.43 PR709.2
N19095003: length 2.1
  TOP w0.254: PR722.2 174.51,170.08 173.8,170.79 PU700.8
N19142937: length 0.6
  BOTTOM w0.102: v4(138.48,158.98) v1(138.48,158.37)
  vias: v4(137.85,158.98) v4(145.72,162.71) v4(145.72,161.95)
N19565438: length 3.4
  TOP w0.102: v1(140.22,155.26) PQ707.2
  TOP w0.254: PQ708.1 139.29,157.55 PQ707.2
N19565442: length 11.2
  TOP w0.102: v1(143.09,161.73) 142.78,161.41 PR703.2
  TOP w0.254: PR703.2 141.48,161.59 140.9,161.59 139.91,160.6 139.91,160.29 139.61,159.99 139.25,159.99 139.11,160.13 PQ709.3 139.11,161.05 139.6,161.54 139.6,163.65 139.97,164.02 PQ710.3
N19565444: length 6.2
  TOP w0.254: PQ712.1 140.41,160.11 PR712.2 140.21,159.38 v1(139.53,159.38) 138.97,159.38 138.46,159.89 PQ709.2 PQ709.5
N19565472: length 3
  TOP w0.102: PR708.1 v1(169.09,162.94)
  TOP w0.254: PR708.1 170.93,162.94 171.1,163.1 PQ711.1
N19636367: length 12.6
  TOP w0.102: v2(29.11,21.92) 28.83,22.2 RA7.2 RA6.2 ; v2(25.95,15.64) 25.95,14.84 26.97,13.83 QA6.2
  IN1 w0.127: v2(29.11,21.92) 29.11,21.16 25.95,17.99 v2(25.95,15.64)
N19792312: length 10
  TOP w0.102: QA5.5 28.6,15.57 28.73,15.44 29.11,15.44 29.25,15.58 QA5.6 29.25,17.11 v1(30.48,18.34) 31.44,19.29 31.44,22.24 RA2.2
N19794620: length 13.8
  TOP w0.102: RA5.2 v1(32.16,22.98) 32.16,17.98 30.37,16.19 30.37,14.63 30.22,14.48 QA6.6 28.66,14.48 28.58,14.4 28.58,13.96 28.71,13.83 QA6.5
N22321388: length 3
  TOP w0.102: UE1.82 188.79,67.71 v1(188.14,68.36) 187.99,68.51 RE37.2
N22702729: length 3.3
  TOP w0.102: v1(43.07,11.78) RD15.2 LED2.1
N22702890: length 2.7
  TOP w0.102: v1(31.81,11.8) 31.9,11.7 LED1.2 32.11,10.49 RD14.2
N22702897: length 22.3
  TOP w0.102: RD17.2 v1(49.61,12.9) 49.61,13.36 v2(49.56,13.41) ; LED1.3 v2(30.4,12.12)
  BOTTOM w0.102: v2(49.56,13.41) 48.09,11.94 30.59,11.94 v2(30.4,12.12)
N22795339: length 2.2
  TOP w0.102: RD18.2 v1(58.84,11.94) 58.84,11.68 58.81,11.65 LED4.1
N23316235:
  vias: v1(47.7,73.84)
N23954212: length 3.8
  TOP w0.102: v1(58.72,82.51) R17.2 59.66,83.13 59.9,83.37 R15.2 60.72,83.32 UC5.5
N23955686: length 3.6
  BOTTOM w0.102: USOC1.C21 101.48,110.75 101.27,110.54 101.27,110.38 100.97,110.08 100.75,110.08 99.78,109.12 T105.1
N23993932: length 2.7
  TOP w0.102: v1(83.34,77.06) 83.67,77.39 CC24.2 RC39.2
N24086884: length 4
  TOP w0.102: v1(52.73,102.83) 54.19,102.83 C1123.2
  TOP w0.254: C1123.2 55.45,102.31 55.81,102.67 U59.12
N24086900: length 4.5
  TOP w0.102: v1(52.38,104.23) 52.77,103.83 54.21,103.83 C1127.2
  TOP w0.254: C1127.2 54.86,103.47 U59.10
N24234938: length 6.2
  BOTTOM w0.102: JODD.11 225.31,115.05 224.21,116.15 v1(223.43,116.15) CS17.1 RS10.2
N24235708: length 3.7
  BOTTOM w0.102: RS09.2 v1(223.32,112.09) 223.82,112.09 223.86,112.05 JODD.8
N24237390: length 3.5
  TOP w0.102: R1048.1 49.68,53.29 49.69,53.28 U58.13 50.59,52.46 v1(50.22,52.08)
N24262528: length 3.6
  BOTTOM w0.203: U11.12 105.93,25.56 105.79,25.42 v1(105.79,25.19) 105.79,25.04 106.2,24.64 106.2,23.62 C976.2
N24262552: length 2.3
  BOTTOM w0.203: U11.10 106.73,25.67 107.06,25.33 v1(107.06,25.08) 107.06,24.38 C967.2
N24334655:
  vias: v1(172,112.52)
N24334673: length 2.2
  BOTTOM w0.508: PC305.1 167.99,116.48 v1(167.91,116.41) 167.71,116.2 PR301.2
N24509824: length 3.7
  BOTTOM w0.102: RL40.2 50.4,81.74 49.94,81.74 49.49,82.18 UL3.3 49.49,83.28 48.89,83.88 v1(48.71,83.88)
N24530695: length 2.7
  TOP w0.102: RS9.1 v1(216.36,116.91)
  TOP w0.508: UI7.3 216.37,115.76 RS9.1
N24559749:
  vias: v1(52.39,88.24)
N24559796: length 2.3
  BOTTOM w0.102: PR306.2 v1(51.34,96.49)
  BOTTOM w0.508: PR306.2 50.21,95.39 PC306.1
N24608852: length 3.7
  TOP w0.203: CA62.2 41.81,17.53 UA1.27
  TOP w0.254: CA62.2 39.83,16.33 RA154.2
N24608977: length 4.9
  TOP w0.102: v1(38.51,23.44) RA51.1
  TOP w0.203: RA51.1 RA34.1 37.62,24.38 RA155.1 38.84,24.38 39.68,23.55 UA1.13
N24654163: length 1.1
  TOP w0.102: PR107.1 v1(135.58,17.09)
N24654248: length 1.3
  TOP w0.102: PR108.2 v1(124.04,18.43)
N24947886: length 3
  BOTTOM w0.102: UT2.8 203.71,160.23 203.62,160.14 202.95,160.14 202.64,159.83 v1(202.64,159.63) 202.29,159.28 RX5.2
N25096547: length 0.9
  TOP w0.102: RE17.2 T199.1
N25096555: length 0.9
  TOP w0.102: RE19.2 T200.1
N25096563: length 0.9
  TOP w0.102: RE20.2 T201.1
N25096571: length 0.9
  TOP w0.102: RE21.2 T202.1
N25415357: length 3.4
  TOP w0.102: U64.5 97.65,141.49 98.07,141.91 98.07,143.05 R5.1 97.55,143.19 v1(96.97,143.77)
N25420647: length 3.6
  TOP w0.102: R19.2 v1(83.25,84.14)
  TOP w0.254: R19.2 81.36,85.06 R18.2 81.36,85.52 81.58,85.74 U54.5
N25421095: length 2.8
  TOP w0.254: R21.2 75.87,84.19 75.73,84.33 R20.2 74.85,85.62 U57.5
N29841026:
  vias: v1(132.83,159.46)
N39970373: length 5.5
  TOP w0.254: PQ710.6 142.53,165.32 143.06,164.79 143.06,164.72 PR718.2 v1(143.69,162.99) 143.12,162.42 PQ712.2
N40812716: length 4.6
  TOP w0.254: UR1.6 178.32,21.12 178.46,20.98 178.87,20.98
  TOP w0.305: CR3.2 v1(180.14,19.58) 180.14,20.22 179.38,20.98 178.87,20.98
N47007898: length 3.4
  TOP w0.102: PC11.2 v1(128.65,185.09)
  TOP w0.254: PQ4.5 130.7,184.97 PR26.1 130.15,185.11 130.13,185.09 PC11.2
N47008110: length 4.5
  TOP w0.102: PC9.1 v1(127.96,181.44)
  TOP w0.254: PC9.1 129.84,180.54 PR17.2 130.7,180.65 PQ4.2
N47008134: length 5.1
  TOP w0.102: v1(142.42,180.79) PL3.2
  TOP w0.254: PL3.2 141.53,178.9 PR2.2 141.99,178.33 PQ1.1
N48037563: length 4
  TOP w0.102: RD6.2 144.35,67.96 v2(144.85,67.46)
  BOTTOM w0.356: JDIMM1.197 143.95,68.13 144.62,67.46 v2(144.85,67.46)
N48037565: length 4.5
  TOP w0.102: v1(145.3,70) 144.57,70 RD7.2 144.35,69.59 144.85,69.1 v2(144.85,68.05)
  BOTTOM w0.356: JDIMM1.201 145.15,68.34 v2(144.85,68.05)
N48039107: length 5.5
  TOP w0.102: v1(124.93,62.89) 124.93,62.57 124.72,62.36 RD4.1
  TOP w0.406: v2(122.65,62.61) 122.65,61.77 CD21.1 CD22.1 RD4.1
  BOTTOM w0.356: v2(122.65,62.61) JDIMM1.126
N52907207: length 17.7
  TOP w0.254: PR708.2 170.07,163.87 PR706.1 v2(169.14,164.72)
  IN1 w0.254: v2(158.86,170.89) 158.86,168.15 162.28,164.72 v2(169.14,164.72)
  BOTTOM w0.254: v2(158.86,170.89) 158.86,171.4 158.65,171.6 PQ706.4
N52907447: length 2.3
  TOP w0.102: v1(174.91,164.63) 174.79,164.74 PR714.1
  TOP w0.254: PR714.1 173.26,164.74 173.22,164.7 PQ711.2
N55155843: length 2.2
  TOP w0.102: RX3.2 215.55,175.77 v1(215.71,175.6)
  TOP w0.254: QX1.1 215.01,176.48 215.07,176.53 RX3.2
N55201771: length 9.8
  BOTTOM w0.102: JHDMI.13 8.79,105.86 8.79,108.28 10.8,110.28 v1(13.08,110.28) 13.9,110.28 RX12.2
N56393123: length 3
  BOTTOM w0.203: 36.02,81.53 36.5,81.53 36.75,81.78 UL1.31
  BOTTOM w0.254: RL31.2 35.08,80.73 v1(35.56,81.21) 35.89,81.53 36.02,81.53
N56393790: length 4.8
  BOTTOM w0.102: T94.1 39.77,80.17 39.77,80.48 39.01,81.24 38.9,81.24 38.35,81.79 UL1.27
N56393809: length 1.7
  BOTTOM w0.102: UL1.25 39.15,82.02 40.07,81.1 T95.1
N56394014: length 6.8
  TOP w0.508: RL20.2 RL19.2 v1(22.33,86.19) 23.65,87.51 CL33.1
N56394031: length 7
  TOP w0.254: CL41.2 32.34,84.73 v2(32.03,85.04)
  BOTTOM w0.254: TL1.3 31.46,85.61 v2(32.03,85.04) 32.63,84.44 v1(32.63,83.86) 32.31,83.54 32.31,82.19 31.92,81.8 TL1.6
N59110906: length 1
  TOP w0.102: T203.1 178.01,57.43 RE43.2
N61580896: length 38
  TOP w0.254: Q2307.1 v2(156.98,32.31) ; R2314.2 144.62,60.34 144.81,60.15 144.81,54.3 145.51,53.6 v1(145.51,52.91) 145.51,52.54 151.69,46.35 v2(156.98,46.35)
  BOTTOM w0.254: v2(156.98,32.31) v2(156.98,46.35)
N61580898: length 4.2
  TOP w0.102: Q2308.1 67.59,29.77 67.5,29.86 R2315.2 v1(64.88,29.86)
N63469417: length 3.8
  TOP w0.102: CA69.1 RA81.2 CA65.2 ; CA69.1 v1(39.07,28.51) ; CA69.1 40.11,28.52 RA79.1
N63469524: length 2.4
  TOP w0.102: 34.71,16.2 v1(33.4,16.2)
  TOP w0.254: 34.71,16.2 34.71,15.52 RA82.1
N63469526: length 1
  TOP w0.254: RA80.1 35.87,15.67 35.96,15.76 35.96,16.2
N63469613: length 2.8
  TOP w0.102: UA1.12 41.01,24.65 40.41,25.25 v1(40.41,25.78) 40.41,26.07 CA65.1
N63469687: length 2.2
  TOP w0.203: CA23.2 41.81,17.02 42.15,17.36 42.15,17.85 42.21,17.9 UA1.28
N63469697: length 5.9
  TOP w0.102: v1(35.17,22.5) 35.17,22.82 RA153.2
  TOP w0.203: RA153.2 36.3,22.93 39.5,22.93 39.69,22.75 UA1.15
N63469703: length 6.5
  TOP w0.203: UA1.37 46.57,19.15 46.71,19.01 46.71,18.82 v2(46.45,18.55)
  TOP w0.254: v4(46.45,14.49) CA24.1
  IN1 w0.254: v4(46.45,14.49) v2(46.45,18.55)
  BOTTOM w0.102: v2(46.45,18.55) v1(46.45,17.93)
N63469709: length 2.9
  TOP w0.203: UA1.35 45.01,17.83 46.45,16.39 CA24.2
N63469711: length 2.7
  TOP w0.203: CA25.2 45.49,16.77 v1(45.1,17.17) 44.61,17.66 UA1.34
N63469723: length 3
  TOP w0.203: UA1.39 46.76,19.95 47.33,19.37 v1(47.4,19.37) 47.43,19.37 48.25,18.55 CA63.2
N63469729: length 2.4
  TOP w0.203: UA1.7 v1(43.01,25.64) 43.01,26.02 43.15,26.16 CA64.2
N63469750: length 216.1
  TOP w0.102: UA1.8 42.61,24.91 42.66,24.96 42.66,26.01 v2(42.25,26.42)
  IN2 w0.127: v2(145.52,95.01) 145.52,93.6 149.41,89.71 149.41,65.33 146.28,62.2 146.28,58.27 139.58,51.56 v2(139.58,47.14)
  BOTTOM w0.102: RA130.2 123.68,131.52 124.99,131.52 134.15,122.36 134.15,112.81 132.44,111.1 132.44,100.63 138.06,95.01 v1(144.06,95.01) v2(145.52,95.01) ; v2(139.58,47.14) 92.27,47.14 75.33,30.2 55.32,30.2 54.51,31.01 45.7,31.01 44.73,30.05 44.73,29.61 42.25,27.13 v2(42.25,26.42)
N100764683: length 1.9
  TOP w0.102: v1(162.59,140.96) PR502.1
  TOP w0.254: PC506.1 162.08,139.9 162.16,139.98 PR502.1
N100764685: length 7.7
  TOP w0.254: v4(164.19,135.77) 163.98,135.56 162.67,135.56 161.64,136.59 v1(161.64,137.42) 161.64,138.11 PR507.2 PC506.2
  BOTTOM w0.203: v4(164.19,135.77) 164.08,135.66 PU500.31
N100764689: length 1.9
  TOP w0.102: PC532.1 v1(160.73,124.32)
  TOP w0.254: PC532.1 160.73,125.75 160.68,125.8 PR539.2
N100764691: length 5.5
  TOP w0.254: PR539.1 PR540.1 161.57,127.57 v1(163.2,129.2) v4(163.82,129.82)
  BOTTOM w0.254: v4(163.82,129.82) 163.68,129.96 PU500.11
N100764720: length 8.2
  TOP w0.254: v2(159.36,133.12) 159.74,132.74 159.91,132.74 PC518.1
  BOTTOM w0.254: PU500.21 161.05,133.04 159.44,133.04 v2(159.36,133.12) 158.68,133.12 158.25,133.55 157.69,133.55 PR522.2 157.05,132.43 PR519.2
N100764741: length 4.2
  BOTTOM w0.203: PU500.28 162.88,136.23 162.58,136.53 PR508.1 PR503.1 163.93,137.21 163.96,137.24 PC504.1
N100764791: length 7.5
  BOTTOM w0.203: PC504.2 164.67,136.65 163.84,136.65 v1(163.48,136.29) 163.28,136.1 PU500.29
  BOTTOM w0.254: PR505.1 165.26,138.95 PC507.2 PC504.2 166.13,137.24 PR504.1 167.26,137.23 PC505.1
N100764795: length 4.2
  BOTTOM w0.203: PC528.2 164.34,128.44 PC531.2 PR534.2 162.58,129.5 v1(162.51,129.58) 162.48,129.6 PU500.14
N100764809: length 9.5
  BOTTOM w0.102: v1(165.48,125.68) 165.26,125.9 PR533.2
  BOTTOM w0.203: PU500.13 162.88,130.2 162.96,130.12 162.96,129.4 163.38,128.97 164.1,128.97 164.74,128.97 PC528.1
  BOTTOM w0.254: PR538.2 PR542.2 166.2,126.87 165.97,126.65 PR533.2 PR543.1 PC528.1
N100764813: length 0.9
  BOTTOM w0.203: PR503.2 163.48,138.11 163.87,138.11 PC507.1
N100764860: length 3.7
  BOTTOM w0.254: PU500.27 162.48,135.94 v1(162.16,136.27) 161.57,136.85 PR510.2
N100764905: length 0.9
  BOTTOM w0.203: PR543.2 164.34,127.52 PC531.1
N100764954: length 1
  BOTTOM w0.254: PR538.1 167.49,128.34 167.54,128.29 PC527.2
N100764996: length 40.7
  TOP w0.254: v2(165.1,140.16) 165.43,139.82 PR500.1
  IN2 w0.254: v2(134.12,141.2) 134.68,141.2 135.94,142.46 135.94,145.76 136.43,146.25 145.27,146.25 150.93,140.59 158.35,140.59 159.74,141.98 161.93,141.98 163.25,140.66 164.14,140.66 164.65,140.16 v2(165.1,140.16)
  BOTTOM w0.254: PH500.2 133.48,141.2 v2(134.12,141.2)
N100765028: length 1.9
  BOTTOM w0.102: v1(163.48,125.65) PC525.2
  BOTTOM w0.203: PC525.2 PR533.1
N100765040: length 2
  BOTTOM w0.102: PR501.1 168.43,138.36 v1(168.43,139.09)
  BOTTOM w0.203: PR501.1 PC505.2
N100765116: length 15.5
  TOP w0.254: PR535.2 165.38,126.49 165.38,124.66 v2(164.62,123.9)
  BOTTOM w0.254: PH503.1 158.32,116.48 158.59,116.75 160.57,116.75 161.52,117.7 161.52,121.53 164.12,124.13 164.39,124.13 v2(164.62,123.9)
N100765769: length 2
  BOTTOM w0.102: v1(163.8,140.04) 163.8,139.74 163.41,139.35 PC511.1
  BOTTOM w0.254: PC511.1 PR505.2
N100765781: length 3.2
  BOTTOM w0.254: PR522.1 158.32,132.92 158.65,132.59 v1(158.92,132.59) 160.1,132.59 160.16,132.64 PU500.20
N100768097: length 1
  TOP w0.102: PC526.1 151.59,120.62 v1(151.39,120.42)
N100768278: length 0.5
  TOP w0.102: 136.54,138.17 v1(136.02,138.17)
N100768460: length 1.3
  BOTTOM w0.102: PR531.2 v1(159.32,126.52)
N100768507: length 1.4
  BOTTOM w0.102: PR511.2 v1(159.07,139.39)
N100768540: length 47.1
  TOP w0.254: v2(164.98,141.43) 165.17,141.62 PR513.1
  IN2 w0.254: v2(134.17,142.39) 134.75,142.39 135.18,142.82 135.18,146.14 136.07,147.03 145.59,147.03 151.25,141.36 158.03,141.36 159.42,142.76 162.25,142.76 163.58,141.43 v2(164.98,141.43)
  BOTTOM w0.254: v2(134.17,142.39) 129.29,142.39 129.03,142.65 PL500.2
N102723193: length 3.8
  TOP w0.102: v2(115.4,127.66) 116.16,126.9 116.16,125.02 T102.1
  BOTTOM w0.102: v2(115.4,127.66) 115.62,127.44 USOC1.BG18
N102723222: length 2.5
  BOTTOM w0.102: T101.1 117.87,129.6 116.36,128.09 USOC1.BH18
N102723231: length 3.6
  BOTTOM w0.102: T100.1 120.48,127.2 118.75,127.2 118.41,126.86 117.74,126.86 117.69,126.86 117.49,126.86 117.28,126.65 USOC1.BG21
N251601461: length 3.5
  BOTTOM w0.203: PR524.2 166.27,129.31 v1(166.02,129.56) 165.76,129.82 165.76,131.14 165.46,131.44 PU500.8

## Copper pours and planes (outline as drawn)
+0.675VS on BOTTOM (solid shape): 156.28,47.64 156.28,44.38 156.32,44.35 156.32,32.71 156.06,32.46 155.45,32.46 155.43,32.43 154.21,32.43 154.18,32.41 154.18,31.95 154.13,31.9 154,31.9 153.98,31.93 153.98,32.43 153.95,32.46 152.33,32.46 152.12,32.66 152.12,47.32 152.76,47.95 155.96,47.95
+0.675VS on TOP: 147.68,60.2 147.68,62.06 147.67,62.07 147.67,69.95 147.5,70.11 146.41,70.11 146.03,69.73 146.03,68.67 145.42,68.06 145.42,53.54 152.17,46.78 155.4,46.78 155.73,47.11 155.73,49.6 148.11,57.22 148.11,59.76
+0.675VSP on BOTTOM (solid shape): 153.83,32.26 153.83,31.75 153.85,31.72 154.31,31.72 154.33,31.75 154.33,32.26 154.36,32.28 155.83,32.28 156.11,32 156.11,27.18 156.21,27.07 156.21,26.82 156.16,26.77 155.35,26.77 155.27,26.85 155.27,27.43 154.77,27.94 153.06,27.94 152.94,28.06 152.94,32.18 153.04,32.28 153.8,32.28
+1.0VALW on TOP (solid shape): 96.32,117.96 96.32,117.07 96.97,116.43 96.97,116.15 96.78,115.96 95.79,115.96 95.56,116.19 95.56,117.94 95.69,118.07 96.22,118.07
+1.0VALW on BOTTOM (solid shape): 54.46,97.76 54.46,97.05 54.44,97.03 53.93,97.03 53.9,97 53.9,96.49 53.93,96.47 54.44,96.47 54.46,96.44 54.46,96.24 54.44,96.21 53.93,96.21 53.9,96.19 53.9,95.68 53.93,95.65 54.44,95.65 54.46,95.63 54.46,95.19 54.38,95.11 52.49,95.11 51.97,95.63 51.97,97.84 52.23,98.09 54.13,98.09
+1.0VALW on BOTTOM: 72.42,108.48 72.47,108.43 73.97,108.43 74.32,108.07 74.32,104.87 74.31,104.86 74.31,103.82 73.94,103.45 68.1,103.45 67.97,103.58 67.97,104.09 67.68,104.38 66.74,104.38 66.63,104.49 66.63,108.02 67.08,108.48
+1.0VALW on IN1: 107.61,115.91 107.22,115.52 106.71,115.52 106.45,115.77 105.24,115.77 105.21,115.75 99.19,115.75 98.33,114.88 87.28,114.88 83.87,111.48 79.94,111.48 74.81,106.35 74.81,105 74.12,104.32 66.7,104.32 66.45,104.57 66.45,111.91 73.43,118.9 83.57,118.9 90.1,125.42 98.68,125.42 107.61,116.49
+1.0VALW on IN2: 52,95.22 61.09,95.22 61.73,95.86 64.6,95.86 68.23,99.49 68.23,108.06 67.9,108.39 64.33,108.39 57.81,101.88 52.12,101.88 51.64,101.39 51.64,95.58
+1.0VALWP on BOTTOM (solid shape): 57.31,96.98 57.31,92.02 56.92,91.64 55.02,91.64 54.77,91.9 54.77,94.82 54.61,94.97 54.61,95.81 54.05,95.81 54.05,96.06 54.08,96.09 54.59,96.09 54.61,96.11 54.61,96.59 54.59,96.62 54.05,96.62 54.05,96.85 54.08,96.87 54.59,96.87 54.59,97.38 54.69,97.48 56.8,97.48
+1.0VS on TOP (solid shape): 97.08,120.8 97.08,119.25 97.01,119.17 88.47,119.17 88.29,119.35 88.29,120.8 88.47,120.98 96.9,120.98
+1.0VS on BOTTOM (solid shape): 113.36,112.24 113.36,112.09 112.7,111.43 112.58,111.43 111.94,112.06 111.94,112.22 112.09,112.37 113.24,112.37
+1.0VS on BOTTOM (solid shape): 74.43,100.61 74.43,96.52 74.4,96.49 74.4,95.45 74.22,95.27 68.81,95.27 68.28,95.81 68.28,97.89 68.48,98.09 69.14,98.09 69.45,98.4 69.45,100.61 69.62,100.79 74.25,100.79
+1.0VS on BOTTOM (solid shape): 114.98,113.94 114.99,113.92 114.99,113.72 114.9,113.66 114.79,113.67 114.76,113.68 114.68,113.68 114.57,113.57 114.07,113.57 114.02,113.62 113.69,113.62 113.67,113.65 113.64,113.69 113.61,113.83 113.69,113.94 113.77,113.99 113.77,114.15 114.16,114.53 114.38,114.53
+1.0VS on BOTTOM (solid shape): 111.89,122.67 111.89,122.38 111.94,122.32 111.95,122.32 112.02,122.22 112.11,122.16 112.14,122.13 112.23,122.12 112.28,122.12 112.41,122.12 112.5,122.03 112.5,121.77 112,121.27 111.71,121.27 111.7,121.28 111.6,121.28 111.6,121.28 111.52,121.21 111.51,121.21 111.33,121.03 111.33,120.88 111.15,120.69 110.67,120.69 110.22,121.15 109.46,121.15 109.34,121.27 109.34,121.52 109.39,121.57 109.76,121.57 109.94,121.75 109.94,121.98 110.52,122.56 110.68,122.56 110.82,122.42 110.82,121.76 111.01,121.57 111.27,121.57 111.49,121.79 111.49,122.52 111.01,123.01 111.01,123.19 111.1,123.28 111.28,123.28
+1.0VS on TOP: 116.23,120.39 116.95,120.39 117.88,119.45 117.88,119.35 117.53,119 115.55,119 115.29,119.25 115.29,119.45
+1.0VS on TOP: 117.42,123.34 115.22,121.14 114.65,121.14 113.74,122.04 113.74,122.15 114.1,122.5 114.1,122.71 113.9,122.91 113.9,123.24 115.01,124.36 115.37,124.36 116.24,125.23 116.24,129.43 114.61,131.06 114.61,132.86 114.42,133.04 114.42,133.8 114.55,133.93 115.29,133.93 121.06,128.17 121.06,125.4 119,123.34 ; 1 cut-out
+1.0VS on TOP: 109.98,122.71 110.19,122.71 110.39,122.5 110.98,122.5 111.36,122.88 111.48,122.88 111.85,122.51 111.85,122.41 111.46,122.02 111.12,122.02 110.17,121.07 110.16,121.07 110.07,120.98 109.48,120.98 109.07,121.38 109.07,121.79
+1.0VS on VCC: 67.82,94.06 64.52,97.36 63.19,97.36 62.89,97.65 62.89,106.27 66.05,109.42 72.52,109.42 92.72,129.61 107.81,129.61 108.11,129.32 108.11,117.82 108.87,117.06 108.87,115.24 108.14,114.52 107.81,114.52 107.2,115.14 94.54,115.14 74.73,95.32 69.39,95.32 68.13,94.06
+1.0VS on IN2: 116.42,120.9 116.39,120.89 116.18,120.57 116.39,120.24 116.42,120.23 116.42,119.79 111.56,114.93 111.56,114.48 111.03,113.94 111.03,113.1 111.43,112.7 112.83,112.7 115.9,115.77 116.75,115.77 117.08,115.44 117.08,113.57 115.42,111.91 113.97,111.91 112.75,110.69 111.59,110.69 111.23,111.05 109.58,111.05 108.11,112.52 107.55,112.52 107.06,113 107.06,113.31 107.67,113.92 107.67,114.26 106.93,115 106.93,115.56 107.07,115.74 107.08,115.96 107.1,116.06 107.2,116.09 107.53,116.69 106.94,116.33 106.91,116.24 106.82,116.21 106.72,116.22 106.63,116.2 106.53,116.22 106.5,116.32 106.21,116.77 105.8,116.43 105.8,116.41 105.75,116.35 104.47,116.35 104.24,116.58 104.24,116.96 104.5,117.22 104.78,117.22 104.82,117.19 105.36,117.19 105.36,117.73 105.32,117.77 105.32,118.04 105.81,118.54 105.81,119.12 105.86,119.17 105.87,119.17 106.03,119.26 106.12,119.41 106.12,119.43 107.14,120.45 108.19,120.45 109.91,122.18 109.93,122.18 114.4,126.64 116.87,126.64 118.35,125.16 118.35,124.58 118.41,124.52 118.41,123.45 116.42,121.46
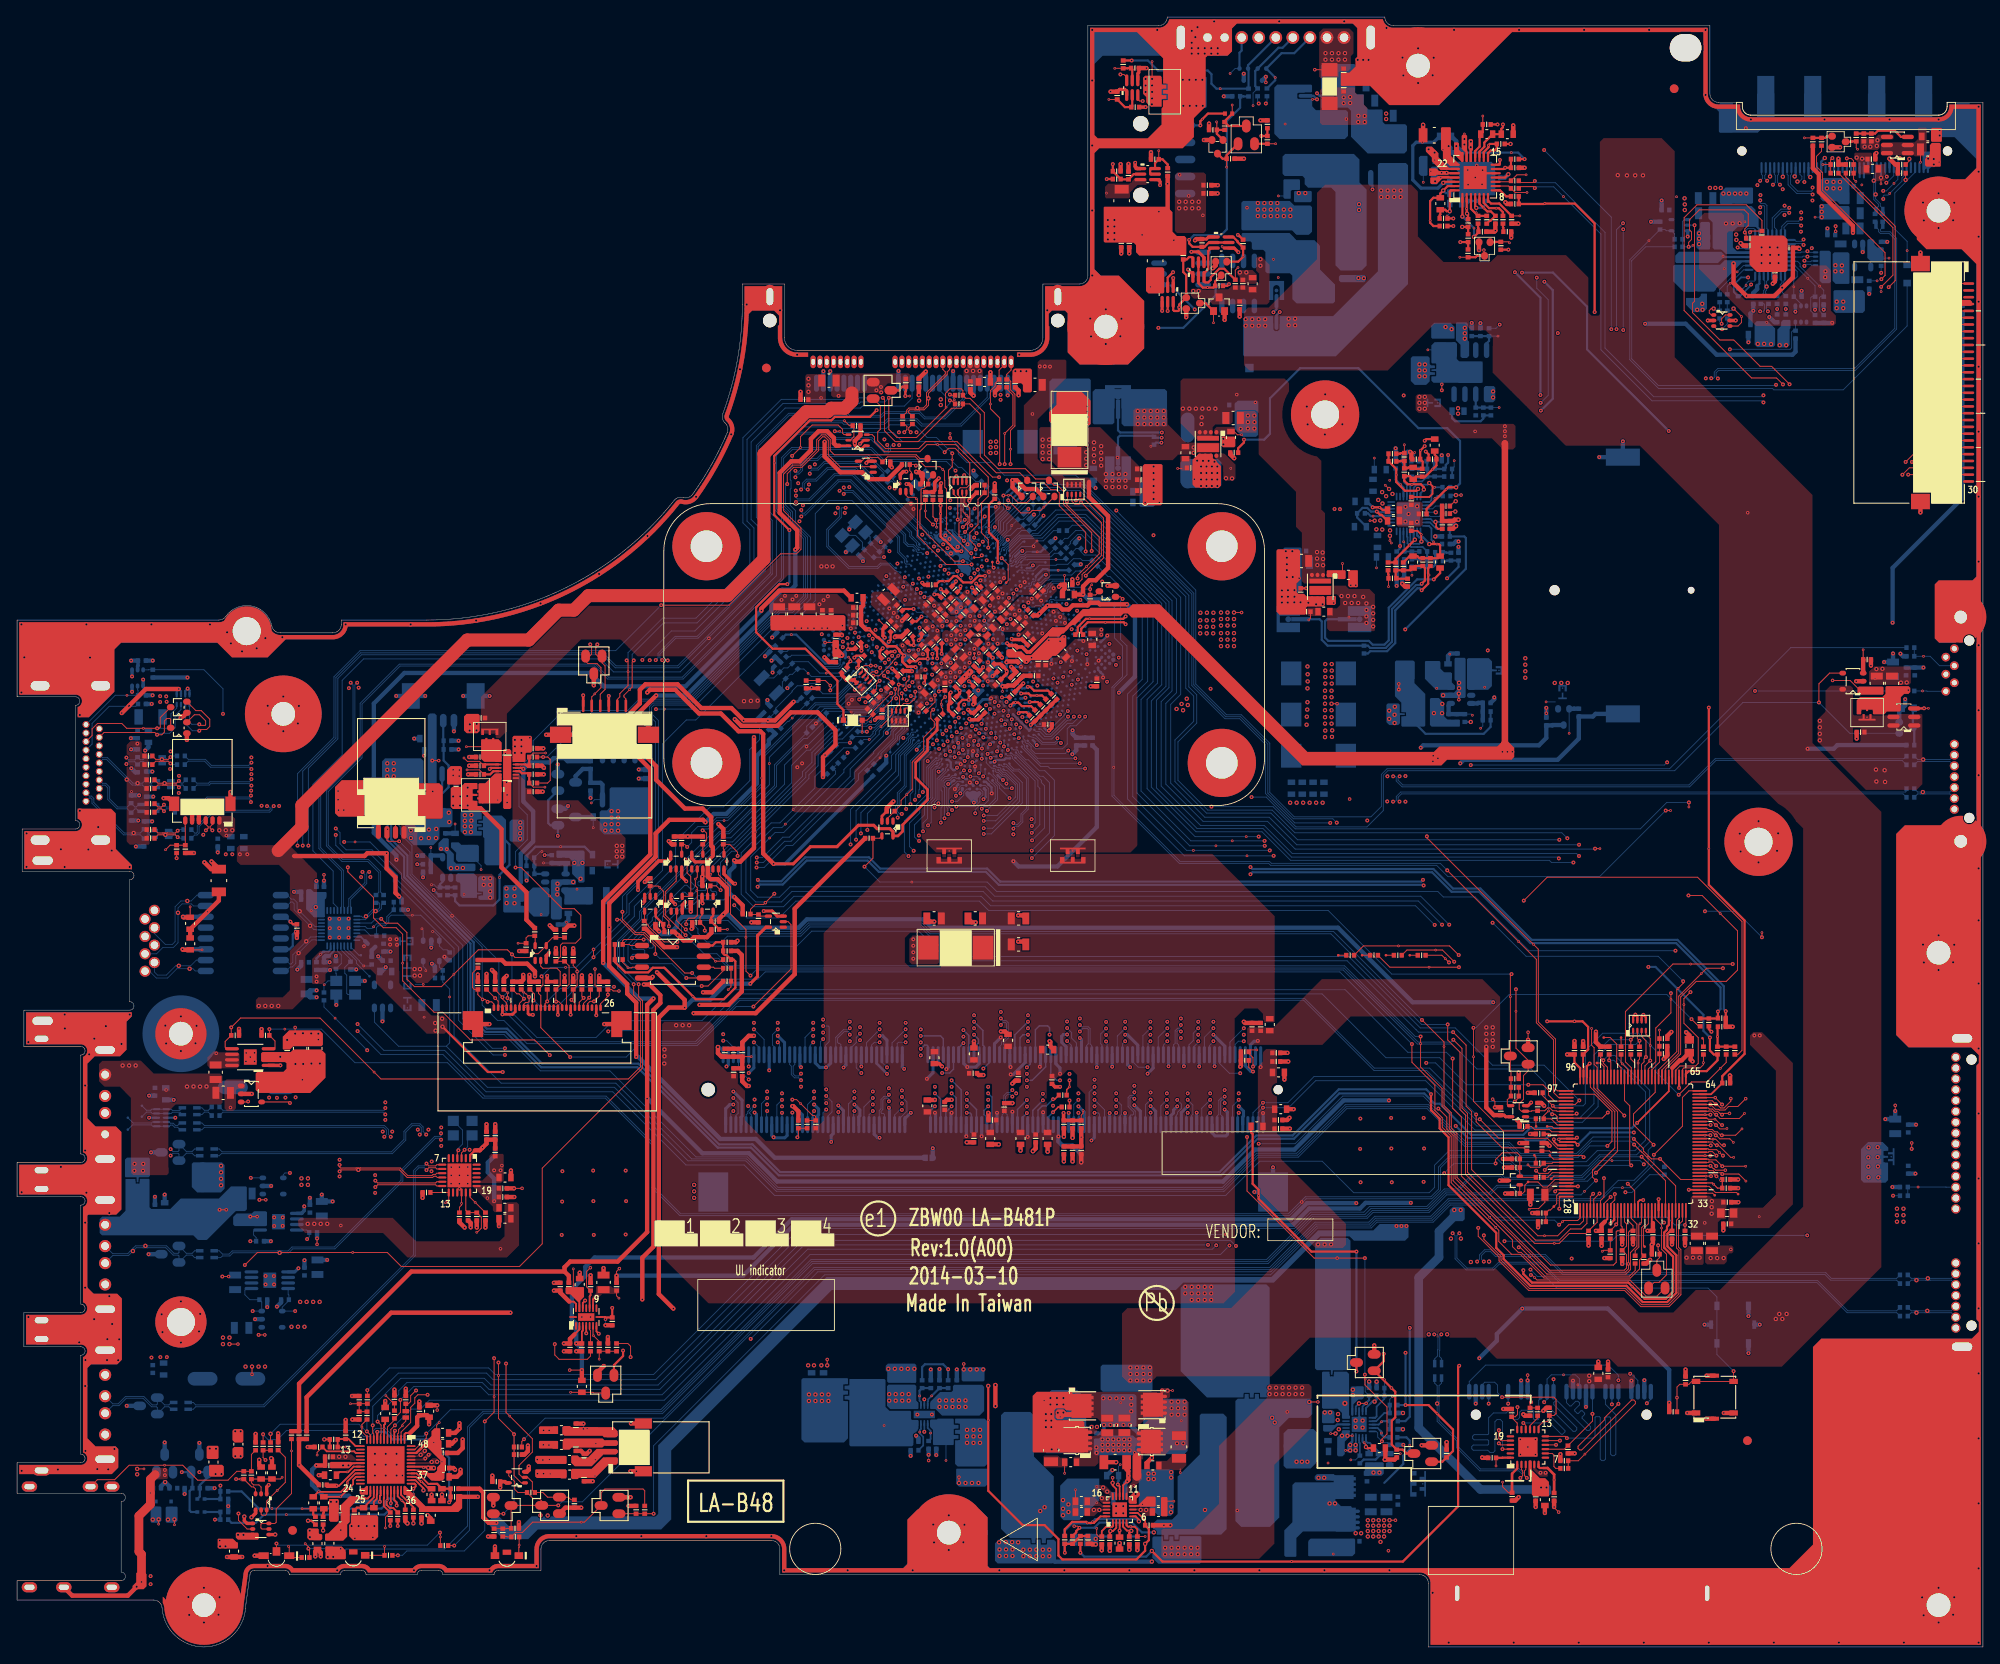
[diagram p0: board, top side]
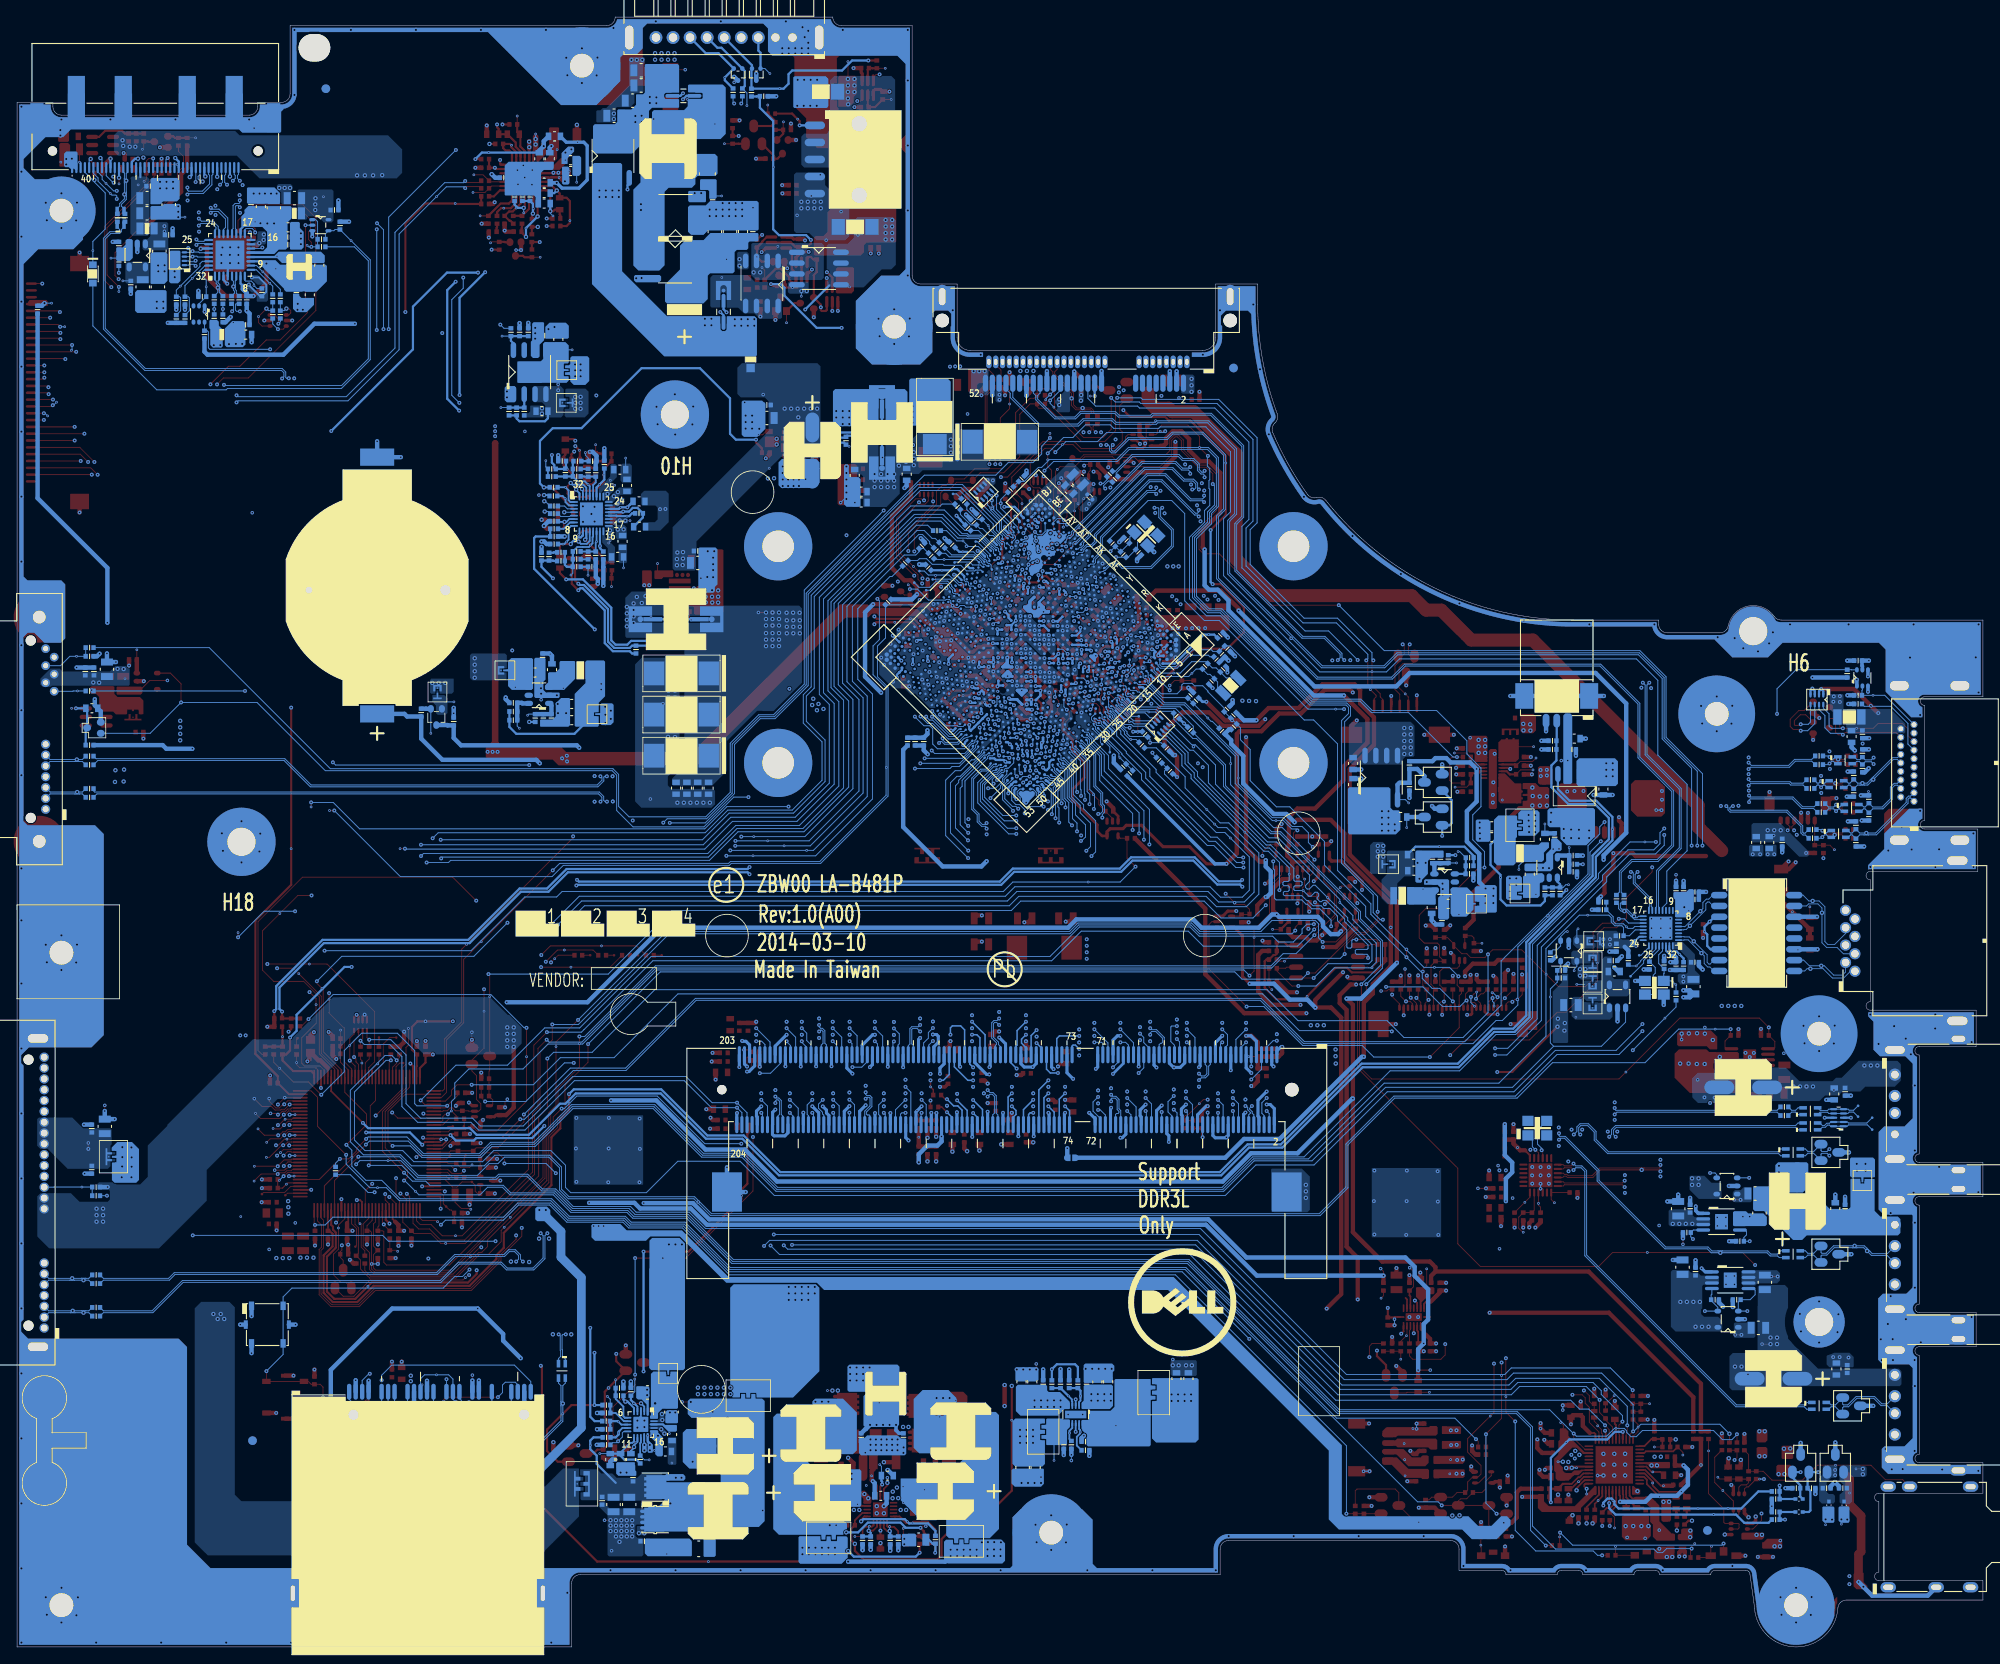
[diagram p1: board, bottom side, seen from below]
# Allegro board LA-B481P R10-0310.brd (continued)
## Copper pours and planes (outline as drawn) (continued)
+1.5VS on TOP (solid shape): 151.23,104.94 166.06,104.94 166.68,105.56 173.46,105.56 174.19,106.29 174.6,106.29 175.46,105.43 175.46,104.35 175.14,104.02 167.6,104.02 166.94,103.36 150.61,103.36 133.28,120.69 130.96,120.69 130.65,120.69 130.18,121.16 129.67,121.16 129.36,120.85 125.02,120.85 123.99,119.81 123.64,119.81 123.49,119.67 123.48,119.66 123.35,119.58 123.26,119.44 123.26,119.43 122.64,118.81 122.48,118.81 122.13,118.46 120.96,118.46 120.81,118.61 120.81,119.03 121.34,119.55 122.77,119.55 122.95,119.73 122.95,119.74 123.06,119.81 123.14,119.92 123.14,119.93 124.37,121.16 124.38,121.16 124.49,121.23 124.56,121.34 124.57,121.35 124.9,121.69 125.66,121.69 125.81,121.84 130.32,121.84 130.74,122.25 133.91,122.25
+1.05VS on BOTTOM (solid shape): 162.06,110.48 162.06,109.5 162.08,109.47 162.61,109.47 162.64,109.45 162.64,109.29 162.61,109.27 162.11,109.27 162.08,109.24 162.08,108.3 161.87,108.09 160.82,108.09 160.49,108.42 160.49,110.46 160.66,110.63 161.9,110.63
+1.05VS on BOTTOM (solid shape): 114.56,116.11 114.56,115.44 114.94,115.06 114.96,115.05 114.99,115.03 115.02,115 115.02,114.84 114.92,114.74 113.72,114.74 113.65,114.81 113.65,114.97 113.66,115 113.66,115.05 113.7,115.1 113.73,115.09 113.8,115.09 113.87,115.09 113.98,115.09 114.16,115.27 114.16,115.8 114.1,115.86 114.1,116.16 114.14,116.16 114.18,116.19 114.21,116.22 114.25,116.24 114.44,116.24
+1.5VS on BOTTOM (solid shape): 163.08,49.45 163.08,48.04 162.67,47.63 156.69,47.63 156.18,48.13 152.71,48.13 147.28,42.7 136.66,42.7 135.81,41.85 95.49,41.85 76.66,23.02 76.66,14.95 75.49,13.77 61.03,13.77 59.9,12.64 56.98,12.64 55.37,14.25 55.37,14.9 55.78,15.31 56.48,15.31 57.6,14.2 59.18,14.2 60.3,15.32 60.98,15.32 60.99,15.29 61.34,15.06 61.69,15.29 61.71,15.32 61.82,15.32 61.83,15.28 62.19,15.03 62.55,15.28 62.56,15.32 74.42,15.32 74.6,15.26 74.79,15.32 74.86,15.32 75.14,15.6 75.14,23.66 94.86,43.38 147.01,43.38 152.47,48.84 158.95,48.84 159.7,49.59 162.94,49.59
+1.5VS on IN2 (solid shape): 174.75,143.15 174.75,140.9 174.65,140.8 174.09,140.8 174,140.89 174,143.28 174.1,143.38 174.52,143.38
+1.5VS on IN2 (solid shape): 167.13,104.26 167.13,94.25 165.49,92.61 165.49,91.96 162.43,88.9 162.43,65.73 162.46,65.7 166.24,61.92 166.24,53.9 164.92,52.58 163.24,52.58 162.96,52.3 162.96,51.57 163.05,51.49 163.05,49.22 162.91,49.09 161.6,49.09 161.41,49.28 161.41,52.95 162.45,53.99 165.13,53.99 165.34,54.2 165.34,62.15 164.96,62.53 163.3,62.53 161.17,64.66 161.17,89.42 164.95,93.2 164.95,94.1 165.7,94.85 165.7,104.56 165.9,104.77 166.62,104.77
+1.5VS on TOP: 164.11,146.86 165.74,146.86 169.19,143.41 175.37,143.41 175.62,143.15 175.62,140.71 175.31,140.4 174.13,140.4 172.83,141.7 168.28,141.7 165.28,144.7 164.24,144.7 163.91,145.03 163.91,146.66
+1.5VS on BOTTOM: 115.22,149.17 115.6,149.17 115.73,149.05 115.73,146.1 115.55,145.92 115.17,145.92 114.96,146.12 114.96,148.92
+1.5VS on BOTTOM: 107.17,149.2 107.52,149.2 107.65,149.07 107.65,147.32 108.77,146.2 108.77,145.01 108.41,144.65 107.22,144.65 106.99,144.88 106.99,149.02
+1.5VS on BOTTOM: 166.15,147.42 166.04,147.53 164.39,147.53 164.39,147.53 163.77,147.53 163.42,147.17 163.42,144.61 163.86,144.16 166.04,144.16 166.23,144.35 166.23,145.11 166.17,145.18 165.72,145.18 165.66,145.24 165.66,145.69 165.72,145.75 166.17,145.75 166.23,145.81 166.23,145.94 166.17,146 165.72,146 165.66,146.07 165.66,146.51 165.72,146.57 166.07,146.57 166.15,146.65
+1.5VS on VCC: 150.12,140.92 149.36,141.68 137.04,141.68 135.92,142.8 135.92,145.59 135.14,146.38 130.73,146.38 129.82,145.47 129.82,142.86 129.53,142.57 108.15,142.57 107.85,142.86 107.85,146.4 108.72,147.27 118.24,147.27 119.28,148.3 119.28,150.65 119.48,150.86 120.69,151.56 121.39,152.77 121.74,153.11 124,153.11 125.53,151.59 129.42,151.59 130.94,153.11 162.67,153.11 162.97,152.81 162.97,148.18 163.88,147.27 165.79,147.27 166.4,146.65 166.4,141.15 166.17,140.92
+1.05VS on IN1: 135.08,111.5 135.44,111.86 139.5,111.86 141.05,110.31 142.07,110.31 148.09,104.29 154.41,104.29 156.52,106.4 156.52,110.36 157.15,111 162.18,111 162.4,110.78 162.4,103.4 161.84,102.84 160.58,102.84 160.19,102.45 160.19,97.04 159.03,95.88 142.73,95.88 135.08,103.53
+1.05VS on IN2: 111.56,112.82 112.75,112.82 115.83,115.9 120.02,115.9 120.68,116.56 127.36,116.56 134.59,109.33 137.34,109.33 137.72,109.71 137.72,111.33 128.8,120.24 119.59,120.24 117.17,117.83 115.09,117.83 111.26,113.99 111.26,113.13
+1.5VS on IN2: 173.99,104.54 175.26,104.54 175.44,104.72 175.44,106.07 175.34,106.17 174.15,106.17 173.92,105.94 173.92,104.62
+1.05VS_SOC on TOP (solid shape): 112.07,114.46 112.07,114.2 110.68,112.81 110.63,112.81 110.22,113.21 110.22,113.34 111.59,114.71 111.82,114.71
+1.05VSP on BOTTOM (solid shape): 163.78,115.51 163.78,113 165.04,111.74 165.04,108.01 164.92,107.9 162.33,107.9 162.23,108 162.23,109.09 162.26,109.12 162.79,109.12 162.79,109.6 162.26,109.6 162.23,109.62 162.23,110.72 161.49,111.46 161.49,115.51 161.63,115.65 163.63,115.65
+1.5VSP on BOTTOM: 170.01,146.12 170.01,147.65 169.82,147.84 166.7,147.84 166.32,147.46 166.32,146.44 166.26,146.38 165.81,146.38 165.75,146.31 165.75,146.19 165.81,146.12 166.26,146.12 166.32,146.06 166.32,145.68 166.26,145.62 165.81,145.62 165.75,145.55 165.75,145.43 165.81,145.36 166.26,145.36 166.32,145.3 166.32,144.47 166.64,144.16 168.42,144.16 168.51,144.24 168.51,145.57 168.88,145.93 169.82,145.93
+1.8VALW on BOTTOM (solid shape): 165.56,151.14 165.56,150.42 165.71,150.26 166.12,150.26 166.17,150.21 166.17,149.93 165.61,149.93 165.61,149.48 165.64,149.45 166.14,149.45 166.17,149.43 166.17,149.17 166.14,149.15 165.66,149.15 165.57,149.05 165.57,148.99 165.56,148.98 165.56,148.38 165.14,147.97 163.81,147.97 163.35,148.43 163.35,151.12 163.56,151.33 165.37,151.33
+1.8VALW on TOP: 58.19,102.41 58.7,102.41 59.44,101.67 59.46,101.67 59.52,101.62 59.52,100.81 59.62,100.71 59.74,100.71 59.77,100.73 60.25,100.73 60.38,100.61 60.38,99.9 61.01,99.26 65.76,99.26 69.27,95.76 70.41,95.76 71.3,94.87 71.3,92.5 70.31,91.51 60.86,91.51 58.07,94.31 58.07,102.28
+1.8VALW on TOP: 101.13,111.84 101.56,111.98 101.51,112.43 101.49,112.47 101.51,112.5 101.8,112.8 102.01,112.8 102.34,112.47 102.34,112.18 102.14,112.03 102.09,111.78 100.1,109.78 100.08,109.78 99.46,109.17 98.02,109.17 97.06,110.13 97.06,111.58 97.31,111.83 98.33,111.83 98.58,112.09 98.58,112.34 98.45,112.47 98.45,112.57 98.89,113 99.17,113 99.55,112.62 99.55,112.29 98.71,111.45 98.45,111.45 98.33,111.33 98.33,110.95 98.83,110.44 99.72,110.44
+1.8VALW on TOP: 102.39,108.94 102.65,109.2 104.2,109.2 104.53,108.87 104.53,107.44 99.22,102.13 99.22,100.45 96.63,97.86 91.11,97.86 90.83,98.14 90.83,108.02 91.62,108.81 93.83,108.81 94.57,108.07 94.57,105.36 93.63,104.42 93.63,100.91 93.83,100.71 97.59,100.71 98.15,101.27 98.15,102.82 102.39,107.06
+1.8VALW on BOTTOM: 70.15,90.64 71.66,90.64 71.83,90.81 71.83,94.01 71.45,94.38 70.34,94.38 70.05,94.1 70.05,92.99 70.01,92.95 70.01,91.92 69.98,91.9 69.47,91.9 69.45,91.87 69.45,91.69 69.47,91.67 69.93,91.67 69.98,91.62 69.98,90.8
+1.8VALW on BOTTOM: 108.52,114.69 107.5,113.67 107.36,113.67 107.09,113.67 106.92,113.84 106.92,113.97 106.93,113.98 106.93,114.75 107.15,114.97 107.27,114.96 107.31,114.97 108.39,114.97 108.52,114.84
+1.8VALW on VCC: 72.4,89.48 68.49,93.39 68.49,93.7 69.6,94.82 74.94,94.82 94.75,114.63 106.98,114.63 107.46,114.16 107.46,113.83 107.22,113.59 107.22,112.87 108.74,111.35 108.74,111.05 106.98,109.29 105.54,109.29 105.31,109.53 105.31,110.16 104.78,110.69 102.79,110.69 84.99,92.89 84.99,90.35 84.12,89.48
+1.8VALW on IN1: 63.1,73.81 59.77,77.14 59.77,80.54 61.85,82.62 65.81,82.62 66.45,83.26 66.45,96.42 60.63,102.23 60.63,115.97 69.04,124.38 82.05,124.38 88.45,130.78 88.45,138.81 92.63,143 107.25,143 108.58,144.33 116.48,144.33 121.06,148.92 130.71,148.92 134.27,152.47 165.38,152.47 165.76,152.09 165.76,148.18 165.23,147.65 140.24,147.65 134.9,142.31 119.03,142.31 117.88,141.17 117.88,141.04 115.62,138.78 109.62,138.78 107.34,136.5 95.95,136.5 93.4,133.95 93.4,129.79 83.4,119.8 73.35,119.8 65.99,112.44 65.99,110.34 66.02,110.31 66.02,104.34 66.86,103.5 73.03,103.5 78.68,97.85 81.65,97.85 82.64,96.86 82.64,93.41 80.19,90.96 80.19,74.37 79.63,73.81
+1.8VALW on IN2: 104.98,120.22 105.72,120.22 106.12,119.81 106.12,119.56 104.07,117.5 104.07,116.56 104.47,116.15 104.96,116.15 104.98,116.18 105.54,116.18 107.55,114.17 107.55,113.97 106.99,113.41 104.78,113.41 102.59,115.59 102.59,117.83
+1.8VALWP on BOTTOM: 66.7,93.11 66.96,93.37 69.73,93.37 69.88,93.22 69.88,92.05 69.85,92.02 69.32,92.02 69.29,92 69.29,91.54 69.32,91.51 69.83,91.51 69.85,91.49 69.85,90.6 70.49,89.96 70.49,87.78 69.8,87.09 68.71,87.09 68.63,87.17 68.63,89.53 67.82,90.35 66.98,90.35 66.7,90.63
+1.8VS on TOP (solid shape): 53.95,101.22 53.95,100.61 53.93,100.58 53.42,100.58 53.39,100.56 53.39,100.02 53.95,100.02 53.95,99.77 53.39,99.77 53.39,99.24 53.42,99.21 53.93,99.21 53.95,99.18 53.95,98.32 53.88,98.25 51.08,98.25 50.83,98.5 50.83,100.66 51.01,100.84 52,100.84 52.45,101.29 53.88,101.29
+1.8VS on BOTTOM: 115.82,118.45 115.88,118.5 116.59,118.5 116.75,118.34 116.75,118.12 116.57,117.94 115.73,117.94 115.71,117.96 115.26,117.96 115.21,118.02 115.14,118.02 115.11,118.05 114.99,118.05 114.94,118.04 114.88,118.05 114.85,118.05 114.8,118.11 114.8,118.25 114.91,118.36 115.09,118.36 115.18,118.45
+1.8VS on BOTTOM: 118.04,135.96 118.04,135.81 117.63,135.41 117.02,135.41 116.28,136.14 116.03,136.14 115.73,136.45 115.73,137.01 115.83,137.11 116.89,137.11
+1.8VS on VCC: 24.9,97.36 21.24,101.02 21.24,104.19 18.7,106.73 18.7,118.84 18.99,119.13 23.91,119.13 23.93,119.15 24.81,119.45 25.5,120.1 27.27,120.8 28.61,119.45 29.3,118.23 30.56,117.65 30.58,117.63 37.26,117.63 37.28,117.65 38.42,118.13 39.14,119.13 48.26,119.13 64.7,122.97 77.89,133.5 79.18,133.61 80.2,134.41 82.35,137.75 84.14,141.29 84.29,141.29 84.79,140.79 105.8,140.79 107.07,142.06 117.78,142.06 118.01,141.83 118.01,136.83 111.3,130.12 92.51,130.12 72.31,109.93 65.84,109.93 62.39,106.48 62.39,97.65 62.09,97.36
+1.8VS_OUT on TOP (solid shape): 56.8,102.36 56.8,99.18 56.52,98.91 54.13,98.91 54.08,98.96 54.08,101.17 54.18,101.27 54.87,101.27 56.01,102.41 56.75,102.41
+1.35V on TOP (solid shape): 60.33,106.68 60.33,104.98 60.2,104.85 59.69,104.85 59.59,104.75 59.59,103.88 59.46,103.76 58.14,103.76 58.07,103.83 58.07,106.68 58.22,106.83 60.18,106.83
+1.35V on BOTTOM (solid shape): 146.82,42.11 146.82,30.81 146.8,30.77 146.77,30.76 146.45,30.49 146.6,30.11 146.64,30.02 146.6,29.94 146.44,29.66 146.57,29.37 146.61,29.33 146.54,29.26 145.7,29.26 145.67,29.28 145.67,29.69 145.67,29.77 145.65,29.79 145.04,29.79 144.96,29.79 144.94,29.77 144.94,29.26 144.91,29.23 144.5,29.23 144.48,29.26 144.48,29.69 144.48,29.77 144.45,29.79 143.84,29.79 143.75,29.79 143.73,29.78 143.73,29.27 143.71,29.25 139.45,29.25 136.38,32.33 136.38,42.11 136.78,42.52 146.41,42.52
+1.35V on TOP: 75.59,45.74 75.59,73.02 75.87,73.3 81.21,73.3 81.69,72.82 81.69,68.93 83.19,67.43 84.28,67.43 84.48,67.23 84.48,66.04 85.32,65.2 85.32,61.72 87.71,59.33 92.84,59.33 93.12,59.61 93.12,61.01 93.35,61.24 94.06,61.24 94.54,61.72 94.54,83.72 99.94,89.11 99.94,89.14 103.79,92.99 108.23,92.99 108.28,92.94 108.28,92.48 108.33,92.43 109.02,92.43 109.02,92.96 109.05,92.99 109.45,92.99 109.48,92.96 109.48,92.43 110.21,92.43 110.21,92.96 110.24,92.99 122.76,92.99 122.76,92.43 123.5,92.43 123.5,92.99 123.96,92.99 123.96,92.43 124.72,92.43 124.72,92.96 124.74,92.99 140.08,92.99 147.4,85.67 147.4,73.33 147.3,73.23 146.21,73.23 146.03,73.4 146.03,74.24 145.42,74.85 143.87,74.85 142.7,73.68 142.7,54.15 142.73,54.13 142.73,41.63 141.38,40.28 81.05,40.28 ; 17 cut-outs
+1.35V on IN1: 59.39,106.93 59.95,106.37 59.95,102.23 65.64,96.54 65.64,83.44 65.26,83.06 61.73,83.06 59.34,80.67 59.34,77.09 63.11,73.31 79.07,73.31 79.36,73.03 79.36,68.55 78.88,68.07 54.82,68.07 52.89,70 52.89,83.49 56.62,87.22 56.62,92.68 50.6,98.7 50.6,106.12 51.41,106.93
+1.35V_SOC on TOP: outline of 186 points within 105.98,92.58 131.29,118.88 ; 6 cut-outs
+1.35V_SOC on BOTTOM: 111.9,107.58 112.16,107.31 112.16,107.3 112.25,107.16 112.4,107.07 112.41,107.06 112.45,107.02 112.45,106.76 112.27,106.58 112.25,106.59 112.08,106.59 111.94,106.51 111.62,106.51 111.44,106.69 111.44,106.92 111.51,107.08 111.45,107.25 111.44,107.27 111.44,107.32 111.69,107.58
+1.35VP on BOTTOM (solid shape): 144.35,29.64 144.35,29.13 144.38,29.11 145.04,29.11 145.06,29.13 145.06,29.64 145.09,29.67 145.52,29.67 145.55,29.64 145.55,29.13 145.57,29.11 151.51,29.11 151.79,28.83 151.79,27.3 151.35,26.86 149.06,26.86 147.93,25.73 147.93,15.18 146.82,14.07 143.47,14.07 142.79,14.75 142.79,28.84 142.97,29.02 142.98,29.02 143.07,29.11 143.84,29.11 143.87,29.13 143.87,29.64 143.89,29.67 144.33,29.67
+1.35VP on BOTTOM: 154.66,26.34 156.14,26.34 156.21,26.41 156.21,26.54 156.14,26.62 155.3,26.62 155.1,26.82 155.1,27.43 154.92,27.61 154.61,27.61 154.54,27.53 154.54,26.46
+1.35VP on IN2: 146.99,27.13 148.31,27.13 148.47,26.97 148.47,26.11 148.34,25.98 147.02,25.98 146.82,26.19 146.82,26.95
+1.35VP on IN2: 153.72,27.51 154.99,27.51 155.1,27.4 155.1,26.41 154.77,26.08 153.7,26.08 153.55,26.24 153.55,27.33
+1.35VS on TOP: 113.57,115.72 113.87,115.72 114.05,115.54 114.05,115.06 114.28,114.83 114.28,114.45 113.97,114.15 113.97,113.59 114.1,113.46 114.58,113.46 115.08,112.96 115.08,112.63 114.81,112.37 114.28,112.37 113.01,113.64 113.01,113.92 113.49,114.4 113.49,114.68 113.57,114.76 113.57,115.06 113.47,115.16 113.47,115.62
+1.35VS on TOP: 56.04,107.06 54.36,107.06 54.33,107.08 54.33,109.4 54.36,109.42 54.36,111.38 65.05,122.07 80.88,122.07 80.89,122.06 81.56,122.73 83.59,122.73 88.8,127.94 98.48,127.94 101.86,131.32 101.86,131.75 104.5,134.39 104.88,134.39 105.29,133.98 105.29,132.59 101.68,128.98 101.68,127.53 108.66,120.55 108.72,120.55 108.72,119.56 108.54,119.38 108.13,119.38 105.49,122.02 104.07,122.02 100.41,125.68 90.35,125.68 84.69,120.01 84.66,120.01 84.66,113.64 87.1,111.2 87.1,110.23 86.82,109.95 84.51,109.95 78.31,116.15 72.7,116.15 70.73,118.12 66.11,118.12 57.41,109.42 57.41,107.39 56.57,106.55 56.21,106.55 56.09,106.68 56.09,107.01
+1.35VS on BOTTOM: 104.02,134.97 104.55,134.97 105.82,133.7 105.82,133.3 105.62,133.09 105.01,133.09 103.81,134.29 103.81,134.77
+1.35VS on BOTTOM: 108.92,121 110.16,121 110.24,120.93 110.24,120.72 110.14,120.62 109.91,120.62 109.81,120.52 109.81,119.94 109.33,119.45 108.33,119.45 108.21,119.58 108.21,119.84 108.33,119.96 109.12,119.96 109.27,120.11 109.27,120.47 109.12,120.62 108.89,120.62 108.79,120.72 108.79,120.88
+1.35VS on IN1: 100.77,128.5 101.55,127.71 101.55,124.89 109.16,117.28 109.16,115.4 107.14,113.38 107.14,112.52 107.88,111.78 111.15,111.78 113.02,113.65 113.71,113.65 114.41,112.95 114.41,112.62 112.45,110.67 111.13,110.67 110.99,110.81 110.75,110.81 110.48,110.54 108.11,110.54 107.19,109.62 101.86,109.62 97.53,105.29 86.5,105.29 84.51,107.29 84.51,110.72 85.06,111.26 86.91,111.26 88.14,110.03 95.13,110.03 97.41,112.32 102.44,112.32 104.88,114.76 105.54,114.76 106.09,115.3 107.36,115.3 107.92,115.86 107.92,116.56 98.49,125.98 94.34,125.98 94.06,126.26 94.06,128.09 94.47,128.5
+1.35VS_OUT on TOP (solid shape): 56.8,106.04 56.8,103.83 56.75,103.78 54.74,103.78 54.38,104.14 54.38,106.37 54.44,106.42 56.42,106.42
+3V_HUB on TOP: 53.45,54.68 54.51,54.68 55.35,55.52 55.35,57.58 55.58,57.81 56.92,57.81 57.03,57.71 57.03,54.71 56.7,54.38 53.42,54.38 53.37,54.43 53.37,54.61
+3V_HUB on IN2: 55.45,56.23 57,56.23 57.18,56.06 57.18,49.35 56.65,48.82 51.74,48.82 51.26,49.3 51.26,50.72 51.67,51.13 54.18,51.13 55.12,52.07 55.12,55.9
+3V_WLAN on TOP (solid shape): 118.94,149.73 118.94,147.23 118.8,147.09 118.06,147.09 117.88,147.27 117.88,147.98 117.69,148.17 117.31,148.17 117.3,148.18 116.74,148.18 116.67,148.26 116.67,149.63 116.92,149.88 118.79,149.88
+3V_WLAN on TOP: 111.41,150.75 112.8,150.75 112.91,150.65 112.91,150.01 113.19,149.73 113.19,148.03 113.01,147.85 112.3,147.85 112.14,148 111.26,148 110.93,148.33 110.93,149.71 111.33,150.11 111.33,150.67
+3V_WLAN on TOP: 92.56,149.22 94.72,149.22 94.8,149.15 94.8,145.87 94.72,145.79 92.48,145.79 92.38,145.9 92.38,149.05
+3V_WLAN on BOTTOM: 105.59,149.17 105.9,149.17 106,149.07 106,145.97 105.87,145.84 105.59,145.84 105.39,146.05 105.39,148.97
+3V_WLAN on BOTTOM: 92.59,149.17 93.83,149.17 93.98,149.02 93.98,147.11 93.81,146.94 92.61,146.94 92.41,147.14 92.41,148.99
+3V_WLAN on BOTTOM: 116.64,146.76 118.34,146.76 118.57,146.99 118.57,149.71 118.42,149.86 116.72,149.86 116.54,149.68 116.54,146.86
+3V_WLAN on IN1: 92.33,145.74 105.79,145.74 107.06,147.01 117.45,147.01 118.52,148.08 118.52,149.68 118.37,149.83 113.24,149.83 112.91,150.16 112.91,150.7 112.86,150.75 111.36,150.75 111.31,150.7 111.31,150.06 110.42,149.17 92.75,149.17 92.03,148.45 92.03,146.05
+3VALW on BOTTOM (solid shape): 105.39,30.58 105.39,28.88 105.62,28.65 105.62,27.96 105.54,27.89 102.34,27.89 101.96,28.27 101.96,30.58 102.14,30.76 105.21,30.76
+3VALW on BOTTOM (solid shape): 55.9,90.21 55.9,87.77 55.73,87.6 54.18,87.6 54.05,87.73 54.05,88.03 54.11,88.08 54.59,88.08 54.61,88.1 54.61,88.54 54.56,88.59 54.05,88.59 54.03,88.61 54.03,90.19 54.26,90.42 55.68,90.42
+3VALW on BOTTOM (solid shape): 138.81,12.86 138.81,9.95 138.62,9.76 133.75,9.76 133.34,10.17 133.34,10.18 133.27,10.28 133.17,10.35 133.16,10.35 133.05,10.46 133.05,10.9 133.09,10.91 133.35,11.25 133.09,11.59 133.05,11.6 133.05,12.81 133.2,12.96 134.27,12.96 134.3,12.94 134.3,12.43 134.32,12.4 135.01,12.4 135.03,12.43 135.03,12.5 135.04,12.55 135.05,12.56 135.05,12.96 135.06,12.96 135.49,12.96 135.52,12.94 135.52,12.43 135.54,12.4 136.2,12.4 136.25,12.45 136.25,12.96 136.28,12.99 138.68,12.99
+3VALW on TOP: 48.06,77.8 46.84,77.8 46.1,78.53 46.1,85.19 45.01,86.28 45.01,90.42 43.59,91.84 43.59,93.01 45.01,94.44 45.01,96.29 45.32,96.59 46.36,96.59 46.92,96.04 46.92,93.85 50.12,90.65 55.6,90.65 56.16,90.09 56.16,85.9
+3VALW on TOP: 195.86,46.99 197.49,46.99 197.67,46.81 197.67,44.96 197.51,44.8 195.58,44.8 195.38,45.01 195.38,46.51
+3VALW on TOP: 147.35,12.11 147.35,21.36 151.7,25.71 151.7,30.54 151.4,30.84 146.79,30.84 146.5,30.55 146.5,29.2 140.86,23.56 140.86,16.77 137.92,13.83 134.77,13.83 134.77,13.82 134.28,13.82 134.12,13.66 134.12,10.67 134.45,10.34 145.58,10.34
+3VALW on BOTTOM: 45.11,79.98 45.65,79.98 45.65,80.57 45.83,80.57 45.85,80.54 45.85,80.01 45.88,79.98 46.36,79.98 46.37,79.97 47.12,79.97 47.12,79.96 47.53,79.55 47.53,78.66 47.12,78.26 45.9,78.26 45.85,78.2 45.85,77.72 45.65,77.72 45.65,78.26 45.62,78.28 45.14,78.28 45.09,78.33 45.09,79.96
+3VALW on IN1: 54.6,50.65 66.2,39.05 74.07,39.05 77.24,42.22 191.78,42.22 195.49,45.94 197.39,45.94 197.65,45.67 197.65,35.71 197.17,35.23 179.86,35.23 172.29,27.66 101.02,27.66 96.31,32.36 58.42,32.36 41.53,49.25 41.53,90.14 44.01,92.62 55.64,92.62 55.97,92.29 55.97,87.25 52.48,83.76 52.48,69.24 48.62,65.38 48.62,51.53 49.51,50.65
+3VALW_EC on TOP: 196.37,52.91 198.38,52.91 198.73,52.55 200.26,52.55 200.33,52.47 200.33,50.44 200.32,50.43 200.32,50.28 200.18,50.14 199.67,50.14 199.34,49.81 199.34,47.78 199.24,47.67 196.27,47.67 196.14,47.8 196.14,52.68
+3VALW_EC on IN1: 194.39,68.1 193.45,67.16 193.45,64.44 202.06,55.83 202.06,48.41 201.53,47.88 195.64,47.88 192.79,45.03 183.67,45.03 182.35,46.34 174.6,46.34 172.8,48.15 172.8,73.73 173.84,74.78 193.91,74.78 194.39,74.29
+3VALW_SOC on BOTTOM (solid shape): 104.35,116.36 104.63,116.36 104.76,116.24 104.76,116.11 104.17,115.53 104,115.53 103.94,115.58 103.94,115.91 103.74,116.11 103.74,116.34 103.94,116.54 104.17,116.54
+3VALW_UL2 on BOTTOM: 41.46,78.31 43.21,78.31 43.44,78.53 43.44,80.85 43.54,80.95 44.33,80.95 44.63,80.64 44.63,78.23 44.71,78.15 45.49,78.15 45.55,78.1 45.55,77.62 45.6,77.57 45.95,77.57 46,77.62 46,77.75 45.98,77.77 45.98,78.1 46.03,78.15 46.61,78.15 46.74,78.03 46.74,76.02 46.43,75.72 45.88,75.72 45.85,75.69 45.85,75.21 45.83,75.18 45.65,75.18 45.65,75.66 45.6,75.72 44.56,75.72 44,76.27 41.68,76.27 41.38,76.58 41.38,78.23
+3VALW_UL3 on BOTTOM: 45.27,81.63 48.03,81.63 48.24,81.43 48.24,80.16 48.01,79.93 47.45,79.93 47.25,80.13 46,80.13 46,80.69 45.98,80.72 45.55,80.72 45.49,80.67 45.49,80.16 45.47,80.13 45.06,80.13 44.91,80.29 44.91,81.28
+3VALWP on BOTTOM (solid shape): 141.77,26.95 141.77,13.81 141.11,13.16 136.15,13.16 136.12,13.12 136.12,12.62 136.09,12.59 135.69,12.59 135.66,12.62 135.66,13.12 135.64,13.15 134.95,13.15 134.92,13.12 134.92,12.62 134.9,12.59 134.47,12.59 134.44,12.62 134.44,13.12 134.42,13.15 133.65,13.15 133.56,13.2 133.55,13.29 133.53,13.63 133.23,13.79 133.16,13.82 133.13,13.89 133.13,14.45 133.62,14.93 135.36,14.93 136.01,15.57 136.01,19.98 138.61,22.57 138.61,27.16 138.79,27.35 141.37,27.35
+3VLP on TOP: 198.05,47.06 200.97,47.06 201.15,46.89 201.15,46.31 200.97,46.14 200.64,46.14 200.38,45.88 200.38,45.18 200.05,44.85 198.07,44.85 197.84,45.08 197.84,46.86
+3VLP on BOTTOM: 181.84,113.54 181.99,113.38 181.99,111.88 181.87,111.76 181.41,111.76 181.38,111.78 181.38,112.32 180.9,112.32 180.88,112.29 180.88,111.81 180.83,111.76 179.45,111.76 179.23,111.99 179.23,113.49 179.28,113.54
+3VLP on IN1: 198.44,46.02 201.27,46.02 206.07,50.82 206.07,75.36 177.85,103.58 177.85,113.56 178.39,114.09 182.22,114.09 182.71,113.61 182.71,104.93 209.63,78 209.63,49.15 203.69,43.2 198.34,43.2 198.14,43.4 198.14,45.73
+3VS on TOP (solid shape): 177.52,21.79 177.52,20.72 178.46,19.78 179.1,19.78 179.53,19.35 179.53,17.73 179.48,17.68 177.71,17.68 177.54,17.85 177.54,19.24 177.55,19.25 177.55,19.73 177.14,20.14 177.14,21.79 177.22,21.87 177.45,21.87
+3VS on TOP (solid shape): 47.86,16.5 50.88,16.5 51.45,17.07 51.45,17.86 51.52,17.93 52.08,17.93 52.16,17.85 52.16,16.28 51.71,15.82 47.13,15.82 47.11,15.84 47.11,16.31 45.59,17.82 45.4,17.82 45.3,17.92 45.3,18.81 45.37,18.87 45.49,18.87
+3VS on BOTTOM (solid shape): 169.66,51.39 169.66,50.15 169.43,49.92 168.22,49.92 167.91,50.23 167.91,51.23 168.3,51.62 169.43,51.62
+3VS on BOTTOM (solid shape): 179.78,18.82 179.78,17.96 179.58,17.75 177.73,17.75 177.47,18.01 177.47,18.9 177.65,19.07 179.53,19.07
+3VS on BOTTOM (solid shape): 216.56,158.82 216.56,156.67 216.31,156.41 213.13,156.41 212.88,156.67 212.88,158.95 213.01,159.08 216.31,159.08
+3VS on BOTTOM (solid shape): 97.39,31.44 97.39,30.83 97.36,30.81 96.85,30.81 96.83,30.78 96.83,30.05 97.36,30.05 97.39,30.02 97.39,29.59 96.85,29.59 96.83,29.56 96.83,28.88 96.88,28.83 97.34,28.83 97.39,28.78 97.39,24.46 96.91,23.97 92.29,23.97 91.93,24.34 91.93,31.34 92.1,31.52 97.31,31.52
+3VS on TOP: 119.62,150.66 119.89,150.92 122.84,150.92 122.96,150.8 122.96,148.77 121.52,147.32 121.52,145.84 119.61,143.94 119.61,139.29 120.15,138.76 121.19,138.76 122.84,137.11 125.58,137.11 125.86,136.83 125.86,135.94 125.76,135.84 122.74,135.84 121.11,137.46 119.26,137.46 117.99,138.73 117.99,145.57 119.62,147.2
+3VS on TOP: 144.3,70.58 144.17,70.71 144.17,72.54 144.28,72.64 147.27,72.64 152.92,78.29 171.75,78.29 173.82,76.22 173.82,69.92 173.59,69.7 171.07,69.7 170.84,69.92 170.84,72.74 169.66,73.92 156.3,73.92 152.96,70.58
+3VS on TOP: 217.28,175.21 217.38,175.11 217.38,172.79 217.25,172.67 215.93,172.67 215.78,172.82 215.78,174.02 215.77,174.07 215.32,174.52 215.32,175.09 215.44,175.21
+3VS on TOP: 102.06,148.16 104.5,148.16 104.68,148.33 104.68,149.12 104.47,149.32 95.61,149.32 95.41,149.12 95.41,146.76 95.66,146.51 98,146.51 98.5,147.01 100.94,147.01 101.07,146.89 101.4,146.89 101.58,147.06 101.58,147.67
+3VS on TOP: 26.06,94 31.91,94 33.79,92.12 33.79,92.1 35.16,90.73 35.16,82.4 33.79,81.02 33.79,76.27 32.26,74.75 28.1,74.75 27.99,74.85 27.99,75.87 28.3,76.17 31.14,76.17 31.97,77 31.97,81.61 33.35,82.99 33.35,85.08 31.97,86.46 31.97,90.41 30.69,91.69 26.19,91.69 25.76,92.12 25.76,93.7
+3VS on BOTTOM: 25.84,94.05 27.26,94.05 27.41,93.9 27.41,92.81 27.28,92.68 25.91,92.68 25.73,92.86 25.73,93.95
+3VS on BOTTOM: 198.29,71.24 202.76,71.24 212.79,61.21 212.79,61.08 215.08,58.8 215.08,55.12 215.97,54.23 218.76,54.23 219.02,54.48 220.79,54.48 221.05,54.23 221.05,53.72 220.92,53.59 219.65,53.59 219.52,53.46 219.52,52.45 219.78,52.19 223.08,52.19 224.1,53.21 227.65,53.21 228.03,52.83 228.03,48.13 226.64,46.73 213.76,46.73 208.17,52.32 208.17,55.93 199.85,64.25 197.18,64.25 192.48,68.95 192.48,70.39 190.4,72.46 185.7,72.46 182.71,69.47 172.53,69.47 171.26,70.74 171.26,72.77 172.6,74.1 172.89,74.1 174.98,76.2 192.6,76.2 192.62,76.17 193.36,76.17
+3VS on BOTTOM: 198.38,169.14 199.29,169.14 199.44,169.29 199.44,170.48 199.95,170.99 199.95,171.35 199.77,171.52 198.33,171.52 198.12,171.32 198.12,170.89 198.28,170.74 198.28,169.24
+3VS on VCC: 85.22,28.52 83.72,30.02 83.72,46.03 81.54,48.21 61.28,48.21 60.99,48.5 60.99,87.81 58.81,89.99 47.55,89.99 43.97,86.41 43.97,71.93 42.72,70.69 25.03,70.69 24.67,71.05 24.67,74.45 24.9,74.69 25.49,74.69 25.7,74.68 25.7,74.69 26.72,74.69 28.22,76.19 28.22,89.69 26.97,90.94 26.47,90.94 26.46,90.94 26.23,90.94 25.94,91.24 25.94,96.55 26.23,96.85 64.31,96.85 67.44,93.72 67.44,93.7 67.59,93.55 67.61,93.55 67.98,93.18 67.98,93.16 68.13,93.01 68.15,93.01 72.19,88.97 79.24,88.97 79.53,88.68 79.53,87.96 79.66,62.45 83.74,58.37 164.09,58.37 169.83,64.1 169.83,135.82 166.91,138.74 166.91,146.86 166,147.78 164.09,147.78 163.48,148.39 163.48,160.12 171.33,167.97 185.47,167.97 195.38,158.06 228.97,158.06 229.13,157.9 229.13,48.21 205.68,48.21 205.39,48.5 205.39,127.81 176.66,156.54 169.47,156.54 168.81,155.88 168.81,152.75 175.8,145.76 175.8,82.26 182.65,75.41 182.65,57.08 173.66,48.08 100.63,48.08 98.96,46.41 98.96,29.52 97.97,28.52
+3VS on IN1: 198,170.23 216.51,170.23 220.48,166.27 220.48,161.77 217.88,159.18 213.08,159.18 212.55,158.65 212.55,156.61 213.08,156.08 220.42,156.08 222.51,158.16 222.51,169.77 217.33,174.95 198.5,174.95 197.59,174.04 197.59,170.64
+3VS on IN1: 40.67,27.25 48.16,27.25 50.19,25.22 60.61,25.22 66.45,19.38 66.45,16.33 66.2,16.08 54.77,16.08 52.99,17.85 52.99,18.74 47.02,24.71 40.92,24.71 40.41,25.22 40.41,27
+3VS on IN2: 106.99,149.58 116.51,149.58 117.4,150.47 121.19,150.47 121.36,150.29 121.36,149.55 119.47,147.66 107.81,147.66 106.76,146.61 105.06,146.61 105.05,146.62 100.91,146.62 100.46,147.06 100.46,147.47 101.08,148.09 105.5,148.09
+3VS on IN2: 46.63,24.08 41.18,24.08 40.03,25.22 31.52,25.22 30.89,24.59 27.84,24.59 27.59,24.84 27.59,25.86 27.99,26.26 27.99,67.08 25.68,69.39 25.68,73.56 28.27,76.15 30.74,76.15 31.09,75.79 31.09,74.01 29.49,72.41 29.49,70.84 31.52,68.81 31.52,39.95 34.57,36.9 38.19,36.9 48.54,26.56 48.54,25.98
+3VS_CAM on TOP: 217.76,173.86 218.9,173.86 218.98,173.78 218.98,171.93 218.9,171.85 217.83,171.85 217.71,171.98 217.71,173.81
+3VS_LCDIN on BOTTOM: 215.12,162.41 217.53,162.41 217.71,162.23 217.71,160.02 217.55,159.87 214.99,159.87 214.86,159.99 214.86,162.15
+3VS_OUT on BOTTOM (solid shape): 101.78,31.29 101.78,28.14 102.24,27.68 104.68,27.68 104.78,27.58 104.78,26.72 104.88,26.62 105.54,26.62 105.64,26.52 105.64,25.59 105.57,25.52 105.57,25.4 105.31,25.14 105.29,25.14 105.01,24.9 105.06,24.53 105.06,23.92 105.05,23.91 105.05,23.68 104.88,23.52 97.69,23.52 97.54,23.67 97.54,28.98 97.51,29 97.01,29 96.98,29.03 96.98,29.41 97.01,29.44 97.54,29.44 97.54,30.2 97.01,30.2 96.98,30.22 96.98,30.6 97.01,30.63 97.51,30.63 97.54,30.66 97.54,31.37 97.59,31.42 101.65,31.42
+3VS_RT on BOTTOM (solid shape): 207.85,155.5 207.85,154.61 207.75,154.51 207.75,152.65 207.46,152.36 206.44,152.36 206.3,152.5 206.3,154.46 206.76,154.91 206.76,155.37 206.99,155.6 207.75,155.6
+3VS_RT on BOTTOM: 193.53,167.03 194.44,167.03 195.15,167.74 196.27,167.74 196.4,167.61 196.4,167.46 196.52,167.33 197.51,167.33 197.51,170.76 197.39,170.89 193.5,170.89 193.32,170.71 193.32,167.23
+3VS_RT on IN1: 194.52,170.66 196.62,170.66 198.05,169.24 198.05,158.04 199.93,156.16 201.83,156.16 202.92,155.06 202.92,152.4 203.38,151.94 206.12,151.94 206.3,152.12 206.3,152.86 206.45,153.01 207.85,153.01 208.11,152.75 208.11,150.62 207.7,150.21 199.8,150.21 194.26,155.75 194.26,170.41
+5V_HDD on BOTTOM: 219.76,56.06 224.46,56.06 226.8,58.39 227.66,58.39 228.04,58.77 228.04,61.87 227.84,62.08 223.93,62.08 222.66,60.81 219.48,60.81 219.31,60.63 219.31,58.93 219.46,58.77 219.46,58.04 219.43,58.01 218.93,58.01 218.9,57.99 218.9,57.78 218.93,57.76 219.43,57.76 219.46,57.73 219.46,57.22 219.43,57.2 218.93,57.2 218.9,57.17 218.9,57 218.95,56.94 219.43,56.94 219.46,56.92 219.46,56.36
+5V_HUB on TOP: 53.47,54.18 56.75,54.18 56.85,54.07 56.85,51.08 56.75,50.98 55.99,50.98 55.76,51.2 55.76,51.64 53.39,54 53.39,54.1
+5V_PVDD on TOP (solid shape): 49.6,25.55 49.6,24.29 49.75,24.14 49.75,22.59 50.26,22.08 50.26,20.65 50.08,20.48 50.08,19.74 49.85,19.51 48.54,19.51 47.9,20.15 47.39,20.15 46.89,20.65 45.75,20.65 45.69,20.71 45.69,20.78 45.75,20.84 46,20.84 46.02,20.83 46.1,20.8 46.18,20.79 47.13,20.79 47.21,20.72 47.91,20.72 48.23,20.39 48.86,20.39 48.89,20.43 48.98,20.43 49.23,20.67 49.23,21.06 49.61,21.44 49.61,21.88 48.13,23.37 47.64,23.37 47.15,22.88 47.14,22.87 47.03,22.79 46.95,22.68 46.95,22.67 46.89,22.62 45.75,22.62 45.69,22.68 45.69,22.81 45.75,22.87 46.7,22.87 48.57,24.74 48.57,25.28 48.92,25.64 49.51,25.64
+5V_USB_PWR1 on BOTTOM (solid shape): 15.57,57.25 15.57,55.22 15.42,55.07 14.28,55.07 14.23,55.01 14.23,54.51 14.2,54.48 14.05,54.48 14.02,54.51 14.02,55.04 14,55.07 12.73,55.07 12.65,55.14 12.65,57.15 12.88,57.38 15.45,57.38
+5V_USB_PWR1 on TOP: 13.62,55.32 13.34,55.6 13.34,64.39 12.04,65.68 10.27,65.68 9.6,66.34 9.6,68.32 10,68.72 12.16,68.72 12.2,68.76 14.48,68.76 16.01,67.23 23.78,67.23 24.08,66.93 24.08,63.83 23.85,63.6 18.57,63.6 17.73,62.76 17.73,58.6 17.64,58.36 17.73,58.12 17.73,56.21 17.76,56.18 17.76,55.52 17.55,55.32
+5V_USB_PWR1 on BOTTOM: 16.46,65.12 16.93,64.65 18.51,64.65 19.16,64.01 26.67,64.01 27.16,64.49 27.16,67.26 26.47,67.94 23.12,67.94 21.52,66.34 17.61,66.34 17.21,66.74 16.55,66.74 14.56,68.73 12.25,68.73 12.23,68.72 10.02,68.72 9.63,68.32 9.63,66.39 10.34,65.68 13.8,65.68 14.35,65.12
+5V_USB_PWR1_R1 on TOP: 23.64,69.72 25.86,69.72 26.06,69.52 26.06,68.1 25.81,67.84 22.63,67.84 22.3,68.17 22.3,69.11 23.03,69.84 23.52,69.84
+5V_USB_PWR1_R2 on TOP: 24.54,66.55 26.62,66.55 26.75,66.42 26.75,65.58 26.57,65.4 25.76,65.4 25.66,65.3 25.66,63.15 25.37,62.86 24.6,62.86 24.31,63.15 24.31,66.32
+5V_USB_PWR2 on BOTTOM (solid shape): 15.52,54.81 15.52,51.56 15.73,51.36 17.96,51.36 19.18,52.58 23.65,52.58 25.07,54 26.83,54 26.93,53.9 26.93,51.31 26.72,51.1 25.63,51.1 22.25,47.72 21.19,47.72 20.65,48.26 9.96,48.26 9.68,48.54 9.68,50.17 9.97,50.46 12.03,50.46 12.7,51.13 12.7,54.81 12.75,54.86 13.85,54.86 13.87,54.84 13.87,54.35 13.9,54.33 14.35,54.33 14.38,54.35 14.38,54.86 14.41,54.89 15.45,54.89
+5V_USB_PWR2_R1 on BOTTOM (solid shape): 29.29,50.95 29.29,49.5 29.14,49.35 25.51,49.35 25.33,49.53 25.33,50.42 25.73,50.82 27.51,50.82 27.77,51.08 29.16,51.08
+5V_USB_PWR2_R2 on BOTTOM: 27.18,53.92 28.02,53.92 28.38,53.57 29.06,53.57 29.32,53.31 29.32,52.37 29.09,52.14 27.23,52.14 27.08,52.3 27.08,53.82
+5V_USB_PWR3 on BOTTOM: 9.76,30.58 24.46,30.58 24.77,30.88 24.77,32.08 26.42,33.73 26.42,39.93 26.39,39.95 26.39,42.24 26.19,42.44 23.22,42.44 22.84,42.06 22.84,36.14 19.33,32.64 9.86,32.64 9.55,32.33 9.55,30.78
+5V_USB_PWR3 on IN1: 9.81,32.59 18.06,32.59 23.52,38.05 26.32,38.05 26.95,37.41 26.95,35.13 26.32,34.49 23.52,34.49 19.46,30.43 9.93,30.43 9.55,30.81 9.55,32.33
+5V_USB_PWR3_R1 on BOTTOM: 28.16,44.18 28.29,44.05 28.29,42.56 28.11,42.38 26.69,42.38 26.43,42.63 24.12,42.63 23.79,42.96 23.79,43.83 24.15,44.18
+5V_USB_PWR3_R2 on BOTTOM: 26.75,38.15 27.59,38.15 27.71,38.02 29.09,38.02 29.19,37.92 29.19,36.35 29.09,36.24 26.83,36.24 26.67,36.4 26.67,38.07
+5VA on TOP (solid shape): 39.68,17.55 39.68,17.02 38.99,16.33 38.99,14.65 38.69,14.35 38.69,12.93 38.23,12.47 36.17,12.47 36.1,12.55 36.1,13.18 36.22,13.31 36.48,13.31 37.93,14.76 37.93,16.61 38.99,17.68 39.55,17.68
+5VALW on TOP (solid shape): 36.15,69.54 36.15,66.75 34.34,64.95 31.35,64.95 31.33,64.96 28.31,64.96 27.97,65.3 27.97,67.23 28.17,67.43 31.22,67.43 31.58,67.79 31.58,68.43 31.42,68.58 28.73,68.58 28.6,68.7 28.6,69.59 28.76,69.75 32.08,69.75 32.39,70.05 35.64,70.05
+5VALW on BOTTOM (solid shape): 170.03,155.14 170.03,153.19 170.18,153.03 170.18,151.38 169.93,151.13 169.35,151.13 169.17,151.31 169.17,152.68 168.63,153.21 168.63,155.22 168.74,155.32 169.85,155.32
+5VALW on BOTTOM (solid shape): 113.34,30.5 113.34,27.66 112.8,27.13 108.41,27.13 107.65,27.89 107.12,27.89 107.04,27.96 107.04,28.75 108.18,29.89 109.5,29.89 109.68,30.07 109.68,30.58 109.83,30.73 113.11,30.73
+5VALW on BOTTOM (solid shape): 58.93,89.18 59.39,89.18 59.57,89 59.57,87.42 59.54,87.4 59.05,87.4 59.02,87.37 59.02,86.89 59.54,86.89 59.57,86.87 59.57,86.18 59.49,86.1 57.1,86.1 56.98,86.23 56.98,89.13 57.18,89.33 58.78,89.33
+5VALW on BOTTOM (solid shape): 119.97,12.57 119.97,12.14 119.97,12.04 120.01,12 120.64,12 120.7,12.06 120.7,12.55 120.73,12.57 121.52,12.57 121.76,12.33 121.76,10.21 121.34,9.79 114.93,9.79 114.61,10.11 114.61,12.14 115.07,12.6 118.72,12.6 118.77,12.55 118.77,12.14 118.77,12.06 118.78,12.06 118.8,12.04 118.87,12.04 119.39,12.04 119.47,12.04 119.49,12.05 119.49,12.57 119.52,12.6 119.94,12.6
+5VALW on TOP: 33.23,50.32 44.02,50.32 46.79,47.55 56.52,47.55 57.13,48.16 57.13,51.81 57.43,52.12 58.58,52.12 58.83,51.86 58.83,47.09 57.41,45.67 45.75,45.67 42.88,48.54 33.76,48.54 32.95,49.35 32.95,50.04
+5VALW on BOTTOM: 34.17,51.31 36.66,51.31 36.83,51.13 36.83,49.5 36.66,49.32 32.11,49.32 31.98,49.45 31.98,50.29 32.08,50.39 33.79,50.39 34.04,50.65 34.04,51.18
+5VALW on BOTTOM: 32.64,55.24 34.29,55.24 34.4,55.14 34.4,54 34.38,53.99 34.38,53.6 33.3,52.53 30.76,52.53 30.64,52.65 30.64,54.3 30.76,54.43 31.83,54.43
+5VALW on BOTTOM: 173,114.76 173.56,114.76 173.59,114.73 173.59,114.25 173.05,114.25 173.03,114.22 173.03,113.46 173.16,113.33 177.04,113.33 177.32,113.61 177.32,116.28 177.12,116.48 173.21,116.48 173,116.28
+5VALW on BOTTOM: 36.58,43.99 36.58,37.54 36.02,36.98 30.76,36.98 30.56,37.18 30.56,38.25 31.02,38.71 32.69,38.71 33.02,39.04 33.02,39.57 32.9,39.7 32.9,42.31 32.74,42.47 31.09,42.47 30.94,42.62 30.94,43.46 31.02,43.53 33.05,43.53 33.4,43.89 34.22,43.89 34.52,44.19 36.38,44.19
+5VALW on BOTTOM: 155.02,130.88 156.98,130.88 157.08,130.99 157.08,131.77 156.98,131.87 155.65,131.87 155.32,132.2 155.32,133.58 155.58,133.83 157.13,133.83 157.28,133.98 157.28,135.18 156.9,135.56 154.36,135.56 154.03,135.23 154.03,131.87
+5VALW on VCC: outline of 98 points within 25.81,9.75 204.88,156.03 ; 1 cut-out
+5VALW on IN1: 177.13,129.87 177.13,151.27 172.09,156.31 169.9,156.31 169.27,155.67 169.27,143.99 168.61,143.33 162.16,143.33 153.95,135.13 153.95,133.45 154.31,133.09 155.25,133.09 160.56,138.4 170.03,138.4 170.26,138.17 170.26,131.57 168.68,130 168.68,129.23 168.81,129.11 176.37,129.11
+5VALWP on BOTTOM (solid shape): 119.18,27.13 119.18,22.32 121.5,20 121.5,13.08 121.19,12.76 120.67,12.76 120.61,12.7 120.58,12.7 120.58,12.21 120.53,12.16 120.12,12.16 120.09,12.19 120.09,12.69 120.07,12.7 120.02,12.76 119.4,12.76 119.36,12.72 119.36,12.19 119.33,12.16 118.93,12.16 118.9,12.19 118.9,12.74 118.88,12.76 116.39,12.76 115.32,13.83 115.32,27.18 115.7,27.56 118.75,27.56
+5VS on TOP (solid shape): 38.51,11.31 38.51,10.38 38.42,10.28 36.29,10.28 36.14,10.42 36.14,11.71 36.2,11.76 38.06,11.76
+5VS on BOTTOM (solid shape): 47.63,103.88 47.63,101.17 47.4,100.94 43.06,100.94 42.78,101.22 42.78,103.83 43.13,104.19 47.32,104.19
+5VS on BOTTOM (solid shape): 113.74,26.44 113.74,21.49 113.41,21.16 110.24,21.16 109.93,21.46 109.93,24.2 109.96,24.23 110.47,24.23 110.49,24.25 110.49,24.97 110.47,24.99 109.96,24.99 109.93,25.02 109.93,25.42 109.96,25.45 110.49,25.45 110.49,26.19 110.47,26.21 109.93,26.21 109.93,26.72 109.99,26.77 113.41,26.77
+5VS on BOTTOM (solid shape): 219.31,58.54 219.31,58.19 219.28,58.16 218.77,58.16 218.75,58.14 218.75,57.61 218.77,57.58 219.26,57.58 219.28,57.55 219.28,57.35 218.77,57.35 218.75,57.33 218.75,56.82 218.77,56.79 219.23,56.79 219.28,56.74 219.28,54.73 218.98,54.43 216.44,54.43 216.11,54.76 216.11,58.37 216.94,59.21 218.65,59.21
+5VS on TOP: 211.03,106.14 211.03,108.74 211.94,109.65 211.94,112.11 212.53,112.7 214.89,112.7 215.17,112.42 215.17,109.37 215.32,109.22 219.15,109.22 219.33,109.4 223.19,109.4 223.29,109.29 223.29,101.17 222.62,100.49 216.68,100.49 ; 1 cut-out
+5VS on BOTTOM: 16.44,108.1 17.55,108.1 17.96,108.51 17.96,111.02 17.99,111.05 17.99,111.55 17.81,111.73 16.46,111.73 16.34,111.61 16.34,108.2
+5VS on BOTTOM: 24.29,94.05 25.45,94.05 25.53,93.98 25.53,92.76 25.45,92.68 24.29,92.68 24.18,92.78 24.18,93.95
+5VS on IN1: 220.35,120.01 220.35,117.6 219.29,116.55 219.29,21.48 207.69,9.87 114.72,9.87 114.2,10.39 114.2,15.34 112.93,16.61 92.32,16.61 89.63,13.92 58.7,13.92 55.15,10.36 36.22,10.36 36.1,10.49 36.1,11.63 36.22,11.76 44.4,11.76 44.83,12.2 53.55,12.2 57.31,15.95 66.45,15.95 66.96,16.46 66.96,19.25 60.61,25.6 50.32,25.6 25.68,50.24 25.68,67.64 33.05,75 33.05,91.64 32.16,92.53 23.65,92.53 18.57,97.61 18.57,107.92 16.39,110.11 16.39,111.76 16.69,112.06 23.93,112.06 32.06,103.93 44.3,103.93 44.56,103.68 44.56,93.62 40.67,89.74 40.67,48.89 57.59,31.98 95.81,31.98 101.37,26.41 110.57,26.41 110.61,26.37 114.4,26.37 122.16,18.62 203.09,18.62 210.47,25.99 210.47,118.54 212.35,120.42 219.94,120.42
+5VS on IN2: 36.3,10.3 57.47,10.3 62.42,15.25 62.42,15.79 62.27,15.94 58.84,15.94 55.16,12.26 44.95,12.26 44.51,11.82 36.28,11.82 36.08,11.63 36.08,10.52
+5VS_ODD on TOP: 217.66,114.96 221.85,114.96 221.95,114.86 221.95,113.03 221.72,112.8 217.25,112.8 217.05,113 217.05,114.35
+5VS_ODD on BOTTOM: 219.51,114.37 225.07,114.37 225.4,114.7 226.5,114.7 227.66,113.54 227.66,112.82 227.41,112.57 226.47,112.57 226.34,112.7 217.33,112.7 217.2,112.82 217.2,114.86 217.35,115.01 218.88,115.01
+5VS_ODD_R1 on TOP (solid shape): 221.89,112.46 221.89,111.96 221.67,111.75 221.16,111.75 220.78,111.36 220.78,109.83 220.63,109.68 219.13,109.68 219.08,109.62 219.08,109.6 218.82,109.34 217.58,109.34 217.5,109.42 217.5,109.88 217.48,109.9 216.16,109.9 216.13,109.88 216.13,109.4 216.08,109.34 215.65,109.34 215.6,109.4 215.6,110.97 216.01,111.38 218.62,111.38 218.98,111.73 218.98,112.55 219.08,112.65 221.69,112.65
+5VS_ODD_R2 on TOP (solid shape): 218.75,112.49 218.75,111.76 218.65,111.66 215.9,111.66 215.7,111.86 215.7,112.44 215.85,112.6 218.65,112.6
+5VS_OUT on BOTTOM (solid shape): 109.78,26.69 109.78,26.08 109.83,26.03 110.32,26.03 110.34,26.01 110.34,25.63 110.32,25.6 109.81,25.6 109.78,25.58 109.78,24.84 110.32,24.84 110.34,24.81 110.34,24.43 110.32,24.41 109.81,24.41 109.78,24.38 109.78,23.75 109.71,23.67 107.42,23.67 107.34,23.75 107.34,25.45 107.01,25.78 107.01,26.59 107.09,26.67 107.8,26.67 107.9,26.77 109.71,26.77
+5VS_TOUCH on TOP: 23.63,97.43 25.23,97.43 25.56,97.1 25.56,95.6 24.86,94.9 24.17,94.9 23.45,95.63 23.45,97.25
+5VS_TOUCH on BOTTOM: 20.58,92.66 21.54,92.66 23.22,94.33 27.03,94.33 27.13,94.44 27.13,96.39 26.93,96.59 23.75,96.59 20.35,93.19 20.35,92.89
+AVCC33 on BOTTOM (solid shape): 206.05,154.58 206.05,152.63 205.82,152.4 203.94,152.4 203.64,152.7 203.64,155.19 203.89,155.45 205.18,155.45
+AVCC33 on IN1: 204.32,160.42 205.97,160.42 206.1,160.3 206.1,152.42 205.85,152.17 203.64,152.17 203.33,152.47 203.33,159.43
+DVCC33 on BOTTOM (solid shape): 212.58,163.52 212.58,160.07 212.4,159.89 211.53,159.89 211.26,160.17 211.26,163.6 211.36,163.7 212.4,163.7
+DVCC33 on BOTTOM (solid shape): 203.75,168.49 203.75,168.34 203.74,168.32 203.74,168.1 204.12,167.71 204.12,166.57 204.04,166.49 201.65,166.49 201.1,165.94 201.1,164.11 201.55,163.65 203.44,163.65 203.53,163.56 203.53,163.41 203.45,163.32 200.25,163.32 199.74,163.84 198.92,163.84 198.71,164.05 198.71,167.02 198.23,167.51 198.23,168.81 198.35,168.93 203.31,168.93
+DVCC33 on TOP: 197.74,168.15 202.14,168.15 202.39,167.89 202.39,166.37 201.98,165.96 200.61,165.96 200.38,165.73 200.38,160.04 202.52,157.91 206.23,157.91 210.29,161.97 212.02,161.97 212.58,161.41 212.58,156.69 213.16,156.11 213.16,155.19 212.86,154.89 203.81,154.89 197.13,161.57 197.13,167.54
+V18R on TOP: 180.17,54.53 182.38,54.53 182.43,54.48 182.43,54.35 182.38,54.3 180.6,54.3 179.53,53.24 179.53,52.3 179.48,52.25 178.67,52.25 178.59,52.32 178.59,53.67 178.64,53.72 179.35,53.72
+VCC_3IN1 on TOP: 189.41,32.05 189.61,31.85 189.61,30.58 189.34,30.3 182.05,30.3 181.84,30.5 181.84,31.6 182.3,32.05
+VCC_3IN1 on TOP: 177.75,21.87 177.88,21.87 177.96,21.79 177.96,21 178.29,20.67 179.25,20.67 179.38,20.55 179.38,20.01 179.33,19.96 178.51,19.96 177.68,20.8 177.68,21.79
+VCC_3IN1 on IN1: 188.19,23.82 188.19,28.83 186.29,30.73 184.13,30.73 183.87,30.99 183.87,31.9 184.05,32.08 186.72,32.08 189.51,29.28 189.51,22.81 185.96,19.25 178.41,19.25 178.06,19.61 178.06,20.5 178.26,20.7 185.07,20.7
B+_3/5V on BOTTOM (solid shape): 131.19,29.41 131.19,25.96 131.03,25.79 127.3,25.79 127.03,26.06 127.03,29.51 127.16,29.64 130.97,29.64
B+_3/5V on TOP: 133.86,29.58 133.86,27 133.76,26.9 132.39,26.9 131.3,25.8 127.28,25.8 127.05,26.03 127.05,26.36 126.57,26.85 124.06,26.85 123.98,26.92 123.98,29.64 123.98,29.64 123.98,29.88 124.02,29.92 124.26,29.92 124.26,29.92 133.53,29.92
GND on TOP (solid shape): 23.61,23.48 23.61,22.16 23.48,22.03 22.35,22.03 22.22,22.16 22.22,23.44 22.36,23.58 23.5,23.58
GND on TOP (solid shape): 41.25,101.17 41.25,98.09 40.52,97.36 37.67,97.36 37.27,97.76 37.27,100.84 38.05,101.62 40.8,101.62
GND on TOP (solid shape): 49.89,100.86 49.89,97.28 49.71,97.1 46.84,97.1 46.43,97.51 46.43,100.61 47.1,101.27 49.48,101.27
GND on TOP (solid shape): 52.15,103.1 52.15,101.32 51.95,101.12 50.52,101.12 50.4,101.24 50.4,102.84 50.83,103.27 51.97,103.27
GND on TOP (solid shape): 54.21,109.24 54.21,107.39 53.95,107.14 52.71,107.14 52.38,107.47 52.38,109.09 52.68,109.4 54.05,109.4
GND on TOP (solid shape): 57.92,105.08 57.92,98.4 57.76,98.25 57.1,98.25 56.98,98.37 56.98,105.15 57.1,105.28 57.71,105.28
GND on TOP (solid shape): 134.24,138.55 134.24,134.06 134.04,133.86 132.08,133.86 131.93,134.01 131.93,138.48 132.13,138.68 134.12,138.68
GND on TOP (solid shape): 26.52,25.35 26.52,24.13 26.37,23.98 25.51,23.98 25.25,24.24 25.25,25.35 25.44,25.54 26.33,25.54
GND on TOP (solid shape): 35.84,71.91 35.84,70.61 35.67,70.43 32.36,70.43 31.98,70.05 31.22,70.05 31.14,70.13 31.14,71.55 31.88,72.29 35.46,72.29
GND on TOP (solid shape): 207.5,165.03 207.5,161.41 207.29,161.21 203.91,161.21 203.05,162.08 203.05,165.22 203.31,165.48 207.05,165.48
GND on TOP (solid shape): 125.81,146.12 125.81,143.38 125.66,143.23 121.47,143.23 120.96,143.74 120.96,144.78 121.82,145.64 121.82,147.04 121.95,147.17 124.77,147.17
GND on TOP (solid shape): 140.14,139.77 140.14,139.39 141.1,138.43 141.1,136.17 140.87,135.94 138.1,135.94 137.77,136.27 137.77,139.19 138.48,139.9 140.01,139.9
GND on TOP (solid shape): 225.58,178.04 225.58,176.55 225.5,176.48 224.41,176.48 224.31,176.58 224.31,177.98 224.44,178.1 225.52,178.1
GND on TOP (solid shape): 170.63,176.67 170.63,175.51 170.51,175.4 170.51,174.18 170.44,174.1 170.27,174.1 170.21,174.17 170.21,175.52 170.12,175.61 170.12,176.7 170.2,176.78 170.52,176.78
GND on TOP (solid shape): 122.96,118.46 122.96,117.4 121.77,116.2 121.36,116.2 120.86,115.69 118.82,115.69 118.39,115.26 118.09,115.26 117.35,116 116.21,116 115.93,116.28 115.93,116.81 116.11,116.99 116.79,116.99 117.07,116.71 117.71,116.71 118.14,116.28 118.85,116.28 120.91,118.34 122.23,118.34 122.53,118.64 122.79,118.64
GND on TOP (solid shape): 150.37,128.5 150.37,125.12 149.94,124.69 149.94,123.7 150.17,123.47 150.83,123.47 151.11,123.19 153.14,123.19 153.29,123.04 153.29,122.25 153.04,121.99 151.21,121.99 151.06,121.84 151.06,121.13 150.96,121.03 147.96,121.03 147.6,121.38 147.6,128.55 147.76,128.7 150.17,128.7
GND on TOP (solid shape): 7.61,98.28 11.02,98.28 11.57,97.73 11.57,93.56 13.45,91.68 13.45,91.15 13.33,91.18 13.2,91.19 0.85,91.19 0.85,95.65 6.85,95.65 7.59,96.27 7.1,97.11 7.1,98.3 7.61,98.3
GND on TOP (solid shape): 13.43,73.92 12.83,73.31 12.83,70.02 12.06,69.26 9.1,69.26 8.23,68.39 8.23,61.98 9.19,61.02 11.58,61.02 12.23,60.37 12.23,51.3 11.62,50.69 8.34,50.69 8.23,50.58 8.23,42.15 8.97,41.41 11.73,41.41 12.28,40.86 12.28,33.67 11.74,33.13 8.66,33.13 8.23,32.7 8.23,24.47 9.19,23.52 11.55,23.52 11.86,23.21 11.86,21.03 11.09,20.26 0.25,20.26 0.25,21.35 7.47,21.35 8.21,21.97 7.72,22.81 7.72,33.99 8.21,34.83 7.47,35.45 1.05,35.45 1.05,38.95 7.47,38.95 8.21,39.57 7.72,40.41 7.72,51.59 8.21,52.43 7.47,53.05 0.25,53.05 0.25,56.55 7.47,56.55 8.21,57.17 7.72,58.01 7.72,69.19 8.21,70.03 7.47,70.65 1.05,70.65 1.05,74.41 13.2,74.41 13.32,74.42 13.43,74.44
GND on TOP (solid shape): 89.67,153.52 90.19,152.28 91.43,151.77 92.71,151.77 92.71,151.26 91.43,151.26 89.83,151.92 89.17,153.52 89.17,154.87 89.31,155.01 89.31,156.1 88.73,156.68 86.15,156.68 85.75,156.28 85.07,150.21 83.43,144.33 83.42,144.19 83.49,144.07 84.03,143.14 83.93,142.07 82.06,138.28 79.79,134.7 78.93,134.06 77.86,134.04 77.72,134.03 77.6,133.96 64.44,123.41 48,119.64 38.74,119.64 38.15,118.56 37,118.14 31.48,118.14 29.36,116.02 25.19,116.02 23.46,117.75 12.2,117.75 11.4,116.95 11.4,112 8.4,109 7.1,109 7.1,110.19 7.59,111.03 6.85,111.65 0.25,111.65 0.25,120.15 23.65,120.15 24.22,120.29 24.67,120.68 27.48,121.79 29.61,119.65 30.05,118.93 30.84,118.65 37,118.65 37.89,119.01 38.25,119.9 38.25,120.15 48.51,120.15 48.51,120.15 64.45,123.97 77.2,134.27 77.56,134.52 78,134.52 78.76,134.54 79.38,135 81.62,138.52 83.46,142.27 83.53,143.03 83.15,143.69 82.93,144.07 82.95,144.51 84.67,150.85 85.25,157.4 85.25,159.55 89.67,159.55
GND on TOP (solid shape): outline of 887 points within 17.08,0.25 230.15,190.85
GND on BOTTOM (solid shape): 24.32,56.5 24.32,53.73 23.88,53.29 21.11,53.29 20.48,53.92 20.48,56.64 20.65,56.82 24.01,56.82
GND on BOTTOM (solid shape): 59.44,96.87 59.44,94.61 59.24,94.41 57.89,94.41 57.71,94.59 57.71,96.75 57.97,97 59.31,97
GND on BOTTOM (solid shape): 113.39,32.66 113.39,31.27 113.26,31.14 110.85,31.14 110.7,31.29 110.7,32.59 110.9,32.79 113.26,32.79
GND on BOTTOM (solid shape): 113.85,20.72 113.85,19.17 113.47,18.79 110.39,18.79 110.06,19.12 110.06,20.83 110.14,20.9 113.67,20.9
GND on BOTTOM (solid shape): 126.7,13.16 126.7,11.94 126.56,11.8 125.09,11.8 125.02,11.86 125.02,13.13 125.15,13.26 126.6,13.26
GND on BOTTOM (solid shape): 141.15,138.89 141.15,136.22 140.82,135.89 136.96,135.89 136.35,136.5 136.35,138.89 136.76,139.29 140.74,139.29
GND on BOTTOM (solid shape): 152.38,25.12 152.38,21.69 151.61,20.92 148.75,20.92 148.43,21.24 148.43,25.05 148.94,25.56 151.94,25.56
GND on BOTTOM (solid shape): 154.4,27.56 154.4,26.35 154.27,26.22 153.06,26.22 152.94,26.35 152.94,27.56 153.13,27.75 154.21,27.75
GND on BOTTOM (solid shape): 173.24,147.65 173.24,146.19 172.99,145.93 172.1,145.93 171.91,146.12 171.91,147.65 172.1,147.84 173.05,147.84
GND on BOTTOM (solid shape): 203.46,171.02 203.46,169.34 203.33,169.21 199.72,169.21 199.57,169.37 199.57,170.46 200.23,171.12 203.36,171.12
GND on BOTTOM (solid shape): 214.76,163.35 214.76,159.89 214.68,159.81 213.13,159.81 212.78,160.17 212.78,163.32 212.98,163.52 214.58,163.52
GND on BOTTOM (solid shape): 145.47,146 145.47,142.14 145.22,141.88 143.64,141.88 142.7,142.82 142.7,145.74 143.08,146.12 145.34,146.12
GND on BOTTOM (solid shape): 125.84,148.54 125.84,143.41 125.63,143.2 121.49,143.2 120.98,143.71 120.98,148.36 121.34,148.71 125.66,148.71
GND on BOTTOM (solid shape): 135.56,20.65 135.56,15.72 135.21,15.36 133.77,15.36 132.7,16.44 131.62,16.44 131.45,16.6 131.45,20.63 131.65,20.83 135.39,20.83
GND on BOTTOM (solid shape): 139.42,184.02 139.42,180.57 139.3,180.44 135.51,180.44 135.33,180.62 135.33,183.87 135.61,184.15 139.3,184.15
GND on BOTTOM (solid shape): 168.48,154.77 168.48,153.44 168.43,153.39 165.87,153.39 165.74,153.52 165.74,154.91 166.09,155.26 167.99,155.26
GND on BOTTOM (solid shape): 198.41,166.95 198.41,163.92 198.33,163.84 197.07,163.84 196.82,164.09 196.82,165.92 197.26,166.37 197.26,166.95 197.39,167.08 198.29,167.08
GND on BOTTOM (solid shape): 214.76,172.08 214.76,169.21 214.71,169.16 213.62,169.16 213.29,169.49 211.66,169.49 211.36,169.8 211.36,171.96 211.64,172.24 214.61,172.24
GND on BOTTOM (solid shape): 105.39,33.04 105.39,31.06 105.29,30.96 102.14,30.96 101.97,31.13 101.97,31.63 101.98,31.65 101.98,32.23 101.81,32.41 101.81,32.97 102.06,33.22 105.21,33.22
GND on BOTTOM (solid shape): 133.48,138.45 133.48,133.98 133.18,133.68 131.68,133.68 131.55,133.81 131.55,136.93 131.78,137.16 132.59,137.16 132.92,137.49 132.92,138.5 133.05,138.63 133.3,138.63
GND on BOTTOM (solid shape): 150.55,128.78 150.55,123.77 150.4,123.62 148.8,123.62 148.62,123.8 148.62,124.28 148.31,124.58 148.31,128.67 148.54,128.9 150.42,128.9
GND on BOTTOM (solid shape): 157,25.02 157,23.94 157.13,23.81 157.13,22.92 157,22.79 156.75,22.79 156.62,22.92 156.62,23.81 156.81,24 156.81,25.02 156.87,25.08 156.94,25.08
GND on BOTTOM (solid shape): 149.69,169.01 151.57,169.01 151.77,168.81 151.77,165.94 151.41,165.58 149.94,165.58 149.43,166.09 143.62,166.09 143.49,166.22 143.49,169.34 143.69,169.54 149.15,169.54
GND on BOTTOM (solid shape): 173.24,173.68 173.24,170.25 173.18,170.19 169.82,170.19 169.62,170 169.62,168.79 168.99,168.79 168.99,172.86 168.67,173.18 167.66,173.18 167.53,173.3 167.53,174.13 172.8,174.13
GND on BOTTOM (solid shape): 131.05,24.52 131.64,24.52 131.73,24.43 131.73,22.73 131.47,22.48 126.37,22.48 126.19,22.65 126.19,24.33 126.29,24.43 126.81,24.43 127.09,24.71 127.17,24.71 127.25,24.79 130.78,24.79
GND on BOTTOM (solid shape): 157.83,30.48 157.83,29.21 157.64,29.02 157.19,29.02 156.62,28.45 156.62,27.18 156.56,27.11 156.43,27.11 156.37,27.18 156.37,29.27 156.3,29.33 156.3,30.41 156.43,30.54 157.76,30.54
GND on BOTTOM (solid shape): 160.18,21.52 160.18,20.32 159.92,20.06 157.89,20.06 157.83,20.13 157.83,20.57 157.95,20.7 157.95,21.27 158.02,21.33 158.02,21.65 160.05,21.65
GND on BOTTOM (solid shape): 198.06,158.64 198.06,156.91 197.65,156.5 196.46,156.5 195.6,157.36 195.6,158.13 195.64,158.17 197.07,158.17 197.33,158.42 197.33,158.59 197.41,158.68 198.02,158.68
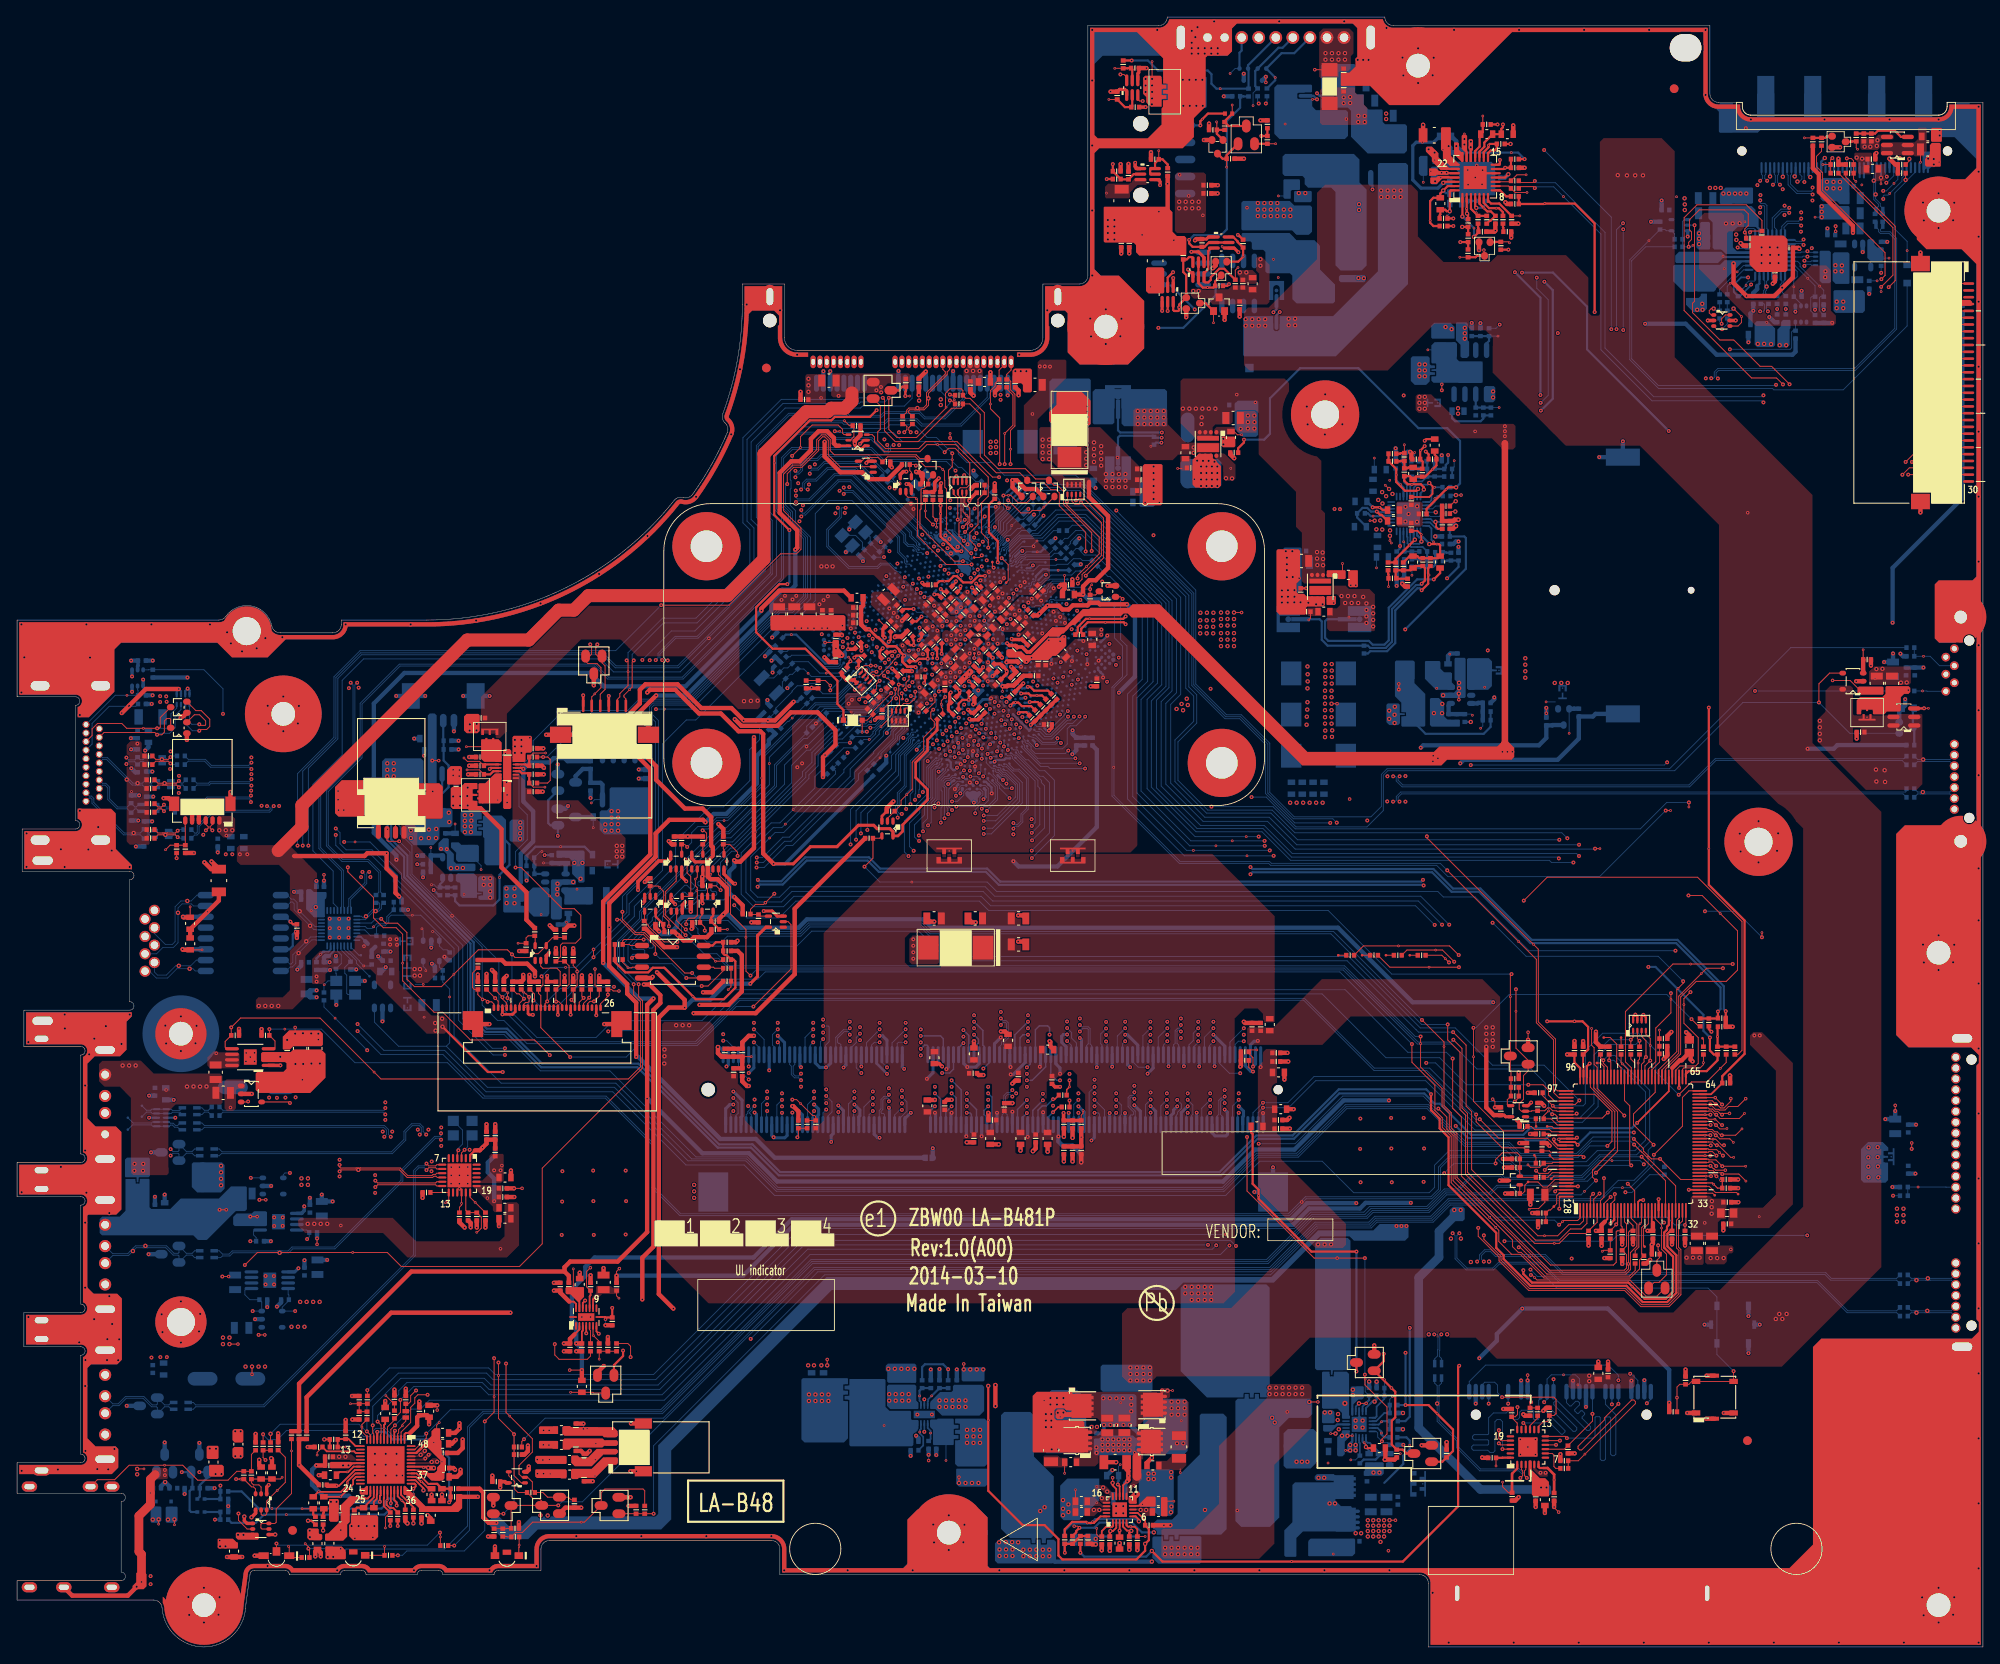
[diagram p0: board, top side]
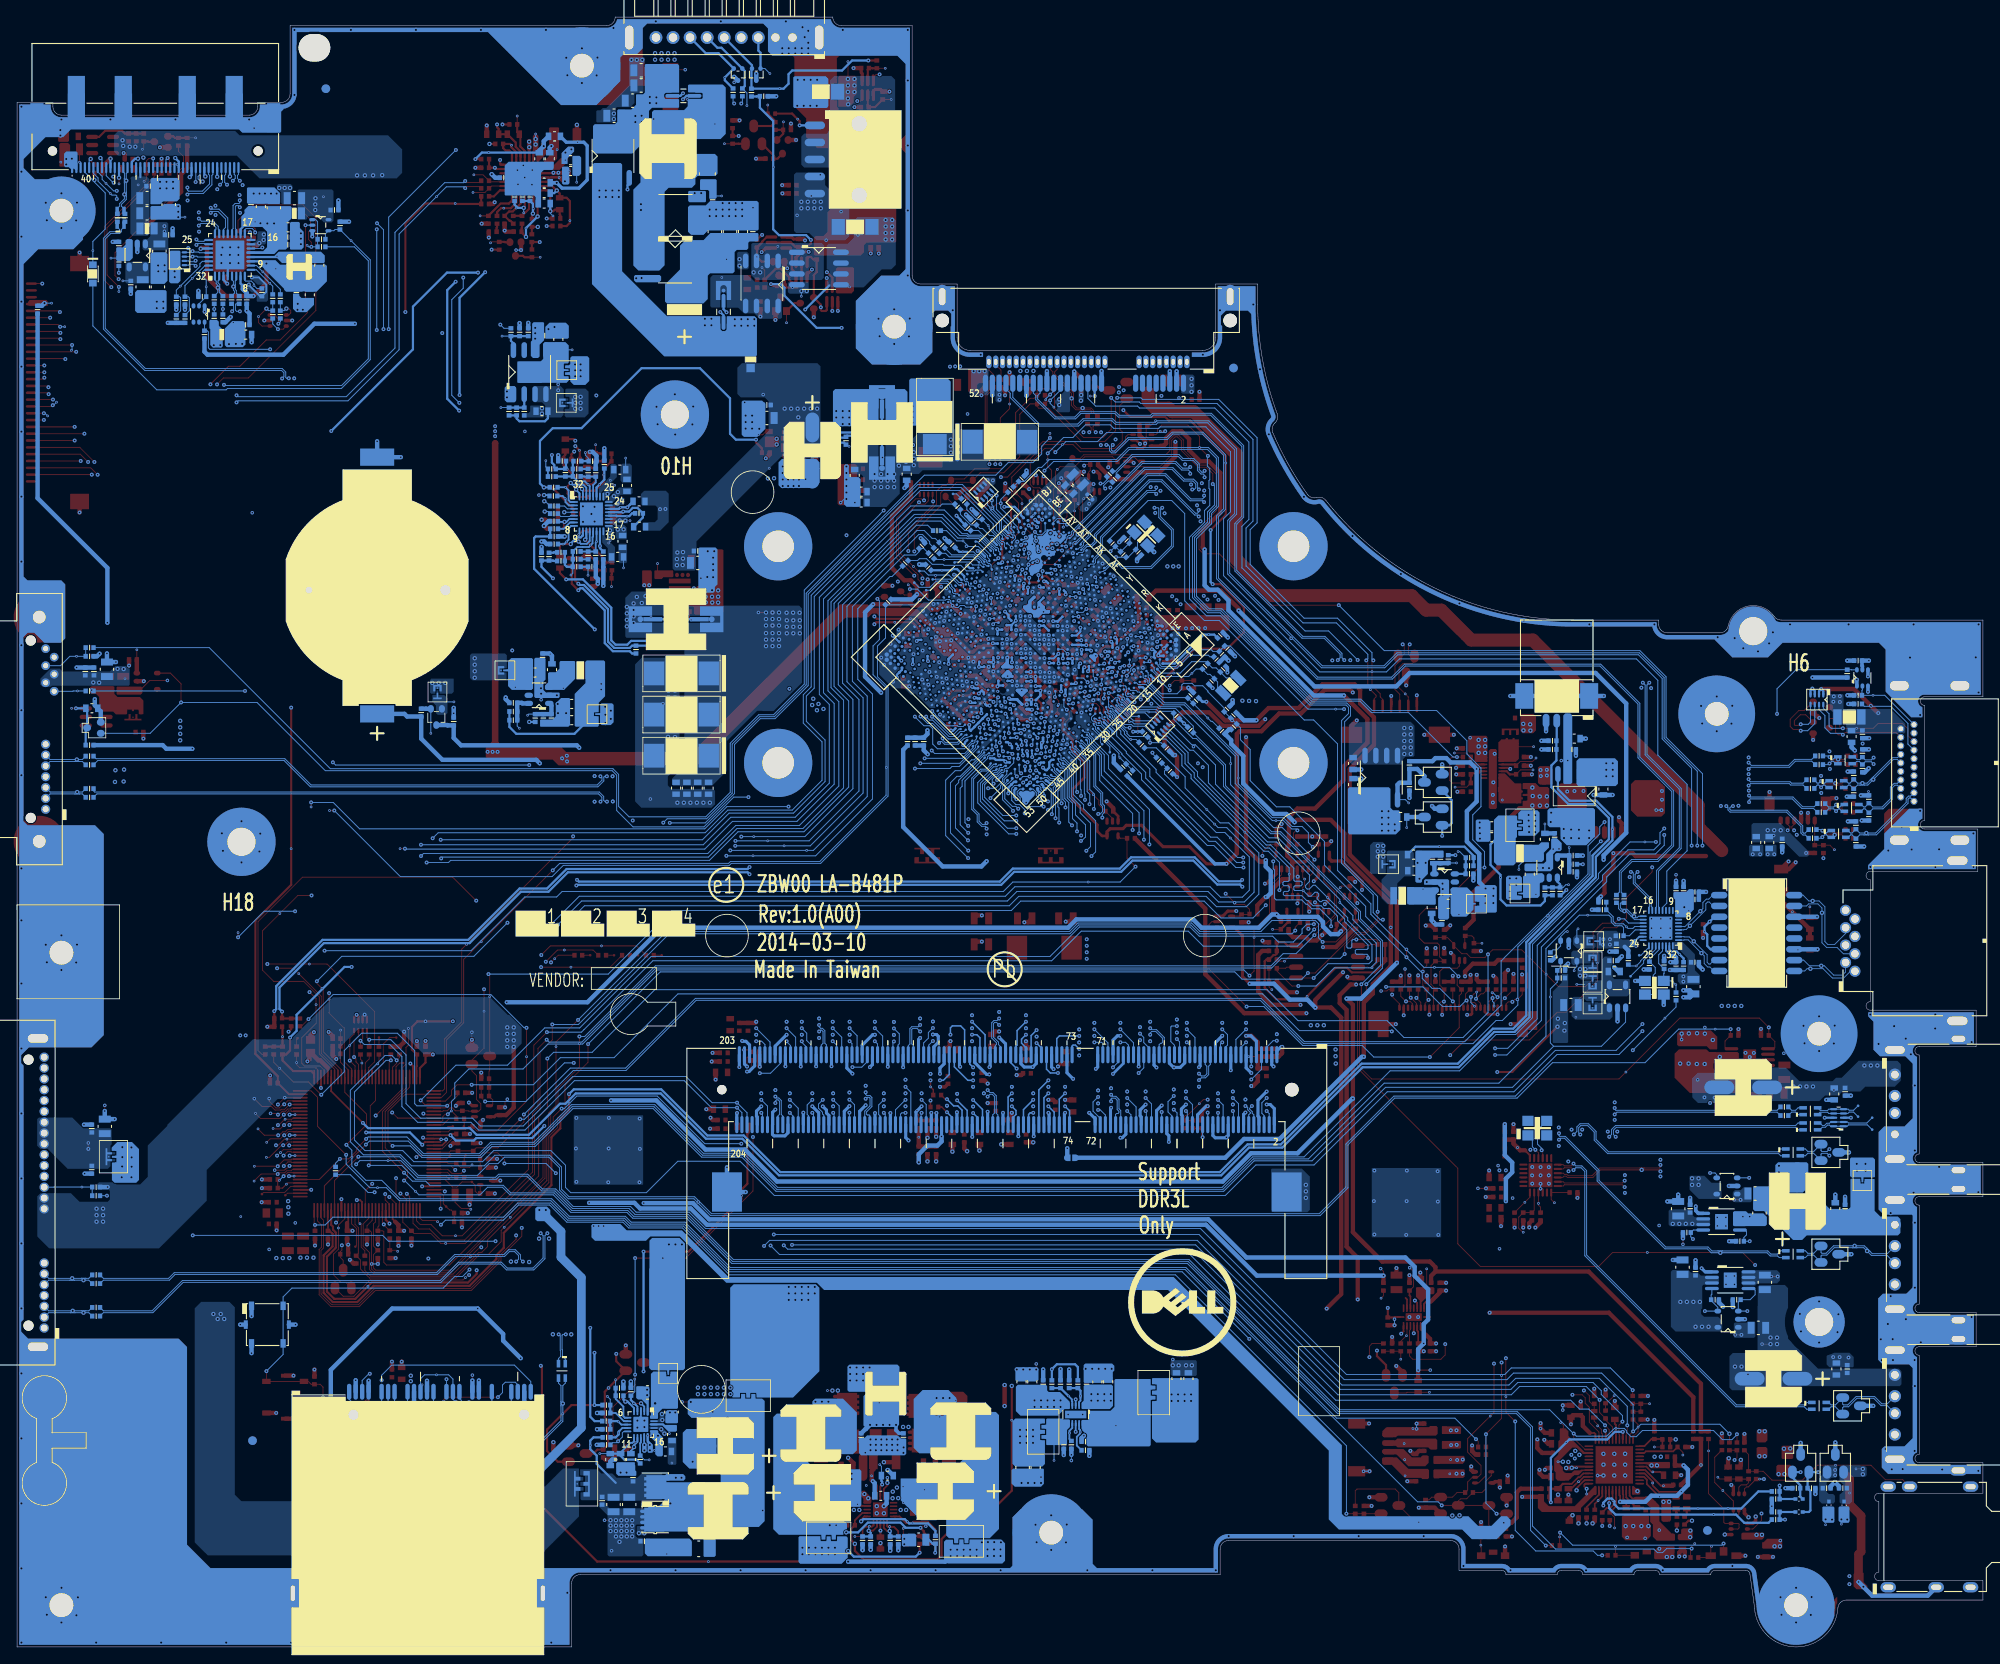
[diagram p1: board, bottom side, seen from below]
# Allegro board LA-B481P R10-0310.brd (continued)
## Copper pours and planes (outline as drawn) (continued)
GND on BOTTOM (solid shape): 157.38,28.06 157.38,27.11 157.51,26.99 158.14,26.99 158.14,25.27 156.43,25.27 156.43,26.99 157.13,26.99 157.19,27.05 157.19,28.06 157.25,28.13 157.32,28.13
GND on BOTTOM (solid shape): 50.26,98.33 50.79,98.33 51.03,98.09 51.03,96.37 50.78,96.11 49.58,96.11 49.51,96.04 49.51,95.04 49.5,95.03 49.5,94.73 48.77,94 46.49,94 45.47,95.02 45.47,98.17 45.67,98.37 50.22,98.37
GND on BOTTOM (solid shape): 167.26,110.63 167.26,109.1 167.64,108.72 169.04,108.72 169.1,108.66 169.1,107.96 169.04,107.9 165.79,107.9 165.59,108.1 165.59,111.15 165.7,111.26 166.63,111.26
GND on BOTTOM (solid shape): 50.6,94.69 50.6,93.57 51.18,92.99 51.18,92.12 51.46,91.84 53.6,91.84 53.72,91.72 53.72,91.08 53.6,90.96 50.68,90.96 50.37,91.26 50.37,92.96 50.03,93.3 49.56,93.3 49.38,93.48 49.38,94.26 49.94,94.82 50.47,94.82
GND on BOTTOM (solid shape): 169.78,115.85 169.78,111.4 169.64,111.26 166.95,111.26 166.82,111.39 166.82,111.83 166.88,111.9 168.41,111.9 168.72,112.22 168.72,113.17 168.47,113.42 168.47,115.86 168.58,115.97 169.65,115.97
GND on BOTTOM (solid shape): 66.51,93.24 66.51,89.75 66.37,89.61 65.87,89.61 65.74,89.74 65.74,89.95 65.05,90.64 65.05,92.16 64.67,92.54 63.27,92.54 63.21,92.61 63.21,93.3 63.27,93.37 66.39,93.37
GND on BOTTOM (solid shape): 65.5,89.88 65.5,89.43 65.43,89.37 63.91,89.37 63.59,89.05 63.59,88.1 63.85,87.84 63.85,85.48 63.66,85.29 62.74,85.29 62.56,85.47 62.56,89.86 62.7,90 65.37,90
GND on BOTTOM (solid shape): 126.84,17.65 126.77,17.45 126.83,17.26 126.84,17.24 126.84,17.21 126.04,16.41 126.03,16.4 125.93,16.33 125.86,16.23 125.86,16.23 124.49,14.86 122.66,14.86 122.25,15.26 122.25,18.91 123.09,19.75 126.84,19.75
GND on BOTTOM (solid shape): 7.61,98.28 8.65,98.28 11.57,95.37 11.57,93.56 13.45,91.68 13.45,91.15 13.33,91.18 13.2,91.19 0.85,91.19 0.85,95.65 6.85,95.65 7.59,96.27 7.1,97.11 7.1,98.3 7.61,98.3
GND on BOTTOM (solid shape): 112.27,100.39 112.48,100.28 112.7,100.35 112.77,100.37 112.83,100.34 113,100.17 113,99.96 112.88,99.84 112.88,99.81 112.68,99.61 112.68,99.59 112.61,99.51 112.61,99.08 112.29,98.77 112.1,98.77 111.75,99.12 111.75,99.23 111.17,99.8 111.17,99.88 111.16,99.93 111.14,99.99 111.14,100.16 111.32,100.34 111.38,100.37 111.45,100.35 111.67,100.28 111.88,100.39
GND on BOTTOM (solid shape): 13.43,73.92 12.83,73.31 12.83,70.02 12.06,69.26 9.1,69.26 8.23,68.39 8.23,61.98 9.19,61.02 11.58,61.02 12.23,60.37 12.23,51.3 11.62,50.69 8.34,50.69 8.23,50.58 8.23,42.15 8.97,41.41 11.73,41.41 12.28,40.86 12.28,33.67 11.74,33.13 8.66,33.13 8.23,32.7 8.23,24.47 9.19,23.52 11.55,23.52 11.86,23.21 11.86,21.03 11.11,20.28 0.25,20.28 0.25,21.35 7.47,21.35 8.21,21.96 7.74,22.8 7.72,22.82 7.72,33.99 8.21,34.83 7.47,35.45 1.05,35.45 1.05,38.95 7.47,38.95 8.21,39.57 7.72,40.41 7.72,51.59 8.21,52.43 7.47,53.05 0.25,53.05 0.25,56.55 7.47,56.55 8.21,57.17 7.72,58.01 7.72,69.19 8.21,70.03 7.47,70.65 1.05,70.65 1.05,74.41 13.2,74.41 13.32,74.41 13.43,74.44
GND on BOTTOM (solid shape): 89.67,153.52 90.19,152.28 91.43,151.77 92.71,151.77 92.71,151.26 91.43,151.26 89.83,151.92 89.17,153.52 89.17,154.87 89.31,155.01 89.31,156.1 88.73,156.68 86.15,156.68 85.75,156.28 85.07,150.21 83.43,144.33 83.42,144.19 83.49,144.07 84.03,143.14 83.93,142.07 82.06,138.28 79.79,134.7 78.93,134.06 77.86,134.04 77.72,134.03 77.6,133.96 64.44,123.41 48,119.64 38.74,119.64 38.15,118.56 37,118.14 31.48,118.14 29.36,116.02 25.19,116.02 23.46,117.75 12.2,117.75 11.4,116.95 11.4,112 8.4,109 7.1,109 7.1,110.19 7.59,111.03 6.85,111.65 0.25,111.65 0.25,120.15 23.65,120.15 24.22,120.29 24.67,120.68 27.48,121.79 29.61,119.65 30.05,118.93 30.84,118.65 37,118.65 37.89,119.01 38.25,119.9 38.25,120.15 48,120.15 64.22,123.86 77.2,134.27 77.56,134.52 78,134.52 78.76,134.54 79.38,135 81.62,138.52 83.46,142.27 83.53,143.03 83.15,143.69 82.93,144.07 82.95,144.51 84.67,150.85 85.25,157.4 85.25,159.55 89.67,159.55
GND on BOTTOM (solid shape): outline of 246 points within 17.41,0.25 230.15,190.85
GND on BOTTOM (solid shape): outline of 660 points within 107.35,125.59 112.58,131.06
GND on IN1 (solid shape): 89.67,153.52 90.19,152.28 91.43,151.77 92.71,151.77 92.71,151.26 91.43,151.26 89.83,151.92 89.17,153.52 89.17,154.86 89.31,155.01 89.31,156.1 88.73,156.68 86.15,156.68 85.75,156.28 85.07,150.21 83.43,144.33 83.42,144.19 83.49,144.07 84.03,143.14 83.93,142.07 82.06,138.28 79.79,134.7 78.93,134.06 77.86,134.04 77.72,134.03 77.6,133.96 64.44,123.41 48,119.64 38.74,119.64 38.15,118.56 37,118.14 31.48,118.14 29.36,116.02 25.19,116.02 23.46,117.75 12.2,117.75 11.4,116.95 11.4,112 8.4,109 7.1,109 7.1,110.19 7.59,111.03 6.85,111.65 0.25,111.65 0.25,120.15 23.65,120.15 24.22,120.29 24.67,120.68 27.48,121.79 29.61,119.65 30.05,118.93 30.84,118.65 37,118.65 37.89,119.01 38.25,119.9 38.25,120.15 48,120.15 64.22,123.86 77.2,134.27 77.56,134.52 78,134.52 78.76,134.54 79.38,135 81.62,138.52 83.46,142.27 83.53,143.03 83.15,143.69 82.93,144.07 82.95,144.51 84.67,150.85 85.25,157.4 85.25,159.55 89.67,159.55
GND on IN1 (solid shape): outline of 860 points within 17.08,0.25 230.15,190.85
GND on IN2 (solid shape): 7.61,98.28 8.64,98.28 11.57,95.36 11.57,93.56 13.45,91.68 13.45,91.15 13.33,91.18 13.2,91.19 0.85,91.19 0.85,95.65 6.85,95.65 7.59,96.27 7.1,97.11 7.1,98.3 7.61,98.3
GND on IN2 (solid shape): 13.43,73.92 12.83,73.31 12.83,70.02 12.06,69.26 9.1,69.26 8.23,68.39 8.23,61.98 9.19,61.02 11.58,61.02 12.23,60.37 12.23,51.3 11.62,50.69 8.34,50.69 8.23,50.58 8.23,42.15 8.97,41.41 11.73,41.41 12.28,40.86 12.28,33.67 11.74,33.13 8.66,33.13 8.23,32.7 8.23,24.47 9.19,23.52 11.55,23.52 11.86,23.21 11.86,21.05 11.09,20.28 0.25,20.28 0.25,21.35 7.47,21.35 8.21,21.97 7.72,22.81 7.72,33.99 8.21,34.83 7.47,35.45 1.05,35.45 1.05,38.95 7.47,38.95 8.21,39.57 7.72,40.41 7.72,51.59 8.21,52.43 7.47,53.05 0.25,53.05 0.25,56.55 7.47,56.55 8.21,57.17 7.72,58.01 7.72,69.19 8.21,70.03 7.47,70.65 1.05,70.65 1.05,74.41 13.2,74.41 13.32,74.42 13.43,74.44
GND on IN2 (solid shape): 89.67,153.52 90.19,152.28 91.43,151.77 92.71,151.77 92.71,151.26 91.43,151.26 89.83,151.92 89.17,153.52 89.17,154.87 89.31,155.01 89.31,156.1 88.73,156.68 86.15,156.68 85.75,156.28 85.07,150.21 83.43,144.33 83.42,144.19 83.49,144.07 84.03,143.14 83.93,142.07 82.06,138.28 79.79,134.7 78.93,134.06 77.86,134.04 77.72,134.03 77.6,133.96 64.44,123.41 48,119.64 38.74,119.64 38.15,118.56 37,118.14 31.48,118.14 29.36,116.02 25.19,116.02 23.46,117.75 12.2,117.75 11.4,116.95 11.4,112 8.4,109 7.1,109 7.1,110.19 7.59,111.03 6.85,111.65 0.25,111.65 0.25,120.15 23.65,120.15 24.22,120.29 24.67,120.68 27.48,121.79 29.61,119.65 30.05,118.93 30.84,118.65 37,118.65 37.89,119.01 38.25,119.9 38.25,120.15 48,120.15 64.22,123.86 77.2,134.27 77.56,134.52 78,134.52 78.76,134.54 79.38,135 81.62,138.52 83.46,142.27 83.53,143.03 83.15,143.69 82.93,144.07 82.95,144.51 84.67,150.85 85.25,157.4 85.25,159.55 89.67,159.55
GND on IN2 (solid shape): outline of 236 points within 17.08,0.25 230.15,190.85
GND on TOP: 115.38,121.02 117.51,123.15 119.17,123.15 120.81,124.79 121.24,124.79 121.85,124.18 121.85,123.8 119.95,121.9 118.93,121.9 118.63,122.21 118.37,122.21 118.17,122.41 117.79,122.41 117.53,122.15 117.53,121.82 118.94,120.42 118.94,120.38 118.98,120.34 119.94,120.34 121.31,121.71 122,121.71 123.07,120.65 123.07,119.96 122.79,119.68 121.34,119.68 119.36,117.7 118.98,117.7 117.99,118.69 117.78,118.69 117.5,118.41 117.2,118.41 117.11,118.5 117.11,118.81 117.22,118.92 117.5,118.92 117.53,118.95 117.73,118.95 118.14,119.35 118.14,119.5 116.92,120.72 116.36,120.72 115.57,119.94 115.35,119.94 114.79,120.5 114.79,120.6 115.21,121.02
GND on TOP: 111.74,119.25 111.84,119.25 112.17,118.92 112.88,118.92 113.06,118.74 113.34,118.74 113.68,119.09 113.8,119.09 114.2,118.68 114.2,118.64 113.97,118.41 113.97,118.01 114.74,117.24 114.74,117.12 114.41,116.79 114.2,116.79 114,116.99 113.77,116.99 113.44,116.66 113.21,116.66 112.83,117.04 113.2,117.41 113.38,117.41 113.44,117.47 113.44,118.08 113.08,118.44 111.99,118.44 111.69,118.13 111.61,118.13 111.15,118.59 111.15,118.67
GND on TOP: 145.29,142.47 145.19,142.36 143.11,142.36 142.95,142.52 142.95,143 142.94,143.01 142.94,144.82 143.03,144.9 145.04,144.9 145.29,144.65
GND on TOP: 164.52,134.29 161.82,134.29 161.63,134.11 161.63,131.56 161.85,131.35 164.54,131.35 164.75,131.56 164.75,134.06
GND on TOP: 106,119.68 106,120.11 106.45,120.57 106.75,120.57 108.2,119.12 108.2,118.23 107.22,117.25 106.99,117.25 106.84,117.4 106.66,117.4 106.15,116.9 106.15,116.82 106.46,116.52 106.46,116.29 106.33,116.16 105.64,116.16 105.3,115.82 104.91,115.82 104.63,116.1 104.45,116.1 103.84,116.71 103.84,116.89 103.38,117.35 103.38,117.6 103.56,117.78 103.84,117.78 104.25,117.37 104.25,117.24 104.45,117.04 105.31,117.04 105.58,117.32 105.58,117.37 106.76,118.54 106.76,118.92
GND on TOP: 106.56,114.87 106.78,114.64 106.78,114.47 106.61,114.3 106.12,114.3 105.87,114.04 105.87,112.88 107.42,111.33 107.42,110.92 107.32,110.82 106.96,110.82 106.84,110.95 106.45,110.95 106.33,110.82 106.33,110.18 105.95,109.8 105.95,109.42 105.82,109.29 105.41,109.29 105.18,109.52 105.18,110.77 105.62,111.2 105.62,111.91 105.57,111.96 105.57,112.34 105.31,112.6 105.31,113.23 105.23,113.31 105.2,113.35 105.16,113.39 105.16,114.1 105.93,114.87
GND on TOP: 125.58,118.36 127.16,118.36 127.33,118.54 127.33,119.4 127.21,119.53 125.63,119.53 125.48,119.38 125.48,118.46
GND on TOP: 131.88,23.57 131.19,23.57 131.07,23.44 131.07,22.96 130.92,22.81 126.88,22.81 126.76,22.69 126.76,21.6 126.34,21.18 123.88,21.18 123.83,21.23 123.83,22.22 123.93,22.32 125.05,22.32 125.38,22.65 125.38,24.64 125.48,24.74 126.47,24.74 127.02,25.28 127.02,25.49 127.08,25.55 131.7,25.55 131.93,25.32 131.93,23.62
GND on TOP: 100.36,123.72 102.16,123.72 103.46,122.43 103.46,122.04 103.23,121.82 103.23,121.11 103.86,120.47 103.86,119.63 103.43,119.2 103.08,119.2 100.08,122.2 100.08,123.44
GND on TOP: 88.37,121.16 96.98,121.16 97.34,120.8 97.34,119.4 97.56,119.17 98.15,119.17 98.4,119.43 98.4,122.12 98.25,122.27 97.29,122.27 95.96,123.59 89.41,123.59 88.14,122.32 88.14,121.38
GND on TOP: 111.52,123.98 111.66,123.84 111.66,123.63 112.25,123.04 112.35,123.04 113.55,124.23 113.55,124.28 113.46,124.37 113.46,124.42 113.05,124.82 112.78,124.82 112.62,124.99 112.62,125.13 112.89,125.39 112.89,125.58 113.72,126.42 115.62,126.42 115.91,126.12 115.91,125.26 115.28,124.62 115,124.62 113.72,123.34 113.72,122.81 113.92,122.6 113.92,122.5 113.59,122.17 113.59,121.94 113.9,121.64 113.9,121.57 113.17,120.83 112.98,120.65 112.68,120.65 112.58,120.75 112.58,120.75 112.53,120.8 112.53,121.13 113.03,121.64 113.03,121.89 112.22,122.71 111.85,122.71 111.48,123.08 111.36,123.08 111.36,123.09 111.2,123.09 110.77,122.65 110.57,122.65 110.29,122.93 109.83,122.93 108.84,121.95 108.84,121.44 109.43,120.85 110.11,120.85 110.42,121.16 110.65,121.16 110.9,120.9 110.9,120.75 109.52,119.38 109.35,119.38 108.92,119.81 108.92,120.47 106.58,122.81 106.58,122.93 106.91,123.26 107.12,123.26 107.93,122.45 108.41,122.45 109.34,123.38 109.77,123.38 110.04,123.11 110.29,123.11 111.16,123.98
GND on TOP: 107.46,115 110.29,117.84 110.75,117.84 110.83,117.76 110.83,117.35 109.47,116 109.47,115.8 109.66,115.61 109.66,115.27 109.05,114.66 108.09,114.66 107.65,114.23 107.53,114.23 107.2,114.56 107.2,114.74
GND on TOP: 104.56,80.33 104.56,83.02 104.96,83.41 107.93,83.41 108.08,83.26 108.08,80.26 107.85,80.03 104.85,80.03
GND on BOTTOM: 114.39,109.97 114.33,110.03 114.33,110.31 114.43,110.41 114.76,110.41 115.07,110.72 115.07,110.97 115.09,110.99 115.29,110.99 115.35,110.93 115.35,110.29 115.03,109.97
GND on BOTTOM: 79.85,56.11 83.3,56.11 83.43,55.98 83.43,51.28 83.02,50.87 79.26,50.87 78.88,51.26 78.88,55.14
GND on BOTTOM: 109.53,132.31 110.01,132.31 110.47,132.76 111.46,132.76 111.64,132.59 112.12,132.59 112.53,132.99 112.53,133.55 108.72,137.36 108.66,137.36 107.22,138.81 106.61,138.81 105.74,137.95 105.74,137.46 106.89,136.32 106.89,136.04 108.99,133.93 108.99,132.84
GND on BOTTOM: outline of 339 points within 102.96,103.51 110.35,112.8
GND on BOTTOM: 110.93,139.72 115.01,139.72 115.17,139.88 115.17,143.36 114.99,143.53 111.18,143.53 110.7,143.05 110.7,139.95
GND on BOTTOM: 121.29,108.57 121.26,108.59 121.24,108.62 121.2,108.64 121.18,108.69 121.22,108.73 121.44,108.92 121.37,109.19 121.34,109.28 121.4,109.36 121.47,109.41 121.52,109.48 121.59,109.53 121.68,109.5 121.8,109.43 121.95,109.43 122.09,109.57 122.36,109.57 122.48,109.45 122.48,109.19 121.86,108.57
GND on BOTTOM: 25.2,32.03 27.64,34.47 29.32,34.47 29.71,34.07 29.71,30.41 29.39,30.1 25.51,30.1 25.2,30.4
GND on BOTTOM: 63.5,48.03 63.5,56.16 71.63,56.16 71.63,48.03
GND on BOTTOM: 157.03,54.2 157.03,62.33 165.15,62.33 165.15,54.2
GND on BOTTOM: 99.34,114.82 99.36,114.79 99.35,114.76 99.34,114.5 99.5,114.3 99.52,114.28 99.52,114.26 99.52,114.22 99.52,114.21 99.53,113.9 99.83,113.83 99.91,113.83 99.97,113.78 100.19,113.57 100.49,113.61 100.52,113.62 100.56,113.61 100.64,113.52 100.64,113.24 100.54,113.14 100.15,113.14 100,113.19 99.85,113.14 99.67,113.14 99.65,113.15 99.63,113.16 99.49,113.28 99.3,113.26 99.27,113.26 99.24,113.27 98.94,113.57 98.93,113.61 98.94,113.62 98.96,113.81 98.84,113.95 98.82,113.97 98.81,114 98.81,114.17 98.8,114.5 98.47,114.51 98.29,114.51 98.26,114.52 98.26,114.54 98.17,114.63 98.05,114.67 98.02,114.68 98,114.72 98,114.97 98.23,115.2 98.3,115.19 98.37,115.2 98.52,115.2 98.54,115.19 98.56,115.18 98.76,115.05 99,115.08 99.01,115.09 99.07,115.09
GND on BOTTOM: 157.23,98.4 149,98.4 148.59,98.8 148.59,100.38 148.82,100.61 153.72,100.61 154.13,101.01 154.13,102.06 152.76,103.43 152.76,115.72 153.01,115.97 157.2,115.97 157.97,115.21 157.97,99.13
GND on BOTTOM: 156.82,16.25 160.94,16.25 161.38,16.7 161.38,16.89 161.45,16.95 162.14,16.95 162.21,16.89 162.21,16.44 161.19,15.43 161.19,10.79 161.01,10.62 157.18,10.62 157,10.79 157,12.67 157.13,12.8 157.7,12.8 157.93,13.03 157.93,14.21 157.79,14.35 156.84,14.35 156.71,14.49 156.71,16.14
GND on BOTTOM: 95.77,116.16 95.8,116.08 95.8,116.07 95.8,115.89 95.84,115.86 95.84,115.7 95.69,115.55 95.49,115.55 95.39,115.65 94.6,115.65 94.04,116.22 94.04,118.9 94.23,119.09 94.89,119.09 95.36,118.62 95.36,118.54 94.76,117.94 94.76,117.69 95.04,117.41 95.07,117.33 95.03,117.26 95.02,117.25 94.94,116.92 95.23,116.76 95.32,116.73 95.43,116.42 95.66,116.35 95.74,116.32 95.77,116.24
GND on BOTTOM: outline of 130 points within 110.29,104.7 118.06,110.78
GND on BOTTOM: outline of 2203 points within 95.48,108.08 129.36,128.7
GND on BOTTOM: 107.18,129.25 107.12,129.11 107.06,129.04 106.97,129.04 106.92,129.06 106.86,129.07 106.84,129.1 106.84,129.5 106.83,129.52 106.54,129.81 106.42,129.81 106.06,130.17 105.99,130.17 105.84,130.32 105.84,130.5 106.18,130.84 106.34,130.84 106.38,130.83 106.4,130.79 106.4,130.37 106.81,129.96 106.81,129.94 106.9,129.81 107.05,129.77 107.13,129.74 107.16,129.67 107.16,129.64 107.3,129.51 107.31,129.45 107.32,129.41 107.32,129.37 107.3,129.34
GND on BOTTOM: 158.52,180.54 160.1,180.54 160.23,180.41 160.23,178.89 160.38,178.74 162.41,178.74 162.51,178.84 162.51,180.06 162.41,180.16 162.03,180.16 161.75,180.44 161.34,180.44 158.68,183.11 158.68,186.28 158.58,186.38 156.92,186.38 156.85,186.31 156.85,185.77 156.98,185.65 156.98,182.37 157.18,182.17 157.92,182.17 158.04,182.04 158.04,181.02
GND on BOTTOM: outline of 99 points within 111.98,126.6 114.99,129.82
GND on BOTTOM: 15.65,34.49 17.94,34.49 18.32,34.11 18.32,33.12 17.99,32.79 15.24,32.79 15.14,32.89 15.14,33.98
GND on BOTTOM: 92.26,31.77 95.02,31.77 95.2,31.95 95.2,33.48 95.05,33.63 92.28,33.63 92.13,33.48 92.13,31.9
GND on BOTTOM: 170.2,145.55 168.77,145.55 168.61,145.39 168.61,144.27 168.72,144.16 171.15,144.16 171.21,144.22 171.21,144.6 171.15,144.66 170.45,144.66 170.26,144.85 170.26,145.49
GND on BOTTOM: 202.2,160.85 202.98,160.85 203.11,160.73 203.11,160.46 203,160.36 202.86,160.36 202.23,159.73 201.35,159.73 201.3,159.67 201.3,158.88 201.45,158.73 202.14,158.73 203,159.59 203,159.84 203.13,159.97 203.35,159.97 203.45,159.87 203.45,159.35 202.92,158.81 202.53,158.81 202.34,158.62 202.34,158.61 202.31,158.59 202.31,157.81 202.23,157.72 201.17,157.72 200.98,157.91 200.98,159.63
GND on BOTTOM: 104.9,112.72 104.91,112.65 104.91,112.62 104.87,112.56 104.81,112.54 104.66,112.39 104.31,112.39 104.27,112.44 104.22,112.49 104.14,112.55 103.88,112.58 103.67,112.43 103.62,112.29 103.63,112.15 103.62,112.08 103.57,112.04 103.37,112.04 103.27,112.13 103.27,112.22 103.28,112.3 103.28,112.37 103.3,112.45 103.37,112.49 103.6,112.61 103.69,112.85 103.68,112.92 103.66,112.98 103.66,113.07 103.75,113.15 103.87,113.15 104.19,113.21 104.33,113.5 104.35,113.53 104.57,113.53 104.68,113.43 104.68,113.36 104.59,113.02 104.84,112.77
GND on BOTTOM: 29.77,67.31 33.4,67.31 34.06,66.65 34.06,64.44 33.4,63.78 29.72,63.78 28.91,64.59 28.91,66.44
GND on VCC: outline of 81 points within 1.27,14.3 52.73,74.69
GND on VCC: 14.91,90.88 14.39,91.75 13.49,92.19 13.46,92.21 1.87,92.21 1.87,94.63 7.11,94.63 7.14,94.65 8.53,95.85 8.12,97.63 8.12,109.67 8.53,111.46 7.14,112.65 7.11,112.67 1.27,112.67 1.27,119.13 17.9,119.13 18.19,118.84 18.19,106.52 20.73,103.98 20.73,100.81 24.69,96.85 25.13,96.85 25.43,96.55 25.43,91.24 25.13,90.94 21.81,90.92
GND on VCC: 166.67,1.27 166.67,7.74 166.65,7.76 166.01,9.09 164.68,9.73 164.66,9.75 134.41,9.75 133.89,10.28 133.36,9.75 122.22,9.75 121.95,10.02 121.95,19.99 119.03,22.91 119.03,29.43 119.51,29.92 132.98,29.92 133.74,30.68 144.53,30.68 149.61,35.76 203.72,35.76 205.39,37.43 205.39,47.4 205.68,47.7 229.13,47.7 229.13,1.27
GND on VCC: 83.95,58.88 80.17,62.66 80.04,87.96 80.04,88.68 80.33,88.97 84.34,88.97 85.5,90.14 85.5,92.68 103,110.18 104.57,110.18 104.8,109.95 104.8,109.32 105.33,108.79 107.2,108.79 109.35,110.95 113.16,110.95 113.8,111.58 143.52,111.58 144.3,112.36 144.3,122.23 143.52,123.01 133.17,123.01 132.87,123.31 132.87,138.61 130.33,141.15 130.33,145.26 130.94,145.87 134.92,145.87 135.41,145.38 135.41,142.59 136.83,141.17 149.15,141.17 149.91,140.41 166.17,140.41 166.4,140.18 166.4,138.53 169.32,135.6 169.32,64.31 163.88,58.88
GND on VCC: 107.34,142.86 107.05,142.57 106.86,142.57 105.59,141.3 99.08,141.3 98.81,141.42 98.53,141.3 85,141.3 84.62,141.68 84.62,142.19 84.53,142.28 84.5,143.37 83.96,144.32 85.67,150.63 86.27,157.14 86.27,158.53 88.66,158.53 88.66,153.26 88.67,153.24 89.47,151.56 91.15,150.76 91.16,150.75 118.68,150.75 118.77,150.65 118.77,148.52 118.03,147.78 108.51,147.78 107.34,146.61
GND on VCC: 125.74,152.09 124.21,153.62 121.74,153.62 121.5,153.86 121.5,158.53 124.76,158.53 124.78,158.55 126.11,159.19 126.75,160.52 126.77,160.54 126.77,188.83 134.06,188.83 134.08,188.85 134.99,189.17 135.68,189.83 137.7,189.83 138.2,189.33 138.2,188.06 138.33,187.93 138.33,187.65 138.61,187.65 138.73,187.53 156.09,187.53 156.62,188.06 156.62,189.16 156.65,189.23 157.11,189.69 157.25,189.83 159.42,189.83 160.11,189.17 161.02,188.85 161.04,188.83 197.13,188.83 197.13,181.84 197.15,181.82 197.79,180.49 199.12,179.85 199.14,179.83 201.06,179.83 201.78,178.83 202.92,178.35 202.94,178.33 225.46,178.33 225.48,178.35 226.62,178.83 227.34,179.83 229.13,179.83 229.13,158.73 228.97,158.57 195.59,158.57 185.68,168.48 171.12,168.48 162.97,160.33 162.97,153.91 162.67,153.62 130.73,153.62 129.21,152.09 ; 1 cut-out
GND on VCC: 21.88,1.27 18.26,4.65 17.96,5.65 17.23,6.4 17.05,6.59 17.05,6.83 21.22,11 26.04,11 26.93,11.89 27.1,11.89 27.33,11.65 27.33,10.19 26.53,9.71 26.08,8.88 26.07,8.85 26.05,8.72 26.03,8.59 25.59,5.39 25.55,5.13 25.55,5.13 25.53,4.89 25.51,4.64
GND on VCC: 186.19,48.59 186.08,48.69 186.08,51.02 186.32,51.26 187.63,51.26 187.86,51.02 187.86,48.69 187.76,48.59
GND on VCC: 43.06,48.21 36.86,54.41 36.86,58.01 37.35,58.49 43.95,58.49 47.76,62.3 60.19,62.3 60.48,62.01 60.48,48.5 60.19,48.21
GND on GND: outline of 242 points within 0.26,0.25 230.14,190.85 ; 1 cut-out
GNDA on TOP (solid shape): 26.52,23.32 26.52,22.3 26.33,22.11 25.44,22.11 25.25,22.3 25.25,23.25 25.44,23.44 26.39,23.44
GNDA on TOP (solid shape): 37.7,17.24 37.7,14.86 37.52,14.68 36.73,14.68 36.55,14.86 36.55,17.27 36.63,17.35 37.6,17.35
GNDA on TOP (solid shape): 24.22,21.17 24.22,20.15 24.03,19.96 22.69,19.96 22.51,20.14 22.51,21.28 22.58,21.36 24.03,21.36
GNDA on TOP (solid shape): 42.32,15.25 42.32,12.91 41.91,12.51 39.41,12.51 38.92,13 38.92,14.3 39.12,14.5 39.12,15.34 39.22,15.44 42.13,15.44
GNDA on TOP (solid shape): 25.85,12.14 25.85,11.58 25.81,11.54 23.63,11.54 23.51,11.66 23.51,12.62 23.57,12.69 25.3,12.69
GNDA on TOP (solid shape): 35.36,13.76 35.36,13.34 35.46,13.23 35.67,13.23 35.77,13.13 35.77,12.67 35.61,12.52 34.47,12.52 34.27,12.52 34.01,12.77 34.01,13.08 34.03,13.09 34.03,13.75 34.17,13.89 35.23,13.89
GNDA on VCC: 16.54,6.7 16.41,6.73 16.28,6.75 16.26,6.77 13.13,6.77 13.96,8.06 13.47,9.51 13.47,16.29 13.88,18.08 12.49,19.27 12.46,19.29 12.28,19.29 11.56,20.01 12.96,21.41 23.63,21.41 25.53,23.32 30.68,23.32 32.01,24.65 39.55,24.65 40.86,23.34 40.86,19.46 41.33,19 44.25,19 44.35,18.89 44.35,17.37 44.86,16.86 44.86,14.32 45.39,13.79 48.84,13.79 49.43,14.38 49.43,16.56 49.03,16.97 48.08,16.97 47.34,17.71 47.34,18.91 46.68,19.57 45.79,19.57 45.62,19.74 45.62,20.16 45.73,20.27 46.91,20.27 47.55,19.63 47.93,19.63 48.31,19.25 49.33,19.25 49.58,19 50.72,19 50.96,18.76 50.96,14.53 49.33,12.9 44.75,12.9 44.25,12.39 26.72,12.39 25.83,11.5 21.01,11.5 16.54,7.04
GNDA on GND: 16.54,5.63 16.3,5.72 16,5.75 0.26,5.75 0.26,7.52 12.2,7.52 12.25,7.52 12.95,8.17 12.45,8.99 12.45,16.81 12.95,17.63 12.25,18.28 12.2,18.28 0.26,18.28 0.26,19.63 0.39,19.76 11.31,19.76 12.96,21.41 23.63,21.41 25.53,23.32 30.68,23.32 32.01,24.65 39.55,24.65 40.86,23.34 40.86,19.46 41.33,19 44.25,19 44.35,18.89 44.35,17.37 44.86,16.86 44.86,14.32 45.39,13.79 48.84,13.79 49.43,14.38 49.43,16.56 49.03,16.97 48.08,16.97 47.34,17.71 47.34,18.91 46.68,19.57 45.79,19.57 45.62,19.74 45.62,20.16 45.73,20.27 46.91,20.27 47.55,19.63 47.93,19.63 48.31,19.25 49.33,19.25 49.58,19 50.72,19 50.96,18.76 50.96,14.53 49.33,12.9 44.75,12.9 44.25,12.39 26.72,12.39 25.83,11.5 21.01,11.5 16.54,7.04
VDDP_LDO on TOP (solid shape): 168.99,176.29 168.99,175.52 169.24,175.27 169.43,175.27 169.5,175.21 169.5,174.19 169.43,174.13 169.31,174.13 168.42,175.02 168.42,176.35 168.48,176.41 168.86,176.41
VIN on TOP (solid shape): 135.41,168.22 135.41,165.94 135.92,165.43 136.81,165.43 137.04,165.2 137.04,163.27 136.91,163.14 131.52,163.14 131.14,163.52 131.14,164.36 130.86,164.64 130.64,164.64 130.61,164.67 127.49,164.67 127.36,164.79 127.36,168.78 127.44,168.86 134.78,168.86
VIN on BOTTOM: 131.85,167.66 132.36,167.16 132.36,165.17 133,164.54 135.26,164.54 135.51,164.29 135.51,159.59 135.33,159.41 131.17,159.41 129.06,161.52 127.94,161.52 127.41,162.05 127.41,167.31 127.77,167.66
+CHGRTC on BOTTOM: 180.32,111.61 181.03,111.61 181.03,112.14 181.05,112.16 181.21,112.16 181.23,112.14 181.23,111.68 181.28,111.63 181.66,111.63 181.74,111.55 181.74,110.82 181.31,110.39 181.31,109.5 181.11,109.29 180.17,109.29 179.96,109.5 179.96,111.25
+EC_VCCA on TOP: 200.69,49.1 205.34,49.1 208.12,51.88 208.12,68.46 204.5,72.08 203.48,72.08 203.1,71.7 203.1,70.6 206.14,67.56 206.14,53.02 204.63,51.51 200.82,51.51 200.56,51.26 200.56,49.22
+EC_VCCA on IN1: 198.28,76.27 200.18,76.27 200.24,76.21 203.93,76.21 205.39,74.75 205.39,71.19 201.7,67.51 201.7,67.38 199.04,64.72 194.72,64.72 194.21,65.23 194.21,65.99 197.39,69.16 197.39,75.39
+FAN_POWER on BOTTOM (solid shape): 49.18,109.22 49.18,101.29 49.05,101.17 48.31,101.17 48.14,101.34 48.14,109.22 48.37,109.45 48.95,109.45
+INV_PWR_SRC on TOP (solid shape): 225.45,176.2 225.45,175.48 225.45,175.4 225.45,175.32 225.45,173.63 225.38,173.56 223.8,173.56 223.61,173.75 223.61,174.46 224.18,175.03 224.18,176.1 224.44,176.35 225.3,176.35
+INV_PWR_SRC on BOTTOM (solid shape): 224.88,175.08 224.88,173.65 224.74,173.51 224.34,173.51 224.16,173.33 223.73,173.33 223.55,173.15 223.4,173.15 223.32,173.23 223.32,175.18 223.47,175.33 224.63,175.33
+INV_PWR_SRC_R on TOP: 222.41,174.78 222.3,174.88 220.81,174.88 220.63,174.93 220.44,174.88 218.57,174.88 218.42,175.03 218.42,175.69 218.42,176.17 218.65,176.4 222.38,176.4 222.79,176.81 222.79,178.03 222.89,178.13 223.73,178.13 223.8,178.05 223.8,175.36 223.52,175.08 223.52,174.85 223.45,174.78
+LAN_IO on TOP: 44.76,79.25 44.81,79.2 44.81,77.8 48.57,74.04 49.97,74.04 50.44,73.57 50.44,72.24 50.11,71.91 47.99,71.91 42.04,77.87 42.04,78.84 41.46,79.42 36.68,79.42 36.15,78.89 36.15,78.1 35.77,77.72 34.67,77.72 34.57,77.82 34.57,80.67 35.51,81.61 39.3,81.61 39.58,81.89 39.58,83.07 40.03,83.53 44.44,83.53 44.76,83.21
+LAN_IO on BOTTOM: 48.7,79.25 49.25,79.25 49.38,79.12 49.38,77.87 50.42,76.83 50.42,70.89 50.35,70.81 48.72,70.81 48.62,70.91 48.62,79.17
+LAN_IO on BOTTOM: 45.27,81.96 45.19,81.89 42.17,81.89 42.12,81.84 41.41,81.84 41.06,82.18 41.06,82.51 41.48,82.93 42.27,82.93 42.57,83.23 42.57,83.59 42.95,83.97 44.94,83.97 45.27,83.64
+LAN_IO on BOTTOM: 35.18,82.65 36.35,82.65 36.43,82.57 36.43,81.86 36.27,81.71 35.56,81.71 34.62,80.77 34.62,79.07 34.75,78.94 35.59,78.94 35.77,78.76 35.77,77.93 35.51,77.67 33.28,77.67 33.18,77.77 33.18,78.76 33.76,79.35 33.76,81.23
+LAN_IO_UL3 on BOTTOM: 45.49,83.49 47.7,83.49 48.03,83.16 48.03,82.37 47.55,81.89 45.6,81.89 45.39,82.09 45.39,82.5 45.42,82.52 45.95,82.52 45.98,82.55 45.98,82.95 45.95,82.98 45.42,82.98 45.39,83.01 45.39,83.39
+LAN_VDD on BOTTOM (solid shape): 34.78,88.52 36.17,88.52 36.25,88.44 36.25,87.81 36.07,87.63 36.07,85.65 35.97,85.55 34.8,85.55 33.89,86.46 33.89,88.72 33.99,88.82 34.47,88.82
+LCDVDD on BOTTOM: 212.86,167.05 214.66,167.05 214.79,166.93 214.79,165.4 215.12,165.07 215.57,165.07 215.7,164.95 215.7,163.93 215.52,163.75 212.86,163.75 212.68,163.93 212.68,166.88
+LCDVDD_CONN on BOTTOM: 215.22,172.41 216.94,172.41 217.12,172.24 217.12,165.71 216.87,165.45 215.12,165.45 214.89,165.68 214.89,172.08
+SOC_VCC on TOP: 113.19,116.43 113.19,115.58 112.86,115.25 112.75,115.25 112.42,115.58 112.42,115.69 112.43,115.7 112.52,115.86 112.52,116.04 112.48,116.13 112.42,116.21 112.39,116.27 112.4,116.34 112.43,116.6 112.21,116.75 111.98,116.62 111.98,116.36 111.99,116.29 111.96,116.23 111.89,116.16 111.84,116.07 111.82,115.91 111.88,115.76 111.88,115.28 109.25,112.65 108.08,112.65 107.7,112.27 107.41,112.27 106.85,112.82 106.85,113.07 108.29,114.51 109.05,114.51 109.86,115.32 109.86,115.68 109.75,115.79 109.75,116.05 112.02,118.32 112.78,118.32 113.22,117.89 113.22,117.75 112.63,117.16 112.63,116.99
+SOC_VCC on BOTTOM: 112.34,117.66 113.45,116.54 113.45,116.4 113.36,116.31 112.94,116.31 112.87,116.24 112.51,116.24 112.48,116.22 112.41,116.22 112.4,116.23 111.83,116.04 112.23,115.6 112.33,115.5 112.33,115.42 112.33,115.32 111.68,114.67 111.33,114.67 111.21,114.55 111.21,114.26 111.06,114.11 111,114.11 110.93,114.1 110.72,114.1 110.67,114.05 110.67,113.5 110.07,112.91 108.87,112.91 108.68,113.09 107.92,113.09 107.49,112.67 107.32,112.67 107.18,112.81 107.18,113.49 107.26,113.57 107.65,113.57 109.06,114.98 109.63,114.98 109.77,115.12 109.77,115.24 109.77,115.24 109.8,115.39 109.77,115.53 109.77,115.54 109.77,115.99 109.93,116.14 110.18,116.14 110.18,116.15 110.51,116.15 111.03,116.68 111.04,116.68 112.09,117.73 112.21,117.73
+SOC_VCC on BOTTOM: 153.5,100.96 148.95,100.96 147.22,102.69 147.22,106.2 143.67,109.75 143.06,109.75 143.03,109.73 141.74,109.73 138.41,113.05 138.41,121.77 138.74,122.1 152.07,122.1 152.2,121.97 152.2,121.03 152.07,120.9 149.2,120.9 149.15,120.85 149.15,120.14 149.23,120.06 152.1,120.06 152.2,119.96 152.2,103.25 153.62,101.83 153.62,101.09
+SOC_VCC on VCC: 109.35,111.45 107.72,113.08 107.72,113.38 109.38,115.03 109.38,115.86 109.67,116.15 110.24,116.15 116.59,122.5 143.31,122.5 143.79,122.02 143.79,112.57 143.31,112.09 113.59,112.09 112.95,111.45
+SOC_VCC on IN1: 109.81,116.36 111.05,116.36 118.82,124.13 145.14,124.13 145.74,123.53 145.74,120.97 147.43,119.28 151.06,119.28 152,118.34 152,106.5 151.41,105.92 147.12,105.92 140.85,112.19 140.85,112.27 140.14,112.98 114.84,112.98 113.95,113.87 112.83,113.87 111.13,112.16 108.21,112.16 107.65,112.72 107.65,113.51 109.55,115.42 109.55,116.1
+SOC_VNN on TOP: 119.97,143.03 126.93,143.03 131.7,138.25 131.7,135.08 131.58,134.95 128.35,134.95 125.58,137.72 122.56,137.72 121.26,139.01 120.2,139.01 119.82,139.39 119.82,142.87
+SOC_VNN on TOP: 111.41,118.11 111.41,118.04 111.2,117.82 110.98,117.82 110.82,117.99 110.29,117.99 109.61,117.3 109.36,117.3 108.67,117.99 108.67,118 108.41,118.25 108.41,118.9 108.74,119.23 109.07,119.23 109.15,119.15 109.66,119.15 111.15,120.65 111.15,120.88 110.78,121.25 110.78,121.52 111.08,121.82 111.59,121.82 112.07,122.3 112.22,122.3 112.8,121.71 112.8,121.66 112.32,121.18 112.32,120.8 112.65,120.47 113.01,120.47 113.9,121.36 114.15,121.36 114.58,120.93 114.58,120.44 115.22,119.81 115.22,119.61 115.22,119.61 115.22,119.2 115.78,118.64 115.78,118.01 115.17,117.4 114.86,117.4 114.15,118.11 114.15,118.31 114.43,118.59 114.43,118.84 113.97,119.3 113.74,119.3 113.39,118.95 113.14,118.95 113.05,119.04 112.51,119.04 112.04,119.5 111.74,119.5 110.93,118.69 110.93,118.59
+SOC_VNN on BOTTOM: 108.85,116.26 108.74,116.37 108.74,116.77 108.66,116.84 108.66,117.17 108.67,117.17 108.67,117.62 108.67,117.62 108.67,118.03 108.67,118.03 108.74,118.24 108.95,118.32 109.03,118.32 109.23,118.51 109.23,118.64 109.24,118.71 109.24,118.74 109.39,118.89 109.88,118.89 110.29,118.93 110.39,119.33 110.39,119.53 111.46,120.6 111.46,120.98 111.56,121.08 112.32,121.08 112.41,121 112.41,120.11 112.39,120.08 112.97,119.51 113.46,119.51 113.57,119.4 113.57,119.23 114.01,118.78 114.01,118.68 114.29,118.4 114.35,118.42 114.42,118.41 114.51,118.39 114.62,118.28 114.62,118.1 114.8,117.93 114.83,117.93 114.84,117.92 114.94,117.91 115.1,117.92 115.17,117.85 115.17,116.94 115.09,116.86 114.66,116.86 114.15,117.37 114.15,117.73 113.97,117.9 113.77,117.9 113.13,118.54 113.13,118.77 113.08,118.82 113.07,118.83 113,118.93 112.9,119 112.9,119 112.86,119.04 112.37,119.04 112.33,119.02 111.98,119.02 111.47,118.52 111.37,118.41 111.37,118 111.23,117.86 110.79,117.86 110.73,117.92 110.43,117.92 110.22,117.71 110.22,117.37 109.11,116.26
+SOC_VNN on BOTTOM: 132.67,141.27 132.67,137.64 132.49,137.46 131.45,137.46 131.25,137.26 131.25,133.73 131.17,133.65 128.5,133.65 126.95,135.2 126.95,137.31 126.75,137.51 124.72,137.51 124.26,137.97 116.59,137.97 116.36,138.2 116.36,142.49 116.64,142.77 124.34,142.77 125.58,141.53 128.4,141.53 128.63,141.3 128.63,138.48 128.68,138.43 129.37,138.43 129.44,138.5 129.44,141.27 129.68,141.51 132.43,141.51
+SOC_VNN on VCC: 109.67,116.66 109.38,116.96 109.38,117.27 108.61,118.04 108.61,129.32 108.91,129.61 111.51,129.61 118.52,136.62 118.52,141.83 118.75,142.06 129.53,142.06 129.82,141.76 129.82,140.94 132.36,138.4 132.36,123.31 132.07,123.01 116.38,123.01 110.03,116.66
+SOC_VNN on IN1: 132.24,134.16 125.58,127.51 121.87,127.51 110.9,116.53 110.17,116.53 106.05,120.65 106.05,134.91 108.96,137.82 115.22,137.82 119.28,141.88 132.11,141.88 132.24,141.76
+SW_LX on BOTTOM (solid shape): 200.23,163.1 203.44,163.1 203.51,163.02 203.51,162.91 203.43,162.83 199.92,162.83 199.33,162.25 194.47,162.25 194.34,162.38 194.34,163.14 194.78,163.59 199.74,163.59
+SWR_V12 on BOTTOM (solid shape): 203.49,162.54 203.49,162.39 203.43,162.34 202.17,162.34 201.64,161.8 201.45,161.62 201.45,161.59 199.1,159.24 199.1,159.13 198.87,158.9 196.99,158.9 196.98,158.91 196.8,158.95 196.63,158.91 196.62,158.9 195.31,158.9 194.09,160.12 194.09,161.91 194.24,162.06 199.59,162.06 200.11,162.59 203.44,162.59
+VDISPLAY_VCC on BOTTOM: 10.82,109.98 15.83,109.98 16.03,109.78 16.03,107.26 15.8,107.03 9.33,107.03 9.1,107.26 9.1,108.25
ADPIN on TOP: 135.97,172.87 139.09,172.87 139.35,172.62 139.35,166.04 139.09,165.78 135.94,165.78 135.69,166.04 135.69,172.59
ADPIN on BOTTOM: 135.97,172.87 139.09,172.87 139.35,172.62 139.35,166.04 139.09,165.78 137.57,165.78 136.71,164.92 133.38,164.92 132.87,165.43 132.87,168.58 135.69,171.4 135.69,172.59
B+ on BOTTOM (solid shape): 133.07,32.87 133.07,30.1 132.9,29.92 127.26,29.92 126.99,30.19 126.99,32.87 127.22,33.09 132.85,33.09
B+ on BOTTOM (solid shape): 163.02,173.73 163.02,159.79 154.55,151.32 143.83,151.32 143.69,151.46 143.69,155.75 143.97,156.03 147.17,156.03 147.22,155.98 147.22,154.48 147.43,154.28 147.76,154.28 147.98,154.51 147.98,156 148.01,156.03 154.23,156.03 159.49,161.29 159.49,173.81 159.67,173.99 162.77,173.99
B+ on TOP: 219.93,176.85 219.84,176.76 218.55,176.76 218.29,176.5 218.29,175.74 218.09,175.54 216.21,175.54 216.03,175.72 216.03,176.83 216.08,176.88 216.18,176.88 216.21,176.91 217.73,176.91 218.14,177.32 219.82,177.32 219.93,177.2
B+ on TOP: 146.96,31.71 151.51,36.27 170.95,36.27 173.41,33.81 186.67,33.81 187.61,32.87 206.84,32.87 218.49,44.52 218.49,97.91 210.42,105.99 210.42,135.08 194.26,151.23 194.26,175.38 192.74,176.91 185.96,176.91 185.5,176.45 185.5,156.26 185.32,156.08 184.53,156.08 184.15,156.46 184.15,160.55 181.51,163.19 173.51,163.19 172.7,162.38 167.19,162.38 164.16,165.4 164.16,170.69 163.4,171.45 153.29,171.45 152.35,170.51 152.35,162.71 146.69,157.05 144.28,157.05 143.79,156.56 143.79,150.29 144.43,149.65 160.63,149.65 166.12,155.14 169.68,155.14 170.44,154.38 172.09,154.38 172.95,153.52 172.95,152.45 172.94,152.44 172.94,149.41 181.51,140.84 190.2,140.84 199.47,131.57 199.47,105.79 208.54,96.72 208.59,96.72 209.32,95.98 209.32,51.61 199.57,41.86 196.75,41.86 194.11,39.22 190.05,39.22 188.32,40.94 176.71,40.94 173.3,44.36 146.9,44.36 142.27,39.72 130.13,39.72 129.49,39.09 129.49,31.72 130.32,30.9 132.74,30.9 133.56,31.71 ; 1 cut-out
B+ on BOTTOM: 168.86,10.74 208.05,10.74 209.58,12.27 209.58,39.7 208.82,40.46 205.51,40.46 204.88,39.83 204.88,17.85 204.12,17.09 170.23,17.09 166.4,20.93 164.6,20.93 164.54,20.88 164.54,19.96 164.52,19.94 164.04,19.94 164.04,19.53 164.06,19.51 164.57,19.51 164.57,18.77 164.54,18.74 164.04,18.74 164.01,18.72 164.01,18.31 164.54,18.31 164.54,15.29 168.86,10.97
B+ on BOTTOM: 204.83,177.75 218.55,177.75 219.03,177.26 219.03,175.28 218.6,174.85 204.65,174.85 201.98,172.18 185.91,172.18 185.27,172.82 185.27,175.59 186.92,177.24 204.32,177.24
B+_1.35VP on BOTTOM: 157.7,19.84 160.14,19.84 160.65,20.34 161.93,20.34 162.41,20.83 164.39,20.83 164.42,20.8 164.42,20.19 164.34,20.11 163.83,20.11 163.83,19.38 163.86,19.35 164.34,19.35 164.39,19.3 164.39,18.92 164.37,18.9 163.86,18.9 163.83,18.87 163.83,18.18 163.88,18.13 164.32,18.13 164.37,18.08 164.37,17.33 164.24,17.21 161.32,17.21 161.26,17.14 154.97,17.14 154.71,17.4 154.71,20.14 154.92,20.34 157.2,20.34
BATT+ on BOTTOM (solid shape): 156.82,185.44 156.82,182.24 157.05,182.01 157.81,182.01 157.84,181.99 157.84,180.82 158.4,180.26 159.95,180.26 160.05,180.16 160.05,178.81 160.33,178.53 162.69,178.53 162.89,178.33 162.89,175.41 162.59,175.11 158.3,175.11 156.34,177.06 156.34,180.11 155.98,180.46 152.89,180.46 152.81,180.54 152.81,181.4 152.89,181.48 154.38,181.48 154.56,181.66 154.56,182.04 154.36,182.24 152.84,182.24 152.81,182.27 152.81,185.42 152.99,185.6 156.67,185.6
BATT+ on TOP: 153.06,182.88 156.67,182.88 156.8,182.75 156.8,182.29 157.05,182.04 157.76,182.04 157.84,181.96 157.84,180.85 158.25,180.44 158.25,178.56 158.14,178.46 152.94,178.46 152.71,178.69 152.71,182.52
BATT+ on VCC: 158.38,175.08 156.37,177.09 156.37,178.11 155.96,178.51 153.17,178.51 152.81,178.87 152.81,185.39 152.92,185.49 156.64,185.49 156.75,185.39 156.75,183.1 157.76,182.09 157.76,180.82 158.42,180.16 159.69,180.16 159.92,179.93 159.92,178.91 160.32,178.51 162.61,178.51 162.84,178.28 162.84,175.31 162.61,175.08
BATT++ on TOP: 156.32,186.51 156.62,186.81 156.62,189.3 156.16,189.76 153.04,189.76 152.61,189.33 152.61,184.1 152.76,183.94 154.71,183.94 154.89,184.12 154.89,184.61 155.05,184.76 155.98,184.76 156.32,185.09
BATT++ on IN1: 155.6,185.77 156.62,186.79 156.62,189.35 156.19,189.79 153.04,189.79 152.56,189.3 152.56,186.05 152.84,185.77
BOOT1 on BOTTOM: 161.82,131.22 161.82,129.49 161.17,128.83 161.17,127.3 160.94,127.07 160.43,127.07 160.32,127.19 160.32,128.97 161.51,130.16 161.51,131.21 161.58,131.29 161.76,131.29
BOOT_1.35VP on BOTTOM (solid shape): 156.26,26.13 156.26,26.06 156.18,25.97 154.78,25.97 154.08,25.27 153.17,25.27 153.06,25.37 153.06,25.96 153.14,26.03 154.46,26.03 154.65,26.22 156.18,26.22
BOOTG on BOTTOM: 162.2,134.47 162.2,135.92 161.25,136.87 161.25,136.88 160.89,137.24 160.89,138.53 160.71,138.71 160.3,138.71 160.11,138.51 160.11,137.16 161.95,135.32 161.95,134.47 162.01,134.41 162.14,134.41
BST on TOP (solid shape): 167.91,172.41 168.93,172.41 168.99,172.35 168.99,172.22 168.93,172.16 167.02,172.16 166.39,171.52 165.75,171.52 165.62,171.65 165.62,172.22 165.69,172.29 166.32,172.29 166.51,172.48 167.85,172.48
BST on BOTTOM (solid shape): 166.51,173.49 166.51,171.59 166.39,171.46 165.81,171.46 165.69,171.59 165.69,173.43 165.81,173.56 166.45,173.56
BST_1.35VP on BOTTOM: 153.13,24.51 153.19,24.57 154.08,24.57 154.14,24.51 154.14,21.52 153.98,21.36 153.23,21.36 153.13,21.46
BST_3V on TOP (solid shape): 133.43,17.52 133.43,16.51 133.37,16.44 131.47,16.44 131.46,16.43 130.36,16.43 130.31,16.48 130.31,16.61 130.36,16.66 131.44,16.66 132.4,17.63 133.33,17.63
BST_5V on TOP: 126.32,17.49 126.32,17.49 126.23,17.57 125.05,17.57 125,17.52 125,16.58 125.08,16.5 126.95,16.5 127.13,16.33 128.1,16.33 128.15,16.39 128.15,16.56 128.09,16.63 127.19,16.63
BST_CHGA on BOTTOM (solid shape): 165.31,174.76 165.31,172.6 165.18,172.48 164.54,172.48 164.29,172.73 164.29,174.64 164.48,174.83 165.24,174.83
CHG on BOTTOM (solid shape): 151.77,183.08 151.77,182.34 151.69,182.27 150.19,182.27 150.04,182.12 150.04,181.61 150.14,181.51 150.41,181.51 150.42,181.51 151.72,181.51 151.79,181.43 151.79,180.63 151.92,180.51 151.92,180.49 152.23,180.19 155.76,180.19 155.98,179.96 155.98,177.16 155.62,176.79 147.96,176.79 147.35,177.4 147.35,182.84 147.69,183.18 151.67,183.18
CHG_B+ on BOTTOM (solid shape): 149.69,165.22 149.69,165.2 149.94,164.95 152.05,164.95 152.71,164.29 152.71,161.49 154.46,159.74 154.46,157.76 154.23,157.53 149.97,157.53 149.46,158.04 149.46,160.78 149.18,161.06 146.51,161.06 146.31,161.26 146.31,163.55 146.05,163.8 144.89,163.8 144.71,163.98 144.71,164.64 144.55,164.79 143.62,164.79 143.51,164.89 143.51,165.68 143.62,165.78 149.13,165.78
CPU_B+ on TOP: 145.52,139.8 149.89,135.43 149.89,131.34 150.57,130.66 150.57,124.97 150.85,124.69 153.98,124.69 154,124.71 154,125.22 153.97,125.26 153.38,125.26 153.29,125.35 153.29,132.92 152.86,133.35 152.86,139.06 149.08,142.85 149.08,148.18 148.54,148.71 136.63,148.71 136.35,148.44 136.35,143.48 138.41,141.43 140.82,141.43 140.85,141.45 140.85,141.98 140.82,142.01 140.21,142.01 140.14,142.09 140.14,143.03 140.44,143.33 142.19,143.33 142.47,143.61 142.47,144.85 142.55,144.93 145.27,144.93 145.52,144.68
CPU_B+ on BOTTOM: 150.83,126.36 150.83,128.29 150.78,128.34 150.78,129.61 140.82,139.57 136.93,139.57 136.24,140.27 136.24,150.15 136.6,150.52 145.44,150.52 145.98,149.98 145.98,146.91 145.57,146.51 142.78,146.51 142.32,146.05 142.32,142.54 153.57,131.29 153.57,126.44 153.34,126.21 150.98,126.21
DCIN on TOP (solid shape): 168.04,178.09 168.04,174.83 168.99,173.87 168.99,173.75 168.93,173.68 167.91,173.68 167.11,174.48 167.11,175.33 166.88,175.56 166.88,178.08 166.98,178.18 167.95,178.18
DH_1.35VP on BOTTOM (solid shape): 154.5,20.08 154.5,19.7 154.31,19.51 152.28,19.51 152.09,19.7 152.09,20.01 152.34,20.27 154.31,20.27
DH_1.35VP on IN2 (solid shape): 153.44,20.95 153.44,19.75 153.25,19.56 152.49,19.56 152.24,19.81 152.24,21.14 152.37,21.27 153.13,21.27
DH_1.35VP on IN2 (solid shape): 155.16,25.59 155.16,25.33 153.95,24.13 153.64,24.13 153.13,24.64 153.13,24.89 154.02,25.78 154.97,25.78
DH_1.35VP on BOTTOM: 154.27,24.89 154.27,25.21 154.91,25.84 156.24,25.84 156.3,25.78 156.3,25.65 156.24,25.59 155.35,25.59 154.78,25.02 154.78,24.89 154.65,24.76 154.4,24.76
DH_CHG on TOP (solid shape): 166.64,173.05 167.66,173.05 167.78,172.92 168.99,172.92 169.05,172.86 169.05,172.73 168.99,172.67 167.78,172.67 167.72,172.6 166.39,172.6 166.26,172.48 165.5,172.48 165.5,173.37 166.32,173.37
DH_CHG on BOTTOM (solid shape): 158.09,160.7 158.09,160.23 157.86,160.01 155.13,160.01 154.92,160.22 154.92,160.68 155.1,160.86 157.94,160.86
DH_CHG on IN2 (solid shape): 158.08,161.63 158.08,160.34 158,160.26 156.91,160.26 156.84,160.34 156.84,161.55 156.99,161.71 158,161.71
DH_CHG on IN2 (solid shape): 167.85,173.53 167.85,172.64 167.69,172.49 165.79,172.49 165.64,172.64 165.64,173.53 165.71,173.61 167.77,173.61
DL_1.35VP on BOTTOM (solid shape): 156.62,25.02 156.62,24 156.49,23.87 156.49,22.86 156.42,22.78 155.96,22.78 155.88,22.86 155.88,23.71 156.37,24.19 156.37,25.02 156.43,25.08 156.56,25.08
DL_1.35VP on IN2 (solid shape): 156.49,23.81 156.49,22.86 156.81,22.54 157.19,22.54 157.56,22.17 157.56,21.77 157.43,21.64 156.57,21.64 155.98,22.22 155.98,23.75 156.18,23.94 156.37,23.94
DL_1.35VP on BOTTOM: 156.63,13.22 156.63,14.05 156.76,14.18 157.71,14.18 157.78,14.11 157.78,13.22 157.65,13.1 156.76,13.1
DL_1.35VP on IN2: 156.63,13.18 156.63,14.45 156.82,14.64 157.52,14.64 157.78,14.39 157.78,13.18 157.59,12.99 156.82,12.99
DL_CHG on TOP (solid shape): 169.94,177.18 169.94,175.46 170.01,175.4 170.01,174.19 169.94,174.13 169.82,174.13 169.75,174.19 169.75,175.22 169.31,175.66 169.31,177.18 169.43,177.3 169.82,177.3
DL_CHG on BOTTOM (solid shape): 151.74,170.61 151.74,169.54 151.59,169.39 149.76,169.39 149.66,169.49 149.66,170.61 149.76,170.71 151.64,170.71
DL_CHG on IN2 (solid shape): 152.07,170.61 152.07,169.9 151.92,169.75 149.76,169.75 149.69,169.82 149.69,170.58 149.81,170.71 151.97,170.71
DL_CHG on IN2 (solid shape): 169.93,177.85 169.93,176.07 169.78,175.92 169.5,175.92 168.8,176.62 168.65,176.62 168.63,176.63 168.38,176.63 168.25,176.76 168.25,177.85 168.33,177.92 169.85,177.92
ECAGND on IN2: 201.55,73.43 201.55,67.08 201.2,66.72 196.52,66.72 196.12,67.13 196.12,69.42 197.26,70.56 197.26,73.3 197.64,73.68 201.3,73.68
ENVDD_R on BOTTOM (solid shape): 217.68,164.89 217.68,164.41 218.01,164.08 218.65,164.08 218.75,163.98 218.75,162.63 218.6,162.48 217.22,162.48 216.84,162.86 216.84,164.92 217,165.07 217.5,165.07
GCLK_VRTC on TOP: 67.95,42.31 69.6,42.31 69.8,42.11 70.51,42.11 70.59,42.03 70.59,41.55 70.41,41.37 68.56,41.37 67.59,40.41 67.59,39.34 67.54,39.29 67.44,39.29 67.39,39.34 67.39,41.02 67.85,41.48 67.85,42.21
HDMI_GND on TOP: 15.52,102.31 15.52,94.18 15.4,94.05 13.24,94.05 12.86,94.44 12.86,105.76 13.29,106.2 14.41,106.2 14.6,106 14.6,104.89 14.71,104.77 15.32,104.77 15.4,104.7 15.4,102.44
INT-SPK-L+ on TOP (solid shape): 63.4,25.8 63.4,24.99 63.38,24.97 61.24,24.97 61.17,25.04 61.17,25.75 61.27,25.86 63.35,25.86
INT-SPK-L+ on TOP (solid shape): 49.1,21.08 49.1,20.85 48.95,20.7 48.14,20.7 47.81,21.03 45.72,21.03 45.67,21.08 45.67,21.21 45.72,21.26 48.92,21.26
INT-SPK-L+ on IN2 (solid shape): 49.61,20.7 49.61,19.89 49.51,19.78 48.85,19.78 47.88,20.75 47.88,21.13 48.01,21.26 49.05,21.26
INT-SPK-L+ on IN2: 61.47,25.86 64.44,25.86 64.54,25.75 64.54,24.89 64.32,24.66 63.81,24.66 63.58,24.89 61.62,24.89 61.42,25.09 61.42,25.8
INT-SPK-L- on TOP (solid shape): 63.4,24.1 63.4,23.29 63.38,23.26 61.27,23.26 61.17,23.37 61.17,24.08 61.24,24.15 63.35,24.15
INT-SPK-L- on IN2 (solid shape): 50.57,21.97 50.57,21.33 50.37,21.13 49.64,21.13 49.33,21.44 48.44,21.44 48.29,21.59 48.29,21.79 48.7,22.2 50.35,22.2
INT-SPK-L- on TOP: 45.65,21.44 49.2,21.44 49.43,21.66 49.43,21.84 49.13,22.15 48.72,22.15 48.24,21.66 45.7,21.66 45.65,21.61
INT-SPK-L- on IN2: 61.62,24.2 63.05,24.2 63.06,24.19 63.34,24.19 63.45,24.08 63.45,22.45 63.33,22.32 62.46,22.32 62.34,22.45 62.34,23.16 62.18,23.32 61.57,23.32 61.38,23.51 61.38,23.96
INT-SPK-R+ on TOP (solid shape): 64.39,22.32 64.39,21.54 64.32,21.46 60.99,21.46 60.73,21.71 60.73,22.27 60.86,22.4 64.32,22.4
INT-SPK-R+ on TOP: 45.72,22.25 47.43,22.25 48.06,22.88 48.06,23.16 47.96,23.26 47.68,23.26 46.87,22.45 45.72,22.45 45.67,22.4 45.67,22.3
INT-SPK-R+ on IN2: 47.07,22.25 47.4,22.25 48.05,22.9 48.05,23.1 48.52,23.57 48.52,23.95 48.16,24.31 47.73,24.31 46.87,23.44 46.87,22.45
INT-SPK-R+ on IN2: 61.93,21.66 61.8,21.54 59.92,21.54 59.82,21.64 59.82,22.53 60.02,22.73 61.78,22.73 61.93,22.58
INT-SPK-R- on TOP (solid shape): 64.42,20.7 64.42,19.91 64.32,19.81 60.91,19.81 60.73,19.99 60.73,20.75 60.81,20.83 64.29,20.83
INT-SPK-R- on TOP: 45.75,21.84 47.88,21.84 48.59,22.55 48.59,22.65 48.47,22.78 48.19,22.78 47.48,22.07 45.75,22.07 45.67,21.99 45.67,21.92
INT-SPK-R- on IN2: 59.92,20.67 61.88,20.67 61.95,20.6 61.95,19.99 61.83,19.86 59.97,19.86 59.87,19.96 59.87,20.62
INT-SPK-R- on IN2: 47.68,21.84 48.19,21.84 48.66,22.31 48.94,22.31 49.36,22.73 49.36,22.96 48.95,23.37 48.64,23.37 47.55,22.27 47.55,21.97
KB_CAPS_PWR on TOP (solid shape): 229.11,157.73 229.11,157.33 229.04,157.25 226.83,157.25 226.8,157.27 226.8,157.76 226.98,157.94 228.91,157.94
LG_3V on TOP: 131.35,23.32 131.91,23.32 131.98,23.24 131.98,22.07 131.91,21.99 130.81,21.99 130.76,22.05 130.76,22.5 130.92,22.65 131.02,22.65 131.22,22.86 131.22,23.19
LG_3V on TOP: 129.94,18.61 130.71,19.38 130.71,20.29 130.81,20.39 131.73,20.39 131.83,20.29 131.83,19.64 131.03,18.84 131.02,18.84 130.13,17.95 130.13,17.31 130.06,17.25 130,17.25 129.94,17.31
LG_5V on TOP: 127.55,18.91 128.32,18.13 128.34,18.15 128.44,18.15 128.55,18.03 128.55,17.24 128.5,17.19 128.35,17.19 128.3,17.24 128.3,17.52 127.91,17.92 127.58,17.92 127.12,18.38 126.45,18.38 126.3,18.52 126.3,18.92 126.38,19 127.41,19 127.43,18.99 127.44,18.98 127.49,18.94
LG_5V on TOP: 125.64,25.86 125.84,26.05 126.6,26.05 126.79,25.86 126.79,25.47 126.28,24.97 125.52,24.97 125.39,25.09 125.39,25.28 125.64,25.54
LG_5V on IN2: 125.63,26.11 126.9,26.11 127.09,25.92 127.09,25.06 126.41,24.38 125.76,24.38 125.5,24.64 125.5,25.99
LG_5V on IN2: 128.02,18.35 128.02,17.94 127.89,17.81 127.2,17.81 126.84,18.17 126.84,19.01 126.44,19.4 126.44,19.56 127.11,20.22 127.21,20.22 127.89,19.53 127.89,18.62 128,18.51 128,18.37
LGATE1 on TOP (solid shape): 154.56,123.14 154.56,122.32 154.41,122.17 153.52,122.17 153.47,122.22 153.47,123.14 153.55,123.21 154.49,123.21
LGATE1 on BOTTOM: 161.47,132.11 160.33,132.11 159.96,131.75 158.83,131.75 158.8,131.77 158.8,132.31 159.17,132.67 160.2,132.67 160.47,132.4 161.46,132.4 161.51,132.35 161.51,132.16
LGATE1 on IN2: 159.74,131.67 158.93,131.67 158.65,131.95 157.38,131.95 157.33,132 157.33,132.94 157.41,133.02 158.98,133.02 159.3,132.7 159.81,132.7 160.05,132.46 160.05,131.98
LGATE1 on IN2: 153.65,122.11 154.31,122.11 154.54,122.34 154.54,123.14 153.86,123.82 153.86,124.62 153.8,124.69 152.84,124.69 152.76,124.61 152.76,123
LGATEG on TOP: 140.31,139.52 140.31,139.82 140.41,139.93 141.48,139.93 142.8,138.61 142.8,137.01 142.55,136.75 141.58,136.75 141.38,136.95 141.38,137.77 141.35,137.79 141.35,138.48
LGATEG on BOTTOM: 161.48,133.97 160.51,133.97 159.74,134.74 159.29,134.74 159.2,134.65 159.2,134.05 159.36,133.88 159.74,133.88 159.91,133.71 161.48,133.71 161.56,133.79 161.56,133.89
LGATEG on IN2: 141.38,137.11 141.56,137.28 142.7,137.28 142.83,137.16 142.83,136.01 142.52,135.71 141.74,135.71 141.38,136.07
LGATEG on IN2: 160.34,134.11 160.34,133.86 160.21,133.73 158.37,133.73 158.3,133.81 158.3,134.92 158.37,135 159.45,135
LX_1.0VALWP on BOTTOM (solid shape): 52.06,94.05 53.96,94.05 54.13,93.88 54.13,92.13 54.05,92.05 51.7,92.05 51.46,92.28 51.46,93.13 50.88,93.71 50.88,94.27 50.92,94.31 51.8,94.31
LX_1.05VSP on BOTTOM (solid shape): 166.82,115.48 166.82,114.71 167.25,114.28 168.04,114.28 168.16,114.16 168.16,113.09 168.53,112.71 168.53,112.34 168.41,112.22 166.82,112.22 166.82,112.21 166.29,112.21 165.01,113.49 165.01,115.52 165.09,115.6 166.69,115.6
LX_3V on BOTTOM (solid shape): 137.19,28.78 137.19,22.98 136.81,22.6 132.44,22.6 131.98,23.06 131.98,27.49 133.59,29.11 136.86,29.11
LX_3V on IN2 (solid shape): 133.51,16.51 133.51,16 133.32,15.81 131.54,15.81 131.41,15.94 131.41,16.51 131.54,16.63 133.38,16.63
LX_3V on TOP: 135.06,23.06 134.55,22.56 132.34,22.56 132.11,22.79 132.11,26.12 132.62,26.63 133.86,26.63 134.12,26.88 134.12,28.94 134.2,29.02 136.96,29.02 137.31,28.67 137.31,23.42 136.96,23.06
LX_3V on TOP: 131.54,15.81 131.3,16.05 130.36,16.05 130.31,16.1 130.31,16.23 130.33,16.25 131.47,16.25 131.54,16.32 133.32,16.32 133.4,16.23 133.4,15.42 133.35,15.36 132.19,15.36 131.74,15.81
LX_3V on IN2: 136.36,22.45 136.17,22.25 135.54,22.25 135.35,22.45 135.35,24.12 135.59,24.36 136.71,24.36 137.11,23.95 137.11,22.93 136.62,22.45
LX_5V on TOP (solid shape): 123.69,29.84 123.69,27.85 123.6,27.76 122.94,27.76 122.72,27.98 121.78,27.98 121.57,27.76 121.57,26.82 121.81,26.58 122.61,26.58 122.62,26.59 124.82,26.59 125.09,26.32 125.09,22.82 125.08,22.81 119.13,22.81 119.03,22.91 119.03,29.43 119.52,29.92 123.61,29.92
LX_5V on BOTTOM (solid shape): outline of 83 points within 120.32,22.71 125.3,30.12
LX_5V on TOP: 127.08,16.2 128.07,16.2 128.12,16.15 128.12,16 128.07,15.95 127.16,15.95 127.02,15.81 126.71,15.81 126.24,15.34 125.15,15.34 125.05,15.44 125.05,16.28 125.12,16.36 126.93,16.36
LX_5V on IN2: 122.1,23.75 122.36,23.49 122.36,22.58 121.72,21.94 120.78,21.94 120.32,22.4 120.32,23.65 120.42,23.75
LX_5V on IN2: 124.55,16.7 124.68,16.83 126.84,16.83 127.09,16.57 127.09,15.75 126.9,15.56 124.81,15.56 124.55,15.81
LX_+1.8VSP on BOTTOM (solid shape): 67.47,89.05 67.47,87.25 67.26,87.04 64.21,87.04 64.15,87.11 64.15,88.19 63.78,88.55 63.78,88.92 63.91,89.05 65.5,89.05 65.54,89.09 67.43,89.09
LX_CHG on TOP (solid shape): 166.58,175.14 166.58,174.67 167.82,173.43 168.99,173.43 169.05,173.37 169.05,173.24 168.99,173.18 166.83,173.18 165.81,174.19 165.81,174.64 165.12,175.33 165.12,175.78 165.24,175.91 165.81,175.91
LX_CHG on BOTTOM (solid shape): 166.58,175.14 166.58,173.87 165.94,173.87 165.94,174.51 165.12,175.33 165.12,175.78 165.24,175.91 165.81,175.91
LX_CHG on BOTTOM (solid shape): 157.33,174.39 157.33,171.7 158.17,170.86 158.17,161.97 157.59,161.39 155.12,161.39 154.51,162 154.51,170.61 154.03,171.09 151.31,171.09 150.9,171.5 150.9,172.21 150.65,172.46 148.57,172.46 148.31,172.72 148.31,174.75 148.62,175.05 156.67,175.05
